<?xml version="1.0" encoding="utf-8" standalone="no"?>
<device schemaVersion="1.1">
  <name>STM32L433VCT7</name>
  <version>1.0</version>
  <description>STM32L433CBT6,STM32L433CBT7,STM32L433CBU6,STM32L433CBU7,STM32L433CBY6,STM32L433CBY7,STM32L433CCT3,STM32L433CCT6,STM32L433CCT7,STM32L433CCU3,STM32L433CCU6,STM32L433CCU7,STM32L433CCY3,STM32L433CCY6,STM32L433CCY7,STM32L433RBI6,STM32L433RBT6,STM32L433RBY6,STM32L433RCI3,STM32L433RCI6,STM32L433RCI7,STM32L433RCT3,STM32L433RCT3P,STM32L433RCT6,STM32L433RCT6P,STM32L433RCT7,STM32L433RCT7P,STM32L433RCY3,STM32L433RCY6,STM32L433RCY7,STM32L433VCI3,STM32L433VCI6,STM32L433VCI7,STM32L433VCT3,STM32L433VCT6,STM32L433VCT7</description>
  <addressUnitBits>8</addressUnitBits>
  <width>32</width>
  <size>0x20</size>
  <resetValue>0</resetValue>
  <resetMask>0xFFFFFFFF</resetMask>
  <peripherals>
    <peripheral>
      <name>TIM2</name>
      <baseAddress>0x40000000</baseAddress>
      <registers>
        <register>
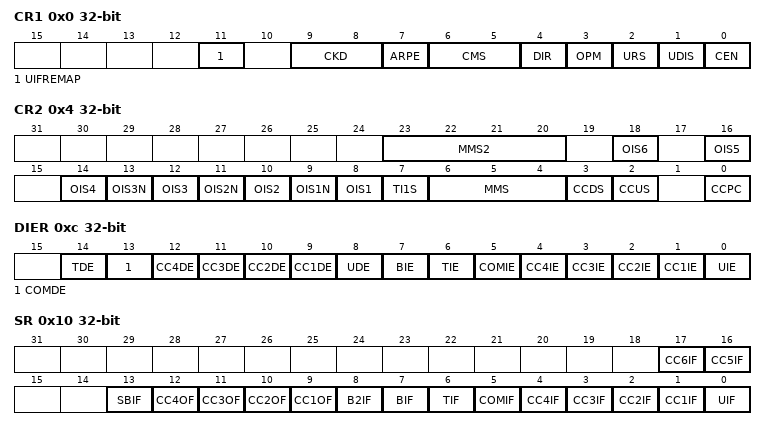
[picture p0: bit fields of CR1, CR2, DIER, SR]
          <name>CR1</name>
          <addressOffset>0x0</addressOffset>
          <size>0x20</size>
          <fields>
            <field>
              <name>CEN</name>
              <bitOffset>0</bitOffset>
              <bitWidth>1</bitWidth>
            </field>
            <field>
              <name>UDIS</name>
              <bitOffset>1</bitOffset>
              <bitWidth>1</bitWidth>
            </field>
            <field>
              <name>URS</name>
              <bitOffset>2</bitOffset>
              <bitWidth>1</bitWidth>
            </field>
            <field>
              <name>OPM</name>
              <bitOffset>3</bitOffset>
              <bitWidth>1</bitWidth>
            </field>
            <field>
              <name>DIR</name>
              <bitOffset>4</bitOffset>
              <bitWidth>1</bitWidth>
            </field>
            <field>
              <name>CMS</name>
              <bitOffset>5</bitOffset>
              <bitWidth>2</bitWidth>
            </field>
            <field>
              <name>ARPE</name>
              <bitOffset>7</bitOffset>
              <bitWidth>1</bitWidth>
            </field>
            <field>
              <name>CKD</name>
              <bitOffset>8</bitOffset>
              <bitWidth>2</bitWidth>
            </field>
            <field>
              <name>UIFREMAP</name>
              <bitOffset>11</bitOffset>
              <bitWidth>1</bitWidth>
            </field>
          </fields>
        </register>
        <register>
          <name>CR2</name>
          <addressOffset>0x4</addressOffset>
          <size>0x20</size>
          <fields>
            <field>
              <name>CCPC</name>
              <bitOffset>0</bitOffset>
              <bitWidth>1</bitWidth>
            </field>
            <field>
              <name>CCUS</name>
              <bitOffset>2</bitOffset>
              <bitWidth>1</bitWidth>
            </field>
            <field>
              <name>CCDS</name>
              <bitOffset>3</bitOffset>
              <bitWidth>1</bitWidth>
            </field>
            <field>
              <name>MMS</name>
              <bitOffset>4</bitOffset>
              <bitWidth>3</bitWidth>
            </field>
            <field>
              <name>TI1S</name>
              <bitOffset>7</bitOffset>
              <bitWidth>1</bitWidth>
            </field>
            <field>
              <name>OIS1</name>
              <bitOffset>8</bitOffset>
              <bitWidth>1</bitWidth>
            </field>
            <field>
              <name>OIS1N</name>
              <bitOffset>9</bitOffset>
              <bitWidth>1</bitWidth>
            </field>
            <field>
              <name>OIS2</name>
              <bitOffset>10</bitOffset>
              <bitWidth>1</bitWidth>
            </field>
            <field>
              <name>OIS2N</name>
              <bitOffset>11</bitOffset>
              <bitWidth>1</bitWidth>
            </field>
            <field>
              <name>OIS3</name>
              <bitOffset>12</bitOffset>
              <bitWidth>1</bitWidth>
            </field>
            <field>
              <name>OIS3N</name>
              <bitOffset>13</bitOffset>
              <bitWidth>1</bitWidth>
            </field>
            <field>
              <name>OIS4</name>
              <bitOffset>14</bitOffset>
              <bitWidth>1</bitWidth>
            </field>
            <field>
              <name>OIS5</name>
              <bitOffset>16</bitOffset>
              <bitWidth>1</bitWidth>
            </field>
            <field>
              <name>OIS6</name>
              <bitOffset>18</bitOffset>
              <bitWidth>1</bitWidth>
            </field>
            <field>
              <name>MMS2</name>
              <bitOffset>20</bitOffset>
              <bitWidth>4</bitWidth>
            </field>
          </fields>
        </register>
        <register>
          <name>SMCR</name>
          <addressOffset>0x8</addressOffset>
          <size>0x20</size>
          <fields>
            <field>
              <name>SMS</name>
              <bitOffset>0</bitOffset>
              <bitWidth>17</bitWidth>
            </field>
            <field>
              <name>OCCS</name>
              <bitOffset>3</bitOffset>
              <bitWidth>1</bitWidth>
            </field>
            <field>
              <name>TS</name>
              <bitOffset>4</bitOffset>
              <bitWidth>3</bitWidth>
            </field>
            <field>
              <name>MSM</name>
              <bitOffset>7</bitOffset>
              <bitWidth>1</bitWidth>
            </field>
            <field>
              <name>ETF</name>
              <bitOffset>8</bitOffset>
              <bitWidth>4</bitWidth>
            </field>
            <field>
              <name>ETPS</name>
              <bitOffset>12</bitOffset>
              <bitWidth>2</bitWidth>
            </field>
            <field>
              <name>ECE</name>
              <bitOffset>14</bitOffset>
              <bitWidth>1</bitWidth>
            </field>
            <field>
              <name>ETP</name>
              <bitOffset>15</bitOffset>
              <bitWidth>1</bitWidth>
            </field>
          </fields>
        </register>
        <register>
          <name>DIER</name>
          <addressOffset>0xc</addressOffset>
          <size>0x20</size>
          <fields>
            <field>
              <name>UIE</name>
              <bitOffset>0</bitOffset>
              <bitWidth>1</bitWidth>
            </field>
            <field>
              <name>CC1IE</name>
              <bitOffset>1</bitOffset>
              <bitWidth>1</bitWidth>
            </field>
            <field>
              <name>CC2IE</name>
              <bitOffset>2</bitOffset>
              <bitWidth>1</bitWidth>
            </field>
            <field>
              <name>CC3IE</name>
              <bitOffset>3</bitOffset>
              <bitWidth>1</bitWidth>
            </field>
            <field>
              <name>CC4IE</name>
              <bitOffset>4</bitOffset>
              <bitWidth>1</bitWidth>
            </field>
            <field>
              <name>COMIE</name>
              <bitOffset>5</bitOffset>
              <bitWidth>1</bitWidth>
            </field>
            <field>
              <name>TIE</name>
              <bitOffset>6</bitOffset>
              <bitWidth>1</bitWidth>
            </field>
            <field>
              <name>BIE</name>
              <bitOffset>7</bitOffset>
              <bitWidth>1</bitWidth>
            </field>
            <field>
              <name>UDE</name>
              <bitOffset>8</bitOffset>
              <bitWidth>1</bitWidth>
            </field>
            <field>
              <name>CC1DE</name>
              <bitOffset>9</bitOffset>
              <bitWidth>1</bitWidth>
            </field>
            <field>
              <name>CC2DE</name>
              <bitOffset>10</bitOffset>
              <bitWidth>1</bitWidth>
            </field>
            <field>
              <name>CC3DE</name>
              <bitOffset>11</bitOffset>
              <bitWidth>1</bitWidth>
            </field>
            <field>
              <name>CC4DE</name>
              <bitOffset>12</bitOffset>
              <bitWidth>1</bitWidth>
            </field>
            <field>
              <name>COMDE</name>
              <bitOffset>13</bitOffset>
              <bitWidth>1</bitWidth>
            </field>
            <field>
              <name>TDE</name>
              <bitOffset>14</bitOffset>
              <bitWidth>1</bitWidth>
            </field>
          </fields>
        </register>
        <register>
          <name>SR</name>
          <addressOffset>0x10</addressOffset>
          <size>0x20</size>
          <fields>
            <field>
              <name>UIF</name>
              <bitOffset>0</bitOffset>
              <bitWidth>1</bitWidth>
            </field>
            <field>
              <name>CC1IF</name>
              <bitOffset>1</bitOffset>
              <bitWidth>1</bitWidth>
            </field>
            <field>
              <name>CC2IF</name>
              <bitOffset>2</bitOffset>
              <bitWidth>1</bitWidth>
            </field>
            <field>
              <name>CC3IF</name>
              <bitOffset>3</bitOffset>
              <bitWidth>1</bitWidth>
            </field>
            <field>
              <name>CC4IF</name>
              <bitOffset>4</bitOffset>
              <bitWidth>1</bitWidth>
            </field>
            <field>
              <name>COMIF</name>
              <bitOffset>5</bitOffset>
              <bitWidth>1</bitWidth>
            </field>
            <field>
              <name>TIF</name>
              <bitOffset>6</bitOffset>
              <bitWidth>1</bitWidth>
            </field>
            <field>
              <name>BIF</name>
              <bitOffset>7</bitOffset>
              <bitWidth>1</bitWidth>
            </field>
            <field>
              <name>B2IF</name>
              <bitOffset>8</bitOffset>
              <bitWidth>1</bitWidth>
            </field>
            <field>
              <name>CC1OF</name>
              <bitOffset>9</bitOffset>
              <bitWidth>1</bitWidth>
            </field>
            <field>
              <name>CC2OF</name>
              <bitOffset>10</bitOffset>
              <bitWidth>1</bitWidth>
            </field>
            <field>
              <name>CC3OF</name>
              <bitOffset>11</bitOffset>
              <bitWidth>1</bitWidth>
            </field>
            <field>
              <name>CC4OF</name>
              <bitOffset>12</bitOffset>
              <bitWidth>1</bitWidth>
            </field>
            <field>
              <name>SBIF</name>
              <bitOffset>13</bitOffset>
              <bitWidth>1</bitWidth>
            </field>
            <field>
              <name>CC5IF</name>
              <bitOffset>16</bitOffset>
              <bitWidth>1</bitWidth>
            </field>
            <field>
              <name>CC6IF</name>
              <bitOffset>17</bitOffset>
              <bitWidth>1</bitWidth>
            </field>
          </fields>
        </register>
        <register>
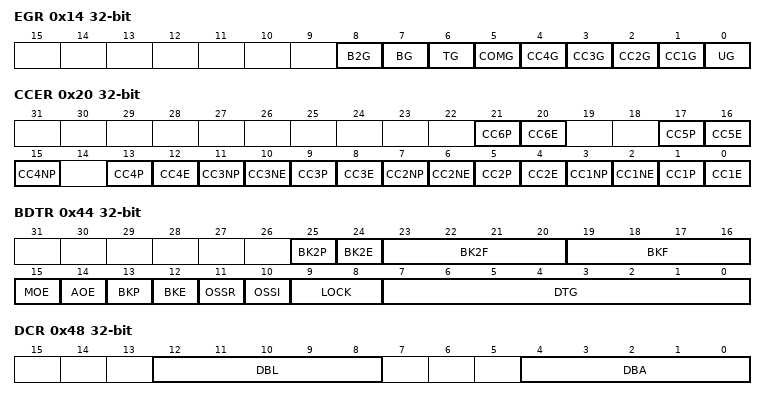
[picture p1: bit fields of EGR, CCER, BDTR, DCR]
          <name>EGR</name>
          <addressOffset>0x14</addressOffset>
          <size>0x20</size>
          <fields>
            <field>
              <name>UG</name>
              <bitOffset>0</bitOffset>
              <bitWidth>1</bitWidth>
            </field>
            <field>
              <name>CC1G</name>
              <bitOffset>1</bitOffset>
              <bitWidth>1</bitWidth>
            </field>
            <field>
              <name>CC2G</name>
              <bitOffset>2</bitOffset>
              <bitWidth>1</bitWidth>
            </field>
            <field>
              <name>CC3G</name>
              <bitOffset>3</bitOffset>
              <bitWidth>1</bitWidth>
            </field>
            <field>
              <name>CC4G</name>
              <bitOffset>4</bitOffset>
              <bitWidth>1</bitWidth>
            </field>
            <field>
              <name>COMG</name>
              <bitOffset>5</bitOffset>
              <bitWidth>1</bitWidth>
            </field>
            <field>
              <name>TG</name>
              <bitOffset>6</bitOffset>
              <bitWidth>1</bitWidth>
            </field>
            <field>
              <name>BG</name>
              <bitOffset>7</bitOffset>
              <bitWidth>1</bitWidth>
            </field>
            <field>
              <name>B2G</name>
              <bitOffset>8</bitOffset>
              <bitWidth>1</bitWidth>
            </field>
          </fields>
        </register>
        <register>
          <name>CCMR1</name>
          <addressOffset>0x18</addressOffset>
          <size>0x20</size>
          <fields>
            <field>
              <name>CC1S</name>
              <bitOffset>0</bitOffset>
              <bitWidth>2</bitWidth>
            </field>
            <field>
              <name>OC1FE</name>
              <bitOffset>2</bitOffset>
              <bitWidth>1</bitWidth>
            </field>
            <field>
              <name>OC1PE</name>
              <bitOffset>3</bitOffset>
              <bitWidth>1</bitWidth>
            </field>
            <field>
              <name>OC1M</name>
              <bitOffset>4</bitOffset>
              <bitWidth>13</bitWidth>
            </field>
            <field>
              <name>OC1CE</name>
              <bitOffset>7</bitOffset>
              <bitWidth>1</bitWidth>
            </field>
            <field>
              <name>CC2S</name>
              <bitOffset>8</bitOffset>
              <bitWidth>2</bitWidth>
            </field>
            <field>
              <name>OC2FE</name>
              <bitOffset>10</bitOffset>
              <bitWidth>1</bitWidth>
            </field>
            <field>
              <name>OC2PE</name>
              <bitOffset>11</bitOffset>
              <bitWidth>1</bitWidth>
            </field>
            <field>
              <name>OC2M</name>
              <bitOffset>12</bitOffset>
              <bitWidth>13</bitWidth>
            </field>
            <field>
              <name>OC2CE</name>
              <bitOffset>15</bitOffset>
              <bitWidth>1</bitWidth>
            </field>
          </fields>
        </register>
        <register>
          <name>CCMR2</name>
          <addressOffset>0x1c</addressOffset>
          <size>0x20</size>
          <fields>
            <field>
              <name>CC3S</name>
              <bitOffset>0</bitOffset>
              <bitWidth>2</bitWidth>
            </field>
            <field>
              <name>OC3FE</name>
              <bitOffset>2</bitOffset>
              <bitWidth>1</bitWidth>
            </field>
            <field>
              <name>OC3PE</name>
              <bitOffset>3</bitOffset>
              <bitWidth>1</bitWidth>
            </field>
            <field>
              <name>OC3M</name>
              <bitOffset>4</bitOffset>
              <bitWidth>13</bitWidth>
            </field>
            <field>
              <name>OC3CE</name>
              <bitOffset>7</bitOffset>
              <bitWidth>1</bitWidth>
            </field>
            <field>
              <name>CC4S</name>
              <bitOffset>8</bitOffset>
              <bitWidth>2</bitWidth>
            </field>
            <field>
              <name>OC4FE</name>
              <bitOffset>10</bitOffset>
              <bitWidth>1</bitWidth>
            </field>
            <field>
              <name>OC4PE</name>
              <bitOffset>11</bitOffset>
              <bitWidth>1</bitWidth>
            </field>
            <field>
              <name>OC4M</name>
              <bitOffset>12</bitOffset>
              <bitWidth>13</bitWidth>
            </field>
            <field>
              <name>OC4CE</name>
              <bitOffset>15</bitOffset>
              <bitWidth>1</bitWidth>
            </field>
          </fields>
        </register>
        <register>
          <name>CCER</name>
          <addressOffset>0x20</addressOffset>
          <size>0x20</size>
          <fields>
            <field>
              <name>CC1E</name>
              <bitOffset>0</bitOffset>
              <bitWidth>1</bitWidth>
            </field>
            <field>
              <name>CC1P</name>
              <bitOffset>1</bitOffset>
              <bitWidth>1</bitWidth>
            </field>
            <field>
              <name>CC1NE</name>
              <bitOffset>2</bitOffset>
              <bitWidth>1</bitWidth>
            </field>
            <field>
              <name>CC1NP</name>
              <bitOffset>3</bitOffset>
              <bitWidth>1</bitWidth>
            </field>
            <field>
              <name>CC2E</name>
              <bitOffset>4</bitOffset>
              <bitWidth>1</bitWidth>
            </field>
            <field>
              <name>CC2P</name>
              <bitOffset>5</bitOffset>
              <bitWidth>1</bitWidth>
            </field>
            <field>
              <name>CC2NE</name>
              <bitOffset>6</bitOffset>
              <bitWidth>1</bitWidth>
            </field>
            <field>
              <name>CC2NP</name>
              <bitOffset>7</bitOffset>
              <bitWidth>1</bitWidth>
            </field>
            <field>
              <name>CC3E</name>
              <bitOffset>8</bitOffset>
              <bitWidth>1</bitWidth>
            </field>
            <field>
              <name>CC3P</name>
              <bitOffset>9</bitOffset>
              <bitWidth>1</bitWidth>
            </field>
            <field>
              <name>CC3NE</name>
              <bitOffset>10</bitOffset>
              <bitWidth>1</bitWidth>
            </field>
            <field>
              <name>CC3NP</name>
              <bitOffset>11</bitOffset>
              <bitWidth>1</bitWidth>
            </field>
            <field>
              <name>CC4E</name>
              <bitOffset>12</bitOffset>
              <bitWidth>1</bitWidth>
            </field>
            <field>
              <name>CC4P</name>
              <bitOffset>13</bitOffset>
              <bitWidth>1</bitWidth>
            </field>
            <field>
              <name>CC4NP</name>
              <bitOffset>15</bitOffset>
              <bitWidth>1</bitWidth>
            </field>
            <field>
              <name>CC5E</name>
              <bitOffset>16</bitOffset>
              <bitWidth>1</bitWidth>
            </field>
            <field>
              <name>CC5P</name>
              <bitOffset>17</bitOffset>
              <bitWidth>1</bitWidth>
            </field>
            <field>
              <name>CC6E</name>
              <bitOffset>20</bitOffset>
              <bitWidth>1</bitWidth>
            </field>
            <field>
              <name>CC6P</name>
              <bitOffset>21</bitOffset>
              <bitWidth>1</bitWidth>
            </field>
          </fields>
        </register>
        <register>
          <name>CNT</name>
          <addressOffset>0x24</addressOffset>
          <size>0x20</size>
          <fields>
            <field>
              <name>CNT</name>
              <bitOffset>0</bitOffset>
              <bitWidth>32</bitWidth>
            </field>
            <field>
              <name>UIFCPY</name>
              <bitOffset>31</bitOffset>
              <bitWidth>1</bitWidth>
            </field>
          </fields>
        </register>
        <register>
          <name>PSC</name>
          <addressOffset>0x28</addressOffset>
          <size>0x20</size>
          <fields>
            <field>
              <name>PSC</name>
              <bitOffset>0</bitOffset>
              <bitWidth>16</bitWidth>
            </field>
          </fields>
        </register>
        <register>
          <name>ARR</name>
          <addressOffset>0x2c</addressOffset>
          <size>0x20</size>
          <fields>
            <field>
              <name>ARR</name>
              <bitOffset>0</bitOffset>
              <bitWidth>32</bitWidth>
            </field>
          </fields>
        </register>
        <register>
          <name>RCR</name>
          <addressOffset>0x30</addressOffset>
          <size>0x20</size>
          <fields>
            <field>
              <name>REP</name>
              <bitOffset>0</bitOffset>
              <bitWidth>16</bitWidth>
            </field>
          </fields>
        </register>
        <register>
          <name>CCR1</name>
          <addressOffset>0x34</addressOffset>
          <size>0x20</size>
          <fields>
            <field>
              <name>CCR1</name>
              <bitOffset>0</bitOffset>
              <bitWidth>16</bitWidth>
            </field>
          </fields>
        </register>
        <register>
          <name>CCR2</name>
          <addressOffset>0x38</addressOffset>
          <size>0x20</size>
          <fields>
            <field>
              <name>CCR2</name>
              <bitOffset>0</bitOffset>
              <bitWidth>16</bitWidth>
            </field>
          </fields>
        </register>
        <register>
          <name>CCR3</name>
          <addressOffset>0x3c</addressOffset>
          <size>0x20</size>
          <fields>
            <field>
              <name>CCR3</name>
              <bitOffset>0</bitOffset>
              <bitWidth>16</bitWidth>
            </field>
          </fields>
        </register>
        <register>
          <name>CCR4</name>
          <addressOffset>0x40</addressOffset>
          <size>0x20</size>
          <fields>
            <field>
              <name>CCR4</name>
              <bitOffset>0</bitOffset>
              <bitWidth>16</bitWidth>
            </field>
          </fields>
        </register>
        <register>
          <name>BDTR</name>
          <addressOffset>0x44</addressOffset>
          <size>0x20</size>
          <fields>
            <field>
              <name>DTG</name>
              <bitOffset>0</bitOffset>
              <bitWidth>8</bitWidth>
            </field>
            <field>
              <name>LOCK</name>
              <bitOffset>8</bitOffset>
              <bitWidth>2</bitWidth>
            </field>
            <field>
              <name>OSSI</name>
              <bitOffset>10</bitOffset>
              <bitWidth>1</bitWidth>
            </field>
            <field>
              <name>OSSR</name>
              <bitOffset>11</bitOffset>
              <bitWidth>1</bitWidth>
            </field>
            <field>
              <name>BKE</name>
              <bitOffset>12</bitOffset>
              <bitWidth>1</bitWidth>
            </field>
            <field>
              <name>BKP</name>
              <bitOffset>13</bitOffset>
              <bitWidth>1</bitWidth>
            </field>
            <field>
              <name>AOE</name>
              <bitOffset>14</bitOffset>
              <bitWidth>1</bitWidth>
            </field>
            <field>
              <name>MOE</name>
              <bitOffset>15</bitOffset>
              <bitWidth>1</bitWidth>
            </field>
            <field>
              <name>BKF</name>
              <bitOffset>16</bitOffset>
              <bitWidth>4</bitWidth>
            </field>
            <field>
              <name>BK2F</name>
              <bitOffset>20</bitOffset>
              <bitWidth>4</bitWidth>
            </field>
            <field>
              <name>BK2E</name>
              <bitOffset>24</bitOffset>
              <bitWidth>1</bitWidth>
            </field>
            <field>
              <name>BK2P</name>
              <bitOffset>25</bitOffset>
              <bitWidth>1</bitWidth>
            </field>
          </fields>
        </register>
        <register>
          <name>DCR</name>
          <addressOffset>0x48</addressOffset>
          <size>0x20</size>
          <fields>
            <field>
              <name>DBA</name>
              <bitOffset>0</bitOffset>
              <bitWidth>5</bitWidth>
            </field>
            <field>
              <name>DBL</name>
              <bitOffset>8</bitOffset>
              <bitWidth>5</bitWidth>
            </field>
          </fields>
        </register>
        <register>
          <name>DMAR</name>
          <addressOffset>0x4c</addressOffset>
          <size>0x20</size>
          <fields>
            <field>
              <name>DMAB</name>
              <bitOffset>0</bitOffset>
              <bitWidth>16</bitWidth>
            </field>
          </fields>
        </register>
        <register>
          <name>OR1</name>
          <addressOffset>0x50</addressOffset>
          <size>0x20</size>
        </register>
        <register>
          <name>CCMR3</name>
          <addressOffset>0x54</addressOffset>
          <size>0x20</size>
          <fields>
            <field>
              <name>OC5FE</name>
              <bitOffset>2</bitOffset>
              <bitWidth>1</bitWidth>
            </field>
            <field>
              <name>OC5PE</name>
              <bitOffset>3</bitOffset>
              <bitWidth>1</bitWidth>
            </field>
            <field>
              <name>OC5M</name>
              <bitOffset>4</bitOffset>
              <bitWidth>13</bitWidth>
            </field>
            <field>
              <name>OC5CE</name>
              <bitOffset>7</bitOffset>
              <bitWidth>1</bitWidth>
            </field>
            <field>
              <name>OC6FE</name>
              <bitOffset>10</bitOffset>
              <bitWidth>1</bitWidth>
            </field>
            <field>
              <name>OC6PE</name>
              <bitOffset>11</bitOffset>
              <bitWidth>1</bitWidth>
            </field>
            <field>
              <name>OC6M</name>
              <bitOffset>12</bitOffset>
              <bitWidth>13</bitWidth>
            </field>
            <field>
              <name>OC6CE</name>
              <bitOffset>15</bitOffset>
              <bitWidth>1</bitWidth>
            </field>
          </fields>
        </register>
        <register>
          <name>CCR5</name>
          <addressOffset>0x58</addressOffset>
          <size>0x20</size>
          <fields>
            <field>
              <name>CCR5</name>
              <bitOffset>0</bitOffset>
              <bitWidth>32</bitWidth>
            </field>
            <field>
              <name>GC5C1</name>
              <bitOffset>29</bitOffset>
              <bitWidth>1</bitWidth>
            </field>
            <field>
              <name>GC5C2</name>
              <bitOffset>30</bitOffset>
              <bitWidth>1</bitWidth>
            </field>
            <field>
              <name>GC5C3</name>
              <bitOffset>31</bitOffset>
              <bitWidth>1</bitWidth>
            </field>
          </fields>
        </register>
        <register>
          <name>CCR6</name>
          <addressOffset>0x5c</addressOffset>
          <size>0x20</size>
          <fields>
            <field>
              <name>CCR6</name>
              <bitOffset>0</bitOffset>
              <bitWidth>16</bitWidth>
            </field>
          </fields>
        </register>
        <register>
          <name>OR2</name>
          <addressOffset>0x60</addressOffset>
          <size>0x20</size>
        </register>
        <register>
          <name>OR3</name>
          <addressOffset>0x64</addressOffset>
          <size>0x20</size>
        </register>
      </registers>
    </peripheral>
    <peripheral>
      <name>TIM6</name>
      <baseAddress>0x40001000</baseAddress>
      <registers>
        <register>
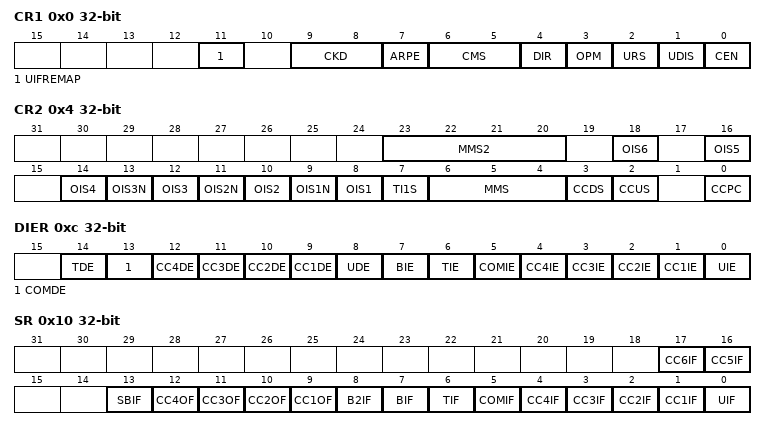
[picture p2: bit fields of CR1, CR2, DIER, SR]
          <name>CR1</name>
          <addressOffset>0x0</addressOffset>
          <size>0x20</size>
          <fields>
            <field>
              <name>CEN</name>
              <bitOffset>0</bitOffset>
              <bitWidth>1</bitWidth>
            </field>
            <field>
              <name>UDIS</name>
              <bitOffset>1</bitOffset>
              <bitWidth>1</bitWidth>
            </field>
            <field>
              <name>URS</name>
              <bitOffset>2</bitOffset>
              <bitWidth>1</bitWidth>
            </field>
            <field>
              <name>OPM</name>
              <bitOffset>3</bitOffset>
              <bitWidth>1</bitWidth>
            </field>
            <field>
              <name>DIR</name>
              <bitOffset>4</bitOffset>
              <bitWidth>1</bitWidth>
            </field>
            <field>
              <name>CMS</name>
              <bitOffset>5</bitOffset>
              <bitWidth>2</bitWidth>
            </field>
            <field>
              <name>ARPE</name>
              <bitOffset>7</bitOffset>
              <bitWidth>1</bitWidth>
            </field>
            <field>
              <name>CKD</name>
              <bitOffset>8</bitOffset>
              <bitWidth>2</bitWidth>
            </field>
            <field>
              <name>UIFREMAP</name>
              <bitOffset>11</bitOffset>
              <bitWidth>1</bitWidth>
            </field>
          </fields>
        </register>
        <register>
          <name>CR2</name>
          <addressOffset>0x4</addressOffset>
          <size>0x20</size>
          <fields>
            <field>
              <name>CCPC</name>
              <bitOffset>0</bitOffset>
              <bitWidth>1</bitWidth>
            </field>
            <field>
              <name>CCUS</name>
              <bitOffset>2</bitOffset>
              <bitWidth>1</bitWidth>
            </field>
            <field>
              <name>CCDS</name>
              <bitOffset>3</bitOffset>
              <bitWidth>1</bitWidth>
            </field>
            <field>
              <name>MMS</name>
              <bitOffset>4</bitOffset>
              <bitWidth>3</bitWidth>
            </field>
            <field>
              <name>TI1S</name>
              <bitOffset>7</bitOffset>
              <bitWidth>1</bitWidth>
            </field>
            <field>
              <name>OIS1</name>
              <bitOffset>8</bitOffset>
              <bitWidth>1</bitWidth>
            </field>
            <field>
              <name>OIS1N</name>
              <bitOffset>9</bitOffset>
              <bitWidth>1</bitWidth>
            </field>
            <field>
              <name>OIS2</name>
              <bitOffset>10</bitOffset>
              <bitWidth>1</bitWidth>
            </field>
            <field>
              <name>OIS2N</name>
              <bitOffset>11</bitOffset>
              <bitWidth>1</bitWidth>
            </field>
            <field>
              <name>OIS3</name>
              <bitOffset>12</bitOffset>
              <bitWidth>1</bitWidth>
            </field>
            <field>
              <name>OIS3N</name>
              <bitOffset>13</bitOffset>
              <bitWidth>1</bitWidth>
            </field>
            <field>
              <name>OIS4</name>
              <bitOffset>14</bitOffset>
              <bitWidth>1</bitWidth>
            </field>
            <field>
              <name>OIS5</name>
              <bitOffset>16</bitOffset>
              <bitWidth>1</bitWidth>
            </field>
            <field>
              <name>OIS6</name>
              <bitOffset>18</bitOffset>
              <bitWidth>1</bitWidth>
            </field>
            <field>
              <name>MMS2</name>
              <bitOffset>20</bitOffset>
              <bitWidth>4</bitWidth>
            </field>
          </fields>
        </register>
        <register>
          <name>SMCR</name>
          <addressOffset>0x8</addressOffset>
          <size>0x20</size>
          <fields>
            <field>
              <name>SMS</name>
              <bitOffset>0</bitOffset>
              <bitWidth>17</bitWidth>
            </field>
            <field>
              <name>OCCS</name>
              <bitOffset>3</bitOffset>
              <bitWidth>1</bitWidth>
            </field>
            <field>
              <name>TS</name>
              <bitOffset>4</bitOffset>
              <bitWidth>3</bitWidth>
            </field>
            <field>
              <name>MSM</name>
              <bitOffset>7</bitOffset>
              <bitWidth>1</bitWidth>
            </field>
            <field>
              <name>ETF</name>
              <bitOffset>8</bitOffset>
              <bitWidth>4</bitWidth>
            </field>
            <field>
              <name>ETPS</name>
              <bitOffset>12</bitOffset>
              <bitWidth>2</bitWidth>
            </field>
            <field>
              <name>ECE</name>
              <bitOffset>14</bitOffset>
              <bitWidth>1</bitWidth>
            </field>
            <field>
              <name>ETP</name>
              <bitOffset>15</bitOffset>
              <bitWidth>1</bitWidth>
            </field>
          </fields>
        </register>
        <register>
          <name>DIER</name>
          <addressOffset>0xc</addressOffset>
          <size>0x20</size>
          <fields>
            <field>
              <name>UIE</name>
              <bitOffset>0</bitOffset>
              <bitWidth>1</bitWidth>
            </field>
            <field>
              <name>CC1IE</name>
              <bitOffset>1</bitOffset>
              <bitWidth>1</bitWidth>
            </field>
            <field>
              <name>CC2IE</name>
              <bitOffset>2</bitOffset>
              <bitWidth>1</bitWidth>
            </field>
            <field>
              <name>CC3IE</name>
              <bitOffset>3</bitOffset>
              <bitWidth>1</bitWidth>
            </field>
            <field>
              <name>CC4IE</name>
              <bitOffset>4</bitOffset>
              <bitWidth>1</bitWidth>
            </field>
            <field>
              <name>COMIE</name>
              <bitOffset>5</bitOffset>
              <bitWidth>1</bitWidth>
            </field>
            <field>
              <name>TIE</name>
              <bitOffset>6</bitOffset>
              <bitWidth>1</bitWidth>
            </field>
            <field>
              <name>BIE</name>
              <bitOffset>7</bitOffset>
              <bitWidth>1</bitWidth>
            </field>
            <field>
              <name>UDE</name>
              <bitOffset>8</bitOffset>
              <bitWidth>1</bitWidth>
            </field>
            <field>
              <name>CC1DE</name>
              <bitOffset>9</bitOffset>
              <bitWidth>1</bitWidth>
            </field>
            <field>
              <name>CC2DE</name>
              <bitOffset>10</bitOffset>
              <bitWidth>1</bitWidth>
            </field>
            <field>
              <name>CC3DE</name>
              <bitOffset>11</bitOffset>
              <bitWidth>1</bitWidth>
            </field>
            <field>
              <name>CC4DE</name>
              <bitOffset>12</bitOffset>
              <bitWidth>1</bitWidth>
            </field>
            <field>
              <name>COMDE</name>
              <bitOffset>13</bitOffset>
              <bitWidth>1</bitWidth>
            </field>
            <field>
              <name>TDE</name>
              <bitOffset>14</bitOffset>
              <bitWidth>1</bitWidth>
            </field>
          </fields>
        </register>
        <register>
          <name>SR</name>
          <addressOffset>0x10</addressOffset>
          <size>0x20</size>
          <fields>
            <field>
              <name>UIF</name>
              <bitOffset>0</bitOffset>
              <bitWidth>1</bitWidth>
            </field>
            <field>
              <name>CC1IF</name>
              <bitOffset>1</bitOffset>
              <bitWidth>1</bitWidth>
            </field>
            <field>
              <name>CC2IF</name>
              <bitOffset>2</bitOffset>
              <bitWidth>1</bitWidth>
            </field>
            <field>
              <name>CC3IF</name>
              <bitOffset>3</bitOffset>
              <bitWidth>1</bitWidth>
            </field>
            <field>
              <name>CC4IF</name>
              <bitOffset>4</bitOffset>
              <bitWidth>1</bitWidth>
            </field>
            <field>
              <name>COMIF</name>
              <bitOffset>5</bitOffset>
              <bitWidth>1</bitWidth>
            </field>
            <field>
              <name>TIF</name>
              <bitOffset>6</bitOffset>
              <bitWidth>1</bitWidth>
            </field>
            <field>
              <name>BIF</name>
              <bitOffset>7</bitOffset>
              <bitWidth>1</bitWidth>
            </field>
            <field>
              <name>B2IF</name>
              <bitOffset>8</bitOffset>
              <bitWidth>1</bitWidth>
            </field>
            <field>
              <name>CC1OF</name>
              <bitOffset>9</bitOffset>
              <bitWidth>1</bitWidth>
            </field>
            <field>
              <name>CC2OF</name>
              <bitOffset>10</bitOffset>
              <bitWidth>1</bitWidth>
            </field>
            <field>
              <name>CC3OF</name>
              <bitOffset>11</bitOffset>
              <bitWidth>1</bitWidth>
            </field>
            <field>
              <name>CC4OF</name>
              <bitOffset>12</bitOffset>
              <bitWidth>1</bitWidth>
            </field>
            <field>
              <name>SBIF</name>
              <bitOffset>13</bitOffset>
              <bitWidth>1</bitWidth>
            </field>
            <field>
              <name>CC5IF</name>
              <bitOffset>16</bitOffset>
              <bitWidth>1</bitWidth>
            </field>
            <field>
              <name>CC6IF</name>
              <bitOffset>17</bitOffset>
              <bitWidth>1</bitWidth>
            </field>
          </fields>
        </register>
        <register>
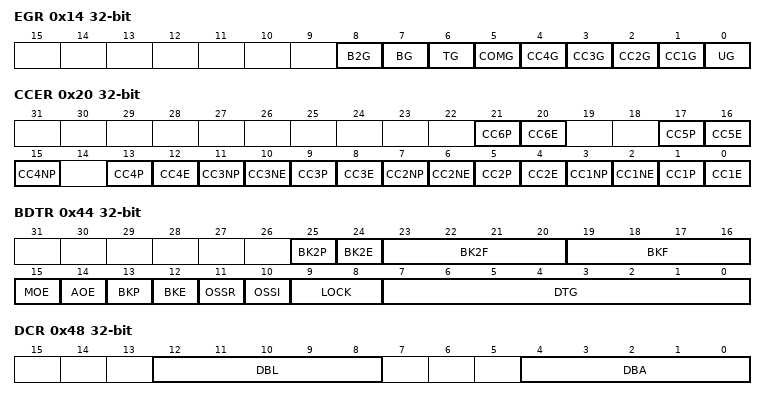
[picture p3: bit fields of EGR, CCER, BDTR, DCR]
          <name>EGR</name>
          <addressOffset>0x14</addressOffset>
          <size>0x20</size>
          <fields>
            <field>
              <name>UG</name>
              <bitOffset>0</bitOffset>
              <bitWidth>1</bitWidth>
            </field>
            <field>
              <name>CC1G</name>
              <bitOffset>1</bitOffset>
              <bitWidth>1</bitWidth>
            </field>
            <field>
              <name>CC2G</name>
              <bitOffset>2</bitOffset>
              <bitWidth>1</bitWidth>
            </field>
            <field>
              <name>CC3G</name>
              <bitOffset>3</bitOffset>
              <bitWidth>1</bitWidth>
            </field>
            <field>
              <name>CC4G</name>
              <bitOffset>4</bitOffset>
              <bitWidth>1</bitWidth>
            </field>
            <field>
              <name>COMG</name>
              <bitOffset>5</bitOffset>
              <bitWidth>1</bitWidth>
            </field>
            <field>
              <name>TG</name>
              <bitOffset>6</bitOffset>
              <bitWidth>1</bitWidth>
            </field>
            <field>
              <name>BG</name>
              <bitOffset>7</bitOffset>
              <bitWidth>1</bitWidth>
            </field>
            <field>
              <name>B2G</name>
              <bitOffset>8</bitOffset>
              <bitWidth>1</bitWidth>
            </field>
          </fields>
        </register>
        <register>
          <name>CCMR1</name>
          <addressOffset>0x18</addressOffset>
          <size>0x20</size>
          <fields>
            <field>
              <name>CC1S</name>
              <bitOffset>0</bitOffset>
              <bitWidth>2</bitWidth>
            </field>
            <field>
              <name>OC1FE</name>
              <bitOffset>2</bitOffset>
              <bitWidth>1</bitWidth>
            </field>
            <field>
              <name>OC1PE</name>
              <bitOffset>3</bitOffset>
              <bitWidth>1</bitWidth>
            </field>
            <field>
              <name>OC1M</name>
              <bitOffset>4</bitOffset>
              <bitWidth>13</bitWidth>
            </field>
            <field>
              <name>OC1CE</name>
              <bitOffset>7</bitOffset>
              <bitWidth>1</bitWidth>
            </field>
            <field>
              <name>CC2S</name>
              <bitOffset>8</bitOffset>
              <bitWidth>2</bitWidth>
            </field>
            <field>
              <name>OC2FE</name>
              <bitOffset>10</bitOffset>
              <bitWidth>1</bitWidth>
            </field>
            <field>
              <name>OC2PE</name>
              <bitOffset>11</bitOffset>
              <bitWidth>1</bitWidth>
            </field>
            <field>
              <name>OC2M</name>
              <bitOffset>12</bitOffset>
              <bitWidth>13</bitWidth>
            </field>
            <field>
              <name>OC2CE</name>
              <bitOffset>15</bitOffset>
              <bitWidth>1</bitWidth>
            </field>
          </fields>
        </register>
        <register>
          <name>CCMR2</name>
          <addressOffset>0x1c</addressOffset>
          <size>0x20</size>
          <fields>
            <field>
              <name>CC3S</name>
              <bitOffset>0</bitOffset>
              <bitWidth>2</bitWidth>
            </field>
            <field>
              <name>OC3FE</name>
              <bitOffset>2</bitOffset>
              <bitWidth>1</bitWidth>
            </field>
            <field>
              <name>OC3PE</name>
              <bitOffset>3</bitOffset>
              <bitWidth>1</bitWidth>
            </field>
            <field>
              <name>OC3M</name>
              <bitOffset>4</bitOffset>
              <bitWidth>13</bitWidth>
            </field>
            <field>
              <name>OC3CE</name>
              <bitOffset>7</bitOffset>
              <bitWidth>1</bitWidth>
            </field>
            <field>
              <name>CC4S</name>
              <bitOffset>8</bitOffset>
              <bitWidth>2</bitWidth>
            </field>
            <field>
              <name>OC4FE</name>
              <bitOffset>10</bitOffset>
              <bitWidth>1</bitWidth>
            </field>
            <field>
              <name>OC4PE</name>
              <bitOffset>11</bitOffset>
              <bitWidth>1</bitWidth>
            </field>
            <field>
              <name>OC4M</name>
              <bitOffset>12</bitOffset>
              <bitWidth>13</bitWidth>
            </field>
            <field>
              <name>OC4CE</name>
              <bitOffset>15</bitOffset>
              <bitWidth>1</bitWidth>
            </field>
          </fields>
        </register>
        <register>
          <name>CCER</name>
          <addressOffset>0x20</addressOffset>
          <size>0x20</size>
          <fields>
            <field>
              <name>CC1E</name>
              <bitOffset>0</bitOffset>
              <bitWidth>1</bitWidth>
            </field>
            <field>
              <name>CC1P</name>
              <bitOffset>1</bitOffset>
              <bitWidth>1</bitWidth>
            </field>
            <field>
              <name>CC1NE</name>
              <bitOffset>2</bitOffset>
              <bitWidth>1</bitWidth>
            </field>
            <field>
              <name>CC1NP</name>
              <bitOffset>3</bitOffset>
              <bitWidth>1</bitWidth>
            </field>
            <field>
              <name>CC2E</name>
              <bitOffset>4</bitOffset>
              <bitWidth>1</bitWidth>
            </field>
            <field>
              <name>CC2P</name>
              <bitOffset>5</bitOffset>
              <bitWidth>1</bitWidth>
            </field>
            <field>
              <name>CC2NE</name>
              <bitOffset>6</bitOffset>
              <bitWidth>1</bitWidth>
            </field>
            <field>
              <name>CC2NP</name>
              <bitOffset>7</bitOffset>
              <bitWidth>1</bitWidth>
            </field>
            <field>
              <name>CC3E</name>
              <bitOffset>8</bitOffset>
              <bitWidth>1</bitWidth>
            </field>
            <field>
              <name>CC3P</name>
              <bitOffset>9</bitOffset>
              <bitWidth>1</bitWidth>
            </field>
            <field>
              <name>CC3NE</name>
              <bitOffset>10</bitOffset>
              <bitWidth>1</bitWidth>
            </field>
            <field>
              <name>CC3NP</name>
              <bitOffset>11</bitOffset>
              <bitWidth>1</bitWidth>
            </field>
            <field>
              <name>CC4E</name>
              <bitOffset>12</bitOffset>
              <bitWidth>1</bitWidth>
            </field>
            <field>
              <name>CC4P</name>
              <bitOffset>13</bitOffset>
              <bitWidth>1</bitWidth>
            </field>
            <field>
              <name>CC4NP</name>
              <bitOffset>15</bitOffset>
              <bitWidth>1</bitWidth>
            </field>
            <field>
              <name>CC5E</name>
              <bitOffset>16</bitOffset>
              <bitWidth>1</bitWidth>
            </field>
            <field>
              <name>CC5P</name>
              <bitOffset>17</bitOffset>
              <bitWidth>1</bitWidth>
            </field>
            <field>
              <name>CC6E</name>
              <bitOffset>20</bitOffset>
              <bitWidth>1</bitWidth>
            </field>
            <field>
              <name>CC6P</name>
              <bitOffset>21</bitOffset>
              <bitWidth>1</bitWidth>
            </field>
          </fields>
        </register>
        <register>
          <name>CNT</name>
          <addressOffset>0x24</addressOffset>
          <size>0x20</size>
          <fields>
            <field>
              <name>CNT</name>
              <bitOffset>0</bitOffset>
              <bitWidth>32</bitWidth>
            </field>
            <field>
              <name>UIFCPY</name>
              <bitOffset>31</bitOffset>
              <bitWidth>1</bitWidth>
            </field>
          </fields>
        </register>
        <register>
          <name>PSC</name>
          <addressOffset>0x28</addressOffset>
          <size>0x20</size>
          <fields>
            <field>
              <name>PSC</name>
              <bitOffset>0</bitOffset>
              <bitWidth>16</bitWidth>
            </field>
          </fields>
        </register>
        <register>
          <name>ARR</name>
          <addressOffset>0x2c</addressOffset>
          <size>0x20</size>
          <fields>
            <field>
              <name>ARR</name>
              <bitOffset>0</bitOffset>
              <bitWidth>32</bitWidth>
            </field>
          </fields>
        </register>
        <register>
          <name>RCR</name>
          <addressOffset>0x30</addressOffset>
          <size>0x20</size>
          <fields>
            <field>
              <name>REP</name>
              <bitOffset>0</bitOffset>
              <bitWidth>16</bitWidth>
            </field>
          </fields>
        </register>
        <register>
          <name>CCR1</name>
          <addressOffset>0x34</addressOffset>
          <size>0x20</size>
          <fields>
            <field>
              <name>CCR1</name>
              <bitOffset>0</bitOffset>
              <bitWidth>16</bitWidth>
            </field>
          </fields>
        </register>
        <register>
          <name>CCR2</name>
          <addressOffset>0x38</addressOffset>
          <size>0x20</size>
          <fields>
            <field>
              <name>CCR2</name>
              <bitOffset>0</bitOffset>
              <bitWidth>16</bitWidth>
            </field>
          </fields>
        </register>
        <register>
          <name>CCR3</name>
          <addressOffset>0x3c</addressOffset>
          <size>0x20</size>
          <fields>
            <field>
              <name>CCR3</name>
              <bitOffset>0</bitOffset>
              <bitWidth>16</bitWidth>
            </field>
          </fields>
        </register>
        <register>
          <name>CCR4</name>
          <addressOffset>0x40</addressOffset>
          <size>0x20</size>
          <fields>
            <field>
              <name>CCR4</name>
              <bitOffset>0</bitOffset>
              <bitWidth>16</bitWidth>
            </field>
          </fields>
        </register>
        <register>
          <name>BDTR</name>
          <addressOffset>0x44</addressOffset>
          <size>0x20</size>
          <fields>
            <field>
              <name>DTG</name>
              <bitOffset>0</bitOffset>
              <bitWidth>8</bitWidth>
            </field>
            <field>
              <name>LOCK</name>
              <bitOffset>8</bitOffset>
              <bitWidth>2</bitWidth>
            </field>
            <field>
              <name>OSSI</name>
              <bitOffset>10</bitOffset>
              <bitWidth>1</bitWidth>
            </field>
            <field>
              <name>OSSR</name>
              <bitOffset>11</bitOffset>
              <bitWidth>1</bitWidth>
            </field>
            <field>
              <name>BKE</name>
              <bitOffset>12</bitOffset>
              <bitWidth>1</bitWidth>
            </field>
            <field>
              <name>BKP</name>
              <bitOffset>13</bitOffset>
              <bitWidth>1</bitWidth>
            </field>
            <field>
              <name>AOE</name>
              <bitOffset>14</bitOffset>
              <bitWidth>1</bitWidth>
            </field>
            <field>
              <name>MOE</name>
              <bitOffset>15</bitOffset>
              <bitWidth>1</bitWidth>
            </field>
            <field>
              <name>BKF</name>
              <bitOffset>16</bitOffset>
              <bitWidth>4</bitWidth>
            </field>
            <field>
              <name>BK2F</name>
              <bitOffset>20</bitOffset>
              <bitWidth>4</bitWidth>
            </field>
            <field>
              <name>BK2E</name>
              <bitOffset>24</bitOffset>
              <bitWidth>1</bitWidth>
            </field>
            <field>
              <name>BK2P</name>
              <bitOffset>25</bitOffset>
              <bitWidth>1</bitWidth>
            </field>
          </fields>
        </register>
        <register>
          <name>DCR</name>
          <addressOffset>0x48</addressOffset>
          <size>0x20</size>
          <fields>
            <field>
              <name>DBA</name>
              <bitOffset>0</bitOffset>
              <bitWidth>5</bitWidth>
            </field>
            <field>
              <name>DBL</name>
              <bitOffset>8</bitOffset>
              <bitWidth>5</bitWidth>
            </field>
          </fields>
        </register>
        <register>
          <name>DMAR</name>
          <addressOffset>0x4c</addressOffset>
          <size>0x20</size>
          <fields>
            <field>
              <name>DMAB</name>
              <bitOffset>0</bitOffset>
              <bitWidth>16</bitWidth>
            </field>
          </fields>
        </register>
        <register>
          <name>OR1</name>
          <addressOffset>0x50</addressOffset>
          <size>0x20</size>
        </register>
        <register>
          <name>CCMR3</name>
          <addressOffset>0x54</addressOffset>
          <size>0x20</size>
          <fields>
            <field>
              <name>OC5FE</name>
              <bitOffset>2</bitOffset>
              <bitWidth>1</bitWidth>
            </field>
            <field>
              <name>OC5PE</name>
              <bitOffset>3</bitOffset>
              <bitWidth>1</bitWidth>
            </field>
            <field>
              <name>OC5M</name>
              <bitOffset>4</bitOffset>
              <bitWidth>13</bitWidth>
            </field>
            <field>
              <name>OC5CE</name>
              <bitOffset>7</bitOffset>
              <bitWidth>1</bitWidth>
            </field>
            <field>
              <name>OC6FE</name>
              <bitOffset>10</bitOffset>
              <bitWidth>1</bitWidth>
            </field>
            <field>
              <name>OC6PE</name>
              <bitOffset>11</bitOffset>
              <bitWidth>1</bitWidth>
            </field>
            <field>
              <name>OC6M</name>
              <bitOffset>12</bitOffset>
              <bitWidth>13</bitWidth>
            </field>
            <field>
              <name>OC6CE</name>
              <bitOffset>15</bitOffset>
              <bitWidth>1</bitWidth>
            </field>
          </fields>
        </register>
        <register>
          <name>CCR5</name>
          <addressOffset>0x58</addressOffset>
          <size>0x20</size>
          <fields>
            <field>
              <name>CCR5</name>
              <bitOffset>0</bitOffset>
              <bitWidth>32</bitWidth>
            </field>
            <field>
              <name>GC5C1</name>
              <bitOffset>29</bitOffset>
              <bitWidth>1</bitWidth>
            </field>
            <field>
              <name>GC5C2</name>
              <bitOffset>30</bitOffset>
              <bitWidth>1</bitWidth>
            </field>
            <field>
              <name>GC5C3</name>
              <bitOffset>31</bitOffset>
              <bitWidth>1</bitWidth>
            </field>
          </fields>
        </register>
        <register>
          <name>CCR6</name>
          <addressOffset>0x5c</addressOffset>
          <size>0x20</size>
          <fields>
            <field>
              <name>CCR6</name>
              <bitOffset>0</bitOffset>
              <bitWidth>16</bitWidth>
            </field>
          </fields>
        </register>
        <register>
          <name>OR2</name>
          <addressOffset>0x60</addressOffset>
          <size>0x20</size>
        </register>
        <register>
          <name>OR3</name>
          <addressOffset>0x64</addressOffset>
          <size>0x20</size>
        </register>
      </registers>
    </peripheral>
    <peripheral>
      <name>TIM7</name>
      <baseAddress>0x40001400</baseAddress>
      <registers>
        <register>
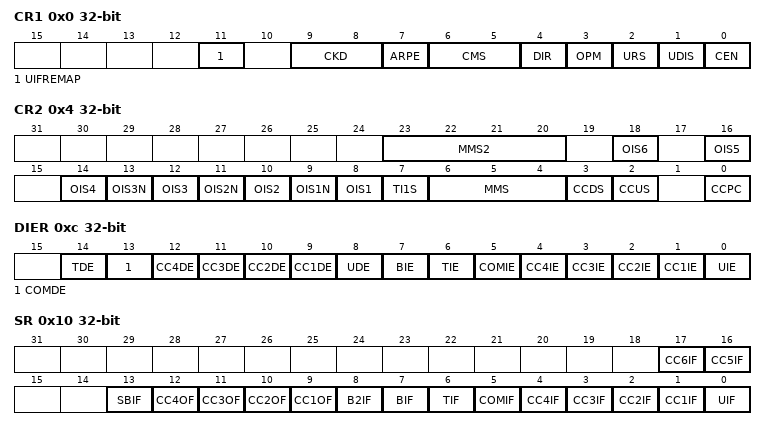
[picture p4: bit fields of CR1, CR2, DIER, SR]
          <name>CR1</name>
          <addressOffset>0x0</addressOffset>
          <size>0x20</size>
          <fields>
            <field>
              <name>CEN</name>
              <bitOffset>0</bitOffset>
              <bitWidth>1</bitWidth>
            </field>
            <field>
              <name>UDIS</name>
              <bitOffset>1</bitOffset>
              <bitWidth>1</bitWidth>
            </field>
            <field>
              <name>URS</name>
              <bitOffset>2</bitOffset>
              <bitWidth>1</bitWidth>
            </field>
            <field>
              <name>OPM</name>
              <bitOffset>3</bitOffset>
              <bitWidth>1</bitWidth>
            </field>
            <field>
              <name>DIR</name>
              <bitOffset>4</bitOffset>
              <bitWidth>1</bitWidth>
            </field>
            <field>
              <name>CMS</name>
              <bitOffset>5</bitOffset>
              <bitWidth>2</bitWidth>
            </field>
            <field>
              <name>ARPE</name>
              <bitOffset>7</bitOffset>
              <bitWidth>1</bitWidth>
            </field>
            <field>
              <name>CKD</name>
              <bitOffset>8</bitOffset>
              <bitWidth>2</bitWidth>
            </field>
            <field>
              <name>UIFREMAP</name>
              <bitOffset>11</bitOffset>
              <bitWidth>1</bitWidth>
            </field>
          </fields>
        </register>
        <register>
          <name>CR2</name>
          <addressOffset>0x4</addressOffset>
          <size>0x20</size>
          <fields>
            <field>
              <name>CCPC</name>
              <bitOffset>0</bitOffset>
              <bitWidth>1</bitWidth>
            </field>
            <field>
              <name>CCUS</name>
              <bitOffset>2</bitOffset>
              <bitWidth>1</bitWidth>
            </field>
            <field>
              <name>CCDS</name>
              <bitOffset>3</bitOffset>
              <bitWidth>1</bitWidth>
            </field>
            <field>
              <name>MMS</name>
              <bitOffset>4</bitOffset>
              <bitWidth>3</bitWidth>
            </field>
            <field>
              <name>TI1S</name>
              <bitOffset>7</bitOffset>
              <bitWidth>1</bitWidth>
            </field>
            <field>
              <name>OIS1</name>
              <bitOffset>8</bitOffset>
              <bitWidth>1</bitWidth>
            </field>
            <field>
              <name>OIS1N</name>
              <bitOffset>9</bitOffset>
              <bitWidth>1</bitWidth>
            </field>
            <field>
              <name>OIS2</name>
              <bitOffset>10</bitOffset>
              <bitWidth>1</bitWidth>
            </field>
            <field>
              <name>OIS2N</name>
              <bitOffset>11</bitOffset>
              <bitWidth>1</bitWidth>
            </field>
            <field>
              <name>OIS3</name>
              <bitOffset>12</bitOffset>
              <bitWidth>1</bitWidth>
            </field>
            <field>
              <name>OIS3N</name>
              <bitOffset>13</bitOffset>
              <bitWidth>1</bitWidth>
            </field>
            <field>
              <name>OIS4</name>
              <bitOffset>14</bitOffset>
              <bitWidth>1</bitWidth>
            </field>
            <field>
              <name>OIS5</name>
              <bitOffset>16</bitOffset>
              <bitWidth>1</bitWidth>
            </field>
            <field>
              <name>OIS6</name>
              <bitOffset>18</bitOffset>
              <bitWidth>1</bitWidth>
            </field>
            <field>
              <name>MMS2</name>
              <bitOffset>20</bitOffset>
              <bitWidth>4</bitWidth>
            </field>
          </fields>
        </register>
        <register>
          <name>SMCR</name>
          <addressOffset>0x8</addressOffset>
          <size>0x20</size>
          <fields>
            <field>
              <name>SMS</name>
              <bitOffset>0</bitOffset>
              <bitWidth>17</bitWidth>
            </field>
            <field>
              <name>OCCS</name>
              <bitOffset>3</bitOffset>
              <bitWidth>1</bitWidth>
            </field>
            <field>
              <name>TS</name>
              <bitOffset>4</bitOffset>
              <bitWidth>3</bitWidth>
            </field>
            <field>
              <name>MSM</name>
              <bitOffset>7</bitOffset>
              <bitWidth>1</bitWidth>
            </field>
            <field>
              <name>ETF</name>
              <bitOffset>8</bitOffset>
              <bitWidth>4</bitWidth>
            </field>
            <field>
              <name>ETPS</name>
              <bitOffset>12</bitOffset>
              <bitWidth>2</bitWidth>
            </field>
            <field>
              <name>ECE</name>
              <bitOffset>14</bitOffset>
              <bitWidth>1</bitWidth>
            </field>
            <field>
              <name>ETP</name>
              <bitOffset>15</bitOffset>
              <bitWidth>1</bitWidth>
            </field>
          </fields>
        </register>
        <register>
          <name>DIER</name>
          <addressOffset>0xc</addressOffset>
          <size>0x20</size>
          <fields>
            <field>
              <name>UIE</name>
              <bitOffset>0</bitOffset>
              <bitWidth>1</bitWidth>
            </field>
            <field>
              <name>CC1IE</name>
              <bitOffset>1</bitOffset>
              <bitWidth>1</bitWidth>
            </field>
            <field>
              <name>CC2IE</name>
              <bitOffset>2</bitOffset>
              <bitWidth>1</bitWidth>
            </field>
            <field>
              <name>CC3IE</name>
              <bitOffset>3</bitOffset>
              <bitWidth>1</bitWidth>
            </field>
            <field>
              <name>CC4IE</name>
              <bitOffset>4</bitOffset>
              <bitWidth>1</bitWidth>
            </field>
            <field>
              <name>COMIE</name>
              <bitOffset>5</bitOffset>
              <bitWidth>1</bitWidth>
            </field>
            <field>
              <name>TIE</name>
              <bitOffset>6</bitOffset>
              <bitWidth>1</bitWidth>
            </field>
            <field>
              <name>BIE</name>
              <bitOffset>7</bitOffset>
              <bitWidth>1</bitWidth>
            </field>
            <field>
              <name>UDE</name>
              <bitOffset>8</bitOffset>
              <bitWidth>1</bitWidth>
            </field>
            <field>
              <name>CC1DE</name>
              <bitOffset>9</bitOffset>
              <bitWidth>1</bitWidth>
            </field>
            <field>
              <name>CC2DE</name>
              <bitOffset>10</bitOffset>
              <bitWidth>1</bitWidth>
            </field>
            <field>
              <name>CC3DE</name>
              <bitOffset>11</bitOffset>
              <bitWidth>1</bitWidth>
            </field>
            <field>
              <name>CC4DE</name>
              <bitOffset>12</bitOffset>
              <bitWidth>1</bitWidth>
            </field>
            <field>
              <name>COMDE</name>
              <bitOffset>13</bitOffset>
              <bitWidth>1</bitWidth>
            </field>
            <field>
              <name>TDE</name>
              <bitOffset>14</bitOffset>
              <bitWidth>1</bitWidth>
            </field>
          </fields>
        </register>
        <register>
          <name>SR</name>
          <addressOffset>0x10</addressOffset>
          <size>0x20</size>
          <fields>
            <field>
              <name>UIF</name>
              <bitOffset>0</bitOffset>
              <bitWidth>1</bitWidth>
            </field>
            <field>
              <name>CC1IF</name>
              <bitOffset>1</bitOffset>
              <bitWidth>1</bitWidth>
            </field>
            <field>
              <name>CC2IF</name>
              <bitOffset>2</bitOffset>
              <bitWidth>1</bitWidth>
            </field>
            <field>
              <name>CC3IF</name>
              <bitOffset>3</bitOffset>
              <bitWidth>1</bitWidth>
            </field>
            <field>
              <name>CC4IF</name>
              <bitOffset>4</bitOffset>
              <bitWidth>1</bitWidth>
            </field>
            <field>
              <name>COMIF</name>
              <bitOffset>5</bitOffset>
              <bitWidth>1</bitWidth>
            </field>
            <field>
              <name>TIF</name>
              <bitOffset>6</bitOffset>
              <bitWidth>1</bitWidth>
            </field>
            <field>
              <name>BIF</name>
              <bitOffset>7</bitOffset>
              <bitWidth>1</bitWidth>
            </field>
            <field>
              <name>B2IF</name>
              <bitOffset>8</bitOffset>
              <bitWidth>1</bitWidth>
            </field>
            <field>
              <name>CC1OF</name>
              <bitOffset>9</bitOffset>
              <bitWidth>1</bitWidth>
            </field>
            <field>
              <name>CC2OF</name>
              <bitOffset>10</bitOffset>
              <bitWidth>1</bitWidth>
            </field>
            <field>
              <name>CC3OF</name>
              <bitOffset>11</bitOffset>
              <bitWidth>1</bitWidth>
            </field>
            <field>
              <name>CC4OF</name>
              <bitOffset>12</bitOffset>
              <bitWidth>1</bitWidth>
            </field>
            <field>
              <name>SBIF</name>
              <bitOffset>13</bitOffset>
              <bitWidth>1</bitWidth>
            </field>
            <field>
              <name>CC5IF</name>
              <bitOffset>16</bitOffset>
              <bitWidth>1</bitWidth>
            </field>
            <field>
              <name>CC6IF</name>
              <bitOffset>17</bitOffset>
              <bitWidth>1</bitWidth>
            </field>
          </fields>
        </register>
        <register>
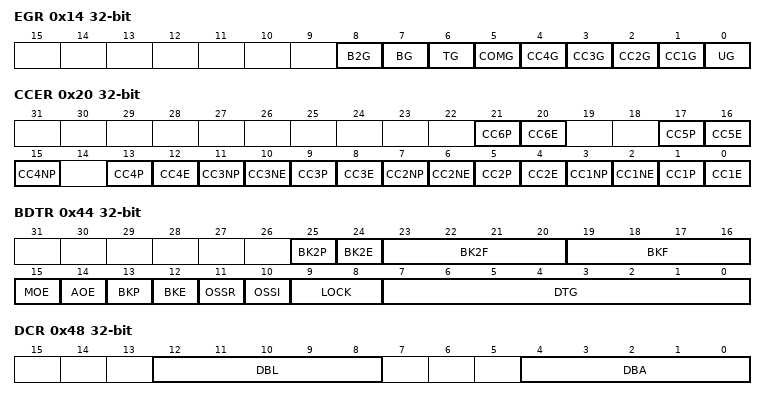
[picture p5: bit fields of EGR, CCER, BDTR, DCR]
          <name>EGR</name>
          <addressOffset>0x14</addressOffset>
          <size>0x20</size>
          <fields>
            <field>
              <name>UG</name>
              <bitOffset>0</bitOffset>
              <bitWidth>1</bitWidth>
            </field>
            <field>
              <name>CC1G</name>
              <bitOffset>1</bitOffset>
              <bitWidth>1</bitWidth>
            </field>
            <field>
              <name>CC2G</name>
              <bitOffset>2</bitOffset>
              <bitWidth>1</bitWidth>
            </field>
            <field>
              <name>CC3G</name>
              <bitOffset>3</bitOffset>
              <bitWidth>1</bitWidth>
            </field>
            <field>
              <name>CC4G</name>
              <bitOffset>4</bitOffset>
              <bitWidth>1</bitWidth>
            </field>
            <field>
              <name>COMG</name>
              <bitOffset>5</bitOffset>
              <bitWidth>1</bitWidth>
            </field>
            <field>
              <name>TG</name>
              <bitOffset>6</bitOffset>
              <bitWidth>1</bitWidth>
            </field>
            <field>
              <name>BG</name>
              <bitOffset>7</bitOffset>
              <bitWidth>1</bitWidth>
            </field>
            <field>
              <name>B2G</name>
              <bitOffset>8</bitOffset>
              <bitWidth>1</bitWidth>
            </field>
          </fields>
        </register>
        <register>
          <name>CCMR1</name>
          <addressOffset>0x18</addressOffset>
          <size>0x20</size>
          <fields>
            <field>
              <name>CC1S</name>
              <bitOffset>0</bitOffset>
              <bitWidth>2</bitWidth>
            </field>
            <field>
              <name>OC1FE</name>
              <bitOffset>2</bitOffset>
              <bitWidth>1</bitWidth>
            </field>
            <field>
              <name>OC1PE</name>
              <bitOffset>3</bitOffset>
              <bitWidth>1</bitWidth>
            </field>
            <field>
              <name>OC1M</name>
              <bitOffset>4</bitOffset>
              <bitWidth>13</bitWidth>
            </field>
            <field>
              <name>OC1CE</name>
              <bitOffset>7</bitOffset>
              <bitWidth>1</bitWidth>
            </field>
            <field>
              <name>CC2S</name>
              <bitOffset>8</bitOffset>
              <bitWidth>2</bitWidth>
            </field>
            <field>
              <name>OC2FE</name>
              <bitOffset>10</bitOffset>
              <bitWidth>1</bitWidth>
            </field>
            <field>
              <name>OC2PE</name>
              <bitOffset>11</bitOffset>
              <bitWidth>1</bitWidth>
            </field>
            <field>
              <name>OC2M</name>
              <bitOffset>12</bitOffset>
              <bitWidth>13</bitWidth>
            </field>
            <field>
              <name>OC2CE</name>
              <bitOffset>15</bitOffset>
              <bitWidth>1</bitWidth>
            </field>
          </fields>
        </register>
        <register>
          <name>CCMR2</name>
          <addressOffset>0x1c</addressOffset>
          <size>0x20</size>
          <fields>
            <field>
              <name>CC3S</name>
              <bitOffset>0</bitOffset>
              <bitWidth>2</bitWidth>
            </field>
            <field>
              <name>OC3FE</name>
              <bitOffset>2</bitOffset>
              <bitWidth>1</bitWidth>
            </field>
            <field>
              <name>OC3PE</name>
              <bitOffset>3</bitOffset>
              <bitWidth>1</bitWidth>
            </field>
            <field>
              <name>OC3M</name>
              <bitOffset>4</bitOffset>
              <bitWidth>13</bitWidth>
            </field>
            <field>
              <name>OC3CE</name>
              <bitOffset>7</bitOffset>
              <bitWidth>1</bitWidth>
            </field>
            <field>
              <name>CC4S</name>
              <bitOffset>8</bitOffset>
              <bitWidth>2</bitWidth>
            </field>
            <field>
              <name>OC4FE</name>
              <bitOffset>10</bitOffset>
              <bitWidth>1</bitWidth>
            </field>
            <field>
              <name>OC4PE</name>
              <bitOffset>11</bitOffset>
              <bitWidth>1</bitWidth>
            </field>
            <field>
              <name>OC4M</name>
              <bitOffset>12</bitOffset>
              <bitWidth>13</bitWidth>
            </field>
            <field>
              <name>OC4CE</name>
              <bitOffset>15</bitOffset>
              <bitWidth>1</bitWidth>
            </field>
          </fields>
        </register>
        <register>
          <name>CCER</name>
          <addressOffset>0x20</addressOffset>
          <size>0x20</size>
          <fields>
            <field>
              <name>CC1E</name>
              <bitOffset>0</bitOffset>
              <bitWidth>1</bitWidth>
            </field>
            <field>
              <name>CC1P</name>
              <bitOffset>1</bitOffset>
              <bitWidth>1</bitWidth>
            </field>
            <field>
              <name>CC1NE</name>
              <bitOffset>2</bitOffset>
              <bitWidth>1</bitWidth>
            </field>
            <field>
              <name>CC1NP</name>
              <bitOffset>3</bitOffset>
              <bitWidth>1</bitWidth>
            </field>
            <field>
              <name>CC2E</name>
              <bitOffset>4</bitOffset>
              <bitWidth>1</bitWidth>
            </field>
            <field>
              <name>CC2P</name>
              <bitOffset>5</bitOffset>
              <bitWidth>1</bitWidth>
            </field>
            <field>
              <name>CC2NE</name>
              <bitOffset>6</bitOffset>
              <bitWidth>1</bitWidth>
            </field>
            <field>
              <name>CC2NP</name>
              <bitOffset>7</bitOffset>
              <bitWidth>1</bitWidth>
            </field>
            <field>
              <name>CC3E</name>
              <bitOffset>8</bitOffset>
              <bitWidth>1</bitWidth>
            </field>
            <field>
              <name>CC3P</name>
              <bitOffset>9</bitOffset>
              <bitWidth>1</bitWidth>
            </field>
            <field>
              <name>CC3NE</name>
              <bitOffset>10</bitOffset>
              <bitWidth>1</bitWidth>
            </field>
            <field>
              <name>CC3NP</name>
              <bitOffset>11</bitOffset>
              <bitWidth>1</bitWidth>
            </field>
            <field>
              <name>CC4E</name>
              <bitOffset>12</bitOffset>
              <bitWidth>1</bitWidth>
            </field>
            <field>
              <name>CC4P</name>
              <bitOffset>13</bitOffset>
              <bitWidth>1</bitWidth>
            </field>
            <field>
              <name>CC4NP</name>
              <bitOffset>15</bitOffset>
              <bitWidth>1</bitWidth>
            </field>
            <field>
              <name>CC5E</name>
              <bitOffset>16</bitOffset>
              <bitWidth>1</bitWidth>
            </field>
            <field>
              <name>CC5P</name>
              <bitOffset>17</bitOffset>
              <bitWidth>1</bitWidth>
            </field>
            <field>
              <name>CC6E</name>
              <bitOffset>20</bitOffset>
              <bitWidth>1</bitWidth>
            </field>
            <field>
              <name>CC6P</name>
              <bitOffset>21</bitOffset>
              <bitWidth>1</bitWidth>
            </field>
          </fields>
        </register>
        <register>
          <name>CNT</name>
          <addressOffset>0x24</addressOffset>
          <size>0x20</size>
          <fields>
            <field>
              <name>CNT</name>
              <bitOffset>0</bitOffset>
              <bitWidth>32</bitWidth>
            </field>
            <field>
              <name>UIFCPY</name>
              <bitOffset>31</bitOffset>
              <bitWidth>1</bitWidth>
            </field>
          </fields>
        </register>
        <register>
          <name>PSC</name>
          <addressOffset>0x28</addressOffset>
          <size>0x20</size>
          <fields>
            <field>
              <name>PSC</name>
              <bitOffset>0</bitOffset>
              <bitWidth>16</bitWidth>
            </field>
          </fields>
        </register>
        <register>
          <name>ARR</name>
          <addressOffset>0x2c</addressOffset>
          <size>0x20</size>
          <fields>
            <field>
              <name>ARR</name>
              <bitOffset>0</bitOffset>
              <bitWidth>32</bitWidth>
            </field>
          </fields>
        </register>
        <register>
          <name>RCR</name>
          <addressOffset>0x30</addressOffset>
          <size>0x20</size>
          <fields>
            <field>
              <name>REP</name>
              <bitOffset>0</bitOffset>
              <bitWidth>16</bitWidth>
            </field>
          </fields>
        </register>
        <register>
          <name>CCR1</name>
          <addressOffset>0x34</addressOffset>
          <size>0x20</size>
          <fields>
            <field>
              <name>CCR1</name>
              <bitOffset>0</bitOffset>
              <bitWidth>16</bitWidth>
            </field>
          </fields>
        </register>
        <register>
          <name>CCR2</name>
          <addressOffset>0x38</addressOffset>
          <size>0x20</size>
          <fields>
            <field>
              <name>CCR2</name>
              <bitOffset>0</bitOffset>
              <bitWidth>16</bitWidth>
            </field>
          </fields>
        </register>
        <register>
          <name>CCR3</name>
          <addressOffset>0x3c</addressOffset>
          <size>0x20</size>
          <fields>
            <field>
              <name>CCR3</name>
              <bitOffset>0</bitOffset>
              <bitWidth>16</bitWidth>
            </field>
          </fields>
        </register>
        <register>
          <name>CCR4</name>
          <addressOffset>0x40</addressOffset>
          <size>0x20</size>
          <fields>
            <field>
              <name>CCR4</name>
              <bitOffset>0</bitOffset>
              <bitWidth>16</bitWidth>
            </field>
          </fields>
        </register>
        <register>
          <name>BDTR</name>
          <addressOffset>0x44</addressOffset>
          <size>0x20</size>
          <fields>
            <field>
              <name>DTG</name>
              <bitOffset>0</bitOffset>
              <bitWidth>8</bitWidth>
            </field>
            <field>
              <name>LOCK</name>
              <bitOffset>8</bitOffset>
              <bitWidth>2</bitWidth>
            </field>
            <field>
              <name>OSSI</name>
              <bitOffset>10</bitOffset>
              <bitWidth>1</bitWidth>
            </field>
            <field>
              <name>OSSR</name>
              <bitOffset>11</bitOffset>
              <bitWidth>1</bitWidth>
            </field>
            <field>
              <name>BKE</name>
              <bitOffset>12</bitOffset>
              <bitWidth>1</bitWidth>
            </field>
            <field>
              <name>BKP</name>
              <bitOffset>13</bitOffset>
              <bitWidth>1</bitWidth>
            </field>
            <field>
              <name>AOE</name>
              <bitOffset>14</bitOffset>
              <bitWidth>1</bitWidth>
            </field>
            <field>
              <name>MOE</name>
              <bitOffset>15</bitOffset>
              <bitWidth>1</bitWidth>
            </field>
            <field>
              <name>BKF</name>
              <bitOffset>16</bitOffset>
              <bitWidth>4</bitWidth>
            </field>
            <field>
              <name>BK2F</name>
              <bitOffset>20</bitOffset>
              <bitWidth>4</bitWidth>
            </field>
            <field>
              <name>BK2E</name>
              <bitOffset>24</bitOffset>
              <bitWidth>1</bitWidth>
            </field>
            <field>
              <name>BK2P</name>
              <bitOffset>25</bitOffset>
              <bitWidth>1</bitWidth>
            </field>
          </fields>
        </register>
        <register>
          <name>DCR</name>
          <addressOffset>0x48</addressOffset>
          <size>0x20</size>
          <fields>
            <field>
              <name>DBA</name>
              <bitOffset>0</bitOffset>
              <bitWidth>5</bitWidth>
            </field>
            <field>
              <name>DBL</name>
              <bitOffset>8</bitOffset>
              <bitWidth>5</bitWidth>
            </field>
          </fields>
        </register>
        <register>
          <name>DMAR</name>
          <addressOffset>0x4c</addressOffset>
          <size>0x20</size>
          <fields>
            <field>
              <name>DMAB</name>
              <bitOffset>0</bitOffset>
              <bitWidth>16</bitWidth>
            </field>
          </fields>
        </register>
        <register>
          <name>OR1</name>
          <addressOffset>0x50</addressOffset>
          <size>0x20</size>
        </register>
        <register>
          <name>CCMR3</name>
          <addressOffset>0x54</addressOffset>
          <size>0x20</size>
          <fields>
            <field>
              <name>OC5FE</name>
              <bitOffset>2</bitOffset>
              <bitWidth>1</bitWidth>
            </field>
            <field>
              <name>OC5PE</name>
              <bitOffset>3</bitOffset>
              <bitWidth>1</bitWidth>
            </field>
            <field>
              <name>OC5M</name>
              <bitOffset>4</bitOffset>
              <bitWidth>13</bitWidth>
            </field>
            <field>
              <name>OC5CE</name>
              <bitOffset>7</bitOffset>
              <bitWidth>1</bitWidth>
            </field>
            <field>
              <name>OC6FE</name>
              <bitOffset>10</bitOffset>
              <bitWidth>1</bitWidth>
            </field>
            <field>
              <name>OC6PE</name>
              <bitOffset>11</bitOffset>
              <bitWidth>1</bitWidth>
            </field>
            <field>
              <name>OC6M</name>
              <bitOffset>12</bitOffset>
              <bitWidth>13</bitWidth>
            </field>
            <field>
              <name>OC6CE</name>
              <bitOffset>15</bitOffset>
              <bitWidth>1</bitWidth>
            </field>
          </fields>
        </register>
        <register>
          <name>CCR5</name>
          <addressOffset>0x58</addressOffset>
          <size>0x20</size>
          <fields>
            <field>
              <name>CCR5</name>
              <bitOffset>0</bitOffset>
              <bitWidth>32</bitWidth>
            </field>
            <field>
              <name>GC5C1</name>
              <bitOffset>29</bitOffset>
              <bitWidth>1</bitWidth>
            </field>
            <field>
              <name>GC5C2</name>
              <bitOffset>30</bitOffset>
              <bitWidth>1</bitWidth>
            </field>
            <field>
              <name>GC5C3</name>
              <bitOffset>31</bitOffset>
              <bitWidth>1</bitWidth>
            </field>
          </fields>
        </register>
        <register>
          <name>CCR6</name>
          <addressOffset>0x5c</addressOffset>
          <size>0x20</size>
          <fields>
            <field>
              <name>CCR6</name>
              <bitOffset>0</bitOffset>
              <bitWidth>16</bitWidth>
            </field>
          </fields>
        </register>
        <register>
          <name>OR2</name>
          <addressOffset>0x60</addressOffset>
          <size>0x20</size>
        </register>
        <register>
          <name>OR3</name>
          <addressOffset>0x64</addressOffset>
          <size>0x20</size>
        </register>
      </registers>
    </peripheral>
    <peripheral>
      <name>LCD</name>
      <baseAddress>0x40002400</baseAddress>
      <registers>
        <register>
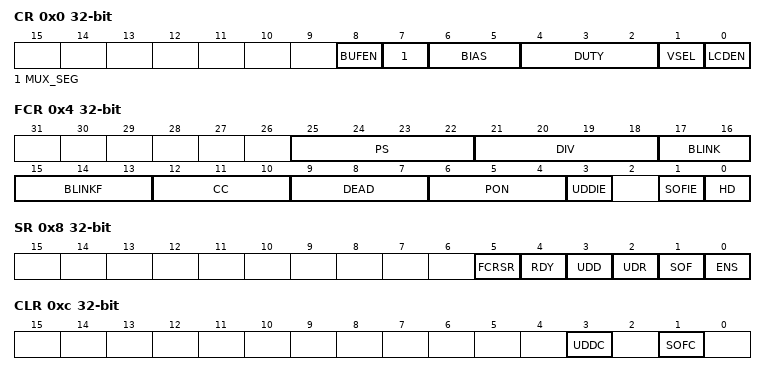
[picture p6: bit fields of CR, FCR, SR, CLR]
          <name>CR</name>
          <addressOffset>0x0</addressOffset>
          <size>0x20</size>
          <fields>
            <field>
              <name>LCDEN</name>
              <bitOffset>0</bitOffset>
              <bitWidth>1</bitWidth>
            </field>
            <field>
              <name>VSEL</name>
              <bitOffset>1</bitOffset>
              <bitWidth>1</bitWidth>
            </field>
            <field>
              <name>DUTY</name>
              <bitOffset>2</bitOffset>
              <bitWidth>3</bitWidth>
            </field>
            <field>
              <name>BIAS</name>
              <bitOffset>5</bitOffset>
              <bitWidth>2</bitWidth>
            </field>
            <field>
              <name>MUX_SEG</name>
              <bitOffset>7</bitOffset>
              <bitWidth>1</bitWidth>
            </field>
            <field>
              <name>BUFEN</name>
              <bitOffset>8</bitOffset>
              <bitWidth>1</bitWidth>
            </field>
          </fields>
        </register>
        <register>
          <name>FCR</name>
          <addressOffset>0x4</addressOffset>
          <size>0x20</size>
          <fields>
            <field>
              <name>HD</name>
              <bitOffset>0</bitOffset>
              <bitWidth>1</bitWidth>
            </field>
            <field>
              <name>SOFIE</name>
              <bitOffset>1</bitOffset>
              <bitWidth>1</bitWidth>
            </field>
            <field>
              <name>UDDIE</name>
              <bitOffset>3</bitOffset>
              <bitWidth>1</bitWidth>
            </field>
            <field>
              <name>PON</name>
              <bitOffset>4</bitOffset>
              <bitWidth>3</bitWidth>
            </field>
            <field>
              <name>DEAD</name>
              <bitOffset>7</bitOffset>
              <bitWidth>3</bitWidth>
            </field>
            <field>
              <name>CC</name>
              <bitOffset>10</bitOffset>
              <bitWidth>3</bitWidth>
            </field>
            <field>
              <name>BLINKF</name>
              <bitOffset>13</bitOffset>
              <bitWidth>3</bitWidth>
            </field>
            <field>
              <name>BLINK</name>
              <bitOffset>16</bitOffset>
              <bitWidth>2</bitWidth>
            </field>
            <field>
              <name>DIV</name>
              <bitOffset>18</bitOffset>
              <bitWidth>4</bitWidth>
            </field>
            <field>
              <name>PS</name>
              <bitOffset>22</bitOffset>
              <bitWidth>4</bitWidth>
            </field>
          </fields>
        </register>
        <register>
          <name>SR</name>
          <addressOffset>0x8</addressOffset>
          <size>0x20</size>
          <fields>
            <field>
              <name>ENS</name>
              <bitOffset>0</bitOffset>
              <bitWidth>1</bitWidth>
            </field>
            <field>
              <name>SOF</name>
              <bitOffset>1</bitOffset>
              <bitWidth>1</bitWidth>
            </field>
            <field>
              <name>UDR</name>
              <bitOffset>2</bitOffset>
              <bitWidth>1</bitWidth>
            </field>
            <field>
              <name>UDD</name>
              <bitOffset>3</bitOffset>
              <bitWidth>1</bitWidth>
            </field>
            <field>
              <name>RDY</name>
              <bitOffset>4</bitOffset>
              <bitWidth>1</bitWidth>
            </field>
            <field>
              <name>FCRSR</name>
              <bitOffset>5</bitOffset>
              <bitWidth>1</bitWidth>
            </field>
          </fields>
        </register>
        <register>
          <name>CLR</name>
          <addressOffset>0xc</addressOffset>
          <size>0x20</size>
          <fields>
            <field>
              <name>SOFC</name>
              <bitOffset>1</bitOffset>
              <bitWidth>1</bitWidth>
            </field>
            <field>
              <name>UDDC</name>
              <bitOffset>3</bitOffset>
              <bitWidth>1</bitWidth>
            </field>
          </fields>
        </register>
        <register>
          <name>RAM.0</name>
          <addressOffset>0x14</addressOffset>
          <size>0x20</size>
          <fields>
            <field>
              <name>SEGMENT_DATA</name>
              <bitOffset>0</bitOffset>
              <bitWidth>32</bitWidth>
            </field>
          </fields>
        </register>
        <register>
          <name>RAM.1</name>
          <addressOffset>0x18</addressOffset>
          <size>0x20</size>
          <fields>
            <field>
              <name>SEGMENT_DATA</name>
              <bitOffset>0</bitOffset>
              <bitWidth>32</bitWidth>
            </field>
          </fields>
        </register>
        <register>
          <name>RAM.2</name>
          <addressOffset>0x1c</addressOffset>
          <size>0x20</size>
          <fields>
            <field>
              <name>SEGMENT_DATA</name>
              <bitOffset>0</bitOffset>
              <bitWidth>32</bitWidth>
            </field>
          </fields>
        </register>
        <register>
          <name>RAM.3</name>
          <addressOffset>0x20</addressOffset>
          <size>0x20</size>
          <fields>
            <field>
              <name>SEGMENT_DATA</name>
              <bitOffset>0</bitOffset>
              <bitWidth>32</bitWidth>
            </field>
          </fields>
        </register>
        <register>
          <name>RAM.4</name>
          <addressOffset>0x24</addressOffset>
          <size>0x20</size>
          <fields>
            <field>
              <name>SEGMENT_DATA</name>
              <bitOffset>0</bitOffset>
              <bitWidth>32</bitWidth>
            </field>
          </fields>
        </register>
        <register>
          <name>RAM.5</name>
          <addressOffset>0x28</addressOffset>
          <size>0x20</size>
          <fields>
            <field>
              <name>SEGMENT_DATA</name>
              <bitOffset>0</bitOffset>
              <bitWidth>32</bitWidth>
            </field>
          </fields>
        </register>
        <register>
          <name>RAM.6</name>
          <addressOffset>0x2c</addressOffset>
          <size>0x20</size>
          <fields>
            <field>
              <name>SEGMENT_DATA</name>
              <bitOffset>0</bitOffset>
              <bitWidth>32</bitWidth>
            </field>
          </fields>
        </register>
        <register>
          <name>RAM.7</name>
          <addressOffset>0x30</addressOffset>
          <size>0x20</size>
          <fields>
            <field>
              <name>SEGMENT_DATA</name>
              <bitOffset>0</bitOffset>
              <bitWidth>32</bitWidth>
            </field>
          </fields>
        </register>
        <register>
          <name>RAM.8</name>
          <addressOffset>0x34</addressOffset>
          <size>0x20</size>
          <fields>
            <field>
              <name>SEGMENT_DATA</name>
              <bitOffset>0</bitOffset>
              <bitWidth>32</bitWidth>
            </field>
          </fields>
        </register>
        <register>
          <name>RAM.9</name>
          <addressOffset>0x38</addressOffset>
          <size>0x20</size>
          <fields>
            <field>
              <name>SEGMENT_DATA</name>
              <bitOffset>0</bitOffset>
              <bitWidth>32</bitWidth>
            </field>
          </fields>
        </register>
        <register>
          <name>RAM.10</name>
          <addressOffset>0x3c</addressOffset>
          <size>0x20</size>
          <fields>
            <field>
              <name>SEGMENT_DATA</name>
              <bitOffset>0</bitOffset>
              <bitWidth>32</bitWidth>
            </field>
          </fields>
        </register>
        <register>
          <name>RAM.11</name>
          <addressOffset>0x40</addressOffset>
          <size>0x20</size>
          <fields>
            <field>
              <name>SEGMENT_DATA</name>
              <bitOffset>0</bitOffset>
              <bitWidth>32</bitWidth>
            </field>
          </fields>
        </register>
        <register>
          <name>RAM.12</name>
          <addressOffset>0x44</addressOffset>
          <size>0x20</size>
          <fields>
            <field>
              <name>SEGMENT_DATA</name>
              <bitOffset>0</bitOffset>
              <bitWidth>32</bitWidth>
            </field>
          </fields>
        </register>
        <register>
          <name>RAM.13</name>
          <addressOffset>0x48</addressOffset>
          <size>0x20</size>
          <fields>
            <field>
              <name>SEGMENT_DATA</name>
              <bitOffset>0</bitOffset>
              <bitWidth>32</bitWidth>
            </field>
          </fields>
        </register>
        <register>
          <name>RAM.14</name>
          <addressOffset>0x4c</addressOffset>
          <size>0x20</size>
          <fields>
            <field>
              <name>SEGMENT_DATA</name>
              <bitOffset>0</bitOffset>
              <bitWidth>32</bitWidth>
            </field>
          </fields>
        </register>
        <register>
          <name>RAM.15</name>
          <addressOffset>0x50</addressOffset>
          <size>0x20</size>
          <fields>
            <field>
              <name>SEGMENT_DATA</name>
              <bitOffset>0</bitOffset>
              <bitWidth>32</bitWidth>
            </field>
          </fields>
        </register>
      </registers>
    </peripheral>
    <peripheral>
      <name>RTC</name>
      <baseAddress>0x40002800</baseAddress>
      <registers>
        <register>
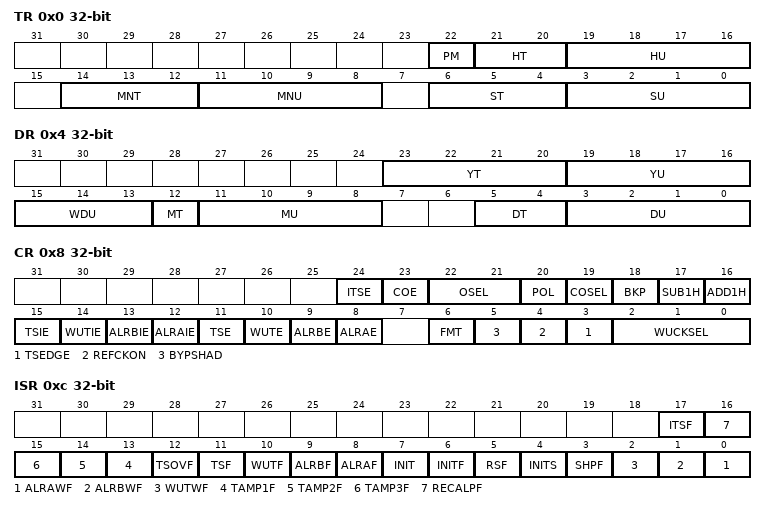
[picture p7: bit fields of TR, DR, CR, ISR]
          <name>TR</name>
          <addressOffset>0x0</addressOffset>
          <size>0x20</size>
          <fields>
            <field>
              <name>SU</name>
              <bitOffset>0</bitOffset>
              <bitWidth>4</bitWidth>
            </field>
            <field>
              <name>ST</name>
              <bitOffset>4</bitOffset>
              <bitWidth>3</bitWidth>
            </field>
            <field>
              <name>MNU</name>
              <bitOffset>8</bitOffset>
              <bitWidth>4</bitWidth>
            </field>
            <field>
              <name>MNT</name>
              <bitOffset>12</bitOffset>
              <bitWidth>3</bitWidth>
            </field>
            <field>
              <name>HU</name>
              <bitOffset>16</bitOffset>
              <bitWidth>4</bitWidth>
            </field>
            <field>
              <name>HT</name>
              <bitOffset>20</bitOffset>
              <bitWidth>2</bitWidth>
            </field>
            <field>
              <name>PM</name>
              <bitOffset>22</bitOffset>
              <bitWidth>1</bitWidth>
            </field>
          </fields>
        </register>
        <register>
          <name>DR</name>
          <addressOffset>0x4</addressOffset>
          <size>0x20</size>
          <fields>
            <field>
              <name>DU</name>
              <bitOffset>0</bitOffset>
              <bitWidth>4</bitWidth>
            </field>
            <field>
              <name>DT</name>
              <bitOffset>4</bitOffset>
              <bitWidth>2</bitWidth>
            </field>
            <field>
              <name>MU</name>
              <bitOffset>8</bitOffset>
              <bitWidth>4</bitWidth>
            </field>
            <field>
              <name>MT</name>
              <bitOffset>12</bitOffset>
              <bitWidth>1</bitWidth>
            </field>
            <field>
              <name>WDU</name>
              <bitOffset>13</bitOffset>
              <bitWidth>3</bitWidth>
            </field>
            <field>
              <name>YU</name>
              <bitOffset>16</bitOffset>
              <bitWidth>4</bitWidth>
            </field>
            <field>
              <name>YT</name>
              <bitOffset>20</bitOffset>
              <bitWidth>4</bitWidth>
            </field>
          </fields>
        </register>
        <register>
          <name>CR</name>
          <addressOffset>0x8</addressOffset>
          <size>0x20</size>
          <fields>
            <field>
              <name>WUCKSEL</name>
              <bitOffset>0</bitOffset>
              <bitWidth>3</bitWidth>
            </field>
            <field>
              <name>TSEDGE</name>
              <bitOffset>3</bitOffset>
              <bitWidth>1</bitWidth>
            </field>
            <field>
              <name>REFCKON</name>
              <bitOffset>4</bitOffset>
              <bitWidth>1</bitWidth>
            </field>
            <field>
              <name>BYPSHAD</name>
              <bitOffset>5</bitOffset>
              <bitWidth>1</bitWidth>
            </field>
            <field>
              <name>FMT</name>
              <bitOffset>6</bitOffset>
              <bitWidth>1</bitWidth>
            </field>
            <field>
              <name>ALRAE</name>
              <bitOffset>8</bitOffset>
              <bitWidth>1</bitWidth>
            </field>
            <field>
              <name>ALRBE</name>
              <bitOffset>9</bitOffset>
              <bitWidth>1</bitWidth>
            </field>
            <field>
              <name>WUTE</name>
              <bitOffset>10</bitOffset>
              <bitWidth>1</bitWidth>
            </field>
            <field>
              <name>TSE</name>
              <bitOffset>11</bitOffset>
              <bitWidth>1</bitWidth>
            </field>
            <field>
              <name>ALRAIE</name>
              <bitOffset>12</bitOffset>
              <bitWidth>1</bitWidth>
            </field>
            <field>
              <name>ALRBIE</name>
              <bitOffset>13</bitOffset>
              <bitWidth>1</bitWidth>
            </field>
            <field>
              <name>WUTIE</name>
              <bitOffset>14</bitOffset>
              <bitWidth>1</bitWidth>
            </field>
            <field>
              <name>TSIE</name>
              <bitOffset>15</bitOffset>
              <bitWidth>1</bitWidth>
            </field>
            <field>
              <name>ADD1H</name>
              <bitOffset>16</bitOffset>
              <bitWidth>1</bitWidth>
            </field>
            <field>
              <name>SUB1H</name>
              <bitOffset>17</bitOffset>
              <bitWidth>1</bitWidth>
            </field>
            <field>
              <name>BKP</name>
              <bitOffset>18</bitOffset>
              <bitWidth>1</bitWidth>
            </field>
            <field>
              <name>COSEL</name>
              <bitOffset>19</bitOffset>
              <bitWidth>1</bitWidth>
            </field>
            <field>
              <name>POL</name>
              <bitOffset>20</bitOffset>
              <bitWidth>1</bitWidth>
            </field>
            <field>
              <name>OSEL</name>
              <bitOffset>21</bitOffset>
              <bitWidth>2</bitWidth>
            </field>
            <field>
              <name>COE</name>
              <bitOffset>23</bitOffset>
              <bitWidth>1</bitWidth>
            </field>
            <field>
              <name>ITSE</name>
              <bitOffset>24</bitOffset>
              <bitWidth>1</bitWidth>
            </field>
          </fields>
        </register>
        <register>
          <name>ISR</name>
          <addressOffset>0xc</addressOffset>
          <size>0x20</size>
          <fields>
            <field>
              <name>ALRAWF</name>
              <bitOffset>0</bitOffset>
              <bitWidth>1</bitWidth>
            </field>
            <field>
              <name>ALRBWF</name>
              <bitOffset>1</bitOffset>
              <bitWidth>1</bitWidth>
            </field>
            <field>
              <name>WUTWF</name>
              <bitOffset>2</bitOffset>
              <bitWidth>1</bitWidth>
            </field>
            <field>
              <name>SHPF</name>
              <bitOffset>3</bitOffset>
              <bitWidth>1</bitWidth>
            </field>
            <field>
              <name>INITS</name>
              <bitOffset>4</bitOffset>
              <bitWidth>1</bitWidth>
            </field>
            <field>
              <name>RSF</name>
              <bitOffset>5</bitOffset>
              <bitWidth>1</bitWidth>
            </field>
            <field>
              <name>INITF</name>
              <bitOffset>6</bitOffset>
              <bitWidth>1</bitWidth>
            </field>
            <field>
              <name>INIT</name>
              <bitOffset>7</bitOffset>
              <bitWidth>1</bitWidth>
            </field>
            <field>
              <name>ALRAF</name>
              <bitOffset>8</bitOffset>
              <bitWidth>1</bitWidth>
            </field>
            <field>
              <name>ALRBF</name>
              <bitOffset>9</bitOffset>
              <bitWidth>1</bitWidth>
            </field>
            <field>
              <name>WUTF</name>
              <bitOffset>10</bitOffset>
              <bitWidth>1</bitWidth>
            </field>
            <field>
              <name>TSF</name>
              <bitOffset>11</bitOffset>
              <bitWidth>1</bitWidth>
            </field>
            <field>
              <name>TSOVF</name>
              <bitOffset>12</bitOffset>
              <bitWidth>1</bitWidth>
            </field>
            <field>
              <name>TAMP1F</name>
              <bitOffset>13</bitOffset>
              <bitWidth>1</bitWidth>
            </field>
            <field>
              <name>TAMP2F</name>
              <bitOffset>14</bitOffset>
              <bitWidth>1</bitWidth>
            </field>
            <field>
              <name>TAMP3F</name>
              <bitOffset>15</bitOffset>
              <bitWidth>1</bitWidth>
            </field>
            <field>
              <name>RECALPF</name>
              <bitOffset>16</bitOffset>
              <bitWidth>1</bitWidth>
            </field>
            <field>
              <name>ITSF</name>
              <bitOffset>17</bitOffset>
              <bitWidth>1</bitWidth>
            </field>
          </fields>
        </register>
        <register>
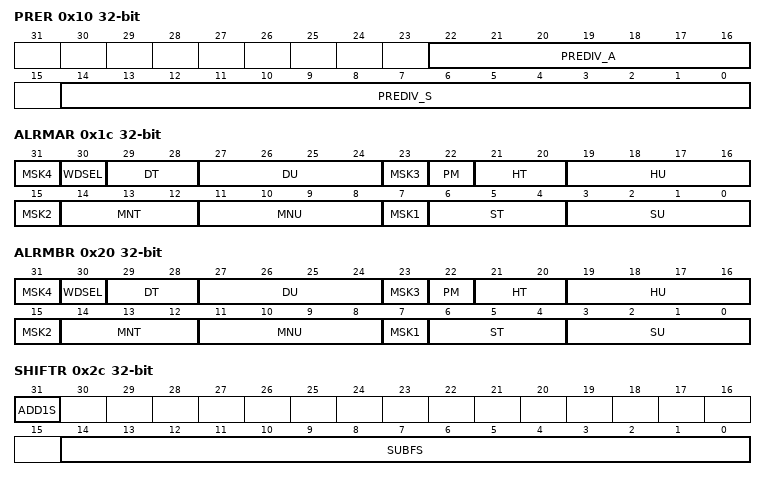
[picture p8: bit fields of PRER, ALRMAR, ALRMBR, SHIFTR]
          <name>PRER</name>
          <addressOffset>0x10</addressOffset>
          <size>0x20</size>
          <fields>
            <field>
              <name>PREDIV_S</name>
              <bitOffset>0</bitOffset>
              <bitWidth>15</bitWidth>
            </field>
            <field>
              <name>PREDIV_A</name>
              <bitOffset>16</bitOffset>
              <bitWidth>7</bitWidth>
            </field>
          </fields>
        </register>
        <register>
          <name>WUTR</name>
          <addressOffset>0x14</addressOffset>
          <size>0x20</size>
          <fields>
            <field>
              <name>WUT</name>
              <bitOffset>0</bitOffset>
              <bitWidth>16</bitWidth>
            </field>
          </fields>
        </register>
        <register>
          <name>ALRMAR</name>
          <addressOffset>0x1c</addressOffset>
          <size>0x20</size>
          <fields>
            <field>
              <name>SU</name>
              <bitOffset>0</bitOffset>
              <bitWidth>4</bitWidth>
            </field>
            <field>
              <name>ST</name>
              <bitOffset>4</bitOffset>
              <bitWidth>3</bitWidth>
            </field>
            <field>
              <name>MSK1</name>
              <bitOffset>7</bitOffset>
              <bitWidth>1</bitWidth>
            </field>
            <field>
              <name>MNU</name>
              <bitOffset>8</bitOffset>
              <bitWidth>4</bitWidth>
            </field>
            <field>
              <name>MNT</name>
              <bitOffset>12</bitOffset>
              <bitWidth>3</bitWidth>
            </field>
            <field>
              <name>MSK2</name>
              <bitOffset>15</bitOffset>
              <bitWidth>1</bitWidth>
            </field>
            <field>
              <name>HU</name>
              <bitOffset>16</bitOffset>
              <bitWidth>4</bitWidth>
            </field>
            <field>
              <name>HT</name>
              <bitOffset>20</bitOffset>
              <bitWidth>2</bitWidth>
            </field>
            <field>
              <name>PM</name>
              <bitOffset>22</bitOffset>
              <bitWidth>1</bitWidth>
            </field>
            <field>
              <name>MSK3</name>
              <bitOffset>23</bitOffset>
              <bitWidth>1</bitWidth>
            </field>
            <field>
              <name>DU</name>
              <bitOffset>24</bitOffset>
              <bitWidth>4</bitWidth>
            </field>
            <field>
              <name>DT</name>
              <bitOffset>28</bitOffset>
              <bitWidth>2</bitWidth>
            </field>
            <field>
              <name>WDSEL</name>
              <bitOffset>30</bitOffset>
              <bitWidth>1</bitWidth>
            </field>
            <field>
              <name>MSK4</name>
              <bitOffset>31</bitOffset>
              <bitWidth>1</bitWidth>
            </field>
          </fields>
        </register>
        <register>
          <name>ALRMBR</name>
          <addressOffset>0x20</addressOffset>
          <size>0x20</size>
          <fields>
            <field>
              <name>SU</name>
              <bitOffset>0</bitOffset>
              <bitWidth>4</bitWidth>
            </field>
            <field>
              <name>ST</name>
              <bitOffset>4</bitOffset>
              <bitWidth>3</bitWidth>
            </field>
            <field>
              <name>MSK1</name>
              <bitOffset>7</bitOffset>
              <bitWidth>1</bitWidth>
            </field>
            <field>
              <name>MNU</name>
              <bitOffset>8</bitOffset>
              <bitWidth>4</bitWidth>
            </field>
            <field>
              <name>MNT</name>
              <bitOffset>12</bitOffset>
              <bitWidth>3</bitWidth>
            </field>
            <field>
              <name>MSK2</name>
              <bitOffset>15</bitOffset>
              <bitWidth>1</bitWidth>
            </field>
            <field>
              <name>HU</name>
              <bitOffset>16</bitOffset>
              <bitWidth>4</bitWidth>
            </field>
            <field>
              <name>HT</name>
              <bitOffset>20</bitOffset>
              <bitWidth>2</bitWidth>
            </field>
            <field>
              <name>PM</name>
              <bitOffset>22</bitOffset>
              <bitWidth>1</bitWidth>
            </field>
            <field>
              <name>MSK3</name>
              <bitOffset>23</bitOffset>
              <bitWidth>1</bitWidth>
            </field>
            <field>
              <name>DU</name>
              <bitOffset>24</bitOffset>
              <bitWidth>4</bitWidth>
            </field>
            <field>
              <name>DT</name>
              <bitOffset>28</bitOffset>
              <bitWidth>2</bitWidth>
            </field>
            <field>
              <name>WDSEL</name>
              <bitOffset>30</bitOffset>
              <bitWidth>1</bitWidth>
            </field>
            <field>
              <name>MSK4</name>
              <bitOffset>31</bitOffset>
              <bitWidth>1</bitWidth>
            </field>
          </fields>
        </register>
        <register>
          <name>WPR</name>
          <addressOffset>0x24</addressOffset>
          <size>0x20</size>
          <fields>
            <field>
              <name>KEY</name>
              <bitOffset>0</bitOffset>
              <bitWidth>8</bitWidth>
            </field>
          </fields>
        </register>
        <register>
          <name>SSR</name>
          <addressOffset>0x28</addressOffset>
          <size>0x20</size>
          <fields>
            <field>
              <name>SS</name>
              <bitOffset>0</bitOffset>
              <bitWidth>16</bitWidth>
            </field>
          </fields>
        </register>
        <register>
          <name>SHIFTR</name>
          <addressOffset>0x2c</addressOffset>
          <size>0x20</size>
          <fields>
            <field>
              <name>SUBFS</name>
              <bitOffset>0</bitOffset>
              <bitWidth>15</bitWidth>
            </field>
            <field>
              <name>ADD1S</name>
              <bitOffset>31</bitOffset>
              <bitWidth>1</bitWidth>
            </field>
          </fields>
        </register>
        <register>
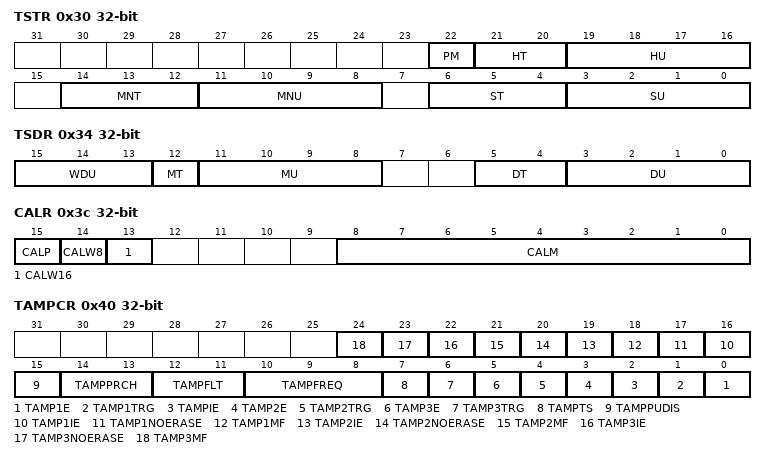
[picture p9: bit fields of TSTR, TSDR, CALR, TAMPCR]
          <name>TSTR</name>
          <addressOffset>0x30</addressOffset>
          <size>0x20</size>
          <fields>
            <field>
              <name>SU</name>
              <bitOffset>0</bitOffset>
              <bitWidth>4</bitWidth>
            </field>
            <field>
              <name>ST</name>
              <bitOffset>4</bitOffset>
              <bitWidth>3</bitWidth>
            </field>
            <field>
              <name>MNU</name>
              <bitOffset>8</bitOffset>
              <bitWidth>4</bitWidth>
            </field>
            <field>
              <name>MNT</name>
              <bitOffset>12</bitOffset>
              <bitWidth>3</bitWidth>
            </field>
            <field>
              <name>HU</name>
              <bitOffset>16</bitOffset>
              <bitWidth>4</bitWidth>
            </field>
            <field>
              <name>HT</name>
              <bitOffset>20</bitOffset>
              <bitWidth>2</bitWidth>
            </field>
            <field>
              <name>PM</name>
              <bitOffset>22</bitOffset>
              <bitWidth>1</bitWidth>
            </field>
          </fields>
        </register>
        <register>
          <name>TSDR</name>
          <addressOffset>0x34</addressOffset>
          <size>0x20</size>
          <fields>
            <field>
              <name>DU</name>
              <bitOffset>0</bitOffset>
              <bitWidth>4</bitWidth>
            </field>
            <field>
              <name>DT</name>
              <bitOffset>4</bitOffset>
              <bitWidth>2</bitWidth>
            </field>
            <field>
              <name>MU</name>
              <bitOffset>8</bitOffset>
              <bitWidth>4</bitWidth>
            </field>
            <field>
              <name>MT</name>
              <bitOffset>12</bitOffset>
              <bitWidth>1</bitWidth>
            </field>
            <field>
              <name>WDU</name>
              <bitOffset>13</bitOffset>
              <bitWidth>3</bitWidth>
            </field>
          </fields>
        </register>
        <register>
          <name>TSSSR</name>
          <addressOffset>0x38</addressOffset>
          <size>0x20</size>
          <fields>
            <field>
              <name>SS</name>
              <bitOffset>0</bitOffset>
              <bitWidth>16</bitWidth>
            </field>
          </fields>
        </register>
        <register>
          <name>CALR</name>
          <addressOffset>0x3c</addressOffset>
          <size>0x20</size>
          <fields>
            <field>
              <name>CALM</name>
              <bitOffset>0</bitOffset>
              <bitWidth>9</bitWidth>
            </field>
            <field>
              <name>CALW16</name>
              <bitOffset>13</bitOffset>
              <bitWidth>1</bitWidth>
            </field>
            <field>
              <name>CALW8</name>
              <bitOffset>14</bitOffset>
              <bitWidth>1</bitWidth>
            </field>
            <field>
              <name>CALP</name>
              <bitOffset>15</bitOffset>
              <bitWidth>1</bitWidth>
            </field>
          </fields>
        </register>
        <register>
          <name>TAMPCR</name>
          <addressOffset>0x40</addressOffset>
          <size>0x20</size>
          <fields>
            <field>
              <name>TAMP1E</name>
              <bitOffset>0</bitOffset>
              <bitWidth>1</bitWidth>
            </field>
            <field>
              <name>TAMP1TRG</name>
              <bitOffset>1</bitOffset>
              <bitWidth>1</bitWidth>
            </field>
            <field>
              <name>TAMPIE</name>
              <bitOffset>2</bitOffset>
              <bitWidth>1</bitWidth>
            </field>
            <field>
              <name>TAMP2E</name>
              <bitOffset>3</bitOffset>
              <bitWidth>1</bitWidth>
            </field>
            <field>
              <name>TAMP2TRG</name>
              <bitOffset>4</bitOffset>
              <bitWidth>1</bitWidth>
            </field>
            <field>
              <name>TAMP3E</name>
              <bitOffset>5</bitOffset>
              <bitWidth>1</bitWidth>
            </field>
            <field>
              <name>TAMP3TRG</name>
              <bitOffset>6</bitOffset>
              <bitWidth>1</bitWidth>
            </field>
            <field>
              <name>TAMPTS</name>
              <bitOffset>7</bitOffset>
              <bitWidth>1</bitWidth>
            </field>
            <field>
              <name>TAMPFREQ</name>
              <bitOffset>8</bitOffset>
              <bitWidth>3</bitWidth>
            </field>
            <field>
              <name>TAMPFLT</name>
              <bitOffset>11</bitOffset>
              <bitWidth>2</bitWidth>
            </field>
            <field>
              <name>TAMPPRCH</name>
              <bitOffset>13</bitOffset>
              <bitWidth>2</bitWidth>
            </field>
            <field>
              <name>TAMPPUDIS</name>
              <bitOffset>15</bitOffset>
              <bitWidth>1</bitWidth>
            </field>
            <field>
              <name>TAMP1IE</name>
              <bitOffset>16</bitOffset>
              <bitWidth>1</bitWidth>
            </field>
            <field>
              <name>TAMP1NOERASE</name>
              <bitOffset>17</bitOffset>
              <bitWidth>1</bitWidth>
            </field>
            <field>
              <name>TAMP1MF</name>
              <bitOffset>18</bitOffset>
              <bitWidth>1</bitWidth>
            </field>
            <field>
              <name>TAMP2IE</name>
              <bitOffset>19</bitOffset>
              <bitWidth>1</bitWidth>
            </field>
            <field>
              <name>TAMP2NOERASE</name>
              <bitOffset>20</bitOffset>
              <bitWidth>1</bitWidth>
            </field>
            <field>
              <name>TAMP2MF</name>
              <bitOffset>21</bitOffset>
              <bitWidth>1</bitWidth>
            </field>
            <field>
              <name>TAMP3IE</name>
              <bitOffset>22</bitOffset>
              <bitWidth>1</bitWidth>
            </field>
            <field>
              <name>TAMP3NOERASE</name>
              <bitOffset>23</bitOffset>
              <bitWidth>1</bitWidth>
            </field>
            <field>
              <name>TAMP3MF</name>
              <bitOffset>24</bitOffset>
              <bitWidth>1</bitWidth>
            </field>
          </fields>
        </register>
        <register>
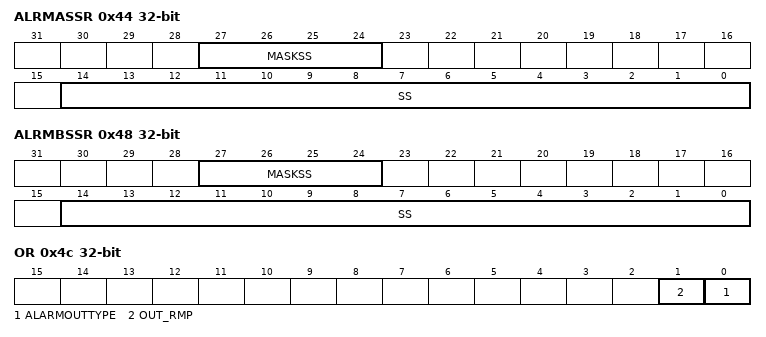
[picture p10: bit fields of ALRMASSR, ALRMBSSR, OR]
          <name>ALRMASSR</name>
          <addressOffset>0x44</addressOffset>
          <size>0x20</size>
          <fields>
            <field>
              <name>SS</name>
              <bitOffset>0</bitOffset>
              <bitWidth>15</bitWidth>
            </field>
            <field>
              <name>MASKSS</name>
              <bitOffset>24</bitOffset>
              <bitWidth>4</bitWidth>
            </field>
          </fields>
        </register>
        <register>
          <name>ALRMBSSR</name>
          <addressOffset>0x48</addressOffset>
          <size>0x20</size>
          <fields>
            <field>
              <name>SS</name>
              <bitOffset>0</bitOffset>
              <bitWidth>15</bitWidth>
            </field>
            <field>
              <name>MASKSS</name>
              <bitOffset>24</bitOffset>
              <bitWidth>4</bitWidth>
            </field>
          </fields>
        </register>
        <register>
          <name>OR</name>
          <addressOffset>0x4c</addressOffset>
          <size>0x20</size>
          <fields>
            <field>
              <name>ALARMOUTTYPE</name>
              <bitOffset>0</bitOffset>
              <bitWidth>1</bitWidth>
            </field>
            <field>
              <name>OUT_RMP</name>
              <bitOffset>1</bitOffset>
              <bitWidth>1</bitWidth>
            </field>
          </fields>
        </register>
        <register>
          <name>BKP0R</name>
          <addressOffset>0x50</addressOffset>
          <size>0x20</size>
        </register>
        <register>
          <name>BKP1R</name>
          <addressOffset>0x54</addressOffset>
          <size>0x20</size>
        </register>
        <register>
          <name>BKP2R</name>
          <addressOffset>0x58</addressOffset>
          <size>0x20</size>
        </register>
        <register>
          <name>BKP3R</name>
          <addressOffset>0x5c</addressOffset>
          <size>0x20</size>
        </register>
        <register>
          <name>BKP4R</name>
          <addressOffset>0x60</addressOffset>
          <size>0x20</size>
        </register>
        <register>
          <name>BKP5R</name>
          <addressOffset>0x64</addressOffset>
          <size>0x20</size>
        </register>
        <register>
          <name>BKP6R</name>
          <addressOffset>0x68</addressOffset>
          <size>0x20</size>
        </register>
        <register>
          <name>BKP7R</name>
          <addressOffset>0x6c</addressOffset>
          <size>0x20</size>
        </register>
        <register>
          <name>BKP8R</name>
          <addressOffset>0x70</addressOffset>
          <size>0x20</size>
        </register>
        <register>
          <name>BKP9R</name>
          <addressOffset>0x74</addressOffset>
          <size>0x20</size>
        </register>
        <register>
          <name>BKP10R</name>
          <addressOffset>0x78</addressOffset>
          <size>0x20</size>
        </register>
        <register>
          <name>BKP11R</name>
          <addressOffset>0x7c</addressOffset>
          <size>0x20</size>
        </register>
        <register>
          <name>BKP12R</name>
          <addressOffset>0x80</addressOffset>
          <size>0x20</size>
        </register>
        <register>
          <name>BKP13R</name>
          <addressOffset>0x84</addressOffset>
          <size>0x20</size>
        </register>
        <register>
          <name>BKP14R</name>
          <addressOffset>0x88</addressOffset>
          <size>0x20</size>
        </register>
        <register>
          <name>BKP15R</name>
          <addressOffset>0x8c</addressOffset>
          <size>0x20</size>
        </register>
        <register>
          <name>BKP16R</name>
          <addressOffset>0x90</addressOffset>
          <size>0x20</size>
        </register>
        <register>
          <name>BKP17R</name>
          <addressOffset>0x94</addressOffset>
          <size>0x20</size>
        </register>
        <register>
          <name>BKP18R</name>
          <addressOffset>0x98</addressOffset>
          <size>0x20</size>
        </register>
        <register>
          <name>BKP19R</name>
          <addressOffset>0x9c</addressOffset>
          <size>0x20</size>
        </register>
        <register>
          <name>BKP20R</name>
          <addressOffset>0xa0</addressOffset>
          <size>0x20</size>
        </register>
        <register>
          <name>BKP21R</name>
          <addressOffset>0xa4</addressOffset>
          <size>0x20</size>
        </register>
        <register>
          <name>BKP22R</name>
          <addressOffset>0xa8</addressOffset>
          <size>0x20</size>
        </register>
        <register>
          <name>BKP23R</name>
          <addressOffset>0xac</addressOffset>
          <size>0x20</size>
        </register>
        <register>
          <name>BKP24R</name>
          <addressOffset>0xb0</addressOffset>
          <size>0x20</size>
        </register>
        <register>
          <name>BKP25R</name>
          <addressOffset>0xb4</addressOffset>
          <size>0x20</size>
        </register>
        <register>
          <name>BKP26R</name>
          <addressOffset>0xb8</addressOffset>
          <size>0x20</size>
        </register>
        <register>
          <name>BKP27R</name>
          <addressOffset>0xbc</addressOffset>
          <size>0x20</size>
        </register>
        <register>
          <name>BKP28R</name>
          <addressOffset>0xc0</addressOffset>
          <size>0x20</size>
        </register>
        <register>
          <name>BKP29R</name>
          <addressOffset>0xc4</addressOffset>
          <size>0x20</size>
        </register>
        <register>
          <name>BKP30R</name>
          <addressOffset>0xc8</addressOffset>
          <size>0x20</size>
        </register>
        <register>
          <name>BKP31R</name>
          <addressOffset>0xcc</addressOffset>
          <size>0x20</size>
        </register>
      </registers>
    </peripheral>
    <peripheral>
      <name>WWDG</name>
      <baseAddress>0x40002c00</baseAddress>
      <registers>
        <register>
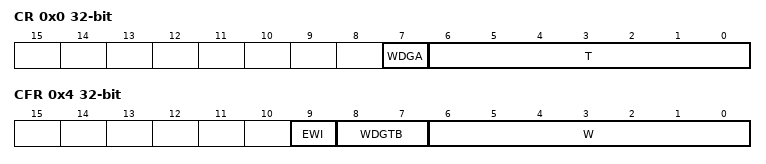
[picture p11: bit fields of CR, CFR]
          <name>CR</name>
          <addressOffset>0x0</addressOffset>
          <size>0x20</size>
          <fields>
            <field>
              <name>T</name>
              <bitOffset>0</bitOffset>
              <bitWidth>7</bitWidth>
            </field>
            <field>
              <name>WDGA</name>
              <bitOffset>7</bitOffset>
              <bitWidth>1</bitWidth>
            </field>
          </fields>
        </register>
        <register>
          <name>CFR</name>
          <addressOffset>0x4</addressOffset>
          <size>0x20</size>
          <fields>
            <field>
              <name>W</name>
              <bitOffset>0</bitOffset>
              <bitWidth>7</bitWidth>
            </field>
            <field>
              <name>WDGTB</name>
              <bitOffset>7</bitOffset>
              <bitWidth>2</bitWidth>
            </field>
            <field>
              <name>EWI</name>
              <bitOffset>9</bitOffset>
              <bitWidth>1</bitWidth>
            </field>
          </fields>
        </register>
        <register>
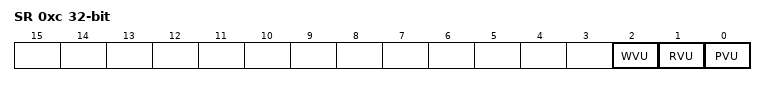
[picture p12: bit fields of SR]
          <name>SR</name>
          <addressOffset>0x8</addressOffset>
          <size>0x20</size>
          <fields>
            <field>
              <name>EWIF</name>
              <bitOffset>0</bitOffset>
              <bitWidth>1</bitWidth>
            </field>
          </fields>
        </register>
      </registers>
    </peripheral>
    <peripheral>
      <name>IWDG</name>
      <baseAddress>0x40003000</baseAddress>
      <registers>
        <register>
          <name>KR</name>
          <addressOffset>0x0</addressOffset>
          <size>0x20</size>
          <fields>
            <field>
              <name>KEY</name>
              <bitOffset>0</bitOffset>
              <bitWidth>16</bitWidth>
            </field>
          </fields>
        </register>
        <register>
          <name>PR</name>
          <addressOffset>0x4</addressOffset>
          <size>0x20</size>
          <fields>
            <field>
              <name>PR</name>
              <bitOffset>0</bitOffset>
              <bitWidth>3</bitWidth>
            </field>
          </fields>
        </register>
        <register>
          <name>RLR</name>
          <addressOffset>0x8</addressOffset>
          <size>0x20</size>
          <fields>
            <field>
              <name>RL</name>
              <bitOffset>0</bitOffset>
              <bitWidth>12</bitWidth>
            </field>
          </fields>
        </register>
        <register>
          <name>SR</name>
          <addressOffset>0xc</addressOffset>
          <size>0x20</size>
          <fields>
            <field>
              <name>PVU</name>
              <bitOffset>0</bitOffset>
              <bitWidth>1</bitWidth>
            </field>
            <field>
              <name>RVU</name>
              <bitOffset>1</bitOffset>
              <bitWidth>1</bitWidth>
            </field>
            <field>
              <name>WVU</name>
              <bitOffset>2</bitOffset>
              <bitWidth>1</bitWidth>
            </field>
          </fields>
        </register>
        <register>
          <name>WINR</name>
          <addressOffset>0x10</addressOffset>
          <size>0x20</size>
          <fields>
            <field>
              <name>WIN</name>
              <bitOffset>0</bitOffset>
              <bitWidth>12</bitWidth>
            </field>
          </fields>
        </register>
      </registers>
    </peripheral>
    <peripheral>
      <name>SPI2</name>
      <baseAddress>0x40003800</baseAddress>
      <registers>
        <register>
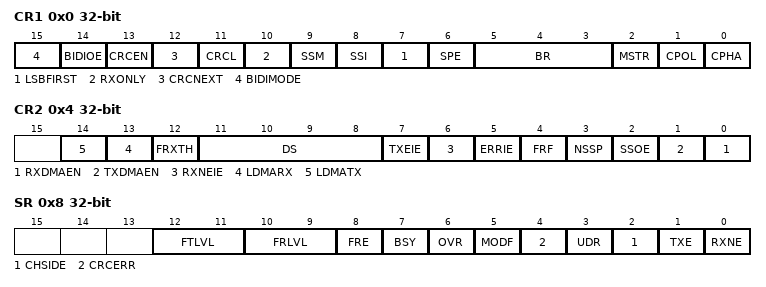
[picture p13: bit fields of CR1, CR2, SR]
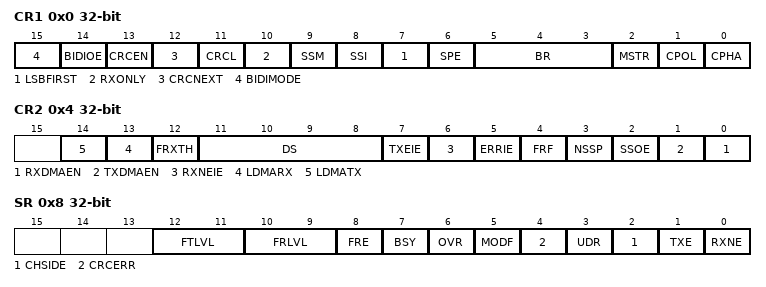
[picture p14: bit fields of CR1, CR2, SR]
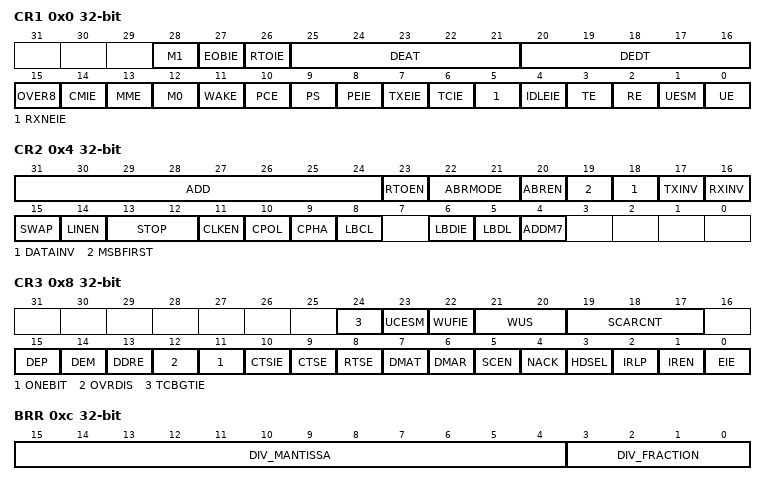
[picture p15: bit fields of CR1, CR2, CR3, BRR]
          <name>CR1</name>
          <addressOffset>0x0</addressOffset>
          <size>0x20</size>
          <fields>
            <field>
              <name>CPHA</name>
              <bitOffset>0</bitOffset>
              <bitWidth>1</bitWidth>
            </field>
            <field>
              <name>CPOL</name>
              <bitOffset>1</bitOffset>
              <bitWidth>1</bitWidth>
            </field>
            <field>
              <name>MSTR</name>
              <bitOffset>2</bitOffset>
              <bitWidth>1</bitWidth>
            </field>
            <field>
              <name>BR</name>
              <bitOffset>3</bitOffset>
              <bitWidth>3</bitWidth>
            </field>
            <field>
              <name>SPE</name>
              <bitOffset>6</bitOffset>
              <bitWidth>1</bitWidth>
            </field>
            <field>
              <name>LSBFIRST</name>
              <bitOffset>7</bitOffset>
              <bitWidth>1</bitWidth>
            </field>
            <field>
              <name>SSI</name>
              <bitOffset>8</bitOffset>
              <bitWidth>1</bitWidth>
            </field>
            <field>
              <name>SSM</name>
              <bitOffset>9</bitOffset>
              <bitWidth>1</bitWidth>
            </field>
            <field>
              <name>RXONLY</name>
              <bitOffset>10</bitOffset>
              <bitWidth>1</bitWidth>
            </field>
            <field>
              <name>CRCL</name>
              <bitOffset>11</bitOffset>
              <bitWidth>1</bitWidth>
            </field>
            <field>
              <name>CRCNEXT</name>
              <bitOffset>12</bitOffset>
              <bitWidth>1</bitWidth>
            </field>
            <field>
              <name>CRCEN</name>
              <bitOffset>13</bitOffset>
              <bitWidth>1</bitWidth>
            </field>
            <field>
              <name>BIDIOE</name>
              <bitOffset>14</bitOffset>
              <bitWidth>1</bitWidth>
            </field>
            <field>
              <name>BIDIMODE</name>
              <bitOffset>15</bitOffset>
              <bitWidth>1</bitWidth>
            </field>
          </fields>
        </register>
        <register>
          <name>CR2</name>
          <addressOffset>0x4</addressOffset>
          <size>0x20</size>
          <fields>
            <field>
              <name>RXDMAEN</name>
              <bitOffset>0</bitOffset>
              <bitWidth>1</bitWidth>
            </field>
            <field>
              <name>TXDMAEN</name>
              <bitOffset>1</bitOffset>
              <bitWidth>1</bitWidth>
            </field>
            <field>
              <name>SSOE</name>
              <bitOffset>2</bitOffset>
              <bitWidth>1</bitWidth>
            </field>
            <field>
              <name>NSSP</name>
              <bitOffset>3</bitOffset>
              <bitWidth>1</bitWidth>
            </field>
            <field>
              <name>FRF</name>
              <bitOffset>4</bitOffset>
              <bitWidth>1</bitWidth>
            </field>
            <field>
              <name>ERRIE</name>
              <bitOffset>5</bitOffset>
              <bitWidth>1</bitWidth>
            </field>
            <field>
              <name>RXNEIE</name>
              <bitOffset>6</bitOffset>
              <bitWidth>1</bitWidth>
            </field>
            <field>
              <name>TXEIE</name>
              <bitOffset>7</bitOffset>
              <bitWidth>1</bitWidth>
            </field>
            <field>
              <name>DS</name>
              <bitOffset>8</bitOffset>
              <bitWidth>4</bitWidth>
            </field>
            <field>
              <name>FRXTH</name>
              <bitOffset>12</bitOffset>
              <bitWidth>1</bitWidth>
            </field>
            <field>
              <name>LDMARX</name>
              <bitOffset>13</bitOffset>
              <bitWidth>1</bitWidth>
            </field>
            <field>
              <name>LDMATX</name>
              <bitOffset>14</bitOffset>
              <bitWidth>1</bitWidth>
            </field>
          </fields>
        </register>
        <register>
          <name>SR</name>
          <addressOffset>0x8</addressOffset>
          <size>0x20</size>
          <fields>
            <field>
              <name>RXNE</name>
              <bitOffset>0</bitOffset>
              <bitWidth>1</bitWidth>
            </field>
            <field>
              <name>TXE</name>
              <bitOffset>1</bitOffset>
              <bitWidth>1</bitWidth>
            </field>
            <field>
              <name>CHSIDE</name>
              <bitOffset>2</bitOffset>
              <bitWidth>1</bitWidth>
            </field>
            <field>
              <name>UDR</name>
              <bitOffset>3</bitOffset>
              <bitWidth>1</bitWidth>
            </field>
            <field>
              <name>CRCERR</name>
              <bitOffset>4</bitOffset>
              <bitWidth>1</bitWidth>
            </field>
            <field>
              <name>MODF</name>
              <bitOffset>5</bitOffset>
              <bitWidth>1</bitWidth>
            </field>
            <field>
              <name>OVR</name>
              <bitOffset>6</bitOffset>
              <bitWidth>1</bitWidth>
            </field>
            <field>
              <name>BSY</name>
              <bitOffset>7</bitOffset>
              <bitWidth>1</bitWidth>
            </field>
            <field>
              <name>FRE</name>
              <bitOffset>8</bitOffset>
              <bitWidth>1</bitWidth>
            </field>
            <field>
              <name>FRLVL</name>
              <bitOffset>9</bitOffset>
              <bitWidth>2</bitWidth>
            </field>
            <field>
              <name>FTLVL</name>
              <bitOffset>11</bitOffset>
              <bitWidth>2</bitWidth>
            </field>
          </fields>
        </register>
        <register>
          <name>DR</name>
          <addressOffset>0xc</addressOffset>
          <size>0x20</size>
          <fields>
            <field>
              <name>DR</name>
              <bitOffset>0</bitOffset>
              <bitWidth>16</bitWidth>
            </field>
          </fields>
        </register>
        <register>
          <name>CRCPR</name>
          <addressOffset>0x10</addressOffset>
          <size>0x20</size>
          <fields>
            <field>
              <name>CRCPOLY</name>
              <bitOffset>0</bitOffset>
              <bitWidth>16</bitWidth>
            </field>
          </fields>
        </register>
        <register>
          <name>RXCRCR</name>
          <addressOffset>0x14</addressOffset>
          <size>0x20</size>
          <fields>
            <field>
              <name>RXCRC</name>
              <bitOffset>0</bitOffset>
              <bitWidth>16</bitWidth>
            </field>
          </fields>
        </register>
        <register>
          <name>TXCRCR</name>
          <addressOffset>0x18</addressOffset>
          <size>0x20</size>
          <fields>
            <field>
              <name>TXCRC</name>
              <bitOffset>0</bitOffset>
              <bitWidth>16</bitWidth>
            </field>
          </fields>
        </register>
      </registers>
    </peripheral>
    <peripheral>
      <name>SPI3</name>
      <baseAddress>0x40003c00</baseAddress>
      <registers>
        <register>
          <name>CR1</name>
          <addressOffset>0x0</addressOffset>
          <size>0x20</size>
          <fields>
            <field>
              <name>CPHA</name>
              <bitOffset>0</bitOffset>
              <bitWidth>1</bitWidth>
            </field>
            <field>
              <name>CPOL</name>
              <bitOffset>1</bitOffset>
              <bitWidth>1</bitWidth>
            </field>
            <field>
              <name>MSTR</name>
              <bitOffset>2</bitOffset>
              <bitWidth>1</bitWidth>
            </field>
            <field>
              <name>BR</name>
              <bitOffset>3</bitOffset>
              <bitWidth>3</bitWidth>
            </field>
            <field>
              <name>SPE</name>
              <bitOffset>6</bitOffset>
              <bitWidth>1</bitWidth>
            </field>
            <field>
              <name>LSBFIRST</name>
              <bitOffset>7</bitOffset>
              <bitWidth>1</bitWidth>
            </field>
            <field>
              <name>SSI</name>
              <bitOffset>8</bitOffset>
              <bitWidth>1</bitWidth>
            </field>
            <field>
              <name>SSM</name>
              <bitOffset>9</bitOffset>
              <bitWidth>1</bitWidth>
            </field>
            <field>
              <name>RXONLY</name>
              <bitOffset>10</bitOffset>
              <bitWidth>1</bitWidth>
            </field>
            <field>
              <name>CRCL</name>
              <bitOffset>11</bitOffset>
              <bitWidth>1</bitWidth>
            </field>
            <field>
              <name>CRCNEXT</name>
              <bitOffset>12</bitOffset>
              <bitWidth>1</bitWidth>
            </field>
            <field>
              <name>CRCEN</name>
              <bitOffset>13</bitOffset>
              <bitWidth>1</bitWidth>
            </field>
            <field>
              <name>BIDIOE</name>
              <bitOffset>14</bitOffset>
              <bitWidth>1</bitWidth>
            </field>
            <field>
              <name>BIDIMODE</name>
              <bitOffset>15</bitOffset>
              <bitWidth>1</bitWidth>
            </field>
          </fields>
        </register>
        <register>
          <name>CR2</name>
          <addressOffset>0x4</addressOffset>
          <size>0x20</size>
          <fields>
            <field>
              <name>RXDMAEN</name>
              <bitOffset>0</bitOffset>
              <bitWidth>1</bitWidth>
            </field>
            <field>
              <name>TXDMAEN</name>
              <bitOffset>1</bitOffset>
              <bitWidth>1</bitWidth>
            </field>
            <field>
              <name>SSOE</name>
              <bitOffset>2</bitOffset>
              <bitWidth>1</bitWidth>
            </field>
            <field>
              <name>NSSP</name>
              <bitOffset>3</bitOffset>
              <bitWidth>1</bitWidth>
            </field>
            <field>
              <name>FRF</name>
              <bitOffset>4</bitOffset>
              <bitWidth>1</bitWidth>
            </field>
            <field>
              <name>ERRIE</name>
              <bitOffset>5</bitOffset>
              <bitWidth>1</bitWidth>
            </field>
            <field>
              <name>RXNEIE</name>
              <bitOffset>6</bitOffset>
              <bitWidth>1</bitWidth>
            </field>
            <field>
              <name>TXEIE</name>
              <bitOffset>7</bitOffset>
              <bitWidth>1</bitWidth>
            </field>
            <field>
              <name>DS</name>
              <bitOffset>8</bitOffset>
              <bitWidth>4</bitWidth>
            </field>
            <field>
              <name>FRXTH</name>
              <bitOffset>12</bitOffset>
              <bitWidth>1</bitWidth>
            </field>
            <field>
              <name>LDMARX</name>
              <bitOffset>13</bitOffset>
              <bitWidth>1</bitWidth>
            </field>
            <field>
              <name>LDMATX</name>
              <bitOffset>14</bitOffset>
              <bitWidth>1</bitWidth>
            </field>
          </fields>
        </register>
        <register>
          <name>SR</name>
          <addressOffset>0x8</addressOffset>
          <size>0x20</size>
          <fields>
            <field>
              <name>RXNE</name>
              <bitOffset>0</bitOffset>
              <bitWidth>1</bitWidth>
            </field>
            <field>
              <name>TXE</name>
              <bitOffset>1</bitOffset>
              <bitWidth>1</bitWidth>
            </field>
            <field>
              <name>CHSIDE</name>
              <bitOffset>2</bitOffset>
              <bitWidth>1</bitWidth>
            </field>
            <field>
              <name>UDR</name>
              <bitOffset>3</bitOffset>
              <bitWidth>1</bitWidth>
            </field>
            <field>
              <name>CRCERR</name>
              <bitOffset>4</bitOffset>
              <bitWidth>1</bitWidth>
            </field>
            <field>
              <name>MODF</name>
              <bitOffset>5</bitOffset>
              <bitWidth>1</bitWidth>
            </field>
            <field>
              <name>OVR</name>
              <bitOffset>6</bitOffset>
              <bitWidth>1</bitWidth>
            </field>
            <field>
              <name>BSY</name>
              <bitOffset>7</bitOffset>
              <bitWidth>1</bitWidth>
            </field>
            <field>
              <name>FRE</name>
              <bitOffset>8</bitOffset>
              <bitWidth>1</bitWidth>
            </field>
            <field>
              <name>FRLVL</name>
              <bitOffset>9</bitOffset>
              <bitWidth>2</bitWidth>
            </field>
            <field>
              <name>FTLVL</name>
              <bitOffset>11</bitOffset>
              <bitWidth>2</bitWidth>
            </field>
          </fields>
        </register>
        <register>
          <name>DR</name>
          <addressOffset>0xc</addressOffset>
          <size>0x20</size>
          <fields>
            <field>
              <name>DR</name>
              <bitOffset>0</bitOffset>
              <bitWidth>16</bitWidth>
            </field>
          </fields>
        </register>
        <register>
          <name>CRCPR</name>
          <addressOffset>0x10</addressOffset>
          <size>0x20</size>
          <fields>
            <field>
              <name>CRCPOLY</name>
              <bitOffset>0</bitOffset>
              <bitWidth>16</bitWidth>
            </field>
          </fields>
        </register>
        <register>
          <name>RXCRCR</name>
          <addressOffset>0x14</addressOffset>
          <size>0x20</size>
          <fields>
            <field>
              <name>RXCRC</name>
              <bitOffset>0</bitOffset>
              <bitWidth>16</bitWidth>
            </field>
          </fields>
        </register>
        <register>
          <name>TXCRCR</name>
          <addressOffset>0x18</addressOffset>
          <size>0x20</size>
          <fields>
            <field>
              <name>TXCRC</name>
              <bitOffset>0</bitOffset>
              <bitWidth>16</bitWidth>
            </field>
          </fields>
        </register>
      </registers>
    </peripheral>
    <peripheral>
      <name>USART2</name>
      <baseAddress>0x40004400</baseAddress>
      <registers>
        <register>
          <name>CR1</name>
          <addressOffset>0x0</addressOffset>
          <size>0x20</size>
          <fields>
            <field>
              <name>UE</name>
              <bitOffset>0</bitOffset>
              <bitWidth>1</bitWidth>
            </field>
            <field>
              <name>UESM</name>
              <bitOffset>1</bitOffset>
              <bitWidth>1</bitWidth>
            </field>
            <field>
              <name>RE</name>
              <bitOffset>2</bitOffset>
              <bitWidth>1</bitWidth>
            </field>
            <field>
              <name>TE</name>
              <bitOffset>3</bitOffset>
              <bitWidth>1</bitWidth>
            </field>
            <field>
              <name>IDLEIE</name>
              <bitOffset>4</bitOffset>
              <bitWidth>1</bitWidth>
            </field>
            <field>
              <name>RXNEIE</name>
              <bitOffset>5</bitOffset>
              <bitWidth>1</bitWidth>
            </field>
            <field>
              <name>TCIE</name>
              <bitOffset>6</bitOffset>
              <bitWidth>1</bitWidth>
            </field>
            <field>
              <name>TXEIE</name>
              <bitOffset>7</bitOffset>
              <bitWidth>1</bitWidth>
            </field>
            <field>
              <name>PEIE</name>
              <bitOffset>8</bitOffset>
              <bitWidth>1</bitWidth>
            </field>
            <field>
              <name>PS</name>
              <bitOffset>9</bitOffset>
              <bitWidth>1</bitWidth>
            </field>
            <field>
              <name>PCE</name>
              <bitOffset>10</bitOffset>
              <bitWidth>1</bitWidth>
            </field>
            <field>
              <name>WAKE</name>
              <bitOffset>11</bitOffset>
              <bitWidth>1</bitWidth>
            </field>
            <field>
              <name>M0</name>
              <bitOffset>12</bitOffset>
              <bitWidth>1</bitWidth>
            </field>
            <field>
              <name>MME</name>
              <bitOffset>13</bitOffset>
              <bitWidth>1</bitWidth>
            </field>
            <field>
              <name>CMIE</name>
              <bitOffset>14</bitOffset>
              <bitWidth>1</bitWidth>
            </field>
            <field>
              <name>OVER8</name>
              <bitOffset>15</bitOffset>
              <bitWidth>1</bitWidth>
            </field>
            <field>
              <name>DEDT</name>
              <bitOffset>16</bitOffset>
              <bitWidth>5</bitWidth>
            </field>
            <field>
              <name>DEAT</name>
              <bitOffset>21</bitOffset>
              <bitWidth>5</bitWidth>
            </field>
            <field>
              <name>RTOIE</name>
              <bitOffset>26</bitOffset>
              <bitWidth>1</bitWidth>
            </field>
            <field>
              <name>EOBIE</name>
              <bitOffset>27</bitOffset>
              <bitWidth>1</bitWidth>
            </field>
            <field>
              <name>M1</name>
              <bitOffset>28</bitOffset>
              <bitWidth>1</bitWidth>
            </field>
          </fields>
        </register>
        <register>
          <name>CR2</name>
          <addressOffset>0x4</addressOffset>
          <size>0x20</size>
          <fields>
            <field>
              <name>ADDM7</name>
              <bitOffset>4</bitOffset>
              <bitWidth>1</bitWidth>
            </field>
            <field>
              <name>LBDL</name>
              <bitOffset>5</bitOffset>
              <bitWidth>1</bitWidth>
            </field>
            <field>
              <name>LBDIE</name>
              <bitOffset>6</bitOffset>
              <bitWidth>1</bitWidth>
            </field>
            <field>
              <name>LBCL</name>
              <bitOffset>8</bitOffset>
              <bitWidth>1</bitWidth>
            </field>
            <field>
              <name>CPHA</name>
              <bitOffset>9</bitOffset>
              <bitWidth>1</bitWidth>
            </field>
            <field>
              <name>CPOL</name>
              <bitOffset>10</bitOffset>
              <bitWidth>1</bitWidth>
            </field>
            <field>
              <name>CLKEN</name>
              <bitOffset>11</bitOffset>
              <bitWidth>1</bitWidth>
            </field>
            <field>
              <name>STOP</name>
              <bitOffset>12</bitOffset>
              <bitWidth>2</bitWidth>
            </field>
            <field>
              <name>LINEN</name>
              <bitOffset>14</bitOffset>
              <bitWidth>1</bitWidth>
            </field>
            <field>
              <name>SWAP</name>
              <bitOffset>15</bitOffset>
              <bitWidth>1</bitWidth>
            </field>
            <field>
              <name>RXINV</name>
              <bitOffset>16</bitOffset>
              <bitWidth>1</bitWidth>
            </field>
            <field>
              <name>TXINV</name>
              <bitOffset>17</bitOffset>
              <bitWidth>1</bitWidth>
            </field>
            <field>
              <name>DATAINV</name>
              <bitOffset>18</bitOffset>
              <bitWidth>1</bitWidth>
            </field>
            <field>
              <name>MSBFIRST</name>
              <bitOffset>19</bitOffset>
              <bitWidth>1</bitWidth>
            </field>
            <field>
              <name>ABREN</name>
              <bitOffset>20</bitOffset>
              <bitWidth>1</bitWidth>
            </field>
            <field>
              <name>ABRMODE</name>
              <bitOffset>21</bitOffset>
              <bitWidth>2</bitWidth>
            </field>
            <field>
              <name>RTOEN</name>
              <bitOffset>23</bitOffset>
              <bitWidth>1</bitWidth>
            </field>
            <field>
              <name>ADD</name>
              <bitOffset>24</bitOffset>
              <bitWidth>8</bitWidth>
            </field>
          </fields>
        </register>
        <register>
          <name>CR3</name>
          <addressOffset>0x8</addressOffset>
          <size>0x20</size>
          <fields>
            <field>
              <name>EIE</name>
              <bitOffset>0</bitOffset>
              <bitWidth>1</bitWidth>
            </field>
            <field>
              <name>IREN</name>
              <bitOffset>1</bitOffset>
              <bitWidth>1</bitWidth>
            </field>
            <field>
              <name>IRLP</name>
              <bitOffset>2</bitOffset>
              <bitWidth>1</bitWidth>
            </field>
            <field>
              <name>HDSEL</name>
              <bitOffset>3</bitOffset>
              <bitWidth>1</bitWidth>
            </field>
            <field>
              <name>NACK</name>
              <bitOffset>4</bitOffset>
              <bitWidth>1</bitWidth>
            </field>
            <field>
              <name>SCEN</name>
              <bitOffset>5</bitOffset>
              <bitWidth>1</bitWidth>
            </field>
            <field>
              <name>DMAR</name>
              <bitOffset>6</bitOffset>
              <bitWidth>1</bitWidth>
            </field>
            <field>
              <name>DMAT</name>
              <bitOffset>7</bitOffset>
              <bitWidth>1</bitWidth>
            </field>
            <field>
              <name>RTSE</name>
              <bitOffset>8</bitOffset>
              <bitWidth>1</bitWidth>
            </field>
            <field>
              <name>CTSE</name>
              <bitOffset>9</bitOffset>
              <bitWidth>1</bitWidth>
            </field>
            <field>
              <name>CTSIE</name>
              <bitOffset>10</bitOffset>
              <bitWidth>1</bitWidth>
            </field>
            <field>
              <name>ONEBIT</name>
              <bitOffset>11</bitOffset>
              <bitWidth>1</bitWidth>
            </field>
            <field>
              <name>OVRDIS</name>
              <bitOffset>12</bitOffset>
              <bitWidth>1</bitWidth>
            </field>
            <field>
              <name>DDRE</name>
              <bitOffset>13</bitOffset>
              <bitWidth>1</bitWidth>
            </field>
            <field>
              <name>DEM</name>
              <bitOffset>14</bitOffset>
              <bitWidth>1</bitWidth>
            </field>
            <field>
              <name>DEP</name>
              <bitOffset>15</bitOffset>
              <bitWidth>1</bitWidth>
            </field>
            <field>
              <name>SCARCNT</name>
              <bitOffset>17</bitOffset>
              <bitWidth>3</bitWidth>
            </field>
            <field>
              <name>WUS</name>
              <bitOffset>20</bitOffset>
              <bitWidth>2</bitWidth>
            </field>
            <field>
              <name>WUFIE</name>
              <bitOffset>22</bitOffset>
              <bitWidth>1</bitWidth>
            </field>
            <field>
              <name>UCESM</name>
              <bitOffset>23</bitOffset>
              <bitWidth>1</bitWidth>
            </field>
            <field>
              <name>TCBGTIE</name>
              <bitOffset>24</bitOffset>
              <bitWidth>1</bitWidth>
            </field>
          </fields>
        </register>
        <register>
          <name>BRR</name>
          <addressOffset>0xc</addressOffset>
          <size>0x20</size>
          <fields>
            <field>
              <name>DIV_FRACTION</name>
              <bitOffset>0</bitOffset>
              <bitWidth>4</bitWidth>
            </field>
            <field>
              <name>DIV_MANTISSA</name>
              <bitOffset>4</bitOffset>
              <bitWidth>12</bitWidth>
            </field>
          </fields>
        </register>
        <register>
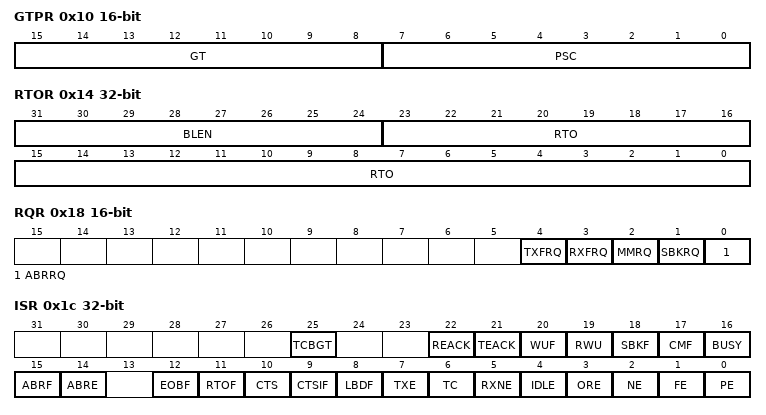
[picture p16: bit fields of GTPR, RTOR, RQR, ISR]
          <name>GTPR</name>
          <addressOffset>0x10</addressOffset>
          <size>0x10</size>
          <fields>
            <field>
              <name>PSC</name>
              <bitOffset>0</bitOffset>
              <bitWidth>8</bitWidth>
            </field>
            <field>
              <name>GT</name>
              <bitOffset>8</bitOffset>
              <bitWidth>8</bitWidth>
            </field>
          </fields>
        </register>
        <register>
          <name>RTOR</name>
          <addressOffset>0x14</addressOffset>
          <size>0x20</size>
          <fields>
            <field>
              <name>RTO</name>
              <bitOffset>0</bitOffset>
              <bitWidth>24</bitWidth>
            </field>
            <field>
              <name>BLEN</name>
              <bitOffset>24</bitOffset>
              <bitWidth>8</bitWidth>
            </field>
          </fields>
        </register>
        <register>
          <name>RQR</name>
          <addressOffset>0x18</addressOffset>
          <size>0x10</size>
          <fields>
            <field>
              <name>ABRRQ</name>
              <bitOffset>0</bitOffset>
              <bitWidth>1</bitWidth>
            </field>
            <field>
              <name>SBKRQ</name>
              <bitOffset>1</bitOffset>
              <bitWidth>1</bitWidth>
            </field>
            <field>
              <name>MMRQ</name>
              <bitOffset>2</bitOffset>
              <bitWidth>1</bitWidth>
            </field>
            <field>
              <name>RXFRQ</name>
              <bitOffset>3</bitOffset>
              <bitWidth>1</bitWidth>
            </field>
            <field>
              <name>TXFRQ</name>
              <bitOffset>4</bitOffset>
              <bitWidth>1</bitWidth>
            </field>
          </fields>
        </register>
        <register>
          <name>ISR</name>
          <addressOffset>0x1c</addressOffset>
          <size>0x20</size>
          <fields>
            <field>
              <name>PE</name>
              <bitOffset>0</bitOffset>
              <bitWidth>1</bitWidth>
            </field>
            <field>
              <name>FE</name>
              <bitOffset>1</bitOffset>
              <bitWidth>1</bitWidth>
            </field>
            <field>
              <name>NE</name>
              <bitOffset>2</bitOffset>
              <bitWidth>1</bitWidth>
            </field>
            <field>
              <name>ORE</name>
              <bitOffset>3</bitOffset>
              <bitWidth>1</bitWidth>
            </field>
            <field>
              <name>IDLE</name>
              <bitOffset>4</bitOffset>
              <bitWidth>1</bitWidth>
            </field>
            <field>
              <name>RXNE</name>
              <bitOffset>5</bitOffset>
              <bitWidth>1</bitWidth>
            </field>
            <field>
              <name>TC</name>
              <bitOffset>6</bitOffset>
              <bitWidth>1</bitWidth>
            </field>
            <field>
              <name>TXE</name>
              <bitOffset>7</bitOffset>
              <bitWidth>1</bitWidth>
            </field>
            <field>
              <name>LBDF</name>
              <bitOffset>8</bitOffset>
              <bitWidth>1</bitWidth>
            </field>
            <field>
              <name>CTSIF</name>
              <bitOffset>9</bitOffset>
              <bitWidth>1</bitWidth>
            </field>
            <field>
              <name>CTS</name>
              <bitOffset>10</bitOffset>
              <bitWidth>1</bitWidth>
            </field>
            <field>
              <name>RTOF</name>
              <bitOffset>11</bitOffset>
              <bitWidth>1</bitWidth>
            </field>
            <field>
              <name>EOBF</name>
              <bitOffset>12</bitOffset>
              <bitWidth>1</bitWidth>
            </field>
            <field>
              <name>ABRE</name>
              <bitOffset>14</bitOffset>
              <bitWidth>1</bitWidth>
            </field>
            <field>
              <name>ABRF</name>
              <bitOffset>15</bitOffset>
              <bitWidth>1</bitWidth>
            </field>
            <field>
              <name>BUSY</name>
              <bitOffset>16</bitOffset>
              <bitWidth>1</bitWidth>
            </field>
            <field>
              <name>CMF</name>
              <bitOffset>17</bitOffset>
              <bitWidth>1</bitWidth>
            </field>
            <field>
              <name>SBKF</name>
              <bitOffset>18</bitOffset>
              <bitWidth>1</bitWidth>
            </field>
            <field>
              <name>RWU</name>
              <bitOffset>19</bitOffset>
              <bitWidth>1</bitWidth>
            </field>
            <field>
              <name>WUF</name>
              <bitOffset>20</bitOffset>
              <bitWidth>1</bitWidth>
            </field>
            <field>
              <name>TEACK</name>
              <bitOffset>21</bitOffset>
              <bitWidth>1</bitWidth>
            </field>
            <field>
              <name>REACK</name>
              <bitOffset>22</bitOffset>
              <bitWidth>1</bitWidth>
            </field>
            <field>
              <name>TCBGT</name>
              <bitOffset>25</bitOffset>
              <bitWidth>1</bitWidth>
            </field>
          </fields>
        </register>
        <register>
          <name>ICR</name>
          <addressOffset>0x20</addressOffset>
          <size>0x20</size>
          <fields>
            <field>
              <name>PECF</name>
              <bitOffset>0</bitOffset>
              <bitWidth>1</bitWidth>
            </field>
            <field>
              <name>FECF</name>
              <bitOffset>1</bitOffset>
              <bitWidth>1</bitWidth>
            </field>
            <field>
              <name>NECF</name>
              <bitOffset>2</bitOffset>
              <bitWidth>1</bitWidth>
            </field>
            <field>
              <name>ORECF</name>
              <bitOffset>3</bitOffset>
              <bitWidth>1</bitWidth>
            </field>
            <field>
              <name>IDLECF</name>
              <bitOffset>4</bitOffset>
              <bitWidth>1</bitWidth>
            </field>
            <field>
              <name>TCCF</name>
              <bitOffset>6</bitOffset>
              <bitWidth>1</bitWidth>
            </field>
            <field>
              <name>TCBGTCF</name>
              <bitOffset>7</bitOffset>
              <bitWidth>1</bitWidth>
            </field>
            <field>
              <name>LBDCF</name>
              <bitOffset>8</bitOffset>
              <bitWidth>1</bitWidth>
            </field>
            <field>
              <name>CTSCF</name>
              <bitOffset>9</bitOffset>
              <bitWidth>1</bitWidth>
            </field>
            <field>
              <name>RTOCF</name>
              <bitOffset>11</bitOffset>
              <bitWidth>1</bitWidth>
            </field>
            <field>
              <name>EOBCF</name>
              <bitOffset>12</bitOffset>
              <bitWidth>1</bitWidth>
            </field>
            <field>
              <name>CMCF</name>
              <bitOffset>17</bitOffset>
              <bitWidth>1</bitWidth>
            </field>
            <field>
              <name>WUCF</name>
              <bitOffset>20</bitOffset>
              <bitWidth>1</bitWidth>
            </field>
          </fields>
        </register>
        <register>
          <name>RDR</name>
          <addressOffset>0x24</addressOffset>
          <size>0x10</size>
          <fields>
            <field>
              <name>RDR</name>
              <bitOffset>0</bitOffset>
              <bitWidth>9</bitWidth>
            </field>
          </fields>
        </register>
        <register>
          <name>TDR</name>
          <addressOffset>0x28</addressOffset>
          <size>0x10</size>
          <fields>
            <field>
              <name>TDR</name>
              <bitOffset>0</bitOffset>
              <bitWidth>9</bitWidth>
            </field>
          </fields>
        </register>
      </registers>
    </peripheral>
    <peripheral>
      <name>USART3</name>
      <baseAddress>0x40004800</baseAddress>
      <registers>
        <register>
          <name>CR1</name>
          <addressOffset>0x0</addressOffset>
          <size>0x20</size>
          <fields>
            <field>
              <name>UE</name>
              <bitOffset>0</bitOffset>
              <bitWidth>1</bitWidth>
            </field>
            <field>
              <name>UESM</name>
              <bitOffset>1</bitOffset>
              <bitWidth>1</bitWidth>
            </field>
            <field>
              <name>RE</name>
              <bitOffset>2</bitOffset>
              <bitWidth>1</bitWidth>
            </field>
            <field>
              <name>TE</name>
              <bitOffset>3</bitOffset>
              <bitWidth>1</bitWidth>
            </field>
            <field>
              <name>IDLEIE</name>
              <bitOffset>4</bitOffset>
              <bitWidth>1</bitWidth>
            </field>
            <field>
              <name>RXNEIE</name>
              <bitOffset>5</bitOffset>
              <bitWidth>1</bitWidth>
            </field>
            <field>
              <name>TCIE</name>
              <bitOffset>6</bitOffset>
              <bitWidth>1</bitWidth>
            </field>
            <field>
              <name>TXEIE</name>
              <bitOffset>7</bitOffset>
              <bitWidth>1</bitWidth>
            </field>
            <field>
              <name>PEIE</name>
              <bitOffset>8</bitOffset>
              <bitWidth>1</bitWidth>
            </field>
            <field>
              <name>PS</name>
              <bitOffset>9</bitOffset>
              <bitWidth>1</bitWidth>
            </field>
            <field>
              <name>PCE</name>
              <bitOffset>10</bitOffset>
              <bitWidth>1</bitWidth>
            </field>
            <field>
              <name>WAKE</name>
              <bitOffset>11</bitOffset>
              <bitWidth>1</bitWidth>
            </field>
            <field>
              <name>M0</name>
              <bitOffset>12</bitOffset>
              <bitWidth>1</bitWidth>
            </field>
            <field>
              <name>MME</name>
              <bitOffset>13</bitOffset>
              <bitWidth>1</bitWidth>
            </field>
            <field>
              <name>CMIE</name>
              <bitOffset>14</bitOffset>
              <bitWidth>1</bitWidth>
            </field>
            <field>
              <name>OVER8</name>
              <bitOffset>15</bitOffset>
              <bitWidth>1</bitWidth>
            </field>
            <field>
              <name>DEDT</name>
              <bitOffset>16</bitOffset>
              <bitWidth>5</bitWidth>
            </field>
            <field>
              <name>DEAT</name>
              <bitOffset>21</bitOffset>
              <bitWidth>5</bitWidth>
            </field>
            <field>
              <name>RTOIE</name>
              <bitOffset>26</bitOffset>
              <bitWidth>1</bitWidth>
            </field>
            <field>
              <name>EOBIE</name>
              <bitOffset>27</bitOffset>
              <bitWidth>1</bitWidth>
            </field>
            <field>
              <name>M1</name>
              <bitOffset>28</bitOffset>
              <bitWidth>1</bitWidth>
            </field>
          </fields>
        </register>
        <register>
          <name>CR2</name>
          <addressOffset>0x4</addressOffset>
          <size>0x20</size>
          <fields>
            <field>
              <name>ADDM7</name>
              <bitOffset>4</bitOffset>
              <bitWidth>1</bitWidth>
            </field>
            <field>
              <name>LBDL</name>
              <bitOffset>5</bitOffset>
              <bitWidth>1</bitWidth>
            </field>
            <field>
              <name>LBDIE</name>
              <bitOffset>6</bitOffset>
              <bitWidth>1</bitWidth>
            </field>
            <field>
              <name>LBCL</name>
              <bitOffset>8</bitOffset>
              <bitWidth>1</bitWidth>
            </field>
            <field>
              <name>CPHA</name>
              <bitOffset>9</bitOffset>
              <bitWidth>1</bitWidth>
            </field>
            <field>
              <name>CPOL</name>
              <bitOffset>10</bitOffset>
              <bitWidth>1</bitWidth>
            </field>
            <field>
              <name>CLKEN</name>
              <bitOffset>11</bitOffset>
              <bitWidth>1</bitWidth>
            </field>
            <field>
              <name>STOP</name>
              <bitOffset>12</bitOffset>
              <bitWidth>2</bitWidth>
            </field>
            <field>
              <name>LINEN</name>
              <bitOffset>14</bitOffset>
              <bitWidth>1</bitWidth>
            </field>
            <field>
              <name>SWAP</name>
              <bitOffset>15</bitOffset>
              <bitWidth>1</bitWidth>
            </field>
            <field>
              <name>RXINV</name>
              <bitOffset>16</bitOffset>
              <bitWidth>1</bitWidth>
            </field>
            <field>
              <name>TXINV</name>
              <bitOffset>17</bitOffset>
              <bitWidth>1</bitWidth>
            </field>
            <field>
              <name>DATAINV</name>
              <bitOffset>18</bitOffset>
              <bitWidth>1</bitWidth>
            </field>
            <field>
              <name>MSBFIRST</name>
              <bitOffset>19</bitOffset>
              <bitWidth>1</bitWidth>
            </field>
            <field>
              <name>ABREN</name>
              <bitOffset>20</bitOffset>
              <bitWidth>1</bitWidth>
            </field>
            <field>
              <name>ABRMODE</name>
              <bitOffset>21</bitOffset>
              <bitWidth>2</bitWidth>
            </field>
            <field>
              <name>RTOEN</name>
              <bitOffset>23</bitOffset>
              <bitWidth>1</bitWidth>
            </field>
            <field>
              <name>ADD</name>
              <bitOffset>24</bitOffset>
              <bitWidth>8</bitWidth>
            </field>
          </fields>
        </register>
        <register>
          <name>CR3</name>
          <addressOffset>0x8</addressOffset>
          <size>0x20</size>
          <fields>
            <field>
              <name>EIE</name>
              <bitOffset>0</bitOffset>
              <bitWidth>1</bitWidth>
            </field>
            <field>
              <name>IREN</name>
              <bitOffset>1</bitOffset>
              <bitWidth>1</bitWidth>
            </field>
            <field>
              <name>IRLP</name>
              <bitOffset>2</bitOffset>
              <bitWidth>1</bitWidth>
            </field>
            <field>
              <name>HDSEL</name>
              <bitOffset>3</bitOffset>
              <bitWidth>1</bitWidth>
            </field>
            <field>
              <name>NACK</name>
              <bitOffset>4</bitOffset>
              <bitWidth>1</bitWidth>
            </field>
            <field>
              <name>SCEN</name>
              <bitOffset>5</bitOffset>
              <bitWidth>1</bitWidth>
            </field>
            <field>
              <name>DMAR</name>
              <bitOffset>6</bitOffset>
              <bitWidth>1</bitWidth>
            </field>
            <field>
              <name>DMAT</name>
              <bitOffset>7</bitOffset>
              <bitWidth>1</bitWidth>
            </field>
            <field>
              <name>RTSE</name>
              <bitOffset>8</bitOffset>
              <bitWidth>1</bitWidth>
            </field>
            <field>
              <name>CTSE</name>
              <bitOffset>9</bitOffset>
              <bitWidth>1</bitWidth>
            </field>
            <field>
              <name>CTSIE</name>
              <bitOffset>10</bitOffset>
              <bitWidth>1</bitWidth>
            </field>
            <field>
              <name>ONEBIT</name>
              <bitOffset>11</bitOffset>
              <bitWidth>1</bitWidth>
            </field>
            <field>
              <name>OVRDIS</name>
              <bitOffset>12</bitOffset>
              <bitWidth>1</bitWidth>
            </field>
            <field>
              <name>DDRE</name>
              <bitOffset>13</bitOffset>
              <bitWidth>1</bitWidth>
            </field>
            <field>
              <name>DEM</name>
              <bitOffset>14</bitOffset>
              <bitWidth>1</bitWidth>
            </field>
            <field>
              <name>DEP</name>
              <bitOffset>15</bitOffset>
              <bitWidth>1</bitWidth>
            </field>
            <field>
              <name>SCARCNT</name>
              <bitOffset>17</bitOffset>
              <bitWidth>3</bitWidth>
            </field>
            <field>
              <name>WUS</name>
              <bitOffset>20</bitOffset>
              <bitWidth>2</bitWidth>
            </field>
            <field>
              <name>WUFIE</name>
              <bitOffset>22</bitOffset>
              <bitWidth>1</bitWidth>
            </field>
            <field>
              <name>UCESM</name>
              <bitOffset>23</bitOffset>
              <bitWidth>1</bitWidth>
            </field>
            <field>
              <name>TCBGTIE</name>
              <bitOffset>24</bitOffset>
              <bitWidth>1</bitWidth>
            </field>
          </fields>
        </register>
        <register>
          <name>BRR</name>
          <addressOffset>0xc</addressOffset>
          <size>0x20</size>
          <fields>
            <field>
              <name>DIV_FRACTION</name>
              <bitOffset>0</bitOffset>
              <bitWidth>4</bitWidth>
            </field>
            <field>
              <name>DIV_MANTISSA</name>
              <bitOffset>4</bitOffset>
              <bitWidth>12</bitWidth>
            </field>
          </fields>
        </register>
        <register>
          <name>GTPR</name>
          <addressOffset>0x10</addressOffset>
          <size>0x10</size>
          <fields>
            <field>
              <name>PSC</name>
              <bitOffset>0</bitOffset>
              <bitWidth>8</bitWidth>
            </field>
            <field>
              <name>GT</name>
              <bitOffset>8</bitOffset>
              <bitWidth>8</bitWidth>
            </field>
          </fields>
        </register>
        <register>
          <name>RTOR</name>
          <addressOffset>0x14</addressOffset>
          <size>0x20</size>
          <fields>
            <field>
              <name>RTO</name>
              <bitOffset>0</bitOffset>
              <bitWidth>24</bitWidth>
            </field>
            <field>
              <name>BLEN</name>
              <bitOffset>24</bitOffset>
              <bitWidth>8</bitWidth>
            </field>
          </fields>
        </register>
        <register>
          <name>RQR</name>
          <addressOffset>0x18</addressOffset>
          <size>0x10</size>
          <fields>
            <field>
              <name>ABRRQ</name>
              <bitOffset>0</bitOffset>
              <bitWidth>1</bitWidth>
            </field>
            <field>
              <name>SBKRQ</name>
              <bitOffset>1</bitOffset>
              <bitWidth>1</bitWidth>
            </field>
            <field>
              <name>MMRQ</name>
              <bitOffset>2</bitOffset>
              <bitWidth>1</bitWidth>
            </field>
            <field>
              <name>RXFRQ</name>
              <bitOffset>3</bitOffset>
              <bitWidth>1</bitWidth>
            </field>
            <field>
              <name>TXFRQ</name>
              <bitOffset>4</bitOffset>
              <bitWidth>1</bitWidth>
            </field>
          </fields>
        </register>
        <register>
          <name>ISR</name>
          <addressOffset>0x1c</addressOffset>
          <size>0x20</size>
          <fields>
            <field>
              <name>PE</name>
              <bitOffset>0</bitOffset>
              <bitWidth>1</bitWidth>
            </field>
            <field>
              <name>FE</name>
              <bitOffset>1</bitOffset>
              <bitWidth>1</bitWidth>
            </field>
            <field>
              <name>NE</name>
              <bitOffset>2</bitOffset>
              <bitWidth>1</bitWidth>
            </field>
            <field>
              <name>ORE</name>
              <bitOffset>3</bitOffset>
              <bitWidth>1</bitWidth>
            </field>
            <field>
              <name>IDLE</name>
              <bitOffset>4</bitOffset>
              <bitWidth>1</bitWidth>
            </field>
            <field>
              <name>RXNE</name>
              <bitOffset>5</bitOffset>
              <bitWidth>1</bitWidth>
            </field>
            <field>
              <name>TC</name>
              <bitOffset>6</bitOffset>
              <bitWidth>1</bitWidth>
            </field>
            <field>
              <name>TXE</name>
              <bitOffset>7</bitOffset>
              <bitWidth>1</bitWidth>
            </field>
            <field>
              <name>LBDF</name>
              <bitOffset>8</bitOffset>
              <bitWidth>1</bitWidth>
            </field>
            <field>
              <name>CTSIF</name>
              <bitOffset>9</bitOffset>
              <bitWidth>1</bitWidth>
            </field>
            <field>
              <name>CTS</name>
              <bitOffset>10</bitOffset>
              <bitWidth>1</bitWidth>
            </field>
            <field>
              <name>RTOF</name>
              <bitOffset>11</bitOffset>
              <bitWidth>1</bitWidth>
            </field>
            <field>
              <name>EOBF</name>
              <bitOffset>12</bitOffset>
              <bitWidth>1</bitWidth>
            </field>
            <field>
              <name>ABRE</name>
              <bitOffset>14</bitOffset>
              <bitWidth>1</bitWidth>
            </field>
            <field>
              <name>ABRF</name>
              <bitOffset>15</bitOffset>
              <bitWidth>1</bitWidth>
            </field>
            <field>
              <name>BUSY</name>
              <bitOffset>16</bitOffset>
              <bitWidth>1</bitWidth>
            </field>
            <field>
              <name>CMF</name>
              <bitOffset>17</bitOffset>
              <bitWidth>1</bitWidth>
            </field>
            <field>
              <name>SBKF</name>
              <bitOffset>18</bitOffset>
              <bitWidth>1</bitWidth>
            </field>
            <field>
              <name>RWU</name>
              <bitOffset>19</bitOffset>
              <bitWidth>1</bitWidth>
            </field>
            <field>
              <name>WUF</name>
              <bitOffset>20</bitOffset>
              <bitWidth>1</bitWidth>
            </field>
            <field>
              <name>TEACK</name>
              <bitOffset>21</bitOffset>
              <bitWidth>1</bitWidth>
            </field>
            <field>
              <name>REACK</name>
              <bitOffset>22</bitOffset>
              <bitWidth>1</bitWidth>
            </field>
            <field>
              <name>TCBGT</name>
              <bitOffset>25</bitOffset>
              <bitWidth>1</bitWidth>
            </field>
          </fields>
        </register>
        <register>
          <name>ICR</name>
          <addressOffset>0x20</addressOffset>
          <size>0x20</size>
          <fields>
            <field>
              <name>PECF</name>
              <bitOffset>0</bitOffset>
              <bitWidth>1</bitWidth>
            </field>
            <field>
              <name>FECF</name>
              <bitOffset>1</bitOffset>
              <bitWidth>1</bitWidth>
            </field>
            <field>
              <name>NECF</name>
              <bitOffset>2</bitOffset>
              <bitWidth>1</bitWidth>
            </field>
            <field>
              <name>ORECF</name>
              <bitOffset>3</bitOffset>
              <bitWidth>1</bitWidth>
            </field>
            <field>
              <name>IDLECF</name>
              <bitOffset>4</bitOffset>
              <bitWidth>1</bitWidth>
            </field>
            <field>
              <name>TCCF</name>
              <bitOffset>6</bitOffset>
              <bitWidth>1</bitWidth>
            </field>
            <field>
              <name>TCBGTCF</name>
              <bitOffset>7</bitOffset>
              <bitWidth>1</bitWidth>
            </field>
            <field>
              <name>LBDCF</name>
              <bitOffset>8</bitOffset>
              <bitWidth>1</bitWidth>
            </field>
            <field>
              <name>CTSCF</name>
              <bitOffset>9</bitOffset>
              <bitWidth>1</bitWidth>
            </field>
            <field>
              <name>RTOCF</name>
              <bitOffset>11</bitOffset>
              <bitWidth>1</bitWidth>
            </field>
            <field>
              <name>EOBCF</name>
              <bitOffset>12</bitOffset>
              <bitWidth>1</bitWidth>
            </field>
            <field>
              <name>CMCF</name>
              <bitOffset>17</bitOffset>
              <bitWidth>1</bitWidth>
            </field>
            <field>
              <name>WUCF</name>
              <bitOffset>20</bitOffset>
              <bitWidth>1</bitWidth>
            </field>
          </fields>
        </register>
        <register>
          <name>RDR</name>
          <addressOffset>0x24</addressOffset>
          <size>0x10</size>
          <fields>
            <field>
              <name>RDR</name>
              <bitOffset>0</bitOffset>
              <bitWidth>9</bitWidth>
            </field>
          </fields>
        </register>
        <register>
          <name>TDR</name>
          <addressOffset>0x28</addressOffset>
          <size>0x10</size>
          <fields>
            <field>
              <name>TDR</name>
              <bitOffset>0</bitOffset>
              <bitWidth>9</bitWidth>
            </field>
          </fields>
        </register>
      </registers>
    </peripheral>
    <peripheral>
      <name>I2C1</name>
      <baseAddress>0x40005400</baseAddress>
      <registers>
        <register>
          <name>CR1</name>
          <addressOffset>0x0</addressOffset>
          <size>0x20</size>
          <fields>
            <field>
              <name>PE</name>
              <bitOffset>0</bitOffset>
              <bitWidth>1</bitWidth>
            </field>
            <field>
              <name>TXIE</name>
              <bitOffset>1</bitOffset>
              <bitWidth>1</bitWidth>
            </field>
            <field>
              <name>RXIE</name>
              <bitOffset>2</bitOffset>
              <bitWidth>1</bitWidth>
            </field>
            <field>
              <name>ADDRIE</name>
              <bitOffset>3</bitOffset>
              <bitWidth>1</bitWidth>
            </field>
            <field>
              <name>NACKIE</name>
              <bitOffset>4</bitOffset>
              <bitWidth>1</bitWidth>
            </field>
            <field>
              <name>STOPIE</name>
              <bitOffset>5</bitOffset>
              <bitWidth>1</bitWidth>
            </field>
            <field>
              <name>TCIE</name>
              <bitOffset>6</bitOffset>
              <bitWidth>1</bitWidth>
            </field>
            <field>
              <name>ERRIE</name>
              <bitOffset>7</bitOffset>
              <bitWidth>1</bitWidth>
            </field>
            <field>
              <name>DNF</name>
              <bitOffset>8</bitOffset>
              <bitWidth>4</bitWidth>
            </field>
            <field>
              <name>ANFOFF</name>
              <bitOffset>12</bitOffset>
              <bitWidth>1</bitWidth>
            </field>
            <field>
              <name>SWRST</name>
              <bitOffset>13</bitOffset>
              <bitWidth>1</bitWidth>
            </field>
            <field>
              <name>TXDMAEN</name>
              <bitOffset>14</bitOffset>
              <bitWidth>1</bitWidth>
            </field>
            <field>
              <name>RXDMAEN</name>
              <bitOffset>15</bitOffset>
              <bitWidth>1</bitWidth>
            </field>
            <field>
              <name>SBC</name>
              <bitOffset>16</bitOffset>
              <bitWidth>1</bitWidth>
            </field>
            <field>
              <name>NOSTRETCH</name>
              <bitOffset>17</bitOffset>
              <bitWidth>1</bitWidth>
            </field>
            <field>
              <name>WUPEN</name>
              <bitOffset>18</bitOffset>
              <bitWidth>1</bitWidth>
            </field>
            <field>
              <name>GCEN</name>
              <bitOffset>19</bitOffset>
              <bitWidth>1</bitWidth>
            </field>
            <field>
              <name>SMBHEN</name>
              <bitOffset>20</bitOffset>
              <bitWidth>1</bitWidth>
            </field>
            <field>
              <name>SMBDEN</name>
              <bitOffset>21</bitOffset>
              <bitWidth>1</bitWidth>
            </field>
            <field>
              <name>ALERTEN</name>
              <bitOffset>22</bitOffset>
              <bitWidth>1</bitWidth>
            </field>
            <field>
              <name>PECEN</name>
              <bitOffset>23</bitOffset>
              <bitWidth>1</bitWidth>
            </field>
          </fields>
        </register>
        <register>
          <name>CR2</name>
          <addressOffset>0x4</addressOffset>
          <size>0x20</size>
          <fields>
            <field>
              <name>SADD</name>
              <bitOffset>0</bitOffset>
              <bitWidth>10</bitWidth>
            </field>
            <field>
              <name>RD_WRN</name>
              <bitOffset>10</bitOffset>
              <bitWidth>1</bitWidth>
            </field>
            <field>
              <name>ADD10</name>
              <bitOffset>11</bitOffset>
              <bitWidth>1</bitWidth>
            </field>
            <field>
              <name>HEAD10R</name>
              <bitOffset>12</bitOffset>
              <bitWidth>1</bitWidth>
            </field>
            <field>
              <name>START</name>
              <bitOffset>13</bitOffset>
              <bitWidth>1</bitWidth>
            </field>
            <field>
              <name>STOP</name>
              <bitOffset>14</bitOffset>
              <bitWidth>1</bitWidth>
            </field>
            <field>
              <name>NACK</name>
              <bitOffset>15</bitOffset>
              <bitWidth>1</bitWidth>
            </field>
            <field>
              <name>NBYTES</name>
              <bitOffset>16</bitOffset>
              <bitWidth>8</bitWidth>
            </field>
            <field>
              <name>RELOAD</name>
              <bitOffset>24</bitOffset>
              <bitWidth>1</bitWidth>
            </field>
            <field>
              <name>AUTOEND</name>
              <bitOffset>25</bitOffset>
              <bitWidth>1</bitWidth>
            </field>
            <field>
              <name>PECBYTE</name>
              <bitOffset>26</bitOffset>
              <bitWidth>1</bitWidth>
            </field>
          </fields>
        </register>
        <register>
          <name>OAR1</name>
          <addressOffset>0x8</addressOffset>
          <size>0x20</size>
          <fields>
            <field>
              <name>OA1</name>
              <bitOffset>0</bitOffset>
              <bitWidth>10</bitWidth>
            </field>
            <field>
              <name>OA1MODE</name>
              <bitOffset>10</bitOffset>
              <bitWidth>1</bitWidth>
            </field>
            <field>
              <name>OA1EN</name>
              <bitOffset>15</bitOffset>
              <bitWidth>1</bitWidth>
            </field>
          </fields>
        </register>
        <register>
          <name>OAR2</name>
          <addressOffset>0xc</addressOffset>
          <size>0x20</size>
          <fields>
            <field>
              <name>OA2</name>
              <bitOffset>1</bitOffset>
              <bitWidth>7</bitWidth>
            </field>
            <field>
              <name>OA2MSK</name>
              <bitOffset>8</bitOffset>
              <bitWidth>3</bitWidth>
            </field>
            <field>
              <name>OA2MASK06</name>
              <bitOffset>9</bitOffset>
              <bitWidth>2</bitWidth>
            </field>
            <field>
              <name>OA2MASK04</name>
              <bitOffset>10</bitOffset>
              <bitWidth>1</bitWidth>
            </field>
            <field>
              <name>OA2EN</name>
              <bitOffset>15</bitOffset>
              <bitWidth>1</bitWidth>
            </field>
          </fields>
        </register>
        <register>
          <name>TIMINGR</name>
          <addressOffset>0x10</addressOffset>
          <size>0x20</size>
          <fields>
            <field>
              <name>SCLL</name>
              <bitOffset>0</bitOffset>
              <bitWidth>8</bitWidth>
            </field>
            <field>
              <name>SCLH</name>
              <bitOffset>8</bitOffset>
              <bitWidth>8</bitWidth>
            </field>
            <field>
              <name>SDADEL</name>
              <bitOffset>16</bitOffset>
              <bitWidth>4</bitWidth>
            </field>
            <field>
              <name>SCLDEL</name>
              <bitOffset>20</bitOffset>
              <bitWidth>4</bitWidth>
            </field>
            <field>
              <name>PRESC</name>
              <bitOffset>28</bitOffset>
              <bitWidth>4</bitWidth>
            </field>
          </fields>
        </register>
        <register>
          <name>TIMEOUTR</name>
          <addressOffset>0x14</addressOffset>
          <size>0x20</size>
          <fields>
            <field>
              <name>TIMEOUTA</name>
              <bitOffset>0</bitOffset>
              <bitWidth>12</bitWidth>
            </field>
            <field>
              <name>TIDLE</name>
              <bitOffset>12</bitOffset>
              <bitWidth>1</bitWidth>
            </field>
            <field>
              <name>TIMOUTEN</name>
              <bitOffset>15</bitOffset>
              <bitWidth>1</bitWidth>
            </field>
            <field>
              <name>TIMEOUTB</name>
              <bitOffset>16</bitOffset>
              <bitWidth>12</bitWidth>
            </field>
            <field>
              <name>TEXTEN</name>
              <bitOffset>31</bitOffset>
              <bitWidth>1</bitWidth>
            </field>
          </fields>
        </register>
        <register>
          <name>ISR</name>
          <addressOffset>0x18</addressOffset>
          <size>0x20</size>
          <fields>
            <field>
              <name>TXE</name>
              <bitOffset>0</bitOffset>
              <bitWidth>1</bitWidth>
            </field>
            <field>
              <name>TXIS</name>
              <bitOffset>1</bitOffset>
              <bitWidth>1</bitWidth>
            </field>
            <field>
              <name>RXNE</name>
              <bitOffset>2</bitOffset>
              <bitWidth>1</bitWidth>
            </field>
            <field>
              <name>ADDR</name>
              <bitOffset>3</bitOffset>
              <bitWidth>1</bitWidth>
            </field>
            <field>
              <name>NACKF</name>
              <bitOffset>4</bitOffset>
              <bitWidth>1</bitWidth>
            </field>
            <field>
              <name>STOPF</name>
              <bitOffset>5</bitOffset>
              <bitWidth>1</bitWidth>
            </field>
            <field>
              <name>TC</name>
              <bitOffset>6</bitOffset>
              <bitWidth>1</bitWidth>
            </field>
            <field>
              <name>TCR</name>
              <bitOffset>7</bitOffset>
              <bitWidth>1</bitWidth>
            </field>
            <field>
              <name>BERR</name>
              <bitOffset>8</bitOffset>
              <bitWidth>1</bitWidth>
            </field>
            <field>
              <name>ARLO</name>
              <bitOffset>9</bitOffset>
              <bitWidth>1</bitWidth>
            </field>
            <field>
              <name>OVR</name>
              <bitOffset>10</bitOffset>
              <bitWidth>1</bitWidth>
            </field>
            <field>
              <name>PECERR</name>
              <bitOffset>11</bitOffset>
              <bitWidth>1</bitWidth>
            </field>
            <field>
              <name>TIMEOUT</name>
              <bitOffset>12</bitOffset>
              <bitWidth>1</bitWidth>
            </field>
            <field>
              <name>ALERT</name>
              <bitOffset>13</bitOffset>
              <bitWidth>1</bitWidth>
            </field>
            <field>
              <name>BUSY</name>
              <bitOffset>15</bitOffset>
              <bitWidth>1</bitWidth>
            </field>
            <field>
              <name>DIR</name>
              <bitOffset>16</bitOffset>
              <bitWidth>1</bitWidth>
            </field>
            <field>
              <name>ADDCODE</name>
              <bitOffset>17</bitOffset>
              <bitWidth>7</bitWidth>
            </field>
          </fields>
        </register>
        <register>
          <name>ICR</name>
          <addressOffset>0x1c</addressOffset>
          <size>0x20</size>
          <fields>
            <field>
              <name>ADDRCF</name>
              <bitOffset>3</bitOffset>
              <bitWidth>1</bitWidth>
            </field>
            <field>
              <name>NACKCF</name>
              <bitOffset>4</bitOffset>
              <bitWidth>1</bitWidth>
            </field>
            <field>
              <name>STOPCF</name>
              <bitOffset>5</bitOffset>
              <bitWidth>1</bitWidth>
            </field>
            <field>
              <name>BERRCF</name>
              <bitOffset>8</bitOffset>
              <bitWidth>1</bitWidth>
            </field>
            <field>
              <name>ARLOCF</name>
              <bitOffset>9</bitOffset>
              <bitWidth>1</bitWidth>
            </field>
            <field>
              <name>OVRCF</name>
              <bitOffset>10</bitOffset>
              <bitWidth>1</bitWidth>
            </field>
            <field>
              <name>PECCF</name>
              <bitOffset>11</bitOffset>
              <bitWidth>1</bitWidth>
            </field>
            <field>
              <name>TIMOUTCF</name>
              <bitOffset>12</bitOffset>
              <bitWidth>1</bitWidth>
            </field>
            <field>
              <name>ALERTCF</name>
              <bitOffset>13</bitOffset>
              <bitWidth>1</bitWidth>
            </field>
          </fields>
        </register>
        <register>
          <name>PECR</name>
          <addressOffset>0x20</addressOffset>
          <size>0x20</size>
          <fields>
            <field>
              <name>PEC</name>
              <bitOffset>0</bitOffset>
              <bitWidth>8</bitWidth>
            </field>
          </fields>
        </register>
        <register>
          <name>RXDR</name>
          <addressOffset>0x24</addressOffset>
          <size>0x20</size>
          <fields>
            <field>
              <name>RXDATA</name>
              <bitOffset>0</bitOffset>
              <bitWidth>8</bitWidth>
            </field>
          </fields>
        </register>
        <register>
          <name>TXDR</name>
          <addressOffset>0x28</addressOffset>
          <size>0x20</size>
          <fields>
            <field>
              <name>TXDATA</name>
              <bitOffset>0</bitOffset>
              <bitWidth>8</bitWidth>
            </field>
          </fields>
        </register>
      </registers>
    </peripheral>
    <peripheral>
      <name>I2C2</name>
      <baseAddress>0x40005800</baseAddress>
      <registers>
        <register>
          <name>CR1</name>
          <addressOffset>0x0</addressOffset>
          <size>0x20</size>
          <fields>
            <field>
              <name>PE</name>
              <bitOffset>0</bitOffset>
              <bitWidth>1</bitWidth>
            </field>
            <field>
              <name>TXIE</name>
              <bitOffset>1</bitOffset>
              <bitWidth>1</bitWidth>
            </field>
            <field>
              <name>RXIE</name>
              <bitOffset>2</bitOffset>
              <bitWidth>1</bitWidth>
            </field>
            <field>
              <name>ADDRIE</name>
              <bitOffset>3</bitOffset>
              <bitWidth>1</bitWidth>
            </field>
            <field>
              <name>NACKIE</name>
              <bitOffset>4</bitOffset>
              <bitWidth>1</bitWidth>
            </field>
            <field>
              <name>STOPIE</name>
              <bitOffset>5</bitOffset>
              <bitWidth>1</bitWidth>
            </field>
            <field>
              <name>TCIE</name>
              <bitOffset>6</bitOffset>
              <bitWidth>1</bitWidth>
            </field>
            <field>
              <name>ERRIE</name>
              <bitOffset>7</bitOffset>
              <bitWidth>1</bitWidth>
            </field>
            <field>
              <name>DNF</name>
              <bitOffset>8</bitOffset>
              <bitWidth>4</bitWidth>
            </field>
            <field>
              <name>ANFOFF</name>
              <bitOffset>12</bitOffset>
              <bitWidth>1</bitWidth>
            </field>
            <field>
              <name>SWRST</name>
              <bitOffset>13</bitOffset>
              <bitWidth>1</bitWidth>
            </field>
            <field>
              <name>TXDMAEN</name>
              <bitOffset>14</bitOffset>
              <bitWidth>1</bitWidth>
            </field>
            <field>
              <name>RXDMAEN</name>
              <bitOffset>15</bitOffset>
              <bitWidth>1</bitWidth>
            </field>
            <field>
              <name>SBC</name>
              <bitOffset>16</bitOffset>
              <bitWidth>1</bitWidth>
            </field>
            <field>
              <name>NOSTRETCH</name>
              <bitOffset>17</bitOffset>
              <bitWidth>1</bitWidth>
            </field>
            <field>
              <name>WUPEN</name>
              <bitOffset>18</bitOffset>
              <bitWidth>1</bitWidth>
            </field>
            <field>
              <name>GCEN</name>
              <bitOffset>19</bitOffset>
              <bitWidth>1</bitWidth>
            </field>
            <field>
              <name>SMBHEN</name>
              <bitOffset>20</bitOffset>
              <bitWidth>1</bitWidth>
            </field>
            <field>
              <name>SMBDEN</name>
              <bitOffset>21</bitOffset>
              <bitWidth>1</bitWidth>
            </field>
            <field>
              <name>ALERTEN</name>
              <bitOffset>22</bitOffset>
              <bitWidth>1</bitWidth>
            </field>
            <field>
              <name>PECEN</name>
              <bitOffset>23</bitOffset>
              <bitWidth>1</bitWidth>
            </field>
          </fields>
        </register>
        <register>
          <name>CR2</name>
          <addressOffset>0x4</addressOffset>
          <size>0x20</size>
          <fields>
            <field>
              <name>SADD</name>
              <bitOffset>0</bitOffset>
              <bitWidth>10</bitWidth>
            </field>
            <field>
              <name>RD_WRN</name>
              <bitOffset>10</bitOffset>
              <bitWidth>1</bitWidth>
            </field>
            <field>
              <name>ADD10</name>
              <bitOffset>11</bitOffset>
              <bitWidth>1</bitWidth>
            </field>
            <field>
              <name>HEAD10R</name>
              <bitOffset>12</bitOffset>
              <bitWidth>1</bitWidth>
            </field>
            <field>
              <name>START</name>
              <bitOffset>13</bitOffset>
              <bitWidth>1</bitWidth>
            </field>
            <field>
              <name>STOP</name>
              <bitOffset>14</bitOffset>
              <bitWidth>1</bitWidth>
            </field>
            <field>
              <name>NACK</name>
              <bitOffset>15</bitOffset>
              <bitWidth>1</bitWidth>
            </field>
            <field>
              <name>NBYTES</name>
              <bitOffset>16</bitOffset>
              <bitWidth>8</bitWidth>
            </field>
            <field>
              <name>RELOAD</name>
              <bitOffset>24</bitOffset>
              <bitWidth>1</bitWidth>
            </field>
            <field>
              <name>AUTOEND</name>
              <bitOffset>25</bitOffset>
              <bitWidth>1</bitWidth>
            </field>
            <field>
              <name>PECBYTE</name>
              <bitOffset>26</bitOffset>
              <bitWidth>1</bitWidth>
            </field>
          </fields>
        </register>
        <register>
          <name>OAR1</name>
          <addressOffset>0x8</addressOffset>
          <size>0x20</size>
          <fields>
            <field>
              <name>OA1</name>
              <bitOffset>0</bitOffset>
              <bitWidth>10</bitWidth>
            </field>
            <field>
              <name>OA1MODE</name>
              <bitOffset>10</bitOffset>
              <bitWidth>1</bitWidth>
            </field>
            <field>
              <name>OA1EN</name>
              <bitOffset>15</bitOffset>
              <bitWidth>1</bitWidth>
            </field>
          </fields>
        </register>
        <register>
          <name>OAR2</name>
          <addressOffset>0xc</addressOffset>
          <size>0x20</size>
          <fields>
            <field>
              <name>OA2</name>
              <bitOffset>1</bitOffset>
              <bitWidth>7</bitWidth>
            </field>
            <field>
              <name>OA2MSK</name>
              <bitOffset>8</bitOffset>
              <bitWidth>3</bitWidth>
            </field>
            <field>
              <name>OA2MASK06</name>
              <bitOffset>9</bitOffset>
              <bitWidth>2</bitWidth>
            </field>
            <field>
              <name>OA2MASK04</name>
              <bitOffset>10</bitOffset>
              <bitWidth>1</bitWidth>
            </field>
            <field>
              <name>OA2EN</name>
              <bitOffset>15</bitOffset>
              <bitWidth>1</bitWidth>
            </field>
          </fields>
        </register>
        <register>
          <name>TIMINGR</name>
          <addressOffset>0x10</addressOffset>
          <size>0x20</size>
          <fields>
            <field>
              <name>SCLL</name>
              <bitOffset>0</bitOffset>
              <bitWidth>8</bitWidth>
            </field>
            <field>
              <name>SCLH</name>
              <bitOffset>8</bitOffset>
              <bitWidth>8</bitWidth>
            </field>
            <field>
              <name>SDADEL</name>
              <bitOffset>16</bitOffset>
              <bitWidth>4</bitWidth>
            </field>
            <field>
              <name>SCLDEL</name>
              <bitOffset>20</bitOffset>
              <bitWidth>4</bitWidth>
            </field>
            <field>
              <name>PRESC</name>
              <bitOffset>28</bitOffset>
              <bitWidth>4</bitWidth>
            </field>
          </fields>
        </register>
        <register>
          <name>TIMEOUTR</name>
          <addressOffset>0x14</addressOffset>
          <size>0x20</size>
          <fields>
            <field>
              <name>TIMEOUTA</name>
              <bitOffset>0</bitOffset>
              <bitWidth>12</bitWidth>
            </field>
            <field>
              <name>TIDLE</name>
              <bitOffset>12</bitOffset>
              <bitWidth>1</bitWidth>
            </field>
            <field>
              <name>TIMOUTEN</name>
              <bitOffset>15</bitOffset>
              <bitWidth>1</bitWidth>
            </field>
            <field>
              <name>TIMEOUTB</name>
              <bitOffset>16</bitOffset>
              <bitWidth>12</bitWidth>
            </field>
            <field>
              <name>TEXTEN</name>
              <bitOffset>31</bitOffset>
              <bitWidth>1</bitWidth>
            </field>
          </fields>
        </register>
        <register>
          <name>ISR</name>
          <addressOffset>0x18</addressOffset>
          <size>0x20</size>
          <fields>
            <field>
              <name>TXE</name>
              <bitOffset>0</bitOffset>
              <bitWidth>1</bitWidth>
            </field>
            <field>
              <name>TXIS</name>
              <bitOffset>1</bitOffset>
              <bitWidth>1</bitWidth>
            </field>
            <field>
              <name>RXNE</name>
              <bitOffset>2</bitOffset>
              <bitWidth>1</bitWidth>
            </field>
            <field>
              <name>ADDR</name>
              <bitOffset>3</bitOffset>
              <bitWidth>1</bitWidth>
            </field>
            <field>
              <name>NACKF</name>
              <bitOffset>4</bitOffset>
              <bitWidth>1</bitWidth>
            </field>
            <field>
              <name>STOPF</name>
              <bitOffset>5</bitOffset>
              <bitWidth>1</bitWidth>
            </field>
            <field>
              <name>TC</name>
              <bitOffset>6</bitOffset>
              <bitWidth>1</bitWidth>
            </field>
            <field>
              <name>TCR</name>
              <bitOffset>7</bitOffset>
              <bitWidth>1</bitWidth>
            </field>
            <field>
              <name>BERR</name>
              <bitOffset>8</bitOffset>
              <bitWidth>1</bitWidth>
            </field>
            <field>
              <name>ARLO</name>
              <bitOffset>9</bitOffset>
              <bitWidth>1</bitWidth>
            </field>
            <field>
              <name>OVR</name>
              <bitOffset>10</bitOffset>
              <bitWidth>1</bitWidth>
            </field>
            <field>
              <name>PECERR</name>
              <bitOffset>11</bitOffset>
              <bitWidth>1</bitWidth>
            </field>
            <field>
              <name>TIMEOUT</name>
              <bitOffset>12</bitOffset>
              <bitWidth>1</bitWidth>
            </field>
            <field>
              <name>ALERT</name>
              <bitOffset>13</bitOffset>
              <bitWidth>1</bitWidth>
            </field>
            <field>
              <name>BUSY</name>
              <bitOffset>15</bitOffset>
              <bitWidth>1</bitWidth>
            </field>
            <field>
              <name>DIR</name>
              <bitOffset>16</bitOffset>
              <bitWidth>1</bitWidth>
            </field>
            <field>
              <name>ADDCODE</name>
              <bitOffset>17</bitOffset>
              <bitWidth>7</bitWidth>
            </field>
          </fields>
        </register>
        <register>
          <name>ICR</name>
          <addressOffset>0x1c</addressOffset>
          <size>0x20</size>
          <fields>
            <field>
              <name>ADDRCF</name>
              <bitOffset>3</bitOffset>
              <bitWidth>1</bitWidth>
            </field>
            <field>
              <name>NACKCF</name>
              <bitOffset>4</bitOffset>
              <bitWidth>1</bitWidth>
            </field>
            <field>
              <name>STOPCF</name>
              <bitOffset>5</bitOffset>
              <bitWidth>1</bitWidth>
            </field>
            <field>
              <name>BERRCF</name>
              <bitOffset>8</bitOffset>
              <bitWidth>1</bitWidth>
            </field>
            <field>
              <name>ARLOCF</name>
              <bitOffset>9</bitOffset>
              <bitWidth>1</bitWidth>
            </field>
            <field>
              <name>OVRCF</name>
              <bitOffset>10</bitOffset>
              <bitWidth>1</bitWidth>
            </field>
            <field>
              <name>PECCF</name>
              <bitOffset>11</bitOffset>
              <bitWidth>1</bitWidth>
            </field>
            <field>
              <name>TIMOUTCF</name>
              <bitOffset>12</bitOffset>
              <bitWidth>1</bitWidth>
            </field>
            <field>
              <name>ALERTCF</name>
              <bitOffset>13</bitOffset>
              <bitWidth>1</bitWidth>
            </field>
          </fields>
        </register>
        <register>
          <name>PECR</name>
          <addressOffset>0x20</addressOffset>
          <size>0x20</size>
          <fields>
            <field>
              <name>PEC</name>
              <bitOffset>0</bitOffset>
              <bitWidth>8</bitWidth>
            </field>
          </fields>
        </register>
        <register>
          <name>RXDR</name>
          <addressOffset>0x24</addressOffset>
          <size>0x20</size>
          <fields>
            <field>
              <name>RXDATA</name>
              <bitOffset>0</bitOffset>
              <bitWidth>8</bitWidth>
            </field>
          </fields>
        </register>
        <register>
          <name>TXDR</name>
          <addressOffset>0x28</addressOffset>
          <size>0x20</size>
          <fields>
            <field>
              <name>TXDATA</name>
              <bitOffset>0</bitOffset>
              <bitWidth>8</bitWidth>
            </field>
          </fields>
        </register>
      </registers>
    </peripheral>
    <peripheral>
      <name>I2C3</name>
      <baseAddress>0x40005c00</baseAddress>
      <registers>
        <register>
          <name>CR1</name>
          <addressOffset>0x0</addressOffset>
          <size>0x20</size>
          <fields>
            <field>
              <name>PE</name>
              <bitOffset>0</bitOffset>
              <bitWidth>1</bitWidth>
            </field>
            <field>
              <name>TXIE</name>
              <bitOffset>1</bitOffset>
              <bitWidth>1</bitWidth>
            </field>
            <field>
              <name>RXIE</name>
              <bitOffset>2</bitOffset>
              <bitWidth>1</bitWidth>
            </field>
            <field>
              <name>ADDRIE</name>
              <bitOffset>3</bitOffset>
              <bitWidth>1</bitWidth>
            </field>
            <field>
              <name>NACKIE</name>
              <bitOffset>4</bitOffset>
              <bitWidth>1</bitWidth>
            </field>
            <field>
              <name>STOPIE</name>
              <bitOffset>5</bitOffset>
              <bitWidth>1</bitWidth>
            </field>
            <field>
              <name>TCIE</name>
              <bitOffset>6</bitOffset>
              <bitWidth>1</bitWidth>
            </field>
            <field>
              <name>ERRIE</name>
              <bitOffset>7</bitOffset>
              <bitWidth>1</bitWidth>
            </field>
            <field>
              <name>DNF</name>
              <bitOffset>8</bitOffset>
              <bitWidth>4</bitWidth>
            </field>
            <field>
              <name>ANFOFF</name>
              <bitOffset>12</bitOffset>
              <bitWidth>1</bitWidth>
            </field>
            <field>
              <name>SWRST</name>
              <bitOffset>13</bitOffset>
              <bitWidth>1</bitWidth>
            </field>
            <field>
              <name>TXDMAEN</name>
              <bitOffset>14</bitOffset>
              <bitWidth>1</bitWidth>
            </field>
            <field>
              <name>RXDMAEN</name>
              <bitOffset>15</bitOffset>
              <bitWidth>1</bitWidth>
            </field>
            <field>
              <name>SBC</name>
              <bitOffset>16</bitOffset>
              <bitWidth>1</bitWidth>
            </field>
            <field>
              <name>NOSTRETCH</name>
              <bitOffset>17</bitOffset>
              <bitWidth>1</bitWidth>
            </field>
            <field>
              <name>WUPEN</name>
              <bitOffset>18</bitOffset>
              <bitWidth>1</bitWidth>
            </field>
            <field>
              <name>GCEN</name>
              <bitOffset>19</bitOffset>
              <bitWidth>1</bitWidth>
            </field>
            <field>
              <name>SMBHEN</name>
              <bitOffset>20</bitOffset>
              <bitWidth>1</bitWidth>
            </field>
            <field>
              <name>SMBDEN</name>
              <bitOffset>21</bitOffset>
              <bitWidth>1</bitWidth>
            </field>
            <field>
              <name>ALERTEN</name>
              <bitOffset>22</bitOffset>
              <bitWidth>1</bitWidth>
            </field>
            <field>
              <name>PECEN</name>
              <bitOffset>23</bitOffset>
              <bitWidth>1</bitWidth>
            </field>
          </fields>
        </register>
        <register>
          <name>CR2</name>
          <addressOffset>0x4</addressOffset>
          <size>0x20</size>
          <fields>
            <field>
              <name>SADD</name>
              <bitOffset>0</bitOffset>
              <bitWidth>10</bitWidth>
            </field>
            <field>
              <name>RD_WRN</name>
              <bitOffset>10</bitOffset>
              <bitWidth>1</bitWidth>
            </field>
            <field>
              <name>ADD10</name>
              <bitOffset>11</bitOffset>
              <bitWidth>1</bitWidth>
            </field>
            <field>
              <name>HEAD10R</name>
              <bitOffset>12</bitOffset>
              <bitWidth>1</bitWidth>
            </field>
            <field>
              <name>START</name>
              <bitOffset>13</bitOffset>
              <bitWidth>1</bitWidth>
            </field>
            <field>
              <name>STOP</name>
              <bitOffset>14</bitOffset>
              <bitWidth>1</bitWidth>
            </field>
            <field>
              <name>NACK</name>
              <bitOffset>15</bitOffset>
              <bitWidth>1</bitWidth>
            </field>
            <field>
              <name>NBYTES</name>
              <bitOffset>16</bitOffset>
              <bitWidth>8</bitWidth>
            </field>
            <field>
              <name>RELOAD</name>
              <bitOffset>24</bitOffset>
              <bitWidth>1</bitWidth>
            </field>
            <field>
              <name>AUTOEND</name>
              <bitOffset>25</bitOffset>
              <bitWidth>1</bitWidth>
            </field>
            <field>
              <name>PECBYTE</name>
              <bitOffset>26</bitOffset>
              <bitWidth>1</bitWidth>
            </field>
          </fields>
        </register>
        <register>
          <name>OAR1</name>
          <addressOffset>0x8</addressOffset>
          <size>0x20</size>
          <fields>
            <field>
              <name>OA1</name>
              <bitOffset>0</bitOffset>
              <bitWidth>10</bitWidth>
            </field>
            <field>
              <name>OA1MODE</name>
              <bitOffset>10</bitOffset>
              <bitWidth>1</bitWidth>
            </field>
            <field>
              <name>OA1EN</name>
              <bitOffset>15</bitOffset>
              <bitWidth>1</bitWidth>
            </field>
          </fields>
        </register>
        <register>
          <name>OAR2</name>
          <addressOffset>0xc</addressOffset>
          <size>0x20</size>
          <fields>
            <field>
              <name>OA2</name>
              <bitOffset>1</bitOffset>
              <bitWidth>7</bitWidth>
            </field>
            <field>
              <name>OA2MSK</name>
              <bitOffset>8</bitOffset>
              <bitWidth>3</bitWidth>
            </field>
            <field>
              <name>OA2MASK06</name>
              <bitOffset>9</bitOffset>
              <bitWidth>2</bitWidth>
            </field>
            <field>
              <name>OA2MASK04</name>
              <bitOffset>10</bitOffset>
              <bitWidth>1</bitWidth>
            </field>
            <field>
              <name>OA2EN</name>
              <bitOffset>15</bitOffset>
              <bitWidth>1</bitWidth>
            </field>
          </fields>
        </register>
        <register>
          <name>TIMINGR</name>
          <addressOffset>0x10</addressOffset>
          <size>0x20</size>
          <fields>
            <field>
              <name>SCLL</name>
              <bitOffset>0</bitOffset>
              <bitWidth>8</bitWidth>
            </field>
            <field>
              <name>SCLH</name>
              <bitOffset>8</bitOffset>
              <bitWidth>8</bitWidth>
            </field>
            <field>
              <name>SDADEL</name>
              <bitOffset>16</bitOffset>
              <bitWidth>4</bitWidth>
            </field>
            <field>
              <name>SCLDEL</name>
              <bitOffset>20</bitOffset>
              <bitWidth>4</bitWidth>
            </field>
            <field>
              <name>PRESC</name>
              <bitOffset>28</bitOffset>
              <bitWidth>4</bitWidth>
            </field>
          </fields>
        </register>
        <register>
          <name>TIMEOUTR</name>
          <addressOffset>0x14</addressOffset>
          <size>0x20</size>
          <fields>
            <field>
              <name>TIMEOUTA</name>
              <bitOffset>0</bitOffset>
              <bitWidth>12</bitWidth>
            </field>
            <field>
              <name>TIDLE</name>
              <bitOffset>12</bitOffset>
              <bitWidth>1</bitWidth>
            </field>
            <field>
              <name>TIMOUTEN</name>
              <bitOffset>15</bitOffset>
              <bitWidth>1</bitWidth>
            </field>
            <field>
              <name>TIMEOUTB</name>
              <bitOffset>16</bitOffset>
              <bitWidth>12</bitWidth>
            </field>
            <field>
              <name>TEXTEN</name>
              <bitOffset>31</bitOffset>
              <bitWidth>1</bitWidth>
            </field>
          </fields>
        </register>
        <register>
          <name>ISR</name>
          <addressOffset>0x18</addressOffset>
          <size>0x20</size>
          <fields>
            <field>
              <name>TXE</name>
              <bitOffset>0</bitOffset>
              <bitWidth>1</bitWidth>
            </field>
            <field>
              <name>TXIS</name>
              <bitOffset>1</bitOffset>
              <bitWidth>1</bitWidth>
            </field>
            <field>
              <name>RXNE</name>
              <bitOffset>2</bitOffset>
              <bitWidth>1</bitWidth>
            </field>
            <field>
              <name>ADDR</name>
              <bitOffset>3</bitOffset>
              <bitWidth>1</bitWidth>
            </field>
            <field>
              <name>NACKF</name>
              <bitOffset>4</bitOffset>
              <bitWidth>1</bitWidth>
            </field>
            <field>
              <name>STOPF</name>
              <bitOffset>5</bitOffset>
              <bitWidth>1</bitWidth>
            </field>
            <field>
              <name>TC</name>
              <bitOffset>6</bitOffset>
              <bitWidth>1</bitWidth>
            </field>
            <field>
              <name>TCR</name>
              <bitOffset>7</bitOffset>
              <bitWidth>1</bitWidth>
            </field>
            <field>
              <name>BERR</name>
              <bitOffset>8</bitOffset>
              <bitWidth>1</bitWidth>
            </field>
            <field>
              <name>ARLO</name>
              <bitOffset>9</bitOffset>
              <bitWidth>1</bitWidth>
            </field>
            <field>
              <name>OVR</name>
              <bitOffset>10</bitOffset>
              <bitWidth>1</bitWidth>
            </field>
            <field>
              <name>PECERR</name>
              <bitOffset>11</bitOffset>
              <bitWidth>1</bitWidth>
            </field>
            <field>
              <name>TIMEOUT</name>
              <bitOffset>12</bitOffset>
              <bitWidth>1</bitWidth>
            </field>
            <field>
              <name>ALERT</name>
              <bitOffset>13</bitOffset>
              <bitWidth>1</bitWidth>
            </field>
            <field>
              <name>BUSY</name>
              <bitOffset>15</bitOffset>
              <bitWidth>1</bitWidth>
            </field>
            <field>
              <name>DIR</name>
              <bitOffset>16</bitOffset>
              <bitWidth>1</bitWidth>
            </field>
            <field>
              <name>ADDCODE</name>
              <bitOffset>17</bitOffset>
              <bitWidth>7</bitWidth>
            </field>
          </fields>
        </register>
        <register>
          <name>ICR</name>
          <addressOffset>0x1c</addressOffset>
          <size>0x20</size>
          <fields>
            <field>
              <name>ADDRCF</name>
              <bitOffset>3</bitOffset>
              <bitWidth>1</bitWidth>
            </field>
            <field>
              <name>NACKCF</name>
              <bitOffset>4</bitOffset>
              <bitWidth>1</bitWidth>
            </field>
            <field>
              <name>STOPCF</name>
              <bitOffset>5</bitOffset>
              <bitWidth>1</bitWidth>
            </field>
            <field>
              <name>BERRCF</name>
              <bitOffset>8</bitOffset>
              <bitWidth>1</bitWidth>
            </field>
            <field>
              <name>ARLOCF</name>
              <bitOffset>9</bitOffset>
              <bitWidth>1</bitWidth>
            </field>
            <field>
              <name>OVRCF</name>
              <bitOffset>10</bitOffset>
              <bitWidth>1</bitWidth>
            </field>
            <field>
              <name>PECCF</name>
              <bitOffset>11</bitOffset>
              <bitWidth>1</bitWidth>
            </field>
            <field>
              <name>TIMOUTCF</name>
              <bitOffset>12</bitOffset>
              <bitWidth>1</bitWidth>
            </field>
            <field>
              <name>ALERTCF</name>
              <bitOffset>13</bitOffset>
              <bitWidth>1</bitWidth>
            </field>
          </fields>
        </register>
        <register>
          <name>PECR</name>
          <addressOffset>0x20</addressOffset>
          <size>0x20</size>
          <fields>
            <field>
              <name>PEC</name>
              <bitOffset>0</bitOffset>
              <bitWidth>8</bitWidth>
            </field>
          </fields>
        </register>
        <register>
          <name>RXDR</name>
          <addressOffset>0x24</addressOffset>
          <size>0x20</size>
          <fields>
            <field>
              <name>RXDATA</name>
              <bitOffset>0</bitOffset>
              <bitWidth>8</bitWidth>
            </field>
          </fields>
        </register>
        <register>
          <name>TXDR</name>
          <addressOffset>0x28</addressOffset>
          <size>0x20</size>
          <fields>
            <field>
              <name>TXDATA</name>
              <bitOffset>0</bitOffset>
              <bitWidth>8</bitWidth>
            </field>
          </fields>
        </register>
      </registers>
    </peripheral>
    <peripheral>
      <name>CRS</name>
      <baseAddress>0x40006000</baseAddress>
      <registers>
        <register>
          <name>CR</name>
          <addressOffset>0x0</addressOffset>
          <size>0x20</size>
          <fields>
            <field>
              <name>SYNCOKIE</name>
              <bitOffset>0</bitOffset>
              <bitWidth>1</bitWidth>
            </field>
            <field>
              <name>SYNCWARNIE</name>
              <bitOffset>1</bitOffset>
              <bitWidth>1</bitWidth>
            </field>
            <field>
              <name>ERRIE</name>
              <bitOffset>2</bitOffset>
              <bitWidth>1</bitWidth>
            </field>
            <field>
              <name>ESYNCIE</name>
              <bitOffset>3</bitOffset>
              <bitWidth>1</bitWidth>
            </field>
            <field>
              <name>CEN</name>
              <bitOffset>5</bitOffset>
              <bitWidth>1</bitWidth>
            </field>
            <field>
              <name>AUTOTRIMEN</name>
              <bitOffset>6</bitOffset>
              <bitWidth>1</bitWidth>
            </field>
            <field>
              <name>SWSYNC</name>
              <bitOffset>7</bitOffset>
              <bitWidth>1</bitWidth>
            </field>
            <field>
              <name>TRIM</name>
              <bitOffset>8</bitOffset>
              <bitWidth>6</bitWidth>
            </field>
          </fields>
        </register>
        <register>
          <name>CFGR</name>
          <addressOffset>0x4</addressOffset>
          <size>0x20</size>
          <fields>
            <field>
              <name>RELOAD</name>
              <bitOffset>0</bitOffset>
              <bitWidth>16</bitWidth>
            </field>
            <field>
              <name>FELIM</name>
              <bitOffset>16</bitOffset>
              <bitWidth>8</bitWidth>
            </field>
            <field>
              <name>SYNCDIV</name>
              <bitOffset>24</bitOffset>
              <bitWidth>3</bitWidth>
            </field>
            <field>
              <name>SYNCSRC</name>
              <bitOffset>28</bitOffset>
              <bitWidth>2</bitWidth>
            </field>
            <field>
              <name>SYNCPOL</name>
              <bitOffset>31</bitOffset>
              <bitWidth>1</bitWidth>
            </field>
          </fields>
        </register>
        <register>
          <name>ISR</name>
          <addressOffset>0x8</addressOffset>
          <size>0x20</size>
          <fields>
            <field>
              <name>SYNCOKF</name>
              <bitOffset>0</bitOffset>
              <bitWidth>1</bitWidth>
            </field>
            <field>
              <name>SYNCWARNF</name>
              <bitOffset>1</bitOffset>
              <bitWidth>1</bitWidth>
            </field>
            <field>
              <name>ERRF</name>
              <bitOffset>2</bitOffset>
              <bitWidth>1</bitWidth>
            </field>
            <field>
              <name>ESYNCF</name>
              <bitOffset>3</bitOffset>
              <bitWidth>1</bitWidth>
            </field>
            <field>
              <name>SYNCERR</name>
              <bitOffset>8</bitOffset>
              <bitWidth>1</bitWidth>
            </field>
            <field>
              <name>SYNCMISS</name>
              <bitOffset>9</bitOffset>
              <bitWidth>1</bitWidth>
            </field>
            <field>
              <name>TRIMOVF</name>
              <bitOffset>10</bitOffset>
              <bitWidth>1</bitWidth>
            </field>
            <field>
              <name>FEDIR</name>
              <bitOffset>15</bitOffset>
              <bitWidth>1</bitWidth>
            </field>
            <field>
              <name>FECAP</name>
              <bitOffset>16</bitOffset>
              <bitWidth>16</bitWidth>
            </field>
          </fields>
        </register>
        <register>
          <name>ICR</name>
          <addressOffset>0xc</addressOffset>
          <size>0x20</size>
          <fields>
            <field>
              <name>SYNCOKC</name>
              <bitOffset>0</bitOffset>
              <bitWidth>1</bitWidth>
            </field>
            <field>
              <name>SYNCWARNC</name>
              <bitOffset>1</bitOffset>
              <bitWidth>1</bitWidth>
            </field>
            <field>
              <name>ERRC</name>
              <bitOffset>2</bitOffset>
              <bitWidth>1</bitWidth>
            </field>
            <field>
              <name>ESYNCC</name>
              <bitOffset>3</bitOffset>
              <bitWidth>1</bitWidth>
            </field>
          </fields>
        </register>
      </registers>
    </peripheral>
    <peripheral>
      <name>CAN</name>
      <baseAddress>0x40006400</baseAddress>
      <registers>
        <register>
          <name>MCR</name>
          <addressOffset>0x0</addressOffset>
          <size>0x20</size>
          <fields>
            <field>
              <name>INRQ</name>
              <bitOffset>0</bitOffset>
              <bitWidth>1</bitWidth>
            </field>
            <field>
              <name>SLEEP</name>
              <bitOffset>1</bitOffset>
              <bitWidth>1</bitWidth>
            </field>
            <field>
              <name>TXFP</name>
              <bitOffset>2</bitOffset>
              <bitWidth>1</bitWidth>
            </field>
            <field>
              <name>RFLM</name>
              <bitOffset>3</bitOffset>
              <bitWidth>1</bitWidth>
            </field>
            <field>
              <name>NART</name>
              <bitOffset>4</bitOffset>
              <bitWidth>1</bitWidth>
            </field>
            <field>
              <name>AWUM</name>
              <bitOffset>5</bitOffset>
              <bitWidth>1</bitWidth>
            </field>
            <field>
              <name>ABOM</name>
              <bitOffset>6</bitOffset>
              <bitWidth>1</bitWidth>
            </field>
            <field>
              <name>TTCM</name>
              <bitOffset>7</bitOffset>
              <bitWidth>1</bitWidth>
            </field>
            <field>
              <name>RESET</name>
              <bitOffset>15</bitOffset>
              <bitWidth>1</bitWidth>
            </field>
          </fields>
        </register>
        <register>
          <name>MSR</name>
          <addressOffset>0x4</addressOffset>
          <size>0x20</size>
          <fields>
            <field>
              <name>INAK</name>
              <bitOffset>0</bitOffset>
              <bitWidth>1</bitWidth>
            </field>
            <field>
              <name>SLAK</name>
              <bitOffset>1</bitOffset>
              <bitWidth>1</bitWidth>
            </field>
            <field>
              <name>ERRI</name>
              <bitOffset>2</bitOffset>
              <bitWidth>1</bitWidth>
            </field>
            <field>
              <name>WKUI</name>
              <bitOffset>3</bitOffset>
              <bitWidth>1</bitWidth>
            </field>
            <field>
              <name>SLAKI</name>
              <bitOffset>4</bitOffset>
              <bitWidth>1</bitWidth>
            </field>
            <field>
              <name>TXM</name>
              <bitOffset>8</bitOffset>
              <bitWidth>1</bitWidth>
            </field>
            <field>
              <name>RXM</name>
              <bitOffset>9</bitOffset>
              <bitWidth>1</bitWidth>
            </field>
            <field>
              <name>SAMP</name>
              <bitOffset>10</bitOffset>
              <bitWidth>1</bitWidth>
            </field>
            <field>
              <name>RX</name>
              <bitOffset>11</bitOffset>
              <bitWidth>1</bitWidth>
            </field>
          </fields>
        </register>
        <register>
          <name>TSR</name>
          <addressOffset>0x8</addressOffset>
          <size>0x20</size>
          <fields>
            <field>
              <name>RQCP0</name>
              <bitOffset>0</bitOffset>
              <bitWidth>1</bitWidth>
            </field>
            <field>
              <name>TXOK0</name>
              <bitOffset>1</bitOffset>
              <bitWidth>1</bitWidth>
            </field>
            <field>
              <name>ALST0</name>
              <bitOffset>2</bitOffset>
              <bitWidth>1</bitWidth>
            </field>
            <field>
              <name>TERR0</name>
              <bitOffset>3</bitOffset>
              <bitWidth>1</bitWidth>
            </field>
            <field>
              <name>ABRQ0</name>
              <bitOffset>7</bitOffset>
              <bitWidth>1</bitWidth>
            </field>
            <field>
              <name>RQCP1</name>
              <bitOffset>8</bitOffset>
              <bitWidth>1</bitWidth>
            </field>
            <field>
              <name>TXOK1</name>
              <bitOffset>9</bitOffset>
              <bitWidth>1</bitWidth>
            </field>
            <field>
              <name>ALST1</name>
              <bitOffset>10</bitOffset>
              <bitWidth>1</bitWidth>
            </field>
            <field>
              <name>TERR1</name>
              <bitOffset>11</bitOffset>
              <bitWidth>1</bitWidth>
            </field>
            <field>
              <name>ABRQ1</name>
              <bitOffset>15</bitOffset>
              <bitWidth>1</bitWidth>
            </field>
            <field>
              <name>RQCP2</name>
              <bitOffset>16</bitOffset>
              <bitWidth>1</bitWidth>
            </field>
            <field>
              <name>TXOK2</name>
              <bitOffset>17</bitOffset>
              <bitWidth>1</bitWidth>
            </field>
            <field>
              <name>ALST2</name>
              <bitOffset>18</bitOffset>
              <bitWidth>1</bitWidth>
            </field>
            <field>
              <name>TERR2</name>
              <bitOffset>19</bitOffset>
              <bitWidth>1</bitWidth>
            </field>
            <field>
              <name>ABRQ2</name>
              <bitOffset>23</bitOffset>
              <bitWidth>1</bitWidth>
            </field>
            <field>
              <name>CODE</name>
              <bitOffset>24</bitOffset>
              <bitWidth>2</bitWidth>
            </field>
            <field>
              <name>TME0</name>
              <bitOffset>26</bitOffset>
              <bitWidth>1</bitWidth>
            </field>
            <field>
              <name>TME1</name>
              <bitOffset>27</bitOffset>
              <bitWidth>1</bitWidth>
            </field>
            <field>
              <name>TME2</name>
              <bitOffset>28</bitOffset>
              <bitWidth>1</bitWidth>
            </field>
            <field>
              <name>LOW0</name>
              <bitOffset>29</bitOffset>
              <bitWidth>1</bitWidth>
            </field>
            <field>
              <name>LOW1</name>
              <bitOffset>30</bitOffset>
              <bitWidth>1</bitWidth>
            </field>
            <field>
              <name>LOW2</name>
              <bitOffset>31</bitOffset>
              <bitWidth>1</bitWidth>
            </field>
          </fields>
        </register>
        <register>
          <name>RF0R</name>
          <addressOffset>0xc</addressOffset>
          <size>0x20</size>
          <fields>
            <field>
              <name>FMP0</name>
              <bitOffset>0</bitOffset>
              <bitWidth>2</bitWidth>
            </field>
            <field>
              <name>FULL0</name>
              <bitOffset>3</bitOffset>
              <bitWidth>1</bitWidth>
            </field>
            <field>
              <name>FOVR0</name>
              <bitOffset>4</bitOffset>
              <bitWidth>1</bitWidth>
            </field>
            <field>
              <name>RFOM0</name>
              <bitOffset>5</bitOffset>
              <bitWidth>1</bitWidth>
            </field>
          </fields>
        </register>
        <register>
          <name>RF1R</name>
          <addressOffset>0x10</addressOffset>
          <size>0x20</size>
          <fields>
            <field>
              <name>FMP1</name>
              <bitOffset>0</bitOffset>
              <bitWidth>2</bitWidth>
            </field>
            <field>
              <name>FULL1</name>
              <bitOffset>3</bitOffset>
              <bitWidth>1</bitWidth>
            </field>
            <field>
              <name>FOVR1</name>
              <bitOffset>4</bitOffset>
              <bitWidth>1</bitWidth>
            </field>
            <field>
              <name>RFOM1</name>
              <bitOffset>5</bitOffset>
              <bitWidth>1</bitWidth>
            </field>
          </fields>
        </register>
        <register>
          <name>IER</name>
          <addressOffset>0x14</addressOffset>
          <size>0x20</size>
          <fields>
            <field>
              <name>TMEIE</name>
              <bitOffset>0</bitOffset>
              <bitWidth>1</bitWidth>
            </field>
            <field>
              <name>FMPIE0</name>
              <bitOffset>1</bitOffset>
              <bitWidth>1</bitWidth>
            </field>
            <field>
              <name>FFIE0</name>
              <bitOffset>2</bitOffset>
              <bitWidth>1</bitWidth>
            </field>
            <field>
              <name>FOVIE0</name>
              <bitOffset>3</bitOffset>
              <bitWidth>1</bitWidth>
            </field>
            <field>
              <name>FMPIE1</name>
              <bitOffset>4</bitOffset>
              <bitWidth>1</bitWidth>
            </field>
            <field>
              <name>FFIE1</name>
              <bitOffset>5</bitOffset>
              <bitWidth>1</bitWidth>
            </field>
            <field>
              <name>FOVIE1</name>
              <bitOffset>6</bitOffset>
              <bitWidth>1</bitWidth>
            </field>
            <field>
              <name>EWGIE</name>
              <bitOffset>8</bitOffset>
              <bitWidth>1</bitWidth>
            </field>
            <field>
              <name>EPVIE</name>
              <bitOffset>9</bitOffset>
              <bitWidth>1</bitWidth>
            </field>
            <field>
              <name>BOFIE</name>
              <bitOffset>10</bitOffset>
              <bitWidth>1</bitWidth>
            </field>
            <field>
              <name>LECIE</name>
              <bitOffset>11</bitOffset>
              <bitWidth>1</bitWidth>
            </field>
            <field>
              <name>ERRIE</name>
              <bitOffset>15</bitOffset>
              <bitWidth>1</bitWidth>
            </field>
            <field>
              <name>WKUIE</name>
              <bitOffset>16</bitOffset>
              <bitWidth>1</bitWidth>
            </field>
            <field>
              <name>SLKIE</name>
              <bitOffset>17</bitOffset>
              <bitWidth>1</bitWidth>
            </field>
          </fields>
        </register>
        <register>
          <name>ESR</name>
          <addressOffset>0x18</addressOffset>
          <size>0x20</size>
          <fields>
            <field>
              <name>EWGF</name>
              <bitOffset>0</bitOffset>
              <bitWidth>1</bitWidth>
            </field>
            <field>
              <name>EPVF</name>
              <bitOffset>1</bitOffset>
              <bitWidth>1</bitWidth>
            </field>
            <field>
              <name>BOFF</name>
              <bitOffset>2</bitOffset>
              <bitWidth>1</bitWidth>
            </field>
            <field>
              <name>LEC</name>
              <bitOffset>4</bitOffset>
              <bitWidth>3</bitWidth>
            </field>
            <field>
              <name>TEC</name>
              <bitOffset>16</bitOffset>
              <bitWidth>8</bitWidth>
            </field>
            <field>
              <name>REC</name>
              <bitOffset>24</bitOffset>
              <bitWidth>8</bitWidth>
            </field>
          </fields>
        </register>
        <register>
          <name>BTR</name>
          <addressOffset>0x1c</addressOffset>
          <size>0x20</size>
          <fields>
            <field>
              <name>BRP</name>
              <bitOffset>0</bitOffset>
              <bitWidth>10</bitWidth>
            </field>
            <field>
              <name>TS1</name>
              <bitOffset>16</bitOffset>
              <bitWidth>4</bitWidth>
            </field>
            <field>
              <name>TS2</name>
              <bitOffset>20</bitOffset>
              <bitWidth>3</bitWidth>
            </field>
            <field>
              <name>SJW</name>
              <bitOffset>24</bitOffset>
              <bitWidth>2</bitWidth>
            </field>
            <field>
              <name>LBKM</name>
              <bitOffset>30</bitOffset>
              <bitWidth>1</bitWidth>
            </field>
            <field>
              <name>SILM</name>
              <bitOffset>31</bitOffset>
              <bitWidth>1</bitWidth>
            </field>
          </fields>
        </register>
        <register>
          <name>sTxMailBox.0.TIR</name>
          <addressOffset>0x180</addressOffset>
          <size>0x20</size>
          <fields>
            <field>
              <name>TXRQ</name>
              <bitOffset>0</bitOffset>
              <bitWidth>1</bitWidth>
            </field>
            <field>
              <name>RTR</name>
              <bitOffset>1</bitOffset>
              <bitWidth>1</bitWidth>
            </field>
            <field>
              <name>IDE</name>
              <bitOffset>2</bitOffset>
              <bitWidth>1</bitWidth>
            </field>
            <field>
              <name>EXID</name>
              <bitOffset>3</bitOffset>
              <bitWidth>18</bitWidth>
            </field>
            <field>
              <name>STID</name>
              <bitOffset>21</bitOffset>
              <bitWidth>11</bitWidth>
            </field>
          </fields>
        </register>
        <register>
          <name>sTxMailBox.0.TDTR</name>
          <addressOffset>0x184</addressOffset>
          <size>0x20</size>
          <fields>
            <field>
              <name>DLC</name>
              <bitOffset>0</bitOffset>
              <bitWidth>4</bitWidth>
            </field>
            <field>
              <name>TGT</name>
              <bitOffset>8</bitOffset>
              <bitWidth>1</bitWidth>
            </field>
            <field>
              <name>TIME</name>
              <bitOffset>16</bitOffset>
              <bitWidth>16</bitWidth>
            </field>
          </fields>
        </register>
        <register>
          <name>sTxMailBox.0.TDLR</name>
          <addressOffset>0x188</addressOffset>
          <size>0x20</size>
          <fields>
            <field>
              <name>DATA0</name>
              <bitOffset>0</bitOffset>
              <bitWidth>8</bitWidth>
            </field>
            <field>
              <name>DATA1</name>
              <bitOffset>8</bitOffset>
              <bitWidth>8</bitWidth>
            </field>
            <field>
              <name>DATA2</name>
              <bitOffset>16</bitOffset>
              <bitWidth>8</bitWidth>
            </field>
            <field>
              <name>DATA3</name>
              <bitOffset>24</bitOffset>
              <bitWidth>8</bitWidth>
            </field>
          </fields>
        </register>
        <register>
          <name>sTxMailBox.0.TDHR</name>
          <addressOffset>0x18c</addressOffset>
          <size>0x20</size>
          <fields>
            <field>
              <name>DATA4</name>
              <bitOffset>0</bitOffset>
              <bitWidth>8</bitWidth>
            </field>
            <field>
              <name>DATA5</name>
              <bitOffset>8</bitOffset>
              <bitWidth>8</bitWidth>
            </field>
            <field>
              <name>DATA6</name>
              <bitOffset>16</bitOffset>
              <bitWidth>8</bitWidth>
            </field>
            <field>
              <name>DATA7</name>
              <bitOffset>24</bitOffset>
              <bitWidth>8</bitWidth>
            </field>
          </fields>
        </register>
        <register>
          <name>sTxMailBox.1.TIR</name>
          <addressOffset>0x190</addressOffset>
          <size>0x20</size>
          <fields>
            <field>
              <name>TXRQ</name>
              <bitOffset>0</bitOffset>
              <bitWidth>1</bitWidth>
            </field>
            <field>
              <name>RTR</name>
              <bitOffset>1</bitOffset>
              <bitWidth>1</bitWidth>
            </field>
            <field>
              <name>IDE</name>
              <bitOffset>2</bitOffset>
              <bitWidth>1</bitWidth>
            </field>
            <field>
              <name>EXID</name>
              <bitOffset>3</bitOffset>
              <bitWidth>18</bitWidth>
            </field>
            <field>
              <name>STID</name>
              <bitOffset>21</bitOffset>
              <bitWidth>11</bitWidth>
            </field>
          </fields>
        </register>
        <register>
          <name>sTxMailBox.1.TDTR</name>
          <addressOffset>0x194</addressOffset>
          <size>0x20</size>
          <fields>
            <field>
              <name>DLC</name>
              <bitOffset>0</bitOffset>
              <bitWidth>4</bitWidth>
            </field>
            <field>
              <name>TGT</name>
              <bitOffset>8</bitOffset>
              <bitWidth>1</bitWidth>
            </field>
            <field>
              <name>TIME</name>
              <bitOffset>16</bitOffset>
              <bitWidth>16</bitWidth>
            </field>
          </fields>
        </register>
        <register>
          <name>sTxMailBox.1.TDLR</name>
          <addressOffset>0x198</addressOffset>
          <size>0x20</size>
          <fields>
            <field>
              <name>DATA0</name>
              <bitOffset>0</bitOffset>
              <bitWidth>8</bitWidth>
            </field>
            <field>
              <name>DATA1</name>
              <bitOffset>8</bitOffset>
              <bitWidth>8</bitWidth>
            </field>
            <field>
              <name>DATA2</name>
              <bitOffset>16</bitOffset>
              <bitWidth>8</bitWidth>
            </field>
            <field>
              <name>DATA3</name>
              <bitOffset>24</bitOffset>
              <bitWidth>8</bitWidth>
            </field>
          </fields>
        </register>
        <register>
          <name>sTxMailBox.1.TDHR</name>
          <addressOffset>0x19c</addressOffset>
          <size>0x20</size>
          <fields>
            <field>
              <name>DATA4</name>
              <bitOffset>0</bitOffset>
              <bitWidth>8</bitWidth>
            </field>
            <field>
              <name>DATA5</name>
              <bitOffset>8</bitOffset>
              <bitWidth>8</bitWidth>
            </field>
            <field>
              <name>DATA6</name>
              <bitOffset>16</bitOffset>
              <bitWidth>8</bitWidth>
            </field>
            <field>
              <name>DATA7</name>
              <bitOffset>24</bitOffset>
              <bitWidth>8</bitWidth>
            </field>
          </fields>
        </register>
        <register>
          <name>sTxMailBox.2.TIR</name>
          <addressOffset>0x1a0</addressOffset>
          <size>0x20</size>
          <fields>
            <field>
              <name>TXRQ</name>
              <bitOffset>0</bitOffset>
              <bitWidth>1</bitWidth>
            </field>
            <field>
              <name>RTR</name>
              <bitOffset>1</bitOffset>
              <bitWidth>1</bitWidth>
            </field>
            <field>
              <name>IDE</name>
              <bitOffset>2</bitOffset>
              <bitWidth>1</bitWidth>
            </field>
            <field>
              <name>EXID</name>
              <bitOffset>3</bitOffset>
              <bitWidth>18</bitWidth>
            </field>
            <field>
              <name>STID</name>
              <bitOffset>21</bitOffset>
              <bitWidth>11</bitWidth>
            </field>
          </fields>
        </register>
        <register>
          <name>sTxMailBox.2.TDTR</name>
          <addressOffset>0x1a4</addressOffset>
          <size>0x20</size>
          <fields>
            <field>
              <name>DLC</name>
              <bitOffset>0</bitOffset>
              <bitWidth>4</bitWidth>
            </field>
            <field>
              <name>TGT</name>
              <bitOffset>8</bitOffset>
              <bitWidth>1</bitWidth>
            </field>
            <field>
              <name>TIME</name>
              <bitOffset>16</bitOffset>
              <bitWidth>16</bitWidth>
            </field>
          </fields>
        </register>
        <register>
          <name>sTxMailBox.2.TDLR</name>
          <addressOffset>0x1a8</addressOffset>
          <size>0x20</size>
          <fields>
            <field>
              <name>DATA0</name>
              <bitOffset>0</bitOffset>
              <bitWidth>8</bitWidth>
            </field>
            <field>
              <name>DATA1</name>
              <bitOffset>8</bitOffset>
              <bitWidth>8</bitWidth>
            </field>
            <field>
              <name>DATA2</name>
              <bitOffset>16</bitOffset>
              <bitWidth>8</bitWidth>
            </field>
            <field>
              <name>DATA3</name>
              <bitOffset>24</bitOffset>
              <bitWidth>8</bitWidth>
            </field>
          </fields>
        </register>
        <register>
          <name>sTxMailBox.2.TDHR</name>
          <addressOffset>0x1ac</addressOffset>
          <size>0x20</size>
          <fields>
            <field>
              <name>DATA4</name>
              <bitOffset>0</bitOffset>
              <bitWidth>8</bitWidth>
            </field>
            <field>
              <name>DATA5</name>
              <bitOffset>8</bitOffset>
              <bitWidth>8</bitWidth>
            </field>
            <field>
              <name>DATA6</name>
              <bitOffset>16</bitOffset>
              <bitWidth>8</bitWidth>
            </field>
            <field>
              <name>DATA7</name>
              <bitOffset>24</bitOffset>
              <bitWidth>8</bitWidth>
            </field>
          </fields>
        </register>
        <register>
          <name>sFIFOMailBox.0.RIR</name>
          <addressOffset>0x1b0</addressOffset>
          <size>0x20</size>
          <fields>
            <field>
              <name>RTR</name>
              <bitOffset>1</bitOffset>
              <bitWidth>1</bitWidth>
            </field>
            <field>
              <name>IDE</name>
              <bitOffset>2</bitOffset>
              <bitWidth>1</bitWidth>
            </field>
            <field>
              <name>EXID</name>
              <bitOffset>3</bitOffset>
              <bitWidth>18</bitWidth>
            </field>
            <field>
              <name>STID</name>
              <bitOffset>21</bitOffset>
              <bitWidth>11</bitWidth>
            </field>
          </fields>
        </register>
        <register>
          <name>sFIFOMailBox.0.RDTR</name>
          <addressOffset>0x1b4</addressOffset>
          <size>0x20</size>
          <fields>
            <field>
              <name>DLC</name>
              <bitOffset>0</bitOffset>
              <bitWidth>4</bitWidth>
            </field>
            <field>
              <name>FMI</name>
              <bitOffset>8</bitOffset>
              <bitWidth>8</bitWidth>
            </field>
            <field>
              <name>TIME</name>
              <bitOffset>16</bitOffset>
              <bitWidth>16</bitWidth>
            </field>
          </fields>
        </register>
        <register>
          <name>sFIFOMailBox.0.RDLR</name>
          <addressOffset>0x1b8</addressOffset>
          <size>0x20</size>
          <fields>
            <field>
              <name>DATA0</name>
              <bitOffset>0</bitOffset>
              <bitWidth>8</bitWidth>
            </field>
            <field>
              <name>DATA1</name>
              <bitOffset>8</bitOffset>
              <bitWidth>8</bitWidth>
            </field>
            <field>
              <name>DATA2</name>
              <bitOffset>16</bitOffset>
              <bitWidth>8</bitWidth>
            </field>
            <field>
              <name>DATA3</name>
              <bitOffset>24</bitOffset>
              <bitWidth>8</bitWidth>
            </field>
          </fields>
        </register>
        <register>
          <name>sFIFOMailBox.0.RDHR</name>
          <addressOffset>0x1bc</addressOffset>
          <size>0x20</size>
          <fields>
            <field>
              <name>DATA4</name>
              <bitOffset>0</bitOffset>
              <bitWidth>8</bitWidth>
            </field>
            <field>
              <name>DATA5</name>
              <bitOffset>8</bitOffset>
              <bitWidth>8</bitWidth>
            </field>
            <field>
              <name>DATA6</name>
              <bitOffset>16</bitOffset>
              <bitWidth>8</bitWidth>
            </field>
            <field>
              <name>DATA7</name>
              <bitOffset>24</bitOffset>
              <bitWidth>8</bitWidth>
            </field>
          </fields>
        </register>
        <register>
          <name>sFIFOMailBox.1.RIR</name>
          <addressOffset>0x1c0</addressOffset>
          <size>0x20</size>
          <fields>
            <field>
              <name>RTR</name>
              <bitOffset>1</bitOffset>
              <bitWidth>1</bitWidth>
            </field>
            <field>
              <name>IDE</name>
              <bitOffset>2</bitOffset>
              <bitWidth>1</bitWidth>
            </field>
            <field>
              <name>EXID</name>
              <bitOffset>3</bitOffset>
              <bitWidth>18</bitWidth>
            </field>
            <field>
              <name>STID</name>
              <bitOffset>21</bitOffset>
              <bitWidth>11</bitWidth>
            </field>
          </fields>
        </register>
        <register>
          <name>sFIFOMailBox.1.RDTR</name>
          <addressOffset>0x1c4</addressOffset>
          <size>0x20</size>
          <fields>
            <field>
              <name>DLC</name>
              <bitOffset>0</bitOffset>
              <bitWidth>4</bitWidth>
            </field>
            <field>
              <name>FMI</name>
              <bitOffset>8</bitOffset>
              <bitWidth>8</bitWidth>
            </field>
            <field>
              <name>TIME</name>
              <bitOffset>16</bitOffset>
              <bitWidth>16</bitWidth>
            </field>
          </fields>
        </register>
        <register>
          <name>sFIFOMailBox.1.RDLR</name>
          <addressOffset>0x1c8</addressOffset>
          <size>0x20</size>
          <fields>
            <field>
              <name>DATA0</name>
              <bitOffset>0</bitOffset>
              <bitWidth>8</bitWidth>
            </field>
            <field>
              <name>DATA1</name>
              <bitOffset>8</bitOffset>
              <bitWidth>8</bitWidth>
            </field>
            <field>
              <name>DATA2</name>
              <bitOffset>16</bitOffset>
              <bitWidth>8</bitWidth>
            </field>
            <field>
              <name>DATA3</name>
              <bitOffset>24</bitOffset>
              <bitWidth>8</bitWidth>
            </field>
          </fields>
        </register>
        <register>
          <name>sFIFOMailBox.1.RDHR</name>
          <addressOffset>0x1cc</addressOffset>
          <size>0x20</size>
          <fields>
            <field>
              <name>DATA4</name>
              <bitOffset>0</bitOffset>
              <bitWidth>8</bitWidth>
            </field>
            <field>
              <name>DATA5</name>
              <bitOffset>8</bitOffset>
              <bitWidth>8</bitWidth>
            </field>
            <field>
              <name>DATA6</name>
              <bitOffset>16</bitOffset>
              <bitWidth>8</bitWidth>
            </field>
            <field>
              <name>DATA7</name>
              <bitOffset>24</bitOffset>
              <bitWidth>8</bitWidth>
            </field>
          </fields>
        </register>
        <register>
          <name>FMR</name>
          <addressOffset>0x200</addressOffset>
          <size>0x20</size>
          <fields>
            <field>
              <name>FINIT</name>
              <bitOffset>0</bitOffset>
              <bitWidth>1</bitWidth>
            </field>
          </fields>
        </register>
        <register>
          <name>FM1R</name>
          <addressOffset>0x204</addressOffset>
          <size>0x20</size>
          <fields>
            <field>
              <name>FBM0</name>
              <bitOffset>0</bitOffset>
              <bitWidth>1</bitWidth>
            </field>
            <field>
              <name>FBM1</name>
              <bitOffset>1</bitOffset>
              <bitWidth>1</bitWidth>
            </field>
            <field>
              <name>FBM2</name>
              <bitOffset>2</bitOffset>
              <bitWidth>1</bitWidth>
            </field>
            <field>
              <name>FBM3</name>
              <bitOffset>3</bitOffset>
              <bitWidth>1</bitWidth>
            </field>
            <field>
              <name>FBM4</name>
              <bitOffset>4</bitOffset>
              <bitWidth>1</bitWidth>
            </field>
            <field>
              <name>FBM5</name>
              <bitOffset>5</bitOffset>
              <bitWidth>1</bitWidth>
            </field>
            <field>
              <name>FBM6</name>
              <bitOffset>6</bitOffset>
              <bitWidth>1</bitWidth>
            </field>
            <field>
              <name>FBM7</name>
              <bitOffset>7</bitOffset>
              <bitWidth>1</bitWidth>
            </field>
            <field>
              <name>FBM8</name>
              <bitOffset>8</bitOffset>
              <bitWidth>1</bitWidth>
            </field>
            <field>
              <name>FBM9</name>
              <bitOffset>9</bitOffset>
              <bitWidth>1</bitWidth>
            </field>
            <field>
              <name>FBM10</name>
              <bitOffset>10</bitOffset>
              <bitWidth>1</bitWidth>
            </field>
            <field>
              <name>FBM11</name>
              <bitOffset>11</bitOffset>
              <bitWidth>1</bitWidth>
            </field>
            <field>
              <name>FBM12</name>
              <bitOffset>12</bitOffset>
              <bitWidth>1</bitWidth>
            </field>
            <field>
              <name>FBM13</name>
              <bitOffset>13</bitOffset>
              <bitWidth>1</bitWidth>
            </field>
          </fields>
        </register>
        <register>
          <name>FS1R</name>
          <addressOffset>0x20c</addressOffset>
          <size>0x20</size>
          <fields>
            <field>
              <name>FSC0</name>
              <bitOffset>0</bitOffset>
              <bitWidth>1</bitWidth>
            </field>
            <field>
              <name>FSC1</name>
              <bitOffset>1</bitOffset>
              <bitWidth>1</bitWidth>
            </field>
            <field>
              <name>FSC2</name>
              <bitOffset>2</bitOffset>
              <bitWidth>1</bitWidth>
            </field>
            <field>
              <name>FSC3</name>
              <bitOffset>3</bitOffset>
              <bitWidth>1</bitWidth>
            </field>
            <field>
              <name>FSC4</name>
              <bitOffset>4</bitOffset>
              <bitWidth>1</bitWidth>
            </field>
            <field>
              <name>FSC5</name>
              <bitOffset>5</bitOffset>
              <bitWidth>1</bitWidth>
            </field>
            <field>
              <name>FSC6</name>
              <bitOffset>6</bitOffset>
              <bitWidth>1</bitWidth>
            </field>
            <field>
              <name>FSC7</name>
              <bitOffset>7</bitOffset>
              <bitWidth>1</bitWidth>
            </field>
            <field>
              <name>FSC8</name>
              <bitOffset>8</bitOffset>
              <bitWidth>1</bitWidth>
            </field>
            <field>
              <name>FSC9</name>
              <bitOffset>9</bitOffset>
              <bitWidth>1</bitWidth>
            </field>
            <field>
              <name>FSC10</name>
              <bitOffset>10</bitOffset>
              <bitWidth>1</bitWidth>
            </field>
            <field>
              <name>FSC11</name>
              <bitOffset>11</bitOffset>
              <bitWidth>1</bitWidth>
            </field>
            <field>
              <name>FSC12</name>
              <bitOffset>12</bitOffset>
              <bitWidth>1</bitWidth>
            </field>
            <field>
              <name>FSC13</name>
              <bitOffset>13</bitOffset>
              <bitWidth>1</bitWidth>
            </field>
          </fields>
        </register>
        <register>
          <name>FFA1R</name>
          <addressOffset>0x214</addressOffset>
          <size>0x20</size>
          <fields>
            <field>
              <name>FFA0</name>
              <bitOffset>0</bitOffset>
              <bitWidth>1</bitWidth>
            </field>
            <field>
              <name>FFA1</name>
              <bitOffset>1</bitOffset>
              <bitWidth>1</bitWidth>
            </field>
            <field>
              <name>FFA2</name>
              <bitOffset>2</bitOffset>
              <bitWidth>1</bitWidth>
            </field>
            <field>
              <name>FFA3</name>
              <bitOffset>3</bitOffset>
              <bitWidth>1</bitWidth>
            </field>
            <field>
              <name>FFA4</name>
              <bitOffset>4</bitOffset>
              <bitWidth>1</bitWidth>
            </field>
            <field>
              <name>FFA5</name>
              <bitOffset>5</bitOffset>
              <bitWidth>1</bitWidth>
            </field>
            <field>
              <name>FFA6</name>
              <bitOffset>6</bitOffset>
              <bitWidth>1</bitWidth>
            </field>
            <field>
              <name>FFA7</name>
              <bitOffset>7</bitOffset>
              <bitWidth>1</bitWidth>
            </field>
            <field>
              <name>FFA8</name>
              <bitOffset>8</bitOffset>
              <bitWidth>1</bitWidth>
            </field>
            <field>
              <name>FFA9</name>
              <bitOffset>9</bitOffset>
              <bitWidth>1</bitWidth>
            </field>
            <field>
              <name>FFA10</name>
              <bitOffset>10</bitOffset>
              <bitWidth>1</bitWidth>
            </field>
            <field>
              <name>FFA11</name>
              <bitOffset>11</bitOffset>
              <bitWidth>1</bitWidth>
            </field>
            <field>
              <name>FFA12</name>
              <bitOffset>12</bitOffset>
              <bitWidth>1</bitWidth>
            </field>
            <field>
              <name>FFA13</name>
              <bitOffset>13</bitOffset>
              <bitWidth>1</bitWidth>
            </field>
          </fields>
        </register>
        <register>
          <name>FA1R</name>
          <addressOffset>0x21c</addressOffset>
          <size>0x20</size>
          <fields>
            <field>
              <name>FACT0</name>
              <bitOffset>0</bitOffset>
              <bitWidth>1</bitWidth>
            </field>
            <field>
              <name>FACT1</name>
              <bitOffset>1</bitOffset>
              <bitWidth>1</bitWidth>
            </field>
            <field>
              <name>FACT2</name>
              <bitOffset>2</bitOffset>
              <bitWidth>1</bitWidth>
            </field>
            <field>
              <name>FACT3</name>
              <bitOffset>3</bitOffset>
              <bitWidth>1</bitWidth>
            </field>
            <field>
              <name>FACT4</name>
              <bitOffset>4</bitOffset>
              <bitWidth>1</bitWidth>
            </field>
            <field>
              <name>FACT5</name>
              <bitOffset>5</bitOffset>
              <bitWidth>1</bitWidth>
            </field>
            <field>
              <name>FACT6</name>
              <bitOffset>6</bitOffset>
              <bitWidth>1</bitWidth>
            </field>
            <field>
              <name>FACT7</name>
              <bitOffset>7</bitOffset>
              <bitWidth>1</bitWidth>
            </field>
            <field>
              <name>FACT8</name>
              <bitOffset>8</bitOffset>
              <bitWidth>1</bitWidth>
            </field>
            <field>
              <name>FACT9</name>
              <bitOffset>9</bitOffset>
              <bitWidth>1</bitWidth>
            </field>
            <field>
              <name>FACT10</name>
              <bitOffset>10</bitOffset>
              <bitWidth>1</bitWidth>
            </field>
            <field>
              <name>FACT11</name>
              <bitOffset>11</bitOffset>
              <bitWidth>1</bitWidth>
            </field>
            <field>
              <name>FACT12</name>
              <bitOffset>12</bitOffset>
              <bitWidth>1</bitWidth>
            </field>
            <field>
              <name>FACT13</name>
              <bitOffset>13</bitOffset>
              <bitWidth>1</bitWidth>
            </field>
          </fields>
        </register>
        <register>
          <name>sFilterRegister.0.FR1</name>
          <addressOffset>0x240</addressOffset>
          <size>0x20</size>
          <fields>
            <field>
              <name>FB0</name>
              <bitOffset>0</bitOffset>
              <bitWidth>1</bitWidth>
            </field>
            <field>
              <name>FB1</name>
              <bitOffset>1</bitOffset>
              <bitWidth>1</bitWidth>
            </field>
            <field>
              <name>FB2</name>
              <bitOffset>2</bitOffset>
              <bitWidth>1</bitWidth>
            </field>
            <field>
              <name>FB3</name>
              <bitOffset>3</bitOffset>
              <bitWidth>1</bitWidth>
            </field>
            <field>
              <name>FB4</name>
              <bitOffset>4</bitOffset>
              <bitWidth>1</bitWidth>
            </field>
            <field>
              <name>FB5</name>
              <bitOffset>5</bitOffset>
              <bitWidth>1</bitWidth>
            </field>
            <field>
              <name>FB6</name>
              <bitOffset>6</bitOffset>
              <bitWidth>1</bitWidth>
            </field>
            <field>
              <name>FB7</name>
              <bitOffset>7</bitOffset>
              <bitWidth>1</bitWidth>
            </field>
            <field>
              <name>FB8</name>
              <bitOffset>8</bitOffset>
              <bitWidth>1</bitWidth>
            </field>
            <field>
              <name>FB9</name>
              <bitOffset>9</bitOffset>
              <bitWidth>1</bitWidth>
            </field>
            <field>
              <name>FB10</name>
              <bitOffset>10</bitOffset>
              <bitWidth>1</bitWidth>
            </field>
            <field>
              <name>FB11</name>
              <bitOffset>11</bitOffset>
              <bitWidth>1</bitWidth>
            </field>
            <field>
              <name>FB12</name>
              <bitOffset>12</bitOffset>
              <bitWidth>1</bitWidth>
            </field>
            <field>
              <name>FB13</name>
              <bitOffset>13</bitOffset>
              <bitWidth>1</bitWidth>
            </field>
            <field>
              <name>FB14</name>
              <bitOffset>14</bitOffset>
              <bitWidth>1</bitWidth>
            </field>
            <field>
              <name>FB15</name>
              <bitOffset>15</bitOffset>
              <bitWidth>1</bitWidth>
            </field>
            <field>
              <name>FB16</name>
              <bitOffset>16</bitOffset>
              <bitWidth>1</bitWidth>
            </field>
            <field>
              <name>FB17</name>
              <bitOffset>17</bitOffset>
              <bitWidth>1</bitWidth>
            </field>
            <field>
              <name>FB18</name>
              <bitOffset>18</bitOffset>
              <bitWidth>1</bitWidth>
            </field>
            <field>
              <name>FB19</name>
              <bitOffset>19</bitOffset>
              <bitWidth>1</bitWidth>
            </field>
            <field>
              <name>FB20</name>
              <bitOffset>20</bitOffset>
              <bitWidth>1</bitWidth>
            </field>
            <field>
              <name>FB21</name>
              <bitOffset>21</bitOffset>
              <bitWidth>1</bitWidth>
            </field>
            <field>
              <name>FB22</name>
              <bitOffset>22</bitOffset>
              <bitWidth>1</bitWidth>
            </field>
            <field>
              <name>FB23</name>
              <bitOffset>23</bitOffset>
              <bitWidth>1</bitWidth>
            </field>
            <field>
              <name>FB24</name>
              <bitOffset>24</bitOffset>
              <bitWidth>1</bitWidth>
            </field>
            <field>
              <name>FB25</name>
              <bitOffset>25</bitOffset>
              <bitWidth>1</bitWidth>
            </field>
            <field>
              <name>FB26</name>
              <bitOffset>26</bitOffset>
              <bitWidth>1</bitWidth>
            </field>
            <field>
              <name>FB27</name>
              <bitOffset>27</bitOffset>
              <bitWidth>1</bitWidth>
            </field>
            <field>
              <name>FB28</name>
              <bitOffset>28</bitOffset>
              <bitWidth>1</bitWidth>
            </field>
            <field>
              <name>FB29</name>
              <bitOffset>29</bitOffset>
              <bitWidth>1</bitWidth>
            </field>
            <field>
              <name>FB30</name>
              <bitOffset>30</bitOffset>
              <bitWidth>1</bitWidth>
            </field>
            <field>
              <name>FB31</name>
              <bitOffset>31</bitOffset>
              <bitWidth>1</bitWidth>
            </field>
          </fields>
        </register>
        <register>
          <name>sFilterRegister.0.FR2</name>
          <addressOffset>0x244</addressOffset>
          <size>0x20</size>
          <fields>
            <field>
              <name>FB0</name>
              <bitOffset>0</bitOffset>
              <bitWidth>1</bitWidth>
            </field>
            <field>
              <name>FB1</name>
              <bitOffset>1</bitOffset>
              <bitWidth>1</bitWidth>
            </field>
            <field>
              <name>FB2</name>
              <bitOffset>2</bitOffset>
              <bitWidth>1</bitWidth>
            </field>
            <field>
              <name>FB3</name>
              <bitOffset>3</bitOffset>
              <bitWidth>1</bitWidth>
            </field>
            <field>
              <name>FB4</name>
              <bitOffset>4</bitOffset>
              <bitWidth>1</bitWidth>
            </field>
            <field>
              <name>FB5</name>
              <bitOffset>5</bitOffset>
              <bitWidth>1</bitWidth>
            </field>
            <field>
              <name>FB6</name>
              <bitOffset>6</bitOffset>
              <bitWidth>1</bitWidth>
            </field>
            <field>
              <name>FB7</name>
              <bitOffset>7</bitOffset>
              <bitWidth>1</bitWidth>
            </field>
            <field>
              <name>FB8</name>
              <bitOffset>8</bitOffset>
              <bitWidth>1</bitWidth>
            </field>
            <field>
              <name>FB9</name>
              <bitOffset>9</bitOffset>
              <bitWidth>1</bitWidth>
            </field>
            <field>
              <name>FB10</name>
              <bitOffset>10</bitOffset>
              <bitWidth>1</bitWidth>
            </field>
            <field>
              <name>FB11</name>
              <bitOffset>11</bitOffset>
              <bitWidth>1</bitWidth>
            </field>
            <field>
              <name>FB12</name>
              <bitOffset>12</bitOffset>
              <bitWidth>1</bitWidth>
            </field>
            <field>
              <name>FB13</name>
              <bitOffset>13</bitOffset>
              <bitWidth>1</bitWidth>
            </field>
            <field>
              <name>FB14</name>
              <bitOffset>14</bitOffset>
              <bitWidth>1</bitWidth>
            </field>
            <field>
              <name>FB15</name>
              <bitOffset>15</bitOffset>
              <bitWidth>1</bitWidth>
            </field>
            <field>
              <name>FB16</name>
              <bitOffset>16</bitOffset>
              <bitWidth>1</bitWidth>
            </field>
            <field>
              <name>FB17</name>
              <bitOffset>17</bitOffset>
              <bitWidth>1</bitWidth>
            </field>
            <field>
              <name>FB18</name>
              <bitOffset>18</bitOffset>
              <bitWidth>1</bitWidth>
            </field>
            <field>
              <name>FB19</name>
              <bitOffset>19</bitOffset>
              <bitWidth>1</bitWidth>
            </field>
            <field>
              <name>FB20</name>
              <bitOffset>20</bitOffset>
              <bitWidth>1</bitWidth>
            </field>
            <field>
              <name>FB21</name>
              <bitOffset>21</bitOffset>
              <bitWidth>1</bitWidth>
            </field>
            <field>
              <name>FB22</name>
              <bitOffset>22</bitOffset>
              <bitWidth>1</bitWidth>
            </field>
            <field>
              <name>FB23</name>
              <bitOffset>23</bitOffset>
              <bitWidth>1</bitWidth>
            </field>
            <field>
              <name>FB24</name>
              <bitOffset>24</bitOffset>
              <bitWidth>1</bitWidth>
            </field>
            <field>
              <name>FB25</name>
              <bitOffset>25</bitOffset>
              <bitWidth>1</bitWidth>
            </field>
            <field>
              <name>FB26</name>
              <bitOffset>26</bitOffset>
              <bitWidth>1</bitWidth>
            </field>
            <field>
              <name>FB27</name>
              <bitOffset>27</bitOffset>
              <bitWidth>1</bitWidth>
            </field>
            <field>
              <name>FB28</name>
              <bitOffset>28</bitOffset>
              <bitWidth>1</bitWidth>
            </field>
            <field>
              <name>FB29</name>
              <bitOffset>29</bitOffset>
              <bitWidth>1</bitWidth>
            </field>
            <field>
              <name>FB30</name>
              <bitOffset>30</bitOffset>
              <bitWidth>1</bitWidth>
            </field>
            <field>
              <name>FB31</name>
              <bitOffset>31</bitOffset>
              <bitWidth>1</bitWidth>
            </field>
          </fields>
        </register>
        <register>
          <name>sFilterRegister.1.FR1</name>
          <addressOffset>0x248</addressOffset>
          <size>0x20</size>
          <fields>
            <field>
              <name>FB0</name>
              <bitOffset>0</bitOffset>
              <bitWidth>1</bitWidth>
            </field>
            <field>
              <name>FB1</name>
              <bitOffset>1</bitOffset>
              <bitWidth>1</bitWidth>
            </field>
            <field>
              <name>FB2</name>
              <bitOffset>2</bitOffset>
              <bitWidth>1</bitWidth>
            </field>
            <field>
              <name>FB3</name>
              <bitOffset>3</bitOffset>
              <bitWidth>1</bitWidth>
            </field>
            <field>
              <name>FB4</name>
              <bitOffset>4</bitOffset>
              <bitWidth>1</bitWidth>
            </field>
            <field>
              <name>FB5</name>
              <bitOffset>5</bitOffset>
              <bitWidth>1</bitWidth>
            </field>
            <field>
              <name>FB6</name>
              <bitOffset>6</bitOffset>
              <bitWidth>1</bitWidth>
            </field>
            <field>
              <name>FB7</name>
              <bitOffset>7</bitOffset>
              <bitWidth>1</bitWidth>
            </field>
            <field>
              <name>FB8</name>
              <bitOffset>8</bitOffset>
              <bitWidth>1</bitWidth>
            </field>
            <field>
              <name>FB9</name>
              <bitOffset>9</bitOffset>
              <bitWidth>1</bitWidth>
            </field>
            <field>
              <name>FB10</name>
              <bitOffset>10</bitOffset>
              <bitWidth>1</bitWidth>
            </field>
            <field>
              <name>FB11</name>
              <bitOffset>11</bitOffset>
              <bitWidth>1</bitWidth>
            </field>
            <field>
              <name>FB12</name>
              <bitOffset>12</bitOffset>
              <bitWidth>1</bitWidth>
            </field>
            <field>
              <name>FB13</name>
              <bitOffset>13</bitOffset>
              <bitWidth>1</bitWidth>
            </field>
            <field>
              <name>FB14</name>
              <bitOffset>14</bitOffset>
              <bitWidth>1</bitWidth>
            </field>
            <field>
              <name>FB15</name>
              <bitOffset>15</bitOffset>
              <bitWidth>1</bitWidth>
            </field>
            <field>
              <name>FB16</name>
              <bitOffset>16</bitOffset>
              <bitWidth>1</bitWidth>
            </field>
            <field>
              <name>FB17</name>
              <bitOffset>17</bitOffset>
              <bitWidth>1</bitWidth>
            </field>
            <field>
              <name>FB18</name>
              <bitOffset>18</bitOffset>
              <bitWidth>1</bitWidth>
            </field>
            <field>
              <name>FB19</name>
              <bitOffset>19</bitOffset>
              <bitWidth>1</bitWidth>
            </field>
            <field>
              <name>FB20</name>
              <bitOffset>20</bitOffset>
              <bitWidth>1</bitWidth>
            </field>
            <field>
              <name>FB21</name>
              <bitOffset>21</bitOffset>
              <bitWidth>1</bitWidth>
            </field>
            <field>
              <name>FB22</name>
              <bitOffset>22</bitOffset>
              <bitWidth>1</bitWidth>
            </field>
            <field>
              <name>FB23</name>
              <bitOffset>23</bitOffset>
              <bitWidth>1</bitWidth>
            </field>
            <field>
              <name>FB24</name>
              <bitOffset>24</bitOffset>
              <bitWidth>1</bitWidth>
            </field>
            <field>
              <name>FB25</name>
              <bitOffset>25</bitOffset>
              <bitWidth>1</bitWidth>
            </field>
            <field>
              <name>FB26</name>
              <bitOffset>26</bitOffset>
              <bitWidth>1</bitWidth>
            </field>
            <field>
              <name>FB27</name>
              <bitOffset>27</bitOffset>
              <bitWidth>1</bitWidth>
            </field>
            <field>
              <name>FB28</name>
              <bitOffset>28</bitOffset>
              <bitWidth>1</bitWidth>
            </field>
            <field>
              <name>FB29</name>
              <bitOffset>29</bitOffset>
              <bitWidth>1</bitWidth>
            </field>
            <field>
              <name>FB30</name>
              <bitOffset>30</bitOffset>
              <bitWidth>1</bitWidth>
            </field>
            <field>
              <name>FB31</name>
              <bitOffset>31</bitOffset>
              <bitWidth>1</bitWidth>
            </field>
          </fields>
        </register>
        <register>
          <name>sFilterRegister.1.FR2</name>
          <addressOffset>0x24c</addressOffset>
          <size>0x20</size>
          <fields>
            <field>
              <name>FB0</name>
              <bitOffset>0</bitOffset>
              <bitWidth>1</bitWidth>
            </field>
            <field>
              <name>FB1</name>
              <bitOffset>1</bitOffset>
              <bitWidth>1</bitWidth>
            </field>
            <field>
              <name>FB2</name>
              <bitOffset>2</bitOffset>
              <bitWidth>1</bitWidth>
            </field>
            <field>
              <name>FB3</name>
              <bitOffset>3</bitOffset>
              <bitWidth>1</bitWidth>
            </field>
            <field>
              <name>FB4</name>
              <bitOffset>4</bitOffset>
              <bitWidth>1</bitWidth>
            </field>
            <field>
              <name>FB5</name>
              <bitOffset>5</bitOffset>
              <bitWidth>1</bitWidth>
            </field>
            <field>
              <name>FB6</name>
              <bitOffset>6</bitOffset>
              <bitWidth>1</bitWidth>
            </field>
            <field>
              <name>FB7</name>
              <bitOffset>7</bitOffset>
              <bitWidth>1</bitWidth>
            </field>
            <field>
              <name>FB8</name>
              <bitOffset>8</bitOffset>
              <bitWidth>1</bitWidth>
            </field>
            <field>
              <name>FB9</name>
              <bitOffset>9</bitOffset>
              <bitWidth>1</bitWidth>
            </field>
            <field>
              <name>FB10</name>
              <bitOffset>10</bitOffset>
              <bitWidth>1</bitWidth>
            </field>
            <field>
              <name>FB11</name>
              <bitOffset>11</bitOffset>
              <bitWidth>1</bitWidth>
            </field>
            <field>
              <name>FB12</name>
              <bitOffset>12</bitOffset>
              <bitWidth>1</bitWidth>
            </field>
            <field>
              <name>FB13</name>
              <bitOffset>13</bitOffset>
              <bitWidth>1</bitWidth>
            </field>
            <field>
              <name>FB14</name>
              <bitOffset>14</bitOffset>
              <bitWidth>1</bitWidth>
            </field>
            <field>
              <name>FB15</name>
              <bitOffset>15</bitOffset>
              <bitWidth>1</bitWidth>
            </field>
            <field>
              <name>FB16</name>
              <bitOffset>16</bitOffset>
              <bitWidth>1</bitWidth>
            </field>
            <field>
              <name>FB17</name>
              <bitOffset>17</bitOffset>
              <bitWidth>1</bitWidth>
            </field>
            <field>
              <name>FB18</name>
              <bitOffset>18</bitOffset>
              <bitWidth>1</bitWidth>
            </field>
            <field>
              <name>FB19</name>
              <bitOffset>19</bitOffset>
              <bitWidth>1</bitWidth>
            </field>
            <field>
              <name>FB20</name>
              <bitOffset>20</bitOffset>
              <bitWidth>1</bitWidth>
            </field>
            <field>
              <name>FB21</name>
              <bitOffset>21</bitOffset>
              <bitWidth>1</bitWidth>
            </field>
            <field>
              <name>FB22</name>
              <bitOffset>22</bitOffset>
              <bitWidth>1</bitWidth>
            </field>
            <field>
              <name>FB23</name>
              <bitOffset>23</bitOffset>
              <bitWidth>1</bitWidth>
            </field>
            <field>
              <name>FB24</name>
              <bitOffset>24</bitOffset>
              <bitWidth>1</bitWidth>
            </field>
            <field>
              <name>FB25</name>
              <bitOffset>25</bitOffset>
              <bitWidth>1</bitWidth>
            </field>
            <field>
              <name>FB26</name>
              <bitOffset>26</bitOffset>
              <bitWidth>1</bitWidth>
            </field>
            <field>
              <name>FB27</name>
              <bitOffset>27</bitOffset>
              <bitWidth>1</bitWidth>
            </field>
            <field>
              <name>FB28</name>
              <bitOffset>28</bitOffset>
              <bitWidth>1</bitWidth>
            </field>
            <field>
              <name>FB29</name>
              <bitOffset>29</bitOffset>
              <bitWidth>1</bitWidth>
            </field>
            <field>
              <name>FB30</name>
              <bitOffset>30</bitOffset>
              <bitWidth>1</bitWidth>
            </field>
            <field>
              <name>FB31</name>
              <bitOffset>31</bitOffset>
              <bitWidth>1</bitWidth>
            </field>
          </fields>
        </register>
        <register>
          <name>sFilterRegister.2.FR1</name>
          <addressOffset>0x250</addressOffset>
          <size>0x20</size>
          <fields>
            <field>
              <name>FB0</name>
              <bitOffset>0</bitOffset>
              <bitWidth>1</bitWidth>
            </field>
            <field>
              <name>FB1</name>
              <bitOffset>1</bitOffset>
              <bitWidth>1</bitWidth>
            </field>
            <field>
              <name>FB2</name>
              <bitOffset>2</bitOffset>
              <bitWidth>1</bitWidth>
            </field>
            <field>
              <name>FB3</name>
              <bitOffset>3</bitOffset>
              <bitWidth>1</bitWidth>
            </field>
            <field>
              <name>FB4</name>
              <bitOffset>4</bitOffset>
              <bitWidth>1</bitWidth>
            </field>
            <field>
              <name>FB5</name>
              <bitOffset>5</bitOffset>
              <bitWidth>1</bitWidth>
            </field>
            <field>
              <name>FB6</name>
              <bitOffset>6</bitOffset>
              <bitWidth>1</bitWidth>
            </field>
            <field>
              <name>FB7</name>
              <bitOffset>7</bitOffset>
              <bitWidth>1</bitWidth>
            </field>
            <field>
              <name>FB8</name>
              <bitOffset>8</bitOffset>
              <bitWidth>1</bitWidth>
            </field>
            <field>
              <name>FB9</name>
              <bitOffset>9</bitOffset>
              <bitWidth>1</bitWidth>
            </field>
            <field>
              <name>FB10</name>
              <bitOffset>10</bitOffset>
              <bitWidth>1</bitWidth>
            </field>
            <field>
              <name>FB11</name>
              <bitOffset>11</bitOffset>
              <bitWidth>1</bitWidth>
            </field>
            <field>
              <name>FB12</name>
              <bitOffset>12</bitOffset>
              <bitWidth>1</bitWidth>
            </field>
            <field>
              <name>FB13</name>
              <bitOffset>13</bitOffset>
              <bitWidth>1</bitWidth>
            </field>
            <field>
              <name>FB14</name>
              <bitOffset>14</bitOffset>
              <bitWidth>1</bitWidth>
            </field>
            <field>
              <name>FB15</name>
              <bitOffset>15</bitOffset>
              <bitWidth>1</bitWidth>
            </field>
            <field>
              <name>FB16</name>
              <bitOffset>16</bitOffset>
              <bitWidth>1</bitWidth>
            </field>
            <field>
              <name>FB17</name>
              <bitOffset>17</bitOffset>
              <bitWidth>1</bitWidth>
            </field>
            <field>
              <name>FB18</name>
              <bitOffset>18</bitOffset>
              <bitWidth>1</bitWidth>
            </field>
            <field>
              <name>FB19</name>
              <bitOffset>19</bitOffset>
              <bitWidth>1</bitWidth>
            </field>
            <field>
              <name>FB20</name>
              <bitOffset>20</bitOffset>
              <bitWidth>1</bitWidth>
            </field>
            <field>
              <name>FB21</name>
              <bitOffset>21</bitOffset>
              <bitWidth>1</bitWidth>
            </field>
            <field>
              <name>FB22</name>
              <bitOffset>22</bitOffset>
              <bitWidth>1</bitWidth>
            </field>
            <field>
              <name>FB23</name>
              <bitOffset>23</bitOffset>
              <bitWidth>1</bitWidth>
            </field>
            <field>
              <name>FB24</name>
              <bitOffset>24</bitOffset>
              <bitWidth>1</bitWidth>
            </field>
            <field>
              <name>FB25</name>
              <bitOffset>25</bitOffset>
              <bitWidth>1</bitWidth>
            </field>
            <field>
              <name>FB26</name>
              <bitOffset>26</bitOffset>
              <bitWidth>1</bitWidth>
            </field>
            <field>
              <name>FB27</name>
              <bitOffset>27</bitOffset>
              <bitWidth>1</bitWidth>
            </field>
            <field>
              <name>FB28</name>
              <bitOffset>28</bitOffset>
              <bitWidth>1</bitWidth>
            </field>
            <field>
              <name>FB29</name>
              <bitOffset>29</bitOffset>
              <bitWidth>1</bitWidth>
            </field>
            <field>
              <name>FB30</name>
              <bitOffset>30</bitOffset>
              <bitWidth>1</bitWidth>
            </field>
            <field>
              <name>FB31</name>
              <bitOffset>31</bitOffset>
              <bitWidth>1</bitWidth>
            </field>
          </fields>
        </register>
        <register>
          <name>sFilterRegister.2.FR2</name>
          <addressOffset>0x254</addressOffset>
          <size>0x20</size>
          <fields>
            <field>
              <name>FB0</name>
              <bitOffset>0</bitOffset>
              <bitWidth>1</bitWidth>
            </field>
            <field>
              <name>FB1</name>
              <bitOffset>1</bitOffset>
              <bitWidth>1</bitWidth>
            </field>
            <field>
              <name>FB2</name>
              <bitOffset>2</bitOffset>
              <bitWidth>1</bitWidth>
            </field>
            <field>
              <name>FB3</name>
              <bitOffset>3</bitOffset>
              <bitWidth>1</bitWidth>
            </field>
            <field>
              <name>FB4</name>
              <bitOffset>4</bitOffset>
              <bitWidth>1</bitWidth>
            </field>
            <field>
              <name>FB5</name>
              <bitOffset>5</bitOffset>
              <bitWidth>1</bitWidth>
            </field>
            <field>
              <name>FB6</name>
              <bitOffset>6</bitOffset>
              <bitWidth>1</bitWidth>
            </field>
            <field>
              <name>FB7</name>
              <bitOffset>7</bitOffset>
              <bitWidth>1</bitWidth>
            </field>
            <field>
              <name>FB8</name>
              <bitOffset>8</bitOffset>
              <bitWidth>1</bitWidth>
            </field>
            <field>
              <name>FB9</name>
              <bitOffset>9</bitOffset>
              <bitWidth>1</bitWidth>
            </field>
            <field>
              <name>FB10</name>
              <bitOffset>10</bitOffset>
              <bitWidth>1</bitWidth>
            </field>
            <field>
              <name>FB11</name>
              <bitOffset>11</bitOffset>
              <bitWidth>1</bitWidth>
            </field>
            <field>
              <name>FB12</name>
              <bitOffset>12</bitOffset>
              <bitWidth>1</bitWidth>
            </field>
            <field>
              <name>FB13</name>
              <bitOffset>13</bitOffset>
              <bitWidth>1</bitWidth>
            </field>
            <field>
              <name>FB14</name>
              <bitOffset>14</bitOffset>
              <bitWidth>1</bitWidth>
            </field>
            <field>
              <name>FB15</name>
              <bitOffset>15</bitOffset>
              <bitWidth>1</bitWidth>
            </field>
            <field>
              <name>FB16</name>
              <bitOffset>16</bitOffset>
              <bitWidth>1</bitWidth>
            </field>
            <field>
              <name>FB17</name>
              <bitOffset>17</bitOffset>
              <bitWidth>1</bitWidth>
            </field>
            <field>
              <name>FB18</name>
              <bitOffset>18</bitOffset>
              <bitWidth>1</bitWidth>
            </field>
            <field>
              <name>FB19</name>
              <bitOffset>19</bitOffset>
              <bitWidth>1</bitWidth>
            </field>
            <field>
              <name>FB20</name>
              <bitOffset>20</bitOffset>
              <bitWidth>1</bitWidth>
            </field>
            <field>
              <name>FB21</name>
              <bitOffset>21</bitOffset>
              <bitWidth>1</bitWidth>
            </field>
            <field>
              <name>FB22</name>
              <bitOffset>22</bitOffset>
              <bitWidth>1</bitWidth>
            </field>
            <field>
              <name>FB23</name>
              <bitOffset>23</bitOffset>
              <bitWidth>1</bitWidth>
            </field>
            <field>
              <name>FB24</name>
              <bitOffset>24</bitOffset>
              <bitWidth>1</bitWidth>
            </field>
            <field>
              <name>FB25</name>
              <bitOffset>25</bitOffset>
              <bitWidth>1</bitWidth>
            </field>
            <field>
              <name>FB26</name>
              <bitOffset>26</bitOffset>
              <bitWidth>1</bitWidth>
            </field>
            <field>
              <name>FB27</name>
              <bitOffset>27</bitOffset>
              <bitWidth>1</bitWidth>
            </field>
            <field>
              <name>FB28</name>
              <bitOffset>28</bitOffset>
              <bitWidth>1</bitWidth>
            </field>
            <field>
              <name>FB29</name>
              <bitOffset>29</bitOffset>
              <bitWidth>1</bitWidth>
            </field>
            <field>
              <name>FB30</name>
              <bitOffset>30</bitOffset>
              <bitWidth>1</bitWidth>
            </field>
            <field>
              <name>FB31</name>
              <bitOffset>31</bitOffset>
              <bitWidth>1</bitWidth>
            </field>
          </fields>
        </register>
        <register>
          <name>sFilterRegister.3.FR1</name>
          <addressOffset>0x258</addressOffset>
          <size>0x20</size>
          <fields>
            <field>
              <name>FB0</name>
              <bitOffset>0</bitOffset>
              <bitWidth>1</bitWidth>
            </field>
            <field>
              <name>FB1</name>
              <bitOffset>1</bitOffset>
              <bitWidth>1</bitWidth>
            </field>
            <field>
              <name>FB2</name>
              <bitOffset>2</bitOffset>
              <bitWidth>1</bitWidth>
            </field>
            <field>
              <name>FB3</name>
              <bitOffset>3</bitOffset>
              <bitWidth>1</bitWidth>
            </field>
            <field>
              <name>FB4</name>
              <bitOffset>4</bitOffset>
              <bitWidth>1</bitWidth>
            </field>
            <field>
              <name>FB5</name>
              <bitOffset>5</bitOffset>
              <bitWidth>1</bitWidth>
            </field>
            <field>
              <name>FB6</name>
              <bitOffset>6</bitOffset>
              <bitWidth>1</bitWidth>
            </field>
            <field>
              <name>FB7</name>
              <bitOffset>7</bitOffset>
              <bitWidth>1</bitWidth>
            </field>
            <field>
              <name>FB8</name>
              <bitOffset>8</bitOffset>
              <bitWidth>1</bitWidth>
            </field>
            <field>
              <name>FB9</name>
              <bitOffset>9</bitOffset>
              <bitWidth>1</bitWidth>
            </field>
            <field>
              <name>FB10</name>
              <bitOffset>10</bitOffset>
              <bitWidth>1</bitWidth>
            </field>
            <field>
              <name>FB11</name>
              <bitOffset>11</bitOffset>
              <bitWidth>1</bitWidth>
            </field>
            <field>
              <name>FB12</name>
              <bitOffset>12</bitOffset>
              <bitWidth>1</bitWidth>
            </field>
            <field>
              <name>FB13</name>
              <bitOffset>13</bitOffset>
              <bitWidth>1</bitWidth>
            </field>
            <field>
              <name>FB14</name>
              <bitOffset>14</bitOffset>
              <bitWidth>1</bitWidth>
            </field>
            <field>
              <name>FB15</name>
              <bitOffset>15</bitOffset>
              <bitWidth>1</bitWidth>
            </field>
            <field>
              <name>FB16</name>
              <bitOffset>16</bitOffset>
              <bitWidth>1</bitWidth>
            </field>
            <field>
              <name>FB17</name>
              <bitOffset>17</bitOffset>
              <bitWidth>1</bitWidth>
            </field>
            <field>
              <name>FB18</name>
              <bitOffset>18</bitOffset>
              <bitWidth>1</bitWidth>
            </field>
            <field>
              <name>FB19</name>
              <bitOffset>19</bitOffset>
              <bitWidth>1</bitWidth>
            </field>
            <field>
              <name>FB20</name>
              <bitOffset>20</bitOffset>
              <bitWidth>1</bitWidth>
            </field>
            <field>
              <name>FB21</name>
              <bitOffset>21</bitOffset>
              <bitWidth>1</bitWidth>
            </field>
            <field>
              <name>FB22</name>
              <bitOffset>22</bitOffset>
              <bitWidth>1</bitWidth>
            </field>
            <field>
              <name>FB23</name>
              <bitOffset>23</bitOffset>
              <bitWidth>1</bitWidth>
            </field>
            <field>
              <name>FB24</name>
              <bitOffset>24</bitOffset>
              <bitWidth>1</bitWidth>
            </field>
            <field>
              <name>FB25</name>
              <bitOffset>25</bitOffset>
              <bitWidth>1</bitWidth>
            </field>
            <field>
              <name>FB26</name>
              <bitOffset>26</bitOffset>
              <bitWidth>1</bitWidth>
            </field>
            <field>
              <name>FB27</name>
              <bitOffset>27</bitOffset>
              <bitWidth>1</bitWidth>
            </field>
            <field>
              <name>FB28</name>
              <bitOffset>28</bitOffset>
              <bitWidth>1</bitWidth>
            </field>
            <field>
              <name>FB29</name>
              <bitOffset>29</bitOffset>
              <bitWidth>1</bitWidth>
            </field>
            <field>
              <name>FB30</name>
              <bitOffset>30</bitOffset>
              <bitWidth>1</bitWidth>
            </field>
            <field>
              <name>FB31</name>
              <bitOffset>31</bitOffset>
              <bitWidth>1</bitWidth>
            </field>
          </fields>
        </register>
        <register>
          <name>sFilterRegister.3.FR2</name>
          <addressOffset>0x25c</addressOffset>
          <size>0x20</size>
          <fields>
            <field>
              <name>FB0</name>
              <bitOffset>0</bitOffset>
              <bitWidth>1</bitWidth>
            </field>
            <field>
              <name>FB1</name>
              <bitOffset>1</bitOffset>
              <bitWidth>1</bitWidth>
            </field>
            <field>
              <name>FB2</name>
              <bitOffset>2</bitOffset>
              <bitWidth>1</bitWidth>
            </field>
            <field>
              <name>FB3</name>
              <bitOffset>3</bitOffset>
              <bitWidth>1</bitWidth>
            </field>
            <field>
              <name>FB4</name>
              <bitOffset>4</bitOffset>
              <bitWidth>1</bitWidth>
            </field>
            <field>
              <name>FB5</name>
              <bitOffset>5</bitOffset>
              <bitWidth>1</bitWidth>
            </field>
            <field>
              <name>FB6</name>
              <bitOffset>6</bitOffset>
              <bitWidth>1</bitWidth>
            </field>
            <field>
              <name>FB7</name>
              <bitOffset>7</bitOffset>
              <bitWidth>1</bitWidth>
            </field>
            <field>
              <name>FB8</name>
              <bitOffset>8</bitOffset>
              <bitWidth>1</bitWidth>
            </field>
            <field>
              <name>FB9</name>
              <bitOffset>9</bitOffset>
              <bitWidth>1</bitWidth>
            </field>
            <field>
              <name>FB10</name>
              <bitOffset>10</bitOffset>
              <bitWidth>1</bitWidth>
            </field>
            <field>
              <name>FB11</name>
              <bitOffset>11</bitOffset>
              <bitWidth>1</bitWidth>
            </field>
            <field>
              <name>FB12</name>
              <bitOffset>12</bitOffset>
              <bitWidth>1</bitWidth>
            </field>
            <field>
              <name>FB13</name>
              <bitOffset>13</bitOffset>
              <bitWidth>1</bitWidth>
            </field>
            <field>
              <name>FB14</name>
              <bitOffset>14</bitOffset>
              <bitWidth>1</bitWidth>
            </field>
            <field>
              <name>FB15</name>
              <bitOffset>15</bitOffset>
              <bitWidth>1</bitWidth>
            </field>
            <field>
              <name>FB16</name>
              <bitOffset>16</bitOffset>
              <bitWidth>1</bitWidth>
            </field>
            <field>
              <name>FB17</name>
              <bitOffset>17</bitOffset>
              <bitWidth>1</bitWidth>
            </field>
            <field>
              <name>FB18</name>
              <bitOffset>18</bitOffset>
              <bitWidth>1</bitWidth>
            </field>
            <field>
              <name>FB19</name>
              <bitOffset>19</bitOffset>
              <bitWidth>1</bitWidth>
            </field>
            <field>
              <name>FB20</name>
              <bitOffset>20</bitOffset>
              <bitWidth>1</bitWidth>
            </field>
            <field>
              <name>FB21</name>
              <bitOffset>21</bitOffset>
              <bitWidth>1</bitWidth>
            </field>
            <field>
              <name>FB22</name>
              <bitOffset>22</bitOffset>
              <bitWidth>1</bitWidth>
            </field>
            <field>
              <name>FB23</name>
              <bitOffset>23</bitOffset>
              <bitWidth>1</bitWidth>
            </field>
            <field>
              <name>FB24</name>
              <bitOffset>24</bitOffset>
              <bitWidth>1</bitWidth>
            </field>
            <field>
              <name>FB25</name>
              <bitOffset>25</bitOffset>
              <bitWidth>1</bitWidth>
            </field>
            <field>
              <name>FB26</name>
              <bitOffset>26</bitOffset>
              <bitWidth>1</bitWidth>
            </field>
            <field>
              <name>FB27</name>
              <bitOffset>27</bitOffset>
              <bitWidth>1</bitWidth>
            </field>
            <field>
              <name>FB28</name>
              <bitOffset>28</bitOffset>
              <bitWidth>1</bitWidth>
            </field>
            <field>
              <name>FB29</name>
              <bitOffset>29</bitOffset>
              <bitWidth>1</bitWidth>
            </field>
            <field>
              <name>FB30</name>
              <bitOffset>30</bitOffset>
              <bitWidth>1</bitWidth>
            </field>
            <field>
              <name>FB31</name>
              <bitOffset>31</bitOffset>
              <bitWidth>1</bitWidth>
            </field>
          </fields>
        </register>
        <register>
          <name>sFilterRegister.4.FR1</name>
          <addressOffset>0x260</addressOffset>
          <size>0x20</size>
          <fields>
            <field>
              <name>FB0</name>
              <bitOffset>0</bitOffset>
              <bitWidth>1</bitWidth>
            </field>
            <field>
              <name>FB1</name>
              <bitOffset>1</bitOffset>
              <bitWidth>1</bitWidth>
            </field>
            <field>
              <name>FB2</name>
              <bitOffset>2</bitOffset>
              <bitWidth>1</bitWidth>
            </field>
            <field>
              <name>FB3</name>
              <bitOffset>3</bitOffset>
              <bitWidth>1</bitWidth>
            </field>
            <field>
              <name>FB4</name>
              <bitOffset>4</bitOffset>
              <bitWidth>1</bitWidth>
            </field>
            <field>
              <name>FB5</name>
              <bitOffset>5</bitOffset>
              <bitWidth>1</bitWidth>
            </field>
            <field>
              <name>FB6</name>
              <bitOffset>6</bitOffset>
              <bitWidth>1</bitWidth>
            </field>
            <field>
              <name>FB7</name>
              <bitOffset>7</bitOffset>
              <bitWidth>1</bitWidth>
            </field>
            <field>
              <name>FB8</name>
              <bitOffset>8</bitOffset>
              <bitWidth>1</bitWidth>
            </field>
            <field>
              <name>FB9</name>
              <bitOffset>9</bitOffset>
              <bitWidth>1</bitWidth>
            </field>
            <field>
              <name>FB10</name>
              <bitOffset>10</bitOffset>
              <bitWidth>1</bitWidth>
            </field>
            <field>
              <name>FB11</name>
              <bitOffset>11</bitOffset>
              <bitWidth>1</bitWidth>
            </field>
            <field>
              <name>FB12</name>
              <bitOffset>12</bitOffset>
              <bitWidth>1</bitWidth>
            </field>
            <field>
              <name>FB13</name>
              <bitOffset>13</bitOffset>
              <bitWidth>1</bitWidth>
            </field>
            <field>
              <name>FB14</name>
              <bitOffset>14</bitOffset>
              <bitWidth>1</bitWidth>
            </field>
            <field>
              <name>FB15</name>
              <bitOffset>15</bitOffset>
              <bitWidth>1</bitWidth>
            </field>
            <field>
              <name>FB16</name>
              <bitOffset>16</bitOffset>
              <bitWidth>1</bitWidth>
            </field>
            <field>
              <name>FB17</name>
              <bitOffset>17</bitOffset>
              <bitWidth>1</bitWidth>
            </field>
            <field>
              <name>FB18</name>
              <bitOffset>18</bitOffset>
              <bitWidth>1</bitWidth>
            </field>
            <field>
              <name>FB19</name>
              <bitOffset>19</bitOffset>
              <bitWidth>1</bitWidth>
            </field>
            <field>
              <name>FB20</name>
              <bitOffset>20</bitOffset>
              <bitWidth>1</bitWidth>
            </field>
            <field>
              <name>FB21</name>
              <bitOffset>21</bitOffset>
              <bitWidth>1</bitWidth>
            </field>
            <field>
              <name>FB22</name>
              <bitOffset>22</bitOffset>
              <bitWidth>1</bitWidth>
            </field>
            <field>
              <name>FB23</name>
              <bitOffset>23</bitOffset>
              <bitWidth>1</bitWidth>
            </field>
            <field>
              <name>FB24</name>
              <bitOffset>24</bitOffset>
              <bitWidth>1</bitWidth>
            </field>
            <field>
              <name>FB25</name>
              <bitOffset>25</bitOffset>
              <bitWidth>1</bitWidth>
            </field>
            <field>
              <name>FB26</name>
              <bitOffset>26</bitOffset>
              <bitWidth>1</bitWidth>
            </field>
            <field>
              <name>FB27</name>
              <bitOffset>27</bitOffset>
              <bitWidth>1</bitWidth>
            </field>
            <field>
              <name>FB28</name>
              <bitOffset>28</bitOffset>
              <bitWidth>1</bitWidth>
            </field>
            <field>
              <name>FB29</name>
              <bitOffset>29</bitOffset>
              <bitWidth>1</bitWidth>
            </field>
            <field>
              <name>FB30</name>
              <bitOffset>30</bitOffset>
              <bitWidth>1</bitWidth>
            </field>
            <field>
              <name>FB31</name>
              <bitOffset>31</bitOffset>
              <bitWidth>1</bitWidth>
            </field>
          </fields>
        </register>
        <register>
          <name>sFilterRegister.4.FR2</name>
          <addressOffset>0x264</addressOffset>
          <size>0x20</size>
          <fields>
            <field>
              <name>FB0</name>
              <bitOffset>0</bitOffset>
              <bitWidth>1</bitWidth>
            </field>
            <field>
              <name>FB1</name>
              <bitOffset>1</bitOffset>
              <bitWidth>1</bitWidth>
            </field>
            <field>
              <name>FB2</name>
              <bitOffset>2</bitOffset>
              <bitWidth>1</bitWidth>
            </field>
            <field>
              <name>FB3</name>
              <bitOffset>3</bitOffset>
              <bitWidth>1</bitWidth>
            </field>
            <field>
              <name>FB4</name>
              <bitOffset>4</bitOffset>
              <bitWidth>1</bitWidth>
            </field>
            <field>
              <name>FB5</name>
              <bitOffset>5</bitOffset>
              <bitWidth>1</bitWidth>
            </field>
            <field>
              <name>FB6</name>
              <bitOffset>6</bitOffset>
              <bitWidth>1</bitWidth>
            </field>
            <field>
              <name>FB7</name>
              <bitOffset>7</bitOffset>
              <bitWidth>1</bitWidth>
            </field>
            <field>
              <name>FB8</name>
              <bitOffset>8</bitOffset>
              <bitWidth>1</bitWidth>
            </field>
            <field>
              <name>FB9</name>
              <bitOffset>9</bitOffset>
              <bitWidth>1</bitWidth>
            </field>
            <field>
              <name>FB10</name>
              <bitOffset>10</bitOffset>
              <bitWidth>1</bitWidth>
            </field>
            <field>
              <name>FB11</name>
              <bitOffset>11</bitOffset>
              <bitWidth>1</bitWidth>
            </field>
            <field>
              <name>FB12</name>
              <bitOffset>12</bitOffset>
              <bitWidth>1</bitWidth>
            </field>
            <field>
              <name>FB13</name>
              <bitOffset>13</bitOffset>
              <bitWidth>1</bitWidth>
            </field>
            <field>
              <name>FB14</name>
              <bitOffset>14</bitOffset>
              <bitWidth>1</bitWidth>
            </field>
            <field>
              <name>FB15</name>
              <bitOffset>15</bitOffset>
              <bitWidth>1</bitWidth>
            </field>
            <field>
              <name>FB16</name>
              <bitOffset>16</bitOffset>
              <bitWidth>1</bitWidth>
            </field>
            <field>
              <name>FB17</name>
              <bitOffset>17</bitOffset>
              <bitWidth>1</bitWidth>
            </field>
            <field>
              <name>FB18</name>
              <bitOffset>18</bitOffset>
              <bitWidth>1</bitWidth>
            </field>
            <field>
              <name>FB19</name>
              <bitOffset>19</bitOffset>
              <bitWidth>1</bitWidth>
            </field>
            <field>
              <name>FB20</name>
              <bitOffset>20</bitOffset>
              <bitWidth>1</bitWidth>
            </field>
            <field>
              <name>FB21</name>
              <bitOffset>21</bitOffset>
              <bitWidth>1</bitWidth>
            </field>
            <field>
              <name>FB22</name>
              <bitOffset>22</bitOffset>
              <bitWidth>1</bitWidth>
            </field>
            <field>
              <name>FB23</name>
              <bitOffset>23</bitOffset>
              <bitWidth>1</bitWidth>
            </field>
            <field>
              <name>FB24</name>
              <bitOffset>24</bitOffset>
              <bitWidth>1</bitWidth>
            </field>
            <field>
              <name>FB25</name>
              <bitOffset>25</bitOffset>
              <bitWidth>1</bitWidth>
            </field>
            <field>
              <name>FB26</name>
              <bitOffset>26</bitOffset>
              <bitWidth>1</bitWidth>
            </field>
            <field>
              <name>FB27</name>
              <bitOffset>27</bitOffset>
              <bitWidth>1</bitWidth>
            </field>
            <field>
              <name>FB28</name>
              <bitOffset>28</bitOffset>
              <bitWidth>1</bitWidth>
            </field>
            <field>
              <name>FB29</name>
              <bitOffset>29</bitOffset>
              <bitWidth>1</bitWidth>
            </field>
            <field>
              <name>FB30</name>
              <bitOffset>30</bitOffset>
              <bitWidth>1</bitWidth>
            </field>
            <field>
              <name>FB31</name>
              <bitOffset>31</bitOffset>
              <bitWidth>1</bitWidth>
            </field>
          </fields>
        </register>
        <register>
          <name>sFilterRegister.5.FR1</name>
          <addressOffset>0x268</addressOffset>
          <size>0x20</size>
          <fields>
            <field>
              <name>FB0</name>
              <bitOffset>0</bitOffset>
              <bitWidth>1</bitWidth>
            </field>
            <field>
              <name>FB1</name>
              <bitOffset>1</bitOffset>
              <bitWidth>1</bitWidth>
            </field>
            <field>
              <name>FB2</name>
              <bitOffset>2</bitOffset>
              <bitWidth>1</bitWidth>
            </field>
            <field>
              <name>FB3</name>
              <bitOffset>3</bitOffset>
              <bitWidth>1</bitWidth>
            </field>
            <field>
              <name>FB4</name>
              <bitOffset>4</bitOffset>
              <bitWidth>1</bitWidth>
            </field>
            <field>
              <name>FB5</name>
              <bitOffset>5</bitOffset>
              <bitWidth>1</bitWidth>
            </field>
            <field>
              <name>FB6</name>
              <bitOffset>6</bitOffset>
              <bitWidth>1</bitWidth>
            </field>
            <field>
              <name>FB7</name>
              <bitOffset>7</bitOffset>
              <bitWidth>1</bitWidth>
            </field>
            <field>
              <name>FB8</name>
              <bitOffset>8</bitOffset>
              <bitWidth>1</bitWidth>
            </field>
            <field>
              <name>FB9</name>
              <bitOffset>9</bitOffset>
              <bitWidth>1</bitWidth>
            </field>
            <field>
              <name>FB10</name>
              <bitOffset>10</bitOffset>
              <bitWidth>1</bitWidth>
            </field>
            <field>
              <name>FB11</name>
              <bitOffset>11</bitOffset>
              <bitWidth>1</bitWidth>
            </field>
            <field>
              <name>FB12</name>
              <bitOffset>12</bitOffset>
              <bitWidth>1</bitWidth>
            </field>
            <field>
              <name>FB13</name>
              <bitOffset>13</bitOffset>
              <bitWidth>1</bitWidth>
            </field>
            <field>
              <name>FB14</name>
              <bitOffset>14</bitOffset>
              <bitWidth>1</bitWidth>
            </field>
            <field>
              <name>FB15</name>
              <bitOffset>15</bitOffset>
              <bitWidth>1</bitWidth>
            </field>
            <field>
              <name>FB16</name>
              <bitOffset>16</bitOffset>
              <bitWidth>1</bitWidth>
            </field>
            <field>
              <name>FB17</name>
              <bitOffset>17</bitOffset>
              <bitWidth>1</bitWidth>
            </field>
            <field>
              <name>FB18</name>
              <bitOffset>18</bitOffset>
              <bitWidth>1</bitWidth>
            </field>
            <field>
              <name>FB19</name>
              <bitOffset>19</bitOffset>
              <bitWidth>1</bitWidth>
            </field>
            <field>
              <name>FB20</name>
              <bitOffset>20</bitOffset>
              <bitWidth>1</bitWidth>
            </field>
            <field>
              <name>FB21</name>
              <bitOffset>21</bitOffset>
              <bitWidth>1</bitWidth>
            </field>
            <field>
              <name>FB22</name>
              <bitOffset>22</bitOffset>
              <bitWidth>1</bitWidth>
            </field>
            <field>
              <name>FB23</name>
              <bitOffset>23</bitOffset>
              <bitWidth>1</bitWidth>
            </field>
            <field>
              <name>FB24</name>
              <bitOffset>24</bitOffset>
              <bitWidth>1</bitWidth>
            </field>
            <field>
              <name>FB25</name>
              <bitOffset>25</bitOffset>
              <bitWidth>1</bitWidth>
            </field>
            <field>
              <name>FB26</name>
              <bitOffset>26</bitOffset>
              <bitWidth>1</bitWidth>
            </field>
            <field>
              <name>FB27</name>
              <bitOffset>27</bitOffset>
              <bitWidth>1</bitWidth>
            </field>
            <field>
              <name>FB28</name>
              <bitOffset>28</bitOffset>
              <bitWidth>1</bitWidth>
            </field>
            <field>
              <name>FB29</name>
              <bitOffset>29</bitOffset>
              <bitWidth>1</bitWidth>
            </field>
            <field>
              <name>FB30</name>
              <bitOffset>30</bitOffset>
              <bitWidth>1</bitWidth>
            </field>
            <field>
              <name>FB31</name>
              <bitOffset>31</bitOffset>
              <bitWidth>1</bitWidth>
            </field>
          </fields>
        </register>
        <register>
          <name>sFilterRegister.5.FR2</name>
          <addressOffset>0x26c</addressOffset>
          <size>0x20</size>
          <fields>
            <field>
              <name>FB0</name>
              <bitOffset>0</bitOffset>
              <bitWidth>1</bitWidth>
            </field>
            <field>
              <name>FB1</name>
              <bitOffset>1</bitOffset>
              <bitWidth>1</bitWidth>
            </field>
            <field>
              <name>FB2</name>
              <bitOffset>2</bitOffset>
              <bitWidth>1</bitWidth>
            </field>
            <field>
              <name>FB3</name>
              <bitOffset>3</bitOffset>
              <bitWidth>1</bitWidth>
            </field>
            <field>
              <name>FB4</name>
              <bitOffset>4</bitOffset>
              <bitWidth>1</bitWidth>
            </field>
            <field>
              <name>FB5</name>
              <bitOffset>5</bitOffset>
              <bitWidth>1</bitWidth>
            </field>
            <field>
              <name>FB6</name>
              <bitOffset>6</bitOffset>
              <bitWidth>1</bitWidth>
            </field>
            <field>
              <name>FB7</name>
              <bitOffset>7</bitOffset>
              <bitWidth>1</bitWidth>
            </field>
            <field>
              <name>FB8</name>
              <bitOffset>8</bitOffset>
              <bitWidth>1</bitWidth>
            </field>
            <field>
              <name>FB9</name>
              <bitOffset>9</bitOffset>
              <bitWidth>1</bitWidth>
            </field>
            <field>
              <name>FB10</name>
              <bitOffset>10</bitOffset>
              <bitWidth>1</bitWidth>
            </field>
            <field>
              <name>FB11</name>
              <bitOffset>11</bitOffset>
              <bitWidth>1</bitWidth>
            </field>
            <field>
              <name>FB12</name>
              <bitOffset>12</bitOffset>
              <bitWidth>1</bitWidth>
            </field>
            <field>
              <name>FB13</name>
              <bitOffset>13</bitOffset>
              <bitWidth>1</bitWidth>
            </field>
            <field>
              <name>FB14</name>
              <bitOffset>14</bitOffset>
              <bitWidth>1</bitWidth>
            </field>
            <field>
              <name>FB15</name>
              <bitOffset>15</bitOffset>
              <bitWidth>1</bitWidth>
            </field>
            <field>
              <name>FB16</name>
              <bitOffset>16</bitOffset>
              <bitWidth>1</bitWidth>
            </field>
            <field>
              <name>FB17</name>
              <bitOffset>17</bitOffset>
              <bitWidth>1</bitWidth>
            </field>
            <field>
              <name>FB18</name>
              <bitOffset>18</bitOffset>
              <bitWidth>1</bitWidth>
            </field>
            <field>
              <name>FB19</name>
              <bitOffset>19</bitOffset>
              <bitWidth>1</bitWidth>
            </field>
            <field>
              <name>FB20</name>
              <bitOffset>20</bitOffset>
              <bitWidth>1</bitWidth>
            </field>
            <field>
              <name>FB21</name>
              <bitOffset>21</bitOffset>
              <bitWidth>1</bitWidth>
            </field>
            <field>
              <name>FB22</name>
              <bitOffset>22</bitOffset>
              <bitWidth>1</bitWidth>
            </field>
            <field>
              <name>FB23</name>
              <bitOffset>23</bitOffset>
              <bitWidth>1</bitWidth>
            </field>
            <field>
              <name>FB24</name>
              <bitOffset>24</bitOffset>
              <bitWidth>1</bitWidth>
            </field>
            <field>
              <name>FB25</name>
              <bitOffset>25</bitOffset>
              <bitWidth>1</bitWidth>
            </field>
            <field>
              <name>FB26</name>
              <bitOffset>26</bitOffset>
              <bitWidth>1</bitWidth>
            </field>
            <field>
              <name>FB27</name>
              <bitOffset>27</bitOffset>
              <bitWidth>1</bitWidth>
            </field>
            <field>
              <name>FB28</name>
              <bitOffset>28</bitOffset>
              <bitWidth>1</bitWidth>
            </field>
            <field>
              <name>FB29</name>
              <bitOffset>29</bitOffset>
              <bitWidth>1</bitWidth>
            </field>
            <field>
              <name>FB30</name>
              <bitOffset>30</bitOffset>
              <bitWidth>1</bitWidth>
            </field>
            <field>
              <name>FB31</name>
              <bitOffset>31</bitOffset>
              <bitWidth>1</bitWidth>
            </field>
          </fields>
        </register>
        <register>
          <name>sFilterRegister.6.FR1</name>
          <addressOffset>0x270</addressOffset>
          <size>0x20</size>
          <fields>
            <field>
              <name>FB0</name>
              <bitOffset>0</bitOffset>
              <bitWidth>1</bitWidth>
            </field>
            <field>
              <name>FB1</name>
              <bitOffset>1</bitOffset>
              <bitWidth>1</bitWidth>
            </field>
            <field>
              <name>FB2</name>
              <bitOffset>2</bitOffset>
              <bitWidth>1</bitWidth>
            </field>
            <field>
              <name>FB3</name>
              <bitOffset>3</bitOffset>
              <bitWidth>1</bitWidth>
            </field>
            <field>
              <name>FB4</name>
              <bitOffset>4</bitOffset>
              <bitWidth>1</bitWidth>
            </field>
            <field>
              <name>FB5</name>
              <bitOffset>5</bitOffset>
              <bitWidth>1</bitWidth>
            </field>
            <field>
              <name>FB6</name>
              <bitOffset>6</bitOffset>
              <bitWidth>1</bitWidth>
            </field>
            <field>
              <name>FB7</name>
              <bitOffset>7</bitOffset>
              <bitWidth>1</bitWidth>
            </field>
            <field>
              <name>FB8</name>
              <bitOffset>8</bitOffset>
              <bitWidth>1</bitWidth>
            </field>
            <field>
              <name>FB9</name>
              <bitOffset>9</bitOffset>
              <bitWidth>1</bitWidth>
            </field>
            <field>
              <name>FB10</name>
              <bitOffset>10</bitOffset>
              <bitWidth>1</bitWidth>
            </field>
            <field>
              <name>FB11</name>
              <bitOffset>11</bitOffset>
              <bitWidth>1</bitWidth>
            </field>
            <field>
              <name>FB12</name>
              <bitOffset>12</bitOffset>
              <bitWidth>1</bitWidth>
            </field>
            <field>
              <name>FB13</name>
              <bitOffset>13</bitOffset>
              <bitWidth>1</bitWidth>
            </field>
            <field>
              <name>FB14</name>
              <bitOffset>14</bitOffset>
              <bitWidth>1</bitWidth>
            </field>
            <field>
              <name>FB15</name>
              <bitOffset>15</bitOffset>
              <bitWidth>1</bitWidth>
            </field>
            <field>
              <name>FB16</name>
              <bitOffset>16</bitOffset>
              <bitWidth>1</bitWidth>
            </field>
            <field>
              <name>FB17</name>
              <bitOffset>17</bitOffset>
              <bitWidth>1</bitWidth>
            </field>
            <field>
              <name>FB18</name>
              <bitOffset>18</bitOffset>
              <bitWidth>1</bitWidth>
            </field>
            <field>
              <name>FB19</name>
              <bitOffset>19</bitOffset>
              <bitWidth>1</bitWidth>
            </field>
            <field>
              <name>FB20</name>
              <bitOffset>20</bitOffset>
              <bitWidth>1</bitWidth>
            </field>
            <field>
              <name>FB21</name>
              <bitOffset>21</bitOffset>
              <bitWidth>1</bitWidth>
            </field>
            <field>
              <name>FB22</name>
              <bitOffset>22</bitOffset>
              <bitWidth>1</bitWidth>
            </field>
            <field>
              <name>FB23</name>
              <bitOffset>23</bitOffset>
              <bitWidth>1</bitWidth>
            </field>
            <field>
              <name>FB24</name>
              <bitOffset>24</bitOffset>
              <bitWidth>1</bitWidth>
            </field>
            <field>
              <name>FB25</name>
              <bitOffset>25</bitOffset>
              <bitWidth>1</bitWidth>
            </field>
            <field>
              <name>FB26</name>
              <bitOffset>26</bitOffset>
              <bitWidth>1</bitWidth>
            </field>
            <field>
              <name>FB27</name>
              <bitOffset>27</bitOffset>
              <bitWidth>1</bitWidth>
            </field>
            <field>
              <name>FB28</name>
              <bitOffset>28</bitOffset>
              <bitWidth>1</bitWidth>
            </field>
            <field>
              <name>FB29</name>
              <bitOffset>29</bitOffset>
              <bitWidth>1</bitWidth>
            </field>
            <field>
              <name>FB30</name>
              <bitOffset>30</bitOffset>
              <bitWidth>1</bitWidth>
            </field>
            <field>
              <name>FB31</name>
              <bitOffset>31</bitOffset>
              <bitWidth>1</bitWidth>
            </field>
          </fields>
        </register>
        <register>
          <name>sFilterRegister.6.FR2</name>
          <addressOffset>0x274</addressOffset>
          <size>0x20</size>
          <fields>
            <field>
              <name>FB0</name>
              <bitOffset>0</bitOffset>
              <bitWidth>1</bitWidth>
            </field>
            <field>
              <name>FB1</name>
              <bitOffset>1</bitOffset>
              <bitWidth>1</bitWidth>
            </field>
            <field>
              <name>FB2</name>
              <bitOffset>2</bitOffset>
              <bitWidth>1</bitWidth>
            </field>
            <field>
              <name>FB3</name>
              <bitOffset>3</bitOffset>
              <bitWidth>1</bitWidth>
            </field>
            <field>
              <name>FB4</name>
              <bitOffset>4</bitOffset>
              <bitWidth>1</bitWidth>
            </field>
            <field>
              <name>FB5</name>
              <bitOffset>5</bitOffset>
              <bitWidth>1</bitWidth>
            </field>
            <field>
              <name>FB6</name>
              <bitOffset>6</bitOffset>
              <bitWidth>1</bitWidth>
            </field>
            <field>
              <name>FB7</name>
              <bitOffset>7</bitOffset>
              <bitWidth>1</bitWidth>
            </field>
            <field>
              <name>FB8</name>
              <bitOffset>8</bitOffset>
              <bitWidth>1</bitWidth>
            </field>
            <field>
              <name>FB9</name>
              <bitOffset>9</bitOffset>
              <bitWidth>1</bitWidth>
            </field>
            <field>
              <name>FB10</name>
              <bitOffset>10</bitOffset>
              <bitWidth>1</bitWidth>
            </field>
            <field>
              <name>FB11</name>
              <bitOffset>11</bitOffset>
              <bitWidth>1</bitWidth>
            </field>
            <field>
              <name>FB12</name>
              <bitOffset>12</bitOffset>
              <bitWidth>1</bitWidth>
            </field>
            <field>
              <name>FB13</name>
              <bitOffset>13</bitOffset>
              <bitWidth>1</bitWidth>
            </field>
            <field>
              <name>FB14</name>
              <bitOffset>14</bitOffset>
              <bitWidth>1</bitWidth>
            </field>
            <field>
              <name>FB15</name>
              <bitOffset>15</bitOffset>
              <bitWidth>1</bitWidth>
            </field>
            <field>
              <name>FB16</name>
              <bitOffset>16</bitOffset>
              <bitWidth>1</bitWidth>
            </field>
            <field>
              <name>FB17</name>
              <bitOffset>17</bitOffset>
              <bitWidth>1</bitWidth>
            </field>
            <field>
              <name>FB18</name>
              <bitOffset>18</bitOffset>
              <bitWidth>1</bitWidth>
            </field>
            <field>
              <name>FB19</name>
              <bitOffset>19</bitOffset>
              <bitWidth>1</bitWidth>
            </field>
            <field>
              <name>FB20</name>
              <bitOffset>20</bitOffset>
              <bitWidth>1</bitWidth>
            </field>
            <field>
              <name>FB21</name>
              <bitOffset>21</bitOffset>
              <bitWidth>1</bitWidth>
            </field>
            <field>
              <name>FB22</name>
              <bitOffset>22</bitOffset>
              <bitWidth>1</bitWidth>
            </field>
            <field>
              <name>FB23</name>
              <bitOffset>23</bitOffset>
              <bitWidth>1</bitWidth>
            </field>
            <field>
              <name>FB24</name>
              <bitOffset>24</bitOffset>
              <bitWidth>1</bitWidth>
            </field>
            <field>
              <name>FB25</name>
              <bitOffset>25</bitOffset>
              <bitWidth>1</bitWidth>
            </field>
            <field>
              <name>FB26</name>
              <bitOffset>26</bitOffset>
              <bitWidth>1</bitWidth>
            </field>
            <field>
              <name>FB27</name>
              <bitOffset>27</bitOffset>
              <bitWidth>1</bitWidth>
            </field>
            <field>
              <name>FB28</name>
              <bitOffset>28</bitOffset>
              <bitWidth>1</bitWidth>
            </field>
            <field>
              <name>FB29</name>
              <bitOffset>29</bitOffset>
              <bitWidth>1</bitWidth>
            </field>
            <field>
              <name>FB30</name>
              <bitOffset>30</bitOffset>
              <bitWidth>1</bitWidth>
            </field>
            <field>
              <name>FB31</name>
              <bitOffset>31</bitOffset>
              <bitWidth>1</bitWidth>
            </field>
          </fields>
        </register>
        <register>
          <name>sFilterRegister.7.FR1</name>
          <addressOffset>0x278</addressOffset>
          <size>0x20</size>
          <fields>
            <field>
              <name>FB0</name>
              <bitOffset>0</bitOffset>
              <bitWidth>1</bitWidth>
            </field>
            <field>
              <name>FB1</name>
              <bitOffset>1</bitOffset>
              <bitWidth>1</bitWidth>
            </field>
            <field>
              <name>FB2</name>
              <bitOffset>2</bitOffset>
              <bitWidth>1</bitWidth>
            </field>
            <field>
              <name>FB3</name>
              <bitOffset>3</bitOffset>
              <bitWidth>1</bitWidth>
            </field>
            <field>
              <name>FB4</name>
              <bitOffset>4</bitOffset>
              <bitWidth>1</bitWidth>
            </field>
            <field>
              <name>FB5</name>
              <bitOffset>5</bitOffset>
              <bitWidth>1</bitWidth>
            </field>
            <field>
              <name>FB6</name>
              <bitOffset>6</bitOffset>
              <bitWidth>1</bitWidth>
            </field>
            <field>
              <name>FB7</name>
              <bitOffset>7</bitOffset>
              <bitWidth>1</bitWidth>
            </field>
            <field>
              <name>FB8</name>
              <bitOffset>8</bitOffset>
              <bitWidth>1</bitWidth>
            </field>
            <field>
              <name>FB9</name>
              <bitOffset>9</bitOffset>
              <bitWidth>1</bitWidth>
            </field>
            <field>
              <name>FB10</name>
              <bitOffset>10</bitOffset>
              <bitWidth>1</bitWidth>
            </field>
            <field>
              <name>FB11</name>
              <bitOffset>11</bitOffset>
              <bitWidth>1</bitWidth>
            </field>
            <field>
              <name>FB12</name>
              <bitOffset>12</bitOffset>
              <bitWidth>1</bitWidth>
            </field>
            <field>
              <name>FB13</name>
              <bitOffset>13</bitOffset>
              <bitWidth>1</bitWidth>
            </field>
            <field>
              <name>FB14</name>
              <bitOffset>14</bitOffset>
              <bitWidth>1</bitWidth>
            </field>
            <field>
              <name>FB15</name>
              <bitOffset>15</bitOffset>
              <bitWidth>1</bitWidth>
            </field>
            <field>
              <name>FB16</name>
              <bitOffset>16</bitOffset>
              <bitWidth>1</bitWidth>
            </field>
            <field>
              <name>FB17</name>
              <bitOffset>17</bitOffset>
              <bitWidth>1</bitWidth>
            </field>
            <field>
              <name>FB18</name>
              <bitOffset>18</bitOffset>
              <bitWidth>1</bitWidth>
            </field>
            <field>
              <name>FB19</name>
              <bitOffset>19</bitOffset>
              <bitWidth>1</bitWidth>
            </field>
            <field>
              <name>FB20</name>
              <bitOffset>20</bitOffset>
              <bitWidth>1</bitWidth>
            </field>
            <field>
              <name>FB21</name>
              <bitOffset>21</bitOffset>
              <bitWidth>1</bitWidth>
            </field>
            <field>
              <name>FB22</name>
              <bitOffset>22</bitOffset>
              <bitWidth>1</bitWidth>
            </field>
            <field>
              <name>FB23</name>
              <bitOffset>23</bitOffset>
              <bitWidth>1</bitWidth>
            </field>
            <field>
              <name>FB24</name>
              <bitOffset>24</bitOffset>
              <bitWidth>1</bitWidth>
            </field>
            <field>
              <name>FB25</name>
              <bitOffset>25</bitOffset>
              <bitWidth>1</bitWidth>
            </field>
            <field>
              <name>FB26</name>
              <bitOffset>26</bitOffset>
              <bitWidth>1</bitWidth>
            </field>
            <field>
              <name>FB27</name>
              <bitOffset>27</bitOffset>
              <bitWidth>1</bitWidth>
            </field>
            <field>
              <name>FB28</name>
              <bitOffset>28</bitOffset>
              <bitWidth>1</bitWidth>
            </field>
            <field>
              <name>FB29</name>
              <bitOffset>29</bitOffset>
              <bitWidth>1</bitWidth>
            </field>
            <field>
              <name>FB30</name>
              <bitOffset>30</bitOffset>
              <bitWidth>1</bitWidth>
            </field>
            <field>
              <name>FB31</name>
              <bitOffset>31</bitOffset>
              <bitWidth>1</bitWidth>
            </field>
          </fields>
        </register>
        <register>
          <name>sFilterRegister.7.FR2</name>
          <addressOffset>0x27c</addressOffset>
          <size>0x20</size>
          <fields>
            <field>
              <name>FB0</name>
              <bitOffset>0</bitOffset>
              <bitWidth>1</bitWidth>
            </field>
            <field>
              <name>FB1</name>
              <bitOffset>1</bitOffset>
              <bitWidth>1</bitWidth>
            </field>
            <field>
              <name>FB2</name>
              <bitOffset>2</bitOffset>
              <bitWidth>1</bitWidth>
            </field>
            <field>
              <name>FB3</name>
              <bitOffset>3</bitOffset>
              <bitWidth>1</bitWidth>
            </field>
            <field>
              <name>FB4</name>
              <bitOffset>4</bitOffset>
              <bitWidth>1</bitWidth>
            </field>
            <field>
              <name>FB5</name>
              <bitOffset>5</bitOffset>
              <bitWidth>1</bitWidth>
            </field>
            <field>
              <name>FB6</name>
              <bitOffset>6</bitOffset>
              <bitWidth>1</bitWidth>
            </field>
            <field>
              <name>FB7</name>
              <bitOffset>7</bitOffset>
              <bitWidth>1</bitWidth>
            </field>
            <field>
              <name>FB8</name>
              <bitOffset>8</bitOffset>
              <bitWidth>1</bitWidth>
            </field>
            <field>
              <name>FB9</name>
              <bitOffset>9</bitOffset>
              <bitWidth>1</bitWidth>
            </field>
            <field>
              <name>FB10</name>
              <bitOffset>10</bitOffset>
              <bitWidth>1</bitWidth>
            </field>
            <field>
              <name>FB11</name>
              <bitOffset>11</bitOffset>
              <bitWidth>1</bitWidth>
            </field>
            <field>
              <name>FB12</name>
              <bitOffset>12</bitOffset>
              <bitWidth>1</bitWidth>
            </field>
            <field>
              <name>FB13</name>
              <bitOffset>13</bitOffset>
              <bitWidth>1</bitWidth>
            </field>
            <field>
              <name>FB14</name>
              <bitOffset>14</bitOffset>
              <bitWidth>1</bitWidth>
            </field>
            <field>
              <name>FB15</name>
              <bitOffset>15</bitOffset>
              <bitWidth>1</bitWidth>
            </field>
            <field>
              <name>FB16</name>
              <bitOffset>16</bitOffset>
              <bitWidth>1</bitWidth>
            </field>
            <field>
              <name>FB17</name>
              <bitOffset>17</bitOffset>
              <bitWidth>1</bitWidth>
            </field>
            <field>
              <name>FB18</name>
              <bitOffset>18</bitOffset>
              <bitWidth>1</bitWidth>
            </field>
            <field>
              <name>FB19</name>
              <bitOffset>19</bitOffset>
              <bitWidth>1</bitWidth>
            </field>
            <field>
              <name>FB20</name>
              <bitOffset>20</bitOffset>
              <bitWidth>1</bitWidth>
            </field>
            <field>
              <name>FB21</name>
              <bitOffset>21</bitOffset>
              <bitWidth>1</bitWidth>
            </field>
            <field>
              <name>FB22</name>
              <bitOffset>22</bitOffset>
              <bitWidth>1</bitWidth>
            </field>
            <field>
              <name>FB23</name>
              <bitOffset>23</bitOffset>
              <bitWidth>1</bitWidth>
            </field>
            <field>
              <name>FB24</name>
              <bitOffset>24</bitOffset>
              <bitWidth>1</bitWidth>
            </field>
            <field>
              <name>FB25</name>
              <bitOffset>25</bitOffset>
              <bitWidth>1</bitWidth>
            </field>
            <field>
              <name>FB26</name>
              <bitOffset>26</bitOffset>
              <bitWidth>1</bitWidth>
            </field>
            <field>
              <name>FB27</name>
              <bitOffset>27</bitOffset>
              <bitWidth>1</bitWidth>
            </field>
            <field>
              <name>FB28</name>
              <bitOffset>28</bitOffset>
              <bitWidth>1</bitWidth>
            </field>
            <field>
              <name>FB29</name>
              <bitOffset>29</bitOffset>
              <bitWidth>1</bitWidth>
            </field>
            <field>
              <name>FB30</name>
              <bitOffset>30</bitOffset>
              <bitWidth>1</bitWidth>
            </field>
            <field>
              <name>FB31</name>
              <bitOffset>31</bitOffset>
              <bitWidth>1</bitWidth>
            </field>
          </fields>
        </register>
        <register>
          <name>sFilterRegister.8.FR1</name>
          <addressOffset>0x280</addressOffset>
          <size>0x20</size>
          <fields>
            <field>
              <name>FB0</name>
              <bitOffset>0</bitOffset>
              <bitWidth>1</bitWidth>
            </field>
            <field>
              <name>FB1</name>
              <bitOffset>1</bitOffset>
              <bitWidth>1</bitWidth>
            </field>
            <field>
              <name>FB2</name>
              <bitOffset>2</bitOffset>
              <bitWidth>1</bitWidth>
            </field>
            <field>
              <name>FB3</name>
              <bitOffset>3</bitOffset>
              <bitWidth>1</bitWidth>
            </field>
            <field>
              <name>FB4</name>
              <bitOffset>4</bitOffset>
              <bitWidth>1</bitWidth>
            </field>
            <field>
              <name>FB5</name>
              <bitOffset>5</bitOffset>
              <bitWidth>1</bitWidth>
            </field>
            <field>
              <name>FB6</name>
              <bitOffset>6</bitOffset>
              <bitWidth>1</bitWidth>
            </field>
            <field>
              <name>FB7</name>
              <bitOffset>7</bitOffset>
              <bitWidth>1</bitWidth>
            </field>
            <field>
              <name>FB8</name>
              <bitOffset>8</bitOffset>
              <bitWidth>1</bitWidth>
            </field>
            <field>
              <name>FB9</name>
              <bitOffset>9</bitOffset>
              <bitWidth>1</bitWidth>
            </field>
            <field>
              <name>FB10</name>
              <bitOffset>10</bitOffset>
              <bitWidth>1</bitWidth>
            </field>
            <field>
              <name>FB11</name>
              <bitOffset>11</bitOffset>
              <bitWidth>1</bitWidth>
            </field>
            <field>
              <name>FB12</name>
              <bitOffset>12</bitOffset>
              <bitWidth>1</bitWidth>
            </field>
            <field>
              <name>FB13</name>
              <bitOffset>13</bitOffset>
              <bitWidth>1</bitWidth>
            </field>
            <field>
              <name>FB14</name>
              <bitOffset>14</bitOffset>
              <bitWidth>1</bitWidth>
            </field>
            <field>
              <name>FB15</name>
              <bitOffset>15</bitOffset>
              <bitWidth>1</bitWidth>
            </field>
            <field>
              <name>FB16</name>
              <bitOffset>16</bitOffset>
              <bitWidth>1</bitWidth>
            </field>
            <field>
              <name>FB17</name>
              <bitOffset>17</bitOffset>
              <bitWidth>1</bitWidth>
            </field>
            <field>
              <name>FB18</name>
              <bitOffset>18</bitOffset>
              <bitWidth>1</bitWidth>
            </field>
            <field>
              <name>FB19</name>
              <bitOffset>19</bitOffset>
              <bitWidth>1</bitWidth>
            </field>
            <field>
              <name>FB20</name>
              <bitOffset>20</bitOffset>
              <bitWidth>1</bitWidth>
            </field>
            <field>
              <name>FB21</name>
              <bitOffset>21</bitOffset>
              <bitWidth>1</bitWidth>
            </field>
            <field>
              <name>FB22</name>
              <bitOffset>22</bitOffset>
              <bitWidth>1</bitWidth>
            </field>
            <field>
              <name>FB23</name>
              <bitOffset>23</bitOffset>
              <bitWidth>1</bitWidth>
            </field>
            <field>
              <name>FB24</name>
              <bitOffset>24</bitOffset>
              <bitWidth>1</bitWidth>
            </field>
            <field>
              <name>FB25</name>
              <bitOffset>25</bitOffset>
              <bitWidth>1</bitWidth>
            </field>
            <field>
              <name>FB26</name>
              <bitOffset>26</bitOffset>
              <bitWidth>1</bitWidth>
            </field>
            <field>
              <name>FB27</name>
              <bitOffset>27</bitOffset>
              <bitWidth>1</bitWidth>
            </field>
            <field>
              <name>FB28</name>
              <bitOffset>28</bitOffset>
              <bitWidth>1</bitWidth>
            </field>
            <field>
              <name>FB29</name>
              <bitOffset>29</bitOffset>
              <bitWidth>1</bitWidth>
            </field>
            <field>
              <name>FB30</name>
              <bitOffset>30</bitOffset>
              <bitWidth>1</bitWidth>
            </field>
            <field>
              <name>FB31</name>
              <bitOffset>31</bitOffset>
              <bitWidth>1</bitWidth>
            </field>
          </fields>
        </register>
        <register>
          <name>sFilterRegister.8.FR2</name>
          <addressOffset>0x284</addressOffset>
          <size>0x20</size>
          <fields>
            <field>
              <name>FB0</name>
              <bitOffset>0</bitOffset>
              <bitWidth>1</bitWidth>
            </field>
            <field>
              <name>FB1</name>
              <bitOffset>1</bitOffset>
              <bitWidth>1</bitWidth>
            </field>
            <field>
              <name>FB2</name>
              <bitOffset>2</bitOffset>
              <bitWidth>1</bitWidth>
            </field>
            <field>
              <name>FB3</name>
              <bitOffset>3</bitOffset>
              <bitWidth>1</bitWidth>
            </field>
            <field>
              <name>FB4</name>
              <bitOffset>4</bitOffset>
              <bitWidth>1</bitWidth>
            </field>
            <field>
              <name>FB5</name>
              <bitOffset>5</bitOffset>
              <bitWidth>1</bitWidth>
            </field>
            <field>
              <name>FB6</name>
              <bitOffset>6</bitOffset>
              <bitWidth>1</bitWidth>
            </field>
            <field>
              <name>FB7</name>
              <bitOffset>7</bitOffset>
              <bitWidth>1</bitWidth>
            </field>
            <field>
              <name>FB8</name>
              <bitOffset>8</bitOffset>
              <bitWidth>1</bitWidth>
            </field>
            <field>
              <name>FB9</name>
              <bitOffset>9</bitOffset>
              <bitWidth>1</bitWidth>
            </field>
            <field>
              <name>FB10</name>
              <bitOffset>10</bitOffset>
              <bitWidth>1</bitWidth>
            </field>
            <field>
              <name>FB11</name>
              <bitOffset>11</bitOffset>
              <bitWidth>1</bitWidth>
            </field>
            <field>
              <name>FB12</name>
              <bitOffset>12</bitOffset>
              <bitWidth>1</bitWidth>
            </field>
            <field>
              <name>FB13</name>
              <bitOffset>13</bitOffset>
              <bitWidth>1</bitWidth>
            </field>
            <field>
              <name>FB14</name>
              <bitOffset>14</bitOffset>
              <bitWidth>1</bitWidth>
            </field>
            <field>
              <name>FB15</name>
              <bitOffset>15</bitOffset>
              <bitWidth>1</bitWidth>
            </field>
            <field>
              <name>FB16</name>
              <bitOffset>16</bitOffset>
              <bitWidth>1</bitWidth>
            </field>
            <field>
              <name>FB17</name>
              <bitOffset>17</bitOffset>
              <bitWidth>1</bitWidth>
            </field>
            <field>
              <name>FB18</name>
              <bitOffset>18</bitOffset>
              <bitWidth>1</bitWidth>
            </field>
            <field>
              <name>FB19</name>
              <bitOffset>19</bitOffset>
              <bitWidth>1</bitWidth>
            </field>
            <field>
              <name>FB20</name>
              <bitOffset>20</bitOffset>
              <bitWidth>1</bitWidth>
            </field>
            <field>
              <name>FB21</name>
              <bitOffset>21</bitOffset>
              <bitWidth>1</bitWidth>
            </field>
            <field>
              <name>FB22</name>
              <bitOffset>22</bitOffset>
              <bitWidth>1</bitWidth>
            </field>
            <field>
              <name>FB23</name>
              <bitOffset>23</bitOffset>
              <bitWidth>1</bitWidth>
            </field>
            <field>
              <name>FB24</name>
              <bitOffset>24</bitOffset>
              <bitWidth>1</bitWidth>
            </field>
            <field>
              <name>FB25</name>
              <bitOffset>25</bitOffset>
              <bitWidth>1</bitWidth>
            </field>
            <field>
              <name>FB26</name>
              <bitOffset>26</bitOffset>
              <bitWidth>1</bitWidth>
            </field>
            <field>
              <name>FB27</name>
              <bitOffset>27</bitOffset>
              <bitWidth>1</bitWidth>
            </field>
            <field>
              <name>FB28</name>
              <bitOffset>28</bitOffset>
              <bitWidth>1</bitWidth>
            </field>
            <field>
              <name>FB29</name>
              <bitOffset>29</bitOffset>
              <bitWidth>1</bitWidth>
            </field>
            <field>
              <name>FB30</name>
              <bitOffset>30</bitOffset>
              <bitWidth>1</bitWidth>
            </field>
            <field>
              <name>FB31</name>
              <bitOffset>31</bitOffset>
              <bitWidth>1</bitWidth>
            </field>
          </fields>
        </register>
        <register>
          <name>sFilterRegister.9.FR1</name>
          <addressOffset>0x288</addressOffset>
          <size>0x20</size>
          <fields>
            <field>
              <name>FB0</name>
              <bitOffset>0</bitOffset>
              <bitWidth>1</bitWidth>
            </field>
            <field>
              <name>FB1</name>
              <bitOffset>1</bitOffset>
              <bitWidth>1</bitWidth>
            </field>
            <field>
              <name>FB2</name>
              <bitOffset>2</bitOffset>
              <bitWidth>1</bitWidth>
            </field>
            <field>
              <name>FB3</name>
              <bitOffset>3</bitOffset>
              <bitWidth>1</bitWidth>
            </field>
            <field>
              <name>FB4</name>
              <bitOffset>4</bitOffset>
              <bitWidth>1</bitWidth>
            </field>
            <field>
              <name>FB5</name>
              <bitOffset>5</bitOffset>
              <bitWidth>1</bitWidth>
            </field>
            <field>
              <name>FB6</name>
              <bitOffset>6</bitOffset>
              <bitWidth>1</bitWidth>
            </field>
            <field>
              <name>FB7</name>
              <bitOffset>7</bitOffset>
              <bitWidth>1</bitWidth>
            </field>
            <field>
              <name>FB8</name>
              <bitOffset>8</bitOffset>
              <bitWidth>1</bitWidth>
            </field>
            <field>
              <name>FB9</name>
              <bitOffset>9</bitOffset>
              <bitWidth>1</bitWidth>
            </field>
            <field>
              <name>FB10</name>
              <bitOffset>10</bitOffset>
              <bitWidth>1</bitWidth>
            </field>
            <field>
              <name>FB11</name>
              <bitOffset>11</bitOffset>
              <bitWidth>1</bitWidth>
            </field>
            <field>
              <name>FB12</name>
              <bitOffset>12</bitOffset>
              <bitWidth>1</bitWidth>
            </field>
            <field>
              <name>FB13</name>
              <bitOffset>13</bitOffset>
              <bitWidth>1</bitWidth>
            </field>
            <field>
              <name>FB14</name>
              <bitOffset>14</bitOffset>
              <bitWidth>1</bitWidth>
            </field>
            <field>
              <name>FB15</name>
              <bitOffset>15</bitOffset>
              <bitWidth>1</bitWidth>
            </field>
            <field>
              <name>FB16</name>
              <bitOffset>16</bitOffset>
              <bitWidth>1</bitWidth>
            </field>
            <field>
              <name>FB17</name>
              <bitOffset>17</bitOffset>
              <bitWidth>1</bitWidth>
            </field>
            <field>
              <name>FB18</name>
              <bitOffset>18</bitOffset>
              <bitWidth>1</bitWidth>
            </field>
            <field>
              <name>FB19</name>
              <bitOffset>19</bitOffset>
              <bitWidth>1</bitWidth>
            </field>
            <field>
              <name>FB20</name>
              <bitOffset>20</bitOffset>
              <bitWidth>1</bitWidth>
            </field>
            <field>
              <name>FB21</name>
              <bitOffset>21</bitOffset>
              <bitWidth>1</bitWidth>
            </field>
            <field>
              <name>FB22</name>
              <bitOffset>22</bitOffset>
              <bitWidth>1</bitWidth>
            </field>
            <field>
              <name>FB23</name>
              <bitOffset>23</bitOffset>
              <bitWidth>1</bitWidth>
            </field>
            <field>
              <name>FB24</name>
              <bitOffset>24</bitOffset>
              <bitWidth>1</bitWidth>
            </field>
            <field>
              <name>FB25</name>
              <bitOffset>25</bitOffset>
              <bitWidth>1</bitWidth>
            </field>
            <field>
              <name>FB26</name>
              <bitOffset>26</bitOffset>
              <bitWidth>1</bitWidth>
            </field>
            <field>
              <name>FB27</name>
              <bitOffset>27</bitOffset>
              <bitWidth>1</bitWidth>
            </field>
            <field>
              <name>FB28</name>
              <bitOffset>28</bitOffset>
              <bitWidth>1</bitWidth>
            </field>
            <field>
              <name>FB29</name>
              <bitOffset>29</bitOffset>
              <bitWidth>1</bitWidth>
            </field>
            <field>
              <name>FB30</name>
              <bitOffset>30</bitOffset>
              <bitWidth>1</bitWidth>
            </field>
            <field>
              <name>FB31</name>
              <bitOffset>31</bitOffset>
              <bitWidth>1</bitWidth>
            </field>
          </fields>
        </register>
        <register>
          <name>sFilterRegister.9.FR2</name>
          <addressOffset>0x28c</addressOffset>
          <size>0x20</size>
          <fields>
            <field>
              <name>FB0</name>
              <bitOffset>0</bitOffset>
              <bitWidth>1</bitWidth>
            </field>
            <field>
              <name>FB1</name>
              <bitOffset>1</bitOffset>
              <bitWidth>1</bitWidth>
            </field>
            <field>
              <name>FB2</name>
              <bitOffset>2</bitOffset>
              <bitWidth>1</bitWidth>
            </field>
            <field>
              <name>FB3</name>
              <bitOffset>3</bitOffset>
              <bitWidth>1</bitWidth>
            </field>
            <field>
              <name>FB4</name>
              <bitOffset>4</bitOffset>
              <bitWidth>1</bitWidth>
            </field>
            <field>
              <name>FB5</name>
              <bitOffset>5</bitOffset>
              <bitWidth>1</bitWidth>
            </field>
            <field>
              <name>FB6</name>
              <bitOffset>6</bitOffset>
              <bitWidth>1</bitWidth>
            </field>
            <field>
              <name>FB7</name>
              <bitOffset>7</bitOffset>
              <bitWidth>1</bitWidth>
            </field>
            <field>
              <name>FB8</name>
              <bitOffset>8</bitOffset>
              <bitWidth>1</bitWidth>
            </field>
            <field>
              <name>FB9</name>
              <bitOffset>9</bitOffset>
              <bitWidth>1</bitWidth>
            </field>
            <field>
              <name>FB10</name>
              <bitOffset>10</bitOffset>
              <bitWidth>1</bitWidth>
            </field>
            <field>
              <name>FB11</name>
              <bitOffset>11</bitOffset>
              <bitWidth>1</bitWidth>
            </field>
            <field>
              <name>FB12</name>
              <bitOffset>12</bitOffset>
              <bitWidth>1</bitWidth>
            </field>
            <field>
              <name>FB13</name>
              <bitOffset>13</bitOffset>
              <bitWidth>1</bitWidth>
            </field>
            <field>
              <name>FB14</name>
              <bitOffset>14</bitOffset>
              <bitWidth>1</bitWidth>
            </field>
            <field>
              <name>FB15</name>
              <bitOffset>15</bitOffset>
              <bitWidth>1</bitWidth>
            </field>
            <field>
              <name>FB16</name>
              <bitOffset>16</bitOffset>
              <bitWidth>1</bitWidth>
            </field>
            <field>
              <name>FB17</name>
              <bitOffset>17</bitOffset>
              <bitWidth>1</bitWidth>
            </field>
            <field>
              <name>FB18</name>
              <bitOffset>18</bitOffset>
              <bitWidth>1</bitWidth>
            </field>
            <field>
              <name>FB19</name>
              <bitOffset>19</bitOffset>
              <bitWidth>1</bitWidth>
            </field>
            <field>
              <name>FB20</name>
              <bitOffset>20</bitOffset>
              <bitWidth>1</bitWidth>
            </field>
            <field>
              <name>FB21</name>
              <bitOffset>21</bitOffset>
              <bitWidth>1</bitWidth>
            </field>
            <field>
              <name>FB22</name>
              <bitOffset>22</bitOffset>
              <bitWidth>1</bitWidth>
            </field>
            <field>
              <name>FB23</name>
              <bitOffset>23</bitOffset>
              <bitWidth>1</bitWidth>
            </field>
            <field>
              <name>FB24</name>
              <bitOffset>24</bitOffset>
              <bitWidth>1</bitWidth>
            </field>
            <field>
              <name>FB25</name>
              <bitOffset>25</bitOffset>
              <bitWidth>1</bitWidth>
            </field>
            <field>
              <name>FB26</name>
              <bitOffset>26</bitOffset>
              <bitWidth>1</bitWidth>
            </field>
            <field>
              <name>FB27</name>
              <bitOffset>27</bitOffset>
              <bitWidth>1</bitWidth>
            </field>
            <field>
              <name>FB28</name>
              <bitOffset>28</bitOffset>
              <bitWidth>1</bitWidth>
            </field>
            <field>
              <name>FB29</name>
              <bitOffset>29</bitOffset>
              <bitWidth>1</bitWidth>
            </field>
            <field>
              <name>FB30</name>
              <bitOffset>30</bitOffset>
              <bitWidth>1</bitWidth>
            </field>
            <field>
              <name>FB31</name>
              <bitOffset>31</bitOffset>
              <bitWidth>1</bitWidth>
            </field>
          </fields>
        </register>
        <register>
          <name>sFilterRegister.10.FR1</name>
          <addressOffset>0x290</addressOffset>
          <size>0x20</size>
          <fields>
            <field>
              <name>FB0</name>
              <bitOffset>0</bitOffset>
              <bitWidth>1</bitWidth>
            </field>
            <field>
              <name>FB1</name>
              <bitOffset>1</bitOffset>
              <bitWidth>1</bitWidth>
            </field>
            <field>
              <name>FB2</name>
              <bitOffset>2</bitOffset>
              <bitWidth>1</bitWidth>
            </field>
            <field>
              <name>FB3</name>
              <bitOffset>3</bitOffset>
              <bitWidth>1</bitWidth>
            </field>
            <field>
              <name>FB4</name>
              <bitOffset>4</bitOffset>
              <bitWidth>1</bitWidth>
            </field>
            <field>
              <name>FB5</name>
              <bitOffset>5</bitOffset>
              <bitWidth>1</bitWidth>
            </field>
            <field>
              <name>FB6</name>
              <bitOffset>6</bitOffset>
              <bitWidth>1</bitWidth>
            </field>
            <field>
              <name>FB7</name>
              <bitOffset>7</bitOffset>
              <bitWidth>1</bitWidth>
            </field>
            <field>
              <name>FB8</name>
              <bitOffset>8</bitOffset>
              <bitWidth>1</bitWidth>
            </field>
            <field>
              <name>FB9</name>
              <bitOffset>9</bitOffset>
              <bitWidth>1</bitWidth>
            </field>
            <field>
              <name>FB10</name>
              <bitOffset>10</bitOffset>
              <bitWidth>1</bitWidth>
            </field>
            <field>
              <name>FB11</name>
              <bitOffset>11</bitOffset>
              <bitWidth>1</bitWidth>
            </field>
            <field>
              <name>FB12</name>
              <bitOffset>12</bitOffset>
              <bitWidth>1</bitWidth>
            </field>
            <field>
              <name>FB13</name>
              <bitOffset>13</bitOffset>
              <bitWidth>1</bitWidth>
            </field>
            <field>
              <name>FB14</name>
              <bitOffset>14</bitOffset>
              <bitWidth>1</bitWidth>
            </field>
            <field>
              <name>FB15</name>
              <bitOffset>15</bitOffset>
              <bitWidth>1</bitWidth>
            </field>
            <field>
              <name>FB16</name>
              <bitOffset>16</bitOffset>
              <bitWidth>1</bitWidth>
            </field>
            <field>
              <name>FB17</name>
              <bitOffset>17</bitOffset>
              <bitWidth>1</bitWidth>
            </field>
            <field>
              <name>FB18</name>
              <bitOffset>18</bitOffset>
              <bitWidth>1</bitWidth>
            </field>
            <field>
              <name>FB19</name>
              <bitOffset>19</bitOffset>
              <bitWidth>1</bitWidth>
            </field>
            <field>
              <name>FB20</name>
              <bitOffset>20</bitOffset>
              <bitWidth>1</bitWidth>
            </field>
            <field>
              <name>FB21</name>
              <bitOffset>21</bitOffset>
              <bitWidth>1</bitWidth>
            </field>
            <field>
              <name>FB22</name>
              <bitOffset>22</bitOffset>
              <bitWidth>1</bitWidth>
            </field>
            <field>
              <name>FB23</name>
              <bitOffset>23</bitOffset>
              <bitWidth>1</bitWidth>
            </field>
            <field>
              <name>FB24</name>
              <bitOffset>24</bitOffset>
              <bitWidth>1</bitWidth>
            </field>
            <field>
              <name>FB25</name>
              <bitOffset>25</bitOffset>
              <bitWidth>1</bitWidth>
            </field>
            <field>
              <name>FB26</name>
              <bitOffset>26</bitOffset>
              <bitWidth>1</bitWidth>
            </field>
            <field>
              <name>FB27</name>
              <bitOffset>27</bitOffset>
              <bitWidth>1</bitWidth>
            </field>
            <field>
              <name>FB28</name>
              <bitOffset>28</bitOffset>
              <bitWidth>1</bitWidth>
            </field>
            <field>
              <name>FB29</name>
              <bitOffset>29</bitOffset>
              <bitWidth>1</bitWidth>
            </field>
            <field>
              <name>FB30</name>
              <bitOffset>30</bitOffset>
              <bitWidth>1</bitWidth>
            </field>
            <field>
              <name>FB31</name>
              <bitOffset>31</bitOffset>
              <bitWidth>1</bitWidth>
            </field>
          </fields>
        </register>
        <register>
          <name>sFilterRegister.10.FR2</name>
          <addressOffset>0x294</addressOffset>
          <size>0x20</size>
          <fields>
            <field>
              <name>FB0</name>
              <bitOffset>0</bitOffset>
              <bitWidth>1</bitWidth>
            </field>
            <field>
              <name>FB1</name>
              <bitOffset>1</bitOffset>
              <bitWidth>1</bitWidth>
            </field>
            <field>
              <name>FB2</name>
              <bitOffset>2</bitOffset>
              <bitWidth>1</bitWidth>
            </field>
            <field>
              <name>FB3</name>
              <bitOffset>3</bitOffset>
              <bitWidth>1</bitWidth>
            </field>
            <field>
              <name>FB4</name>
              <bitOffset>4</bitOffset>
              <bitWidth>1</bitWidth>
            </field>
            <field>
              <name>FB5</name>
              <bitOffset>5</bitOffset>
              <bitWidth>1</bitWidth>
            </field>
            <field>
              <name>FB6</name>
              <bitOffset>6</bitOffset>
              <bitWidth>1</bitWidth>
            </field>
            <field>
              <name>FB7</name>
              <bitOffset>7</bitOffset>
              <bitWidth>1</bitWidth>
            </field>
            <field>
              <name>FB8</name>
              <bitOffset>8</bitOffset>
              <bitWidth>1</bitWidth>
            </field>
            <field>
              <name>FB9</name>
              <bitOffset>9</bitOffset>
              <bitWidth>1</bitWidth>
            </field>
            <field>
              <name>FB10</name>
              <bitOffset>10</bitOffset>
              <bitWidth>1</bitWidth>
            </field>
            <field>
              <name>FB11</name>
              <bitOffset>11</bitOffset>
              <bitWidth>1</bitWidth>
            </field>
            <field>
              <name>FB12</name>
              <bitOffset>12</bitOffset>
              <bitWidth>1</bitWidth>
            </field>
            <field>
              <name>FB13</name>
              <bitOffset>13</bitOffset>
              <bitWidth>1</bitWidth>
            </field>
            <field>
              <name>FB14</name>
              <bitOffset>14</bitOffset>
              <bitWidth>1</bitWidth>
            </field>
            <field>
              <name>FB15</name>
              <bitOffset>15</bitOffset>
              <bitWidth>1</bitWidth>
            </field>
            <field>
              <name>FB16</name>
              <bitOffset>16</bitOffset>
              <bitWidth>1</bitWidth>
            </field>
            <field>
              <name>FB17</name>
              <bitOffset>17</bitOffset>
              <bitWidth>1</bitWidth>
            </field>
            <field>
              <name>FB18</name>
              <bitOffset>18</bitOffset>
              <bitWidth>1</bitWidth>
            </field>
            <field>
              <name>FB19</name>
              <bitOffset>19</bitOffset>
              <bitWidth>1</bitWidth>
            </field>
            <field>
              <name>FB20</name>
              <bitOffset>20</bitOffset>
              <bitWidth>1</bitWidth>
            </field>
            <field>
              <name>FB21</name>
              <bitOffset>21</bitOffset>
              <bitWidth>1</bitWidth>
            </field>
            <field>
              <name>FB22</name>
              <bitOffset>22</bitOffset>
              <bitWidth>1</bitWidth>
            </field>
            <field>
              <name>FB23</name>
              <bitOffset>23</bitOffset>
              <bitWidth>1</bitWidth>
            </field>
            <field>
              <name>FB24</name>
              <bitOffset>24</bitOffset>
              <bitWidth>1</bitWidth>
            </field>
            <field>
              <name>FB25</name>
              <bitOffset>25</bitOffset>
              <bitWidth>1</bitWidth>
            </field>
            <field>
              <name>FB26</name>
              <bitOffset>26</bitOffset>
              <bitWidth>1</bitWidth>
            </field>
            <field>
              <name>FB27</name>
              <bitOffset>27</bitOffset>
              <bitWidth>1</bitWidth>
            </field>
            <field>
              <name>FB28</name>
              <bitOffset>28</bitOffset>
              <bitWidth>1</bitWidth>
            </field>
            <field>
              <name>FB29</name>
              <bitOffset>29</bitOffset>
              <bitWidth>1</bitWidth>
            </field>
            <field>
              <name>FB30</name>
              <bitOffset>30</bitOffset>
              <bitWidth>1</bitWidth>
            </field>
            <field>
              <name>FB31</name>
              <bitOffset>31</bitOffset>
              <bitWidth>1</bitWidth>
            </field>
          </fields>
        </register>
        <register>
          <name>sFilterRegister.11.FR1</name>
          <addressOffset>0x298</addressOffset>
          <size>0x20</size>
          <fields>
            <field>
              <name>FB0</name>
              <bitOffset>0</bitOffset>
              <bitWidth>1</bitWidth>
            </field>
            <field>
              <name>FB1</name>
              <bitOffset>1</bitOffset>
              <bitWidth>1</bitWidth>
            </field>
            <field>
              <name>FB2</name>
              <bitOffset>2</bitOffset>
              <bitWidth>1</bitWidth>
            </field>
            <field>
              <name>FB3</name>
              <bitOffset>3</bitOffset>
              <bitWidth>1</bitWidth>
            </field>
            <field>
              <name>FB4</name>
              <bitOffset>4</bitOffset>
              <bitWidth>1</bitWidth>
            </field>
            <field>
              <name>FB5</name>
              <bitOffset>5</bitOffset>
              <bitWidth>1</bitWidth>
            </field>
            <field>
              <name>FB6</name>
              <bitOffset>6</bitOffset>
              <bitWidth>1</bitWidth>
            </field>
            <field>
              <name>FB7</name>
              <bitOffset>7</bitOffset>
              <bitWidth>1</bitWidth>
            </field>
            <field>
              <name>FB8</name>
              <bitOffset>8</bitOffset>
              <bitWidth>1</bitWidth>
            </field>
            <field>
              <name>FB9</name>
              <bitOffset>9</bitOffset>
              <bitWidth>1</bitWidth>
            </field>
            <field>
              <name>FB10</name>
              <bitOffset>10</bitOffset>
              <bitWidth>1</bitWidth>
            </field>
            <field>
              <name>FB11</name>
              <bitOffset>11</bitOffset>
              <bitWidth>1</bitWidth>
            </field>
            <field>
              <name>FB12</name>
              <bitOffset>12</bitOffset>
              <bitWidth>1</bitWidth>
            </field>
            <field>
              <name>FB13</name>
              <bitOffset>13</bitOffset>
              <bitWidth>1</bitWidth>
            </field>
            <field>
              <name>FB14</name>
              <bitOffset>14</bitOffset>
              <bitWidth>1</bitWidth>
            </field>
            <field>
              <name>FB15</name>
              <bitOffset>15</bitOffset>
              <bitWidth>1</bitWidth>
            </field>
            <field>
              <name>FB16</name>
              <bitOffset>16</bitOffset>
              <bitWidth>1</bitWidth>
            </field>
            <field>
              <name>FB17</name>
              <bitOffset>17</bitOffset>
              <bitWidth>1</bitWidth>
            </field>
            <field>
              <name>FB18</name>
              <bitOffset>18</bitOffset>
              <bitWidth>1</bitWidth>
            </field>
            <field>
              <name>FB19</name>
              <bitOffset>19</bitOffset>
              <bitWidth>1</bitWidth>
            </field>
            <field>
              <name>FB20</name>
              <bitOffset>20</bitOffset>
              <bitWidth>1</bitWidth>
            </field>
            <field>
              <name>FB21</name>
              <bitOffset>21</bitOffset>
              <bitWidth>1</bitWidth>
            </field>
            <field>
              <name>FB22</name>
              <bitOffset>22</bitOffset>
              <bitWidth>1</bitWidth>
            </field>
            <field>
              <name>FB23</name>
              <bitOffset>23</bitOffset>
              <bitWidth>1</bitWidth>
            </field>
            <field>
              <name>FB24</name>
              <bitOffset>24</bitOffset>
              <bitWidth>1</bitWidth>
            </field>
            <field>
              <name>FB25</name>
              <bitOffset>25</bitOffset>
              <bitWidth>1</bitWidth>
            </field>
            <field>
              <name>FB26</name>
              <bitOffset>26</bitOffset>
              <bitWidth>1</bitWidth>
            </field>
            <field>
              <name>FB27</name>
              <bitOffset>27</bitOffset>
              <bitWidth>1</bitWidth>
            </field>
            <field>
              <name>FB28</name>
              <bitOffset>28</bitOffset>
              <bitWidth>1</bitWidth>
            </field>
            <field>
              <name>FB29</name>
              <bitOffset>29</bitOffset>
              <bitWidth>1</bitWidth>
            </field>
            <field>
              <name>FB30</name>
              <bitOffset>30</bitOffset>
              <bitWidth>1</bitWidth>
            </field>
            <field>
              <name>FB31</name>
              <bitOffset>31</bitOffset>
              <bitWidth>1</bitWidth>
            </field>
          </fields>
        </register>
        <register>
          <name>sFilterRegister.11.FR2</name>
          <addressOffset>0x29c</addressOffset>
          <size>0x20</size>
          <fields>
            <field>
              <name>FB0</name>
              <bitOffset>0</bitOffset>
              <bitWidth>1</bitWidth>
            </field>
            <field>
              <name>FB1</name>
              <bitOffset>1</bitOffset>
              <bitWidth>1</bitWidth>
            </field>
            <field>
              <name>FB2</name>
              <bitOffset>2</bitOffset>
              <bitWidth>1</bitWidth>
            </field>
            <field>
              <name>FB3</name>
              <bitOffset>3</bitOffset>
              <bitWidth>1</bitWidth>
            </field>
            <field>
              <name>FB4</name>
              <bitOffset>4</bitOffset>
              <bitWidth>1</bitWidth>
            </field>
            <field>
              <name>FB5</name>
              <bitOffset>5</bitOffset>
              <bitWidth>1</bitWidth>
            </field>
            <field>
              <name>FB6</name>
              <bitOffset>6</bitOffset>
              <bitWidth>1</bitWidth>
            </field>
            <field>
              <name>FB7</name>
              <bitOffset>7</bitOffset>
              <bitWidth>1</bitWidth>
            </field>
            <field>
              <name>FB8</name>
              <bitOffset>8</bitOffset>
              <bitWidth>1</bitWidth>
            </field>
            <field>
              <name>FB9</name>
              <bitOffset>9</bitOffset>
              <bitWidth>1</bitWidth>
            </field>
            <field>
              <name>FB10</name>
              <bitOffset>10</bitOffset>
              <bitWidth>1</bitWidth>
            </field>
            <field>
              <name>FB11</name>
              <bitOffset>11</bitOffset>
              <bitWidth>1</bitWidth>
            </field>
            <field>
              <name>FB12</name>
              <bitOffset>12</bitOffset>
              <bitWidth>1</bitWidth>
            </field>
            <field>
              <name>FB13</name>
              <bitOffset>13</bitOffset>
              <bitWidth>1</bitWidth>
            </field>
            <field>
              <name>FB14</name>
              <bitOffset>14</bitOffset>
              <bitWidth>1</bitWidth>
            </field>
            <field>
              <name>FB15</name>
              <bitOffset>15</bitOffset>
              <bitWidth>1</bitWidth>
            </field>
            <field>
              <name>FB16</name>
              <bitOffset>16</bitOffset>
              <bitWidth>1</bitWidth>
            </field>
            <field>
              <name>FB17</name>
              <bitOffset>17</bitOffset>
              <bitWidth>1</bitWidth>
            </field>
            <field>
              <name>FB18</name>
              <bitOffset>18</bitOffset>
              <bitWidth>1</bitWidth>
            </field>
            <field>
              <name>FB19</name>
              <bitOffset>19</bitOffset>
              <bitWidth>1</bitWidth>
            </field>
            <field>
              <name>FB20</name>
              <bitOffset>20</bitOffset>
              <bitWidth>1</bitWidth>
            </field>
            <field>
              <name>FB21</name>
              <bitOffset>21</bitOffset>
              <bitWidth>1</bitWidth>
            </field>
            <field>
              <name>FB22</name>
              <bitOffset>22</bitOffset>
              <bitWidth>1</bitWidth>
            </field>
            <field>
              <name>FB23</name>
              <bitOffset>23</bitOffset>
              <bitWidth>1</bitWidth>
            </field>
            <field>
              <name>FB24</name>
              <bitOffset>24</bitOffset>
              <bitWidth>1</bitWidth>
            </field>
            <field>
              <name>FB25</name>
              <bitOffset>25</bitOffset>
              <bitWidth>1</bitWidth>
            </field>
            <field>
              <name>FB26</name>
              <bitOffset>26</bitOffset>
              <bitWidth>1</bitWidth>
            </field>
            <field>
              <name>FB27</name>
              <bitOffset>27</bitOffset>
              <bitWidth>1</bitWidth>
            </field>
            <field>
              <name>FB28</name>
              <bitOffset>28</bitOffset>
              <bitWidth>1</bitWidth>
            </field>
            <field>
              <name>FB29</name>
              <bitOffset>29</bitOffset>
              <bitWidth>1</bitWidth>
            </field>
            <field>
              <name>FB30</name>
              <bitOffset>30</bitOffset>
              <bitWidth>1</bitWidth>
            </field>
            <field>
              <name>FB31</name>
              <bitOffset>31</bitOffset>
              <bitWidth>1</bitWidth>
            </field>
          </fields>
        </register>
        <register>
          <name>sFilterRegister.12.FR1</name>
          <addressOffset>0x2a0</addressOffset>
          <size>0x20</size>
          <fields>
            <field>
              <name>FB0</name>
              <bitOffset>0</bitOffset>
              <bitWidth>1</bitWidth>
            </field>
            <field>
              <name>FB1</name>
              <bitOffset>1</bitOffset>
              <bitWidth>1</bitWidth>
            </field>
            <field>
              <name>FB2</name>
              <bitOffset>2</bitOffset>
              <bitWidth>1</bitWidth>
            </field>
            <field>
              <name>FB3</name>
              <bitOffset>3</bitOffset>
              <bitWidth>1</bitWidth>
            </field>
            <field>
              <name>FB4</name>
              <bitOffset>4</bitOffset>
              <bitWidth>1</bitWidth>
            </field>
            <field>
              <name>FB5</name>
              <bitOffset>5</bitOffset>
              <bitWidth>1</bitWidth>
            </field>
            <field>
              <name>FB6</name>
              <bitOffset>6</bitOffset>
              <bitWidth>1</bitWidth>
            </field>
            <field>
              <name>FB7</name>
              <bitOffset>7</bitOffset>
              <bitWidth>1</bitWidth>
            </field>
            <field>
              <name>FB8</name>
              <bitOffset>8</bitOffset>
              <bitWidth>1</bitWidth>
            </field>
            <field>
              <name>FB9</name>
              <bitOffset>9</bitOffset>
              <bitWidth>1</bitWidth>
            </field>
            <field>
              <name>FB10</name>
              <bitOffset>10</bitOffset>
              <bitWidth>1</bitWidth>
            </field>
            <field>
              <name>FB11</name>
              <bitOffset>11</bitOffset>
              <bitWidth>1</bitWidth>
            </field>
            <field>
              <name>FB12</name>
              <bitOffset>12</bitOffset>
              <bitWidth>1</bitWidth>
            </field>
            <field>
              <name>FB13</name>
              <bitOffset>13</bitOffset>
              <bitWidth>1</bitWidth>
            </field>
            <field>
              <name>FB14</name>
              <bitOffset>14</bitOffset>
              <bitWidth>1</bitWidth>
            </field>
            <field>
              <name>FB15</name>
              <bitOffset>15</bitOffset>
              <bitWidth>1</bitWidth>
            </field>
            <field>
              <name>FB16</name>
              <bitOffset>16</bitOffset>
              <bitWidth>1</bitWidth>
            </field>
            <field>
              <name>FB17</name>
              <bitOffset>17</bitOffset>
              <bitWidth>1</bitWidth>
            </field>
            <field>
              <name>FB18</name>
              <bitOffset>18</bitOffset>
              <bitWidth>1</bitWidth>
            </field>
            <field>
              <name>FB19</name>
              <bitOffset>19</bitOffset>
              <bitWidth>1</bitWidth>
            </field>
            <field>
              <name>FB20</name>
              <bitOffset>20</bitOffset>
              <bitWidth>1</bitWidth>
            </field>
            <field>
              <name>FB21</name>
              <bitOffset>21</bitOffset>
              <bitWidth>1</bitWidth>
            </field>
            <field>
              <name>FB22</name>
              <bitOffset>22</bitOffset>
              <bitWidth>1</bitWidth>
            </field>
            <field>
              <name>FB23</name>
              <bitOffset>23</bitOffset>
              <bitWidth>1</bitWidth>
            </field>
            <field>
              <name>FB24</name>
              <bitOffset>24</bitOffset>
              <bitWidth>1</bitWidth>
            </field>
            <field>
              <name>FB25</name>
              <bitOffset>25</bitOffset>
              <bitWidth>1</bitWidth>
            </field>
            <field>
              <name>FB26</name>
              <bitOffset>26</bitOffset>
              <bitWidth>1</bitWidth>
            </field>
            <field>
              <name>FB27</name>
              <bitOffset>27</bitOffset>
              <bitWidth>1</bitWidth>
            </field>
            <field>
              <name>FB28</name>
              <bitOffset>28</bitOffset>
              <bitWidth>1</bitWidth>
            </field>
            <field>
              <name>FB29</name>
              <bitOffset>29</bitOffset>
              <bitWidth>1</bitWidth>
            </field>
            <field>
              <name>FB30</name>
              <bitOffset>30</bitOffset>
              <bitWidth>1</bitWidth>
            </field>
            <field>
              <name>FB31</name>
              <bitOffset>31</bitOffset>
              <bitWidth>1</bitWidth>
            </field>
          </fields>
        </register>
        <register>
          <name>sFilterRegister.12.FR2</name>
          <addressOffset>0x2a4</addressOffset>
          <size>0x20</size>
          <fields>
            <field>
              <name>FB0</name>
              <bitOffset>0</bitOffset>
              <bitWidth>1</bitWidth>
            </field>
            <field>
              <name>FB1</name>
              <bitOffset>1</bitOffset>
              <bitWidth>1</bitWidth>
            </field>
            <field>
              <name>FB2</name>
              <bitOffset>2</bitOffset>
              <bitWidth>1</bitWidth>
            </field>
            <field>
              <name>FB3</name>
              <bitOffset>3</bitOffset>
              <bitWidth>1</bitWidth>
            </field>
            <field>
              <name>FB4</name>
              <bitOffset>4</bitOffset>
              <bitWidth>1</bitWidth>
            </field>
            <field>
              <name>FB5</name>
              <bitOffset>5</bitOffset>
              <bitWidth>1</bitWidth>
            </field>
            <field>
              <name>FB6</name>
              <bitOffset>6</bitOffset>
              <bitWidth>1</bitWidth>
            </field>
            <field>
              <name>FB7</name>
              <bitOffset>7</bitOffset>
              <bitWidth>1</bitWidth>
            </field>
            <field>
              <name>FB8</name>
              <bitOffset>8</bitOffset>
              <bitWidth>1</bitWidth>
            </field>
            <field>
              <name>FB9</name>
              <bitOffset>9</bitOffset>
              <bitWidth>1</bitWidth>
            </field>
            <field>
              <name>FB10</name>
              <bitOffset>10</bitOffset>
              <bitWidth>1</bitWidth>
            </field>
            <field>
              <name>FB11</name>
              <bitOffset>11</bitOffset>
              <bitWidth>1</bitWidth>
            </field>
            <field>
              <name>FB12</name>
              <bitOffset>12</bitOffset>
              <bitWidth>1</bitWidth>
            </field>
            <field>
              <name>FB13</name>
              <bitOffset>13</bitOffset>
              <bitWidth>1</bitWidth>
            </field>
            <field>
              <name>FB14</name>
              <bitOffset>14</bitOffset>
              <bitWidth>1</bitWidth>
            </field>
            <field>
              <name>FB15</name>
              <bitOffset>15</bitOffset>
              <bitWidth>1</bitWidth>
            </field>
            <field>
              <name>FB16</name>
              <bitOffset>16</bitOffset>
              <bitWidth>1</bitWidth>
            </field>
            <field>
              <name>FB17</name>
              <bitOffset>17</bitOffset>
              <bitWidth>1</bitWidth>
            </field>
            <field>
              <name>FB18</name>
              <bitOffset>18</bitOffset>
              <bitWidth>1</bitWidth>
            </field>
            <field>
              <name>FB19</name>
              <bitOffset>19</bitOffset>
              <bitWidth>1</bitWidth>
            </field>
            <field>
              <name>FB20</name>
              <bitOffset>20</bitOffset>
              <bitWidth>1</bitWidth>
            </field>
            <field>
              <name>FB21</name>
              <bitOffset>21</bitOffset>
              <bitWidth>1</bitWidth>
            </field>
            <field>
              <name>FB22</name>
              <bitOffset>22</bitOffset>
              <bitWidth>1</bitWidth>
            </field>
            <field>
              <name>FB23</name>
              <bitOffset>23</bitOffset>
              <bitWidth>1</bitWidth>
            </field>
            <field>
              <name>FB24</name>
              <bitOffset>24</bitOffset>
              <bitWidth>1</bitWidth>
            </field>
            <field>
              <name>FB25</name>
              <bitOffset>25</bitOffset>
              <bitWidth>1</bitWidth>
            </field>
            <field>
              <name>FB26</name>
              <bitOffset>26</bitOffset>
              <bitWidth>1</bitWidth>
            </field>
            <field>
              <name>FB27</name>
              <bitOffset>27</bitOffset>
              <bitWidth>1</bitWidth>
            </field>
            <field>
              <name>FB28</name>
              <bitOffset>28</bitOffset>
              <bitWidth>1</bitWidth>
            </field>
            <field>
              <name>FB29</name>
              <bitOffset>29</bitOffset>
              <bitWidth>1</bitWidth>
            </field>
            <field>
              <name>FB30</name>
              <bitOffset>30</bitOffset>
              <bitWidth>1</bitWidth>
            </field>
            <field>
              <name>FB31</name>
              <bitOffset>31</bitOffset>
              <bitWidth>1</bitWidth>
            </field>
          </fields>
        </register>
        <register>
          <name>sFilterRegister.13.FR1</name>
          <addressOffset>0x2a8</addressOffset>
          <size>0x20</size>
          <fields>
            <field>
              <name>FB0</name>
              <bitOffset>0</bitOffset>
              <bitWidth>1</bitWidth>
            </field>
            <field>
              <name>FB1</name>
              <bitOffset>1</bitOffset>
              <bitWidth>1</bitWidth>
            </field>
            <field>
              <name>FB2</name>
              <bitOffset>2</bitOffset>
              <bitWidth>1</bitWidth>
            </field>
            <field>
              <name>FB3</name>
              <bitOffset>3</bitOffset>
              <bitWidth>1</bitWidth>
            </field>
            <field>
              <name>FB4</name>
              <bitOffset>4</bitOffset>
              <bitWidth>1</bitWidth>
            </field>
            <field>
              <name>FB5</name>
              <bitOffset>5</bitOffset>
              <bitWidth>1</bitWidth>
            </field>
            <field>
              <name>FB6</name>
              <bitOffset>6</bitOffset>
              <bitWidth>1</bitWidth>
            </field>
            <field>
              <name>FB7</name>
              <bitOffset>7</bitOffset>
              <bitWidth>1</bitWidth>
            </field>
            <field>
              <name>FB8</name>
              <bitOffset>8</bitOffset>
              <bitWidth>1</bitWidth>
            </field>
            <field>
              <name>FB9</name>
              <bitOffset>9</bitOffset>
              <bitWidth>1</bitWidth>
            </field>
            <field>
              <name>FB10</name>
              <bitOffset>10</bitOffset>
              <bitWidth>1</bitWidth>
            </field>
            <field>
              <name>FB11</name>
              <bitOffset>11</bitOffset>
              <bitWidth>1</bitWidth>
            </field>
            <field>
              <name>FB12</name>
              <bitOffset>12</bitOffset>
              <bitWidth>1</bitWidth>
            </field>
            <field>
              <name>FB13</name>
              <bitOffset>13</bitOffset>
              <bitWidth>1</bitWidth>
            </field>
            <field>
              <name>FB14</name>
              <bitOffset>14</bitOffset>
              <bitWidth>1</bitWidth>
            </field>
            <field>
              <name>FB15</name>
              <bitOffset>15</bitOffset>
              <bitWidth>1</bitWidth>
            </field>
            <field>
              <name>FB16</name>
              <bitOffset>16</bitOffset>
              <bitWidth>1</bitWidth>
            </field>
            <field>
              <name>FB17</name>
              <bitOffset>17</bitOffset>
              <bitWidth>1</bitWidth>
            </field>
            <field>
              <name>FB18</name>
              <bitOffset>18</bitOffset>
              <bitWidth>1</bitWidth>
            </field>
            <field>
              <name>FB19</name>
              <bitOffset>19</bitOffset>
              <bitWidth>1</bitWidth>
            </field>
            <field>
              <name>FB20</name>
              <bitOffset>20</bitOffset>
              <bitWidth>1</bitWidth>
            </field>
            <field>
              <name>FB21</name>
              <bitOffset>21</bitOffset>
              <bitWidth>1</bitWidth>
            </field>
            <field>
              <name>FB22</name>
              <bitOffset>22</bitOffset>
              <bitWidth>1</bitWidth>
            </field>
            <field>
              <name>FB23</name>
              <bitOffset>23</bitOffset>
              <bitWidth>1</bitWidth>
            </field>
            <field>
              <name>FB24</name>
              <bitOffset>24</bitOffset>
              <bitWidth>1</bitWidth>
            </field>
            <field>
              <name>FB25</name>
              <bitOffset>25</bitOffset>
              <bitWidth>1</bitWidth>
            </field>
            <field>
              <name>FB26</name>
              <bitOffset>26</bitOffset>
              <bitWidth>1</bitWidth>
            </field>
            <field>
              <name>FB27</name>
              <bitOffset>27</bitOffset>
              <bitWidth>1</bitWidth>
            </field>
            <field>
              <name>FB28</name>
              <bitOffset>28</bitOffset>
              <bitWidth>1</bitWidth>
            </field>
            <field>
              <name>FB29</name>
              <bitOffset>29</bitOffset>
              <bitWidth>1</bitWidth>
            </field>
            <field>
              <name>FB30</name>
              <bitOffset>30</bitOffset>
              <bitWidth>1</bitWidth>
            </field>
            <field>
              <name>FB31</name>
              <bitOffset>31</bitOffset>
              <bitWidth>1</bitWidth>
            </field>
          </fields>
        </register>
        <register>
          <name>sFilterRegister.13.FR2</name>
          <addressOffset>0x2ac</addressOffset>
          <size>0x20</size>
          <fields>
            <field>
              <name>FB0</name>
              <bitOffset>0</bitOffset>
              <bitWidth>1</bitWidth>
            </field>
            <field>
              <name>FB1</name>
              <bitOffset>1</bitOffset>
              <bitWidth>1</bitWidth>
            </field>
            <field>
              <name>FB2</name>
              <bitOffset>2</bitOffset>
              <bitWidth>1</bitWidth>
            </field>
            <field>
              <name>FB3</name>
              <bitOffset>3</bitOffset>
              <bitWidth>1</bitWidth>
            </field>
            <field>
              <name>FB4</name>
              <bitOffset>4</bitOffset>
              <bitWidth>1</bitWidth>
            </field>
            <field>
              <name>FB5</name>
              <bitOffset>5</bitOffset>
              <bitWidth>1</bitWidth>
            </field>
            <field>
              <name>FB6</name>
              <bitOffset>6</bitOffset>
              <bitWidth>1</bitWidth>
            </field>
            <field>
              <name>FB7</name>
              <bitOffset>7</bitOffset>
              <bitWidth>1</bitWidth>
            </field>
            <field>
              <name>FB8</name>
              <bitOffset>8</bitOffset>
              <bitWidth>1</bitWidth>
            </field>
            <field>
              <name>FB9</name>
              <bitOffset>9</bitOffset>
              <bitWidth>1</bitWidth>
            </field>
            <field>
              <name>FB10</name>
              <bitOffset>10</bitOffset>
              <bitWidth>1</bitWidth>
            </field>
            <field>
              <name>FB11</name>
              <bitOffset>11</bitOffset>
              <bitWidth>1</bitWidth>
            </field>
            <field>
              <name>FB12</name>
              <bitOffset>12</bitOffset>
              <bitWidth>1</bitWidth>
            </field>
            <field>
              <name>FB13</name>
              <bitOffset>13</bitOffset>
              <bitWidth>1</bitWidth>
            </field>
            <field>
              <name>FB14</name>
              <bitOffset>14</bitOffset>
              <bitWidth>1</bitWidth>
            </field>
            <field>
              <name>FB15</name>
              <bitOffset>15</bitOffset>
              <bitWidth>1</bitWidth>
            </field>
            <field>
              <name>FB16</name>
              <bitOffset>16</bitOffset>
              <bitWidth>1</bitWidth>
            </field>
            <field>
              <name>FB17</name>
              <bitOffset>17</bitOffset>
              <bitWidth>1</bitWidth>
            </field>
            <field>
              <name>FB18</name>
              <bitOffset>18</bitOffset>
              <bitWidth>1</bitWidth>
            </field>
            <field>
              <name>FB19</name>
              <bitOffset>19</bitOffset>
              <bitWidth>1</bitWidth>
            </field>
            <field>
              <name>FB20</name>
              <bitOffset>20</bitOffset>
              <bitWidth>1</bitWidth>
            </field>
            <field>
              <name>FB21</name>
              <bitOffset>21</bitOffset>
              <bitWidth>1</bitWidth>
            </field>
            <field>
              <name>FB22</name>
              <bitOffset>22</bitOffset>
              <bitWidth>1</bitWidth>
            </field>
            <field>
              <name>FB23</name>
              <bitOffset>23</bitOffset>
              <bitWidth>1</bitWidth>
            </field>
            <field>
              <name>FB24</name>
              <bitOffset>24</bitOffset>
              <bitWidth>1</bitWidth>
            </field>
            <field>
              <name>FB25</name>
              <bitOffset>25</bitOffset>
              <bitWidth>1</bitWidth>
            </field>
            <field>
              <name>FB26</name>
              <bitOffset>26</bitOffset>
              <bitWidth>1</bitWidth>
            </field>
            <field>
              <name>FB27</name>
              <bitOffset>27</bitOffset>
              <bitWidth>1</bitWidth>
            </field>
            <field>
              <name>FB28</name>
              <bitOffset>28</bitOffset>
              <bitWidth>1</bitWidth>
            </field>
            <field>
              <name>FB29</name>
              <bitOffset>29</bitOffset>
              <bitWidth>1</bitWidth>
            </field>
            <field>
              <name>FB30</name>
              <bitOffset>30</bitOffset>
              <bitWidth>1</bitWidth>
            </field>
            <field>
              <name>FB31</name>
              <bitOffset>31</bitOffset>
              <bitWidth>1</bitWidth>
            </field>
          </fields>
        </register>
        <register>
          <name>sFilterRegister.14.FR1</name>
          <addressOffset>0x2b0</addressOffset>
          <size>0x20</size>
        </register>
        <register>
          <name>sFilterRegister.14.FR2</name>
          <addressOffset>0x2b4</addressOffset>
          <size>0x20</size>
        </register>
        <register>
          <name>sFilterRegister.15.FR1</name>
          <addressOffset>0x2b8</addressOffset>
          <size>0x20</size>
        </register>
        <register>
          <name>sFilterRegister.15.FR2</name>
          <addressOffset>0x2bc</addressOffset>
          <size>0x20</size>
        </register>
        <register>
          <name>sFilterRegister.16.FR1</name>
          <addressOffset>0x2c0</addressOffset>
          <size>0x20</size>
        </register>
        <register>
          <name>sFilterRegister.16.FR2</name>
          <addressOffset>0x2c4</addressOffset>
          <size>0x20</size>
        </register>
        <register>
          <name>sFilterRegister.17.FR1</name>
          <addressOffset>0x2c8</addressOffset>
          <size>0x20</size>
        </register>
        <register>
          <name>sFilterRegister.17.FR2</name>
          <addressOffset>0x2cc</addressOffset>
          <size>0x20</size>
        </register>
        <register>
          <name>sFilterRegister.18.FR1</name>
          <addressOffset>0x2d0</addressOffset>
          <size>0x20</size>
        </register>
        <register>
          <name>sFilterRegister.18.FR2</name>
          <addressOffset>0x2d4</addressOffset>
          <size>0x20</size>
        </register>
        <register>
          <name>sFilterRegister.19.FR1</name>
          <addressOffset>0x2d8</addressOffset>
          <size>0x20</size>
        </register>
        <register>
          <name>sFilterRegister.19.FR2</name>
          <addressOffset>0x2dc</addressOffset>
          <size>0x20</size>
        </register>
        <register>
          <name>sFilterRegister.20.FR1</name>
          <addressOffset>0x2e0</addressOffset>
          <size>0x20</size>
        </register>
        <register>
          <name>sFilterRegister.20.FR2</name>
          <addressOffset>0x2e4</addressOffset>
          <size>0x20</size>
        </register>
        <register>
          <name>sFilterRegister.21.FR1</name>
          <addressOffset>0x2e8</addressOffset>
          <size>0x20</size>
        </register>
        <register>
          <name>sFilterRegister.21.FR2</name>
          <addressOffset>0x2ec</addressOffset>
          <size>0x20</size>
        </register>
        <register>
          <name>sFilterRegister.22.FR1</name>
          <addressOffset>0x2f0</addressOffset>
          <size>0x20</size>
        </register>
        <register>
          <name>sFilterRegister.22.FR2</name>
          <addressOffset>0x2f4</addressOffset>
          <size>0x20</size>
        </register>
        <register>
          <name>sFilterRegister.23.FR1</name>
          <addressOffset>0x2f8</addressOffset>
          <size>0x20</size>
        </register>
        <register>
          <name>sFilterRegister.23.FR2</name>
          <addressOffset>0x2fc</addressOffset>
          <size>0x20</size>
        </register>
        <register>
          <name>sFilterRegister.24.FR1</name>
          <addressOffset>0x300</addressOffset>
          <size>0x20</size>
        </register>
        <register>
          <name>sFilterRegister.24.FR2</name>
          <addressOffset>0x304</addressOffset>
          <size>0x20</size>
        </register>
        <register>
          <name>sFilterRegister.25.FR1</name>
          <addressOffset>0x308</addressOffset>
          <size>0x20</size>
        </register>
        <register>
          <name>sFilterRegister.25.FR2</name>
          <addressOffset>0x30c</addressOffset>
          <size>0x20</size>
        </register>
        <register>
          <name>sFilterRegister.26.FR1</name>
          <addressOffset>0x310</addressOffset>
          <size>0x20</size>
        </register>
        <register>
          <name>sFilterRegister.26.FR2</name>
          <addressOffset>0x314</addressOffset>
          <size>0x20</size>
        </register>
        <register>
          <name>sFilterRegister.27.FR1</name>
          <addressOffset>0x318</addressOffset>
          <size>0x20</size>
        </register>
        <register>
          <name>sFilterRegister.27.FR2</name>
          <addressOffset>0x31c</addressOffset>
          <size>0x20</size>
        </register>
      </registers>
    </peripheral>
    <peripheral>
      <name>CAN1</name>
      <baseAddress>0x40006400</baseAddress>
      <registers>
        <register>
          <name>MCR</name>
          <addressOffset>0x0</addressOffset>
          <size>0x20</size>
          <fields>
            <field>
              <name>INRQ</name>
              <bitOffset>0</bitOffset>
              <bitWidth>1</bitWidth>
            </field>
            <field>
              <name>SLEEP</name>
              <bitOffset>1</bitOffset>
              <bitWidth>1</bitWidth>
            </field>
            <field>
              <name>TXFP</name>
              <bitOffset>2</bitOffset>
              <bitWidth>1</bitWidth>
            </field>
            <field>
              <name>RFLM</name>
              <bitOffset>3</bitOffset>
              <bitWidth>1</bitWidth>
            </field>
            <field>
              <name>NART</name>
              <bitOffset>4</bitOffset>
              <bitWidth>1</bitWidth>
            </field>
            <field>
              <name>AWUM</name>
              <bitOffset>5</bitOffset>
              <bitWidth>1</bitWidth>
            </field>
            <field>
              <name>ABOM</name>
              <bitOffset>6</bitOffset>
              <bitWidth>1</bitWidth>
            </field>
            <field>
              <name>TTCM</name>
              <bitOffset>7</bitOffset>
              <bitWidth>1</bitWidth>
            </field>
            <field>
              <name>RESET</name>
              <bitOffset>15</bitOffset>
              <bitWidth>1</bitWidth>
            </field>
          </fields>
        </register>
        <register>
          <name>MSR</name>
          <addressOffset>0x4</addressOffset>
          <size>0x20</size>
          <fields>
            <field>
              <name>INAK</name>
              <bitOffset>0</bitOffset>
              <bitWidth>1</bitWidth>
            </field>
            <field>
              <name>SLAK</name>
              <bitOffset>1</bitOffset>
              <bitWidth>1</bitWidth>
            </field>
            <field>
              <name>ERRI</name>
              <bitOffset>2</bitOffset>
              <bitWidth>1</bitWidth>
            </field>
            <field>
              <name>WKUI</name>
              <bitOffset>3</bitOffset>
              <bitWidth>1</bitWidth>
            </field>
            <field>
              <name>SLAKI</name>
              <bitOffset>4</bitOffset>
              <bitWidth>1</bitWidth>
            </field>
            <field>
              <name>TXM</name>
              <bitOffset>8</bitOffset>
              <bitWidth>1</bitWidth>
            </field>
            <field>
              <name>RXM</name>
              <bitOffset>9</bitOffset>
              <bitWidth>1</bitWidth>
            </field>
            <field>
              <name>SAMP</name>
              <bitOffset>10</bitOffset>
              <bitWidth>1</bitWidth>
            </field>
            <field>
              <name>RX</name>
              <bitOffset>11</bitOffset>
              <bitWidth>1</bitWidth>
            </field>
          </fields>
        </register>
        <register>
          <name>TSR</name>
          <addressOffset>0x8</addressOffset>
          <size>0x20</size>
          <fields>
            <field>
              <name>RQCP0</name>
              <bitOffset>0</bitOffset>
              <bitWidth>1</bitWidth>
            </field>
            <field>
              <name>TXOK0</name>
              <bitOffset>1</bitOffset>
              <bitWidth>1</bitWidth>
            </field>
            <field>
              <name>ALST0</name>
              <bitOffset>2</bitOffset>
              <bitWidth>1</bitWidth>
            </field>
            <field>
              <name>TERR0</name>
              <bitOffset>3</bitOffset>
              <bitWidth>1</bitWidth>
            </field>
            <field>
              <name>ABRQ0</name>
              <bitOffset>7</bitOffset>
              <bitWidth>1</bitWidth>
            </field>
            <field>
              <name>RQCP1</name>
              <bitOffset>8</bitOffset>
              <bitWidth>1</bitWidth>
            </field>
            <field>
              <name>TXOK1</name>
              <bitOffset>9</bitOffset>
              <bitWidth>1</bitWidth>
            </field>
            <field>
              <name>ALST1</name>
              <bitOffset>10</bitOffset>
              <bitWidth>1</bitWidth>
            </field>
            <field>
              <name>TERR1</name>
              <bitOffset>11</bitOffset>
              <bitWidth>1</bitWidth>
            </field>
            <field>
              <name>ABRQ1</name>
              <bitOffset>15</bitOffset>
              <bitWidth>1</bitWidth>
            </field>
            <field>
              <name>RQCP2</name>
              <bitOffset>16</bitOffset>
              <bitWidth>1</bitWidth>
            </field>
            <field>
              <name>TXOK2</name>
              <bitOffset>17</bitOffset>
              <bitWidth>1</bitWidth>
            </field>
            <field>
              <name>ALST2</name>
              <bitOffset>18</bitOffset>
              <bitWidth>1</bitWidth>
            </field>
            <field>
              <name>TERR2</name>
              <bitOffset>19</bitOffset>
              <bitWidth>1</bitWidth>
            </field>
            <field>
              <name>ABRQ2</name>
              <bitOffset>23</bitOffset>
              <bitWidth>1</bitWidth>
            </field>
            <field>
              <name>CODE</name>
              <bitOffset>24</bitOffset>
              <bitWidth>2</bitWidth>
            </field>
            <field>
              <name>TME0</name>
              <bitOffset>26</bitOffset>
              <bitWidth>1</bitWidth>
            </field>
            <field>
              <name>TME1</name>
              <bitOffset>27</bitOffset>
              <bitWidth>1</bitWidth>
            </field>
            <field>
              <name>TME2</name>
              <bitOffset>28</bitOffset>
              <bitWidth>1</bitWidth>
            </field>
            <field>
              <name>LOW0</name>
              <bitOffset>29</bitOffset>
              <bitWidth>1</bitWidth>
            </field>
            <field>
              <name>LOW1</name>
              <bitOffset>30</bitOffset>
              <bitWidth>1</bitWidth>
            </field>
            <field>
              <name>LOW2</name>
              <bitOffset>31</bitOffset>
              <bitWidth>1</bitWidth>
            </field>
          </fields>
        </register>
        <register>
          <name>RF0R</name>
          <addressOffset>0xc</addressOffset>
          <size>0x20</size>
          <fields>
            <field>
              <name>FMP0</name>
              <bitOffset>0</bitOffset>
              <bitWidth>2</bitWidth>
            </field>
            <field>
              <name>FULL0</name>
              <bitOffset>3</bitOffset>
              <bitWidth>1</bitWidth>
            </field>
            <field>
              <name>FOVR0</name>
              <bitOffset>4</bitOffset>
              <bitWidth>1</bitWidth>
            </field>
            <field>
              <name>RFOM0</name>
              <bitOffset>5</bitOffset>
              <bitWidth>1</bitWidth>
            </field>
          </fields>
        </register>
        <register>
          <name>RF1R</name>
          <addressOffset>0x10</addressOffset>
          <size>0x20</size>
          <fields>
            <field>
              <name>FMP1</name>
              <bitOffset>0</bitOffset>
              <bitWidth>2</bitWidth>
            </field>
            <field>
              <name>FULL1</name>
              <bitOffset>3</bitOffset>
              <bitWidth>1</bitWidth>
            </field>
            <field>
              <name>FOVR1</name>
              <bitOffset>4</bitOffset>
              <bitWidth>1</bitWidth>
            </field>
            <field>
              <name>RFOM1</name>
              <bitOffset>5</bitOffset>
              <bitWidth>1</bitWidth>
            </field>
          </fields>
        </register>
        <register>
          <name>IER</name>
          <addressOffset>0x14</addressOffset>
          <size>0x20</size>
          <fields>
            <field>
              <name>TMEIE</name>
              <bitOffset>0</bitOffset>
              <bitWidth>1</bitWidth>
            </field>
            <field>
              <name>FMPIE0</name>
              <bitOffset>1</bitOffset>
              <bitWidth>1</bitWidth>
            </field>
            <field>
              <name>FFIE0</name>
              <bitOffset>2</bitOffset>
              <bitWidth>1</bitWidth>
            </field>
            <field>
              <name>FOVIE0</name>
              <bitOffset>3</bitOffset>
              <bitWidth>1</bitWidth>
            </field>
            <field>
              <name>FMPIE1</name>
              <bitOffset>4</bitOffset>
              <bitWidth>1</bitWidth>
            </field>
            <field>
              <name>FFIE1</name>
              <bitOffset>5</bitOffset>
              <bitWidth>1</bitWidth>
            </field>
            <field>
              <name>FOVIE1</name>
              <bitOffset>6</bitOffset>
              <bitWidth>1</bitWidth>
            </field>
            <field>
              <name>EWGIE</name>
              <bitOffset>8</bitOffset>
              <bitWidth>1</bitWidth>
            </field>
            <field>
              <name>EPVIE</name>
              <bitOffset>9</bitOffset>
              <bitWidth>1</bitWidth>
            </field>
            <field>
              <name>BOFIE</name>
              <bitOffset>10</bitOffset>
              <bitWidth>1</bitWidth>
            </field>
            <field>
              <name>LECIE</name>
              <bitOffset>11</bitOffset>
              <bitWidth>1</bitWidth>
            </field>
            <field>
              <name>ERRIE</name>
              <bitOffset>15</bitOffset>
              <bitWidth>1</bitWidth>
            </field>
            <field>
              <name>WKUIE</name>
              <bitOffset>16</bitOffset>
              <bitWidth>1</bitWidth>
            </field>
            <field>
              <name>SLKIE</name>
              <bitOffset>17</bitOffset>
              <bitWidth>1</bitWidth>
            </field>
          </fields>
        </register>
        <register>
          <name>ESR</name>
          <addressOffset>0x18</addressOffset>
          <size>0x20</size>
          <fields>
            <field>
              <name>EWGF</name>
              <bitOffset>0</bitOffset>
              <bitWidth>1</bitWidth>
            </field>
            <field>
              <name>EPVF</name>
              <bitOffset>1</bitOffset>
              <bitWidth>1</bitWidth>
            </field>
            <field>
              <name>BOFF</name>
              <bitOffset>2</bitOffset>
              <bitWidth>1</bitWidth>
            </field>
            <field>
              <name>LEC</name>
              <bitOffset>4</bitOffset>
              <bitWidth>3</bitWidth>
            </field>
            <field>
              <name>TEC</name>
              <bitOffset>16</bitOffset>
              <bitWidth>8</bitWidth>
            </field>
            <field>
              <name>REC</name>
              <bitOffset>24</bitOffset>
              <bitWidth>8</bitWidth>
            </field>
          </fields>
        </register>
        <register>
          <name>BTR</name>
          <addressOffset>0x1c</addressOffset>
          <size>0x20</size>
          <fields>
            <field>
              <name>BRP</name>
              <bitOffset>0</bitOffset>
              <bitWidth>10</bitWidth>
            </field>
            <field>
              <name>TS1</name>
              <bitOffset>16</bitOffset>
              <bitWidth>4</bitWidth>
            </field>
            <field>
              <name>TS2</name>
              <bitOffset>20</bitOffset>
              <bitWidth>3</bitWidth>
            </field>
            <field>
              <name>SJW</name>
              <bitOffset>24</bitOffset>
              <bitWidth>2</bitWidth>
            </field>
            <field>
              <name>LBKM</name>
              <bitOffset>30</bitOffset>
              <bitWidth>1</bitWidth>
            </field>
            <field>
              <name>SILM</name>
              <bitOffset>31</bitOffset>
              <bitWidth>1</bitWidth>
            </field>
          </fields>
        </register>
        <register>
          <name>sTxMailBox.0.TIR</name>
          <addressOffset>0x180</addressOffset>
          <size>0x20</size>
          <fields>
            <field>
              <name>TXRQ</name>
              <bitOffset>0</bitOffset>
              <bitWidth>1</bitWidth>
            </field>
            <field>
              <name>RTR</name>
              <bitOffset>1</bitOffset>
              <bitWidth>1</bitWidth>
            </field>
            <field>
              <name>IDE</name>
              <bitOffset>2</bitOffset>
              <bitWidth>1</bitWidth>
            </field>
            <field>
              <name>EXID</name>
              <bitOffset>3</bitOffset>
              <bitWidth>18</bitWidth>
            </field>
            <field>
              <name>STID</name>
              <bitOffset>21</bitOffset>
              <bitWidth>11</bitWidth>
            </field>
          </fields>
        </register>
        <register>
          <name>sTxMailBox.0.TDTR</name>
          <addressOffset>0x184</addressOffset>
          <size>0x20</size>
          <fields>
            <field>
              <name>DLC</name>
              <bitOffset>0</bitOffset>
              <bitWidth>4</bitWidth>
            </field>
            <field>
              <name>TGT</name>
              <bitOffset>8</bitOffset>
              <bitWidth>1</bitWidth>
            </field>
            <field>
              <name>TIME</name>
              <bitOffset>16</bitOffset>
              <bitWidth>16</bitWidth>
            </field>
          </fields>
        </register>
        <register>
          <name>sTxMailBox.0.TDLR</name>
          <addressOffset>0x188</addressOffset>
          <size>0x20</size>
          <fields>
            <field>
              <name>DATA0</name>
              <bitOffset>0</bitOffset>
              <bitWidth>8</bitWidth>
            </field>
            <field>
              <name>DATA1</name>
              <bitOffset>8</bitOffset>
              <bitWidth>8</bitWidth>
            </field>
            <field>
              <name>DATA2</name>
              <bitOffset>16</bitOffset>
              <bitWidth>8</bitWidth>
            </field>
            <field>
              <name>DATA3</name>
              <bitOffset>24</bitOffset>
              <bitWidth>8</bitWidth>
            </field>
          </fields>
        </register>
        <register>
          <name>sTxMailBox.0.TDHR</name>
          <addressOffset>0x18c</addressOffset>
          <size>0x20</size>
          <fields>
            <field>
              <name>DATA4</name>
              <bitOffset>0</bitOffset>
              <bitWidth>8</bitWidth>
            </field>
            <field>
              <name>DATA5</name>
              <bitOffset>8</bitOffset>
              <bitWidth>8</bitWidth>
            </field>
            <field>
              <name>DATA6</name>
              <bitOffset>16</bitOffset>
              <bitWidth>8</bitWidth>
            </field>
            <field>
              <name>DATA7</name>
              <bitOffset>24</bitOffset>
              <bitWidth>8</bitWidth>
            </field>
          </fields>
        </register>
        <register>
          <name>sTxMailBox.1.TIR</name>
          <addressOffset>0x190</addressOffset>
          <size>0x20</size>
          <fields>
            <field>
              <name>TXRQ</name>
              <bitOffset>0</bitOffset>
              <bitWidth>1</bitWidth>
            </field>
            <field>
              <name>RTR</name>
              <bitOffset>1</bitOffset>
              <bitWidth>1</bitWidth>
            </field>
            <field>
              <name>IDE</name>
              <bitOffset>2</bitOffset>
              <bitWidth>1</bitWidth>
            </field>
            <field>
              <name>EXID</name>
              <bitOffset>3</bitOffset>
              <bitWidth>18</bitWidth>
            </field>
            <field>
              <name>STID</name>
              <bitOffset>21</bitOffset>
              <bitWidth>11</bitWidth>
            </field>
          </fields>
        </register>
        <register>
          <name>sTxMailBox.1.TDTR</name>
          <addressOffset>0x194</addressOffset>
          <size>0x20</size>
          <fields>
            <field>
              <name>DLC</name>
              <bitOffset>0</bitOffset>
              <bitWidth>4</bitWidth>
            </field>
            <field>
              <name>TGT</name>
              <bitOffset>8</bitOffset>
              <bitWidth>1</bitWidth>
            </field>
            <field>
              <name>TIME</name>
              <bitOffset>16</bitOffset>
              <bitWidth>16</bitWidth>
            </field>
          </fields>
        </register>
        <register>
          <name>sTxMailBox.1.TDLR</name>
          <addressOffset>0x198</addressOffset>
          <size>0x20</size>
          <fields>
            <field>
              <name>DATA0</name>
              <bitOffset>0</bitOffset>
              <bitWidth>8</bitWidth>
            </field>
            <field>
              <name>DATA1</name>
              <bitOffset>8</bitOffset>
              <bitWidth>8</bitWidth>
            </field>
            <field>
              <name>DATA2</name>
              <bitOffset>16</bitOffset>
              <bitWidth>8</bitWidth>
            </field>
            <field>
              <name>DATA3</name>
              <bitOffset>24</bitOffset>
              <bitWidth>8</bitWidth>
            </field>
          </fields>
        </register>
        <register>
          <name>sTxMailBox.1.TDHR</name>
          <addressOffset>0x19c</addressOffset>
          <size>0x20</size>
          <fields>
            <field>
              <name>DATA4</name>
              <bitOffset>0</bitOffset>
              <bitWidth>8</bitWidth>
            </field>
            <field>
              <name>DATA5</name>
              <bitOffset>8</bitOffset>
              <bitWidth>8</bitWidth>
            </field>
            <field>
              <name>DATA6</name>
              <bitOffset>16</bitOffset>
              <bitWidth>8</bitWidth>
            </field>
            <field>
              <name>DATA7</name>
              <bitOffset>24</bitOffset>
              <bitWidth>8</bitWidth>
            </field>
          </fields>
        </register>
        <register>
          <name>sTxMailBox.2.TIR</name>
          <addressOffset>0x1a0</addressOffset>
          <size>0x20</size>
          <fields>
            <field>
              <name>TXRQ</name>
              <bitOffset>0</bitOffset>
              <bitWidth>1</bitWidth>
            </field>
            <field>
              <name>RTR</name>
              <bitOffset>1</bitOffset>
              <bitWidth>1</bitWidth>
            </field>
            <field>
              <name>IDE</name>
              <bitOffset>2</bitOffset>
              <bitWidth>1</bitWidth>
            </field>
            <field>
              <name>EXID</name>
              <bitOffset>3</bitOffset>
              <bitWidth>18</bitWidth>
            </field>
            <field>
              <name>STID</name>
              <bitOffset>21</bitOffset>
              <bitWidth>11</bitWidth>
            </field>
          </fields>
        </register>
        <register>
          <name>sTxMailBox.2.TDTR</name>
          <addressOffset>0x1a4</addressOffset>
          <size>0x20</size>
          <fields>
            <field>
              <name>DLC</name>
              <bitOffset>0</bitOffset>
              <bitWidth>4</bitWidth>
            </field>
            <field>
              <name>TGT</name>
              <bitOffset>8</bitOffset>
              <bitWidth>1</bitWidth>
            </field>
            <field>
              <name>TIME</name>
              <bitOffset>16</bitOffset>
              <bitWidth>16</bitWidth>
            </field>
          </fields>
        </register>
        <register>
          <name>sTxMailBox.2.TDLR</name>
          <addressOffset>0x1a8</addressOffset>
          <size>0x20</size>
          <fields>
            <field>
              <name>DATA0</name>
              <bitOffset>0</bitOffset>
              <bitWidth>8</bitWidth>
            </field>
            <field>
              <name>DATA1</name>
              <bitOffset>8</bitOffset>
              <bitWidth>8</bitWidth>
            </field>
            <field>
              <name>DATA2</name>
              <bitOffset>16</bitOffset>
              <bitWidth>8</bitWidth>
            </field>
            <field>
              <name>DATA3</name>
              <bitOffset>24</bitOffset>
              <bitWidth>8</bitWidth>
            </field>
          </fields>
        </register>
        <register>
          <name>sTxMailBox.2.TDHR</name>
          <addressOffset>0x1ac</addressOffset>
          <size>0x20</size>
          <fields>
            <field>
              <name>DATA4</name>
              <bitOffset>0</bitOffset>
              <bitWidth>8</bitWidth>
            </field>
            <field>
              <name>DATA5</name>
              <bitOffset>8</bitOffset>
              <bitWidth>8</bitWidth>
            </field>
            <field>
              <name>DATA6</name>
              <bitOffset>16</bitOffset>
              <bitWidth>8</bitWidth>
            </field>
            <field>
              <name>DATA7</name>
              <bitOffset>24</bitOffset>
              <bitWidth>8</bitWidth>
            </field>
          </fields>
        </register>
        <register>
          <name>sFIFOMailBox.0.RIR</name>
          <addressOffset>0x1b0</addressOffset>
          <size>0x20</size>
          <fields>
            <field>
              <name>RTR</name>
              <bitOffset>1</bitOffset>
              <bitWidth>1</bitWidth>
            </field>
            <field>
              <name>IDE</name>
              <bitOffset>2</bitOffset>
              <bitWidth>1</bitWidth>
            </field>
            <field>
              <name>EXID</name>
              <bitOffset>3</bitOffset>
              <bitWidth>18</bitWidth>
            </field>
            <field>
              <name>STID</name>
              <bitOffset>21</bitOffset>
              <bitWidth>11</bitWidth>
            </field>
          </fields>
        </register>
        <register>
          <name>sFIFOMailBox.0.RDTR</name>
          <addressOffset>0x1b4</addressOffset>
          <size>0x20</size>
          <fields>
            <field>
              <name>DLC</name>
              <bitOffset>0</bitOffset>
              <bitWidth>4</bitWidth>
            </field>
            <field>
              <name>FMI</name>
              <bitOffset>8</bitOffset>
              <bitWidth>8</bitWidth>
            </field>
            <field>
              <name>TIME</name>
              <bitOffset>16</bitOffset>
              <bitWidth>16</bitWidth>
            </field>
          </fields>
        </register>
        <register>
          <name>sFIFOMailBox.0.RDLR</name>
          <addressOffset>0x1b8</addressOffset>
          <size>0x20</size>
          <fields>
            <field>
              <name>DATA0</name>
              <bitOffset>0</bitOffset>
              <bitWidth>8</bitWidth>
            </field>
            <field>
              <name>DATA1</name>
              <bitOffset>8</bitOffset>
              <bitWidth>8</bitWidth>
            </field>
            <field>
              <name>DATA2</name>
              <bitOffset>16</bitOffset>
              <bitWidth>8</bitWidth>
            </field>
            <field>
              <name>DATA3</name>
              <bitOffset>24</bitOffset>
              <bitWidth>8</bitWidth>
            </field>
          </fields>
        </register>
        <register>
          <name>sFIFOMailBox.0.RDHR</name>
          <addressOffset>0x1bc</addressOffset>
          <size>0x20</size>
          <fields>
            <field>
              <name>DATA4</name>
              <bitOffset>0</bitOffset>
              <bitWidth>8</bitWidth>
            </field>
            <field>
              <name>DATA5</name>
              <bitOffset>8</bitOffset>
              <bitWidth>8</bitWidth>
            </field>
            <field>
              <name>DATA6</name>
              <bitOffset>16</bitOffset>
              <bitWidth>8</bitWidth>
            </field>
            <field>
              <name>DATA7</name>
              <bitOffset>24</bitOffset>
              <bitWidth>8</bitWidth>
            </field>
          </fields>
        </register>
        <register>
          <name>sFIFOMailBox.1.RIR</name>
          <addressOffset>0x1c0</addressOffset>
          <size>0x20</size>
          <fields>
            <field>
              <name>RTR</name>
              <bitOffset>1</bitOffset>
              <bitWidth>1</bitWidth>
            </field>
            <field>
              <name>IDE</name>
              <bitOffset>2</bitOffset>
              <bitWidth>1</bitWidth>
            </field>
            <field>
              <name>EXID</name>
              <bitOffset>3</bitOffset>
              <bitWidth>18</bitWidth>
            </field>
            <field>
              <name>STID</name>
              <bitOffset>21</bitOffset>
              <bitWidth>11</bitWidth>
            </field>
          </fields>
        </register>
        <register>
          <name>sFIFOMailBox.1.RDTR</name>
          <addressOffset>0x1c4</addressOffset>
          <size>0x20</size>
          <fields>
            <field>
              <name>DLC</name>
              <bitOffset>0</bitOffset>
              <bitWidth>4</bitWidth>
            </field>
            <field>
              <name>FMI</name>
              <bitOffset>8</bitOffset>
              <bitWidth>8</bitWidth>
            </field>
            <field>
              <name>TIME</name>
              <bitOffset>16</bitOffset>
              <bitWidth>16</bitWidth>
            </field>
          </fields>
        </register>
        <register>
          <name>sFIFOMailBox.1.RDLR</name>
          <addressOffset>0x1c8</addressOffset>
          <size>0x20</size>
          <fields>
            <field>
              <name>DATA0</name>
              <bitOffset>0</bitOffset>
              <bitWidth>8</bitWidth>
            </field>
            <field>
              <name>DATA1</name>
              <bitOffset>8</bitOffset>
              <bitWidth>8</bitWidth>
            </field>
            <field>
              <name>DATA2</name>
              <bitOffset>16</bitOffset>
              <bitWidth>8</bitWidth>
            </field>
            <field>
              <name>DATA3</name>
              <bitOffset>24</bitOffset>
              <bitWidth>8</bitWidth>
            </field>
          </fields>
        </register>
        <register>
          <name>sFIFOMailBox.1.RDHR</name>
          <addressOffset>0x1cc</addressOffset>
          <size>0x20</size>
          <fields>
            <field>
              <name>DATA4</name>
              <bitOffset>0</bitOffset>
              <bitWidth>8</bitWidth>
            </field>
            <field>
              <name>DATA5</name>
              <bitOffset>8</bitOffset>
              <bitWidth>8</bitWidth>
            </field>
            <field>
              <name>DATA6</name>
              <bitOffset>16</bitOffset>
              <bitWidth>8</bitWidth>
            </field>
            <field>
              <name>DATA7</name>
              <bitOffset>24</bitOffset>
              <bitWidth>8</bitWidth>
            </field>
          </fields>
        </register>
        <register>
          <name>FMR</name>
          <addressOffset>0x200</addressOffset>
          <size>0x20</size>
          <fields>
            <field>
              <name>FINIT</name>
              <bitOffset>0</bitOffset>
              <bitWidth>1</bitWidth>
            </field>
          </fields>
        </register>
        <register>
          <name>FM1R</name>
          <addressOffset>0x204</addressOffset>
          <size>0x20</size>
          <fields>
            <field>
              <name>FBM0</name>
              <bitOffset>0</bitOffset>
              <bitWidth>1</bitWidth>
            </field>
            <field>
              <name>FBM1</name>
              <bitOffset>1</bitOffset>
              <bitWidth>1</bitWidth>
            </field>
            <field>
              <name>FBM2</name>
              <bitOffset>2</bitOffset>
              <bitWidth>1</bitWidth>
            </field>
            <field>
              <name>FBM3</name>
              <bitOffset>3</bitOffset>
              <bitWidth>1</bitWidth>
            </field>
            <field>
              <name>FBM4</name>
              <bitOffset>4</bitOffset>
              <bitWidth>1</bitWidth>
            </field>
            <field>
              <name>FBM5</name>
              <bitOffset>5</bitOffset>
              <bitWidth>1</bitWidth>
            </field>
            <field>
              <name>FBM6</name>
              <bitOffset>6</bitOffset>
              <bitWidth>1</bitWidth>
            </field>
            <field>
              <name>FBM7</name>
              <bitOffset>7</bitOffset>
              <bitWidth>1</bitWidth>
            </field>
            <field>
              <name>FBM8</name>
              <bitOffset>8</bitOffset>
              <bitWidth>1</bitWidth>
            </field>
            <field>
              <name>FBM9</name>
              <bitOffset>9</bitOffset>
              <bitWidth>1</bitWidth>
            </field>
            <field>
              <name>FBM10</name>
              <bitOffset>10</bitOffset>
              <bitWidth>1</bitWidth>
            </field>
            <field>
              <name>FBM11</name>
              <bitOffset>11</bitOffset>
              <bitWidth>1</bitWidth>
            </field>
            <field>
              <name>FBM12</name>
              <bitOffset>12</bitOffset>
              <bitWidth>1</bitWidth>
            </field>
            <field>
              <name>FBM13</name>
              <bitOffset>13</bitOffset>
              <bitWidth>1</bitWidth>
            </field>
          </fields>
        </register>
        <register>
          <name>FS1R</name>
          <addressOffset>0x20c</addressOffset>
          <size>0x20</size>
          <fields>
            <field>
              <name>FSC0</name>
              <bitOffset>0</bitOffset>
              <bitWidth>1</bitWidth>
            </field>
            <field>
              <name>FSC1</name>
              <bitOffset>1</bitOffset>
              <bitWidth>1</bitWidth>
            </field>
            <field>
              <name>FSC2</name>
              <bitOffset>2</bitOffset>
              <bitWidth>1</bitWidth>
            </field>
            <field>
              <name>FSC3</name>
              <bitOffset>3</bitOffset>
              <bitWidth>1</bitWidth>
            </field>
            <field>
              <name>FSC4</name>
              <bitOffset>4</bitOffset>
              <bitWidth>1</bitWidth>
            </field>
            <field>
              <name>FSC5</name>
              <bitOffset>5</bitOffset>
              <bitWidth>1</bitWidth>
            </field>
            <field>
              <name>FSC6</name>
              <bitOffset>6</bitOffset>
              <bitWidth>1</bitWidth>
            </field>
            <field>
              <name>FSC7</name>
              <bitOffset>7</bitOffset>
              <bitWidth>1</bitWidth>
            </field>
            <field>
              <name>FSC8</name>
              <bitOffset>8</bitOffset>
              <bitWidth>1</bitWidth>
            </field>
            <field>
              <name>FSC9</name>
              <bitOffset>9</bitOffset>
              <bitWidth>1</bitWidth>
            </field>
            <field>
              <name>FSC10</name>
              <bitOffset>10</bitOffset>
              <bitWidth>1</bitWidth>
            </field>
            <field>
              <name>FSC11</name>
              <bitOffset>11</bitOffset>
              <bitWidth>1</bitWidth>
            </field>
            <field>
              <name>FSC12</name>
              <bitOffset>12</bitOffset>
              <bitWidth>1</bitWidth>
            </field>
            <field>
              <name>FSC13</name>
              <bitOffset>13</bitOffset>
              <bitWidth>1</bitWidth>
            </field>
          </fields>
        </register>
        <register>
          <name>FFA1R</name>
          <addressOffset>0x214</addressOffset>
          <size>0x20</size>
          <fields>
            <field>
              <name>FFA0</name>
              <bitOffset>0</bitOffset>
              <bitWidth>1</bitWidth>
            </field>
            <field>
              <name>FFA1</name>
              <bitOffset>1</bitOffset>
              <bitWidth>1</bitWidth>
            </field>
            <field>
              <name>FFA2</name>
              <bitOffset>2</bitOffset>
              <bitWidth>1</bitWidth>
            </field>
            <field>
              <name>FFA3</name>
              <bitOffset>3</bitOffset>
              <bitWidth>1</bitWidth>
            </field>
            <field>
              <name>FFA4</name>
              <bitOffset>4</bitOffset>
              <bitWidth>1</bitWidth>
            </field>
            <field>
              <name>FFA5</name>
              <bitOffset>5</bitOffset>
              <bitWidth>1</bitWidth>
            </field>
            <field>
              <name>FFA6</name>
              <bitOffset>6</bitOffset>
              <bitWidth>1</bitWidth>
            </field>
            <field>
              <name>FFA7</name>
              <bitOffset>7</bitOffset>
              <bitWidth>1</bitWidth>
            </field>
            <field>
              <name>FFA8</name>
              <bitOffset>8</bitOffset>
              <bitWidth>1</bitWidth>
            </field>
            <field>
              <name>FFA9</name>
              <bitOffset>9</bitOffset>
              <bitWidth>1</bitWidth>
            </field>
            <field>
              <name>FFA10</name>
              <bitOffset>10</bitOffset>
              <bitWidth>1</bitWidth>
            </field>
            <field>
              <name>FFA11</name>
              <bitOffset>11</bitOffset>
              <bitWidth>1</bitWidth>
            </field>
            <field>
              <name>FFA12</name>
              <bitOffset>12</bitOffset>
              <bitWidth>1</bitWidth>
            </field>
            <field>
              <name>FFA13</name>
              <bitOffset>13</bitOffset>
              <bitWidth>1</bitWidth>
            </field>
          </fields>
        </register>
        <register>
          <name>FA1R</name>
          <addressOffset>0x21c</addressOffset>
          <size>0x20</size>
          <fields>
            <field>
              <name>FACT0</name>
              <bitOffset>0</bitOffset>
              <bitWidth>1</bitWidth>
            </field>
            <field>
              <name>FACT1</name>
              <bitOffset>1</bitOffset>
              <bitWidth>1</bitWidth>
            </field>
            <field>
              <name>FACT2</name>
              <bitOffset>2</bitOffset>
              <bitWidth>1</bitWidth>
            </field>
            <field>
              <name>FACT3</name>
              <bitOffset>3</bitOffset>
              <bitWidth>1</bitWidth>
            </field>
            <field>
              <name>FACT4</name>
              <bitOffset>4</bitOffset>
              <bitWidth>1</bitWidth>
            </field>
            <field>
              <name>FACT5</name>
              <bitOffset>5</bitOffset>
              <bitWidth>1</bitWidth>
            </field>
            <field>
              <name>FACT6</name>
              <bitOffset>6</bitOffset>
              <bitWidth>1</bitWidth>
            </field>
            <field>
              <name>FACT7</name>
              <bitOffset>7</bitOffset>
              <bitWidth>1</bitWidth>
            </field>
            <field>
              <name>FACT8</name>
              <bitOffset>8</bitOffset>
              <bitWidth>1</bitWidth>
            </field>
            <field>
              <name>FACT9</name>
              <bitOffset>9</bitOffset>
              <bitWidth>1</bitWidth>
            </field>
            <field>
              <name>FACT10</name>
              <bitOffset>10</bitOffset>
              <bitWidth>1</bitWidth>
            </field>
            <field>
              <name>FACT11</name>
              <bitOffset>11</bitOffset>
              <bitWidth>1</bitWidth>
            </field>
            <field>
              <name>FACT12</name>
              <bitOffset>12</bitOffset>
              <bitWidth>1</bitWidth>
            </field>
            <field>
              <name>FACT13</name>
              <bitOffset>13</bitOffset>
              <bitWidth>1</bitWidth>
            </field>
          </fields>
        </register>
        <register>
          <name>sFilterRegister.0.FR1</name>
          <addressOffset>0x240</addressOffset>
          <size>0x20</size>
          <fields>
            <field>
              <name>FB0</name>
              <bitOffset>0</bitOffset>
              <bitWidth>1</bitWidth>
            </field>
            <field>
              <name>FB1</name>
              <bitOffset>1</bitOffset>
              <bitWidth>1</bitWidth>
            </field>
            <field>
              <name>FB2</name>
              <bitOffset>2</bitOffset>
              <bitWidth>1</bitWidth>
            </field>
            <field>
              <name>FB3</name>
              <bitOffset>3</bitOffset>
              <bitWidth>1</bitWidth>
            </field>
            <field>
              <name>FB4</name>
              <bitOffset>4</bitOffset>
              <bitWidth>1</bitWidth>
            </field>
            <field>
              <name>FB5</name>
              <bitOffset>5</bitOffset>
              <bitWidth>1</bitWidth>
            </field>
            <field>
              <name>FB6</name>
              <bitOffset>6</bitOffset>
              <bitWidth>1</bitWidth>
            </field>
            <field>
              <name>FB7</name>
              <bitOffset>7</bitOffset>
              <bitWidth>1</bitWidth>
            </field>
            <field>
              <name>FB8</name>
              <bitOffset>8</bitOffset>
              <bitWidth>1</bitWidth>
            </field>
            <field>
              <name>FB9</name>
              <bitOffset>9</bitOffset>
              <bitWidth>1</bitWidth>
            </field>
            <field>
              <name>FB10</name>
              <bitOffset>10</bitOffset>
              <bitWidth>1</bitWidth>
            </field>
            <field>
              <name>FB11</name>
              <bitOffset>11</bitOffset>
              <bitWidth>1</bitWidth>
            </field>
            <field>
              <name>FB12</name>
              <bitOffset>12</bitOffset>
              <bitWidth>1</bitWidth>
            </field>
            <field>
              <name>FB13</name>
              <bitOffset>13</bitOffset>
              <bitWidth>1</bitWidth>
            </field>
            <field>
              <name>FB14</name>
              <bitOffset>14</bitOffset>
              <bitWidth>1</bitWidth>
            </field>
            <field>
              <name>FB15</name>
              <bitOffset>15</bitOffset>
              <bitWidth>1</bitWidth>
            </field>
            <field>
              <name>FB16</name>
              <bitOffset>16</bitOffset>
              <bitWidth>1</bitWidth>
            </field>
            <field>
              <name>FB17</name>
              <bitOffset>17</bitOffset>
              <bitWidth>1</bitWidth>
            </field>
            <field>
              <name>FB18</name>
              <bitOffset>18</bitOffset>
              <bitWidth>1</bitWidth>
            </field>
            <field>
              <name>FB19</name>
              <bitOffset>19</bitOffset>
              <bitWidth>1</bitWidth>
            </field>
            <field>
              <name>FB20</name>
              <bitOffset>20</bitOffset>
              <bitWidth>1</bitWidth>
            </field>
            <field>
              <name>FB21</name>
              <bitOffset>21</bitOffset>
              <bitWidth>1</bitWidth>
            </field>
            <field>
              <name>FB22</name>
              <bitOffset>22</bitOffset>
              <bitWidth>1</bitWidth>
            </field>
            <field>
              <name>FB23</name>
              <bitOffset>23</bitOffset>
              <bitWidth>1</bitWidth>
            </field>
            <field>
              <name>FB24</name>
              <bitOffset>24</bitOffset>
              <bitWidth>1</bitWidth>
            </field>
            <field>
              <name>FB25</name>
              <bitOffset>25</bitOffset>
              <bitWidth>1</bitWidth>
            </field>
            <field>
              <name>FB26</name>
              <bitOffset>26</bitOffset>
              <bitWidth>1</bitWidth>
            </field>
            <field>
              <name>FB27</name>
              <bitOffset>27</bitOffset>
              <bitWidth>1</bitWidth>
            </field>
            <field>
              <name>FB28</name>
              <bitOffset>28</bitOffset>
              <bitWidth>1</bitWidth>
            </field>
            <field>
              <name>FB29</name>
              <bitOffset>29</bitOffset>
              <bitWidth>1</bitWidth>
            </field>
            <field>
              <name>FB30</name>
              <bitOffset>30</bitOffset>
              <bitWidth>1</bitWidth>
            </field>
            <field>
              <name>FB31</name>
              <bitOffset>31</bitOffset>
              <bitWidth>1</bitWidth>
            </field>
          </fields>
        </register>
        <register>
          <name>sFilterRegister.0.FR2</name>
          <addressOffset>0x244</addressOffset>
          <size>0x20</size>
          <fields>
            <field>
              <name>FB0</name>
              <bitOffset>0</bitOffset>
              <bitWidth>1</bitWidth>
            </field>
            <field>
              <name>FB1</name>
              <bitOffset>1</bitOffset>
              <bitWidth>1</bitWidth>
            </field>
            <field>
              <name>FB2</name>
              <bitOffset>2</bitOffset>
              <bitWidth>1</bitWidth>
            </field>
            <field>
              <name>FB3</name>
              <bitOffset>3</bitOffset>
              <bitWidth>1</bitWidth>
            </field>
            <field>
              <name>FB4</name>
              <bitOffset>4</bitOffset>
              <bitWidth>1</bitWidth>
            </field>
            <field>
              <name>FB5</name>
              <bitOffset>5</bitOffset>
              <bitWidth>1</bitWidth>
            </field>
            <field>
              <name>FB6</name>
              <bitOffset>6</bitOffset>
              <bitWidth>1</bitWidth>
            </field>
            <field>
              <name>FB7</name>
              <bitOffset>7</bitOffset>
              <bitWidth>1</bitWidth>
            </field>
            <field>
              <name>FB8</name>
              <bitOffset>8</bitOffset>
              <bitWidth>1</bitWidth>
            </field>
            <field>
              <name>FB9</name>
              <bitOffset>9</bitOffset>
              <bitWidth>1</bitWidth>
            </field>
            <field>
              <name>FB10</name>
              <bitOffset>10</bitOffset>
              <bitWidth>1</bitWidth>
            </field>
            <field>
              <name>FB11</name>
              <bitOffset>11</bitOffset>
              <bitWidth>1</bitWidth>
            </field>
            <field>
              <name>FB12</name>
              <bitOffset>12</bitOffset>
              <bitWidth>1</bitWidth>
            </field>
            <field>
              <name>FB13</name>
              <bitOffset>13</bitOffset>
              <bitWidth>1</bitWidth>
            </field>
            <field>
              <name>FB14</name>
              <bitOffset>14</bitOffset>
              <bitWidth>1</bitWidth>
            </field>
            <field>
              <name>FB15</name>
              <bitOffset>15</bitOffset>
              <bitWidth>1</bitWidth>
            </field>
            <field>
              <name>FB16</name>
              <bitOffset>16</bitOffset>
              <bitWidth>1</bitWidth>
            </field>
            <field>
              <name>FB17</name>
              <bitOffset>17</bitOffset>
              <bitWidth>1</bitWidth>
            </field>
            <field>
              <name>FB18</name>
              <bitOffset>18</bitOffset>
              <bitWidth>1</bitWidth>
            </field>
            <field>
              <name>FB19</name>
              <bitOffset>19</bitOffset>
              <bitWidth>1</bitWidth>
            </field>
            <field>
              <name>FB20</name>
              <bitOffset>20</bitOffset>
              <bitWidth>1</bitWidth>
            </field>
            <field>
              <name>FB21</name>
              <bitOffset>21</bitOffset>
              <bitWidth>1</bitWidth>
            </field>
            <field>
              <name>FB22</name>
              <bitOffset>22</bitOffset>
              <bitWidth>1</bitWidth>
            </field>
            <field>
              <name>FB23</name>
              <bitOffset>23</bitOffset>
              <bitWidth>1</bitWidth>
            </field>
            <field>
              <name>FB24</name>
              <bitOffset>24</bitOffset>
              <bitWidth>1</bitWidth>
            </field>
            <field>
              <name>FB25</name>
              <bitOffset>25</bitOffset>
              <bitWidth>1</bitWidth>
            </field>
            <field>
              <name>FB26</name>
              <bitOffset>26</bitOffset>
              <bitWidth>1</bitWidth>
            </field>
            <field>
              <name>FB27</name>
              <bitOffset>27</bitOffset>
              <bitWidth>1</bitWidth>
            </field>
            <field>
              <name>FB28</name>
              <bitOffset>28</bitOffset>
              <bitWidth>1</bitWidth>
            </field>
            <field>
              <name>FB29</name>
              <bitOffset>29</bitOffset>
              <bitWidth>1</bitWidth>
            </field>
            <field>
              <name>FB30</name>
              <bitOffset>30</bitOffset>
              <bitWidth>1</bitWidth>
            </field>
            <field>
              <name>FB31</name>
              <bitOffset>31</bitOffset>
              <bitWidth>1</bitWidth>
            </field>
          </fields>
        </register>
        <register>
          <name>sFilterRegister.1.FR1</name>
          <addressOffset>0x248</addressOffset>
          <size>0x20</size>
          <fields>
            <field>
              <name>FB0</name>
              <bitOffset>0</bitOffset>
              <bitWidth>1</bitWidth>
            </field>
            <field>
              <name>FB1</name>
              <bitOffset>1</bitOffset>
              <bitWidth>1</bitWidth>
            </field>
            <field>
              <name>FB2</name>
              <bitOffset>2</bitOffset>
              <bitWidth>1</bitWidth>
            </field>
            <field>
              <name>FB3</name>
              <bitOffset>3</bitOffset>
              <bitWidth>1</bitWidth>
            </field>
            <field>
              <name>FB4</name>
              <bitOffset>4</bitOffset>
              <bitWidth>1</bitWidth>
            </field>
            <field>
              <name>FB5</name>
              <bitOffset>5</bitOffset>
              <bitWidth>1</bitWidth>
            </field>
            <field>
              <name>FB6</name>
              <bitOffset>6</bitOffset>
              <bitWidth>1</bitWidth>
            </field>
            <field>
              <name>FB7</name>
              <bitOffset>7</bitOffset>
              <bitWidth>1</bitWidth>
            </field>
            <field>
              <name>FB8</name>
              <bitOffset>8</bitOffset>
              <bitWidth>1</bitWidth>
            </field>
            <field>
              <name>FB9</name>
              <bitOffset>9</bitOffset>
              <bitWidth>1</bitWidth>
            </field>
            <field>
              <name>FB10</name>
              <bitOffset>10</bitOffset>
              <bitWidth>1</bitWidth>
            </field>
            <field>
              <name>FB11</name>
              <bitOffset>11</bitOffset>
              <bitWidth>1</bitWidth>
            </field>
            <field>
              <name>FB12</name>
              <bitOffset>12</bitOffset>
              <bitWidth>1</bitWidth>
            </field>
            <field>
              <name>FB13</name>
              <bitOffset>13</bitOffset>
              <bitWidth>1</bitWidth>
            </field>
            <field>
              <name>FB14</name>
              <bitOffset>14</bitOffset>
              <bitWidth>1</bitWidth>
            </field>
            <field>
              <name>FB15</name>
              <bitOffset>15</bitOffset>
              <bitWidth>1</bitWidth>
            </field>
            <field>
              <name>FB16</name>
              <bitOffset>16</bitOffset>
              <bitWidth>1</bitWidth>
            </field>
            <field>
              <name>FB17</name>
              <bitOffset>17</bitOffset>
              <bitWidth>1</bitWidth>
            </field>
            <field>
              <name>FB18</name>
              <bitOffset>18</bitOffset>
              <bitWidth>1</bitWidth>
            </field>
            <field>
              <name>FB19</name>
              <bitOffset>19</bitOffset>
              <bitWidth>1</bitWidth>
            </field>
            <field>
              <name>FB20</name>
              <bitOffset>20</bitOffset>
              <bitWidth>1</bitWidth>
            </field>
            <field>
              <name>FB21</name>
              <bitOffset>21</bitOffset>
              <bitWidth>1</bitWidth>
            </field>
            <field>
              <name>FB22</name>
              <bitOffset>22</bitOffset>
              <bitWidth>1</bitWidth>
            </field>
            <field>
              <name>FB23</name>
              <bitOffset>23</bitOffset>
              <bitWidth>1</bitWidth>
            </field>
            <field>
              <name>FB24</name>
              <bitOffset>24</bitOffset>
              <bitWidth>1</bitWidth>
            </field>
            <field>
              <name>FB25</name>
              <bitOffset>25</bitOffset>
              <bitWidth>1</bitWidth>
            </field>
            <field>
              <name>FB26</name>
              <bitOffset>26</bitOffset>
              <bitWidth>1</bitWidth>
            </field>
            <field>
              <name>FB27</name>
              <bitOffset>27</bitOffset>
              <bitWidth>1</bitWidth>
            </field>
            <field>
              <name>FB28</name>
              <bitOffset>28</bitOffset>
              <bitWidth>1</bitWidth>
            </field>
            <field>
              <name>FB29</name>
              <bitOffset>29</bitOffset>
              <bitWidth>1</bitWidth>
            </field>
            <field>
              <name>FB30</name>
              <bitOffset>30</bitOffset>
              <bitWidth>1</bitWidth>
            </field>
            <field>
              <name>FB31</name>
              <bitOffset>31</bitOffset>
              <bitWidth>1</bitWidth>
            </field>
          </fields>
        </register>
        <register>
          <name>sFilterRegister.1.FR2</name>
          <addressOffset>0x24c</addressOffset>
          <size>0x20</size>
          <fields>
            <field>
              <name>FB0</name>
              <bitOffset>0</bitOffset>
              <bitWidth>1</bitWidth>
            </field>
            <field>
              <name>FB1</name>
              <bitOffset>1</bitOffset>
              <bitWidth>1</bitWidth>
            </field>
            <field>
              <name>FB2</name>
              <bitOffset>2</bitOffset>
              <bitWidth>1</bitWidth>
            </field>
            <field>
              <name>FB3</name>
              <bitOffset>3</bitOffset>
              <bitWidth>1</bitWidth>
            </field>
            <field>
              <name>FB4</name>
              <bitOffset>4</bitOffset>
              <bitWidth>1</bitWidth>
            </field>
            <field>
              <name>FB5</name>
              <bitOffset>5</bitOffset>
              <bitWidth>1</bitWidth>
            </field>
            <field>
              <name>FB6</name>
              <bitOffset>6</bitOffset>
              <bitWidth>1</bitWidth>
            </field>
            <field>
              <name>FB7</name>
              <bitOffset>7</bitOffset>
              <bitWidth>1</bitWidth>
            </field>
            <field>
              <name>FB8</name>
              <bitOffset>8</bitOffset>
              <bitWidth>1</bitWidth>
            </field>
            <field>
              <name>FB9</name>
              <bitOffset>9</bitOffset>
              <bitWidth>1</bitWidth>
            </field>
            <field>
              <name>FB10</name>
              <bitOffset>10</bitOffset>
              <bitWidth>1</bitWidth>
            </field>
            <field>
              <name>FB11</name>
              <bitOffset>11</bitOffset>
              <bitWidth>1</bitWidth>
            </field>
            <field>
              <name>FB12</name>
              <bitOffset>12</bitOffset>
              <bitWidth>1</bitWidth>
            </field>
            <field>
              <name>FB13</name>
              <bitOffset>13</bitOffset>
              <bitWidth>1</bitWidth>
            </field>
            <field>
              <name>FB14</name>
              <bitOffset>14</bitOffset>
              <bitWidth>1</bitWidth>
            </field>
            <field>
              <name>FB15</name>
              <bitOffset>15</bitOffset>
              <bitWidth>1</bitWidth>
            </field>
            <field>
              <name>FB16</name>
              <bitOffset>16</bitOffset>
              <bitWidth>1</bitWidth>
            </field>
            <field>
              <name>FB17</name>
              <bitOffset>17</bitOffset>
              <bitWidth>1</bitWidth>
            </field>
            <field>
              <name>FB18</name>
              <bitOffset>18</bitOffset>
              <bitWidth>1</bitWidth>
            </field>
            <field>
              <name>FB19</name>
              <bitOffset>19</bitOffset>
              <bitWidth>1</bitWidth>
            </field>
            <field>
              <name>FB20</name>
              <bitOffset>20</bitOffset>
              <bitWidth>1</bitWidth>
            </field>
            <field>
              <name>FB21</name>
              <bitOffset>21</bitOffset>
              <bitWidth>1</bitWidth>
            </field>
            <field>
              <name>FB22</name>
              <bitOffset>22</bitOffset>
              <bitWidth>1</bitWidth>
            </field>
            <field>
              <name>FB23</name>
              <bitOffset>23</bitOffset>
              <bitWidth>1</bitWidth>
            </field>
            <field>
              <name>FB24</name>
              <bitOffset>24</bitOffset>
              <bitWidth>1</bitWidth>
            </field>
            <field>
              <name>FB25</name>
              <bitOffset>25</bitOffset>
              <bitWidth>1</bitWidth>
            </field>
            <field>
              <name>FB26</name>
              <bitOffset>26</bitOffset>
              <bitWidth>1</bitWidth>
            </field>
            <field>
              <name>FB27</name>
              <bitOffset>27</bitOffset>
              <bitWidth>1</bitWidth>
            </field>
            <field>
              <name>FB28</name>
              <bitOffset>28</bitOffset>
              <bitWidth>1</bitWidth>
            </field>
            <field>
              <name>FB29</name>
              <bitOffset>29</bitOffset>
              <bitWidth>1</bitWidth>
            </field>
            <field>
              <name>FB30</name>
              <bitOffset>30</bitOffset>
              <bitWidth>1</bitWidth>
            </field>
            <field>
              <name>FB31</name>
              <bitOffset>31</bitOffset>
              <bitWidth>1</bitWidth>
            </field>
          </fields>
        </register>
        <register>
          <name>sFilterRegister.2.FR1</name>
          <addressOffset>0x250</addressOffset>
          <size>0x20</size>
          <fields>
            <field>
              <name>FB0</name>
              <bitOffset>0</bitOffset>
              <bitWidth>1</bitWidth>
            </field>
            <field>
              <name>FB1</name>
              <bitOffset>1</bitOffset>
              <bitWidth>1</bitWidth>
            </field>
            <field>
              <name>FB2</name>
              <bitOffset>2</bitOffset>
              <bitWidth>1</bitWidth>
            </field>
            <field>
              <name>FB3</name>
              <bitOffset>3</bitOffset>
              <bitWidth>1</bitWidth>
            </field>
            <field>
              <name>FB4</name>
              <bitOffset>4</bitOffset>
              <bitWidth>1</bitWidth>
            </field>
            <field>
              <name>FB5</name>
              <bitOffset>5</bitOffset>
              <bitWidth>1</bitWidth>
            </field>
            <field>
              <name>FB6</name>
              <bitOffset>6</bitOffset>
              <bitWidth>1</bitWidth>
            </field>
            <field>
              <name>FB7</name>
              <bitOffset>7</bitOffset>
              <bitWidth>1</bitWidth>
            </field>
            <field>
              <name>FB8</name>
              <bitOffset>8</bitOffset>
              <bitWidth>1</bitWidth>
            </field>
            <field>
              <name>FB9</name>
              <bitOffset>9</bitOffset>
              <bitWidth>1</bitWidth>
            </field>
            <field>
              <name>FB10</name>
              <bitOffset>10</bitOffset>
              <bitWidth>1</bitWidth>
            </field>
            <field>
              <name>FB11</name>
              <bitOffset>11</bitOffset>
              <bitWidth>1</bitWidth>
            </field>
            <field>
              <name>FB12</name>
              <bitOffset>12</bitOffset>
              <bitWidth>1</bitWidth>
            </field>
            <field>
              <name>FB13</name>
              <bitOffset>13</bitOffset>
              <bitWidth>1</bitWidth>
            </field>
            <field>
              <name>FB14</name>
              <bitOffset>14</bitOffset>
              <bitWidth>1</bitWidth>
            </field>
            <field>
              <name>FB15</name>
              <bitOffset>15</bitOffset>
              <bitWidth>1</bitWidth>
            </field>
            <field>
              <name>FB16</name>
              <bitOffset>16</bitOffset>
              <bitWidth>1</bitWidth>
            </field>
            <field>
              <name>FB17</name>
              <bitOffset>17</bitOffset>
              <bitWidth>1</bitWidth>
            </field>
            <field>
              <name>FB18</name>
              <bitOffset>18</bitOffset>
              <bitWidth>1</bitWidth>
            </field>
            <field>
              <name>FB19</name>
              <bitOffset>19</bitOffset>
              <bitWidth>1</bitWidth>
            </field>
            <field>
              <name>FB20</name>
              <bitOffset>20</bitOffset>
              <bitWidth>1</bitWidth>
            </field>
            <field>
              <name>FB21</name>
              <bitOffset>21</bitOffset>
              <bitWidth>1</bitWidth>
            </field>
            <field>
              <name>FB22</name>
              <bitOffset>22</bitOffset>
              <bitWidth>1</bitWidth>
            </field>
            <field>
              <name>FB23</name>
              <bitOffset>23</bitOffset>
              <bitWidth>1</bitWidth>
            </field>
            <field>
              <name>FB24</name>
              <bitOffset>24</bitOffset>
              <bitWidth>1</bitWidth>
            </field>
            <field>
              <name>FB25</name>
              <bitOffset>25</bitOffset>
              <bitWidth>1</bitWidth>
            </field>
            <field>
              <name>FB26</name>
              <bitOffset>26</bitOffset>
              <bitWidth>1</bitWidth>
            </field>
            <field>
              <name>FB27</name>
              <bitOffset>27</bitOffset>
              <bitWidth>1</bitWidth>
            </field>
            <field>
              <name>FB28</name>
              <bitOffset>28</bitOffset>
              <bitWidth>1</bitWidth>
            </field>
            <field>
              <name>FB29</name>
              <bitOffset>29</bitOffset>
              <bitWidth>1</bitWidth>
            </field>
            <field>
              <name>FB30</name>
              <bitOffset>30</bitOffset>
              <bitWidth>1</bitWidth>
            </field>
            <field>
              <name>FB31</name>
              <bitOffset>31</bitOffset>
              <bitWidth>1</bitWidth>
            </field>
          </fields>
        </register>
        <register>
          <name>sFilterRegister.2.FR2</name>
          <addressOffset>0x254</addressOffset>
          <size>0x20</size>
          <fields>
            <field>
              <name>FB0</name>
              <bitOffset>0</bitOffset>
              <bitWidth>1</bitWidth>
            </field>
            <field>
              <name>FB1</name>
              <bitOffset>1</bitOffset>
              <bitWidth>1</bitWidth>
            </field>
            <field>
              <name>FB2</name>
              <bitOffset>2</bitOffset>
              <bitWidth>1</bitWidth>
            </field>
            <field>
              <name>FB3</name>
              <bitOffset>3</bitOffset>
              <bitWidth>1</bitWidth>
            </field>
            <field>
              <name>FB4</name>
              <bitOffset>4</bitOffset>
              <bitWidth>1</bitWidth>
            </field>
            <field>
              <name>FB5</name>
              <bitOffset>5</bitOffset>
              <bitWidth>1</bitWidth>
            </field>
            <field>
              <name>FB6</name>
              <bitOffset>6</bitOffset>
              <bitWidth>1</bitWidth>
            </field>
            <field>
              <name>FB7</name>
              <bitOffset>7</bitOffset>
              <bitWidth>1</bitWidth>
            </field>
            <field>
              <name>FB8</name>
              <bitOffset>8</bitOffset>
              <bitWidth>1</bitWidth>
            </field>
            <field>
              <name>FB9</name>
              <bitOffset>9</bitOffset>
              <bitWidth>1</bitWidth>
            </field>
            <field>
              <name>FB10</name>
              <bitOffset>10</bitOffset>
              <bitWidth>1</bitWidth>
            </field>
            <field>
              <name>FB11</name>
              <bitOffset>11</bitOffset>
              <bitWidth>1</bitWidth>
            </field>
            <field>
              <name>FB12</name>
              <bitOffset>12</bitOffset>
              <bitWidth>1</bitWidth>
            </field>
            <field>
              <name>FB13</name>
              <bitOffset>13</bitOffset>
              <bitWidth>1</bitWidth>
            </field>
            <field>
              <name>FB14</name>
              <bitOffset>14</bitOffset>
              <bitWidth>1</bitWidth>
            </field>
            <field>
              <name>FB15</name>
              <bitOffset>15</bitOffset>
              <bitWidth>1</bitWidth>
            </field>
            <field>
              <name>FB16</name>
              <bitOffset>16</bitOffset>
              <bitWidth>1</bitWidth>
            </field>
            <field>
              <name>FB17</name>
              <bitOffset>17</bitOffset>
              <bitWidth>1</bitWidth>
            </field>
            <field>
              <name>FB18</name>
              <bitOffset>18</bitOffset>
              <bitWidth>1</bitWidth>
            </field>
            <field>
              <name>FB19</name>
              <bitOffset>19</bitOffset>
              <bitWidth>1</bitWidth>
            </field>
            <field>
              <name>FB20</name>
              <bitOffset>20</bitOffset>
              <bitWidth>1</bitWidth>
            </field>
            <field>
              <name>FB21</name>
              <bitOffset>21</bitOffset>
              <bitWidth>1</bitWidth>
            </field>
            <field>
              <name>FB22</name>
              <bitOffset>22</bitOffset>
              <bitWidth>1</bitWidth>
            </field>
            <field>
              <name>FB23</name>
              <bitOffset>23</bitOffset>
              <bitWidth>1</bitWidth>
            </field>
            <field>
              <name>FB24</name>
              <bitOffset>24</bitOffset>
              <bitWidth>1</bitWidth>
            </field>
            <field>
              <name>FB25</name>
              <bitOffset>25</bitOffset>
              <bitWidth>1</bitWidth>
            </field>
            <field>
              <name>FB26</name>
              <bitOffset>26</bitOffset>
              <bitWidth>1</bitWidth>
            </field>
            <field>
              <name>FB27</name>
              <bitOffset>27</bitOffset>
              <bitWidth>1</bitWidth>
            </field>
            <field>
              <name>FB28</name>
              <bitOffset>28</bitOffset>
              <bitWidth>1</bitWidth>
            </field>
            <field>
              <name>FB29</name>
              <bitOffset>29</bitOffset>
              <bitWidth>1</bitWidth>
            </field>
            <field>
              <name>FB30</name>
              <bitOffset>30</bitOffset>
              <bitWidth>1</bitWidth>
            </field>
            <field>
              <name>FB31</name>
              <bitOffset>31</bitOffset>
              <bitWidth>1</bitWidth>
            </field>
          </fields>
        </register>
        <register>
          <name>sFilterRegister.3.FR1</name>
          <addressOffset>0x258</addressOffset>
          <size>0x20</size>
          <fields>
            <field>
              <name>FB0</name>
              <bitOffset>0</bitOffset>
              <bitWidth>1</bitWidth>
            </field>
            <field>
              <name>FB1</name>
              <bitOffset>1</bitOffset>
              <bitWidth>1</bitWidth>
            </field>
            <field>
              <name>FB2</name>
              <bitOffset>2</bitOffset>
              <bitWidth>1</bitWidth>
            </field>
            <field>
              <name>FB3</name>
              <bitOffset>3</bitOffset>
              <bitWidth>1</bitWidth>
            </field>
            <field>
              <name>FB4</name>
              <bitOffset>4</bitOffset>
              <bitWidth>1</bitWidth>
            </field>
            <field>
              <name>FB5</name>
              <bitOffset>5</bitOffset>
              <bitWidth>1</bitWidth>
            </field>
            <field>
              <name>FB6</name>
              <bitOffset>6</bitOffset>
              <bitWidth>1</bitWidth>
            </field>
            <field>
              <name>FB7</name>
              <bitOffset>7</bitOffset>
              <bitWidth>1</bitWidth>
            </field>
            <field>
              <name>FB8</name>
              <bitOffset>8</bitOffset>
              <bitWidth>1</bitWidth>
            </field>
            <field>
              <name>FB9</name>
              <bitOffset>9</bitOffset>
              <bitWidth>1</bitWidth>
            </field>
            <field>
              <name>FB10</name>
              <bitOffset>10</bitOffset>
              <bitWidth>1</bitWidth>
            </field>
            <field>
              <name>FB11</name>
              <bitOffset>11</bitOffset>
              <bitWidth>1</bitWidth>
            </field>
            <field>
              <name>FB12</name>
              <bitOffset>12</bitOffset>
              <bitWidth>1</bitWidth>
            </field>
            <field>
              <name>FB13</name>
              <bitOffset>13</bitOffset>
              <bitWidth>1</bitWidth>
            </field>
            <field>
              <name>FB14</name>
              <bitOffset>14</bitOffset>
              <bitWidth>1</bitWidth>
            </field>
            <field>
              <name>FB15</name>
              <bitOffset>15</bitOffset>
              <bitWidth>1</bitWidth>
            </field>
            <field>
              <name>FB16</name>
              <bitOffset>16</bitOffset>
              <bitWidth>1</bitWidth>
            </field>
            <field>
              <name>FB17</name>
              <bitOffset>17</bitOffset>
              <bitWidth>1</bitWidth>
            </field>
            <field>
              <name>FB18</name>
              <bitOffset>18</bitOffset>
              <bitWidth>1</bitWidth>
            </field>
            <field>
              <name>FB19</name>
              <bitOffset>19</bitOffset>
              <bitWidth>1</bitWidth>
            </field>
            <field>
              <name>FB20</name>
              <bitOffset>20</bitOffset>
              <bitWidth>1</bitWidth>
            </field>
            <field>
              <name>FB21</name>
              <bitOffset>21</bitOffset>
              <bitWidth>1</bitWidth>
            </field>
            <field>
              <name>FB22</name>
              <bitOffset>22</bitOffset>
              <bitWidth>1</bitWidth>
            </field>
            <field>
              <name>FB23</name>
              <bitOffset>23</bitOffset>
              <bitWidth>1</bitWidth>
            </field>
            <field>
              <name>FB24</name>
              <bitOffset>24</bitOffset>
              <bitWidth>1</bitWidth>
            </field>
            <field>
              <name>FB25</name>
              <bitOffset>25</bitOffset>
              <bitWidth>1</bitWidth>
            </field>
            <field>
              <name>FB26</name>
              <bitOffset>26</bitOffset>
              <bitWidth>1</bitWidth>
            </field>
            <field>
              <name>FB27</name>
              <bitOffset>27</bitOffset>
              <bitWidth>1</bitWidth>
            </field>
            <field>
              <name>FB28</name>
              <bitOffset>28</bitOffset>
              <bitWidth>1</bitWidth>
            </field>
            <field>
              <name>FB29</name>
              <bitOffset>29</bitOffset>
              <bitWidth>1</bitWidth>
            </field>
            <field>
              <name>FB30</name>
              <bitOffset>30</bitOffset>
              <bitWidth>1</bitWidth>
            </field>
            <field>
              <name>FB31</name>
              <bitOffset>31</bitOffset>
              <bitWidth>1</bitWidth>
            </field>
          </fields>
        </register>
        <register>
          <name>sFilterRegister.3.FR2</name>
          <addressOffset>0x25c</addressOffset>
          <size>0x20</size>
          <fields>
            <field>
              <name>FB0</name>
              <bitOffset>0</bitOffset>
              <bitWidth>1</bitWidth>
            </field>
            <field>
              <name>FB1</name>
              <bitOffset>1</bitOffset>
              <bitWidth>1</bitWidth>
            </field>
            <field>
              <name>FB2</name>
              <bitOffset>2</bitOffset>
              <bitWidth>1</bitWidth>
            </field>
            <field>
              <name>FB3</name>
              <bitOffset>3</bitOffset>
              <bitWidth>1</bitWidth>
            </field>
            <field>
              <name>FB4</name>
              <bitOffset>4</bitOffset>
              <bitWidth>1</bitWidth>
            </field>
            <field>
              <name>FB5</name>
              <bitOffset>5</bitOffset>
              <bitWidth>1</bitWidth>
            </field>
            <field>
              <name>FB6</name>
              <bitOffset>6</bitOffset>
              <bitWidth>1</bitWidth>
            </field>
            <field>
              <name>FB7</name>
              <bitOffset>7</bitOffset>
              <bitWidth>1</bitWidth>
            </field>
            <field>
              <name>FB8</name>
              <bitOffset>8</bitOffset>
              <bitWidth>1</bitWidth>
            </field>
            <field>
              <name>FB9</name>
              <bitOffset>9</bitOffset>
              <bitWidth>1</bitWidth>
            </field>
            <field>
              <name>FB10</name>
              <bitOffset>10</bitOffset>
              <bitWidth>1</bitWidth>
            </field>
            <field>
              <name>FB11</name>
              <bitOffset>11</bitOffset>
              <bitWidth>1</bitWidth>
            </field>
            <field>
              <name>FB12</name>
              <bitOffset>12</bitOffset>
              <bitWidth>1</bitWidth>
            </field>
            <field>
              <name>FB13</name>
              <bitOffset>13</bitOffset>
              <bitWidth>1</bitWidth>
            </field>
            <field>
              <name>FB14</name>
              <bitOffset>14</bitOffset>
              <bitWidth>1</bitWidth>
            </field>
            <field>
              <name>FB15</name>
              <bitOffset>15</bitOffset>
              <bitWidth>1</bitWidth>
            </field>
            <field>
              <name>FB16</name>
              <bitOffset>16</bitOffset>
              <bitWidth>1</bitWidth>
            </field>
            <field>
              <name>FB17</name>
              <bitOffset>17</bitOffset>
              <bitWidth>1</bitWidth>
            </field>
            <field>
              <name>FB18</name>
              <bitOffset>18</bitOffset>
              <bitWidth>1</bitWidth>
            </field>
            <field>
              <name>FB19</name>
              <bitOffset>19</bitOffset>
              <bitWidth>1</bitWidth>
            </field>
            <field>
              <name>FB20</name>
              <bitOffset>20</bitOffset>
              <bitWidth>1</bitWidth>
            </field>
            <field>
              <name>FB21</name>
              <bitOffset>21</bitOffset>
              <bitWidth>1</bitWidth>
            </field>
            <field>
              <name>FB22</name>
              <bitOffset>22</bitOffset>
              <bitWidth>1</bitWidth>
            </field>
            <field>
              <name>FB23</name>
              <bitOffset>23</bitOffset>
              <bitWidth>1</bitWidth>
            </field>
            <field>
              <name>FB24</name>
              <bitOffset>24</bitOffset>
              <bitWidth>1</bitWidth>
            </field>
            <field>
              <name>FB25</name>
              <bitOffset>25</bitOffset>
              <bitWidth>1</bitWidth>
            </field>
            <field>
              <name>FB26</name>
              <bitOffset>26</bitOffset>
              <bitWidth>1</bitWidth>
            </field>
            <field>
              <name>FB27</name>
              <bitOffset>27</bitOffset>
              <bitWidth>1</bitWidth>
            </field>
            <field>
              <name>FB28</name>
              <bitOffset>28</bitOffset>
              <bitWidth>1</bitWidth>
            </field>
            <field>
              <name>FB29</name>
              <bitOffset>29</bitOffset>
              <bitWidth>1</bitWidth>
            </field>
            <field>
              <name>FB30</name>
              <bitOffset>30</bitOffset>
              <bitWidth>1</bitWidth>
            </field>
            <field>
              <name>FB31</name>
              <bitOffset>31</bitOffset>
              <bitWidth>1</bitWidth>
            </field>
          </fields>
        </register>
        <register>
          <name>sFilterRegister.4.FR1</name>
          <addressOffset>0x260</addressOffset>
          <size>0x20</size>
          <fields>
            <field>
              <name>FB0</name>
              <bitOffset>0</bitOffset>
              <bitWidth>1</bitWidth>
            </field>
            <field>
              <name>FB1</name>
              <bitOffset>1</bitOffset>
              <bitWidth>1</bitWidth>
            </field>
            <field>
              <name>FB2</name>
              <bitOffset>2</bitOffset>
              <bitWidth>1</bitWidth>
            </field>
            <field>
              <name>FB3</name>
              <bitOffset>3</bitOffset>
              <bitWidth>1</bitWidth>
            </field>
            <field>
              <name>FB4</name>
              <bitOffset>4</bitOffset>
              <bitWidth>1</bitWidth>
            </field>
            <field>
              <name>FB5</name>
              <bitOffset>5</bitOffset>
              <bitWidth>1</bitWidth>
            </field>
            <field>
              <name>FB6</name>
              <bitOffset>6</bitOffset>
              <bitWidth>1</bitWidth>
            </field>
            <field>
              <name>FB7</name>
              <bitOffset>7</bitOffset>
              <bitWidth>1</bitWidth>
            </field>
            <field>
              <name>FB8</name>
              <bitOffset>8</bitOffset>
              <bitWidth>1</bitWidth>
            </field>
            <field>
              <name>FB9</name>
              <bitOffset>9</bitOffset>
              <bitWidth>1</bitWidth>
            </field>
            <field>
              <name>FB10</name>
              <bitOffset>10</bitOffset>
              <bitWidth>1</bitWidth>
            </field>
            <field>
              <name>FB11</name>
              <bitOffset>11</bitOffset>
              <bitWidth>1</bitWidth>
            </field>
            <field>
              <name>FB12</name>
              <bitOffset>12</bitOffset>
              <bitWidth>1</bitWidth>
            </field>
            <field>
              <name>FB13</name>
              <bitOffset>13</bitOffset>
              <bitWidth>1</bitWidth>
            </field>
            <field>
              <name>FB14</name>
              <bitOffset>14</bitOffset>
              <bitWidth>1</bitWidth>
            </field>
            <field>
              <name>FB15</name>
              <bitOffset>15</bitOffset>
              <bitWidth>1</bitWidth>
            </field>
            <field>
              <name>FB16</name>
              <bitOffset>16</bitOffset>
              <bitWidth>1</bitWidth>
            </field>
            <field>
              <name>FB17</name>
              <bitOffset>17</bitOffset>
              <bitWidth>1</bitWidth>
            </field>
            <field>
              <name>FB18</name>
              <bitOffset>18</bitOffset>
              <bitWidth>1</bitWidth>
            </field>
            <field>
              <name>FB19</name>
              <bitOffset>19</bitOffset>
              <bitWidth>1</bitWidth>
            </field>
            <field>
              <name>FB20</name>
              <bitOffset>20</bitOffset>
              <bitWidth>1</bitWidth>
            </field>
            <field>
              <name>FB21</name>
              <bitOffset>21</bitOffset>
              <bitWidth>1</bitWidth>
            </field>
            <field>
              <name>FB22</name>
              <bitOffset>22</bitOffset>
              <bitWidth>1</bitWidth>
            </field>
            <field>
              <name>FB23</name>
              <bitOffset>23</bitOffset>
              <bitWidth>1</bitWidth>
            </field>
            <field>
              <name>FB24</name>
              <bitOffset>24</bitOffset>
              <bitWidth>1</bitWidth>
            </field>
            <field>
              <name>FB25</name>
              <bitOffset>25</bitOffset>
              <bitWidth>1</bitWidth>
            </field>
            <field>
              <name>FB26</name>
              <bitOffset>26</bitOffset>
              <bitWidth>1</bitWidth>
            </field>
            <field>
              <name>FB27</name>
              <bitOffset>27</bitOffset>
              <bitWidth>1</bitWidth>
            </field>
            <field>
              <name>FB28</name>
              <bitOffset>28</bitOffset>
              <bitWidth>1</bitWidth>
            </field>
            <field>
              <name>FB29</name>
              <bitOffset>29</bitOffset>
              <bitWidth>1</bitWidth>
            </field>
            <field>
              <name>FB30</name>
              <bitOffset>30</bitOffset>
              <bitWidth>1</bitWidth>
            </field>
            <field>
              <name>FB31</name>
              <bitOffset>31</bitOffset>
              <bitWidth>1</bitWidth>
            </field>
          </fields>
        </register>
        <register>
          <name>sFilterRegister.4.FR2</name>
          <addressOffset>0x264</addressOffset>
          <size>0x20</size>
          <fields>
            <field>
              <name>FB0</name>
              <bitOffset>0</bitOffset>
              <bitWidth>1</bitWidth>
            </field>
            <field>
              <name>FB1</name>
              <bitOffset>1</bitOffset>
              <bitWidth>1</bitWidth>
            </field>
            <field>
              <name>FB2</name>
              <bitOffset>2</bitOffset>
              <bitWidth>1</bitWidth>
            </field>
            <field>
              <name>FB3</name>
              <bitOffset>3</bitOffset>
              <bitWidth>1</bitWidth>
            </field>
            <field>
              <name>FB4</name>
              <bitOffset>4</bitOffset>
              <bitWidth>1</bitWidth>
            </field>
            <field>
              <name>FB5</name>
              <bitOffset>5</bitOffset>
              <bitWidth>1</bitWidth>
            </field>
            <field>
              <name>FB6</name>
              <bitOffset>6</bitOffset>
              <bitWidth>1</bitWidth>
            </field>
            <field>
              <name>FB7</name>
              <bitOffset>7</bitOffset>
              <bitWidth>1</bitWidth>
            </field>
            <field>
              <name>FB8</name>
              <bitOffset>8</bitOffset>
              <bitWidth>1</bitWidth>
            </field>
            <field>
              <name>FB9</name>
              <bitOffset>9</bitOffset>
              <bitWidth>1</bitWidth>
            </field>
            <field>
              <name>FB10</name>
              <bitOffset>10</bitOffset>
              <bitWidth>1</bitWidth>
            </field>
            <field>
              <name>FB11</name>
              <bitOffset>11</bitOffset>
              <bitWidth>1</bitWidth>
            </field>
            <field>
              <name>FB12</name>
              <bitOffset>12</bitOffset>
              <bitWidth>1</bitWidth>
            </field>
            <field>
              <name>FB13</name>
              <bitOffset>13</bitOffset>
              <bitWidth>1</bitWidth>
            </field>
            <field>
              <name>FB14</name>
              <bitOffset>14</bitOffset>
              <bitWidth>1</bitWidth>
            </field>
            <field>
              <name>FB15</name>
              <bitOffset>15</bitOffset>
              <bitWidth>1</bitWidth>
            </field>
            <field>
              <name>FB16</name>
              <bitOffset>16</bitOffset>
              <bitWidth>1</bitWidth>
            </field>
            <field>
              <name>FB17</name>
              <bitOffset>17</bitOffset>
              <bitWidth>1</bitWidth>
            </field>
            <field>
              <name>FB18</name>
              <bitOffset>18</bitOffset>
              <bitWidth>1</bitWidth>
            </field>
            <field>
              <name>FB19</name>
              <bitOffset>19</bitOffset>
              <bitWidth>1</bitWidth>
            </field>
            <field>
              <name>FB20</name>
              <bitOffset>20</bitOffset>
              <bitWidth>1</bitWidth>
            </field>
            <field>
              <name>FB21</name>
              <bitOffset>21</bitOffset>
              <bitWidth>1</bitWidth>
            </field>
            <field>
              <name>FB22</name>
              <bitOffset>22</bitOffset>
              <bitWidth>1</bitWidth>
            </field>
            <field>
              <name>FB23</name>
              <bitOffset>23</bitOffset>
              <bitWidth>1</bitWidth>
            </field>
            <field>
              <name>FB24</name>
              <bitOffset>24</bitOffset>
              <bitWidth>1</bitWidth>
            </field>
            <field>
              <name>FB25</name>
              <bitOffset>25</bitOffset>
              <bitWidth>1</bitWidth>
            </field>
            <field>
              <name>FB26</name>
              <bitOffset>26</bitOffset>
              <bitWidth>1</bitWidth>
            </field>
            <field>
              <name>FB27</name>
              <bitOffset>27</bitOffset>
              <bitWidth>1</bitWidth>
            </field>
            <field>
              <name>FB28</name>
              <bitOffset>28</bitOffset>
              <bitWidth>1</bitWidth>
            </field>
            <field>
              <name>FB29</name>
              <bitOffset>29</bitOffset>
              <bitWidth>1</bitWidth>
            </field>
            <field>
              <name>FB30</name>
              <bitOffset>30</bitOffset>
              <bitWidth>1</bitWidth>
            </field>
            <field>
              <name>FB31</name>
              <bitOffset>31</bitOffset>
              <bitWidth>1</bitWidth>
            </field>
          </fields>
        </register>
        <register>
          <name>sFilterRegister.5.FR1</name>
          <addressOffset>0x268</addressOffset>
          <size>0x20</size>
          <fields>
            <field>
              <name>FB0</name>
              <bitOffset>0</bitOffset>
              <bitWidth>1</bitWidth>
            </field>
            <field>
              <name>FB1</name>
              <bitOffset>1</bitOffset>
              <bitWidth>1</bitWidth>
            </field>
            <field>
              <name>FB2</name>
              <bitOffset>2</bitOffset>
              <bitWidth>1</bitWidth>
            </field>
            <field>
              <name>FB3</name>
              <bitOffset>3</bitOffset>
              <bitWidth>1</bitWidth>
            </field>
            <field>
              <name>FB4</name>
              <bitOffset>4</bitOffset>
              <bitWidth>1</bitWidth>
            </field>
            <field>
              <name>FB5</name>
              <bitOffset>5</bitOffset>
              <bitWidth>1</bitWidth>
            </field>
            <field>
              <name>FB6</name>
              <bitOffset>6</bitOffset>
              <bitWidth>1</bitWidth>
            </field>
            <field>
              <name>FB7</name>
              <bitOffset>7</bitOffset>
              <bitWidth>1</bitWidth>
            </field>
            <field>
              <name>FB8</name>
              <bitOffset>8</bitOffset>
              <bitWidth>1</bitWidth>
            </field>
            <field>
              <name>FB9</name>
              <bitOffset>9</bitOffset>
              <bitWidth>1</bitWidth>
            </field>
            <field>
              <name>FB10</name>
              <bitOffset>10</bitOffset>
              <bitWidth>1</bitWidth>
            </field>
            <field>
              <name>FB11</name>
              <bitOffset>11</bitOffset>
              <bitWidth>1</bitWidth>
            </field>
            <field>
              <name>FB12</name>
              <bitOffset>12</bitOffset>
              <bitWidth>1</bitWidth>
            </field>
            <field>
              <name>FB13</name>
              <bitOffset>13</bitOffset>
              <bitWidth>1</bitWidth>
            </field>
            <field>
              <name>FB14</name>
              <bitOffset>14</bitOffset>
              <bitWidth>1</bitWidth>
            </field>
            <field>
              <name>FB15</name>
              <bitOffset>15</bitOffset>
              <bitWidth>1</bitWidth>
            </field>
            <field>
              <name>FB16</name>
              <bitOffset>16</bitOffset>
              <bitWidth>1</bitWidth>
            </field>
            <field>
              <name>FB17</name>
              <bitOffset>17</bitOffset>
              <bitWidth>1</bitWidth>
            </field>
            <field>
              <name>FB18</name>
              <bitOffset>18</bitOffset>
              <bitWidth>1</bitWidth>
            </field>
            <field>
              <name>FB19</name>
              <bitOffset>19</bitOffset>
              <bitWidth>1</bitWidth>
            </field>
            <field>
              <name>FB20</name>
              <bitOffset>20</bitOffset>
              <bitWidth>1</bitWidth>
            </field>
            <field>
              <name>FB21</name>
              <bitOffset>21</bitOffset>
              <bitWidth>1</bitWidth>
            </field>
            <field>
              <name>FB22</name>
              <bitOffset>22</bitOffset>
              <bitWidth>1</bitWidth>
            </field>
            <field>
              <name>FB23</name>
              <bitOffset>23</bitOffset>
              <bitWidth>1</bitWidth>
            </field>
            <field>
              <name>FB24</name>
              <bitOffset>24</bitOffset>
              <bitWidth>1</bitWidth>
            </field>
            <field>
              <name>FB25</name>
              <bitOffset>25</bitOffset>
              <bitWidth>1</bitWidth>
            </field>
            <field>
              <name>FB26</name>
              <bitOffset>26</bitOffset>
              <bitWidth>1</bitWidth>
            </field>
            <field>
              <name>FB27</name>
              <bitOffset>27</bitOffset>
              <bitWidth>1</bitWidth>
            </field>
            <field>
              <name>FB28</name>
              <bitOffset>28</bitOffset>
              <bitWidth>1</bitWidth>
            </field>
            <field>
              <name>FB29</name>
              <bitOffset>29</bitOffset>
              <bitWidth>1</bitWidth>
            </field>
            <field>
              <name>FB30</name>
              <bitOffset>30</bitOffset>
              <bitWidth>1</bitWidth>
            </field>
            <field>
              <name>FB31</name>
              <bitOffset>31</bitOffset>
              <bitWidth>1</bitWidth>
            </field>
          </fields>
        </register>
        <register>
          <name>sFilterRegister.5.FR2</name>
          <addressOffset>0x26c</addressOffset>
          <size>0x20</size>
          <fields>
            <field>
              <name>FB0</name>
              <bitOffset>0</bitOffset>
              <bitWidth>1</bitWidth>
            </field>
            <field>
              <name>FB1</name>
              <bitOffset>1</bitOffset>
              <bitWidth>1</bitWidth>
            </field>
            <field>
              <name>FB2</name>
              <bitOffset>2</bitOffset>
              <bitWidth>1</bitWidth>
            </field>
            <field>
              <name>FB3</name>
              <bitOffset>3</bitOffset>
              <bitWidth>1</bitWidth>
            </field>
            <field>
              <name>FB4</name>
              <bitOffset>4</bitOffset>
              <bitWidth>1</bitWidth>
            </field>
            <field>
              <name>FB5</name>
              <bitOffset>5</bitOffset>
              <bitWidth>1</bitWidth>
            </field>
            <field>
              <name>FB6</name>
              <bitOffset>6</bitOffset>
              <bitWidth>1</bitWidth>
            </field>
            <field>
              <name>FB7</name>
              <bitOffset>7</bitOffset>
              <bitWidth>1</bitWidth>
            </field>
            <field>
              <name>FB8</name>
              <bitOffset>8</bitOffset>
              <bitWidth>1</bitWidth>
            </field>
            <field>
              <name>FB9</name>
              <bitOffset>9</bitOffset>
              <bitWidth>1</bitWidth>
            </field>
            <field>
              <name>FB10</name>
              <bitOffset>10</bitOffset>
              <bitWidth>1</bitWidth>
            </field>
            <field>
              <name>FB11</name>
              <bitOffset>11</bitOffset>
              <bitWidth>1</bitWidth>
            </field>
            <field>
              <name>FB12</name>
              <bitOffset>12</bitOffset>
              <bitWidth>1</bitWidth>
            </field>
            <field>
              <name>FB13</name>
              <bitOffset>13</bitOffset>
              <bitWidth>1</bitWidth>
            </field>
            <field>
              <name>FB14</name>
              <bitOffset>14</bitOffset>
              <bitWidth>1</bitWidth>
            </field>
            <field>
              <name>FB15</name>
              <bitOffset>15</bitOffset>
              <bitWidth>1</bitWidth>
            </field>
            <field>
              <name>FB16</name>
              <bitOffset>16</bitOffset>
              <bitWidth>1</bitWidth>
            </field>
            <field>
              <name>FB17</name>
              <bitOffset>17</bitOffset>
              <bitWidth>1</bitWidth>
            </field>
            <field>
              <name>FB18</name>
              <bitOffset>18</bitOffset>
              <bitWidth>1</bitWidth>
            </field>
            <field>
              <name>FB19</name>
              <bitOffset>19</bitOffset>
              <bitWidth>1</bitWidth>
            </field>
            <field>
              <name>FB20</name>
              <bitOffset>20</bitOffset>
              <bitWidth>1</bitWidth>
            </field>
            <field>
              <name>FB21</name>
              <bitOffset>21</bitOffset>
              <bitWidth>1</bitWidth>
            </field>
            <field>
              <name>FB22</name>
              <bitOffset>22</bitOffset>
              <bitWidth>1</bitWidth>
            </field>
            <field>
              <name>FB23</name>
              <bitOffset>23</bitOffset>
              <bitWidth>1</bitWidth>
            </field>
            <field>
              <name>FB24</name>
              <bitOffset>24</bitOffset>
              <bitWidth>1</bitWidth>
            </field>
            <field>
              <name>FB25</name>
              <bitOffset>25</bitOffset>
              <bitWidth>1</bitWidth>
            </field>
            <field>
              <name>FB26</name>
              <bitOffset>26</bitOffset>
              <bitWidth>1</bitWidth>
            </field>
            <field>
              <name>FB27</name>
              <bitOffset>27</bitOffset>
              <bitWidth>1</bitWidth>
            </field>
            <field>
              <name>FB28</name>
              <bitOffset>28</bitOffset>
              <bitWidth>1</bitWidth>
            </field>
            <field>
              <name>FB29</name>
              <bitOffset>29</bitOffset>
              <bitWidth>1</bitWidth>
            </field>
            <field>
              <name>FB30</name>
              <bitOffset>30</bitOffset>
              <bitWidth>1</bitWidth>
            </field>
            <field>
              <name>FB31</name>
              <bitOffset>31</bitOffset>
              <bitWidth>1</bitWidth>
            </field>
          </fields>
        </register>
        <register>
          <name>sFilterRegister.6.FR1</name>
          <addressOffset>0x270</addressOffset>
          <size>0x20</size>
          <fields>
            <field>
              <name>FB0</name>
              <bitOffset>0</bitOffset>
              <bitWidth>1</bitWidth>
            </field>
            <field>
              <name>FB1</name>
              <bitOffset>1</bitOffset>
              <bitWidth>1</bitWidth>
            </field>
            <field>
              <name>FB2</name>
              <bitOffset>2</bitOffset>
              <bitWidth>1</bitWidth>
            </field>
            <field>
              <name>FB3</name>
              <bitOffset>3</bitOffset>
              <bitWidth>1</bitWidth>
            </field>
            <field>
              <name>FB4</name>
              <bitOffset>4</bitOffset>
              <bitWidth>1</bitWidth>
            </field>
            <field>
              <name>FB5</name>
              <bitOffset>5</bitOffset>
              <bitWidth>1</bitWidth>
            </field>
            <field>
              <name>FB6</name>
              <bitOffset>6</bitOffset>
              <bitWidth>1</bitWidth>
            </field>
            <field>
              <name>FB7</name>
              <bitOffset>7</bitOffset>
              <bitWidth>1</bitWidth>
            </field>
            <field>
              <name>FB8</name>
              <bitOffset>8</bitOffset>
              <bitWidth>1</bitWidth>
            </field>
            <field>
              <name>FB9</name>
              <bitOffset>9</bitOffset>
              <bitWidth>1</bitWidth>
            </field>
            <field>
              <name>FB10</name>
              <bitOffset>10</bitOffset>
              <bitWidth>1</bitWidth>
            </field>
            <field>
              <name>FB11</name>
              <bitOffset>11</bitOffset>
              <bitWidth>1</bitWidth>
            </field>
            <field>
              <name>FB12</name>
              <bitOffset>12</bitOffset>
              <bitWidth>1</bitWidth>
            </field>
            <field>
              <name>FB13</name>
              <bitOffset>13</bitOffset>
              <bitWidth>1</bitWidth>
            </field>
            <field>
              <name>FB14</name>
              <bitOffset>14</bitOffset>
              <bitWidth>1</bitWidth>
            </field>
            <field>
              <name>FB15</name>
              <bitOffset>15</bitOffset>
              <bitWidth>1</bitWidth>
            </field>
            <field>
              <name>FB16</name>
              <bitOffset>16</bitOffset>
              <bitWidth>1</bitWidth>
            </field>
            <field>
              <name>FB17</name>
              <bitOffset>17</bitOffset>
              <bitWidth>1</bitWidth>
            </field>
            <field>
              <name>FB18</name>
              <bitOffset>18</bitOffset>
              <bitWidth>1</bitWidth>
            </field>
            <field>
              <name>FB19</name>
              <bitOffset>19</bitOffset>
              <bitWidth>1</bitWidth>
            </field>
            <field>
              <name>FB20</name>
              <bitOffset>20</bitOffset>
              <bitWidth>1</bitWidth>
            </field>
            <field>
              <name>FB21</name>
              <bitOffset>21</bitOffset>
              <bitWidth>1</bitWidth>
            </field>
            <field>
              <name>FB22</name>
              <bitOffset>22</bitOffset>
              <bitWidth>1</bitWidth>
            </field>
            <field>
              <name>FB23</name>
              <bitOffset>23</bitOffset>
              <bitWidth>1</bitWidth>
            </field>
            <field>
              <name>FB24</name>
              <bitOffset>24</bitOffset>
              <bitWidth>1</bitWidth>
            </field>
            <field>
              <name>FB25</name>
              <bitOffset>25</bitOffset>
              <bitWidth>1</bitWidth>
            </field>
            <field>
              <name>FB26</name>
              <bitOffset>26</bitOffset>
              <bitWidth>1</bitWidth>
            </field>
            <field>
              <name>FB27</name>
              <bitOffset>27</bitOffset>
              <bitWidth>1</bitWidth>
            </field>
            <field>
              <name>FB28</name>
              <bitOffset>28</bitOffset>
              <bitWidth>1</bitWidth>
            </field>
            <field>
              <name>FB29</name>
              <bitOffset>29</bitOffset>
              <bitWidth>1</bitWidth>
            </field>
            <field>
              <name>FB30</name>
              <bitOffset>30</bitOffset>
              <bitWidth>1</bitWidth>
            </field>
            <field>
              <name>FB31</name>
              <bitOffset>31</bitOffset>
              <bitWidth>1</bitWidth>
            </field>
          </fields>
        </register>
        <register>
          <name>sFilterRegister.6.FR2</name>
          <addressOffset>0x274</addressOffset>
          <size>0x20</size>
          <fields>
            <field>
              <name>FB0</name>
              <bitOffset>0</bitOffset>
              <bitWidth>1</bitWidth>
            </field>
            <field>
              <name>FB1</name>
              <bitOffset>1</bitOffset>
              <bitWidth>1</bitWidth>
            </field>
            <field>
              <name>FB2</name>
              <bitOffset>2</bitOffset>
              <bitWidth>1</bitWidth>
            </field>
            <field>
              <name>FB3</name>
              <bitOffset>3</bitOffset>
              <bitWidth>1</bitWidth>
            </field>
            <field>
              <name>FB4</name>
              <bitOffset>4</bitOffset>
              <bitWidth>1</bitWidth>
            </field>
            <field>
              <name>FB5</name>
              <bitOffset>5</bitOffset>
              <bitWidth>1</bitWidth>
            </field>
            <field>
              <name>FB6</name>
              <bitOffset>6</bitOffset>
              <bitWidth>1</bitWidth>
            </field>
            <field>
              <name>FB7</name>
              <bitOffset>7</bitOffset>
              <bitWidth>1</bitWidth>
            </field>
            <field>
              <name>FB8</name>
              <bitOffset>8</bitOffset>
              <bitWidth>1</bitWidth>
            </field>
            <field>
              <name>FB9</name>
              <bitOffset>9</bitOffset>
              <bitWidth>1</bitWidth>
            </field>
            <field>
              <name>FB10</name>
              <bitOffset>10</bitOffset>
              <bitWidth>1</bitWidth>
            </field>
            <field>
              <name>FB11</name>
              <bitOffset>11</bitOffset>
              <bitWidth>1</bitWidth>
            </field>
            <field>
              <name>FB12</name>
              <bitOffset>12</bitOffset>
              <bitWidth>1</bitWidth>
            </field>
            <field>
              <name>FB13</name>
              <bitOffset>13</bitOffset>
              <bitWidth>1</bitWidth>
            </field>
            <field>
              <name>FB14</name>
              <bitOffset>14</bitOffset>
              <bitWidth>1</bitWidth>
            </field>
            <field>
              <name>FB15</name>
              <bitOffset>15</bitOffset>
              <bitWidth>1</bitWidth>
            </field>
            <field>
              <name>FB16</name>
              <bitOffset>16</bitOffset>
              <bitWidth>1</bitWidth>
            </field>
            <field>
              <name>FB17</name>
              <bitOffset>17</bitOffset>
              <bitWidth>1</bitWidth>
            </field>
            <field>
              <name>FB18</name>
              <bitOffset>18</bitOffset>
              <bitWidth>1</bitWidth>
            </field>
            <field>
              <name>FB19</name>
              <bitOffset>19</bitOffset>
              <bitWidth>1</bitWidth>
            </field>
            <field>
              <name>FB20</name>
              <bitOffset>20</bitOffset>
              <bitWidth>1</bitWidth>
            </field>
            <field>
              <name>FB21</name>
              <bitOffset>21</bitOffset>
              <bitWidth>1</bitWidth>
            </field>
            <field>
              <name>FB22</name>
              <bitOffset>22</bitOffset>
              <bitWidth>1</bitWidth>
            </field>
            <field>
              <name>FB23</name>
              <bitOffset>23</bitOffset>
              <bitWidth>1</bitWidth>
            </field>
            <field>
              <name>FB24</name>
              <bitOffset>24</bitOffset>
              <bitWidth>1</bitWidth>
            </field>
            <field>
              <name>FB25</name>
              <bitOffset>25</bitOffset>
              <bitWidth>1</bitWidth>
            </field>
            <field>
              <name>FB26</name>
              <bitOffset>26</bitOffset>
              <bitWidth>1</bitWidth>
            </field>
            <field>
              <name>FB27</name>
              <bitOffset>27</bitOffset>
              <bitWidth>1</bitWidth>
            </field>
            <field>
              <name>FB28</name>
              <bitOffset>28</bitOffset>
              <bitWidth>1</bitWidth>
            </field>
            <field>
              <name>FB29</name>
              <bitOffset>29</bitOffset>
              <bitWidth>1</bitWidth>
            </field>
            <field>
              <name>FB30</name>
              <bitOffset>30</bitOffset>
              <bitWidth>1</bitWidth>
            </field>
            <field>
              <name>FB31</name>
              <bitOffset>31</bitOffset>
              <bitWidth>1</bitWidth>
            </field>
          </fields>
        </register>
        <register>
          <name>sFilterRegister.7.FR1</name>
          <addressOffset>0x278</addressOffset>
          <size>0x20</size>
          <fields>
            <field>
              <name>FB0</name>
              <bitOffset>0</bitOffset>
              <bitWidth>1</bitWidth>
            </field>
            <field>
              <name>FB1</name>
              <bitOffset>1</bitOffset>
              <bitWidth>1</bitWidth>
            </field>
            <field>
              <name>FB2</name>
              <bitOffset>2</bitOffset>
              <bitWidth>1</bitWidth>
            </field>
            <field>
              <name>FB3</name>
              <bitOffset>3</bitOffset>
              <bitWidth>1</bitWidth>
            </field>
            <field>
              <name>FB4</name>
              <bitOffset>4</bitOffset>
              <bitWidth>1</bitWidth>
            </field>
            <field>
              <name>FB5</name>
              <bitOffset>5</bitOffset>
              <bitWidth>1</bitWidth>
            </field>
            <field>
              <name>FB6</name>
              <bitOffset>6</bitOffset>
              <bitWidth>1</bitWidth>
            </field>
            <field>
              <name>FB7</name>
              <bitOffset>7</bitOffset>
              <bitWidth>1</bitWidth>
            </field>
            <field>
              <name>FB8</name>
              <bitOffset>8</bitOffset>
              <bitWidth>1</bitWidth>
            </field>
            <field>
              <name>FB9</name>
              <bitOffset>9</bitOffset>
              <bitWidth>1</bitWidth>
            </field>
            <field>
              <name>FB10</name>
              <bitOffset>10</bitOffset>
              <bitWidth>1</bitWidth>
            </field>
            <field>
              <name>FB11</name>
              <bitOffset>11</bitOffset>
              <bitWidth>1</bitWidth>
            </field>
            <field>
              <name>FB12</name>
              <bitOffset>12</bitOffset>
              <bitWidth>1</bitWidth>
            </field>
            <field>
              <name>FB13</name>
              <bitOffset>13</bitOffset>
              <bitWidth>1</bitWidth>
            </field>
            <field>
              <name>FB14</name>
              <bitOffset>14</bitOffset>
              <bitWidth>1</bitWidth>
            </field>
            <field>
              <name>FB15</name>
              <bitOffset>15</bitOffset>
              <bitWidth>1</bitWidth>
            </field>
            <field>
              <name>FB16</name>
              <bitOffset>16</bitOffset>
              <bitWidth>1</bitWidth>
            </field>
            <field>
              <name>FB17</name>
              <bitOffset>17</bitOffset>
              <bitWidth>1</bitWidth>
            </field>
            <field>
              <name>FB18</name>
              <bitOffset>18</bitOffset>
              <bitWidth>1</bitWidth>
            </field>
            <field>
              <name>FB19</name>
              <bitOffset>19</bitOffset>
              <bitWidth>1</bitWidth>
            </field>
            <field>
              <name>FB20</name>
              <bitOffset>20</bitOffset>
              <bitWidth>1</bitWidth>
            </field>
            <field>
              <name>FB21</name>
              <bitOffset>21</bitOffset>
              <bitWidth>1</bitWidth>
            </field>
            <field>
              <name>FB22</name>
              <bitOffset>22</bitOffset>
              <bitWidth>1</bitWidth>
            </field>
            <field>
              <name>FB23</name>
              <bitOffset>23</bitOffset>
              <bitWidth>1</bitWidth>
            </field>
            <field>
              <name>FB24</name>
              <bitOffset>24</bitOffset>
              <bitWidth>1</bitWidth>
            </field>
            <field>
              <name>FB25</name>
              <bitOffset>25</bitOffset>
              <bitWidth>1</bitWidth>
            </field>
            <field>
              <name>FB26</name>
              <bitOffset>26</bitOffset>
              <bitWidth>1</bitWidth>
            </field>
            <field>
              <name>FB27</name>
              <bitOffset>27</bitOffset>
              <bitWidth>1</bitWidth>
            </field>
            <field>
              <name>FB28</name>
              <bitOffset>28</bitOffset>
              <bitWidth>1</bitWidth>
            </field>
            <field>
              <name>FB29</name>
              <bitOffset>29</bitOffset>
              <bitWidth>1</bitWidth>
            </field>
            <field>
              <name>FB30</name>
              <bitOffset>30</bitOffset>
              <bitWidth>1</bitWidth>
            </field>
            <field>
              <name>FB31</name>
              <bitOffset>31</bitOffset>
              <bitWidth>1</bitWidth>
            </field>
          </fields>
        </register>
        <register>
          <name>sFilterRegister.7.FR2</name>
          <addressOffset>0x27c</addressOffset>
          <size>0x20</size>
          <fields>
            <field>
              <name>FB0</name>
              <bitOffset>0</bitOffset>
              <bitWidth>1</bitWidth>
            </field>
            <field>
              <name>FB1</name>
              <bitOffset>1</bitOffset>
              <bitWidth>1</bitWidth>
            </field>
            <field>
              <name>FB2</name>
              <bitOffset>2</bitOffset>
              <bitWidth>1</bitWidth>
            </field>
            <field>
              <name>FB3</name>
              <bitOffset>3</bitOffset>
              <bitWidth>1</bitWidth>
            </field>
            <field>
              <name>FB4</name>
              <bitOffset>4</bitOffset>
              <bitWidth>1</bitWidth>
            </field>
            <field>
              <name>FB5</name>
              <bitOffset>5</bitOffset>
              <bitWidth>1</bitWidth>
            </field>
            <field>
              <name>FB6</name>
              <bitOffset>6</bitOffset>
              <bitWidth>1</bitWidth>
            </field>
            <field>
              <name>FB7</name>
              <bitOffset>7</bitOffset>
              <bitWidth>1</bitWidth>
            </field>
            <field>
              <name>FB8</name>
              <bitOffset>8</bitOffset>
              <bitWidth>1</bitWidth>
            </field>
            <field>
              <name>FB9</name>
              <bitOffset>9</bitOffset>
              <bitWidth>1</bitWidth>
            </field>
            <field>
              <name>FB10</name>
              <bitOffset>10</bitOffset>
              <bitWidth>1</bitWidth>
            </field>
            <field>
              <name>FB11</name>
              <bitOffset>11</bitOffset>
              <bitWidth>1</bitWidth>
            </field>
            <field>
              <name>FB12</name>
              <bitOffset>12</bitOffset>
              <bitWidth>1</bitWidth>
            </field>
            <field>
              <name>FB13</name>
              <bitOffset>13</bitOffset>
              <bitWidth>1</bitWidth>
            </field>
            <field>
              <name>FB14</name>
              <bitOffset>14</bitOffset>
              <bitWidth>1</bitWidth>
            </field>
            <field>
              <name>FB15</name>
              <bitOffset>15</bitOffset>
              <bitWidth>1</bitWidth>
            </field>
            <field>
              <name>FB16</name>
              <bitOffset>16</bitOffset>
              <bitWidth>1</bitWidth>
            </field>
            <field>
              <name>FB17</name>
              <bitOffset>17</bitOffset>
              <bitWidth>1</bitWidth>
            </field>
            <field>
              <name>FB18</name>
              <bitOffset>18</bitOffset>
              <bitWidth>1</bitWidth>
            </field>
            <field>
              <name>FB19</name>
              <bitOffset>19</bitOffset>
              <bitWidth>1</bitWidth>
            </field>
            <field>
              <name>FB20</name>
              <bitOffset>20</bitOffset>
              <bitWidth>1</bitWidth>
            </field>
            <field>
              <name>FB21</name>
              <bitOffset>21</bitOffset>
              <bitWidth>1</bitWidth>
            </field>
            <field>
              <name>FB22</name>
              <bitOffset>22</bitOffset>
              <bitWidth>1</bitWidth>
            </field>
            <field>
              <name>FB23</name>
              <bitOffset>23</bitOffset>
              <bitWidth>1</bitWidth>
            </field>
            <field>
              <name>FB24</name>
              <bitOffset>24</bitOffset>
              <bitWidth>1</bitWidth>
            </field>
            <field>
              <name>FB25</name>
              <bitOffset>25</bitOffset>
              <bitWidth>1</bitWidth>
            </field>
            <field>
              <name>FB26</name>
              <bitOffset>26</bitOffset>
              <bitWidth>1</bitWidth>
            </field>
            <field>
              <name>FB27</name>
              <bitOffset>27</bitOffset>
              <bitWidth>1</bitWidth>
            </field>
            <field>
              <name>FB28</name>
              <bitOffset>28</bitOffset>
              <bitWidth>1</bitWidth>
            </field>
            <field>
              <name>FB29</name>
              <bitOffset>29</bitOffset>
              <bitWidth>1</bitWidth>
            </field>
            <field>
              <name>FB30</name>
              <bitOffset>30</bitOffset>
              <bitWidth>1</bitWidth>
            </field>
            <field>
              <name>FB31</name>
              <bitOffset>31</bitOffset>
              <bitWidth>1</bitWidth>
            </field>
          </fields>
        </register>
        <register>
          <name>sFilterRegister.8.FR1</name>
          <addressOffset>0x280</addressOffset>
          <size>0x20</size>
          <fields>
            <field>
              <name>FB0</name>
              <bitOffset>0</bitOffset>
              <bitWidth>1</bitWidth>
            </field>
            <field>
              <name>FB1</name>
              <bitOffset>1</bitOffset>
              <bitWidth>1</bitWidth>
            </field>
            <field>
              <name>FB2</name>
              <bitOffset>2</bitOffset>
              <bitWidth>1</bitWidth>
            </field>
            <field>
              <name>FB3</name>
              <bitOffset>3</bitOffset>
              <bitWidth>1</bitWidth>
            </field>
            <field>
              <name>FB4</name>
              <bitOffset>4</bitOffset>
              <bitWidth>1</bitWidth>
            </field>
            <field>
              <name>FB5</name>
              <bitOffset>5</bitOffset>
              <bitWidth>1</bitWidth>
            </field>
            <field>
              <name>FB6</name>
              <bitOffset>6</bitOffset>
              <bitWidth>1</bitWidth>
            </field>
            <field>
              <name>FB7</name>
              <bitOffset>7</bitOffset>
              <bitWidth>1</bitWidth>
            </field>
            <field>
              <name>FB8</name>
              <bitOffset>8</bitOffset>
              <bitWidth>1</bitWidth>
            </field>
            <field>
              <name>FB9</name>
              <bitOffset>9</bitOffset>
              <bitWidth>1</bitWidth>
            </field>
            <field>
              <name>FB10</name>
              <bitOffset>10</bitOffset>
              <bitWidth>1</bitWidth>
            </field>
            <field>
              <name>FB11</name>
              <bitOffset>11</bitOffset>
              <bitWidth>1</bitWidth>
            </field>
            <field>
              <name>FB12</name>
              <bitOffset>12</bitOffset>
              <bitWidth>1</bitWidth>
            </field>
            <field>
              <name>FB13</name>
              <bitOffset>13</bitOffset>
              <bitWidth>1</bitWidth>
            </field>
            <field>
              <name>FB14</name>
              <bitOffset>14</bitOffset>
              <bitWidth>1</bitWidth>
            </field>
            <field>
              <name>FB15</name>
              <bitOffset>15</bitOffset>
              <bitWidth>1</bitWidth>
            </field>
            <field>
              <name>FB16</name>
              <bitOffset>16</bitOffset>
              <bitWidth>1</bitWidth>
            </field>
            <field>
              <name>FB17</name>
              <bitOffset>17</bitOffset>
              <bitWidth>1</bitWidth>
            </field>
            <field>
              <name>FB18</name>
              <bitOffset>18</bitOffset>
              <bitWidth>1</bitWidth>
            </field>
            <field>
              <name>FB19</name>
              <bitOffset>19</bitOffset>
              <bitWidth>1</bitWidth>
            </field>
            <field>
              <name>FB20</name>
              <bitOffset>20</bitOffset>
              <bitWidth>1</bitWidth>
            </field>
            <field>
              <name>FB21</name>
              <bitOffset>21</bitOffset>
              <bitWidth>1</bitWidth>
            </field>
            <field>
              <name>FB22</name>
              <bitOffset>22</bitOffset>
              <bitWidth>1</bitWidth>
            </field>
            <field>
              <name>FB23</name>
              <bitOffset>23</bitOffset>
              <bitWidth>1</bitWidth>
            </field>
            <field>
              <name>FB24</name>
              <bitOffset>24</bitOffset>
              <bitWidth>1</bitWidth>
            </field>
            <field>
              <name>FB25</name>
              <bitOffset>25</bitOffset>
              <bitWidth>1</bitWidth>
            </field>
            <field>
              <name>FB26</name>
              <bitOffset>26</bitOffset>
              <bitWidth>1</bitWidth>
            </field>
            <field>
              <name>FB27</name>
              <bitOffset>27</bitOffset>
              <bitWidth>1</bitWidth>
            </field>
            <field>
              <name>FB28</name>
              <bitOffset>28</bitOffset>
              <bitWidth>1</bitWidth>
            </field>
            <field>
              <name>FB29</name>
              <bitOffset>29</bitOffset>
              <bitWidth>1</bitWidth>
            </field>
            <field>
              <name>FB30</name>
              <bitOffset>30</bitOffset>
              <bitWidth>1</bitWidth>
            </field>
            <field>
              <name>FB31</name>
              <bitOffset>31</bitOffset>
              <bitWidth>1</bitWidth>
            </field>
          </fields>
        </register>
        <register>
          <name>sFilterRegister.8.FR2</name>
          <addressOffset>0x284</addressOffset>
          <size>0x20</size>
          <fields>
            <field>
              <name>FB0</name>
              <bitOffset>0</bitOffset>
              <bitWidth>1</bitWidth>
            </field>
            <field>
              <name>FB1</name>
              <bitOffset>1</bitOffset>
              <bitWidth>1</bitWidth>
            </field>
            <field>
              <name>FB2</name>
              <bitOffset>2</bitOffset>
              <bitWidth>1</bitWidth>
            </field>
            <field>
              <name>FB3</name>
              <bitOffset>3</bitOffset>
              <bitWidth>1</bitWidth>
            </field>
            <field>
              <name>FB4</name>
              <bitOffset>4</bitOffset>
              <bitWidth>1</bitWidth>
            </field>
            <field>
              <name>FB5</name>
              <bitOffset>5</bitOffset>
              <bitWidth>1</bitWidth>
            </field>
            <field>
              <name>FB6</name>
              <bitOffset>6</bitOffset>
              <bitWidth>1</bitWidth>
            </field>
            <field>
              <name>FB7</name>
              <bitOffset>7</bitOffset>
              <bitWidth>1</bitWidth>
            </field>
            <field>
              <name>FB8</name>
              <bitOffset>8</bitOffset>
              <bitWidth>1</bitWidth>
            </field>
            <field>
              <name>FB9</name>
              <bitOffset>9</bitOffset>
              <bitWidth>1</bitWidth>
            </field>
            <field>
              <name>FB10</name>
              <bitOffset>10</bitOffset>
              <bitWidth>1</bitWidth>
            </field>
            <field>
              <name>FB11</name>
              <bitOffset>11</bitOffset>
              <bitWidth>1</bitWidth>
            </field>
            <field>
              <name>FB12</name>
              <bitOffset>12</bitOffset>
              <bitWidth>1</bitWidth>
            </field>
            <field>
              <name>FB13</name>
              <bitOffset>13</bitOffset>
              <bitWidth>1</bitWidth>
            </field>
            <field>
              <name>FB14</name>
              <bitOffset>14</bitOffset>
              <bitWidth>1</bitWidth>
            </field>
            <field>
              <name>FB15</name>
              <bitOffset>15</bitOffset>
              <bitWidth>1</bitWidth>
            </field>
            <field>
              <name>FB16</name>
              <bitOffset>16</bitOffset>
              <bitWidth>1</bitWidth>
            </field>
            <field>
              <name>FB17</name>
              <bitOffset>17</bitOffset>
              <bitWidth>1</bitWidth>
            </field>
            <field>
              <name>FB18</name>
              <bitOffset>18</bitOffset>
              <bitWidth>1</bitWidth>
            </field>
            <field>
              <name>FB19</name>
              <bitOffset>19</bitOffset>
              <bitWidth>1</bitWidth>
            </field>
            <field>
              <name>FB20</name>
              <bitOffset>20</bitOffset>
              <bitWidth>1</bitWidth>
            </field>
            <field>
              <name>FB21</name>
              <bitOffset>21</bitOffset>
              <bitWidth>1</bitWidth>
            </field>
            <field>
              <name>FB22</name>
              <bitOffset>22</bitOffset>
              <bitWidth>1</bitWidth>
            </field>
            <field>
              <name>FB23</name>
              <bitOffset>23</bitOffset>
              <bitWidth>1</bitWidth>
            </field>
            <field>
              <name>FB24</name>
              <bitOffset>24</bitOffset>
              <bitWidth>1</bitWidth>
            </field>
            <field>
              <name>FB25</name>
              <bitOffset>25</bitOffset>
              <bitWidth>1</bitWidth>
            </field>
            <field>
              <name>FB26</name>
              <bitOffset>26</bitOffset>
              <bitWidth>1</bitWidth>
            </field>
            <field>
              <name>FB27</name>
              <bitOffset>27</bitOffset>
              <bitWidth>1</bitWidth>
            </field>
            <field>
              <name>FB28</name>
              <bitOffset>28</bitOffset>
              <bitWidth>1</bitWidth>
            </field>
            <field>
              <name>FB29</name>
              <bitOffset>29</bitOffset>
              <bitWidth>1</bitWidth>
            </field>
            <field>
              <name>FB30</name>
              <bitOffset>30</bitOffset>
              <bitWidth>1</bitWidth>
            </field>
            <field>
              <name>FB31</name>
              <bitOffset>31</bitOffset>
              <bitWidth>1</bitWidth>
            </field>
          </fields>
        </register>
        <register>
          <name>sFilterRegister.9.FR1</name>
          <addressOffset>0x288</addressOffset>
          <size>0x20</size>
          <fields>
            <field>
              <name>FB0</name>
              <bitOffset>0</bitOffset>
              <bitWidth>1</bitWidth>
            </field>
            <field>
              <name>FB1</name>
              <bitOffset>1</bitOffset>
              <bitWidth>1</bitWidth>
            </field>
            <field>
              <name>FB2</name>
              <bitOffset>2</bitOffset>
              <bitWidth>1</bitWidth>
            </field>
            <field>
              <name>FB3</name>
              <bitOffset>3</bitOffset>
              <bitWidth>1</bitWidth>
            </field>
            <field>
              <name>FB4</name>
              <bitOffset>4</bitOffset>
              <bitWidth>1</bitWidth>
            </field>
            <field>
              <name>FB5</name>
              <bitOffset>5</bitOffset>
              <bitWidth>1</bitWidth>
            </field>
            <field>
              <name>FB6</name>
              <bitOffset>6</bitOffset>
              <bitWidth>1</bitWidth>
            </field>
            <field>
              <name>FB7</name>
              <bitOffset>7</bitOffset>
              <bitWidth>1</bitWidth>
            </field>
            <field>
              <name>FB8</name>
              <bitOffset>8</bitOffset>
              <bitWidth>1</bitWidth>
            </field>
            <field>
              <name>FB9</name>
              <bitOffset>9</bitOffset>
              <bitWidth>1</bitWidth>
            </field>
            <field>
              <name>FB10</name>
              <bitOffset>10</bitOffset>
              <bitWidth>1</bitWidth>
            </field>
            <field>
              <name>FB11</name>
              <bitOffset>11</bitOffset>
              <bitWidth>1</bitWidth>
            </field>
            <field>
              <name>FB12</name>
              <bitOffset>12</bitOffset>
              <bitWidth>1</bitWidth>
            </field>
            <field>
              <name>FB13</name>
              <bitOffset>13</bitOffset>
              <bitWidth>1</bitWidth>
            </field>
            <field>
              <name>FB14</name>
              <bitOffset>14</bitOffset>
              <bitWidth>1</bitWidth>
            </field>
            <field>
              <name>FB15</name>
              <bitOffset>15</bitOffset>
              <bitWidth>1</bitWidth>
            </field>
            <field>
              <name>FB16</name>
              <bitOffset>16</bitOffset>
              <bitWidth>1</bitWidth>
            </field>
            <field>
              <name>FB17</name>
              <bitOffset>17</bitOffset>
              <bitWidth>1</bitWidth>
            </field>
            <field>
              <name>FB18</name>
              <bitOffset>18</bitOffset>
              <bitWidth>1</bitWidth>
            </field>
            <field>
              <name>FB19</name>
              <bitOffset>19</bitOffset>
              <bitWidth>1</bitWidth>
            </field>
            <field>
              <name>FB20</name>
              <bitOffset>20</bitOffset>
              <bitWidth>1</bitWidth>
            </field>
            <field>
              <name>FB21</name>
              <bitOffset>21</bitOffset>
              <bitWidth>1</bitWidth>
            </field>
            <field>
              <name>FB22</name>
              <bitOffset>22</bitOffset>
              <bitWidth>1</bitWidth>
            </field>
            <field>
              <name>FB23</name>
              <bitOffset>23</bitOffset>
              <bitWidth>1</bitWidth>
            </field>
            <field>
              <name>FB24</name>
              <bitOffset>24</bitOffset>
              <bitWidth>1</bitWidth>
            </field>
            <field>
              <name>FB25</name>
              <bitOffset>25</bitOffset>
              <bitWidth>1</bitWidth>
            </field>
            <field>
              <name>FB26</name>
              <bitOffset>26</bitOffset>
              <bitWidth>1</bitWidth>
            </field>
            <field>
              <name>FB27</name>
              <bitOffset>27</bitOffset>
              <bitWidth>1</bitWidth>
            </field>
            <field>
              <name>FB28</name>
              <bitOffset>28</bitOffset>
              <bitWidth>1</bitWidth>
            </field>
            <field>
              <name>FB29</name>
              <bitOffset>29</bitOffset>
              <bitWidth>1</bitWidth>
            </field>
            <field>
              <name>FB30</name>
              <bitOffset>30</bitOffset>
              <bitWidth>1</bitWidth>
            </field>
            <field>
              <name>FB31</name>
              <bitOffset>31</bitOffset>
              <bitWidth>1</bitWidth>
            </field>
          </fields>
        </register>
        <register>
          <name>sFilterRegister.9.FR2</name>
          <addressOffset>0x28c</addressOffset>
          <size>0x20</size>
          <fields>
            <field>
              <name>FB0</name>
              <bitOffset>0</bitOffset>
              <bitWidth>1</bitWidth>
            </field>
            <field>
              <name>FB1</name>
              <bitOffset>1</bitOffset>
              <bitWidth>1</bitWidth>
            </field>
            <field>
              <name>FB2</name>
              <bitOffset>2</bitOffset>
              <bitWidth>1</bitWidth>
            </field>
            <field>
              <name>FB3</name>
              <bitOffset>3</bitOffset>
              <bitWidth>1</bitWidth>
            </field>
            <field>
              <name>FB4</name>
              <bitOffset>4</bitOffset>
              <bitWidth>1</bitWidth>
            </field>
            <field>
              <name>FB5</name>
              <bitOffset>5</bitOffset>
              <bitWidth>1</bitWidth>
            </field>
            <field>
              <name>FB6</name>
              <bitOffset>6</bitOffset>
              <bitWidth>1</bitWidth>
            </field>
            <field>
              <name>FB7</name>
              <bitOffset>7</bitOffset>
              <bitWidth>1</bitWidth>
            </field>
            <field>
              <name>FB8</name>
              <bitOffset>8</bitOffset>
              <bitWidth>1</bitWidth>
            </field>
            <field>
              <name>FB9</name>
              <bitOffset>9</bitOffset>
              <bitWidth>1</bitWidth>
            </field>
            <field>
              <name>FB10</name>
              <bitOffset>10</bitOffset>
              <bitWidth>1</bitWidth>
            </field>
            <field>
              <name>FB11</name>
              <bitOffset>11</bitOffset>
              <bitWidth>1</bitWidth>
            </field>
            <field>
              <name>FB12</name>
              <bitOffset>12</bitOffset>
              <bitWidth>1</bitWidth>
            </field>
            <field>
              <name>FB13</name>
              <bitOffset>13</bitOffset>
              <bitWidth>1</bitWidth>
            </field>
            <field>
              <name>FB14</name>
              <bitOffset>14</bitOffset>
              <bitWidth>1</bitWidth>
            </field>
            <field>
              <name>FB15</name>
              <bitOffset>15</bitOffset>
              <bitWidth>1</bitWidth>
            </field>
            <field>
              <name>FB16</name>
              <bitOffset>16</bitOffset>
              <bitWidth>1</bitWidth>
            </field>
            <field>
              <name>FB17</name>
              <bitOffset>17</bitOffset>
              <bitWidth>1</bitWidth>
            </field>
            <field>
              <name>FB18</name>
              <bitOffset>18</bitOffset>
              <bitWidth>1</bitWidth>
            </field>
            <field>
              <name>FB19</name>
              <bitOffset>19</bitOffset>
              <bitWidth>1</bitWidth>
            </field>
            <field>
              <name>FB20</name>
              <bitOffset>20</bitOffset>
              <bitWidth>1</bitWidth>
            </field>
            <field>
              <name>FB21</name>
              <bitOffset>21</bitOffset>
              <bitWidth>1</bitWidth>
            </field>
            <field>
              <name>FB22</name>
              <bitOffset>22</bitOffset>
              <bitWidth>1</bitWidth>
            </field>
            <field>
              <name>FB23</name>
              <bitOffset>23</bitOffset>
              <bitWidth>1</bitWidth>
            </field>
            <field>
              <name>FB24</name>
              <bitOffset>24</bitOffset>
              <bitWidth>1</bitWidth>
            </field>
            <field>
              <name>FB25</name>
              <bitOffset>25</bitOffset>
              <bitWidth>1</bitWidth>
            </field>
            <field>
              <name>FB26</name>
              <bitOffset>26</bitOffset>
              <bitWidth>1</bitWidth>
            </field>
            <field>
              <name>FB27</name>
              <bitOffset>27</bitOffset>
              <bitWidth>1</bitWidth>
            </field>
            <field>
              <name>FB28</name>
              <bitOffset>28</bitOffset>
              <bitWidth>1</bitWidth>
            </field>
            <field>
              <name>FB29</name>
              <bitOffset>29</bitOffset>
              <bitWidth>1</bitWidth>
            </field>
            <field>
              <name>FB30</name>
              <bitOffset>30</bitOffset>
              <bitWidth>1</bitWidth>
            </field>
            <field>
              <name>FB31</name>
              <bitOffset>31</bitOffset>
              <bitWidth>1</bitWidth>
            </field>
          </fields>
        </register>
        <register>
          <name>sFilterRegister.10.FR1</name>
          <addressOffset>0x290</addressOffset>
          <size>0x20</size>
          <fields>
            <field>
              <name>FB0</name>
              <bitOffset>0</bitOffset>
              <bitWidth>1</bitWidth>
            </field>
            <field>
              <name>FB1</name>
              <bitOffset>1</bitOffset>
              <bitWidth>1</bitWidth>
            </field>
            <field>
              <name>FB2</name>
              <bitOffset>2</bitOffset>
              <bitWidth>1</bitWidth>
            </field>
            <field>
              <name>FB3</name>
              <bitOffset>3</bitOffset>
              <bitWidth>1</bitWidth>
            </field>
            <field>
              <name>FB4</name>
              <bitOffset>4</bitOffset>
              <bitWidth>1</bitWidth>
            </field>
            <field>
              <name>FB5</name>
              <bitOffset>5</bitOffset>
              <bitWidth>1</bitWidth>
            </field>
            <field>
              <name>FB6</name>
              <bitOffset>6</bitOffset>
              <bitWidth>1</bitWidth>
            </field>
            <field>
              <name>FB7</name>
              <bitOffset>7</bitOffset>
              <bitWidth>1</bitWidth>
            </field>
            <field>
              <name>FB8</name>
              <bitOffset>8</bitOffset>
              <bitWidth>1</bitWidth>
            </field>
            <field>
              <name>FB9</name>
              <bitOffset>9</bitOffset>
              <bitWidth>1</bitWidth>
            </field>
            <field>
              <name>FB10</name>
              <bitOffset>10</bitOffset>
              <bitWidth>1</bitWidth>
            </field>
            <field>
              <name>FB11</name>
              <bitOffset>11</bitOffset>
              <bitWidth>1</bitWidth>
            </field>
            <field>
              <name>FB12</name>
              <bitOffset>12</bitOffset>
              <bitWidth>1</bitWidth>
            </field>
            <field>
              <name>FB13</name>
              <bitOffset>13</bitOffset>
              <bitWidth>1</bitWidth>
            </field>
            <field>
              <name>FB14</name>
              <bitOffset>14</bitOffset>
              <bitWidth>1</bitWidth>
            </field>
            <field>
              <name>FB15</name>
              <bitOffset>15</bitOffset>
              <bitWidth>1</bitWidth>
            </field>
            <field>
              <name>FB16</name>
              <bitOffset>16</bitOffset>
              <bitWidth>1</bitWidth>
            </field>
            <field>
              <name>FB17</name>
              <bitOffset>17</bitOffset>
              <bitWidth>1</bitWidth>
            </field>
            <field>
              <name>FB18</name>
              <bitOffset>18</bitOffset>
              <bitWidth>1</bitWidth>
            </field>
            <field>
              <name>FB19</name>
              <bitOffset>19</bitOffset>
              <bitWidth>1</bitWidth>
            </field>
            <field>
              <name>FB20</name>
              <bitOffset>20</bitOffset>
              <bitWidth>1</bitWidth>
            </field>
            <field>
              <name>FB21</name>
              <bitOffset>21</bitOffset>
              <bitWidth>1</bitWidth>
            </field>
            <field>
              <name>FB22</name>
              <bitOffset>22</bitOffset>
              <bitWidth>1</bitWidth>
            </field>
            <field>
              <name>FB23</name>
              <bitOffset>23</bitOffset>
              <bitWidth>1</bitWidth>
            </field>
            <field>
              <name>FB24</name>
              <bitOffset>24</bitOffset>
              <bitWidth>1</bitWidth>
            </field>
            <field>
              <name>FB25</name>
              <bitOffset>25</bitOffset>
              <bitWidth>1</bitWidth>
            </field>
            <field>
              <name>FB26</name>
              <bitOffset>26</bitOffset>
              <bitWidth>1</bitWidth>
            </field>
            <field>
              <name>FB27</name>
              <bitOffset>27</bitOffset>
              <bitWidth>1</bitWidth>
            </field>
            <field>
              <name>FB28</name>
              <bitOffset>28</bitOffset>
              <bitWidth>1</bitWidth>
            </field>
            <field>
              <name>FB29</name>
              <bitOffset>29</bitOffset>
              <bitWidth>1</bitWidth>
            </field>
            <field>
              <name>FB30</name>
              <bitOffset>30</bitOffset>
              <bitWidth>1</bitWidth>
            </field>
            <field>
              <name>FB31</name>
              <bitOffset>31</bitOffset>
              <bitWidth>1</bitWidth>
            </field>
          </fields>
        </register>
        <register>
          <name>sFilterRegister.10.FR2</name>
          <addressOffset>0x294</addressOffset>
          <size>0x20</size>
          <fields>
            <field>
              <name>FB0</name>
              <bitOffset>0</bitOffset>
              <bitWidth>1</bitWidth>
            </field>
            <field>
              <name>FB1</name>
              <bitOffset>1</bitOffset>
              <bitWidth>1</bitWidth>
            </field>
            <field>
              <name>FB2</name>
              <bitOffset>2</bitOffset>
              <bitWidth>1</bitWidth>
            </field>
            <field>
              <name>FB3</name>
              <bitOffset>3</bitOffset>
              <bitWidth>1</bitWidth>
            </field>
            <field>
              <name>FB4</name>
              <bitOffset>4</bitOffset>
              <bitWidth>1</bitWidth>
            </field>
            <field>
              <name>FB5</name>
              <bitOffset>5</bitOffset>
              <bitWidth>1</bitWidth>
            </field>
            <field>
              <name>FB6</name>
              <bitOffset>6</bitOffset>
              <bitWidth>1</bitWidth>
            </field>
            <field>
              <name>FB7</name>
              <bitOffset>7</bitOffset>
              <bitWidth>1</bitWidth>
            </field>
            <field>
              <name>FB8</name>
              <bitOffset>8</bitOffset>
              <bitWidth>1</bitWidth>
            </field>
            <field>
              <name>FB9</name>
              <bitOffset>9</bitOffset>
              <bitWidth>1</bitWidth>
            </field>
            <field>
              <name>FB10</name>
              <bitOffset>10</bitOffset>
              <bitWidth>1</bitWidth>
            </field>
            <field>
              <name>FB11</name>
              <bitOffset>11</bitOffset>
              <bitWidth>1</bitWidth>
            </field>
            <field>
              <name>FB12</name>
              <bitOffset>12</bitOffset>
              <bitWidth>1</bitWidth>
            </field>
            <field>
              <name>FB13</name>
              <bitOffset>13</bitOffset>
              <bitWidth>1</bitWidth>
            </field>
            <field>
              <name>FB14</name>
              <bitOffset>14</bitOffset>
              <bitWidth>1</bitWidth>
            </field>
            <field>
              <name>FB15</name>
              <bitOffset>15</bitOffset>
              <bitWidth>1</bitWidth>
            </field>
            <field>
              <name>FB16</name>
              <bitOffset>16</bitOffset>
              <bitWidth>1</bitWidth>
            </field>
            <field>
              <name>FB17</name>
              <bitOffset>17</bitOffset>
              <bitWidth>1</bitWidth>
            </field>
            <field>
              <name>FB18</name>
              <bitOffset>18</bitOffset>
              <bitWidth>1</bitWidth>
            </field>
            <field>
              <name>FB19</name>
              <bitOffset>19</bitOffset>
              <bitWidth>1</bitWidth>
            </field>
            <field>
              <name>FB20</name>
              <bitOffset>20</bitOffset>
              <bitWidth>1</bitWidth>
            </field>
            <field>
              <name>FB21</name>
              <bitOffset>21</bitOffset>
              <bitWidth>1</bitWidth>
            </field>
            <field>
              <name>FB22</name>
              <bitOffset>22</bitOffset>
              <bitWidth>1</bitWidth>
            </field>
            <field>
              <name>FB23</name>
              <bitOffset>23</bitOffset>
              <bitWidth>1</bitWidth>
            </field>
            <field>
              <name>FB24</name>
              <bitOffset>24</bitOffset>
              <bitWidth>1</bitWidth>
            </field>
            <field>
              <name>FB25</name>
              <bitOffset>25</bitOffset>
              <bitWidth>1</bitWidth>
            </field>
            <field>
              <name>FB26</name>
              <bitOffset>26</bitOffset>
              <bitWidth>1</bitWidth>
            </field>
            <field>
              <name>FB27</name>
              <bitOffset>27</bitOffset>
              <bitWidth>1</bitWidth>
            </field>
            <field>
              <name>FB28</name>
              <bitOffset>28</bitOffset>
              <bitWidth>1</bitWidth>
            </field>
            <field>
              <name>FB29</name>
              <bitOffset>29</bitOffset>
              <bitWidth>1</bitWidth>
            </field>
            <field>
              <name>FB30</name>
              <bitOffset>30</bitOffset>
              <bitWidth>1</bitWidth>
            </field>
            <field>
              <name>FB31</name>
              <bitOffset>31</bitOffset>
              <bitWidth>1</bitWidth>
            </field>
          </fields>
        </register>
        <register>
          <name>sFilterRegister.11.FR1</name>
          <addressOffset>0x298</addressOffset>
          <size>0x20</size>
          <fields>
            <field>
              <name>FB0</name>
              <bitOffset>0</bitOffset>
              <bitWidth>1</bitWidth>
            </field>
            <field>
              <name>FB1</name>
              <bitOffset>1</bitOffset>
              <bitWidth>1</bitWidth>
            </field>
            <field>
              <name>FB2</name>
              <bitOffset>2</bitOffset>
              <bitWidth>1</bitWidth>
            </field>
            <field>
              <name>FB3</name>
              <bitOffset>3</bitOffset>
              <bitWidth>1</bitWidth>
            </field>
            <field>
              <name>FB4</name>
              <bitOffset>4</bitOffset>
              <bitWidth>1</bitWidth>
            </field>
            <field>
              <name>FB5</name>
              <bitOffset>5</bitOffset>
              <bitWidth>1</bitWidth>
            </field>
            <field>
              <name>FB6</name>
              <bitOffset>6</bitOffset>
              <bitWidth>1</bitWidth>
            </field>
            <field>
              <name>FB7</name>
              <bitOffset>7</bitOffset>
              <bitWidth>1</bitWidth>
            </field>
            <field>
              <name>FB8</name>
              <bitOffset>8</bitOffset>
              <bitWidth>1</bitWidth>
            </field>
            <field>
              <name>FB9</name>
              <bitOffset>9</bitOffset>
              <bitWidth>1</bitWidth>
            </field>
            <field>
              <name>FB10</name>
              <bitOffset>10</bitOffset>
              <bitWidth>1</bitWidth>
            </field>
            <field>
              <name>FB11</name>
              <bitOffset>11</bitOffset>
              <bitWidth>1</bitWidth>
            </field>
            <field>
              <name>FB12</name>
              <bitOffset>12</bitOffset>
              <bitWidth>1</bitWidth>
            </field>
            <field>
              <name>FB13</name>
              <bitOffset>13</bitOffset>
              <bitWidth>1</bitWidth>
            </field>
            <field>
              <name>FB14</name>
              <bitOffset>14</bitOffset>
              <bitWidth>1</bitWidth>
            </field>
            <field>
              <name>FB15</name>
              <bitOffset>15</bitOffset>
              <bitWidth>1</bitWidth>
            </field>
            <field>
              <name>FB16</name>
              <bitOffset>16</bitOffset>
              <bitWidth>1</bitWidth>
            </field>
            <field>
              <name>FB17</name>
              <bitOffset>17</bitOffset>
              <bitWidth>1</bitWidth>
            </field>
            <field>
              <name>FB18</name>
              <bitOffset>18</bitOffset>
              <bitWidth>1</bitWidth>
            </field>
            <field>
              <name>FB19</name>
              <bitOffset>19</bitOffset>
              <bitWidth>1</bitWidth>
            </field>
            <field>
              <name>FB20</name>
              <bitOffset>20</bitOffset>
              <bitWidth>1</bitWidth>
            </field>
            <field>
              <name>FB21</name>
              <bitOffset>21</bitOffset>
              <bitWidth>1</bitWidth>
            </field>
            <field>
              <name>FB22</name>
              <bitOffset>22</bitOffset>
              <bitWidth>1</bitWidth>
            </field>
            <field>
              <name>FB23</name>
              <bitOffset>23</bitOffset>
              <bitWidth>1</bitWidth>
            </field>
            <field>
              <name>FB24</name>
              <bitOffset>24</bitOffset>
              <bitWidth>1</bitWidth>
            </field>
            <field>
              <name>FB25</name>
              <bitOffset>25</bitOffset>
              <bitWidth>1</bitWidth>
            </field>
            <field>
              <name>FB26</name>
              <bitOffset>26</bitOffset>
              <bitWidth>1</bitWidth>
            </field>
            <field>
              <name>FB27</name>
              <bitOffset>27</bitOffset>
              <bitWidth>1</bitWidth>
            </field>
            <field>
              <name>FB28</name>
              <bitOffset>28</bitOffset>
              <bitWidth>1</bitWidth>
            </field>
            <field>
              <name>FB29</name>
              <bitOffset>29</bitOffset>
              <bitWidth>1</bitWidth>
            </field>
            <field>
              <name>FB30</name>
              <bitOffset>30</bitOffset>
              <bitWidth>1</bitWidth>
            </field>
            <field>
              <name>FB31</name>
              <bitOffset>31</bitOffset>
              <bitWidth>1</bitWidth>
            </field>
          </fields>
        </register>
        <register>
          <name>sFilterRegister.11.FR2</name>
          <addressOffset>0x29c</addressOffset>
          <size>0x20</size>
          <fields>
            <field>
              <name>FB0</name>
              <bitOffset>0</bitOffset>
              <bitWidth>1</bitWidth>
            </field>
            <field>
              <name>FB1</name>
              <bitOffset>1</bitOffset>
              <bitWidth>1</bitWidth>
            </field>
            <field>
              <name>FB2</name>
              <bitOffset>2</bitOffset>
              <bitWidth>1</bitWidth>
            </field>
            <field>
              <name>FB3</name>
              <bitOffset>3</bitOffset>
              <bitWidth>1</bitWidth>
            </field>
            <field>
              <name>FB4</name>
              <bitOffset>4</bitOffset>
              <bitWidth>1</bitWidth>
            </field>
            <field>
              <name>FB5</name>
              <bitOffset>5</bitOffset>
              <bitWidth>1</bitWidth>
            </field>
            <field>
              <name>FB6</name>
              <bitOffset>6</bitOffset>
              <bitWidth>1</bitWidth>
            </field>
            <field>
              <name>FB7</name>
              <bitOffset>7</bitOffset>
              <bitWidth>1</bitWidth>
            </field>
            <field>
              <name>FB8</name>
              <bitOffset>8</bitOffset>
              <bitWidth>1</bitWidth>
            </field>
            <field>
              <name>FB9</name>
              <bitOffset>9</bitOffset>
              <bitWidth>1</bitWidth>
            </field>
            <field>
              <name>FB10</name>
              <bitOffset>10</bitOffset>
              <bitWidth>1</bitWidth>
            </field>
            <field>
              <name>FB11</name>
              <bitOffset>11</bitOffset>
              <bitWidth>1</bitWidth>
            </field>
            <field>
              <name>FB12</name>
              <bitOffset>12</bitOffset>
              <bitWidth>1</bitWidth>
            </field>
            <field>
              <name>FB13</name>
              <bitOffset>13</bitOffset>
              <bitWidth>1</bitWidth>
            </field>
            <field>
              <name>FB14</name>
              <bitOffset>14</bitOffset>
              <bitWidth>1</bitWidth>
            </field>
            <field>
              <name>FB15</name>
              <bitOffset>15</bitOffset>
              <bitWidth>1</bitWidth>
            </field>
            <field>
              <name>FB16</name>
              <bitOffset>16</bitOffset>
              <bitWidth>1</bitWidth>
            </field>
            <field>
              <name>FB17</name>
              <bitOffset>17</bitOffset>
              <bitWidth>1</bitWidth>
            </field>
            <field>
              <name>FB18</name>
              <bitOffset>18</bitOffset>
              <bitWidth>1</bitWidth>
            </field>
            <field>
              <name>FB19</name>
              <bitOffset>19</bitOffset>
              <bitWidth>1</bitWidth>
            </field>
            <field>
              <name>FB20</name>
              <bitOffset>20</bitOffset>
              <bitWidth>1</bitWidth>
            </field>
            <field>
              <name>FB21</name>
              <bitOffset>21</bitOffset>
              <bitWidth>1</bitWidth>
            </field>
            <field>
              <name>FB22</name>
              <bitOffset>22</bitOffset>
              <bitWidth>1</bitWidth>
            </field>
            <field>
              <name>FB23</name>
              <bitOffset>23</bitOffset>
              <bitWidth>1</bitWidth>
            </field>
            <field>
              <name>FB24</name>
              <bitOffset>24</bitOffset>
              <bitWidth>1</bitWidth>
            </field>
            <field>
              <name>FB25</name>
              <bitOffset>25</bitOffset>
              <bitWidth>1</bitWidth>
            </field>
            <field>
              <name>FB26</name>
              <bitOffset>26</bitOffset>
              <bitWidth>1</bitWidth>
            </field>
            <field>
              <name>FB27</name>
              <bitOffset>27</bitOffset>
              <bitWidth>1</bitWidth>
            </field>
            <field>
              <name>FB28</name>
              <bitOffset>28</bitOffset>
              <bitWidth>1</bitWidth>
            </field>
            <field>
              <name>FB29</name>
              <bitOffset>29</bitOffset>
              <bitWidth>1</bitWidth>
            </field>
            <field>
              <name>FB30</name>
              <bitOffset>30</bitOffset>
              <bitWidth>1</bitWidth>
            </field>
            <field>
              <name>FB31</name>
              <bitOffset>31</bitOffset>
              <bitWidth>1</bitWidth>
            </field>
          </fields>
        </register>
        <register>
          <name>sFilterRegister.12.FR1</name>
          <addressOffset>0x2a0</addressOffset>
          <size>0x20</size>
          <fields>
            <field>
              <name>FB0</name>
              <bitOffset>0</bitOffset>
              <bitWidth>1</bitWidth>
            </field>
            <field>
              <name>FB1</name>
              <bitOffset>1</bitOffset>
              <bitWidth>1</bitWidth>
            </field>
            <field>
              <name>FB2</name>
              <bitOffset>2</bitOffset>
              <bitWidth>1</bitWidth>
            </field>
            <field>
              <name>FB3</name>
              <bitOffset>3</bitOffset>
              <bitWidth>1</bitWidth>
            </field>
            <field>
              <name>FB4</name>
              <bitOffset>4</bitOffset>
              <bitWidth>1</bitWidth>
            </field>
            <field>
              <name>FB5</name>
              <bitOffset>5</bitOffset>
              <bitWidth>1</bitWidth>
            </field>
            <field>
              <name>FB6</name>
              <bitOffset>6</bitOffset>
              <bitWidth>1</bitWidth>
            </field>
            <field>
              <name>FB7</name>
              <bitOffset>7</bitOffset>
              <bitWidth>1</bitWidth>
            </field>
            <field>
              <name>FB8</name>
              <bitOffset>8</bitOffset>
              <bitWidth>1</bitWidth>
            </field>
            <field>
              <name>FB9</name>
              <bitOffset>9</bitOffset>
              <bitWidth>1</bitWidth>
            </field>
            <field>
              <name>FB10</name>
              <bitOffset>10</bitOffset>
              <bitWidth>1</bitWidth>
            </field>
            <field>
              <name>FB11</name>
              <bitOffset>11</bitOffset>
              <bitWidth>1</bitWidth>
            </field>
            <field>
              <name>FB12</name>
              <bitOffset>12</bitOffset>
              <bitWidth>1</bitWidth>
            </field>
            <field>
              <name>FB13</name>
              <bitOffset>13</bitOffset>
              <bitWidth>1</bitWidth>
            </field>
            <field>
              <name>FB14</name>
              <bitOffset>14</bitOffset>
              <bitWidth>1</bitWidth>
            </field>
            <field>
              <name>FB15</name>
              <bitOffset>15</bitOffset>
              <bitWidth>1</bitWidth>
            </field>
            <field>
              <name>FB16</name>
              <bitOffset>16</bitOffset>
              <bitWidth>1</bitWidth>
            </field>
            <field>
              <name>FB17</name>
              <bitOffset>17</bitOffset>
              <bitWidth>1</bitWidth>
            </field>
            <field>
              <name>FB18</name>
              <bitOffset>18</bitOffset>
              <bitWidth>1</bitWidth>
            </field>
            <field>
              <name>FB19</name>
              <bitOffset>19</bitOffset>
              <bitWidth>1</bitWidth>
            </field>
            <field>
              <name>FB20</name>
              <bitOffset>20</bitOffset>
              <bitWidth>1</bitWidth>
            </field>
            <field>
              <name>FB21</name>
              <bitOffset>21</bitOffset>
              <bitWidth>1</bitWidth>
            </field>
            <field>
              <name>FB22</name>
              <bitOffset>22</bitOffset>
              <bitWidth>1</bitWidth>
            </field>
            <field>
              <name>FB23</name>
              <bitOffset>23</bitOffset>
              <bitWidth>1</bitWidth>
            </field>
            <field>
              <name>FB24</name>
              <bitOffset>24</bitOffset>
              <bitWidth>1</bitWidth>
            </field>
            <field>
              <name>FB25</name>
              <bitOffset>25</bitOffset>
              <bitWidth>1</bitWidth>
            </field>
            <field>
              <name>FB26</name>
              <bitOffset>26</bitOffset>
              <bitWidth>1</bitWidth>
            </field>
            <field>
              <name>FB27</name>
              <bitOffset>27</bitOffset>
              <bitWidth>1</bitWidth>
            </field>
            <field>
              <name>FB28</name>
              <bitOffset>28</bitOffset>
              <bitWidth>1</bitWidth>
            </field>
            <field>
              <name>FB29</name>
              <bitOffset>29</bitOffset>
              <bitWidth>1</bitWidth>
            </field>
            <field>
              <name>FB30</name>
              <bitOffset>30</bitOffset>
              <bitWidth>1</bitWidth>
            </field>
            <field>
              <name>FB31</name>
              <bitOffset>31</bitOffset>
              <bitWidth>1</bitWidth>
            </field>
          </fields>
        </register>
        <register>
          <name>sFilterRegister.12.FR2</name>
          <addressOffset>0x2a4</addressOffset>
          <size>0x20</size>
          <fields>
            <field>
              <name>FB0</name>
              <bitOffset>0</bitOffset>
              <bitWidth>1</bitWidth>
            </field>
            <field>
              <name>FB1</name>
              <bitOffset>1</bitOffset>
              <bitWidth>1</bitWidth>
            </field>
            <field>
              <name>FB2</name>
              <bitOffset>2</bitOffset>
              <bitWidth>1</bitWidth>
            </field>
            <field>
              <name>FB3</name>
              <bitOffset>3</bitOffset>
              <bitWidth>1</bitWidth>
            </field>
            <field>
              <name>FB4</name>
              <bitOffset>4</bitOffset>
              <bitWidth>1</bitWidth>
            </field>
            <field>
              <name>FB5</name>
              <bitOffset>5</bitOffset>
              <bitWidth>1</bitWidth>
            </field>
            <field>
              <name>FB6</name>
              <bitOffset>6</bitOffset>
              <bitWidth>1</bitWidth>
            </field>
            <field>
              <name>FB7</name>
              <bitOffset>7</bitOffset>
              <bitWidth>1</bitWidth>
            </field>
            <field>
              <name>FB8</name>
              <bitOffset>8</bitOffset>
              <bitWidth>1</bitWidth>
            </field>
            <field>
              <name>FB9</name>
              <bitOffset>9</bitOffset>
              <bitWidth>1</bitWidth>
            </field>
            <field>
              <name>FB10</name>
              <bitOffset>10</bitOffset>
              <bitWidth>1</bitWidth>
            </field>
            <field>
              <name>FB11</name>
              <bitOffset>11</bitOffset>
              <bitWidth>1</bitWidth>
            </field>
            <field>
              <name>FB12</name>
              <bitOffset>12</bitOffset>
              <bitWidth>1</bitWidth>
            </field>
            <field>
              <name>FB13</name>
              <bitOffset>13</bitOffset>
              <bitWidth>1</bitWidth>
            </field>
            <field>
              <name>FB14</name>
              <bitOffset>14</bitOffset>
              <bitWidth>1</bitWidth>
            </field>
            <field>
              <name>FB15</name>
              <bitOffset>15</bitOffset>
              <bitWidth>1</bitWidth>
            </field>
            <field>
              <name>FB16</name>
              <bitOffset>16</bitOffset>
              <bitWidth>1</bitWidth>
            </field>
            <field>
              <name>FB17</name>
              <bitOffset>17</bitOffset>
              <bitWidth>1</bitWidth>
            </field>
            <field>
              <name>FB18</name>
              <bitOffset>18</bitOffset>
              <bitWidth>1</bitWidth>
            </field>
            <field>
              <name>FB19</name>
              <bitOffset>19</bitOffset>
              <bitWidth>1</bitWidth>
            </field>
            <field>
              <name>FB20</name>
              <bitOffset>20</bitOffset>
              <bitWidth>1</bitWidth>
            </field>
            <field>
              <name>FB21</name>
              <bitOffset>21</bitOffset>
              <bitWidth>1</bitWidth>
            </field>
            <field>
              <name>FB22</name>
              <bitOffset>22</bitOffset>
              <bitWidth>1</bitWidth>
            </field>
            <field>
              <name>FB23</name>
              <bitOffset>23</bitOffset>
              <bitWidth>1</bitWidth>
            </field>
            <field>
              <name>FB24</name>
              <bitOffset>24</bitOffset>
              <bitWidth>1</bitWidth>
            </field>
            <field>
              <name>FB25</name>
              <bitOffset>25</bitOffset>
              <bitWidth>1</bitWidth>
            </field>
            <field>
              <name>FB26</name>
              <bitOffset>26</bitOffset>
              <bitWidth>1</bitWidth>
            </field>
            <field>
              <name>FB27</name>
              <bitOffset>27</bitOffset>
              <bitWidth>1</bitWidth>
            </field>
            <field>
              <name>FB28</name>
              <bitOffset>28</bitOffset>
              <bitWidth>1</bitWidth>
            </field>
            <field>
              <name>FB29</name>
              <bitOffset>29</bitOffset>
              <bitWidth>1</bitWidth>
            </field>
            <field>
              <name>FB30</name>
              <bitOffset>30</bitOffset>
              <bitWidth>1</bitWidth>
            </field>
            <field>
              <name>FB31</name>
              <bitOffset>31</bitOffset>
              <bitWidth>1</bitWidth>
            </field>
          </fields>
        </register>
        <register>
          <name>sFilterRegister.13.FR1</name>
          <addressOffset>0x2a8</addressOffset>
          <size>0x20</size>
          <fields>
            <field>
              <name>FB0</name>
              <bitOffset>0</bitOffset>
              <bitWidth>1</bitWidth>
            </field>
            <field>
              <name>FB1</name>
              <bitOffset>1</bitOffset>
              <bitWidth>1</bitWidth>
            </field>
            <field>
              <name>FB2</name>
              <bitOffset>2</bitOffset>
              <bitWidth>1</bitWidth>
            </field>
            <field>
              <name>FB3</name>
              <bitOffset>3</bitOffset>
              <bitWidth>1</bitWidth>
            </field>
            <field>
              <name>FB4</name>
              <bitOffset>4</bitOffset>
              <bitWidth>1</bitWidth>
            </field>
            <field>
              <name>FB5</name>
              <bitOffset>5</bitOffset>
              <bitWidth>1</bitWidth>
            </field>
            <field>
              <name>FB6</name>
              <bitOffset>6</bitOffset>
              <bitWidth>1</bitWidth>
            </field>
            <field>
              <name>FB7</name>
              <bitOffset>7</bitOffset>
              <bitWidth>1</bitWidth>
            </field>
            <field>
              <name>FB8</name>
              <bitOffset>8</bitOffset>
              <bitWidth>1</bitWidth>
            </field>
            <field>
              <name>FB9</name>
              <bitOffset>9</bitOffset>
              <bitWidth>1</bitWidth>
            </field>
            <field>
              <name>FB10</name>
              <bitOffset>10</bitOffset>
              <bitWidth>1</bitWidth>
            </field>
            <field>
              <name>FB11</name>
              <bitOffset>11</bitOffset>
              <bitWidth>1</bitWidth>
            </field>
            <field>
              <name>FB12</name>
              <bitOffset>12</bitOffset>
              <bitWidth>1</bitWidth>
            </field>
            <field>
              <name>FB13</name>
              <bitOffset>13</bitOffset>
              <bitWidth>1</bitWidth>
            </field>
            <field>
              <name>FB14</name>
              <bitOffset>14</bitOffset>
              <bitWidth>1</bitWidth>
            </field>
            <field>
              <name>FB15</name>
              <bitOffset>15</bitOffset>
              <bitWidth>1</bitWidth>
            </field>
            <field>
              <name>FB16</name>
              <bitOffset>16</bitOffset>
              <bitWidth>1</bitWidth>
            </field>
            <field>
              <name>FB17</name>
              <bitOffset>17</bitOffset>
              <bitWidth>1</bitWidth>
            </field>
            <field>
              <name>FB18</name>
              <bitOffset>18</bitOffset>
              <bitWidth>1</bitWidth>
            </field>
            <field>
              <name>FB19</name>
              <bitOffset>19</bitOffset>
              <bitWidth>1</bitWidth>
            </field>
            <field>
              <name>FB20</name>
              <bitOffset>20</bitOffset>
              <bitWidth>1</bitWidth>
            </field>
            <field>
              <name>FB21</name>
              <bitOffset>21</bitOffset>
              <bitWidth>1</bitWidth>
            </field>
            <field>
              <name>FB22</name>
              <bitOffset>22</bitOffset>
              <bitWidth>1</bitWidth>
            </field>
            <field>
              <name>FB23</name>
              <bitOffset>23</bitOffset>
              <bitWidth>1</bitWidth>
            </field>
            <field>
              <name>FB24</name>
              <bitOffset>24</bitOffset>
              <bitWidth>1</bitWidth>
            </field>
            <field>
              <name>FB25</name>
              <bitOffset>25</bitOffset>
              <bitWidth>1</bitWidth>
            </field>
            <field>
              <name>FB26</name>
              <bitOffset>26</bitOffset>
              <bitWidth>1</bitWidth>
            </field>
            <field>
              <name>FB27</name>
              <bitOffset>27</bitOffset>
              <bitWidth>1</bitWidth>
            </field>
            <field>
              <name>FB28</name>
              <bitOffset>28</bitOffset>
              <bitWidth>1</bitWidth>
            </field>
            <field>
              <name>FB29</name>
              <bitOffset>29</bitOffset>
              <bitWidth>1</bitWidth>
            </field>
            <field>
              <name>FB30</name>
              <bitOffset>30</bitOffset>
              <bitWidth>1</bitWidth>
            </field>
            <field>
              <name>FB31</name>
              <bitOffset>31</bitOffset>
              <bitWidth>1</bitWidth>
            </field>
          </fields>
        </register>
        <register>
          <name>sFilterRegister.13.FR2</name>
          <addressOffset>0x2ac</addressOffset>
          <size>0x20</size>
          <fields>
            <field>
              <name>FB0</name>
              <bitOffset>0</bitOffset>
              <bitWidth>1</bitWidth>
            </field>
            <field>
              <name>FB1</name>
              <bitOffset>1</bitOffset>
              <bitWidth>1</bitWidth>
            </field>
            <field>
              <name>FB2</name>
              <bitOffset>2</bitOffset>
              <bitWidth>1</bitWidth>
            </field>
            <field>
              <name>FB3</name>
              <bitOffset>3</bitOffset>
              <bitWidth>1</bitWidth>
            </field>
            <field>
              <name>FB4</name>
              <bitOffset>4</bitOffset>
              <bitWidth>1</bitWidth>
            </field>
            <field>
              <name>FB5</name>
              <bitOffset>5</bitOffset>
              <bitWidth>1</bitWidth>
            </field>
            <field>
              <name>FB6</name>
              <bitOffset>6</bitOffset>
              <bitWidth>1</bitWidth>
            </field>
            <field>
              <name>FB7</name>
              <bitOffset>7</bitOffset>
              <bitWidth>1</bitWidth>
            </field>
            <field>
              <name>FB8</name>
              <bitOffset>8</bitOffset>
              <bitWidth>1</bitWidth>
            </field>
            <field>
              <name>FB9</name>
              <bitOffset>9</bitOffset>
              <bitWidth>1</bitWidth>
            </field>
            <field>
              <name>FB10</name>
              <bitOffset>10</bitOffset>
              <bitWidth>1</bitWidth>
            </field>
            <field>
              <name>FB11</name>
              <bitOffset>11</bitOffset>
              <bitWidth>1</bitWidth>
            </field>
            <field>
              <name>FB12</name>
              <bitOffset>12</bitOffset>
              <bitWidth>1</bitWidth>
            </field>
            <field>
              <name>FB13</name>
              <bitOffset>13</bitOffset>
              <bitWidth>1</bitWidth>
            </field>
            <field>
              <name>FB14</name>
              <bitOffset>14</bitOffset>
              <bitWidth>1</bitWidth>
            </field>
            <field>
              <name>FB15</name>
              <bitOffset>15</bitOffset>
              <bitWidth>1</bitWidth>
            </field>
            <field>
              <name>FB16</name>
              <bitOffset>16</bitOffset>
              <bitWidth>1</bitWidth>
            </field>
            <field>
              <name>FB17</name>
              <bitOffset>17</bitOffset>
              <bitWidth>1</bitWidth>
            </field>
            <field>
              <name>FB18</name>
              <bitOffset>18</bitOffset>
              <bitWidth>1</bitWidth>
            </field>
            <field>
              <name>FB19</name>
              <bitOffset>19</bitOffset>
              <bitWidth>1</bitWidth>
            </field>
            <field>
              <name>FB20</name>
              <bitOffset>20</bitOffset>
              <bitWidth>1</bitWidth>
            </field>
            <field>
              <name>FB21</name>
              <bitOffset>21</bitOffset>
              <bitWidth>1</bitWidth>
            </field>
            <field>
              <name>FB22</name>
              <bitOffset>22</bitOffset>
              <bitWidth>1</bitWidth>
            </field>
            <field>
              <name>FB23</name>
              <bitOffset>23</bitOffset>
              <bitWidth>1</bitWidth>
            </field>
            <field>
              <name>FB24</name>
              <bitOffset>24</bitOffset>
              <bitWidth>1</bitWidth>
            </field>
            <field>
              <name>FB25</name>
              <bitOffset>25</bitOffset>
              <bitWidth>1</bitWidth>
            </field>
            <field>
              <name>FB26</name>
              <bitOffset>26</bitOffset>
              <bitWidth>1</bitWidth>
            </field>
            <field>
              <name>FB27</name>
              <bitOffset>27</bitOffset>
              <bitWidth>1</bitWidth>
            </field>
            <field>
              <name>FB28</name>
              <bitOffset>28</bitOffset>
              <bitWidth>1</bitWidth>
            </field>
            <field>
              <name>FB29</name>
              <bitOffset>29</bitOffset>
              <bitWidth>1</bitWidth>
            </field>
            <field>
              <name>FB30</name>
              <bitOffset>30</bitOffset>
              <bitWidth>1</bitWidth>
            </field>
            <field>
              <name>FB31</name>
              <bitOffset>31</bitOffset>
              <bitWidth>1</bitWidth>
            </field>
          </fields>
        </register>
        <register>
          <name>sFilterRegister.14.FR1</name>
          <addressOffset>0x2b0</addressOffset>
          <size>0x20</size>
        </register>
        <register>
          <name>sFilterRegister.14.FR2</name>
          <addressOffset>0x2b4</addressOffset>
          <size>0x20</size>
        </register>
        <register>
          <name>sFilterRegister.15.FR1</name>
          <addressOffset>0x2b8</addressOffset>
          <size>0x20</size>
        </register>
        <register>
          <name>sFilterRegister.15.FR2</name>
          <addressOffset>0x2bc</addressOffset>
          <size>0x20</size>
        </register>
        <register>
          <name>sFilterRegister.16.FR1</name>
          <addressOffset>0x2c0</addressOffset>
          <size>0x20</size>
        </register>
        <register>
          <name>sFilterRegister.16.FR2</name>
          <addressOffset>0x2c4</addressOffset>
          <size>0x20</size>
        </register>
        <register>
          <name>sFilterRegister.17.FR1</name>
          <addressOffset>0x2c8</addressOffset>
          <size>0x20</size>
        </register>
        <register>
          <name>sFilterRegister.17.FR2</name>
          <addressOffset>0x2cc</addressOffset>
          <size>0x20</size>
        </register>
        <register>
          <name>sFilterRegister.18.FR1</name>
          <addressOffset>0x2d0</addressOffset>
          <size>0x20</size>
        </register>
        <register>
          <name>sFilterRegister.18.FR2</name>
          <addressOffset>0x2d4</addressOffset>
          <size>0x20</size>
        </register>
        <register>
          <name>sFilterRegister.19.FR1</name>
          <addressOffset>0x2d8</addressOffset>
          <size>0x20</size>
        </register>
        <register>
          <name>sFilterRegister.19.FR2</name>
          <addressOffset>0x2dc</addressOffset>
          <size>0x20</size>
        </register>
        <register>
          <name>sFilterRegister.20.FR1</name>
          <addressOffset>0x2e0</addressOffset>
          <size>0x20</size>
        </register>
        <register>
          <name>sFilterRegister.20.FR2</name>
          <addressOffset>0x2e4</addressOffset>
          <size>0x20</size>
        </register>
        <register>
          <name>sFilterRegister.21.FR1</name>
          <addressOffset>0x2e8</addressOffset>
          <size>0x20</size>
        </register>
        <register>
          <name>sFilterRegister.21.FR2</name>
          <addressOffset>0x2ec</addressOffset>
          <size>0x20</size>
        </register>
        <register>
          <name>sFilterRegister.22.FR1</name>
          <addressOffset>0x2f0</addressOffset>
          <size>0x20</size>
        </register>
        <register>
          <name>sFilterRegister.22.FR2</name>
          <addressOffset>0x2f4</addressOffset>
          <size>0x20</size>
        </register>
        <register>
          <name>sFilterRegister.23.FR1</name>
          <addressOffset>0x2f8</addressOffset>
          <size>0x20</size>
        </register>
        <register>
          <name>sFilterRegister.23.FR2</name>
          <addressOffset>0x2fc</addressOffset>
          <size>0x20</size>
        </register>
        <register>
          <name>sFilterRegister.24.FR1</name>
          <addressOffset>0x300</addressOffset>
          <size>0x20</size>
        </register>
        <register>
          <name>sFilterRegister.24.FR2</name>
          <addressOffset>0x304</addressOffset>
          <size>0x20</size>
        </register>
        <register>
          <name>sFilterRegister.25.FR1</name>
          <addressOffset>0x308</addressOffset>
          <size>0x20</size>
        </register>
        <register>
          <name>sFilterRegister.25.FR2</name>
          <addressOffset>0x30c</addressOffset>
          <size>0x20</size>
        </register>
        <register>
          <name>sFilterRegister.26.FR1</name>
          <addressOffset>0x310</addressOffset>
          <size>0x20</size>
        </register>
        <register>
          <name>sFilterRegister.26.FR2</name>
          <addressOffset>0x314</addressOffset>
          <size>0x20</size>
        </register>
        <register>
          <name>sFilterRegister.27.FR1</name>
          <addressOffset>0x318</addressOffset>
          <size>0x20</size>
        </register>
        <register>
          <name>sFilterRegister.27.FR2</name>
          <addressOffset>0x31c</addressOffset>
          <size>0x20</size>
        </register>
      </registers>
    </peripheral>
    <peripheral>
      <name>USB</name>
      <baseAddress>0x40006800</baseAddress>
      <registers>
        <register>
          <name>EP0R</name>
          <addressOffset>0x0</addressOffset>
          <size>0x10</size>
        </register>
        <register>
          <name>EP1R</name>
          <addressOffset>0x4</addressOffset>
          <size>0x10</size>
        </register>
        <register>
          <name>EP2R</name>
          <addressOffset>0x8</addressOffset>
          <size>0x10</size>
        </register>
        <register>
          <name>EP3R</name>
          <addressOffset>0xc</addressOffset>
          <size>0x10</size>
        </register>
        <register>
          <name>EP4R</name>
          <addressOffset>0x10</addressOffset>
          <size>0x10</size>
        </register>
        <register>
          <name>EP5R</name>
          <addressOffset>0x14</addressOffset>
          <size>0x10</size>
        </register>
        <register>
          <name>EP6R</name>
          <addressOffset>0x18</addressOffset>
          <size>0x10</size>
        </register>
        <register>
          <name>EP7R</name>
          <addressOffset>0x1c</addressOffset>
          <size>0x10</size>
        </register>
        <register>
          <name>CNTR</name>
          <addressOffset>0x40</addressOffset>
          <size>0x10</size>
        </register>
        <register>
          <name>ISTR</name>
          <addressOffset>0x44</addressOffset>
          <size>0x10</size>
        </register>
        <register>
          <name>FNR</name>
          <addressOffset>0x48</addressOffset>
          <size>0x10</size>
        </register>
        <register>
          <name>DADDR</name>
          <addressOffset>0x4c</addressOffset>
          <size>0x10</size>
        </register>
        <register>
          <name>BTABLE</name>
          <addressOffset>0x50</addressOffset>
          <size>0x10</size>
        </register>
        <register>
          <name>LPMCSR</name>
          <addressOffset>0x54</addressOffset>
          <size>0x10</size>
        </register>
        <register>
          <name>BCDR</name>
          <addressOffset>0x58</addressOffset>
          <size>0x10</size>
        </register>
      </registers>
    </peripheral>
    <peripheral>
      <name>PWR</name>
      <baseAddress>0x40007000</baseAddress>
      <registers>
        <register>
          <name>CR1</name>
          <addressOffset>0x0</addressOffset>
          <size>0x20</size>
          <fields>
            <field>
              <name>LPMS_STOP1</name>
              <bitOffset>0</bitOffset>
              <bitWidth>1</bitWidth>
            </field>
            <field>
              <name>LPMS_STOP2</name>
              <bitOffset>1</bitOffset>
              <bitWidth>1</bitWidth>
            </field>
            <field>
              <name>LPMS_SHUTDOWN</name>
              <bitOffset>2</bitOffset>
              <bitWidth>1</bitWidth>
            </field>
            <field>
              <name>DBP</name>
              <bitOffset>8</bitOffset>
              <bitWidth>1</bitWidth>
            </field>
            <field>
              <name>VOS</name>
              <bitOffset>9</bitOffset>
              <bitWidth>2</bitWidth>
            </field>
            <field>
              <name>LPR</name>
              <bitOffset>14</bitOffset>
              <bitWidth>1</bitWidth>
            </field>
          </fields>
        </register>
        <register>
          <name>CR2</name>
          <addressOffset>0x4</addressOffset>
          <size>0x20</size>
          <fields>
            <field>
              <name>PVDE</name>
              <bitOffset>0</bitOffset>
              <bitWidth>1</bitWidth>
            </field>
            <field>
              <name>PLS_LEV7</name>
              <bitOffset>1</bitOffset>
              <bitWidth>3</bitWidth>
            </field>
            <field>
              <name>PLS_LEV6</name>
              <bitOffset>2</bitOffset>
              <bitWidth>2</bitWidth>
            </field>
            <field>
              <name>PLS_LEV4</name>
              <bitOffset>3</bitOffset>
              <bitWidth>1</bitWidth>
            </field>
            <field>
              <name>PVME1</name>
              <bitOffset>4</bitOffset>
              <bitWidth>1</bitWidth>
            </field>
            <field>
              <name>PVME3</name>
              <bitOffset>6</bitOffset>
              <bitWidth>1</bitWidth>
            </field>
            <field>
              <name>PVME4</name>
              <bitOffset>7</bitOffset>
              <bitWidth>1</bitWidth>
            </field>
            <field>
              <name>USV</name>
              <bitOffset>10</bitOffset>
              <bitWidth>1</bitWidth>
            </field>
          </fields>
        </register>
        <register>
          <name>CR3</name>
          <addressOffset>0x8</addressOffset>
          <size>0x20</size>
          <fields>
            <field>
              <name>EWUP1</name>
              <bitOffset>0</bitOffset>
              <bitWidth>1</bitWidth>
            </field>
            <field>
              <name>EWUP2</name>
              <bitOffset>1</bitOffset>
              <bitWidth>1</bitWidth>
            </field>
            <field>
              <name>EWUP3</name>
              <bitOffset>2</bitOffset>
              <bitWidth>1</bitWidth>
            </field>
            <field>
              <name>EWUP4</name>
              <bitOffset>3</bitOffset>
              <bitWidth>1</bitWidth>
            </field>
            <field>
              <name>EWUP5</name>
              <bitOffset>4</bitOffset>
              <bitWidth>1</bitWidth>
            </field>
            <field>
              <name>RRS</name>
              <bitOffset>8</bitOffset>
              <bitWidth>1</bitWidth>
            </field>
            <field>
              <name>APC</name>
              <bitOffset>10</bitOffset>
              <bitWidth>1</bitWidth>
            </field>
            <field>
              <name>EIWUL</name>
              <bitOffset>15</bitOffset>
              <bitWidth>1</bitWidth>
            </field>
          </fields>
        </register>
        <register>
          <name>CR4</name>
          <addressOffset>0xc</addressOffset>
          <size>0x20</size>
          <fields>
            <field>
              <name>WP1</name>
              <bitOffset>0</bitOffset>
              <bitWidth>1</bitWidth>
            </field>
            <field>
              <name>WP2</name>
              <bitOffset>1</bitOffset>
              <bitWidth>1</bitWidth>
            </field>
            <field>
              <name>WP3</name>
              <bitOffset>2</bitOffset>
              <bitWidth>1</bitWidth>
            </field>
            <field>
              <name>WP4</name>
              <bitOffset>3</bitOffset>
              <bitWidth>1</bitWidth>
            </field>
            <field>
              <name>WP5</name>
              <bitOffset>4</bitOffset>
              <bitWidth>1</bitWidth>
            </field>
            <field>
              <name>VBE</name>
              <bitOffset>8</bitOffset>
              <bitWidth>1</bitWidth>
            </field>
            <field>
              <name>VBRS</name>
              <bitOffset>9</bitOffset>
              <bitWidth>1</bitWidth>
            </field>
          </fields>
        </register>
        <register>
          <name>SR1</name>
          <addressOffset>0x10</addressOffset>
          <size>0x20</size>
          <fields>
            <field>
              <name>WUF1</name>
              <bitOffset>0</bitOffset>
              <bitWidth>1</bitWidth>
            </field>
            <field>
              <name>WUF2</name>
              <bitOffset>1</bitOffset>
              <bitWidth>1</bitWidth>
            </field>
            <field>
              <name>WUF3</name>
              <bitOffset>2</bitOffset>
              <bitWidth>1</bitWidth>
            </field>
            <field>
              <name>WUF4</name>
              <bitOffset>3</bitOffset>
              <bitWidth>1</bitWidth>
            </field>
            <field>
              <name>WUF5</name>
              <bitOffset>4</bitOffset>
              <bitWidth>1</bitWidth>
            </field>
            <field>
              <name>SBF</name>
              <bitOffset>8</bitOffset>
              <bitWidth>1</bitWidth>
            </field>
            <field>
              <name>WUFI</name>
              <bitOffset>15</bitOffset>
              <bitWidth>1</bitWidth>
            </field>
          </fields>
        </register>
        <register>
          <name>SR2</name>
          <addressOffset>0x14</addressOffset>
          <size>0x20</size>
          <fields>
            <field>
              <name>REGLPS</name>
              <bitOffset>8</bitOffset>
              <bitWidth>1</bitWidth>
            </field>
            <field>
              <name>REGLPF</name>
              <bitOffset>9</bitOffset>
              <bitWidth>1</bitWidth>
            </field>
            <field>
              <name>VOSF</name>
              <bitOffset>10</bitOffset>
              <bitWidth>1</bitWidth>
            </field>
            <field>
              <name>PVDO</name>
              <bitOffset>11</bitOffset>
              <bitWidth>1</bitWidth>
            </field>
            <field>
              <name>PVMO1</name>
              <bitOffset>12</bitOffset>
              <bitWidth>1</bitWidth>
            </field>
            <field>
              <name>PVMO3</name>
              <bitOffset>14</bitOffset>
              <bitWidth>1</bitWidth>
            </field>
            <field>
              <name>PVMO4</name>
              <bitOffset>15</bitOffset>
              <bitWidth>1</bitWidth>
            </field>
          </fields>
        </register>
        <register>
          <name>SCR</name>
          <addressOffset>0x18</addressOffset>
          <size>0x20</size>
          <fields>
            <field>
              <name>CWUF1</name>
              <bitOffset>0</bitOffset>
              <bitWidth>1</bitWidth>
            </field>
            <field>
              <name>CWUF2</name>
              <bitOffset>1</bitOffset>
              <bitWidth>1</bitWidth>
            </field>
            <field>
              <name>CWUF3</name>
              <bitOffset>2</bitOffset>
              <bitWidth>1</bitWidth>
            </field>
            <field>
              <name>CWUF4</name>
              <bitOffset>3</bitOffset>
              <bitWidth>1</bitWidth>
            </field>
            <field>
              <name>CWUF5</name>
              <bitOffset>4</bitOffset>
              <bitWidth>1</bitWidth>
            </field>
            <field>
              <name>CSBF</name>
              <bitOffset>8</bitOffset>
              <bitWidth>1</bitWidth>
            </field>
          </fields>
        </register>
        <register>
          <name>PUCRA</name>
          <addressOffset>0x20</addressOffset>
          <size>0x20</size>
          <fields>
            <field>
              <name>PA0</name>
              <bitOffset>0</bitOffset>
              <bitWidth>1</bitWidth>
            </field>
            <field>
              <name>PA1</name>
              <bitOffset>1</bitOffset>
              <bitWidth>1</bitWidth>
            </field>
            <field>
              <name>PA2</name>
              <bitOffset>2</bitOffset>
              <bitWidth>1</bitWidth>
            </field>
            <field>
              <name>PA3</name>
              <bitOffset>3</bitOffset>
              <bitWidth>1</bitWidth>
            </field>
            <field>
              <name>PA4</name>
              <bitOffset>4</bitOffset>
              <bitWidth>1</bitWidth>
            </field>
            <field>
              <name>PA5</name>
              <bitOffset>5</bitOffset>
              <bitWidth>1</bitWidth>
            </field>
            <field>
              <name>PA6</name>
              <bitOffset>6</bitOffset>
              <bitWidth>1</bitWidth>
            </field>
            <field>
              <name>PA7</name>
              <bitOffset>7</bitOffset>
              <bitWidth>1</bitWidth>
            </field>
            <field>
              <name>PA8</name>
              <bitOffset>8</bitOffset>
              <bitWidth>1</bitWidth>
            </field>
            <field>
              <name>PA9</name>
              <bitOffset>9</bitOffset>
              <bitWidth>1</bitWidth>
            </field>
            <field>
              <name>PA10</name>
              <bitOffset>10</bitOffset>
              <bitWidth>1</bitWidth>
            </field>
            <field>
              <name>PA11</name>
              <bitOffset>11</bitOffset>
              <bitWidth>1</bitWidth>
            </field>
            <field>
              <name>PA12</name>
              <bitOffset>12</bitOffset>
              <bitWidth>1</bitWidth>
            </field>
            <field>
              <name>PA13</name>
              <bitOffset>13</bitOffset>
              <bitWidth>1</bitWidth>
            </field>
            <field>
              <name>PA15</name>
              <bitOffset>15</bitOffset>
              <bitWidth>1</bitWidth>
            </field>
          </fields>
        </register>
        <register>
          <name>PDCRA</name>
          <addressOffset>0x24</addressOffset>
          <size>0x20</size>
          <fields>
            <field>
              <name>PA0</name>
              <bitOffset>0</bitOffset>
              <bitWidth>1</bitWidth>
            </field>
            <field>
              <name>PA1</name>
              <bitOffset>1</bitOffset>
              <bitWidth>1</bitWidth>
            </field>
            <field>
              <name>PA2</name>
              <bitOffset>2</bitOffset>
              <bitWidth>1</bitWidth>
            </field>
            <field>
              <name>PA3</name>
              <bitOffset>3</bitOffset>
              <bitWidth>1</bitWidth>
            </field>
            <field>
              <name>PA4</name>
              <bitOffset>4</bitOffset>
              <bitWidth>1</bitWidth>
            </field>
            <field>
              <name>PA5</name>
              <bitOffset>5</bitOffset>
              <bitWidth>1</bitWidth>
            </field>
            <field>
              <name>PA6</name>
              <bitOffset>6</bitOffset>
              <bitWidth>1</bitWidth>
            </field>
            <field>
              <name>PA7</name>
              <bitOffset>7</bitOffset>
              <bitWidth>1</bitWidth>
            </field>
            <field>
              <name>PA8</name>
              <bitOffset>8</bitOffset>
              <bitWidth>1</bitWidth>
            </field>
            <field>
              <name>PA9</name>
              <bitOffset>9</bitOffset>
              <bitWidth>1</bitWidth>
            </field>
            <field>
              <name>PA10</name>
              <bitOffset>10</bitOffset>
              <bitWidth>1</bitWidth>
            </field>
            <field>
              <name>PA11</name>
              <bitOffset>11</bitOffset>
              <bitWidth>1</bitWidth>
            </field>
            <field>
              <name>PA12</name>
              <bitOffset>12</bitOffset>
              <bitWidth>1</bitWidth>
            </field>
            <field>
              <name>PA14</name>
              <bitOffset>14</bitOffset>
              <bitWidth>1</bitWidth>
            </field>
          </fields>
        </register>
        <register>
          <name>PUCRB</name>
          <addressOffset>0x28</addressOffset>
          <size>0x20</size>
          <fields>
            <field>
              <name>PB0</name>
              <bitOffset>0</bitOffset>
              <bitWidth>1</bitWidth>
            </field>
            <field>
              <name>PB1</name>
              <bitOffset>1</bitOffset>
              <bitWidth>1</bitWidth>
            </field>
            <field>
              <name>PB2</name>
              <bitOffset>2</bitOffset>
              <bitWidth>1</bitWidth>
            </field>
            <field>
              <name>PB3</name>
              <bitOffset>3</bitOffset>
              <bitWidth>1</bitWidth>
            </field>
            <field>
              <name>PB4</name>
              <bitOffset>4</bitOffset>
              <bitWidth>1</bitWidth>
            </field>
            <field>
              <name>PB5</name>
              <bitOffset>5</bitOffset>
              <bitWidth>1</bitWidth>
            </field>
            <field>
              <name>PB6</name>
              <bitOffset>6</bitOffset>
              <bitWidth>1</bitWidth>
            </field>
            <field>
              <name>PB7</name>
              <bitOffset>7</bitOffset>
              <bitWidth>1</bitWidth>
            </field>
            <field>
              <name>PB8</name>
              <bitOffset>8</bitOffset>
              <bitWidth>1</bitWidth>
            </field>
            <field>
              <name>PB9</name>
              <bitOffset>9</bitOffset>
              <bitWidth>1</bitWidth>
            </field>
            <field>
              <name>PB10</name>
              <bitOffset>10</bitOffset>
              <bitWidth>1</bitWidth>
            </field>
            <field>
              <name>PB11</name>
              <bitOffset>11</bitOffset>
              <bitWidth>1</bitWidth>
            </field>
            <field>
              <name>PB12</name>
              <bitOffset>12</bitOffset>
              <bitWidth>1</bitWidth>
            </field>
            <field>
              <name>PB13</name>
              <bitOffset>13</bitOffset>
              <bitWidth>1</bitWidth>
            </field>
            <field>
              <name>PB14</name>
              <bitOffset>14</bitOffset>
              <bitWidth>1</bitWidth>
            </field>
            <field>
              <name>PB15</name>
              <bitOffset>15</bitOffset>
              <bitWidth>1</bitWidth>
            </field>
          </fields>
        </register>
        <register>
          <name>PDCRB</name>
          <addressOffset>0x2c</addressOffset>
          <size>0x20</size>
          <fields>
            <field>
              <name>PB0</name>
              <bitOffset>0</bitOffset>
              <bitWidth>1</bitWidth>
            </field>
            <field>
              <name>PB1</name>
              <bitOffset>1</bitOffset>
              <bitWidth>1</bitWidth>
            </field>
            <field>
              <name>PB2</name>
              <bitOffset>2</bitOffset>
              <bitWidth>1</bitWidth>
            </field>
            <field>
              <name>PB3</name>
              <bitOffset>3</bitOffset>
              <bitWidth>1</bitWidth>
            </field>
            <field>
              <name>PB5</name>
              <bitOffset>5</bitOffset>
              <bitWidth>1</bitWidth>
            </field>
            <field>
              <name>PB6</name>
              <bitOffset>6</bitOffset>
              <bitWidth>1</bitWidth>
            </field>
            <field>
              <name>PB7</name>
              <bitOffset>7</bitOffset>
              <bitWidth>1</bitWidth>
            </field>
            <field>
              <name>PB8</name>
              <bitOffset>8</bitOffset>
              <bitWidth>1</bitWidth>
            </field>
            <field>
              <name>PB9</name>
              <bitOffset>9</bitOffset>
              <bitWidth>1</bitWidth>
            </field>
            <field>
              <name>PB10</name>
              <bitOffset>10</bitOffset>
              <bitWidth>1</bitWidth>
            </field>
            <field>
              <name>PB11</name>
              <bitOffset>11</bitOffset>
              <bitWidth>1</bitWidth>
            </field>
            <field>
              <name>PB12</name>
              <bitOffset>12</bitOffset>
              <bitWidth>1</bitWidth>
            </field>
            <field>
              <name>PB13</name>
              <bitOffset>13</bitOffset>
              <bitWidth>1</bitWidth>
            </field>
            <field>
              <name>PB14</name>
              <bitOffset>14</bitOffset>
              <bitWidth>1</bitWidth>
            </field>
            <field>
              <name>PB15</name>
              <bitOffset>15</bitOffset>
              <bitWidth>1</bitWidth>
            </field>
          </fields>
        </register>
        <register>
          <name>PUCRC</name>
          <addressOffset>0x30</addressOffset>
          <size>0x20</size>
          <fields>
            <field>
              <name>PC0</name>
              <bitOffset>0</bitOffset>
              <bitWidth>1</bitWidth>
            </field>
            <field>
              <name>PC1</name>
              <bitOffset>1</bitOffset>
              <bitWidth>1</bitWidth>
            </field>
            <field>
              <name>PC2</name>
              <bitOffset>2</bitOffset>
              <bitWidth>1</bitWidth>
            </field>
            <field>
              <name>PC3</name>
              <bitOffset>3</bitOffset>
              <bitWidth>1</bitWidth>
            </field>
            <field>
              <name>PC4</name>
              <bitOffset>4</bitOffset>
              <bitWidth>1</bitWidth>
            </field>
            <field>
              <name>PC5</name>
              <bitOffset>5</bitOffset>
              <bitWidth>1</bitWidth>
            </field>
            <field>
              <name>PC6</name>
              <bitOffset>6</bitOffset>
              <bitWidth>1</bitWidth>
            </field>
            <field>
              <name>PC7</name>
              <bitOffset>7</bitOffset>
              <bitWidth>1</bitWidth>
            </field>
            <field>
              <name>PC8</name>
              <bitOffset>8</bitOffset>
              <bitWidth>1</bitWidth>
            </field>
            <field>
              <name>PC9</name>
              <bitOffset>9</bitOffset>
              <bitWidth>1</bitWidth>
            </field>
            <field>
              <name>PC10</name>
              <bitOffset>10</bitOffset>
              <bitWidth>1</bitWidth>
            </field>
            <field>
              <name>PC11</name>
              <bitOffset>11</bitOffset>
              <bitWidth>1</bitWidth>
            </field>
            <field>
              <name>PC12</name>
              <bitOffset>12</bitOffset>
              <bitWidth>1</bitWidth>
            </field>
            <field>
              <name>PC13</name>
              <bitOffset>13</bitOffset>
              <bitWidth>1</bitWidth>
            </field>
            <field>
              <name>PC14</name>
              <bitOffset>14</bitOffset>
              <bitWidth>1</bitWidth>
            </field>
            <field>
              <name>PC15</name>
              <bitOffset>15</bitOffset>
              <bitWidth>1</bitWidth>
            </field>
          </fields>
        </register>
        <register>
          <name>PDCRC</name>
          <addressOffset>0x34</addressOffset>
          <size>0x20</size>
          <fields>
            <field>
              <name>PC0</name>
              <bitOffset>0</bitOffset>
              <bitWidth>1</bitWidth>
            </field>
            <field>
              <name>PC1</name>
              <bitOffset>1</bitOffset>
              <bitWidth>1</bitWidth>
            </field>
            <field>
              <name>PC2</name>
              <bitOffset>2</bitOffset>
              <bitWidth>1</bitWidth>
            </field>
            <field>
              <name>PC3</name>
              <bitOffset>3</bitOffset>
              <bitWidth>1</bitWidth>
            </field>
            <field>
              <name>PC4</name>
              <bitOffset>4</bitOffset>
              <bitWidth>1</bitWidth>
            </field>
            <field>
              <name>PC5</name>
              <bitOffset>5</bitOffset>
              <bitWidth>1</bitWidth>
            </field>
            <field>
              <name>PC6</name>
              <bitOffset>6</bitOffset>
              <bitWidth>1</bitWidth>
            </field>
            <field>
              <name>PC7</name>
              <bitOffset>7</bitOffset>
              <bitWidth>1</bitWidth>
            </field>
            <field>
              <name>PC8</name>
              <bitOffset>8</bitOffset>
              <bitWidth>1</bitWidth>
            </field>
            <field>
              <name>PC9</name>
              <bitOffset>9</bitOffset>
              <bitWidth>1</bitWidth>
            </field>
            <field>
              <name>PC10</name>
              <bitOffset>10</bitOffset>
              <bitWidth>1</bitWidth>
            </field>
            <field>
              <name>PC11</name>
              <bitOffset>11</bitOffset>
              <bitWidth>1</bitWidth>
            </field>
            <field>
              <name>PC12</name>
              <bitOffset>12</bitOffset>
              <bitWidth>1</bitWidth>
            </field>
            <field>
              <name>PC13</name>
              <bitOffset>13</bitOffset>
              <bitWidth>1</bitWidth>
            </field>
            <field>
              <name>PC14</name>
              <bitOffset>14</bitOffset>
              <bitWidth>1</bitWidth>
            </field>
            <field>
              <name>PC15</name>
              <bitOffset>15</bitOffset>
              <bitWidth>1</bitWidth>
            </field>
          </fields>
        </register>
        <register>
          <name>PUCRD</name>
          <addressOffset>0x38</addressOffset>
          <size>0x20</size>
          <fields>
            <field>
              <name>PD0</name>
              <bitOffset>0</bitOffset>
              <bitWidth>1</bitWidth>
            </field>
            <field>
              <name>PD1</name>
              <bitOffset>1</bitOffset>
              <bitWidth>1</bitWidth>
            </field>
            <field>
              <name>PD2</name>
              <bitOffset>2</bitOffset>
              <bitWidth>1</bitWidth>
            </field>
            <field>
              <name>PD3</name>
              <bitOffset>3</bitOffset>
              <bitWidth>1</bitWidth>
            </field>
            <field>
              <name>PD4</name>
              <bitOffset>4</bitOffset>
              <bitWidth>1</bitWidth>
            </field>
            <field>
              <name>PD5</name>
              <bitOffset>5</bitOffset>
              <bitWidth>1</bitWidth>
            </field>
            <field>
              <name>PD6</name>
              <bitOffset>6</bitOffset>
              <bitWidth>1</bitWidth>
            </field>
            <field>
              <name>PD7</name>
              <bitOffset>7</bitOffset>
              <bitWidth>1</bitWidth>
            </field>
            <field>
              <name>PD8</name>
              <bitOffset>8</bitOffset>
              <bitWidth>1</bitWidth>
            </field>
            <field>
              <name>PD9</name>
              <bitOffset>9</bitOffset>
              <bitWidth>1</bitWidth>
            </field>
            <field>
              <name>PD10</name>
              <bitOffset>10</bitOffset>
              <bitWidth>1</bitWidth>
            </field>
            <field>
              <name>PD11</name>
              <bitOffset>11</bitOffset>
              <bitWidth>1</bitWidth>
            </field>
            <field>
              <name>PD12</name>
              <bitOffset>12</bitOffset>
              <bitWidth>1</bitWidth>
            </field>
            <field>
              <name>PD13</name>
              <bitOffset>13</bitOffset>
              <bitWidth>1</bitWidth>
            </field>
            <field>
              <name>PD14</name>
              <bitOffset>14</bitOffset>
              <bitWidth>1</bitWidth>
            </field>
            <field>
              <name>PD15</name>
              <bitOffset>15</bitOffset>
              <bitWidth>1</bitWidth>
            </field>
          </fields>
        </register>
        <register>
          <name>PDCRD</name>
          <addressOffset>0x3c</addressOffset>
          <size>0x20</size>
          <fields>
            <field>
              <name>PD0</name>
              <bitOffset>0</bitOffset>
              <bitWidth>1</bitWidth>
            </field>
            <field>
              <name>PD1</name>
              <bitOffset>1</bitOffset>
              <bitWidth>1</bitWidth>
            </field>
            <field>
              <name>PD2</name>
              <bitOffset>2</bitOffset>
              <bitWidth>1</bitWidth>
            </field>
            <field>
              <name>PD3</name>
              <bitOffset>3</bitOffset>
              <bitWidth>1</bitWidth>
            </field>
            <field>
              <name>PD4</name>
              <bitOffset>4</bitOffset>
              <bitWidth>1</bitWidth>
            </field>
            <field>
              <name>PD5</name>
              <bitOffset>5</bitOffset>
              <bitWidth>1</bitWidth>
            </field>
            <field>
              <name>PD6</name>
              <bitOffset>6</bitOffset>
              <bitWidth>1</bitWidth>
            </field>
            <field>
              <name>PD7</name>
              <bitOffset>7</bitOffset>
              <bitWidth>1</bitWidth>
            </field>
            <field>
              <name>PD8</name>
              <bitOffset>8</bitOffset>
              <bitWidth>1</bitWidth>
            </field>
            <field>
              <name>PD9</name>
              <bitOffset>9</bitOffset>
              <bitWidth>1</bitWidth>
            </field>
            <field>
              <name>PD10</name>
              <bitOffset>10</bitOffset>
              <bitWidth>1</bitWidth>
            </field>
            <field>
              <name>PD11</name>
              <bitOffset>11</bitOffset>
              <bitWidth>1</bitWidth>
            </field>
            <field>
              <name>PD12</name>
              <bitOffset>12</bitOffset>
              <bitWidth>1</bitWidth>
            </field>
            <field>
              <name>PD13</name>
              <bitOffset>13</bitOffset>
              <bitWidth>1</bitWidth>
            </field>
            <field>
              <name>PD14</name>
              <bitOffset>14</bitOffset>
              <bitWidth>1</bitWidth>
            </field>
            <field>
              <name>PD15</name>
              <bitOffset>15</bitOffset>
              <bitWidth>1</bitWidth>
            </field>
          </fields>
        </register>
        <register>
          <name>PUCRE</name>
          <addressOffset>0x40</addressOffset>
          <size>0x20</size>
          <fields>
            <field>
              <name>PE0</name>
              <bitOffset>0</bitOffset>
              <bitWidth>1</bitWidth>
            </field>
            <field>
              <name>PE1</name>
              <bitOffset>1</bitOffset>
              <bitWidth>1</bitWidth>
            </field>
            <field>
              <name>PE2</name>
              <bitOffset>2</bitOffset>
              <bitWidth>1</bitWidth>
            </field>
            <field>
              <name>PE3</name>
              <bitOffset>3</bitOffset>
              <bitWidth>1</bitWidth>
            </field>
            <field>
              <name>PE4</name>
              <bitOffset>4</bitOffset>
              <bitWidth>1</bitWidth>
            </field>
            <field>
              <name>PE5</name>
              <bitOffset>5</bitOffset>
              <bitWidth>1</bitWidth>
            </field>
            <field>
              <name>PE6</name>
              <bitOffset>6</bitOffset>
              <bitWidth>1</bitWidth>
            </field>
            <field>
              <name>PE7</name>
              <bitOffset>7</bitOffset>
              <bitWidth>1</bitWidth>
            </field>
            <field>
              <name>PE8</name>
              <bitOffset>8</bitOffset>
              <bitWidth>1</bitWidth>
            </field>
            <field>
              <name>PE9</name>
              <bitOffset>9</bitOffset>
              <bitWidth>1</bitWidth>
            </field>
            <field>
              <name>PE10</name>
              <bitOffset>10</bitOffset>
              <bitWidth>1</bitWidth>
            </field>
            <field>
              <name>PE11</name>
              <bitOffset>11</bitOffset>
              <bitWidth>1</bitWidth>
            </field>
            <field>
              <name>PE12</name>
              <bitOffset>12</bitOffset>
              <bitWidth>1</bitWidth>
            </field>
            <field>
              <name>PE13</name>
              <bitOffset>13</bitOffset>
              <bitWidth>1</bitWidth>
            </field>
            <field>
              <name>PE14</name>
              <bitOffset>14</bitOffset>
              <bitWidth>1</bitWidth>
            </field>
            <field>
              <name>PE15</name>
              <bitOffset>15</bitOffset>
              <bitWidth>1</bitWidth>
            </field>
          </fields>
        </register>
        <register>
          <name>PDCRE</name>
          <addressOffset>0x44</addressOffset>
          <size>0x20</size>
          <fields>
            <field>
              <name>PE0</name>
              <bitOffset>0</bitOffset>
              <bitWidth>1</bitWidth>
            </field>
            <field>
              <name>PE1</name>
              <bitOffset>1</bitOffset>
              <bitWidth>1</bitWidth>
            </field>
            <field>
              <name>PE2</name>
              <bitOffset>2</bitOffset>
              <bitWidth>1</bitWidth>
            </field>
            <field>
              <name>PE3</name>
              <bitOffset>3</bitOffset>
              <bitWidth>1</bitWidth>
            </field>
            <field>
              <name>PE4</name>
              <bitOffset>4</bitOffset>
              <bitWidth>1</bitWidth>
            </field>
            <field>
              <name>PE5</name>
              <bitOffset>5</bitOffset>
              <bitWidth>1</bitWidth>
            </field>
            <field>
              <name>PE6</name>
              <bitOffset>6</bitOffset>
              <bitWidth>1</bitWidth>
            </field>
            <field>
              <name>PE7</name>
              <bitOffset>7</bitOffset>
              <bitWidth>1</bitWidth>
            </field>
            <field>
              <name>PE8</name>
              <bitOffset>8</bitOffset>
              <bitWidth>1</bitWidth>
            </field>
            <field>
              <name>PE9</name>
              <bitOffset>9</bitOffset>
              <bitWidth>1</bitWidth>
            </field>
            <field>
              <name>PE10</name>
              <bitOffset>10</bitOffset>
              <bitWidth>1</bitWidth>
            </field>
            <field>
              <name>PE11</name>
              <bitOffset>11</bitOffset>
              <bitWidth>1</bitWidth>
            </field>
            <field>
              <name>PE12</name>
              <bitOffset>12</bitOffset>
              <bitWidth>1</bitWidth>
            </field>
            <field>
              <name>PE13</name>
              <bitOffset>13</bitOffset>
              <bitWidth>1</bitWidth>
            </field>
            <field>
              <name>PE14</name>
              <bitOffset>14</bitOffset>
              <bitWidth>1</bitWidth>
            </field>
            <field>
              <name>PE15</name>
              <bitOffset>15</bitOffset>
              <bitWidth>1</bitWidth>
            </field>
          </fields>
        </register>
        <register>
          <name>PUCRH</name>
          <addressOffset>0x58</addressOffset>
          <size>0x20</size>
          <fields>
            <field>
              <name>PH0</name>
              <bitOffset>0</bitOffset>
              <bitWidth>1</bitWidth>
            </field>
            <field>
              <name>PH1</name>
              <bitOffset>1</bitOffset>
              <bitWidth>1</bitWidth>
            </field>
            <field>
              <name>PH3</name>
              <bitOffset>3</bitOffset>
              <bitWidth>1</bitWidth>
            </field>
          </fields>
        </register>
        <register>
          <name>PDCRH</name>
          <addressOffset>0x5c</addressOffset>
          <size>0x20</size>
          <fields>
            <field>
              <name>PH0</name>
              <bitOffset>0</bitOffset>
              <bitWidth>1</bitWidth>
            </field>
            <field>
              <name>PH1</name>
              <bitOffset>1</bitOffset>
              <bitWidth>1</bitWidth>
            </field>
            <field>
              <name>PH3</name>
              <bitOffset>3</bitOffset>
              <bitWidth>1</bitWidth>
            </field>
          </fields>
        </register>
      </registers>
    </peripheral>
    <peripheral>
      <name>DAC</name>
      <baseAddress>0x40007400</baseAddress>
      <registers>
        <register>
          <name>CR</name>
          <addressOffset>0x0</addressOffset>
          <size>0x20</size>
          <fields>
            <field>
              <name>EN1</name>
              <bitOffset>0</bitOffset>
              <bitWidth>1</bitWidth>
            </field>
            <field>
              <name>TEN1</name>
              <bitOffset>2</bitOffset>
              <bitWidth>1</bitWidth>
            </field>
            <field>
              <name>TSEL1</name>
              <bitOffset>3</bitOffset>
              <bitWidth>3</bitWidth>
            </field>
            <field>
              <name>WAVE1</name>
              <bitOffset>6</bitOffset>
              <bitWidth>2</bitWidth>
            </field>
            <field>
              <name>MAMP1</name>
              <bitOffset>8</bitOffset>
              <bitWidth>4</bitWidth>
            </field>
            <field>
              <name>DMAEN1</name>
              <bitOffset>12</bitOffset>
              <bitWidth>1</bitWidth>
            </field>
            <field>
              <name>DMAUDRIE1</name>
              <bitOffset>13</bitOffset>
              <bitWidth>1</bitWidth>
            </field>
            <field>
              <name>CEN1</name>
              <bitOffset>14</bitOffset>
              <bitWidth>1</bitWidth>
            </field>
            <field>
              <name>EN2</name>
              <bitOffset>16</bitOffset>
              <bitWidth>1</bitWidth>
            </field>
            <field>
              <name>TEN2</name>
              <bitOffset>18</bitOffset>
              <bitWidth>1</bitWidth>
            </field>
            <field>
              <name>TSEL2</name>
              <bitOffset>19</bitOffset>
              <bitWidth>3</bitWidth>
            </field>
            <field>
              <name>WAVE2</name>
              <bitOffset>22</bitOffset>
              <bitWidth>2</bitWidth>
            </field>
            <field>
              <name>MAMP2</name>
              <bitOffset>24</bitOffset>
              <bitWidth>4</bitWidth>
            </field>
            <field>
              <name>DMAEN2</name>
              <bitOffset>28</bitOffset>
              <bitWidth>1</bitWidth>
            </field>
            <field>
              <name>DMAUDRIE2</name>
              <bitOffset>29</bitOffset>
              <bitWidth>1</bitWidth>
            </field>
            <field>
              <name>CEN2</name>
              <bitOffset>30</bitOffset>
              <bitWidth>1</bitWidth>
            </field>
          </fields>
        </register>
        <register>
          <name>SWTRIGR</name>
          <addressOffset>0x4</addressOffset>
          <size>0x20</size>
          <fields>
            <field>
              <name>SWTRIG1</name>
              <bitOffset>0</bitOffset>
              <bitWidth>1</bitWidth>
            </field>
            <field>
              <name>SWTRIG2</name>
              <bitOffset>1</bitOffset>
              <bitWidth>1</bitWidth>
            </field>
          </fields>
        </register>
        <register>
          <name>DHR12R1</name>
          <addressOffset>0x8</addressOffset>
          <size>0x20</size>
          <fields>
            <field>
              <name>DACC1DHR</name>
              <bitOffset>0</bitOffset>
              <bitWidth>12</bitWidth>
            </field>
          </fields>
        </register>
        <register>
          <name>DHR12L1</name>
          <addressOffset>0xc</addressOffset>
          <size>0x20</size>
          <fields>
            <field>
              <name>DACC1DHR</name>
              <bitOffset>4</bitOffset>
              <bitWidth>12</bitWidth>
            </field>
          </fields>
        </register>
        <register>
          <name>DHR8R1</name>
          <addressOffset>0x10</addressOffset>
          <size>0x20</size>
          <fields>
            <field>
              <name>DACC1DHR</name>
              <bitOffset>0</bitOffset>
              <bitWidth>8</bitWidth>
            </field>
          </fields>
        </register>
        <register>
          <name>DHR12R2</name>
          <addressOffset>0x14</addressOffset>
          <size>0x20</size>
          <fields>
            <field>
              <name>DACC2DHR</name>
              <bitOffset>0</bitOffset>
              <bitWidth>12</bitWidth>
            </field>
          </fields>
        </register>
        <register>
          <name>DHR12L2</name>
          <addressOffset>0x18</addressOffset>
          <size>0x20</size>
          <fields>
            <field>
              <name>DACC2DHR</name>
              <bitOffset>4</bitOffset>
              <bitWidth>12</bitWidth>
            </field>
          </fields>
        </register>
        <register>
          <name>DHR8R2</name>
          <addressOffset>0x1c</addressOffset>
          <size>0x20</size>
          <fields>
            <field>
              <name>DACC2DHR</name>
              <bitOffset>0</bitOffset>
              <bitWidth>8</bitWidth>
            </field>
          </fields>
        </register>
        <register>
          <name>DHR12RD</name>
          <addressOffset>0x20</addressOffset>
          <size>0x20</size>
          <fields>
            <field>
              <name>DACC1DHR</name>
              <bitOffset>0</bitOffset>
              <bitWidth>12</bitWidth>
            </field>
            <field>
              <name>DACC2DHR</name>
              <bitOffset>16</bitOffset>
              <bitWidth>12</bitWidth>
            </field>
          </fields>
        </register>
        <register>
          <name>DHR12LD</name>
          <addressOffset>0x24</addressOffset>
          <size>0x20</size>
          <fields>
            <field>
              <name>DACC1DHR</name>
              <bitOffset>4</bitOffset>
              <bitWidth>12</bitWidth>
            </field>
            <field>
              <name>DACC2DHR</name>
              <bitOffset>20</bitOffset>
              <bitWidth>12</bitWidth>
            </field>
          </fields>
        </register>
        <register>
          <name>DHR8RD</name>
          <addressOffset>0x28</addressOffset>
          <size>0x20</size>
          <fields>
            <field>
              <name>DACC1DHR</name>
              <bitOffset>0</bitOffset>
              <bitWidth>8</bitWidth>
            </field>
            <field>
              <name>DACC2DHR</name>
              <bitOffset>8</bitOffset>
              <bitWidth>8</bitWidth>
            </field>
          </fields>
        </register>
        <register>
          <name>DOR1</name>
          <addressOffset>0x2c</addressOffset>
          <size>0x20</size>
          <fields>
            <field>
              <name>DACC1DOR</name>
              <bitOffset>0</bitOffset>
              <bitWidth>12</bitWidth>
            </field>
          </fields>
        </register>
        <register>
          <name>DOR2</name>
          <addressOffset>0x30</addressOffset>
          <size>0x20</size>
          <fields>
            <field>
              <name>DACC2DOR</name>
              <bitOffset>0</bitOffset>
              <bitWidth>12</bitWidth>
            </field>
          </fields>
        </register>
        <register>
          <name>SR</name>
          <addressOffset>0x34</addressOffset>
          <size>0x20</size>
          <fields>
            <field>
              <name>DMAUDR1</name>
              <bitOffset>13</bitOffset>
              <bitWidth>1</bitWidth>
            </field>
            <field>
              <name>CAL_FLAG1</name>
              <bitOffset>14</bitOffset>
              <bitWidth>1</bitWidth>
            </field>
            <field>
              <name>BWST1</name>
              <bitOffset>15</bitOffset>
              <bitWidth>1</bitWidth>
            </field>
            <field>
              <name>DMAUDR2</name>
              <bitOffset>29</bitOffset>
              <bitWidth>1</bitWidth>
            </field>
            <field>
              <name>CAL_FLAG2</name>
              <bitOffset>30</bitOffset>
              <bitWidth>1</bitWidth>
            </field>
            <field>
              <name>BWST2</name>
              <bitOffset>31</bitOffset>
              <bitWidth>1</bitWidth>
            </field>
          </fields>
        </register>
        <register>
          <name>CCR</name>
          <addressOffset>0x38</addressOffset>
          <size>0x20</size>
          <fields>
            <field>
              <name>OTRIM1</name>
              <bitOffset>0</bitOffset>
              <bitWidth>5</bitWidth>
            </field>
            <field>
              <name>OTRIM2</name>
              <bitOffset>16</bitOffset>
              <bitWidth>5</bitWidth>
            </field>
          </fields>
        </register>
        <register>
          <name>MCR</name>
          <addressOffset>0x3c</addressOffset>
          <size>0x20</size>
          <fields>
            <field>
              <name>MODE1</name>
              <bitOffset>0</bitOffset>
              <bitWidth>3</bitWidth>
            </field>
            <field>
              <name>MODE2</name>
              <bitOffset>16</bitOffset>
              <bitWidth>3</bitWidth>
            </field>
          </fields>
        </register>
        <register>
          <name>SHSR1</name>
          <addressOffset>0x40</addressOffset>
          <size>0x20</size>
          <fields>
            <field>
              <name>TSAMPLE1</name>
              <bitOffset>0</bitOffset>
              <bitWidth>10</bitWidth>
            </field>
          </fields>
        </register>
        <register>
          <name>SHSR2</name>
          <addressOffset>0x44</addressOffset>
          <size>0x20</size>
          <fields>
            <field>
              <name>TSAMPLE2</name>
              <bitOffset>0</bitOffset>
              <bitWidth>10</bitWidth>
            </field>
          </fields>
        </register>
        <register>
          <name>SHHR</name>
          <addressOffset>0x48</addressOffset>
          <size>0x20</size>
          <fields>
            <field>
              <name>THOLD1</name>
              <bitOffset>0</bitOffset>
              <bitWidth>10</bitWidth>
            </field>
            <field>
              <name>THOLD2</name>
              <bitOffset>16</bitOffset>
              <bitWidth>10</bitWidth>
            </field>
          </fields>
        </register>
        <register>
          <name>SHRR</name>
          <addressOffset>0x4c</addressOffset>
          <size>0x20</size>
          <fields>
            <field>
              <name>TREFRESH1</name>
              <bitOffset>0</bitOffset>
              <bitWidth>8</bitWidth>
            </field>
            <field>
              <name>TREFRESH2</name>
              <bitOffset>16</bitOffset>
              <bitWidth>8</bitWidth>
            </field>
          </fields>
        </register>
      </registers>
    </peripheral>
    <peripheral>
      <name>DAC1</name>
      <baseAddress>0x40007400</baseAddress>
      <registers>
        <register>
          <name>CR</name>
          <addressOffset>0x0</addressOffset>
          <size>0x20</size>
          <fields>
            <field>
              <name>EN1</name>
              <bitOffset>0</bitOffset>
              <bitWidth>1</bitWidth>
            </field>
            <field>
              <name>TEN1</name>
              <bitOffset>2</bitOffset>
              <bitWidth>1</bitWidth>
            </field>
            <field>
              <name>TSEL1</name>
              <bitOffset>3</bitOffset>
              <bitWidth>3</bitWidth>
            </field>
            <field>
              <name>WAVE1</name>
              <bitOffset>6</bitOffset>
              <bitWidth>2</bitWidth>
            </field>
            <field>
              <name>MAMP1</name>
              <bitOffset>8</bitOffset>
              <bitWidth>4</bitWidth>
            </field>
            <field>
              <name>DMAEN1</name>
              <bitOffset>12</bitOffset>
              <bitWidth>1</bitWidth>
            </field>
            <field>
              <name>DMAUDRIE1</name>
              <bitOffset>13</bitOffset>
              <bitWidth>1</bitWidth>
            </field>
            <field>
              <name>CEN1</name>
              <bitOffset>14</bitOffset>
              <bitWidth>1</bitWidth>
            </field>
            <field>
              <name>EN2</name>
              <bitOffset>16</bitOffset>
              <bitWidth>1</bitWidth>
            </field>
            <field>
              <name>TEN2</name>
              <bitOffset>18</bitOffset>
              <bitWidth>1</bitWidth>
            </field>
            <field>
              <name>TSEL2</name>
              <bitOffset>19</bitOffset>
              <bitWidth>3</bitWidth>
            </field>
            <field>
              <name>WAVE2</name>
              <bitOffset>22</bitOffset>
              <bitWidth>2</bitWidth>
            </field>
            <field>
              <name>MAMP2</name>
              <bitOffset>24</bitOffset>
              <bitWidth>4</bitWidth>
            </field>
            <field>
              <name>DMAEN2</name>
              <bitOffset>28</bitOffset>
              <bitWidth>1</bitWidth>
            </field>
            <field>
              <name>DMAUDRIE2</name>
              <bitOffset>29</bitOffset>
              <bitWidth>1</bitWidth>
            </field>
            <field>
              <name>CEN2</name>
              <bitOffset>30</bitOffset>
              <bitWidth>1</bitWidth>
            </field>
          </fields>
        </register>
        <register>
          <name>SWTRIGR</name>
          <addressOffset>0x4</addressOffset>
          <size>0x20</size>
          <fields>
            <field>
              <name>SWTRIG1</name>
              <bitOffset>0</bitOffset>
              <bitWidth>1</bitWidth>
            </field>
            <field>
              <name>SWTRIG2</name>
              <bitOffset>1</bitOffset>
              <bitWidth>1</bitWidth>
            </field>
          </fields>
        </register>
        <register>
          <name>DHR12R1</name>
          <addressOffset>0x8</addressOffset>
          <size>0x20</size>
          <fields>
            <field>
              <name>DACC1DHR</name>
              <bitOffset>0</bitOffset>
              <bitWidth>12</bitWidth>
            </field>
          </fields>
        </register>
        <register>
          <name>DHR12L1</name>
          <addressOffset>0xc</addressOffset>
          <size>0x20</size>
          <fields>
            <field>
              <name>DACC1DHR</name>
              <bitOffset>4</bitOffset>
              <bitWidth>12</bitWidth>
            </field>
          </fields>
        </register>
        <register>
          <name>DHR8R1</name>
          <addressOffset>0x10</addressOffset>
          <size>0x20</size>
          <fields>
            <field>
              <name>DACC1DHR</name>
              <bitOffset>0</bitOffset>
              <bitWidth>8</bitWidth>
            </field>
          </fields>
        </register>
        <register>
          <name>DHR12R2</name>
          <addressOffset>0x14</addressOffset>
          <size>0x20</size>
          <fields>
            <field>
              <name>DACC2DHR</name>
              <bitOffset>0</bitOffset>
              <bitWidth>12</bitWidth>
            </field>
          </fields>
        </register>
        <register>
          <name>DHR12L2</name>
          <addressOffset>0x18</addressOffset>
          <size>0x20</size>
          <fields>
            <field>
              <name>DACC2DHR</name>
              <bitOffset>4</bitOffset>
              <bitWidth>12</bitWidth>
            </field>
          </fields>
        </register>
        <register>
          <name>DHR8R2</name>
          <addressOffset>0x1c</addressOffset>
          <size>0x20</size>
          <fields>
            <field>
              <name>DACC2DHR</name>
              <bitOffset>0</bitOffset>
              <bitWidth>8</bitWidth>
            </field>
          </fields>
        </register>
        <register>
          <name>DHR12RD</name>
          <addressOffset>0x20</addressOffset>
          <size>0x20</size>
          <fields>
            <field>
              <name>DACC1DHR</name>
              <bitOffset>0</bitOffset>
              <bitWidth>12</bitWidth>
            </field>
            <field>
              <name>DACC2DHR</name>
              <bitOffset>16</bitOffset>
              <bitWidth>12</bitWidth>
            </field>
          </fields>
        </register>
        <register>
          <name>DHR12LD</name>
          <addressOffset>0x24</addressOffset>
          <size>0x20</size>
          <fields>
            <field>
              <name>DACC1DHR</name>
              <bitOffset>4</bitOffset>
              <bitWidth>12</bitWidth>
            </field>
            <field>
              <name>DACC2DHR</name>
              <bitOffset>20</bitOffset>
              <bitWidth>12</bitWidth>
            </field>
          </fields>
        </register>
        <register>
          <name>DHR8RD</name>
          <addressOffset>0x28</addressOffset>
          <size>0x20</size>
          <fields>
            <field>
              <name>DACC1DHR</name>
              <bitOffset>0</bitOffset>
              <bitWidth>8</bitWidth>
            </field>
            <field>
              <name>DACC2DHR</name>
              <bitOffset>8</bitOffset>
              <bitWidth>8</bitWidth>
            </field>
          </fields>
        </register>
        <register>
          <name>DOR1</name>
          <addressOffset>0x2c</addressOffset>
          <size>0x20</size>
          <fields>
            <field>
              <name>DACC1DOR</name>
              <bitOffset>0</bitOffset>
              <bitWidth>12</bitWidth>
            </field>
          </fields>
        </register>
        <register>
          <name>DOR2</name>
          <addressOffset>0x30</addressOffset>
          <size>0x20</size>
          <fields>
            <field>
              <name>DACC2DOR</name>
              <bitOffset>0</bitOffset>
              <bitWidth>12</bitWidth>
            </field>
          </fields>
        </register>
        <register>
          <name>SR</name>
          <addressOffset>0x34</addressOffset>
          <size>0x20</size>
          <fields>
            <field>
              <name>DMAUDR1</name>
              <bitOffset>13</bitOffset>
              <bitWidth>1</bitWidth>
            </field>
            <field>
              <name>CAL_FLAG1</name>
              <bitOffset>14</bitOffset>
              <bitWidth>1</bitWidth>
            </field>
            <field>
              <name>BWST1</name>
              <bitOffset>15</bitOffset>
              <bitWidth>1</bitWidth>
            </field>
            <field>
              <name>DMAUDR2</name>
              <bitOffset>29</bitOffset>
              <bitWidth>1</bitWidth>
            </field>
            <field>
              <name>CAL_FLAG2</name>
              <bitOffset>30</bitOffset>
              <bitWidth>1</bitWidth>
            </field>
            <field>
              <name>BWST2</name>
              <bitOffset>31</bitOffset>
              <bitWidth>1</bitWidth>
            </field>
          </fields>
        </register>
        <register>
          <name>CCR</name>
          <addressOffset>0x38</addressOffset>
          <size>0x20</size>
          <fields>
            <field>
              <name>OTRIM1</name>
              <bitOffset>0</bitOffset>
              <bitWidth>5</bitWidth>
            </field>
            <field>
              <name>OTRIM2</name>
              <bitOffset>16</bitOffset>
              <bitWidth>5</bitWidth>
            </field>
          </fields>
        </register>
        <register>
          <name>MCR</name>
          <addressOffset>0x3c</addressOffset>
          <size>0x20</size>
          <fields>
            <field>
              <name>MODE1</name>
              <bitOffset>0</bitOffset>
              <bitWidth>3</bitWidth>
            </field>
            <field>
              <name>MODE2</name>
              <bitOffset>16</bitOffset>
              <bitWidth>3</bitWidth>
            </field>
          </fields>
        </register>
        <register>
          <name>SHSR1</name>
          <addressOffset>0x40</addressOffset>
          <size>0x20</size>
          <fields>
            <field>
              <name>TSAMPLE1</name>
              <bitOffset>0</bitOffset>
              <bitWidth>10</bitWidth>
            </field>
          </fields>
        </register>
        <register>
          <name>SHSR2</name>
          <addressOffset>0x44</addressOffset>
          <size>0x20</size>
          <fields>
            <field>
              <name>TSAMPLE2</name>
              <bitOffset>0</bitOffset>
              <bitWidth>10</bitWidth>
            </field>
          </fields>
        </register>
        <register>
          <name>SHHR</name>
          <addressOffset>0x48</addressOffset>
          <size>0x20</size>
          <fields>
            <field>
              <name>THOLD1</name>
              <bitOffset>0</bitOffset>
              <bitWidth>10</bitWidth>
            </field>
            <field>
              <name>THOLD2</name>
              <bitOffset>16</bitOffset>
              <bitWidth>10</bitWidth>
            </field>
          </fields>
        </register>
        <register>
          <name>SHRR</name>
          <addressOffset>0x4c</addressOffset>
          <size>0x20</size>
          <fields>
            <field>
              <name>TREFRESH1</name>
              <bitOffset>0</bitOffset>
              <bitWidth>8</bitWidth>
            </field>
            <field>
              <name>TREFRESH2</name>
              <bitOffset>16</bitOffset>
              <bitWidth>8</bitWidth>
            </field>
          </fields>
        </register>
      </registers>
    </peripheral>
    <peripheral>
      <name>OPAMP</name>
      <baseAddress>0x40007800</baseAddress>
      <registers>
        <register>
          <name>CSR</name>
          <addressOffset>0x0</addressOffset>
          <size>0x20</size>
          <fields>
            <field>
              <name>OPAMPxEN</name>
              <bitOffset>0</bitOffset>
              <bitWidth>1</bitWidth>
            </field>
            <field>
              <name>OPALPM</name>
              <bitOffset>1</bitOffset>
              <bitWidth>1</bitWidth>
            </field>
            <field>
              <name>OPAMODE</name>
              <bitOffset>2</bitOffset>
              <bitWidth>2</bitWidth>
            </field>
            <field>
              <name>PGGAIN</name>
              <bitOffset>4</bitOffset>
              <bitWidth>2</bitWidth>
            </field>
            <field>
              <name>VMSEL</name>
              <bitOffset>8</bitOffset>
              <bitWidth>2</bitWidth>
            </field>
            <field>
              <name>VPSEL</name>
              <bitOffset>10</bitOffset>
              <bitWidth>1</bitWidth>
            </field>
            <field>
              <name>CALON</name>
              <bitOffset>12</bitOffset>
              <bitWidth>1</bitWidth>
            </field>
            <field>
              <name>CALSEL</name>
              <bitOffset>13</bitOffset>
              <bitWidth>1</bitWidth>
            </field>
            <field>
              <name>USERTRIM</name>
              <bitOffset>14</bitOffset>
              <bitWidth>1</bitWidth>
            </field>
            <field>
              <name>CALOUT</name>
              <bitOffset>15</bitOffset>
              <bitWidth>1</bitWidth>
            </field>
          </fields>
        </register>
        <register>
          <name>OTR</name>
          <addressOffset>0x4</addressOffset>
          <size>0x20</size>
          <fields>
            <field>
              <name>TRIMOFFSETN</name>
              <bitOffset>0</bitOffset>
              <bitWidth>5</bitWidth>
            </field>
            <field>
              <name>TRIMOFFSETP</name>
              <bitOffset>8</bitOffset>
              <bitWidth>5</bitWidth>
            </field>
          </fields>
        </register>
        <register>
          <name>LPOTR</name>
          <addressOffset>0x8</addressOffset>
          <size>0x20</size>
          <fields>
            <field>
              <name>TRIMLPOFFSETN</name>
              <bitOffset>0</bitOffset>
              <bitWidth>5</bitWidth>
            </field>
            <field>
              <name>TRIMLPOFFSETP</name>
              <bitOffset>8</bitOffset>
              <bitWidth>5</bitWidth>
            </field>
          </fields>
        </register>
      </registers>
    </peripheral>
    <peripheral>
      <name>OPAMP1</name>
      <baseAddress>0x40007800</baseAddress>
      <registers>
        <register>
          <name>CSR</name>
          <addressOffset>0x0</addressOffset>
          <size>0x20</size>
          <fields>
            <field>
              <name>OPAMPxEN</name>
              <bitOffset>0</bitOffset>
              <bitWidth>1</bitWidth>
            </field>
            <field>
              <name>OPALPM</name>
              <bitOffset>1</bitOffset>
              <bitWidth>1</bitWidth>
            </field>
            <field>
              <name>OPAMODE</name>
              <bitOffset>2</bitOffset>
              <bitWidth>2</bitWidth>
            </field>
            <field>
              <name>PGGAIN</name>
              <bitOffset>4</bitOffset>
              <bitWidth>2</bitWidth>
            </field>
            <field>
              <name>VMSEL</name>
              <bitOffset>8</bitOffset>
              <bitWidth>2</bitWidth>
            </field>
            <field>
              <name>VPSEL</name>
              <bitOffset>10</bitOffset>
              <bitWidth>1</bitWidth>
            </field>
            <field>
              <name>CALON</name>
              <bitOffset>12</bitOffset>
              <bitWidth>1</bitWidth>
            </field>
            <field>
              <name>CALSEL</name>
              <bitOffset>13</bitOffset>
              <bitWidth>1</bitWidth>
            </field>
            <field>
              <name>USERTRIM</name>
              <bitOffset>14</bitOffset>
              <bitWidth>1</bitWidth>
            </field>
            <field>
              <name>CALOUT</name>
              <bitOffset>15</bitOffset>
              <bitWidth>1</bitWidth>
            </field>
          </fields>
        </register>
        <register>
          <name>OTR</name>
          <addressOffset>0x4</addressOffset>
          <size>0x20</size>
          <fields>
            <field>
              <name>TRIMOFFSETN</name>
              <bitOffset>0</bitOffset>
              <bitWidth>5</bitWidth>
            </field>
            <field>
              <name>TRIMOFFSETP</name>
              <bitOffset>8</bitOffset>
              <bitWidth>5</bitWidth>
            </field>
          </fields>
        </register>
        <register>
          <name>LPOTR</name>
          <addressOffset>0x8</addressOffset>
          <size>0x20</size>
          <fields>
            <field>
              <name>TRIMLPOFFSETN</name>
              <bitOffset>0</bitOffset>
              <bitWidth>5</bitWidth>
            </field>
            <field>
              <name>TRIMLPOFFSETP</name>
              <bitOffset>8</bitOffset>
              <bitWidth>5</bitWidth>
            </field>
          </fields>
        </register>
      </registers>
    </peripheral>
    <peripheral>
      <name>OPAMP1_COMMON</name>
      <baseAddress>0x40007800</baseAddress>
      <registers>
        <register>
          <name>CSR</name>
          <addressOffset>0x0</addressOffset>
          <size>0x20</size>
          <fields>
            <field>
              <name>OPAMPxEN</name>
              <bitOffset>0</bitOffset>
              <bitWidth>1</bitWidth>
            </field>
            <field>
              <name>OPALPM</name>
              <bitOffset>1</bitOffset>
              <bitWidth>1</bitWidth>
            </field>
            <field>
              <name>OPAMODE</name>
              <bitOffset>2</bitOffset>
              <bitWidth>2</bitWidth>
            </field>
            <field>
              <name>PGGAIN</name>
              <bitOffset>4</bitOffset>
              <bitWidth>2</bitWidth>
            </field>
            <field>
              <name>VMSEL</name>
              <bitOffset>8</bitOffset>
              <bitWidth>2</bitWidth>
            </field>
            <field>
              <name>VPSEL</name>
              <bitOffset>10</bitOffset>
              <bitWidth>1</bitWidth>
            </field>
            <field>
              <name>CALON</name>
              <bitOffset>12</bitOffset>
              <bitWidth>1</bitWidth>
            </field>
            <field>
              <name>CALSEL</name>
              <bitOffset>13</bitOffset>
              <bitWidth>1</bitWidth>
            </field>
            <field>
              <name>USERTRIM</name>
              <bitOffset>14</bitOffset>
              <bitWidth>1</bitWidth>
            </field>
            <field>
              <name>CALOUT</name>
              <bitOffset>15</bitOffset>
              <bitWidth>1</bitWidth>
            </field>
          </fields>
        </register>
      </registers>
    </peripheral>
    <peripheral>
      <name>LPTIM1</name>
      <baseAddress>0x40007c00</baseAddress>
      <registers>
        <register>
          <name>ISR</name>
          <addressOffset>0x0</addressOffset>
          <size>0x20</size>
          <fields>
            <field>
              <name>CMPM</name>
              <bitOffset>0</bitOffset>
              <bitWidth>1</bitWidth>
            </field>
            <field>
              <name>ARRM</name>
              <bitOffset>1</bitOffset>
              <bitWidth>1</bitWidth>
            </field>
            <field>
              <name>EXTTRIG</name>
              <bitOffset>2</bitOffset>
              <bitWidth>1</bitWidth>
            </field>
            <field>
              <name>CMPOK</name>
              <bitOffset>3</bitOffset>
              <bitWidth>1</bitWidth>
            </field>
            <field>
              <name>ARROK</name>
              <bitOffset>4</bitOffset>
              <bitWidth>1</bitWidth>
            </field>
            <field>
              <name>UP</name>
              <bitOffset>5</bitOffset>
              <bitWidth>1</bitWidth>
            </field>
            <field>
              <name>DOWN</name>
              <bitOffset>6</bitOffset>
              <bitWidth>1</bitWidth>
            </field>
          </fields>
        </register>
        <register>
          <name>ICR</name>
          <addressOffset>0x4</addressOffset>
          <size>0x20</size>
          <fields>
            <field>
              <name>CMPMCF</name>
              <bitOffset>0</bitOffset>
              <bitWidth>1</bitWidth>
            </field>
            <field>
              <name>ARRMCF</name>
              <bitOffset>1</bitOffset>
              <bitWidth>1</bitWidth>
            </field>
            <field>
              <name>EXTTRIGCF</name>
              <bitOffset>2</bitOffset>
              <bitWidth>1</bitWidth>
            </field>
            <field>
              <name>CMPOKCF</name>
              <bitOffset>3</bitOffset>
              <bitWidth>1</bitWidth>
            </field>
            <field>
              <name>ARROKCF</name>
              <bitOffset>4</bitOffset>
              <bitWidth>1</bitWidth>
            </field>
            <field>
              <name>UPCF</name>
              <bitOffset>5</bitOffset>
              <bitWidth>1</bitWidth>
            </field>
            <field>
              <name>DOWNCF</name>
              <bitOffset>6</bitOffset>
              <bitWidth>1</bitWidth>
            </field>
          </fields>
        </register>
        <register>
          <name>IER</name>
          <addressOffset>0x8</addressOffset>
          <size>0x20</size>
          <fields>
            <field>
              <name>CMPMIE</name>
              <bitOffset>0</bitOffset>
              <bitWidth>1</bitWidth>
            </field>
            <field>
              <name>ARRMIE</name>
              <bitOffset>1</bitOffset>
              <bitWidth>1</bitWidth>
            </field>
            <field>
              <name>EXTTRIGIE</name>
              <bitOffset>2</bitOffset>
              <bitWidth>1</bitWidth>
            </field>
            <field>
              <name>CMPOKIE</name>
              <bitOffset>3</bitOffset>
              <bitWidth>1</bitWidth>
            </field>
            <field>
              <name>ARROKIE</name>
              <bitOffset>4</bitOffset>
              <bitWidth>1</bitWidth>
            </field>
            <field>
              <name>UPIE</name>
              <bitOffset>5</bitOffset>
              <bitWidth>1</bitWidth>
            </field>
            <field>
              <name>DOWNIE</name>
              <bitOffset>6</bitOffset>
              <bitWidth>1</bitWidth>
            </field>
          </fields>
        </register>
        <register>
          <name>CFGR</name>
          <addressOffset>0xc</addressOffset>
          <size>0x20</size>
          <fields>
            <field>
              <name>CKSEL</name>
              <bitOffset>0</bitOffset>
              <bitWidth>1</bitWidth>
            </field>
            <field>
              <name>CKPOL</name>
              <bitOffset>1</bitOffset>
              <bitWidth>2</bitWidth>
            </field>
            <field>
              <name>CKFLT</name>
              <bitOffset>3</bitOffset>
              <bitWidth>2</bitWidth>
            </field>
            <field>
              <name>TRGFLT</name>
              <bitOffset>6</bitOffset>
              <bitWidth>2</bitWidth>
            </field>
            <field>
              <name>PRESC</name>
              <bitOffset>9</bitOffset>
              <bitWidth>3</bitWidth>
            </field>
            <field>
              <name>TRIGSEL</name>
              <bitOffset>13</bitOffset>
              <bitWidth>3</bitWidth>
            </field>
            <field>
              <name>TRIGEN</name>
              <bitOffset>17</bitOffset>
              <bitWidth>2</bitWidth>
            </field>
            <field>
              <name>TIMOUT</name>
              <bitOffset>19</bitOffset>
              <bitWidth>1</bitWidth>
            </field>
            <field>
              <name>WAVE</name>
              <bitOffset>20</bitOffset>
              <bitWidth>1</bitWidth>
            </field>
            <field>
              <name>WAVPOL</name>
              <bitOffset>21</bitOffset>
              <bitWidth>1</bitWidth>
            </field>
            <field>
              <name>PRELOAD</name>
              <bitOffset>22</bitOffset>
              <bitWidth>1</bitWidth>
            </field>
            <field>
              <name>COUNTMODE</name>
              <bitOffset>23</bitOffset>
              <bitWidth>1</bitWidth>
            </field>
            <field>
              <name>ENC</name>
              <bitOffset>24</bitOffset>
              <bitWidth>1</bitWidth>
            </field>
          </fields>
        </register>
        <register>
          <name>CR</name>
          <addressOffset>0x10</addressOffset>
          <size>0x20</size>
          <fields>
            <field>
              <name>ENABLE</name>
              <bitOffset>0</bitOffset>
              <bitWidth>1</bitWidth>
            </field>
            <field>
              <name>SNGSTRT</name>
              <bitOffset>1</bitOffset>
              <bitWidth>1</bitWidth>
            </field>
            <field>
              <name>CNTSTRT</name>
              <bitOffset>2</bitOffset>
              <bitWidth>1</bitWidth>
            </field>
          </fields>
        </register>
        <register>
          <name>CMP</name>
          <addressOffset>0x14</addressOffset>
          <size>0x20</size>
          <fields>
            <field>
              <name>CMP</name>
              <bitOffset>0</bitOffset>
              <bitWidth>16</bitWidth>
            </field>
          </fields>
        </register>
        <register>
          <name>ARR</name>
          <addressOffset>0x18</addressOffset>
          <size>0x20</size>
          <fields>
            <field>
              <name>ARR</name>
              <bitOffset>0</bitOffset>
              <bitWidth>16</bitWidth>
            </field>
          </fields>
        </register>
        <register>
          <name>CNT</name>
          <addressOffset>0x1c</addressOffset>
          <size>0x20</size>
          <fields>
            <field>
              <name>CNT</name>
              <bitOffset>0</bitOffset>
              <bitWidth>16</bitWidth>
            </field>
          </fields>
        </register>
        <register>
          <name>OR</name>
          <addressOffset>0x20</addressOffset>
          <size>0x20</size>
          <fields>
            <field>
              <name>OR</name>
              <bitOffset>0</bitOffset>
              <bitWidth>2</bitWidth>
            </field>
          </fields>
        </register>
      </registers>
    </peripheral>
    <peripheral>
      <name>LPUART1</name>
      <baseAddress>0x40008000</baseAddress>
      <registers>
        <register>
          <name>CR1</name>
          <addressOffset>0x0</addressOffset>
          <size>0x20</size>
          <fields>
            <field>
              <name>UE</name>
              <bitOffset>0</bitOffset>
              <bitWidth>1</bitWidth>
            </field>
            <field>
              <name>UESM</name>
              <bitOffset>1</bitOffset>
              <bitWidth>1</bitWidth>
            </field>
            <field>
              <name>RE</name>
              <bitOffset>2</bitOffset>
              <bitWidth>1</bitWidth>
            </field>
            <field>
              <name>TE</name>
              <bitOffset>3</bitOffset>
              <bitWidth>1</bitWidth>
            </field>
            <field>
              <name>IDLEIE</name>
              <bitOffset>4</bitOffset>
              <bitWidth>1</bitWidth>
            </field>
            <field>
              <name>RXNEIE</name>
              <bitOffset>5</bitOffset>
              <bitWidth>1</bitWidth>
            </field>
            <field>
              <name>TCIE</name>
              <bitOffset>6</bitOffset>
              <bitWidth>1</bitWidth>
            </field>
            <field>
              <name>TXEIE</name>
              <bitOffset>7</bitOffset>
              <bitWidth>1</bitWidth>
            </field>
            <field>
              <name>PEIE</name>
              <bitOffset>8</bitOffset>
              <bitWidth>1</bitWidth>
            </field>
            <field>
              <name>PS</name>
              <bitOffset>9</bitOffset>
              <bitWidth>1</bitWidth>
            </field>
            <field>
              <name>PCE</name>
              <bitOffset>10</bitOffset>
              <bitWidth>1</bitWidth>
            </field>
            <field>
              <name>WAKE</name>
              <bitOffset>11</bitOffset>
              <bitWidth>1</bitWidth>
            </field>
            <field>
              <name>M0</name>
              <bitOffset>12</bitOffset>
              <bitWidth>1</bitWidth>
            </field>
            <field>
              <name>MME</name>
              <bitOffset>13</bitOffset>
              <bitWidth>1</bitWidth>
            </field>
            <field>
              <name>CMIE</name>
              <bitOffset>14</bitOffset>
              <bitWidth>1</bitWidth>
            </field>
            <field>
              <name>OVER8</name>
              <bitOffset>15</bitOffset>
              <bitWidth>1</bitWidth>
            </field>
            <field>
              <name>DEDT</name>
              <bitOffset>16</bitOffset>
              <bitWidth>5</bitWidth>
            </field>
            <field>
              <name>DEAT</name>
              <bitOffset>21</bitOffset>
              <bitWidth>5</bitWidth>
            </field>
            <field>
              <name>RTOIE</name>
              <bitOffset>26</bitOffset>
              <bitWidth>1</bitWidth>
            </field>
            <field>
              <name>EOBIE</name>
              <bitOffset>27</bitOffset>
              <bitWidth>1</bitWidth>
            </field>
            <field>
              <name>M1</name>
              <bitOffset>28</bitOffset>
              <bitWidth>1</bitWidth>
            </field>
          </fields>
        </register>
        <register>
          <name>CR2</name>
          <addressOffset>0x4</addressOffset>
          <size>0x20</size>
          <fields>
            <field>
              <name>ADDM7</name>
              <bitOffset>4</bitOffset>
              <bitWidth>1</bitWidth>
            </field>
            <field>
              <name>LBDL</name>
              <bitOffset>5</bitOffset>
              <bitWidth>1</bitWidth>
            </field>
            <field>
              <name>LBDIE</name>
              <bitOffset>6</bitOffset>
              <bitWidth>1</bitWidth>
            </field>
            <field>
              <name>LBCL</name>
              <bitOffset>8</bitOffset>
              <bitWidth>1</bitWidth>
            </field>
            <field>
              <name>CPHA</name>
              <bitOffset>9</bitOffset>
              <bitWidth>1</bitWidth>
            </field>
            <field>
              <name>CPOL</name>
              <bitOffset>10</bitOffset>
              <bitWidth>1</bitWidth>
            </field>
            <field>
              <name>CLKEN</name>
              <bitOffset>11</bitOffset>
              <bitWidth>1</bitWidth>
            </field>
            <field>
              <name>STOP</name>
              <bitOffset>12</bitOffset>
              <bitWidth>2</bitWidth>
            </field>
            <field>
              <name>LINEN</name>
              <bitOffset>14</bitOffset>
              <bitWidth>1</bitWidth>
            </field>
            <field>
              <name>SWAP</name>
              <bitOffset>15</bitOffset>
              <bitWidth>1</bitWidth>
            </field>
            <field>
              <name>RXINV</name>
              <bitOffset>16</bitOffset>
              <bitWidth>1</bitWidth>
            </field>
            <field>
              <name>TXINV</name>
              <bitOffset>17</bitOffset>
              <bitWidth>1</bitWidth>
            </field>
            <field>
              <name>DATAINV</name>
              <bitOffset>18</bitOffset>
              <bitWidth>1</bitWidth>
            </field>
            <field>
              <name>MSBFIRST</name>
              <bitOffset>19</bitOffset>
              <bitWidth>1</bitWidth>
            </field>
            <field>
              <name>ABREN</name>
              <bitOffset>20</bitOffset>
              <bitWidth>1</bitWidth>
            </field>
            <field>
              <name>ABRMODE</name>
              <bitOffset>21</bitOffset>
              <bitWidth>2</bitWidth>
            </field>
            <field>
              <name>RTOEN</name>
              <bitOffset>23</bitOffset>
              <bitWidth>1</bitWidth>
            </field>
            <field>
              <name>ADD</name>
              <bitOffset>24</bitOffset>
              <bitWidth>8</bitWidth>
            </field>
          </fields>
        </register>
        <register>
          <name>CR3</name>
          <addressOffset>0x8</addressOffset>
          <size>0x20</size>
          <fields>
            <field>
              <name>EIE</name>
              <bitOffset>0</bitOffset>
              <bitWidth>1</bitWidth>
            </field>
            <field>
              <name>IREN</name>
              <bitOffset>1</bitOffset>
              <bitWidth>1</bitWidth>
            </field>
            <field>
              <name>IRLP</name>
              <bitOffset>2</bitOffset>
              <bitWidth>1</bitWidth>
            </field>
            <field>
              <name>HDSEL</name>
              <bitOffset>3</bitOffset>
              <bitWidth>1</bitWidth>
            </field>
            <field>
              <name>NACK</name>
              <bitOffset>4</bitOffset>
              <bitWidth>1</bitWidth>
            </field>
            <field>
              <name>SCEN</name>
              <bitOffset>5</bitOffset>
              <bitWidth>1</bitWidth>
            </field>
            <field>
              <name>DMAR</name>
              <bitOffset>6</bitOffset>
              <bitWidth>1</bitWidth>
            </field>
            <field>
              <name>DMAT</name>
              <bitOffset>7</bitOffset>
              <bitWidth>1</bitWidth>
            </field>
            <field>
              <name>RTSE</name>
              <bitOffset>8</bitOffset>
              <bitWidth>1</bitWidth>
            </field>
            <field>
              <name>CTSE</name>
              <bitOffset>9</bitOffset>
              <bitWidth>1</bitWidth>
            </field>
            <field>
              <name>CTSIE</name>
              <bitOffset>10</bitOffset>
              <bitWidth>1</bitWidth>
            </field>
            <field>
              <name>ONEBIT</name>
              <bitOffset>11</bitOffset>
              <bitWidth>1</bitWidth>
            </field>
            <field>
              <name>OVRDIS</name>
              <bitOffset>12</bitOffset>
              <bitWidth>1</bitWidth>
            </field>
            <field>
              <name>DDRE</name>
              <bitOffset>13</bitOffset>
              <bitWidth>1</bitWidth>
            </field>
            <field>
              <name>DEM</name>
              <bitOffset>14</bitOffset>
              <bitWidth>1</bitWidth>
            </field>
            <field>
              <name>DEP</name>
              <bitOffset>15</bitOffset>
              <bitWidth>1</bitWidth>
            </field>
            <field>
              <name>SCARCNT</name>
              <bitOffset>17</bitOffset>
              <bitWidth>3</bitWidth>
            </field>
            <field>
              <name>WUS</name>
              <bitOffset>20</bitOffset>
              <bitWidth>2</bitWidth>
            </field>
            <field>
              <name>WUFIE</name>
              <bitOffset>22</bitOffset>
              <bitWidth>1</bitWidth>
            </field>
            <field>
              <name>UCESM</name>
              <bitOffset>23</bitOffset>
              <bitWidth>1</bitWidth>
            </field>
            <field>
              <name>TCBGTIE</name>
              <bitOffset>24</bitOffset>
              <bitWidth>1</bitWidth>
            </field>
          </fields>
        </register>
        <register>
          <name>BRR</name>
          <addressOffset>0xc</addressOffset>
          <size>0x20</size>
          <fields>
            <field>
              <name>DIV_FRACTION</name>
              <bitOffset>0</bitOffset>
              <bitWidth>4</bitWidth>
            </field>
            <field>
              <name>DIV_MANTISSA</name>
              <bitOffset>4</bitOffset>
              <bitWidth>12</bitWidth>
            </field>
          </fields>
        </register>
        <register>
          <name>GTPR</name>
          <addressOffset>0x10</addressOffset>
          <size>0x10</size>
          <fields>
            <field>
              <name>PSC</name>
              <bitOffset>0</bitOffset>
              <bitWidth>8</bitWidth>
            </field>
            <field>
              <name>GT</name>
              <bitOffset>8</bitOffset>
              <bitWidth>8</bitWidth>
            </field>
          </fields>
        </register>
        <register>
          <name>RTOR</name>
          <addressOffset>0x14</addressOffset>
          <size>0x20</size>
          <fields>
            <field>
              <name>RTO</name>
              <bitOffset>0</bitOffset>
              <bitWidth>24</bitWidth>
            </field>
            <field>
              <name>BLEN</name>
              <bitOffset>24</bitOffset>
              <bitWidth>8</bitWidth>
            </field>
          </fields>
        </register>
        <register>
          <name>RQR</name>
          <addressOffset>0x18</addressOffset>
          <size>0x10</size>
          <fields>
            <field>
              <name>ABRRQ</name>
              <bitOffset>0</bitOffset>
              <bitWidth>1</bitWidth>
            </field>
            <field>
              <name>SBKRQ</name>
              <bitOffset>1</bitOffset>
              <bitWidth>1</bitWidth>
            </field>
            <field>
              <name>MMRQ</name>
              <bitOffset>2</bitOffset>
              <bitWidth>1</bitWidth>
            </field>
            <field>
              <name>RXFRQ</name>
              <bitOffset>3</bitOffset>
              <bitWidth>1</bitWidth>
            </field>
            <field>
              <name>TXFRQ</name>
              <bitOffset>4</bitOffset>
              <bitWidth>1</bitWidth>
            </field>
          </fields>
        </register>
        <register>
          <name>ISR</name>
          <addressOffset>0x1c</addressOffset>
          <size>0x20</size>
          <fields>
            <field>
              <name>PE</name>
              <bitOffset>0</bitOffset>
              <bitWidth>1</bitWidth>
            </field>
            <field>
              <name>FE</name>
              <bitOffset>1</bitOffset>
              <bitWidth>1</bitWidth>
            </field>
            <field>
              <name>NE</name>
              <bitOffset>2</bitOffset>
              <bitWidth>1</bitWidth>
            </field>
            <field>
              <name>ORE</name>
              <bitOffset>3</bitOffset>
              <bitWidth>1</bitWidth>
            </field>
            <field>
              <name>IDLE</name>
              <bitOffset>4</bitOffset>
              <bitWidth>1</bitWidth>
            </field>
            <field>
              <name>RXNE</name>
              <bitOffset>5</bitOffset>
              <bitWidth>1</bitWidth>
            </field>
            <field>
              <name>TC</name>
              <bitOffset>6</bitOffset>
              <bitWidth>1</bitWidth>
            </field>
            <field>
              <name>TXE</name>
              <bitOffset>7</bitOffset>
              <bitWidth>1</bitWidth>
            </field>
            <field>
              <name>LBDF</name>
              <bitOffset>8</bitOffset>
              <bitWidth>1</bitWidth>
            </field>
            <field>
              <name>CTSIF</name>
              <bitOffset>9</bitOffset>
              <bitWidth>1</bitWidth>
            </field>
            <field>
              <name>CTS</name>
              <bitOffset>10</bitOffset>
              <bitWidth>1</bitWidth>
            </field>
            <field>
              <name>RTOF</name>
              <bitOffset>11</bitOffset>
              <bitWidth>1</bitWidth>
            </field>
            <field>
              <name>EOBF</name>
              <bitOffset>12</bitOffset>
              <bitWidth>1</bitWidth>
            </field>
            <field>
              <name>ABRE</name>
              <bitOffset>14</bitOffset>
              <bitWidth>1</bitWidth>
            </field>
            <field>
              <name>ABRF</name>
              <bitOffset>15</bitOffset>
              <bitWidth>1</bitWidth>
            </field>
            <field>
              <name>BUSY</name>
              <bitOffset>16</bitOffset>
              <bitWidth>1</bitWidth>
            </field>
            <field>
              <name>CMF</name>
              <bitOffset>17</bitOffset>
              <bitWidth>1</bitWidth>
            </field>
            <field>
              <name>SBKF</name>
              <bitOffset>18</bitOffset>
              <bitWidth>1</bitWidth>
            </field>
            <field>
              <name>RWU</name>
              <bitOffset>19</bitOffset>
              <bitWidth>1</bitWidth>
            </field>
            <field>
              <name>WUF</name>
              <bitOffset>20</bitOffset>
              <bitWidth>1</bitWidth>
            </field>
            <field>
              <name>TEACK</name>
              <bitOffset>21</bitOffset>
              <bitWidth>1</bitWidth>
            </field>
            <field>
              <name>REACK</name>
              <bitOffset>22</bitOffset>
              <bitWidth>1</bitWidth>
            </field>
            <field>
              <name>TCBGT</name>
              <bitOffset>25</bitOffset>
              <bitWidth>1</bitWidth>
            </field>
          </fields>
        </register>
        <register>
          <name>ICR</name>
          <addressOffset>0x20</addressOffset>
          <size>0x20</size>
          <fields>
            <field>
              <name>PECF</name>
              <bitOffset>0</bitOffset>
              <bitWidth>1</bitWidth>
            </field>
            <field>
              <name>FECF</name>
              <bitOffset>1</bitOffset>
              <bitWidth>1</bitWidth>
            </field>
            <field>
              <name>NECF</name>
              <bitOffset>2</bitOffset>
              <bitWidth>1</bitWidth>
            </field>
            <field>
              <name>ORECF</name>
              <bitOffset>3</bitOffset>
              <bitWidth>1</bitWidth>
            </field>
            <field>
              <name>IDLECF</name>
              <bitOffset>4</bitOffset>
              <bitWidth>1</bitWidth>
            </field>
            <field>
              <name>TCCF</name>
              <bitOffset>6</bitOffset>
              <bitWidth>1</bitWidth>
            </field>
            <field>
              <name>TCBGTCF</name>
              <bitOffset>7</bitOffset>
              <bitWidth>1</bitWidth>
            </field>
            <field>
              <name>LBDCF</name>
              <bitOffset>8</bitOffset>
              <bitWidth>1</bitWidth>
            </field>
            <field>
              <name>CTSCF</name>
              <bitOffset>9</bitOffset>
              <bitWidth>1</bitWidth>
            </field>
            <field>
              <name>RTOCF</name>
              <bitOffset>11</bitOffset>
              <bitWidth>1</bitWidth>
            </field>
            <field>
              <name>EOBCF</name>
              <bitOffset>12</bitOffset>
              <bitWidth>1</bitWidth>
            </field>
            <field>
              <name>CMCF</name>
              <bitOffset>17</bitOffset>
              <bitWidth>1</bitWidth>
            </field>
            <field>
              <name>WUCF</name>
              <bitOffset>20</bitOffset>
              <bitWidth>1</bitWidth>
            </field>
          </fields>
        </register>
        <register>
          <name>RDR</name>
          <addressOffset>0x24</addressOffset>
          <size>0x10</size>
          <fields>
            <field>
              <name>RDR</name>
              <bitOffset>0</bitOffset>
              <bitWidth>9</bitWidth>
            </field>
          </fields>
        </register>
        <register>
          <name>TDR</name>
          <addressOffset>0x28</addressOffset>
          <size>0x10</size>
          <fields>
            <field>
              <name>TDR</name>
              <bitOffset>0</bitOffset>
              <bitWidth>9</bitWidth>
            </field>
          </fields>
        </register>
      </registers>
    </peripheral>
    <peripheral>
      <name>SWPMI1</name>
      <baseAddress>0x40008800</baseAddress>
      <registers>
        <register>
          <name>CR</name>
          <addressOffset>0x0</addressOffset>
          <size>0x20</size>
          <fields>
            <field>
              <name>RXDMA</name>
              <bitOffset>0</bitOffset>
              <bitWidth>1</bitWidth>
            </field>
            <field>
              <name>TXDMA</name>
              <bitOffset>1</bitOffset>
              <bitWidth>1</bitWidth>
            </field>
            <field>
              <name>RXMODE</name>
              <bitOffset>2</bitOffset>
              <bitWidth>1</bitWidth>
            </field>
            <field>
              <name>TXMODE</name>
              <bitOffset>3</bitOffset>
              <bitWidth>1</bitWidth>
            </field>
            <field>
              <name>LPBK</name>
              <bitOffset>4</bitOffset>
              <bitWidth>1</bitWidth>
            </field>
            <field>
              <name>SWPACT</name>
              <bitOffset>5</bitOffset>
              <bitWidth>1</bitWidth>
            </field>
            <field>
              <name>DEACT</name>
              <bitOffset>10</bitOffset>
              <bitWidth>1</bitWidth>
            </field>
          </fields>
        </register>
        <register>
          <name>BRR</name>
          <addressOffset>0x4</addressOffset>
          <size>0x20</size>
          <fields>
            <field>
              <name>BR</name>
              <bitOffset>0</bitOffset>
              <bitWidth>6</bitWidth>
            </field>
          </fields>
        </register>
        <register>
          <name>ISR</name>
          <addressOffset>0xc</addressOffset>
          <size>0x20</size>
          <fields>
            <field>
              <name>RXBFF</name>
              <bitOffset>0</bitOffset>
              <bitWidth>1</bitWidth>
            </field>
            <field>
              <name>TXBEF</name>
              <bitOffset>1</bitOffset>
              <bitWidth>1</bitWidth>
            </field>
            <field>
              <name>RXBERF</name>
              <bitOffset>2</bitOffset>
              <bitWidth>1</bitWidth>
            </field>
            <field>
              <name>RXOVRF</name>
              <bitOffset>3</bitOffset>
              <bitWidth>1</bitWidth>
            </field>
            <field>
              <name>TXUNRF</name>
              <bitOffset>4</bitOffset>
              <bitWidth>1</bitWidth>
            </field>
            <field>
              <name>RXNE</name>
              <bitOffset>5</bitOffset>
              <bitWidth>1</bitWidth>
            </field>
            <field>
              <name>TXE</name>
              <bitOffset>6</bitOffset>
              <bitWidth>1</bitWidth>
            </field>
            <field>
              <name>TCF</name>
              <bitOffset>7</bitOffset>
              <bitWidth>1</bitWidth>
            </field>
            <field>
              <name>SRF</name>
              <bitOffset>8</bitOffset>
              <bitWidth>1</bitWidth>
            </field>
            <field>
              <name>SUSP</name>
              <bitOffset>9</bitOffset>
              <bitWidth>1</bitWidth>
            </field>
            <field>
              <name>DEACTF</name>
              <bitOffset>10</bitOffset>
              <bitWidth>1</bitWidth>
            </field>
          </fields>
        </register>
        <register>
          <name>ICR</name>
          <addressOffset>0x10</addressOffset>
          <size>0x20</size>
          <fields>
            <field>
              <name>CRXBFF</name>
              <bitOffset>0</bitOffset>
              <bitWidth>1</bitWidth>
            </field>
            <field>
              <name>CTXBEF</name>
              <bitOffset>1</bitOffset>
              <bitWidth>1</bitWidth>
            </field>
            <field>
              <name>CRXBERF</name>
              <bitOffset>2</bitOffset>
              <bitWidth>1</bitWidth>
            </field>
            <field>
              <name>CRXOVRF</name>
              <bitOffset>3</bitOffset>
              <bitWidth>1</bitWidth>
            </field>
            <field>
              <name>CTXUNRF</name>
              <bitOffset>4</bitOffset>
              <bitWidth>1</bitWidth>
            </field>
            <field>
              <name>CTCF</name>
              <bitOffset>7</bitOffset>
              <bitWidth>1</bitWidth>
            </field>
            <field>
              <name>CSRF</name>
              <bitOffset>8</bitOffset>
              <bitWidth>1</bitWidth>
            </field>
          </fields>
        </register>
        <register>
          <name>IER</name>
          <addressOffset>0x14</addressOffset>
          <size>0x20</size>
          <fields>
            <field>
              <name>RXBFIE</name>
              <bitOffset>0</bitOffset>
              <bitWidth>1</bitWidth>
            </field>
            <field>
              <name>TXBEIE</name>
              <bitOffset>1</bitOffset>
              <bitWidth>1</bitWidth>
            </field>
            <field>
              <name>RXBERIE</name>
              <bitOffset>2</bitOffset>
              <bitWidth>1</bitWidth>
            </field>
            <field>
              <name>RXOVRIE</name>
              <bitOffset>3</bitOffset>
              <bitWidth>1</bitWidth>
            </field>
            <field>
              <name>TXUNRIE</name>
              <bitOffset>4</bitOffset>
              <bitWidth>1</bitWidth>
            </field>
            <field>
              <name>RIE</name>
              <bitOffset>5</bitOffset>
              <bitWidth>1</bitWidth>
            </field>
            <field>
              <name>TIE</name>
              <bitOffset>6</bitOffset>
              <bitWidth>1</bitWidth>
            </field>
            <field>
              <name>TCIE</name>
              <bitOffset>7</bitOffset>
              <bitWidth>1</bitWidth>
            </field>
            <field>
              <name>SRIE</name>
              <bitOffset>8</bitOffset>
              <bitWidth>1</bitWidth>
            </field>
          </fields>
        </register>
        <register>
          <name>RFL</name>
          <addressOffset>0x18</addressOffset>
          <size>0x20</size>
          <fields>
            <field>
              <name>RFL_0_1</name>
              <bitOffset>0</bitOffset>
              <bitWidth>2</bitWidth>
            </field>
          </fields>
        </register>
        <register>
          <name>TDR</name>
          <addressOffset>0x1c</addressOffset>
          <size>0x20</size>
          <fields>
            <field>
              <name>TD</name>
              <bitOffset>0</bitOffset>
              <bitWidth>32</bitWidth>
            </field>
          </fields>
        </register>
        <register>
          <name>RDR</name>
          <addressOffset>0x20</addressOffset>
          <size>0x20</size>
          <fields>
            <field>
              <name>RD</name>
              <bitOffset>0</bitOffset>
              <bitWidth>32</bitWidth>
            </field>
          </fields>
        </register>
        <register>
          <name>OR</name>
          <addressOffset>0x24</addressOffset>
          <size>0x20</size>
          <fields>
            <field>
              <name>TBYP</name>
              <bitOffset>0</bitOffset>
              <bitWidth>1</bitWidth>
            </field>
            <field>
              <name>CLASS</name>
              <bitOffset>1</bitOffset>
              <bitWidth>1</bitWidth>
            </field>
          </fields>
        </register>
      </registers>
    </peripheral>
    <peripheral>
      <name>LPTIM2</name>
      <baseAddress>0x40009400</baseAddress>
      <registers>
        <register>
          <name>ISR</name>
          <addressOffset>0x0</addressOffset>
          <size>0x20</size>
          <fields>
            <field>
              <name>CMPM</name>
              <bitOffset>0</bitOffset>
              <bitWidth>1</bitWidth>
            </field>
            <field>
              <name>ARRM</name>
              <bitOffset>1</bitOffset>
              <bitWidth>1</bitWidth>
            </field>
            <field>
              <name>EXTTRIG</name>
              <bitOffset>2</bitOffset>
              <bitWidth>1</bitWidth>
            </field>
            <field>
              <name>CMPOK</name>
              <bitOffset>3</bitOffset>
              <bitWidth>1</bitWidth>
            </field>
            <field>
              <name>ARROK</name>
              <bitOffset>4</bitOffset>
              <bitWidth>1</bitWidth>
            </field>
            <field>
              <name>UP</name>
              <bitOffset>5</bitOffset>
              <bitWidth>1</bitWidth>
            </field>
            <field>
              <name>DOWN</name>
              <bitOffset>6</bitOffset>
              <bitWidth>1</bitWidth>
            </field>
          </fields>
        </register>
        <register>
          <name>ICR</name>
          <addressOffset>0x4</addressOffset>
          <size>0x20</size>
          <fields>
            <field>
              <name>CMPMCF</name>
              <bitOffset>0</bitOffset>
              <bitWidth>1</bitWidth>
            </field>
            <field>
              <name>ARRMCF</name>
              <bitOffset>1</bitOffset>
              <bitWidth>1</bitWidth>
            </field>
            <field>
              <name>EXTTRIGCF</name>
              <bitOffset>2</bitOffset>
              <bitWidth>1</bitWidth>
            </field>
            <field>
              <name>CMPOKCF</name>
              <bitOffset>3</bitOffset>
              <bitWidth>1</bitWidth>
            </field>
            <field>
              <name>ARROKCF</name>
              <bitOffset>4</bitOffset>
              <bitWidth>1</bitWidth>
            </field>
            <field>
              <name>UPCF</name>
              <bitOffset>5</bitOffset>
              <bitWidth>1</bitWidth>
            </field>
            <field>
              <name>DOWNCF</name>
              <bitOffset>6</bitOffset>
              <bitWidth>1</bitWidth>
            </field>
          </fields>
        </register>
        <register>
          <name>IER</name>
          <addressOffset>0x8</addressOffset>
          <size>0x20</size>
          <fields>
            <field>
              <name>CMPMIE</name>
              <bitOffset>0</bitOffset>
              <bitWidth>1</bitWidth>
            </field>
            <field>
              <name>ARRMIE</name>
              <bitOffset>1</bitOffset>
              <bitWidth>1</bitWidth>
            </field>
            <field>
              <name>EXTTRIGIE</name>
              <bitOffset>2</bitOffset>
              <bitWidth>1</bitWidth>
            </field>
            <field>
              <name>CMPOKIE</name>
              <bitOffset>3</bitOffset>
              <bitWidth>1</bitWidth>
            </field>
            <field>
              <name>ARROKIE</name>
              <bitOffset>4</bitOffset>
              <bitWidth>1</bitWidth>
            </field>
            <field>
              <name>UPIE</name>
              <bitOffset>5</bitOffset>
              <bitWidth>1</bitWidth>
            </field>
            <field>
              <name>DOWNIE</name>
              <bitOffset>6</bitOffset>
              <bitWidth>1</bitWidth>
            </field>
          </fields>
        </register>
        <register>
          <name>CFGR</name>
          <addressOffset>0xc</addressOffset>
          <size>0x20</size>
          <fields>
            <field>
              <name>CKSEL</name>
              <bitOffset>0</bitOffset>
              <bitWidth>1</bitWidth>
            </field>
            <field>
              <name>CKPOL</name>
              <bitOffset>1</bitOffset>
              <bitWidth>2</bitWidth>
            </field>
            <field>
              <name>CKFLT</name>
              <bitOffset>3</bitOffset>
              <bitWidth>2</bitWidth>
            </field>
            <field>
              <name>TRGFLT</name>
              <bitOffset>6</bitOffset>
              <bitWidth>2</bitWidth>
            </field>
            <field>
              <name>PRESC</name>
              <bitOffset>9</bitOffset>
              <bitWidth>3</bitWidth>
            </field>
            <field>
              <name>TRIGSEL</name>
              <bitOffset>13</bitOffset>
              <bitWidth>3</bitWidth>
            </field>
            <field>
              <name>TRIGEN</name>
              <bitOffset>17</bitOffset>
              <bitWidth>2</bitWidth>
            </field>
            <field>
              <name>TIMOUT</name>
              <bitOffset>19</bitOffset>
              <bitWidth>1</bitWidth>
            </field>
            <field>
              <name>WAVE</name>
              <bitOffset>20</bitOffset>
              <bitWidth>1</bitWidth>
            </field>
            <field>
              <name>WAVPOL</name>
              <bitOffset>21</bitOffset>
              <bitWidth>1</bitWidth>
            </field>
            <field>
              <name>PRELOAD</name>
              <bitOffset>22</bitOffset>
              <bitWidth>1</bitWidth>
            </field>
            <field>
              <name>COUNTMODE</name>
              <bitOffset>23</bitOffset>
              <bitWidth>1</bitWidth>
            </field>
            <field>
              <name>ENC</name>
              <bitOffset>24</bitOffset>
              <bitWidth>1</bitWidth>
            </field>
          </fields>
        </register>
        <register>
          <name>CR</name>
          <addressOffset>0x10</addressOffset>
          <size>0x20</size>
          <fields>
            <field>
              <name>ENABLE</name>
              <bitOffset>0</bitOffset>
              <bitWidth>1</bitWidth>
            </field>
            <field>
              <name>SNGSTRT</name>
              <bitOffset>1</bitOffset>
              <bitWidth>1</bitWidth>
            </field>
            <field>
              <name>CNTSTRT</name>
              <bitOffset>2</bitOffset>
              <bitWidth>1</bitWidth>
            </field>
          </fields>
        </register>
        <register>
          <name>CMP</name>
          <addressOffset>0x14</addressOffset>
          <size>0x20</size>
          <fields>
            <field>
              <name>CMP</name>
              <bitOffset>0</bitOffset>
              <bitWidth>16</bitWidth>
            </field>
          </fields>
        </register>
        <register>
          <name>ARR</name>
          <addressOffset>0x18</addressOffset>
          <size>0x20</size>
          <fields>
            <field>
              <name>ARR</name>
              <bitOffset>0</bitOffset>
              <bitWidth>16</bitWidth>
            </field>
          </fields>
        </register>
        <register>
          <name>CNT</name>
          <addressOffset>0x1c</addressOffset>
          <size>0x20</size>
          <fields>
            <field>
              <name>CNT</name>
              <bitOffset>0</bitOffset>
              <bitWidth>16</bitWidth>
            </field>
          </fields>
        </register>
        <register>
          <name>OR</name>
          <addressOffset>0x20</addressOffset>
          <size>0x20</size>
          <fields>
            <field>
              <name>OR</name>
              <bitOffset>0</bitOffset>
              <bitWidth>2</bitWidth>
            </field>
          </fields>
        </register>
      </registers>
    </peripheral>
    <peripheral>
      <name>SYSCFG</name>
      <baseAddress>0x40010000</baseAddress>
      <registers>
        <register>
          <name>MEMRMP</name>
          <addressOffset>0x0</addressOffset>
          <size>0x20</size>
          <fields>
            <field>
              <name>MEM_MODE</name>
              <bitOffset>0</bitOffset>
              <bitWidth>3</bitWidth>
            </field>
          </fields>
        </register>
        <register>
          <name>CFGR1</name>
          <addressOffset>0x4</addressOffset>
          <size>0x20</size>
          <fields>
            <field>
              <name>FWDIS</name>
              <bitOffset>0</bitOffset>
              <bitWidth>1</bitWidth>
            </field>
            <field>
              <name>BOOSTEN</name>
              <bitOffset>8</bitOffset>
              <bitWidth>1</bitWidth>
            </field>
            <field>
              <name>I2C_PB6_FMP</name>
              <bitOffset>16</bitOffset>
              <bitWidth>1</bitWidth>
            </field>
            <field>
              <name>I2C_PB7_FMP</name>
              <bitOffset>17</bitOffset>
              <bitWidth>1</bitWidth>
            </field>
            <field>
              <name>I2C_PB8_FMP</name>
              <bitOffset>18</bitOffset>
              <bitWidth>1</bitWidth>
            </field>
            <field>
              <name>I2C_PB9_FMP</name>
              <bitOffset>19</bitOffset>
              <bitWidth>1</bitWidth>
            </field>
            <field>
              <name>I2C1_FMP</name>
              <bitOffset>20</bitOffset>
              <bitWidth>1</bitWidth>
            </field>
            <field>
              <name>I2C2_FMP</name>
              <bitOffset>21</bitOffset>
              <bitWidth>1</bitWidth>
            </field>
            <field>
              <name>I2C3_FMP</name>
              <bitOffset>22</bitOffset>
              <bitWidth>1</bitWidth>
            </field>
          </fields>
        </register>
        <register>
          <name>EXTICR.0</name>
          <addressOffset>0x8</addressOffset>
          <size>0x20</size>
          <fields>
            <field>
              <name>EXTI0</name>
              <bitOffset>0</bitOffset>
              <bitWidth>3</bitWidth>
            </field>
            <field>
              <name>EXTI1</name>
              <bitOffset>4</bitOffset>
              <bitWidth>3</bitWidth>
            </field>
            <field>
              <name>EXTI2</name>
              <bitOffset>8</bitOffset>
              <bitWidth>3</bitWidth>
            </field>
            <field>
              <name>EXTI3</name>
              <bitOffset>12</bitOffset>
              <bitWidth>3</bitWidth>
            </field>
          </fields>
        </register>
        <register>
          <name>EXTICR.1</name>
          <addressOffset>0xc</addressOffset>
          <size>0x20</size>
          <fields>
            <field>
              <name>EXTI4</name>
              <bitOffset>0</bitOffset>
              <bitWidth>3</bitWidth>
            </field>
            <field>
              <name>EXTI5</name>
              <bitOffset>4</bitOffset>
              <bitWidth>3</bitWidth>
            </field>
            <field>
              <name>EXTI6</name>
              <bitOffset>8</bitOffset>
              <bitWidth>3</bitWidth>
            </field>
            <field>
              <name>EXTI7</name>
              <bitOffset>12</bitOffset>
              <bitWidth>3</bitWidth>
            </field>
          </fields>
        </register>
        <register>
          <name>EXTICR.2</name>
          <addressOffset>0x10</addressOffset>
          <size>0x20</size>
          <fields>
            <field>
              <name>EXTI8</name>
              <bitOffset>0</bitOffset>
              <bitWidth>3</bitWidth>
            </field>
            <field>
              <name>EXTI9</name>
              <bitOffset>4</bitOffset>
              <bitWidth>3</bitWidth>
            </field>
            <field>
              <name>EXTI10</name>
              <bitOffset>8</bitOffset>
              <bitWidth>3</bitWidth>
            </field>
            <field>
              <name>EXTI11</name>
              <bitOffset>12</bitOffset>
              <bitWidth>3</bitWidth>
            </field>
          </fields>
        </register>
        <register>
          <name>EXTICR.3</name>
          <addressOffset>0x14</addressOffset>
          <size>0x20</size>
          <fields>
            <field>
              <name>EXTI12</name>
              <bitOffset>0</bitOffset>
              <bitWidth>3</bitWidth>
            </field>
            <field>
              <name>EXTI13</name>
              <bitOffset>4</bitOffset>
              <bitWidth>3</bitWidth>
            </field>
            <field>
              <name>EXTI14</name>
              <bitOffset>8</bitOffset>
              <bitWidth>3</bitWidth>
            </field>
            <field>
              <name>EXTI15</name>
              <bitOffset>12</bitOffset>
              <bitWidth>3</bitWidth>
            </field>
          </fields>
        </register>
        <register>
          <name>SCSR</name>
          <addressOffset>0x18</addressOffset>
          <size>0x20</size>
          <fields>
            <field>
              <name>SRAM2ER</name>
              <bitOffset>0</bitOffset>
              <bitWidth>1</bitWidth>
            </field>
            <field>
              <name>SRAM2BSY</name>
              <bitOffset>1</bitOffset>
              <bitWidth>1</bitWidth>
            </field>
          </fields>
        </register>
        <register>
          <name>CFGR2</name>
          <addressOffset>0x1c</addressOffset>
          <size>0x20</size>
          <fields>
            <field>
              <name>CLL</name>
              <bitOffset>0</bitOffset>
              <bitWidth>1</bitWidth>
            </field>
            <field>
              <name>SPL</name>
              <bitOffset>1</bitOffset>
              <bitWidth>1</bitWidth>
            </field>
            <field>
              <name>PVDL</name>
              <bitOffset>2</bitOffset>
              <bitWidth>1</bitWidth>
            </field>
            <field>
              <name>ECCL</name>
              <bitOffset>3</bitOffset>
              <bitWidth>1</bitWidth>
            </field>
            <field>
              <name>SPF</name>
              <bitOffset>8</bitOffset>
              <bitWidth>1</bitWidth>
            </field>
          </fields>
        </register>
        <register>
          <name>SWPR</name>
          <addressOffset>0x20</addressOffset>
          <size>0x20</size>
          <fields>
            <field>
              <name>PAGE0</name>
              <bitOffset>0</bitOffset>
              <bitWidth>1</bitWidth>
            </field>
            <field>
              <name>PAGE1</name>
              <bitOffset>1</bitOffset>
              <bitWidth>1</bitWidth>
            </field>
            <field>
              <name>PAGE2</name>
              <bitOffset>2</bitOffset>
              <bitWidth>1</bitWidth>
            </field>
            <field>
              <name>PAGE3</name>
              <bitOffset>3</bitOffset>
              <bitWidth>1</bitWidth>
            </field>
            <field>
              <name>PAGE4</name>
              <bitOffset>4</bitOffset>
              <bitWidth>1</bitWidth>
            </field>
            <field>
              <name>PAGE5</name>
              <bitOffset>5</bitOffset>
              <bitWidth>1</bitWidth>
            </field>
            <field>
              <name>PAGE6</name>
              <bitOffset>6</bitOffset>
              <bitWidth>1</bitWidth>
            </field>
            <field>
              <name>PAGE7</name>
              <bitOffset>7</bitOffset>
              <bitWidth>1</bitWidth>
            </field>
            <field>
              <name>PAGE8</name>
              <bitOffset>8</bitOffset>
              <bitWidth>1</bitWidth>
            </field>
            <field>
              <name>PAGE9</name>
              <bitOffset>9</bitOffset>
              <bitWidth>1</bitWidth>
            </field>
            <field>
              <name>PAGE10</name>
              <bitOffset>10</bitOffset>
              <bitWidth>1</bitWidth>
            </field>
            <field>
              <name>PAGE11</name>
              <bitOffset>11</bitOffset>
              <bitWidth>1</bitWidth>
            </field>
            <field>
              <name>PAGE12</name>
              <bitOffset>12</bitOffset>
              <bitWidth>1</bitWidth>
            </field>
            <field>
              <name>PAGE13</name>
              <bitOffset>13</bitOffset>
              <bitWidth>1</bitWidth>
            </field>
            <field>
              <name>PAGE14</name>
              <bitOffset>14</bitOffset>
              <bitWidth>1</bitWidth>
            </field>
            <field>
              <name>PAGE15</name>
              <bitOffset>15</bitOffset>
              <bitWidth>1</bitWidth>
            </field>
          </fields>
        </register>
        <register>
          <name>SKR</name>
          <addressOffset>0x24</addressOffset>
          <size>0x20</size>
          <fields>
            <field>
              <name>KEY</name>
              <bitOffset>0</bitOffset>
              <bitWidth>8</bitWidth>
            </field>
          </fields>
        </register>
      </registers>
    </peripheral>
    <peripheral>
      <name>VREFBUF</name>
      <baseAddress>0x40010030</baseAddress>
      <registers>
        <register>
          <name>CSR</name>
          <addressOffset>0x0</addressOffset>
          <size>0x20</size>
          <fields>
            <field>
              <name>ENVR</name>
              <bitOffset>0</bitOffset>
              <bitWidth>1</bitWidth>
            </field>
            <field>
              <name>HIZ</name>
              <bitOffset>1</bitOffset>
              <bitWidth>1</bitWidth>
            </field>
            <field>
              <name>VRS</name>
              <bitOffset>2</bitOffset>
              <bitWidth>1</bitWidth>
            </field>
            <field>
              <name>VRR</name>
              <bitOffset>3</bitOffset>
              <bitWidth>1</bitWidth>
            </field>
          </fields>
        </register>
        <register>
          <name>CCR</name>
          <addressOffset>0x4</addressOffset>
          <size>0x20</size>
          <fields>
            <field>
              <name>TRIM</name>
              <bitOffset>0</bitOffset>
              <bitWidth>6</bitWidth>
            </field>
          </fields>
        </register>
      </registers>
    </peripheral>
    <peripheral>
      <name>COMP1</name>
      <baseAddress>0x40010200</baseAddress>
      <registers>
        <register>
          <name>CSR</name>
          <addressOffset>0x0</addressOffset>
          <size>0x20</size>
          <fields>
            <field>
              <name>EN</name>
              <bitOffset>0</bitOffset>
              <bitWidth>1</bitWidth>
            </field>
            <field>
              <name>PWRMODE</name>
              <bitOffset>2</bitOffset>
              <bitWidth>2</bitWidth>
            </field>
            <field>
              <name>INMSEL</name>
              <bitOffset>4</bitOffset>
              <bitWidth>3</bitWidth>
            </field>
            <field>
              <name>INPSEL</name>
              <bitOffset>7</bitOffset>
              <bitWidth>2</bitWidth>
            </field>
            <field>
              <name>WINMODE</name>
              <bitOffset>9</bitOffset>
              <bitWidth>1</bitWidth>
            </field>
            <field>
              <name>POLARITY</name>
              <bitOffset>15</bitOffset>
              <bitWidth>1</bitWidth>
            </field>
            <field>
              <name>HYST</name>
              <bitOffset>16</bitOffset>
              <bitWidth>2</bitWidth>
            </field>
            <field>
              <name>BLANKING</name>
              <bitOffset>18</bitOffset>
              <bitWidth>3</bitWidth>
            </field>
            <field>
              <name>BRGEN</name>
              <bitOffset>22</bitOffset>
              <bitWidth>1</bitWidth>
            </field>
            <field>
              <name>SCALEN</name>
              <bitOffset>23</bitOffset>
              <bitWidth>1</bitWidth>
            </field>
            <field>
              <name>INMESEL</name>
              <bitOffset>25</bitOffset>
              <bitWidth>2</bitWidth>
            </field>
            <field>
              <name>VALUE</name>
              <bitOffset>30</bitOffset>
              <bitWidth>1</bitWidth>
            </field>
            <field>
              <name>LOCK</name>
              <bitOffset>31</bitOffset>
              <bitWidth>1</bitWidth>
            </field>
          </fields>
        </register>
      </registers>
    </peripheral>
    <peripheral>
      <name>COMP2</name>
      <baseAddress>0x40010204</baseAddress>
      <registers>
        <register>
          <name>CSR</name>
          <addressOffset>0x0</addressOffset>
          <size>0x20</size>
          <fields>
            <field>
              <name>EN</name>
              <bitOffset>0</bitOffset>
              <bitWidth>1</bitWidth>
            </field>
            <field>
              <name>PWRMODE</name>
              <bitOffset>2</bitOffset>
              <bitWidth>2</bitWidth>
            </field>
            <field>
              <name>INMSEL</name>
              <bitOffset>4</bitOffset>
              <bitWidth>3</bitWidth>
            </field>
            <field>
              <name>INPSEL</name>
              <bitOffset>7</bitOffset>
              <bitWidth>2</bitWidth>
            </field>
            <field>
              <name>WINMODE</name>
              <bitOffset>9</bitOffset>
              <bitWidth>1</bitWidth>
            </field>
            <field>
              <name>POLARITY</name>
              <bitOffset>15</bitOffset>
              <bitWidth>1</bitWidth>
            </field>
            <field>
              <name>HYST</name>
              <bitOffset>16</bitOffset>
              <bitWidth>2</bitWidth>
            </field>
            <field>
              <name>BLANKING</name>
              <bitOffset>18</bitOffset>
              <bitWidth>3</bitWidth>
            </field>
            <field>
              <name>BRGEN</name>
              <bitOffset>22</bitOffset>
              <bitWidth>1</bitWidth>
            </field>
            <field>
              <name>SCALEN</name>
              <bitOffset>23</bitOffset>
              <bitWidth>1</bitWidth>
            </field>
            <field>
              <name>INMESEL</name>
              <bitOffset>25</bitOffset>
              <bitWidth>2</bitWidth>
            </field>
            <field>
              <name>VALUE</name>
              <bitOffset>30</bitOffset>
              <bitWidth>1</bitWidth>
            </field>
            <field>
              <name>LOCK</name>
              <bitOffset>31</bitOffset>
              <bitWidth>1</bitWidth>
            </field>
          </fields>
        </register>
      </registers>
    </peripheral>
    <peripheral>
      <name>COMP12_COMMON</name>
      <baseAddress>0x40010204</baseAddress>
      <registers>
        <register>
          <name>CSR</name>
          <addressOffset>0x0</addressOffset>
          <size>0x20</size>
          <fields>
            <field>
              <name>EN</name>
              <bitOffset>0</bitOffset>
              <bitWidth>1</bitWidth>
            </field>
            <field>
              <name>PWRMODE</name>
              <bitOffset>2</bitOffset>
              <bitWidth>2</bitWidth>
            </field>
            <field>
              <name>INMSEL</name>
              <bitOffset>4</bitOffset>
              <bitWidth>3</bitWidth>
            </field>
            <field>
              <name>INPSEL</name>
              <bitOffset>7</bitOffset>
              <bitWidth>2</bitWidth>
            </field>
            <field>
              <name>WINMODE</name>
              <bitOffset>9</bitOffset>
              <bitWidth>1</bitWidth>
            </field>
            <field>
              <name>POLARITY</name>
              <bitOffset>15</bitOffset>
              <bitWidth>1</bitWidth>
            </field>
            <field>
              <name>HYST</name>
              <bitOffset>16</bitOffset>
              <bitWidth>2</bitWidth>
            </field>
            <field>
              <name>BLANKING</name>
              <bitOffset>18</bitOffset>
              <bitWidth>3</bitWidth>
            </field>
            <field>
              <name>BRGEN</name>
              <bitOffset>22</bitOffset>
              <bitWidth>1</bitWidth>
            </field>
            <field>
              <name>SCALEN</name>
              <bitOffset>23</bitOffset>
              <bitWidth>1</bitWidth>
            </field>
            <field>
              <name>INMESEL</name>
              <bitOffset>25</bitOffset>
              <bitWidth>2</bitWidth>
            </field>
            <field>
              <name>VALUE</name>
              <bitOffset>30</bitOffset>
              <bitWidth>1</bitWidth>
            </field>
            <field>
              <name>LOCK</name>
              <bitOffset>31</bitOffset>
              <bitWidth>1</bitWidth>
            </field>
          </fields>
        </register>
      </registers>
    </peripheral>
    <peripheral>
      <name>EXTI</name>
      <baseAddress>0x40010400</baseAddress>
      <registers>
        <register>
          <name>IMR1</name>
          <addressOffset>0x0</addressOffset>
          <size>0x20</size>
          <fields>
            <field>
              <name>IM0</name>
              <bitOffset>0</bitOffset>
              <bitWidth>1</bitWidth>
            </field>
            <field>
              <name>IM1</name>
              <bitOffset>1</bitOffset>
              <bitWidth>1</bitWidth>
            </field>
            <field>
              <name>IM2</name>
              <bitOffset>2</bitOffset>
              <bitWidth>1</bitWidth>
            </field>
            <field>
              <name>IM3</name>
              <bitOffset>3</bitOffset>
              <bitWidth>1</bitWidth>
            </field>
            <field>
              <name>IM4</name>
              <bitOffset>4</bitOffset>
              <bitWidth>1</bitWidth>
            </field>
            <field>
              <name>IM5</name>
              <bitOffset>5</bitOffset>
              <bitWidth>1</bitWidth>
            </field>
            <field>
              <name>IM6</name>
              <bitOffset>6</bitOffset>
              <bitWidth>1</bitWidth>
            </field>
            <field>
              <name>IM7</name>
              <bitOffset>7</bitOffset>
              <bitWidth>1</bitWidth>
            </field>
            <field>
              <name>IM8</name>
              <bitOffset>8</bitOffset>
              <bitWidth>1</bitWidth>
            </field>
            <field>
              <name>IM9</name>
              <bitOffset>9</bitOffset>
              <bitWidth>1</bitWidth>
            </field>
            <field>
              <name>IM10</name>
              <bitOffset>10</bitOffset>
              <bitWidth>1</bitWidth>
            </field>
            <field>
              <name>IM11</name>
              <bitOffset>11</bitOffset>
              <bitWidth>1</bitWidth>
            </field>
            <field>
              <name>IM12</name>
              <bitOffset>12</bitOffset>
              <bitWidth>1</bitWidth>
            </field>
            <field>
              <name>IM13</name>
              <bitOffset>13</bitOffset>
              <bitWidth>1</bitWidth>
            </field>
            <field>
              <name>IM14</name>
              <bitOffset>14</bitOffset>
              <bitWidth>1</bitWidth>
            </field>
            <field>
              <name>IM15</name>
              <bitOffset>15</bitOffset>
              <bitWidth>1</bitWidth>
            </field>
            <field>
              <name>IM16</name>
              <bitOffset>16</bitOffset>
              <bitWidth>1</bitWidth>
            </field>
            <field>
              <name>IM17</name>
              <bitOffset>17</bitOffset>
              <bitWidth>1</bitWidth>
            </field>
            <field>
              <name>IM18</name>
              <bitOffset>18</bitOffset>
              <bitWidth>1</bitWidth>
            </field>
            <field>
              <name>IM19</name>
              <bitOffset>19</bitOffset>
              <bitWidth>1</bitWidth>
            </field>
            <field>
              <name>IM20</name>
              <bitOffset>20</bitOffset>
              <bitWidth>1</bitWidth>
            </field>
            <field>
              <name>IM21</name>
              <bitOffset>21</bitOffset>
              <bitWidth>1</bitWidth>
            </field>
            <field>
              <name>IM22</name>
              <bitOffset>22</bitOffset>
              <bitWidth>1</bitWidth>
            </field>
            <field>
              <name>IM23</name>
              <bitOffset>23</bitOffset>
              <bitWidth>1</bitWidth>
            </field>
            <field>
              <name>IM24</name>
              <bitOffset>24</bitOffset>
              <bitWidth>1</bitWidth>
            </field>
            <field>
              <name>IM25</name>
              <bitOffset>25</bitOffset>
              <bitWidth>1</bitWidth>
            </field>
            <field>
              <name>IM26</name>
              <bitOffset>26</bitOffset>
              <bitWidth>1</bitWidth>
            </field>
            <field>
              <name>IM27</name>
              <bitOffset>27</bitOffset>
              <bitWidth>1</bitWidth>
            </field>
            <field>
              <name>IM28</name>
              <bitOffset>28</bitOffset>
              <bitWidth>1</bitWidth>
            </field>
            <field>
              <name>IM31</name>
              <bitOffset>31</bitOffset>
              <bitWidth>1</bitWidth>
            </field>
          </fields>
        </register>
        <register>
          <name>EMR1</name>
          <addressOffset>0x4</addressOffset>
          <size>0x20</size>
          <fields>
            <field>
              <name>EM0</name>
              <bitOffset>0</bitOffset>
              <bitWidth>1</bitWidth>
            </field>
            <field>
              <name>EM1</name>
              <bitOffset>1</bitOffset>
              <bitWidth>1</bitWidth>
            </field>
            <field>
              <name>EM2</name>
              <bitOffset>2</bitOffset>
              <bitWidth>1</bitWidth>
            </field>
            <field>
              <name>EM3</name>
              <bitOffset>3</bitOffset>
              <bitWidth>1</bitWidth>
            </field>
            <field>
              <name>EM4</name>
              <bitOffset>4</bitOffset>
              <bitWidth>1</bitWidth>
            </field>
            <field>
              <name>EM5</name>
              <bitOffset>5</bitOffset>
              <bitWidth>1</bitWidth>
            </field>
            <field>
              <name>EM6</name>
              <bitOffset>6</bitOffset>
              <bitWidth>1</bitWidth>
            </field>
            <field>
              <name>EM7</name>
              <bitOffset>7</bitOffset>
              <bitWidth>1</bitWidth>
            </field>
            <field>
              <name>EM8</name>
              <bitOffset>8</bitOffset>
              <bitWidth>1</bitWidth>
            </field>
            <field>
              <name>EM9</name>
              <bitOffset>9</bitOffset>
              <bitWidth>1</bitWidth>
            </field>
            <field>
              <name>EM10</name>
              <bitOffset>10</bitOffset>
              <bitWidth>1</bitWidth>
            </field>
            <field>
              <name>EM11</name>
              <bitOffset>11</bitOffset>
              <bitWidth>1</bitWidth>
            </field>
            <field>
              <name>EM12</name>
              <bitOffset>12</bitOffset>
              <bitWidth>1</bitWidth>
            </field>
            <field>
              <name>EM13</name>
              <bitOffset>13</bitOffset>
              <bitWidth>1</bitWidth>
            </field>
            <field>
              <name>EM14</name>
              <bitOffset>14</bitOffset>
              <bitWidth>1</bitWidth>
            </field>
            <field>
              <name>EM15</name>
              <bitOffset>15</bitOffset>
              <bitWidth>1</bitWidth>
            </field>
            <field>
              <name>EM16</name>
              <bitOffset>16</bitOffset>
              <bitWidth>1</bitWidth>
            </field>
            <field>
              <name>EM17</name>
              <bitOffset>17</bitOffset>
              <bitWidth>1</bitWidth>
            </field>
            <field>
              <name>EM18</name>
              <bitOffset>18</bitOffset>
              <bitWidth>1</bitWidth>
            </field>
            <field>
              <name>EM19</name>
              <bitOffset>19</bitOffset>
              <bitWidth>1</bitWidth>
            </field>
            <field>
              <name>EM20</name>
              <bitOffset>20</bitOffset>
              <bitWidth>1</bitWidth>
            </field>
            <field>
              <name>EM21</name>
              <bitOffset>21</bitOffset>
              <bitWidth>1</bitWidth>
            </field>
            <field>
              <name>EM22</name>
              <bitOffset>22</bitOffset>
              <bitWidth>1</bitWidth>
            </field>
            <field>
              <name>EM23</name>
              <bitOffset>23</bitOffset>
              <bitWidth>1</bitWidth>
            </field>
            <field>
              <name>EM24</name>
              <bitOffset>24</bitOffset>
              <bitWidth>1</bitWidth>
            </field>
            <field>
              <name>EM25</name>
              <bitOffset>25</bitOffset>
              <bitWidth>1</bitWidth>
            </field>
            <field>
              <name>EM26</name>
              <bitOffset>26</bitOffset>
              <bitWidth>1</bitWidth>
            </field>
            <field>
              <name>EM27</name>
              <bitOffset>27</bitOffset>
              <bitWidth>1</bitWidth>
            </field>
            <field>
              <name>EM28</name>
              <bitOffset>28</bitOffset>
              <bitWidth>1</bitWidth>
            </field>
            <field>
              <name>EM31</name>
              <bitOffset>31</bitOffset>
              <bitWidth>1</bitWidth>
            </field>
          </fields>
        </register>
        <register>
          <name>RTSR1</name>
          <addressOffset>0x8</addressOffset>
          <size>0x20</size>
          <fields>
            <field>
              <name>RT0</name>
              <bitOffset>0</bitOffset>
              <bitWidth>1</bitWidth>
            </field>
            <field>
              <name>RT1</name>
              <bitOffset>1</bitOffset>
              <bitWidth>1</bitWidth>
            </field>
            <field>
              <name>RT2</name>
              <bitOffset>2</bitOffset>
              <bitWidth>1</bitWidth>
            </field>
            <field>
              <name>RT3</name>
              <bitOffset>3</bitOffset>
              <bitWidth>1</bitWidth>
            </field>
            <field>
              <name>RT4</name>
              <bitOffset>4</bitOffset>
              <bitWidth>1</bitWidth>
            </field>
            <field>
              <name>RT5</name>
              <bitOffset>5</bitOffset>
              <bitWidth>1</bitWidth>
            </field>
            <field>
              <name>RT6</name>
              <bitOffset>6</bitOffset>
              <bitWidth>1</bitWidth>
            </field>
            <field>
              <name>RT7</name>
              <bitOffset>7</bitOffset>
              <bitWidth>1</bitWidth>
            </field>
            <field>
              <name>RT8</name>
              <bitOffset>8</bitOffset>
              <bitWidth>1</bitWidth>
            </field>
            <field>
              <name>RT9</name>
              <bitOffset>9</bitOffset>
              <bitWidth>1</bitWidth>
            </field>
            <field>
              <name>RT10</name>
              <bitOffset>10</bitOffset>
              <bitWidth>1</bitWidth>
            </field>
            <field>
              <name>RT11</name>
              <bitOffset>11</bitOffset>
              <bitWidth>1</bitWidth>
            </field>
            <field>
              <name>RT12</name>
              <bitOffset>12</bitOffset>
              <bitWidth>1</bitWidth>
            </field>
            <field>
              <name>RT13</name>
              <bitOffset>13</bitOffset>
              <bitWidth>1</bitWidth>
            </field>
            <field>
              <name>RT14</name>
              <bitOffset>14</bitOffset>
              <bitWidth>1</bitWidth>
            </field>
            <field>
              <name>RT15</name>
              <bitOffset>15</bitOffset>
              <bitWidth>1</bitWidth>
            </field>
            <field>
              <name>RT16</name>
              <bitOffset>16</bitOffset>
              <bitWidth>1</bitWidth>
            </field>
            <field>
              <name>RT18</name>
              <bitOffset>18</bitOffset>
              <bitWidth>1</bitWidth>
            </field>
            <field>
              <name>RT19</name>
              <bitOffset>19</bitOffset>
              <bitWidth>1</bitWidth>
            </field>
            <field>
              <name>RT20</name>
              <bitOffset>20</bitOffset>
              <bitWidth>1</bitWidth>
            </field>
            <field>
              <name>RT21</name>
              <bitOffset>21</bitOffset>
              <bitWidth>1</bitWidth>
            </field>
            <field>
              <name>RT22</name>
              <bitOffset>22</bitOffset>
              <bitWidth>1</bitWidth>
            </field>
          </fields>
        </register>
        <register>
          <name>FTSR1</name>
          <addressOffset>0xc</addressOffset>
          <size>0x20</size>
          <fields>
            <field>
              <name>FT0</name>
              <bitOffset>0</bitOffset>
              <bitWidth>1</bitWidth>
            </field>
            <field>
              <name>FT1</name>
              <bitOffset>1</bitOffset>
              <bitWidth>1</bitWidth>
            </field>
            <field>
              <name>FT2</name>
              <bitOffset>2</bitOffset>
              <bitWidth>1</bitWidth>
            </field>
            <field>
              <name>FT3</name>
              <bitOffset>3</bitOffset>
              <bitWidth>1</bitWidth>
            </field>
            <field>
              <name>FT4</name>
              <bitOffset>4</bitOffset>
              <bitWidth>1</bitWidth>
            </field>
            <field>
              <name>FT5</name>
              <bitOffset>5</bitOffset>
              <bitWidth>1</bitWidth>
            </field>
            <field>
              <name>FT6</name>
              <bitOffset>6</bitOffset>
              <bitWidth>1</bitWidth>
            </field>
            <field>
              <name>FT7</name>
              <bitOffset>7</bitOffset>
              <bitWidth>1</bitWidth>
            </field>
            <field>
              <name>FT8</name>
              <bitOffset>8</bitOffset>
              <bitWidth>1</bitWidth>
            </field>
            <field>
              <name>FT9</name>
              <bitOffset>9</bitOffset>
              <bitWidth>1</bitWidth>
            </field>
            <field>
              <name>FT10</name>
              <bitOffset>10</bitOffset>
              <bitWidth>1</bitWidth>
            </field>
            <field>
              <name>FT11</name>
              <bitOffset>11</bitOffset>
              <bitWidth>1</bitWidth>
            </field>
            <field>
              <name>FT12</name>
              <bitOffset>12</bitOffset>
              <bitWidth>1</bitWidth>
            </field>
            <field>
              <name>FT13</name>
              <bitOffset>13</bitOffset>
              <bitWidth>1</bitWidth>
            </field>
            <field>
              <name>FT14</name>
              <bitOffset>14</bitOffset>
              <bitWidth>1</bitWidth>
            </field>
            <field>
              <name>FT15</name>
              <bitOffset>15</bitOffset>
              <bitWidth>1</bitWidth>
            </field>
            <field>
              <name>FT16</name>
              <bitOffset>16</bitOffset>
              <bitWidth>1</bitWidth>
            </field>
            <field>
              <name>FT18</name>
              <bitOffset>18</bitOffset>
              <bitWidth>1</bitWidth>
            </field>
            <field>
              <name>FT19</name>
              <bitOffset>19</bitOffset>
              <bitWidth>1</bitWidth>
            </field>
            <field>
              <name>FT20</name>
              <bitOffset>20</bitOffset>
              <bitWidth>1</bitWidth>
            </field>
            <field>
              <name>FT21</name>
              <bitOffset>21</bitOffset>
              <bitWidth>1</bitWidth>
            </field>
            <field>
              <name>FT22</name>
              <bitOffset>22</bitOffset>
              <bitWidth>1</bitWidth>
            </field>
          </fields>
        </register>
        <register>
          <name>SWIER1</name>
          <addressOffset>0x10</addressOffset>
          <size>0x20</size>
          <fields>
            <field>
              <name>SWI0</name>
              <bitOffset>0</bitOffset>
              <bitWidth>1</bitWidth>
            </field>
            <field>
              <name>SWI1</name>
              <bitOffset>1</bitOffset>
              <bitWidth>1</bitWidth>
            </field>
            <field>
              <name>SWI2</name>
              <bitOffset>2</bitOffset>
              <bitWidth>1</bitWidth>
            </field>
            <field>
              <name>SWI3</name>
              <bitOffset>3</bitOffset>
              <bitWidth>1</bitWidth>
            </field>
            <field>
              <name>SWI4</name>
              <bitOffset>4</bitOffset>
              <bitWidth>1</bitWidth>
            </field>
            <field>
              <name>SWI5</name>
              <bitOffset>5</bitOffset>
              <bitWidth>1</bitWidth>
            </field>
            <field>
              <name>SWI6</name>
              <bitOffset>6</bitOffset>
              <bitWidth>1</bitWidth>
            </field>
            <field>
              <name>SWI7</name>
              <bitOffset>7</bitOffset>
              <bitWidth>1</bitWidth>
            </field>
            <field>
              <name>SWI8</name>
              <bitOffset>8</bitOffset>
              <bitWidth>1</bitWidth>
            </field>
            <field>
              <name>SWI9</name>
              <bitOffset>9</bitOffset>
              <bitWidth>1</bitWidth>
            </field>
            <field>
              <name>SWI10</name>
              <bitOffset>10</bitOffset>
              <bitWidth>1</bitWidth>
            </field>
            <field>
              <name>SWI11</name>
              <bitOffset>11</bitOffset>
              <bitWidth>1</bitWidth>
            </field>
            <field>
              <name>SWI12</name>
              <bitOffset>12</bitOffset>
              <bitWidth>1</bitWidth>
            </field>
            <field>
              <name>SWI13</name>
              <bitOffset>13</bitOffset>
              <bitWidth>1</bitWidth>
            </field>
            <field>
              <name>SWI14</name>
              <bitOffset>14</bitOffset>
              <bitWidth>1</bitWidth>
            </field>
            <field>
              <name>SWI15</name>
              <bitOffset>15</bitOffset>
              <bitWidth>1</bitWidth>
            </field>
            <field>
              <name>SWI16</name>
              <bitOffset>16</bitOffset>
              <bitWidth>1</bitWidth>
            </field>
            <field>
              <name>SWI18</name>
              <bitOffset>18</bitOffset>
              <bitWidth>1</bitWidth>
            </field>
            <field>
              <name>SWI19</name>
              <bitOffset>19</bitOffset>
              <bitWidth>1</bitWidth>
            </field>
            <field>
              <name>SWI20</name>
              <bitOffset>20</bitOffset>
              <bitWidth>1</bitWidth>
            </field>
            <field>
              <name>SWI21</name>
              <bitOffset>21</bitOffset>
              <bitWidth>1</bitWidth>
            </field>
            <field>
              <name>SWI22</name>
              <bitOffset>22</bitOffset>
              <bitWidth>1</bitWidth>
            </field>
          </fields>
        </register>
        <register>
          <name>PR1</name>
          <addressOffset>0x14</addressOffset>
          <size>0x20</size>
          <fields>
            <field>
              <name>PIF0</name>
              <bitOffset>0</bitOffset>
              <bitWidth>1</bitWidth>
            </field>
            <field>
              <name>PIF1</name>
              <bitOffset>1</bitOffset>
              <bitWidth>1</bitWidth>
            </field>
            <field>
              <name>PIF2</name>
              <bitOffset>2</bitOffset>
              <bitWidth>1</bitWidth>
            </field>
            <field>
              <name>PIF3</name>
              <bitOffset>3</bitOffset>
              <bitWidth>1</bitWidth>
            </field>
            <field>
              <name>PIF4</name>
              <bitOffset>4</bitOffset>
              <bitWidth>1</bitWidth>
            </field>
            <field>
              <name>PIF5</name>
              <bitOffset>5</bitOffset>
              <bitWidth>1</bitWidth>
            </field>
            <field>
              <name>PIF6</name>
              <bitOffset>6</bitOffset>
              <bitWidth>1</bitWidth>
            </field>
            <field>
              <name>PIF7</name>
              <bitOffset>7</bitOffset>
              <bitWidth>1</bitWidth>
            </field>
            <field>
              <name>PIF8</name>
              <bitOffset>8</bitOffset>
              <bitWidth>1</bitWidth>
            </field>
            <field>
              <name>PIF9</name>
              <bitOffset>9</bitOffset>
              <bitWidth>1</bitWidth>
            </field>
            <field>
              <name>PIF10</name>
              <bitOffset>10</bitOffset>
              <bitWidth>1</bitWidth>
            </field>
            <field>
              <name>PIF11</name>
              <bitOffset>11</bitOffset>
              <bitWidth>1</bitWidth>
            </field>
            <field>
              <name>PIF12</name>
              <bitOffset>12</bitOffset>
              <bitWidth>1</bitWidth>
            </field>
            <field>
              <name>PIF13</name>
              <bitOffset>13</bitOffset>
              <bitWidth>1</bitWidth>
            </field>
            <field>
              <name>PIF14</name>
              <bitOffset>14</bitOffset>
              <bitWidth>1</bitWidth>
            </field>
            <field>
              <name>PIF15</name>
              <bitOffset>15</bitOffset>
              <bitWidth>1</bitWidth>
            </field>
            <field>
              <name>PIF16</name>
              <bitOffset>16</bitOffset>
              <bitWidth>1</bitWidth>
            </field>
            <field>
              <name>PIF18</name>
              <bitOffset>18</bitOffset>
              <bitWidth>1</bitWidth>
            </field>
            <field>
              <name>PIF19</name>
              <bitOffset>19</bitOffset>
              <bitWidth>1</bitWidth>
            </field>
            <field>
              <name>PIF20</name>
              <bitOffset>20</bitOffset>
              <bitWidth>1</bitWidth>
            </field>
            <field>
              <name>PIF21</name>
              <bitOffset>21</bitOffset>
              <bitWidth>1</bitWidth>
            </field>
            <field>
              <name>PIF22</name>
              <bitOffset>22</bitOffset>
              <bitWidth>1</bitWidth>
            </field>
          </fields>
        </register>
        <register>
          <name>IMR2</name>
          <addressOffset>0x20</addressOffset>
          <size>0x20</size>
          <fields>
            <field>
              <name>IM32</name>
              <bitOffset>0</bitOffset>
              <bitWidth>1</bitWidth>
            </field>
            <field>
              <name>IM33</name>
              <bitOffset>1</bitOffset>
              <bitWidth>1</bitWidth>
            </field>
            <field>
              <name>IM34</name>
              <bitOffset>2</bitOffset>
              <bitWidth>1</bitWidth>
            </field>
            <field>
              <name>IM35</name>
              <bitOffset>3</bitOffset>
              <bitWidth>1</bitWidth>
            </field>
            <field>
              <name>IM37</name>
              <bitOffset>5</bitOffset>
              <bitWidth>1</bitWidth>
            </field>
            <field>
              <name>IM38</name>
              <bitOffset>6</bitOffset>
              <bitWidth>1</bitWidth>
            </field>
            <field>
              <name>IM39</name>
              <bitOffset>7</bitOffset>
              <bitWidth>1</bitWidth>
            </field>
          </fields>
        </register>
        <register>
          <name>EMR2</name>
          <addressOffset>0x24</addressOffset>
          <size>0x20</size>
          <fields>
            <field>
              <name>EM32</name>
              <bitOffset>0</bitOffset>
              <bitWidth>1</bitWidth>
            </field>
            <field>
              <name>EM33</name>
              <bitOffset>1</bitOffset>
              <bitWidth>1</bitWidth>
            </field>
            <field>
              <name>EM34</name>
              <bitOffset>2</bitOffset>
              <bitWidth>1</bitWidth>
            </field>
            <field>
              <name>EM35</name>
              <bitOffset>3</bitOffset>
              <bitWidth>1</bitWidth>
            </field>
            <field>
              <name>EM37</name>
              <bitOffset>5</bitOffset>
              <bitWidth>1</bitWidth>
            </field>
            <field>
              <name>EM38</name>
              <bitOffset>6</bitOffset>
              <bitWidth>1</bitWidth>
            </field>
            <field>
              <name>EM39</name>
              <bitOffset>7</bitOffset>
              <bitWidth>1</bitWidth>
            </field>
          </fields>
        </register>
        <register>
          <name>RTSR2</name>
          <addressOffset>0x28</addressOffset>
          <size>0x20</size>
          <fields>
            <field>
              <name>RT35</name>
              <bitOffset>3</bitOffset>
              <bitWidth>1</bitWidth>
            </field>
            <field>
              <name>RT37</name>
              <bitOffset>5</bitOffset>
              <bitWidth>1</bitWidth>
            </field>
            <field>
              <name>RT38</name>
              <bitOffset>6</bitOffset>
              <bitWidth>1</bitWidth>
            </field>
          </fields>
        </register>
        <register>
          <name>FTSR2</name>
          <addressOffset>0x2c</addressOffset>
          <size>0x20</size>
          <fields>
            <field>
              <name>FT35</name>
              <bitOffset>3</bitOffset>
              <bitWidth>1</bitWidth>
            </field>
            <field>
              <name>FT37</name>
              <bitOffset>5</bitOffset>
              <bitWidth>1</bitWidth>
            </field>
            <field>
              <name>FT38</name>
              <bitOffset>6</bitOffset>
              <bitWidth>1</bitWidth>
            </field>
          </fields>
        </register>
        <register>
          <name>SWIER2</name>
          <addressOffset>0x30</addressOffset>
          <size>0x20</size>
          <fields>
            <field>
              <name>SWI35</name>
              <bitOffset>3</bitOffset>
              <bitWidth>1</bitWidth>
            </field>
            <field>
              <name>SWI37</name>
              <bitOffset>5</bitOffset>
              <bitWidth>1</bitWidth>
            </field>
            <field>
              <name>SWI38</name>
              <bitOffset>6</bitOffset>
              <bitWidth>1</bitWidth>
            </field>
          </fields>
        </register>
        <register>
          <name>PR2</name>
          <addressOffset>0x34</addressOffset>
          <size>0x20</size>
          <fields>
            <field>
              <name>PIF35</name>
              <bitOffset>3</bitOffset>
              <bitWidth>1</bitWidth>
            </field>
            <field>
              <name>PIF37</name>
              <bitOffset>5</bitOffset>
              <bitWidth>1</bitWidth>
            </field>
            <field>
              <name>PIF38</name>
              <bitOffset>6</bitOffset>
              <bitWidth>1</bitWidth>
            </field>
          </fields>
        </register>
      </registers>
    </peripheral>
    <peripheral>
      <name>FIREWALL</name>
      <baseAddress>0x40011c00</baseAddress>
      <registers>
        <register>
          <name>CSSA</name>
          <addressOffset>0x0</addressOffset>
          <size>0x20</size>
        </register>
        <register>
          <name>CSL</name>
          <addressOffset>0x4</addressOffset>
          <size>0x20</size>
        </register>
        <register>
          <name>NVDSSA</name>
          <addressOffset>0x8</addressOffset>
          <size>0x20</size>
        </register>
        <register>
          <name>NVDSL</name>
          <addressOffset>0xc</addressOffset>
          <size>0x20</size>
        </register>
        <register>
          <name>VDSSA</name>
          <addressOffset>0x10</addressOffset>
          <size>0x20</size>
        </register>
        <register>
          <name>VDSL</name>
          <addressOffset>0x14</addressOffset>
          <size>0x20</size>
        </register>
        <register>
          <name>CR</name>
          <addressOffset>0x20</addressOffset>
          <size>0x20</size>
        </register>
      </registers>
    </peripheral>
    <peripheral>
      <name>SDMMC1</name>
      <baseAddress>0x40012800</baseAddress>
      <registers>
        <register>
          <name>POWER</name>
          <addressOffset>0x0</addressOffset>
          <size>0x20</size>
          <fields>
            <field>
              <name>PWRCTRL</name>
              <bitOffset>0</bitOffset>
              <bitWidth>2</bitWidth>
            </field>
          </fields>
        </register>
        <register>
          <name>CLKCR</name>
          <addressOffset>0x4</addressOffset>
          <size>0x20</size>
          <fields>
            <field>
              <name>CLKDIV</name>
              <bitOffset>0</bitOffset>
              <bitWidth>8</bitWidth>
            </field>
            <field>
              <name>CLKEN</name>
              <bitOffset>8</bitOffset>
              <bitWidth>1</bitWidth>
            </field>
            <field>
              <name>PWRSAV</name>
              <bitOffset>9</bitOffset>
              <bitWidth>1</bitWidth>
            </field>
            <field>
              <name>BYPASS</name>
              <bitOffset>10</bitOffset>
              <bitWidth>1</bitWidth>
            </field>
            <field>
              <name>WIDBUS</name>
              <bitOffset>11</bitOffset>
              <bitWidth>2</bitWidth>
            </field>
            <field>
              <name>NEGEDGE</name>
              <bitOffset>13</bitOffset>
              <bitWidth>1</bitWidth>
            </field>
            <field>
              <name>HWFC_EN</name>
              <bitOffset>14</bitOffset>
              <bitWidth>1</bitWidth>
            </field>
          </fields>
        </register>
        <register>
          <name>ARG</name>
          <addressOffset>0x8</addressOffset>
          <size>0x20</size>
          <fields>
            <field>
              <name>CMDARG</name>
              <bitOffset>0</bitOffset>
              <bitWidth>32</bitWidth>
            </field>
          </fields>
        </register>
        <register>
          <name>CMD</name>
          <addressOffset>0xc</addressOffset>
          <size>0x20</size>
          <fields>
            <field>
              <name>CMDINDEX</name>
              <bitOffset>0</bitOffset>
              <bitWidth>6</bitWidth>
            </field>
            <field>
              <name>WAITRESP</name>
              <bitOffset>6</bitOffset>
              <bitWidth>2</bitWidth>
            </field>
            <field>
              <name>WAITINT</name>
              <bitOffset>8</bitOffset>
              <bitWidth>1</bitWidth>
            </field>
            <field>
              <name>WAITPEND</name>
              <bitOffset>9</bitOffset>
              <bitWidth>1</bitWidth>
            </field>
            <field>
              <name>CPSMEN</name>
              <bitOffset>10</bitOffset>
              <bitWidth>1</bitWidth>
            </field>
            <field>
              <name>SDIOSUSPEND</name>
              <bitOffset>11</bitOffset>
              <bitWidth>1</bitWidth>
            </field>
          </fields>
        </register>
        <register>
          <name>RESPCMD</name>
          <addressOffset>0x10</addressOffset>
          <size>0x20</size>
          <fields>
            <field>
              <name>RESPCMD</name>
              <bitOffset>0</bitOffset>
              <bitWidth>6</bitWidth>
            </field>
          </fields>
        </register>
        <register>
          <name>RESP1</name>
          <addressOffset>0x14</addressOffset>
          <size>0x20</size>
          <fields>
            <field>
              <name>CARDSTATUS1</name>
              <bitOffset>0</bitOffset>
              <bitWidth>32</bitWidth>
            </field>
          </fields>
        </register>
        <register>
          <name>RESP2</name>
          <addressOffset>0x18</addressOffset>
          <size>0x20</size>
          <fields>
            <field>
              <name>CARDSTATUS2</name>
              <bitOffset>0</bitOffset>
              <bitWidth>32</bitWidth>
            </field>
          </fields>
        </register>
        <register>
          <name>RESP3</name>
          <addressOffset>0x1c</addressOffset>
          <size>0x20</size>
          <fields>
            <field>
              <name>CARDSTATUS3</name>
              <bitOffset>0</bitOffset>
              <bitWidth>32</bitWidth>
            </field>
          </fields>
        </register>
        <register>
          <name>RESP4</name>
          <addressOffset>0x20</addressOffset>
          <size>0x20</size>
          <fields>
            <field>
              <name>CARDSTATUS4</name>
              <bitOffset>0</bitOffset>
              <bitWidth>32</bitWidth>
            </field>
          </fields>
        </register>
        <register>
          <name>DTIMER</name>
          <addressOffset>0x24</addressOffset>
          <size>0x20</size>
          <fields>
            <field>
              <name>DATATIME</name>
              <bitOffset>0</bitOffset>
              <bitWidth>32</bitWidth>
            </field>
          </fields>
        </register>
        <register>
          <name>DLEN</name>
          <addressOffset>0x28</addressOffset>
          <size>0x20</size>
          <fields>
            <field>
              <name>DATALENGTH</name>
              <bitOffset>0</bitOffset>
              <bitWidth>25</bitWidth>
            </field>
          </fields>
        </register>
        <register>
          <name>DCTRL</name>
          <addressOffset>0x2c</addressOffset>
          <size>0x20</size>
          <fields>
            <field>
              <name>DTEN</name>
              <bitOffset>0</bitOffset>
              <bitWidth>1</bitWidth>
            </field>
            <field>
              <name>DTDIR</name>
              <bitOffset>1</bitOffset>
              <bitWidth>1</bitWidth>
            </field>
            <field>
              <name>DTMODE</name>
              <bitOffset>2</bitOffset>
              <bitWidth>1</bitWidth>
            </field>
            <field>
              <name>DMAEN</name>
              <bitOffset>3</bitOffset>
              <bitWidth>1</bitWidth>
            </field>
            <field>
              <name>DBLOCKSIZE</name>
              <bitOffset>4</bitOffset>
              <bitWidth>4</bitWidth>
            </field>
            <field>
              <name>RWSTART</name>
              <bitOffset>8</bitOffset>
              <bitWidth>1</bitWidth>
            </field>
            <field>
              <name>RWSTOP</name>
              <bitOffset>9</bitOffset>
              <bitWidth>1</bitWidth>
            </field>
            <field>
              <name>RWMOD</name>
              <bitOffset>10</bitOffset>
              <bitWidth>1</bitWidth>
            </field>
            <field>
              <name>SDIOEN</name>
              <bitOffset>11</bitOffset>
              <bitWidth>1</bitWidth>
            </field>
          </fields>
        </register>
        <register>
          <name>DCOUNT</name>
          <addressOffset>0x30</addressOffset>
          <size>0x20</size>
          <fields>
            <field>
              <name>DATACOUNT</name>
              <bitOffset>0</bitOffset>
              <bitWidth>25</bitWidth>
            </field>
          </fields>
        </register>
        <register>
          <name>STA</name>
          <addressOffset>0x34</addressOffset>
          <size>0x20</size>
          <fields>
            <field>
              <name>CCRCFAIL</name>
              <bitOffset>0</bitOffset>
              <bitWidth>1</bitWidth>
            </field>
            <field>
              <name>DCRCFAIL</name>
              <bitOffset>1</bitOffset>
              <bitWidth>1</bitWidth>
            </field>
            <field>
              <name>CTIMEOUT</name>
              <bitOffset>2</bitOffset>
              <bitWidth>1</bitWidth>
            </field>
            <field>
              <name>DTIMEOUT</name>
              <bitOffset>3</bitOffset>
              <bitWidth>1</bitWidth>
            </field>
            <field>
              <name>TXUNDERR</name>
              <bitOffset>4</bitOffset>
              <bitWidth>1</bitWidth>
            </field>
            <field>
              <name>RXOVERR</name>
              <bitOffset>5</bitOffset>
              <bitWidth>1</bitWidth>
            </field>
            <field>
              <name>CMDREND</name>
              <bitOffset>6</bitOffset>
              <bitWidth>1</bitWidth>
            </field>
            <field>
              <name>CMDSENT</name>
              <bitOffset>7</bitOffset>
              <bitWidth>1</bitWidth>
            </field>
            <field>
              <name>DATAEND</name>
              <bitOffset>8</bitOffset>
              <bitWidth>1</bitWidth>
            </field>
            <field>
              <name>STBITERR</name>
              <bitOffset>9</bitOffset>
              <bitWidth>1</bitWidth>
            </field>
            <field>
              <name>DBCKEND</name>
              <bitOffset>10</bitOffset>
              <bitWidth>1</bitWidth>
            </field>
            <field>
              <name>CMDACT</name>
              <bitOffset>11</bitOffset>
              <bitWidth>1</bitWidth>
            </field>
            <field>
              <name>TXACT</name>
              <bitOffset>12</bitOffset>
              <bitWidth>1</bitWidth>
            </field>
            <field>
              <name>RXACT</name>
              <bitOffset>13</bitOffset>
              <bitWidth>1</bitWidth>
            </field>
            <field>
              <name>TXFIFOHE</name>
              <bitOffset>14</bitOffset>
              <bitWidth>1</bitWidth>
            </field>
            <field>
              <name>RXFIFOHF</name>
              <bitOffset>15</bitOffset>
              <bitWidth>1</bitWidth>
            </field>
            <field>
              <name>TXFIFOF</name>
              <bitOffset>16</bitOffset>
              <bitWidth>1</bitWidth>
            </field>
            <field>
              <name>RXFIFOF</name>
              <bitOffset>17</bitOffset>
              <bitWidth>1</bitWidth>
            </field>
            <field>
              <name>TXFIFOE</name>
              <bitOffset>18</bitOffset>
              <bitWidth>1</bitWidth>
            </field>
            <field>
              <name>RXFIFOE</name>
              <bitOffset>19</bitOffset>
              <bitWidth>1</bitWidth>
            </field>
            <field>
              <name>TXDAVL</name>
              <bitOffset>20</bitOffset>
              <bitWidth>1</bitWidth>
            </field>
            <field>
              <name>RXDAVL</name>
              <bitOffset>21</bitOffset>
              <bitWidth>1</bitWidth>
            </field>
            <field>
              <name>SDIOIT</name>
              <bitOffset>22</bitOffset>
              <bitWidth>1</bitWidth>
            </field>
          </fields>
        </register>
        <register>
          <name>ICR</name>
          <addressOffset>0x38</addressOffset>
          <size>0x20</size>
          <fields>
            <field>
              <name>CCRCFAILC</name>
              <bitOffset>0</bitOffset>
              <bitWidth>1</bitWidth>
            </field>
            <field>
              <name>DCRCFAILC</name>
              <bitOffset>1</bitOffset>
              <bitWidth>1</bitWidth>
            </field>
            <field>
              <name>CTIMEOUTC</name>
              <bitOffset>2</bitOffset>
              <bitWidth>1</bitWidth>
            </field>
            <field>
              <name>DTIMEOUTC</name>
              <bitOffset>3</bitOffset>
              <bitWidth>1</bitWidth>
            </field>
            <field>
              <name>TXUNDERRC</name>
              <bitOffset>4</bitOffset>
              <bitWidth>1</bitWidth>
            </field>
            <field>
              <name>RXOVERRC</name>
              <bitOffset>5</bitOffset>
              <bitWidth>1</bitWidth>
            </field>
            <field>
              <name>CMDRENDC</name>
              <bitOffset>6</bitOffset>
              <bitWidth>1</bitWidth>
            </field>
            <field>
              <name>CMDSENTC</name>
              <bitOffset>7</bitOffset>
              <bitWidth>1</bitWidth>
            </field>
            <field>
              <name>DATAENDC</name>
              <bitOffset>8</bitOffset>
              <bitWidth>1</bitWidth>
            </field>
            <field>
              <name>STBITERRC</name>
              <bitOffset>9</bitOffset>
              <bitWidth>1</bitWidth>
            </field>
            <field>
              <name>DBCKENDC</name>
              <bitOffset>10</bitOffset>
              <bitWidth>1</bitWidth>
            </field>
            <field>
              <name>SDIOITC</name>
              <bitOffset>22</bitOffset>
              <bitWidth>1</bitWidth>
            </field>
          </fields>
        </register>
        <register>
          <name>MASK</name>
          <addressOffset>0x3c</addressOffset>
          <size>0x20</size>
          <fields>
            <field>
              <name>CCRCFAILIE</name>
              <bitOffset>0</bitOffset>
              <bitWidth>1</bitWidth>
            </field>
            <field>
              <name>DCRCFAILIE</name>
              <bitOffset>1</bitOffset>
              <bitWidth>1</bitWidth>
            </field>
            <field>
              <name>CTIMEOUTIE</name>
              <bitOffset>2</bitOffset>
              <bitWidth>1</bitWidth>
            </field>
            <field>
              <name>DTIMEOUTIE</name>
              <bitOffset>3</bitOffset>
              <bitWidth>1</bitWidth>
            </field>
            <field>
              <name>TXUNDERRIE</name>
              <bitOffset>4</bitOffset>
              <bitWidth>1</bitWidth>
            </field>
            <field>
              <name>RXOVERRIE</name>
              <bitOffset>5</bitOffset>
              <bitWidth>1</bitWidth>
            </field>
            <field>
              <name>CMDRENDIE</name>
              <bitOffset>6</bitOffset>
              <bitWidth>1</bitWidth>
            </field>
            <field>
              <name>CMDSENTIE</name>
              <bitOffset>7</bitOffset>
              <bitWidth>1</bitWidth>
            </field>
            <field>
              <name>DATAENDIE</name>
              <bitOffset>8</bitOffset>
              <bitWidth>1</bitWidth>
            </field>
            <field>
              <name>DBCKENDIE</name>
              <bitOffset>10</bitOffset>
              <bitWidth>1</bitWidth>
            </field>
            <field>
              <name>CMDACTIE</name>
              <bitOffset>11</bitOffset>
              <bitWidth>1</bitWidth>
            </field>
            <field>
              <name>TXACTIE</name>
              <bitOffset>12</bitOffset>
              <bitWidth>1</bitWidth>
            </field>
            <field>
              <name>RXACTIE</name>
              <bitOffset>13</bitOffset>
              <bitWidth>1</bitWidth>
            </field>
            <field>
              <name>TXFIFOHEIE</name>
              <bitOffset>14</bitOffset>
              <bitWidth>1</bitWidth>
            </field>
            <field>
              <name>RXFIFOHFIE</name>
              <bitOffset>15</bitOffset>
              <bitWidth>1</bitWidth>
            </field>
            <field>
              <name>TXFIFOFIE</name>
              <bitOffset>16</bitOffset>
              <bitWidth>1</bitWidth>
            </field>
            <field>
              <name>RXFIFOFIE</name>
              <bitOffset>17</bitOffset>
              <bitWidth>1</bitWidth>
            </field>
            <field>
              <name>TXFIFOEIE</name>
              <bitOffset>18</bitOffset>
              <bitWidth>1</bitWidth>
            </field>
            <field>
              <name>RXFIFOEIE</name>
              <bitOffset>19</bitOffset>
              <bitWidth>1</bitWidth>
            </field>
            <field>
              <name>TXDAVLIE</name>
              <bitOffset>20</bitOffset>
              <bitWidth>1</bitWidth>
            </field>
            <field>
              <name>RXDAVLIE</name>
              <bitOffset>21</bitOffset>
              <bitWidth>1</bitWidth>
            </field>
            <field>
              <name>SDIOITIE</name>
              <bitOffset>22</bitOffset>
              <bitWidth>1</bitWidth>
            </field>
          </fields>
        </register>
        <register>
          <name>FIFOCNT</name>
          <addressOffset>0x48</addressOffset>
          <size>0x20</size>
          <fields>
            <field>
              <name>FIFOCOUNT</name>
              <bitOffset>0</bitOffset>
              <bitWidth>24</bitWidth>
            </field>
          </fields>
        </register>
        <register>
          <name>FIFO</name>
          <addressOffset>0x80</addressOffset>
          <size>0x20</size>
          <fields>
            <field>
              <name>FIFODATA</name>
              <bitOffset>0</bitOffset>
              <bitWidth>32</bitWidth>
            </field>
          </fields>
        </register>
      </registers>
    </peripheral>
    <peripheral>
      <name>TIM1</name>
      <baseAddress>0x40012c00</baseAddress>
      <registers>
        <register>
          <name>CR1</name>
          <addressOffset>0x0</addressOffset>
          <size>0x20</size>
          <fields>
            <field>
              <name>CEN</name>
              <bitOffset>0</bitOffset>
              <bitWidth>1</bitWidth>
            </field>
            <field>
              <name>UDIS</name>
              <bitOffset>1</bitOffset>
              <bitWidth>1</bitWidth>
            </field>
            <field>
              <name>URS</name>
              <bitOffset>2</bitOffset>
              <bitWidth>1</bitWidth>
            </field>
            <field>
              <name>OPM</name>
              <bitOffset>3</bitOffset>
              <bitWidth>1</bitWidth>
            </field>
            <field>
              <name>DIR</name>
              <bitOffset>4</bitOffset>
              <bitWidth>1</bitWidth>
            </field>
            <field>
              <name>CMS</name>
              <bitOffset>5</bitOffset>
              <bitWidth>2</bitWidth>
            </field>
            <field>
              <name>ARPE</name>
              <bitOffset>7</bitOffset>
              <bitWidth>1</bitWidth>
            </field>
            <field>
              <name>CKD</name>
              <bitOffset>8</bitOffset>
              <bitWidth>2</bitWidth>
            </field>
            <field>
              <name>UIFREMAP</name>
              <bitOffset>11</bitOffset>
              <bitWidth>1</bitWidth>
            </field>
          </fields>
        </register>
        <register>
          <name>CR2</name>
          <addressOffset>0x4</addressOffset>
          <size>0x20</size>
          <fields>
            <field>
              <name>CCPC</name>
              <bitOffset>0</bitOffset>
              <bitWidth>1</bitWidth>
            </field>
            <field>
              <name>CCUS</name>
              <bitOffset>2</bitOffset>
              <bitWidth>1</bitWidth>
            </field>
            <field>
              <name>CCDS</name>
              <bitOffset>3</bitOffset>
              <bitWidth>1</bitWidth>
            </field>
            <field>
              <name>MMS</name>
              <bitOffset>4</bitOffset>
              <bitWidth>3</bitWidth>
            </field>
            <field>
              <name>TI1S</name>
              <bitOffset>7</bitOffset>
              <bitWidth>1</bitWidth>
            </field>
            <field>
              <name>OIS1</name>
              <bitOffset>8</bitOffset>
              <bitWidth>1</bitWidth>
            </field>
            <field>
              <name>OIS1N</name>
              <bitOffset>9</bitOffset>
              <bitWidth>1</bitWidth>
            </field>
            <field>
              <name>OIS2</name>
              <bitOffset>10</bitOffset>
              <bitWidth>1</bitWidth>
            </field>
            <field>
              <name>OIS2N</name>
              <bitOffset>11</bitOffset>
              <bitWidth>1</bitWidth>
            </field>
            <field>
              <name>OIS3</name>
              <bitOffset>12</bitOffset>
              <bitWidth>1</bitWidth>
            </field>
            <field>
              <name>OIS3N</name>
              <bitOffset>13</bitOffset>
              <bitWidth>1</bitWidth>
            </field>
            <field>
              <name>OIS4</name>
              <bitOffset>14</bitOffset>
              <bitWidth>1</bitWidth>
            </field>
            <field>
              <name>OIS5</name>
              <bitOffset>16</bitOffset>
              <bitWidth>1</bitWidth>
            </field>
            <field>
              <name>OIS6</name>
              <bitOffset>18</bitOffset>
              <bitWidth>1</bitWidth>
            </field>
            <field>
              <name>MMS2</name>
              <bitOffset>20</bitOffset>
              <bitWidth>4</bitWidth>
            </field>
          </fields>
        </register>
        <register>
          <name>SMCR</name>
          <addressOffset>0x8</addressOffset>
          <size>0x20</size>
          <fields>
            <field>
              <name>SMS</name>
              <bitOffset>0</bitOffset>
              <bitWidth>17</bitWidth>
            </field>
            <field>
              <name>OCCS</name>
              <bitOffset>3</bitOffset>
              <bitWidth>1</bitWidth>
            </field>
            <field>
              <name>TS</name>
              <bitOffset>4</bitOffset>
              <bitWidth>3</bitWidth>
            </field>
            <field>
              <name>MSM</name>
              <bitOffset>7</bitOffset>
              <bitWidth>1</bitWidth>
            </field>
            <field>
              <name>ETF</name>
              <bitOffset>8</bitOffset>
              <bitWidth>4</bitWidth>
            </field>
            <field>
              <name>ETPS</name>
              <bitOffset>12</bitOffset>
              <bitWidth>2</bitWidth>
            </field>
            <field>
              <name>ECE</name>
              <bitOffset>14</bitOffset>
              <bitWidth>1</bitWidth>
            </field>
            <field>
              <name>ETP</name>
              <bitOffset>15</bitOffset>
              <bitWidth>1</bitWidth>
            </field>
          </fields>
        </register>
        <register>
          <name>DIER</name>
          <addressOffset>0xc</addressOffset>
          <size>0x20</size>
          <fields>
            <field>
              <name>UIE</name>
              <bitOffset>0</bitOffset>
              <bitWidth>1</bitWidth>
            </field>
            <field>
              <name>CC1IE</name>
              <bitOffset>1</bitOffset>
              <bitWidth>1</bitWidth>
            </field>
            <field>
              <name>CC2IE</name>
              <bitOffset>2</bitOffset>
              <bitWidth>1</bitWidth>
            </field>
            <field>
              <name>CC3IE</name>
              <bitOffset>3</bitOffset>
              <bitWidth>1</bitWidth>
            </field>
            <field>
              <name>CC4IE</name>
              <bitOffset>4</bitOffset>
              <bitWidth>1</bitWidth>
            </field>
            <field>
              <name>COMIE</name>
              <bitOffset>5</bitOffset>
              <bitWidth>1</bitWidth>
            </field>
            <field>
              <name>TIE</name>
              <bitOffset>6</bitOffset>
              <bitWidth>1</bitWidth>
            </field>
            <field>
              <name>BIE</name>
              <bitOffset>7</bitOffset>
              <bitWidth>1</bitWidth>
            </field>
            <field>
              <name>UDE</name>
              <bitOffset>8</bitOffset>
              <bitWidth>1</bitWidth>
            </field>
            <field>
              <name>CC1DE</name>
              <bitOffset>9</bitOffset>
              <bitWidth>1</bitWidth>
            </field>
            <field>
              <name>CC2DE</name>
              <bitOffset>10</bitOffset>
              <bitWidth>1</bitWidth>
            </field>
            <field>
              <name>CC3DE</name>
              <bitOffset>11</bitOffset>
              <bitWidth>1</bitWidth>
            </field>
            <field>
              <name>CC4DE</name>
              <bitOffset>12</bitOffset>
              <bitWidth>1</bitWidth>
            </field>
            <field>
              <name>COMDE</name>
              <bitOffset>13</bitOffset>
              <bitWidth>1</bitWidth>
            </field>
            <field>
              <name>TDE</name>
              <bitOffset>14</bitOffset>
              <bitWidth>1</bitWidth>
            </field>
          </fields>
        </register>
        <register>
          <name>SR</name>
          <addressOffset>0x10</addressOffset>
          <size>0x20</size>
          <fields>
            <field>
              <name>UIF</name>
              <bitOffset>0</bitOffset>
              <bitWidth>1</bitWidth>
            </field>
            <field>
              <name>CC1IF</name>
              <bitOffset>1</bitOffset>
              <bitWidth>1</bitWidth>
            </field>
            <field>
              <name>CC2IF</name>
              <bitOffset>2</bitOffset>
              <bitWidth>1</bitWidth>
            </field>
            <field>
              <name>CC3IF</name>
              <bitOffset>3</bitOffset>
              <bitWidth>1</bitWidth>
            </field>
            <field>
              <name>CC4IF</name>
              <bitOffset>4</bitOffset>
              <bitWidth>1</bitWidth>
            </field>
            <field>
              <name>COMIF</name>
              <bitOffset>5</bitOffset>
              <bitWidth>1</bitWidth>
            </field>
            <field>
              <name>TIF</name>
              <bitOffset>6</bitOffset>
              <bitWidth>1</bitWidth>
            </field>
            <field>
              <name>BIF</name>
              <bitOffset>7</bitOffset>
              <bitWidth>1</bitWidth>
            </field>
            <field>
              <name>B2IF</name>
              <bitOffset>8</bitOffset>
              <bitWidth>1</bitWidth>
            </field>
            <field>
              <name>CC1OF</name>
              <bitOffset>9</bitOffset>
              <bitWidth>1</bitWidth>
            </field>
            <field>
              <name>CC2OF</name>
              <bitOffset>10</bitOffset>
              <bitWidth>1</bitWidth>
            </field>
            <field>
              <name>CC3OF</name>
              <bitOffset>11</bitOffset>
              <bitWidth>1</bitWidth>
            </field>
            <field>
              <name>CC4OF</name>
              <bitOffset>12</bitOffset>
              <bitWidth>1</bitWidth>
            </field>
            <field>
              <name>SBIF</name>
              <bitOffset>13</bitOffset>
              <bitWidth>1</bitWidth>
            </field>
            <field>
              <name>CC5IF</name>
              <bitOffset>16</bitOffset>
              <bitWidth>1</bitWidth>
            </field>
            <field>
              <name>CC6IF</name>
              <bitOffset>17</bitOffset>
              <bitWidth>1</bitWidth>
            </field>
          </fields>
        </register>
        <register>
          <name>EGR</name>
          <addressOffset>0x14</addressOffset>
          <size>0x20</size>
          <fields>
            <field>
              <name>UG</name>
              <bitOffset>0</bitOffset>
              <bitWidth>1</bitWidth>
            </field>
            <field>
              <name>CC1G</name>
              <bitOffset>1</bitOffset>
              <bitWidth>1</bitWidth>
            </field>
            <field>
              <name>CC2G</name>
              <bitOffset>2</bitOffset>
              <bitWidth>1</bitWidth>
            </field>
            <field>
              <name>CC3G</name>
              <bitOffset>3</bitOffset>
              <bitWidth>1</bitWidth>
            </field>
            <field>
              <name>CC4G</name>
              <bitOffset>4</bitOffset>
              <bitWidth>1</bitWidth>
            </field>
            <field>
              <name>COMG</name>
              <bitOffset>5</bitOffset>
              <bitWidth>1</bitWidth>
            </field>
            <field>
              <name>TG</name>
              <bitOffset>6</bitOffset>
              <bitWidth>1</bitWidth>
            </field>
            <field>
              <name>BG</name>
              <bitOffset>7</bitOffset>
              <bitWidth>1</bitWidth>
            </field>
            <field>
              <name>B2G</name>
              <bitOffset>8</bitOffset>
              <bitWidth>1</bitWidth>
            </field>
          </fields>
        </register>
        <register>
          <name>CCMR1</name>
          <addressOffset>0x18</addressOffset>
          <size>0x20</size>
          <fields>
            <field>
              <name>CC1S</name>
              <bitOffset>0</bitOffset>
              <bitWidth>2</bitWidth>
            </field>
            <field>
              <name>OC1FE</name>
              <bitOffset>2</bitOffset>
              <bitWidth>1</bitWidth>
            </field>
            <field>
              <name>OC1PE</name>
              <bitOffset>3</bitOffset>
              <bitWidth>1</bitWidth>
            </field>
            <field>
              <name>OC1M</name>
              <bitOffset>4</bitOffset>
              <bitWidth>13</bitWidth>
            </field>
            <field>
              <name>OC1CE</name>
              <bitOffset>7</bitOffset>
              <bitWidth>1</bitWidth>
            </field>
            <field>
              <name>CC2S</name>
              <bitOffset>8</bitOffset>
              <bitWidth>2</bitWidth>
            </field>
            <field>
              <name>OC2FE</name>
              <bitOffset>10</bitOffset>
              <bitWidth>1</bitWidth>
            </field>
            <field>
              <name>OC2PE</name>
              <bitOffset>11</bitOffset>
              <bitWidth>1</bitWidth>
            </field>
            <field>
              <name>OC2M</name>
              <bitOffset>12</bitOffset>
              <bitWidth>13</bitWidth>
            </field>
            <field>
              <name>OC2CE</name>
              <bitOffset>15</bitOffset>
              <bitWidth>1</bitWidth>
            </field>
          </fields>
        </register>
        <register>
          <name>CCMR2</name>
          <addressOffset>0x1c</addressOffset>
          <size>0x20</size>
          <fields>
            <field>
              <name>CC3S</name>
              <bitOffset>0</bitOffset>
              <bitWidth>2</bitWidth>
            </field>
            <field>
              <name>OC3FE</name>
              <bitOffset>2</bitOffset>
              <bitWidth>1</bitWidth>
            </field>
            <field>
              <name>OC3PE</name>
              <bitOffset>3</bitOffset>
              <bitWidth>1</bitWidth>
            </field>
            <field>
              <name>OC3M</name>
              <bitOffset>4</bitOffset>
              <bitWidth>13</bitWidth>
            </field>
            <field>
              <name>OC3CE</name>
              <bitOffset>7</bitOffset>
              <bitWidth>1</bitWidth>
            </field>
            <field>
              <name>CC4S</name>
              <bitOffset>8</bitOffset>
              <bitWidth>2</bitWidth>
            </field>
            <field>
              <name>OC4FE</name>
              <bitOffset>10</bitOffset>
              <bitWidth>1</bitWidth>
            </field>
            <field>
              <name>OC4PE</name>
              <bitOffset>11</bitOffset>
              <bitWidth>1</bitWidth>
            </field>
            <field>
              <name>OC4M</name>
              <bitOffset>12</bitOffset>
              <bitWidth>13</bitWidth>
            </field>
            <field>
              <name>OC4CE</name>
              <bitOffset>15</bitOffset>
              <bitWidth>1</bitWidth>
            </field>
          </fields>
        </register>
        <register>
          <name>CCER</name>
          <addressOffset>0x20</addressOffset>
          <size>0x20</size>
          <fields>
            <field>
              <name>CC1E</name>
              <bitOffset>0</bitOffset>
              <bitWidth>1</bitWidth>
            </field>
            <field>
              <name>CC1P</name>
              <bitOffset>1</bitOffset>
              <bitWidth>1</bitWidth>
            </field>
            <field>
              <name>CC1NE</name>
              <bitOffset>2</bitOffset>
              <bitWidth>1</bitWidth>
            </field>
            <field>
              <name>CC1NP</name>
              <bitOffset>3</bitOffset>
              <bitWidth>1</bitWidth>
            </field>
            <field>
              <name>CC2E</name>
              <bitOffset>4</bitOffset>
              <bitWidth>1</bitWidth>
            </field>
            <field>
              <name>CC2P</name>
              <bitOffset>5</bitOffset>
              <bitWidth>1</bitWidth>
            </field>
            <field>
              <name>CC2NE</name>
              <bitOffset>6</bitOffset>
              <bitWidth>1</bitWidth>
            </field>
            <field>
              <name>CC2NP</name>
              <bitOffset>7</bitOffset>
              <bitWidth>1</bitWidth>
            </field>
            <field>
              <name>CC3E</name>
              <bitOffset>8</bitOffset>
              <bitWidth>1</bitWidth>
            </field>
            <field>
              <name>CC3P</name>
              <bitOffset>9</bitOffset>
              <bitWidth>1</bitWidth>
            </field>
            <field>
              <name>CC3NE</name>
              <bitOffset>10</bitOffset>
              <bitWidth>1</bitWidth>
            </field>
            <field>
              <name>CC3NP</name>
              <bitOffset>11</bitOffset>
              <bitWidth>1</bitWidth>
            </field>
            <field>
              <name>CC4E</name>
              <bitOffset>12</bitOffset>
              <bitWidth>1</bitWidth>
            </field>
            <field>
              <name>CC4P</name>
              <bitOffset>13</bitOffset>
              <bitWidth>1</bitWidth>
            </field>
            <field>
              <name>CC4NP</name>
              <bitOffset>15</bitOffset>
              <bitWidth>1</bitWidth>
            </field>
            <field>
              <name>CC5E</name>
              <bitOffset>16</bitOffset>
              <bitWidth>1</bitWidth>
            </field>
            <field>
              <name>CC5P</name>
              <bitOffset>17</bitOffset>
              <bitWidth>1</bitWidth>
            </field>
            <field>
              <name>CC6E</name>
              <bitOffset>20</bitOffset>
              <bitWidth>1</bitWidth>
            </field>
            <field>
              <name>CC6P</name>
              <bitOffset>21</bitOffset>
              <bitWidth>1</bitWidth>
            </field>
          </fields>
        </register>
        <register>
          <name>CNT</name>
          <addressOffset>0x24</addressOffset>
          <size>0x20</size>
          <fields>
            <field>
              <name>CNT</name>
              <bitOffset>0</bitOffset>
              <bitWidth>32</bitWidth>
            </field>
            <field>
              <name>UIFCPY</name>
              <bitOffset>31</bitOffset>
              <bitWidth>1</bitWidth>
            </field>
          </fields>
        </register>
        <register>
          <name>PSC</name>
          <addressOffset>0x28</addressOffset>
          <size>0x20</size>
          <fields>
            <field>
              <name>PSC</name>
              <bitOffset>0</bitOffset>
              <bitWidth>16</bitWidth>
            </field>
          </fields>
        </register>
        <register>
          <name>ARR</name>
          <addressOffset>0x2c</addressOffset>
          <size>0x20</size>
          <fields>
            <field>
              <name>ARR</name>
              <bitOffset>0</bitOffset>
              <bitWidth>32</bitWidth>
            </field>
          </fields>
        </register>
        <register>
          <name>RCR</name>
          <addressOffset>0x30</addressOffset>
          <size>0x20</size>
          <fields>
            <field>
              <name>REP</name>
              <bitOffset>0</bitOffset>
              <bitWidth>16</bitWidth>
            </field>
          </fields>
        </register>
        <register>
          <name>CCR1</name>
          <addressOffset>0x34</addressOffset>
          <size>0x20</size>
          <fields>
            <field>
              <name>CCR1</name>
              <bitOffset>0</bitOffset>
              <bitWidth>16</bitWidth>
            </field>
          </fields>
        </register>
        <register>
          <name>CCR2</name>
          <addressOffset>0x38</addressOffset>
          <size>0x20</size>
          <fields>
            <field>
              <name>CCR2</name>
              <bitOffset>0</bitOffset>
              <bitWidth>16</bitWidth>
            </field>
          </fields>
        </register>
        <register>
          <name>CCR3</name>
          <addressOffset>0x3c</addressOffset>
          <size>0x20</size>
          <fields>
            <field>
              <name>CCR3</name>
              <bitOffset>0</bitOffset>
              <bitWidth>16</bitWidth>
            </field>
          </fields>
        </register>
        <register>
          <name>CCR4</name>
          <addressOffset>0x40</addressOffset>
          <size>0x20</size>
          <fields>
            <field>
              <name>CCR4</name>
              <bitOffset>0</bitOffset>
              <bitWidth>16</bitWidth>
            </field>
          </fields>
        </register>
        <register>
          <name>BDTR</name>
          <addressOffset>0x44</addressOffset>
          <size>0x20</size>
          <fields>
            <field>
              <name>DTG</name>
              <bitOffset>0</bitOffset>
              <bitWidth>8</bitWidth>
            </field>
            <field>
              <name>LOCK</name>
              <bitOffset>8</bitOffset>
              <bitWidth>2</bitWidth>
            </field>
            <field>
              <name>OSSI</name>
              <bitOffset>10</bitOffset>
              <bitWidth>1</bitWidth>
            </field>
            <field>
              <name>OSSR</name>
              <bitOffset>11</bitOffset>
              <bitWidth>1</bitWidth>
            </field>
            <field>
              <name>BKE</name>
              <bitOffset>12</bitOffset>
              <bitWidth>1</bitWidth>
            </field>
            <field>
              <name>BKP</name>
              <bitOffset>13</bitOffset>
              <bitWidth>1</bitWidth>
            </field>
            <field>
              <name>AOE</name>
              <bitOffset>14</bitOffset>
              <bitWidth>1</bitWidth>
            </field>
            <field>
              <name>MOE</name>
              <bitOffset>15</bitOffset>
              <bitWidth>1</bitWidth>
            </field>
            <field>
              <name>BKF</name>
              <bitOffset>16</bitOffset>
              <bitWidth>4</bitWidth>
            </field>
            <field>
              <name>BK2F</name>
              <bitOffset>20</bitOffset>
              <bitWidth>4</bitWidth>
            </field>
            <field>
              <name>BK2E</name>
              <bitOffset>24</bitOffset>
              <bitWidth>1</bitWidth>
            </field>
            <field>
              <name>BK2P</name>
              <bitOffset>25</bitOffset>
              <bitWidth>1</bitWidth>
            </field>
          </fields>
        </register>
        <register>
          <name>DCR</name>
          <addressOffset>0x48</addressOffset>
          <size>0x20</size>
          <fields>
            <field>
              <name>DBA</name>
              <bitOffset>0</bitOffset>
              <bitWidth>5</bitWidth>
            </field>
            <field>
              <name>DBL</name>
              <bitOffset>8</bitOffset>
              <bitWidth>5</bitWidth>
            </field>
          </fields>
        </register>
        <register>
          <name>DMAR</name>
          <addressOffset>0x4c</addressOffset>
          <size>0x20</size>
          <fields>
            <field>
              <name>DMAB</name>
              <bitOffset>0</bitOffset>
              <bitWidth>16</bitWidth>
            </field>
          </fields>
        </register>
        <register>
          <name>OR1</name>
          <addressOffset>0x50</addressOffset>
          <size>0x20</size>
        </register>
        <register>
          <name>CCMR3</name>
          <addressOffset>0x54</addressOffset>
          <size>0x20</size>
          <fields>
            <field>
              <name>OC5FE</name>
              <bitOffset>2</bitOffset>
              <bitWidth>1</bitWidth>
            </field>
            <field>
              <name>OC5PE</name>
              <bitOffset>3</bitOffset>
              <bitWidth>1</bitWidth>
            </field>
            <field>
              <name>OC5M</name>
              <bitOffset>4</bitOffset>
              <bitWidth>13</bitWidth>
            </field>
            <field>
              <name>OC5CE</name>
              <bitOffset>7</bitOffset>
              <bitWidth>1</bitWidth>
            </field>
            <field>
              <name>OC6FE</name>
              <bitOffset>10</bitOffset>
              <bitWidth>1</bitWidth>
            </field>
            <field>
              <name>OC6PE</name>
              <bitOffset>11</bitOffset>
              <bitWidth>1</bitWidth>
            </field>
            <field>
              <name>OC6M</name>
              <bitOffset>12</bitOffset>
              <bitWidth>13</bitWidth>
            </field>
            <field>
              <name>OC6CE</name>
              <bitOffset>15</bitOffset>
              <bitWidth>1</bitWidth>
            </field>
          </fields>
        </register>
        <register>
          <name>CCR5</name>
          <addressOffset>0x58</addressOffset>
          <size>0x20</size>
          <fields>
            <field>
              <name>CCR5</name>
              <bitOffset>0</bitOffset>
              <bitWidth>32</bitWidth>
            </field>
            <field>
              <name>GC5C1</name>
              <bitOffset>29</bitOffset>
              <bitWidth>1</bitWidth>
            </field>
            <field>
              <name>GC5C2</name>
              <bitOffset>30</bitOffset>
              <bitWidth>1</bitWidth>
            </field>
            <field>
              <name>GC5C3</name>
              <bitOffset>31</bitOffset>
              <bitWidth>1</bitWidth>
            </field>
          </fields>
        </register>
        <register>
          <name>CCR6</name>
          <addressOffset>0x5c</addressOffset>
          <size>0x20</size>
          <fields>
            <field>
              <name>CCR6</name>
              <bitOffset>0</bitOffset>
              <bitWidth>16</bitWidth>
            </field>
          </fields>
        </register>
        <register>
          <name>OR2</name>
          <addressOffset>0x60</addressOffset>
          <size>0x20</size>
        </register>
        <register>
          <name>OR3</name>
          <addressOffset>0x64</addressOffset>
          <size>0x20</size>
        </register>
      </registers>
    </peripheral>
    <peripheral>
      <name>SPI1</name>
      <baseAddress>0x40013000</baseAddress>
      <registers>
        <register>
          <name>CR1</name>
          <addressOffset>0x0</addressOffset>
          <size>0x20</size>
          <fields>
            <field>
              <name>CPHA</name>
              <bitOffset>0</bitOffset>
              <bitWidth>1</bitWidth>
            </field>
            <field>
              <name>CPOL</name>
              <bitOffset>1</bitOffset>
              <bitWidth>1</bitWidth>
            </field>
            <field>
              <name>MSTR</name>
              <bitOffset>2</bitOffset>
              <bitWidth>1</bitWidth>
            </field>
            <field>
              <name>BR</name>
              <bitOffset>3</bitOffset>
              <bitWidth>3</bitWidth>
            </field>
            <field>
              <name>SPE</name>
              <bitOffset>6</bitOffset>
              <bitWidth>1</bitWidth>
            </field>
            <field>
              <name>LSBFIRST</name>
              <bitOffset>7</bitOffset>
              <bitWidth>1</bitWidth>
            </field>
            <field>
              <name>SSI</name>
              <bitOffset>8</bitOffset>
              <bitWidth>1</bitWidth>
            </field>
            <field>
              <name>SSM</name>
              <bitOffset>9</bitOffset>
              <bitWidth>1</bitWidth>
            </field>
            <field>
              <name>RXONLY</name>
              <bitOffset>10</bitOffset>
              <bitWidth>1</bitWidth>
            </field>
            <field>
              <name>CRCL</name>
              <bitOffset>11</bitOffset>
              <bitWidth>1</bitWidth>
            </field>
            <field>
              <name>CRCNEXT</name>
              <bitOffset>12</bitOffset>
              <bitWidth>1</bitWidth>
            </field>
            <field>
              <name>CRCEN</name>
              <bitOffset>13</bitOffset>
              <bitWidth>1</bitWidth>
            </field>
            <field>
              <name>BIDIOE</name>
              <bitOffset>14</bitOffset>
              <bitWidth>1</bitWidth>
            </field>
            <field>
              <name>BIDIMODE</name>
              <bitOffset>15</bitOffset>
              <bitWidth>1</bitWidth>
            </field>
          </fields>
        </register>
        <register>
          <name>CR2</name>
          <addressOffset>0x4</addressOffset>
          <size>0x20</size>
          <fields>
            <field>
              <name>RXDMAEN</name>
              <bitOffset>0</bitOffset>
              <bitWidth>1</bitWidth>
            </field>
            <field>
              <name>TXDMAEN</name>
              <bitOffset>1</bitOffset>
              <bitWidth>1</bitWidth>
            </field>
            <field>
              <name>SSOE</name>
              <bitOffset>2</bitOffset>
              <bitWidth>1</bitWidth>
            </field>
            <field>
              <name>NSSP</name>
              <bitOffset>3</bitOffset>
              <bitWidth>1</bitWidth>
            </field>
            <field>
              <name>FRF</name>
              <bitOffset>4</bitOffset>
              <bitWidth>1</bitWidth>
            </field>
            <field>
              <name>ERRIE</name>
              <bitOffset>5</bitOffset>
              <bitWidth>1</bitWidth>
            </field>
            <field>
              <name>RXNEIE</name>
              <bitOffset>6</bitOffset>
              <bitWidth>1</bitWidth>
            </field>
            <field>
              <name>TXEIE</name>
              <bitOffset>7</bitOffset>
              <bitWidth>1</bitWidth>
            </field>
            <field>
              <name>DS</name>
              <bitOffset>8</bitOffset>
              <bitWidth>4</bitWidth>
            </field>
            <field>
              <name>FRXTH</name>
              <bitOffset>12</bitOffset>
              <bitWidth>1</bitWidth>
            </field>
            <field>
              <name>LDMARX</name>
              <bitOffset>13</bitOffset>
              <bitWidth>1</bitWidth>
            </field>
            <field>
              <name>LDMATX</name>
              <bitOffset>14</bitOffset>
              <bitWidth>1</bitWidth>
            </field>
          </fields>
        </register>
        <register>
          <name>SR</name>
          <addressOffset>0x8</addressOffset>
          <size>0x20</size>
          <fields>
            <field>
              <name>RXNE</name>
              <bitOffset>0</bitOffset>
              <bitWidth>1</bitWidth>
            </field>
            <field>
              <name>TXE</name>
              <bitOffset>1</bitOffset>
              <bitWidth>1</bitWidth>
            </field>
            <field>
              <name>CHSIDE</name>
              <bitOffset>2</bitOffset>
              <bitWidth>1</bitWidth>
            </field>
            <field>
              <name>UDR</name>
              <bitOffset>3</bitOffset>
              <bitWidth>1</bitWidth>
            </field>
            <field>
              <name>CRCERR</name>
              <bitOffset>4</bitOffset>
              <bitWidth>1</bitWidth>
            </field>
            <field>
              <name>MODF</name>
              <bitOffset>5</bitOffset>
              <bitWidth>1</bitWidth>
            </field>
            <field>
              <name>OVR</name>
              <bitOffset>6</bitOffset>
              <bitWidth>1</bitWidth>
            </field>
            <field>
              <name>BSY</name>
              <bitOffset>7</bitOffset>
              <bitWidth>1</bitWidth>
            </field>
            <field>
              <name>FRE</name>
              <bitOffset>8</bitOffset>
              <bitWidth>1</bitWidth>
            </field>
            <field>
              <name>FRLVL</name>
              <bitOffset>9</bitOffset>
              <bitWidth>2</bitWidth>
            </field>
            <field>
              <name>FTLVL</name>
              <bitOffset>11</bitOffset>
              <bitWidth>2</bitWidth>
            </field>
          </fields>
        </register>
        <register>
          <name>DR</name>
          <addressOffset>0xc</addressOffset>
          <size>0x20</size>
          <fields>
            <field>
              <name>DR</name>
              <bitOffset>0</bitOffset>
              <bitWidth>16</bitWidth>
            </field>
          </fields>
        </register>
        <register>
          <name>CRCPR</name>
          <addressOffset>0x10</addressOffset>
          <size>0x20</size>
          <fields>
            <field>
              <name>CRCPOLY</name>
              <bitOffset>0</bitOffset>
              <bitWidth>16</bitWidth>
            </field>
          </fields>
        </register>
        <register>
          <name>RXCRCR</name>
          <addressOffset>0x14</addressOffset>
          <size>0x20</size>
          <fields>
            <field>
              <name>RXCRC</name>
              <bitOffset>0</bitOffset>
              <bitWidth>16</bitWidth>
            </field>
          </fields>
        </register>
        <register>
          <name>TXCRCR</name>
          <addressOffset>0x18</addressOffset>
          <size>0x20</size>
          <fields>
            <field>
              <name>TXCRC</name>
              <bitOffset>0</bitOffset>
              <bitWidth>16</bitWidth>
            </field>
          </fields>
        </register>
      </registers>
    </peripheral>
    <peripheral>
      <name>USART1</name>
      <baseAddress>0x40013800</baseAddress>
      <registers>
        <register>
          <name>CR1</name>
          <addressOffset>0x0</addressOffset>
          <size>0x20</size>
          <fields>
            <field>
              <name>UE</name>
              <bitOffset>0</bitOffset>
              <bitWidth>1</bitWidth>
            </field>
            <field>
              <name>UESM</name>
              <bitOffset>1</bitOffset>
              <bitWidth>1</bitWidth>
            </field>
            <field>
              <name>RE</name>
              <bitOffset>2</bitOffset>
              <bitWidth>1</bitWidth>
            </field>
            <field>
              <name>TE</name>
              <bitOffset>3</bitOffset>
              <bitWidth>1</bitWidth>
            </field>
            <field>
              <name>IDLEIE</name>
              <bitOffset>4</bitOffset>
              <bitWidth>1</bitWidth>
            </field>
            <field>
              <name>RXNEIE</name>
              <bitOffset>5</bitOffset>
              <bitWidth>1</bitWidth>
            </field>
            <field>
              <name>TCIE</name>
              <bitOffset>6</bitOffset>
              <bitWidth>1</bitWidth>
            </field>
            <field>
              <name>TXEIE</name>
              <bitOffset>7</bitOffset>
              <bitWidth>1</bitWidth>
            </field>
            <field>
              <name>PEIE</name>
              <bitOffset>8</bitOffset>
              <bitWidth>1</bitWidth>
            </field>
            <field>
              <name>PS</name>
              <bitOffset>9</bitOffset>
              <bitWidth>1</bitWidth>
            </field>
            <field>
              <name>PCE</name>
              <bitOffset>10</bitOffset>
              <bitWidth>1</bitWidth>
            </field>
            <field>
              <name>WAKE</name>
              <bitOffset>11</bitOffset>
              <bitWidth>1</bitWidth>
            </field>
            <field>
              <name>M0</name>
              <bitOffset>12</bitOffset>
              <bitWidth>1</bitWidth>
            </field>
            <field>
              <name>MME</name>
              <bitOffset>13</bitOffset>
              <bitWidth>1</bitWidth>
            </field>
            <field>
              <name>CMIE</name>
              <bitOffset>14</bitOffset>
              <bitWidth>1</bitWidth>
            </field>
            <field>
              <name>OVER8</name>
              <bitOffset>15</bitOffset>
              <bitWidth>1</bitWidth>
            </field>
            <field>
              <name>DEDT</name>
              <bitOffset>16</bitOffset>
              <bitWidth>5</bitWidth>
            </field>
            <field>
              <name>DEAT</name>
              <bitOffset>21</bitOffset>
              <bitWidth>5</bitWidth>
            </field>
            <field>
              <name>RTOIE</name>
              <bitOffset>26</bitOffset>
              <bitWidth>1</bitWidth>
            </field>
            <field>
              <name>EOBIE</name>
              <bitOffset>27</bitOffset>
              <bitWidth>1</bitWidth>
            </field>
            <field>
              <name>M1</name>
              <bitOffset>28</bitOffset>
              <bitWidth>1</bitWidth>
            </field>
          </fields>
        </register>
        <register>
          <name>CR2</name>
          <addressOffset>0x4</addressOffset>
          <size>0x20</size>
          <fields>
            <field>
              <name>ADDM7</name>
              <bitOffset>4</bitOffset>
              <bitWidth>1</bitWidth>
            </field>
            <field>
              <name>LBDL</name>
              <bitOffset>5</bitOffset>
              <bitWidth>1</bitWidth>
            </field>
            <field>
              <name>LBDIE</name>
              <bitOffset>6</bitOffset>
              <bitWidth>1</bitWidth>
            </field>
            <field>
              <name>LBCL</name>
              <bitOffset>8</bitOffset>
              <bitWidth>1</bitWidth>
            </field>
            <field>
              <name>CPHA</name>
              <bitOffset>9</bitOffset>
              <bitWidth>1</bitWidth>
            </field>
            <field>
              <name>CPOL</name>
              <bitOffset>10</bitOffset>
              <bitWidth>1</bitWidth>
            </field>
            <field>
              <name>CLKEN</name>
              <bitOffset>11</bitOffset>
              <bitWidth>1</bitWidth>
            </field>
            <field>
              <name>STOP</name>
              <bitOffset>12</bitOffset>
              <bitWidth>2</bitWidth>
            </field>
            <field>
              <name>LINEN</name>
              <bitOffset>14</bitOffset>
              <bitWidth>1</bitWidth>
            </field>
            <field>
              <name>SWAP</name>
              <bitOffset>15</bitOffset>
              <bitWidth>1</bitWidth>
            </field>
            <field>
              <name>RXINV</name>
              <bitOffset>16</bitOffset>
              <bitWidth>1</bitWidth>
            </field>
            <field>
              <name>TXINV</name>
              <bitOffset>17</bitOffset>
              <bitWidth>1</bitWidth>
            </field>
            <field>
              <name>DATAINV</name>
              <bitOffset>18</bitOffset>
              <bitWidth>1</bitWidth>
            </field>
            <field>
              <name>MSBFIRST</name>
              <bitOffset>19</bitOffset>
              <bitWidth>1</bitWidth>
            </field>
            <field>
              <name>ABREN</name>
              <bitOffset>20</bitOffset>
              <bitWidth>1</bitWidth>
            </field>
            <field>
              <name>ABRMODE</name>
              <bitOffset>21</bitOffset>
              <bitWidth>2</bitWidth>
            </field>
            <field>
              <name>RTOEN</name>
              <bitOffset>23</bitOffset>
              <bitWidth>1</bitWidth>
            </field>
            <field>
              <name>ADD</name>
              <bitOffset>24</bitOffset>
              <bitWidth>8</bitWidth>
            </field>
          </fields>
        </register>
        <register>
          <name>CR3</name>
          <addressOffset>0x8</addressOffset>
          <size>0x20</size>
          <fields>
            <field>
              <name>EIE</name>
              <bitOffset>0</bitOffset>
              <bitWidth>1</bitWidth>
            </field>
            <field>
              <name>IREN</name>
              <bitOffset>1</bitOffset>
              <bitWidth>1</bitWidth>
            </field>
            <field>
              <name>IRLP</name>
              <bitOffset>2</bitOffset>
              <bitWidth>1</bitWidth>
            </field>
            <field>
              <name>HDSEL</name>
              <bitOffset>3</bitOffset>
              <bitWidth>1</bitWidth>
            </field>
            <field>
              <name>NACK</name>
              <bitOffset>4</bitOffset>
              <bitWidth>1</bitWidth>
            </field>
            <field>
              <name>SCEN</name>
              <bitOffset>5</bitOffset>
              <bitWidth>1</bitWidth>
            </field>
            <field>
              <name>DMAR</name>
              <bitOffset>6</bitOffset>
              <bitWidth>1</bitWidth>
            </field>
            <field>
              <name>DMAT</name>
              <bitOffset>7</bitOffset>
              <bitWidth>1</bitWidth>
            </field>
            <field>
              <name>RTSE</name>
              <bitOffset>8</bitOffset>
              <bitWidth>1</bitWidth>
            </field>
            <field>
              <name>CTSE</name>
              <bitOffset>9</bitOffset>
              <bitWidth>1</bitWidth>
            </field>
            <field>
              <name>CTSIE</name>
              <bitOffset>10</bitOffset>
              <bitWidth>1</bitWidth>
            </field>
            <field>
              <name>ONEBIT</name>
              <bitOffset>11</bitOffset>
              <bitWidth>1</bitWidth>
            </field>
            <field>
              <name>OVRDIS</name>
              <bitOffset>12</bitOffset>
              <bitWidth>1</bitWidth>
            </field>
            <field>
              <name>DDRE</name>
              <bitOffset>13</bitOffset>
              <bitWidth>1</bitWidth>
            </field>
            <field>
              <name>DEM</name>
              <bitOffset>14</bitOffset>
              <bitWidth>1</bitWidth>
            </field>
            <field>
              <name>DEP</name>
              <bitOffset>15</bitOffset>
              <bitWidth>1</bitWidth>
            </field>
            <field>
              <name>SCARCNT</name>
              <bitOffset>17</bitOffset>
              <bitWidth>3</bitWidth>
            </field>
            <field>
              <name>WUS</name>
              <bitOffset>20</bitOffset>
              <bitWidth>2</bitWidth>
            </field>
            <field>
              <name>WUFIE</name>
              <bitOffset>22</bitOffset>
              <bitWidth>1</bitWidth>
            </field>
            <field>
              <name>UCESM</name>
              <bitOffset>23</bitOffset>
              <bitWidth>1</bitWidth>
            </field>
            <field>
              <name>TCBGTIE</name>
              <bitOffset>24</bitOffset>
              <bitWidth>1</bitWidth>
            </field>
          </fields>
        </register>
        <register>
          <name>BRR</name>
          <addressOffset>0xc</addressOffset>
          <size>0x20</size>
          <fields>
            <field>
              <name>DIV_FRACTION</name>
              <bitOffset>0</bitOffset>
              <bitWidth>4</bitWidth>
            </field>
            <field>
              <name>DIV_MANTISSA</name>
              <bitOffset>4</bitOffset>
              <bitWidth>12</bitWidth>
            </field>
          </fields>
        </register>
        <register>
          <name>GTPR</name>
          <addressOffset>0x10</addressOffset>
          <size>0x10</size>
          <fields>
            <field>
              <name>PSC</name>
              <bitOffset>0</bitOffset>
              <bitWidth>8</bitWidth>
            </field>
            <field>
              <name>GT</name>
              <bitOffset>8</bitOffset>
              <bitWidth>8</bitWidth>
            </field>
          </fields>
        </register>
        <register>
          <name>RTOR</name>
          <addressOffset>0x14</addressOffset>
          <size>0x20</size>
          <fields>
            <field>
              <name>RTO</name>
              <bitOffset>0</bitOffset>
              <bitWidth>24</bitWidth>
            </field>
            <field>
              <name>BLEN</name>
              <bitOffset>24</bitOffset>
              <bitWidth>8</bitWidth>
            </field>
          </fields>
        </register>
        <register>
          <name>RQR</name>
          <addressOffset>0x18</addressOffset>
          <size>0x10</size>
          <fields>
            <field>
              <name>ABRRQ</name>
              <bitOffset>0</bitOffset>
              <bitWidth>1</bitWidth>
            </field>
            <field>
              <name>SBKRQ</name>
              <bitOffset>1</bitOffset>
              <bitWidth>1</bitWidth>
            </field>
            <field>
              <name>MMRQ</name>
              <bitOffset>2</bitOffset>
              <bitWidth>1</bitWidth>
            </field>
            <field>
              <name>RXFRQ</name>
              <bitOffset>3</bitOffset>
              <bitWidth>1</bitWidth>
            </field>
            <field>
              <name>TXFRQ</name>
              <bitOffset>4</bitOffset>
              <bitWidth>1</bitWidth>
            </field>
          </fields>
        </register>
        <register>
          <name>ISR</name>
          <addressOffset>0x1c</addressOffset>
          <size>0x20</size>
          <fields>
            <field>
              <name>PE</name>
              <bitOffset>0</bitOffset>
              <bitWidth>1</bitWidth>
            </field>
            <field>
              <name>FE</name>
              <bitOffset>1</bitOffset>
              <bitWidth>1</bitWidth>
            </field>
            <field>
              <name>NE</name>
              <bitOffset>2</bitOffset>
              <bitWidth>1</bitWidth>
            </field>
            <field>
              <name>ORE</name>
              <bitOffset>3</bitOffset>
              <bitWidth>1</bitWidth>
            </field>
            <field>
              <name>IDLE</name>
              <bitOffset>4</bitOffset>
              <bitWidth>1</bitWidth>
            </field>
            <field>
              <name>RXNE</name>
              <bitOffset>5</bitOffset>
              <bitWidth>1</bitWidth>
            </field>
            <field>
              <name>TC</name>
              <bitOffset>6</bitOffset>
              <bitWidth>1</bitWidth>
            </field>
            <field>
              <name>TXE</name>
              <bitOffset>7</bitOffset>
              <bitWidth>1</bitWidth>
            </field>
            <field>
              <name>LBDF</name>
              <bitOffset>8</bitOffset>
              <bitWidth>1</bitWidth>
            </field>
            <field>
              <name>CTSIF</name>
              <bitOffset>9</bitOffset>
              <bitWidth>1</bitWidth>
            </field>
            <field>
              <name>CTS</name>
              <bitOffset>10</bitOffset>
              <bitWidth>1</bitWidth>
            </field>
            <field>
              <name>RTOF</name>
              <bitOffset>11</bitOffset>
              <bitWidth>1</bitWidth>
            </field>
            <field>
              <name>EOBF</name>
              <bitOffset>12</bitOffset>
              <bitWidth>1</bitWidth>
            </field>
            <field>
              <name>ABRE</name>
              <bitOffset>14</bitOffset>
              <bitWidth>1</bitWidth>
            </field>
            <field>
              <name>ABRF</name>
              <bitOffset>15</bitOffset>
              <bitWidth>1</bitWidth>
            </field>
            <field>
              <name>BUSY</name>
              <bitOffset>16</bitOffset>
              <bitWidth>1</bitWidth>
            </field>
            <field>
              <name>CMF</name>
              <bitOffset>17</bitOffset>
              <bitWidth>1</bitWidth>
            </field>
            <field>
              <name>SBKF</name>
              <bitOffset>18</bitOffset>
              <bitWidth>1</bitWidth>
            </field>
            <field>
              <name>RWU</name>
              <bitOffset>19</bitOffset>
              <bitWidth>1</bitWidth>
            </field>
            <field>
              <name>WUF</name>
              <bitOffset>20</bitOffset>
              <bitWidth>1</bitWidth>
            </field>
            <field>
              <name>TEACK</name>
              <bitOffset>21</bitOffset>
              <bitWidth>1</bitWidth>
            </field>
            <field>
              <name>REACK</name>
              <bitOffset>22</bitOffset>
              <bitWidth>1</bitWidth>
            </field>
            <field>
              <name>TCBGT</name>
              <bitOffset>25</bitOffset>
              <bitWidth>1</bitWidth>
            </field>
          </fields>
        </register>
        <register>
          <name>ICR</name>
          <addressOffset>0x20</addressOffset>
          <size>0x20</size>
          <fields>
            <field>
              <name>PECF</name>
              <bitOffset>0</bitOffset>
              <bitWidth>1</bitWidth>
            </field>
            <field>
              <name>FECF</name>
              <bitOffset>1</bitOffset>
              <bitWidth>1</bitWidth>
            </field>
            <field>
              <name>NECF</name>
              <bitOffset>2</bitOffset>
              <bitWidth>1</bitWidth>
            </field>
            <field>
              <name>ORECF</name>
              <bitOffset>3</bitOffset>
              <bitWidth>1</bitWidth>
            </field>
            <field>
              <name>IDLECF</name>
              <bitOffset>4</bitOffset>
              <bitWidth>1</bitWidth>
            </field>
            <field>
              <name>TCCF</name>
              <bitOffset>6</bitOffset>
              <bitWidth>1</bitWidth>
            </field>
            <field>
              <name>TCBGTCF</name>
              <bitOffset>7</bitOffset>
              <bitWidth>1</bitWidth>
            </field>
            <field>
              <name>LBDCF</name>
              <bitOffset>8</bitOffset>
              <bitWidth>1</bitWidth>
            </field>
            <field>
              <name>CTSCF</name>
              <bitOffset>9</bitOffset>
              <bitWidth>1</bitWidth>
            </field>
            <field>
              <name>RTOCF</name>
              <bitOffset>11</bitOffset>
              <bitWidth>1</bitWidth>
            </field>
            <field>
              <name>EOBCF</name>
              <bitOffset>12</bitOffset>
              <bitWidth>1</bitWidth>
            </field>
            <field>
              <name>CMCF</name>
              <bitOffset>17</bitOffset>
              <bitWidth>1</bitWidth>
            </field>
            <field>
              <name>WUCF</name>
              <bitOffset>20</bitOffset>
              <bitWidth>1</bitWidth>
            </field>
          </fields>
        </register>
        <register>
          <name>RDR</name>
          <addressOffset>0x24</addressOffset>
          <size>0x10</size>
          <fields>
            <field>
              <name>RDR</name>
              <bitOffset>0</bitOffset>
              <bitWidth>9</bitWidth>
            </field>
          </fields>
        </register>
        <register>
          <name>TDR</name>
          <addressOffset>0x28</addressOffset>
          <size>0x10</size>
          <fields>
            <field>
              <name>TDR</name>
              <bitOffset>0</bitOffset>
              <bitWidth>9</bitWidth>
            </field>
          </fields>
        </register>
      </registers>
    </peripheral>
    <peripheral>
      <name>TIM15</name>
      <baseAddress>0x40014000</baseAddress>
      <registers>
        <register>
          <name>CR1</name>
          <addressOffset>0x0</addressOffset>
          <size>0x20</size>
          <fields>
            <field>
              <name>CEN</name>
              <bitOffset>0</bitOffset>
              <bitWidth>1</bitWidth>
            </field>
            <field>
              <name>UDIS</name>
              <bitOffset>1</bitOffset>
              <bitWidth>1</bitWidth>
            </field>
            <field>
              <name>URS</name>
              <bitOffset>2</bitOffset>
              <bitWidth>1</bitWidth>
            </field>
            <field>
              <name>OPM</name>
              <bitOffset>3</bitOffset>
              <bitWidth>1</bitWidth>
            </field>
            <field>
              <name>DIR</name>
              <bitOffset>4</bitOffset>
              <bitWidth>1</bitWidth>
            </field>
            <field>
              <name>CMS</name>
              <bitOffset>5</bitOffset>
              <bitWidth>2</bitWidth>
            </field>
            <field>
              <name>ARPE</name>
              <bitOffset>7</bitOffset>
              <bitWidth>1</bitWidth>
            </field>
            <field>
              <name>CKD</name>
              <bitOffset>8</bitOffset>
              <bitWidth>2</bitWidth>
            </field>
            <field>
              <name>UIFREMAP</name>
              <bitOffset>11</bitOffset>
              <bitWidth>1</bitWidth>
            </field>
          </fields>
        </register>
        <register>
          <name>CR2</name>
          <addressOffset>0x4</addressOffset>
          <size>0x20</size>
          <fields>
            <field>
              <name>CCPC</name>
              <bitOffset>0</bitOffset>
              <bitWidth>1</bitWidth>
            </field>
            <field>
              <name>CCUS</name>
              <bitOffset>2</bitOffset>
              <bitWidth>1</bitWidth>
            </field>
            <field>
              <name>CCDS</name>
              <bitOffset>3</bitOffset>
              <bitWidth>1</bitWidth>
            </field>
            <field>
              <name>MMS</name>
              <bitOffset>4</bitOffset>
              <bitWidth>3</bitWidth>
            </field>
            <field>
              <name>TI1S</name>
              <bitOffset>7</bitOffset>
              <bitWidth>1</bitWidth>
            </field>
            <field>
              <name>OIS1</name>
              <bitOffset>8</bitOffset>
              <bitWidth>1</bitWidth>
            </field>
            <field>
              <name>OIS1N</name>
              <bitOffset>9</bitOffset>
              <bitWidth>1</bitWidth>
            </field>
            <field>
              <name>OIS2</name>
              <bitOffset>10</bitOffset>
              <bitWidth>1</bitWidth>
            </field>
            <field>
              <name>OIS2N</name>
              <bitOffset>11</bitOffset>
              <bitWidth>1</bitWidth>
            </field>
            <field>
              <name>OIS3</name>
              <bitOffset>12</bitOffset>
              <bitWidth>1</bitWidth>
            </field>
            <field>
              <name>OIS3N</name>
              <bitOffset>13</bitOffset>
              <bitWidth>1</bitWidth>
            </field>
            <field>
              <name>OIS4</name>
              <bitOffset>14</bitOffset>
              <bitWidth>1</bitWidth>
            </field>
            <field>
              <name>OIS5</name>
              <bitOffset>16</bitOffset>
              <bitWidth>1</bitWidth>
            </field>
            <field>
              <name>OIS6</name>
              <bitOffset>18</bitOffset>
              <bitWidth>1</bitWidth>
            </field>
            <field>
              <name>MMS2</name>
              <bitOffset>20</bitOffset>
              <bitWidth>4</bitWidth>
            </field>
          </fields>
        </register>
        <register>
          <name>SMCR</name>
          <addressOffset>0x8</addressOffset>
          <size>0x20</size>
          <fields>
            <field>
              <name>SMS</name>
              <bitOffset>0</bitOffset>
              <bitWidth>17</bitWidth>
            </field>
            <field>
              <name>OCCS</name>
              <bitOffset>3</bitOffset>
              <bitWidth>1</bitWidth>
            </field>
            <field>
              <name>TS</name>
              <bitOffset>4</bitOffset>
              <bitWidth>3</bitWidth>
            </field>
            <field>
              <name>MSM</name>
              <bitOffset>7</bitOffset>
              <bitWidth>1</bitWidth>
            </field>
            <field>
              <name>ETF</name>
              <bitOffset>8</bitOffset>
              <bitWidth>4</bitWidth>
            </field>
            <field>
              <name>ETPS</name>
              <bitOffset>12</bitOffset>
              <bitWidth>2</bitWidth>
            </field>
            <field>
              <name>ECE</name>
              <bitOffset>14</bitOffset>
              <bitWidth>1</bitWidth>
            </field>
            <field>
              <name>ETP</name>
              <bitOffset>15</bitOffset>
              <bitWidth>1</bitWidth>
            </field>
          </fields>
        </register>
        <register>
          <name>DIER</name>
          <addressOffset>0xc</addressOffset>
          <size>0x20</size>
          <fields>
            <field>
              <name>UIE</name>
              <bitOffset>0</bitOffset>
              <bitWidth>1</bitWidth>
            </field>
            <field>
              <name>CC1IE</name>
              <bitOffset>1</bitOffset>
              <bitWidth>1</bitWidth>
            </field>
            <field>
              <name>CC2IE</name>
              <bitOffset>2</bitOffset>
              <bitWidth>1</bitWidth>
            </field>
            <field>
              <name>CC3IE</name>
              <bitOffset>3</bitOffset>
              <bitWidth>1</bitWidth>
            </field>
            <field>
              <name>CC4IE</name>
              <bitOffset>4</bitOffset>
              <bitWidth>1</bitWidth>
            </field>
            <field>
              <name>COMIE</name>
              <bitOffset>5</bitOffset>
              <bitWidth>1</bitWidth>
            </field>
            <field>
              <name>TIE</name>
              <bitOffset>6</bitOffset>
              <bitWidth>1</bitWidth>
            </field>
            <field>
              <name>BIE</name>
              <bitOffset>7</bitOffset>
              <bitWidth>1</bitWidth>
            </field>
            <field>
              <name>UDE</name>
              <bitOffset>8</bitOffset>
              <bitWidth>1</bitWidth>
            </field>
            <field>
              <name>CC1DE</name>
              <bitOffset>9</bitOffset>
              <bitWidth>1</bitWidth>
            </field>
            <field>
              <name>CC2DE</name>
              <bitOffset>10</bitOffset>
              <bitWidth>1</bitWidth>
            </field>
            <field>
              <name>CC3DE</name>
              <bitOffset>11</bitOffset>
              <bitWidth>1</bitWidth>
            </field>
            <field>
              <name>CC4DE</name>
              <bitOffset>12</bitOffset>
              <bitWidth>1</bitWidth>
            </field>
            <field>
              <name>COMDE</name>
              <bitOffset>13</bitOffset>
              <bitWidth>1</bitWidth>
            </field>
            <field>
              <name>TDE</name>
              <bitOffset>14</bitOffset>
              <bitWidth>1</bitWidth>
            </field>
          </fields>
        </register>
        <register>
          <name>SR</name>
          <addressOffset>0x10</addressOffset>
          <size>0x20</size>
          <fields>
            <field>
              <name>UIF</name>
              <bitOffset>0</bitOffset>
              <bitWidth>1</bitWidth>
            </field>
            <field>
              <name>CC1IF</name>
              <bitOffset>1</bitOffset>
              <bitWidth>1</bitWidth>
            </field>
            <field>
              <name>CC2IF</name>
              <bitOffset>2</bitOffset>
              <bitWidth>1</bitWidth>
            </field>
            <field>
              <name>CC3IF</name>
              <bitOffset>3</bitOffset>
              <bitWidth>1</bitWidth>
            </field>
            <field>
              <name>CC4IF</name>
              <bitOffset>4</bitOffset>
              <bitWidth>1</bitWidth>
            </field>
            <field>
              <name>COMIF</name>
              <bitOffset>5</bitOffset>
              <bitWidth>1</bitWidth>
            </field>
            <field>
              <name>TIF</name>
              <bitOffset>6</bitOffset>
              <bitWidth>1</bitWidth>
            </field>
            <field>
              <name>BIF</name>
              <bitOffset>7</bitOffset>
              <bitWidth>1</bitWidth>
            </field>
            <field>
              <name>B2IF</name>
              <bitOffset>8</bitOffset>
              <bitWidth>1</bitWidth>
            </field>
            <field>
              <name>CC1OF</name>
              <bitOffset>9</bitOffset>
              <bitWidth>1</bitWidth>
            </field>
            <field>
              <name>CC2OF</name>
              <bitOffset>10</bitOffset>
              <bitWidth>1</bitWidth>
            </field>
            <field>
              <name>CC3OF</name>
              <bitOffset>11</bitOffset>
              <bitWidth>1</bitWidth>
            </field>
            <field>
              <name>CC4OF</name>
              <bitOffset>12</bitOffset>
              <bitWidth>1</bitWidth>
            </field>
            <field>
              <name>SBIF</name>
              <bitOffset>13</bitOffset>
              <bitWidth>1</bitWidth>
            </field>
            <field>
              <name>CC5IF</name>
              <bitOffset>16</bitOffset>
              <bitWidth>1</bitWidth>
            </field>
            <field>
              <name>CC6IF</name>
              <bitOffset>17</bitOffset>
              <bitWidth>1</bitWidth>
            </field>
          </fields>
        </register>
        <register>
          <name>EGR</name>
          <addressOffset>0x14</addressOffset>
          <size>0x20</size>
          <fields>
            <field>
              <name>UG</name>
              <bitOffset>0</bitOffset>
              <bitWidth>1</bitWidth>
            </field>
            <field>
              <name>CC1G</name>
              <bitOffset>1</bitOffset>
              <bitWidth>1</bitWidth>
            </field>
            <field>
              <name>CC2G</name>
              <bitOffset>2</bitOffset>
              <bitWidth>1</bitWidth>
            </field>
            <field>
              <name>CC3G</name>
              <bitOffset>3</bitOffset>
              <bitWidth>1</bitWidth>
            </field>
            <field>
              <name>CC4G</name>
              <bitOffset>4</bitOffset>
              <bitWidth>1</bitWidth>
            </field>
            <field>
              <name>COMG</name>
              <bitOffset>5</bitOffset>
              <bitWidth>1</bitWidth>
            </field>
            <field>
              <name>TG</name>
              <bitOffset>6</bitOffset>
              <bitWidth>1</bitWidth>
            </field>
            <field>
              <name>BG</name>
              <bitOffset>7</bitOffset>
              <bitWidth>1</bitWidth>
            </field>
            <field>
              <name>B2G</name>
              <bitOffset>8</bitOffset>
              <bitWidth>1</bitWidth>
            </field>
          </fields>
        </register>
        <register>
          <name>CCMR1</name>
          <addressOffset>0x18</addressOffset>
          <size>0x20</size>
          <fields>
            <field>
              <name>CC1S</name>
              <bitOffset>0</bitOffset>
              <bitWidth>2</bitWidth>
            </field>
            <field>
              <name>OC1FE</name>
              <bitOffset>2</bitOffset>
              <bitWidth>1</bitWidth>
            </field>
            <field>
              <name>OC1PE</name>
              <bitOffset>3</bitOffset>
              <bitWidth>1</bitWidth>
            </field>
            <field>
              <name>OC1M</name>
              <bitOffset>4</bitOffset>
              <bitWidth>13</bitWidth>
            </field>
            <field>
              <name>OC1CE</name>
              <bitOffset>7</bitOffset>
              <bitWidth>1</bitWidth>
            </field>
            <field>
              <name>CC2S</name>
              <bitOffset>8</bitOffset>
              <bitWidth>2</bitWidth>
            </field>
            <field>
              <name>OC2FE</name>
              <bitOffset>10</bitOffset>
              <bitWidth>1</bitWidth>
            </field>
            <field>
              <name>OC2PE</name>
              <bitOffset>11</bitOffset>
              <bitWidth>1</bitWidth>
            </field>
            <field>
              <name>OC2M</name>
              <bitOffset>12</bitOffset>
              <bitWidth>13</bitWidth>
            </field>
            <field>
              <name>OC2CE</name>
              <bitOffset>15</bitOffset>
              <bitWidth>1</bitWidth>
            </field>
          </fields>
        </register>
        <register>
          <name>CCMR2</name>
          <addressOffset>0x1c</addressOffset>
          <size>0x20</size>
          <fields>
            <field>
              <name>CC3S</name>
              <bitOffset>0</bitOffset>
              <bitWidth>2</bitWidth>
            </field>
            <field>
              <name>OC3FE</name>
              <bitOffset>2</bitOffset>
              <bitWidth>1</bitWidth>
            </field>
            <field>
              <name>OC3PE</name>
              <bitOffset>3</bitOffset>
              <bitWidth>1</bitWidth>
            </field>
            <field>
              <name>OC3M</name>
              <bitOffset>4</bitOffset>
              <bitWidth>13</bitWidth>
            </field>
            <field>
              <name>OC3CE</name>
              <bitOffset>7</bitOffset>
              <bitWidth>1</bitWidth>
            </field>
            <field>
              <name>CC4S</name>
              <bitOffset>8</bitOffset>
              <bitWidth>2</bitWidth>
            </field>
            <field>
              <name>OC4FE</name>
              <bitOffset>10</bitOffset>
              <bitWidth>1</bitWidth>
            </field>
            <field>
              <name>OC4PE</name>
              <bitOffset>11</bitOffset>
              <bitWidth>1</bitWidth>
            </field>
            <field>
              <name>OC4M</name>
              <bitOffset>12</bitOffset>
              <bitWidth>13</bitWidth>
            </field>
            <field>
              <name>OC4CE</name>
              <bitOffset>15</bitOffset>
              <bitWidth>1</bitWidth>
            </field>
          </fields>
        </register>
        <register>
          <name>CCER</name>
          <addressOffset>0x20</addressOffset>
          <size>0x20</size>
          <fields>
            <field>
              <name>CC1E</name>
              <bitOffset>0</bitOffset>
              <bitWidth>1</bitWidth>
            </field>
            <field>
              <name>CC1P</name>
              <bitOffset>1</bitOffset>
              <bitWidth>1</bitWidth>
            </field>
            <field>
              <name>CC1NE</name>
              <bitOffset>2</bitOffset>
              <bitWidth>1</bitWidth>
            </field>
            <field>
              <name>CC1NP</name>
              <bitOffset>3</bitOffset>
              <bitWidth>1</bitWidth>
            </field>
            <field>
              <name>CC2E</name>
              <bitOffset>4</bitOffset>
              <bitWidth>1</bitWidth>
            </field>
            <field>
              <name>CC2P</name>
              <bitOffset>5</bitOffset>
              <bitWidth>1</bitWidth>
            </field>
            <field>
              <name>CC2NE</name>
              <bitOffset>6</bitOffset>
              <bitWidth>1</bitWidth>
            </field>
            <field>
              <name>CC2NP</name>
              <bitOffset>7</bitOffset>
              <bitWidth>1</bitWidth>
            </field>
            <field>
              <name>CC3E</name>
              <bitOffset>8</bitOffset>
              <bitWidth>1</bitWidth>
            </field>
            <field>
              <name>CC3P</name>
              <bitOffset>9</bitOffset>
              <bitWidth>1</bitWidth>
            </field>
            <field>
              <name>CC3NE</name>
              <bitOffset>10</bitOffset>
              <bitWidth>1</bitWidth>
            </field>
            <field>
              <name>CC3NP</name>
              <bitOffset>11</bitOffset>
              <bitWidth>1</bitWidth>
            </field>
            <field>
              <name>CC4E</name>
              <bitOffset>12</bitOffset>
              <bitWidth>1</bitWidth>
            </field>
            <field>
              <name>CC4P</name>
              <bitOffset>13</bitOffset>
              <bitWidth>1</bitWidth>
            </field>
            <field>
              <name>CC4NP</name>
              <bitOffset>15</bitOffset>
              <bitWidth>1</bitWidth>
            </field>
            <field>
              <name>CC5E</name>
              <bitOffset>16</bitOffset>
              <bitWidth>1</bitWidth>
            </field>
            <field>
              <name>CC5P</name>
              <bitOffset>17</bitOffset>
              <bitWidth>1</bitWidth>
            </field>
            <field>
              <name>CC6E</name>
              <bitOffset>20</bitOffset>
              <bitWidth>1</bitWidth>
            </field>
            <field>
              <name>CC6P</name>
              <bitOffset>21</bitOffset>
              <bitWidth>1</bitWidth>
            </field>
          </fields>
        </register>
        <register>
          <name>CNT</name>
          <addressOffset>0x24</addressOffset>
          <size>0x20</size>
          <fields>
            <field>
              <name>CNT</name>
              <bitOffset>0</bitOffset>
              <bitWidth>32</bitWidth>
            </field>
            <field>
              <name>UIFCPY</name>
              <bitOffset>31</bitOffset>
              <bitWidth>1</bitWidth>
            </field>
          </fields>
        </register>
        <register>
          <name>PSC</name>
          <addressOffset>0x28</addressOffset>
          <size>0x20</size>
          <fields>
            <field>
              <name>PSC</name>
              <bitOffset>0</bitOffset>
              <bitWidth>16</bitWidth>
            </field>
          </fields>
        </register>
        <register>
          <name>ARR</name>
          <addressOffset>0x2c</addressOffset>
          <size>0x20</size>
          <fields>
            <field>
              <name>ARR</name>
              <bitOffset>0</bitOffset>
              <bitWidth>32</bitWidth>
            </field>
          </fields>
        </register>
        <register>
          <name>RCR</name>
          <addressOffset>0x30</addressOffset>
          <size>0x20</size>
          <fields>
            <field>
              <name>REP</name>
              <bitOffset>0</bitOffset>
              <bitWidth>16</bitWidth>
            </field>
          </fields>
        </register>
        <register>
          <name>CCR1</name>
          <addressOffset>0x34</addressOffset>
          <size>0x20</size>
          <fields>
            <field>
              <name>CCR1</name>
              <bitOffset>0</bitOffset>
              <bitWidth>16</bitWidth>
            </field>
          </fields>
        </register>
        <register>
          <name>CCR2</name>
          <addressOffset>0x38</addressOffset>
          <size>0x20</size>
          <fields>
            <field>
              <name>CCR2</name>
              <bitOffset>0</bitOffset>
              <bitWidth>16</bitWidth>
            </field>
          </fields>
        </register>
        <register>
          <name>CCR3</name>
          <addressOffset>0x3c</addressOffset>
          <size>0x20</size>
          <fields>
            <field>
              <name>CCR3</name>
              <bitOffset>0</bitOffset>
              <bitWidth>16</bitWidth>
            </field>
          </fields>
        </register>
        <register>
          <name>CCR4</name>
          <addressOffset>0x40</addressOffset>
          <size>0x20</size>
          <fields>
            <field>
              <name>CCR4</name>
              <bitOffset>0</bitOffset>
              <bitWidth>16</bitWidth>
            </field>
          </fields>
        </register>
        <register>
          <name>BDTR</name>
          <addressOffset>0x44</addressOffset>
          <size>0x20</size>
          <fields>
            <field>
              <name>DTG</name>
              <bitOffset>0</bitOffset>
              <bitWidth>8</bitWidth>
            </field>
            <field>
              <name>LOCK</name>
              <bitOffset>8</bitOffset>
              <bitWidth>2</bitWidth>
            </field>
            <field>
              <name>OSSI</name>
              <bitOffset>10</bitOffset>
              <bitWidth>1</bitWidth>
            </field>
            <field>
              <name>OSSR</name>
              <bitOffset>11</bitOffset>
              <bitWidth>1</bitWidth>
            </field>
            <field>
              <name>BKE</name>
              <bitOffset>12</bitOffset>
              <bitWidth>1</bitWidth>
            </field>
            <field>
              <name>BKP</name>
              <bitOffset>13</bitOffset>
              <bitWidth>1</bitWidth>
            </field>
            <field>
              <name>AOE</name>
              <bitOffset>14</bitOffset>
              <bitWidth>1</bitWidth>
            </field>
            <field>
              <name>MOE</name>
              <bitOffset>15</bitOffset>
              <bitWidth>1</bitWidth>
            </field>
            <field>
              <name>BKF</name>
              <bitOffset>16</bitOffset>
              <bitWidth>4</bitWidth>
            </field>
            <field>
              <name>BK2F</name>
              <bitOffset>20</bitOffset>
              <bitWidth>4</bitWidth>
            </field>
            <field>
              <name>BK2E</name>
              <bitOffset>24</bitOffset>
              <bitWidth>1</bitWidth>
            </field>
            <field>
              <name>BK2P</name>
              <bitOffset>25</bitOffset>
              <bitWidth>1</bitWidth>
            </field>
          </fields>
        </register>
        <register>
          <name>DCR</name>
          <addressOffset>0x48</addressOffset>
          <size>0x20</size>
          <fields>
            <field>
              <name>DBA</name>
              <bitOffset>0</bitOffset>
              <bitWidth>5</bitWidth>
            </field>
            <field>
              <name>DBL</name>
              <bitOffset>8</bitOffset>
              <bitWidth>5</bitWidth>
            </field>
          </fields>
        </register>
        <register>
          <name>DMAR</name>
          <addressOffset>0x4c</addressOffset>
          <size>0x20</size>
          <fields>
            <field>
              <name>DMAB</name>
              <bitOffset>0</bitOffset>
              <bitWidth>16</bitWidth>
            </field>
          </fields>
        </register>
        <register>
          <name>OR1</name>
          <addressOffset>0x50</addressOffset>
          <size>0x20</size>
        </register>
        <register>
          <name>CCMR3</name>
          <addressOffset>0x54</addressOffset>
          <size>0x20</size>
          <fields>
            <field>
              <name>OC5FE</name>
              <bitOffset>2</bitOffset>
              <bitWidth>1</bitWidth>
            </field>
            <field>
              <name>OC5PE</name>
              <bitOffset>3</bitOffset>
              <bitWidth>1</bitWidth>
            </field>
            <field>
              <name>OC5M</name>
              <bitOffset>4</bitOffset>
              <bitWidth>13</bitWidth>
            </field>
            <field>
              <name>OC5CE</name>
              <bitOffset>7</bitOffset>
              <bitWidth>1</bitWidth>
            </field>
            <field>
              <name>OC6FE</name>
              <bitOffset>10</bitOffset>
              <bitWidth>1</bitWidth>
            </field>
            <field>
              <name>OC6PE</name>
              <bitOffset>11</bitOffset>
              <bitWidth>1</bitWidth>
            </field>
            <field>
              <name>OC6M</name>
              <bitOffset>12</bitOffset>
              <bitWidth>13</bitWidth>
            </field>
            <field>
              <name>OC6CE</name>
              <bitOffset>15</bitOffset>
              <bitWidth>1</bitWidth>
            </field>
          </fields>
        </register>
        <register>
          <name>CCR5</name>
          <addressOffset>0x58</addressOffset>
          <size>0x20</size>
          <fields>
            <field>
              <name>CCR5</name>
              <bitOffset>0</bitOffset>
              <bitWidth>32</bitWidth>
            </field>
            <field>
              <name>GC5C1</name>
              <bitOffset>29</bitOffset>
              <bitWidth>1</bitWidth>
            </field>
            <field>
              <name>GC5C2</name>
              <bitOffset>30</bitOffset>
              <bitWidth>1</bitWidth>
            </field>
            <field>
              <name>GC5C3</name>
              <bitOffset>31</bitOffset>
              <bitWidth>1</bitWidth>
            </field>
          </fields>
        </register>
        <register>
          <name>CCR6</name>
          <addressOffset>0x5c</addressOffset>
          <size>0x20</size>
          <fields>
            <field>
              <name>CCR6</name>
              <bitOffset>0</bitOffset>
              <bitWidth>16</bitWidth>
            </field>
          </fields>
        </register>
        <register>
          <name>OR2</name>
          <addressOffset>0x60</addressOffset>
          <size>0x20</size>
        </register>
        <register>
          <name>OR3</name>
          <addressOffset>0x64</addressOffset>
          <size>0x20</size>
        </register>
      </registers>
    </peripheral>
    <peripheral>
      <name>TIM16</name>
      <baseAddress>0x40014400</baseAddress>
      <registers>
        <register>
          <name>CR1</name>
          <addressOffset>0x0</addressOffset>
          <size>0x20</size>
          <fields>
            <field>
              <name>CEN</name>
              <bitOffset>0</bitOffset>
              <bitWidth>1</bitWidth>
            </field>
            <field>
              <name>UDIS</name>
              <bitOffset>1</bitOffset>
              <bitWidth>1</bitWidth>
            </field>
            <field>
              <name>URS</name>
              <bitOffset>2</bitOffset>
              <bitWidth>1</bitWidth>
            </field>
            <field>
              <name>OPM</name>
              <bitOffset>3</bitOffset>
              <bitWidth>1</bitWidth>
            </field>
            <field>
              <name>DIR</name>
              <bitOffset>4</bitOffset>
              <bitWidth>1</bitWidth>
            </field>
            <field>
              <name>CMS</name>
              <bitOffset>5</bitOffset>
              <bitWidth>2</bitWidth>
            </field>
            <field>
              <name>ARPE</name>
              <bitOffset>7</bitOffset>
              <bitWidth>1</bitWidth>
            </field>
            <field>
              <name>CKD</name>
              <bitOffset>8</bitOffset>
              <bitWidth>2</bitWidth>
            </field>
            <field>
              <name>UIFREMAP</name>
              <bitOffset>11</bitOffset>
              <bitWidth>1</bitWidth>
            </field>
          </fields>
        </register>
        <register>
          <name>CR2</name>
          <addressOffset>0x4</addressOffset>
          <size>0x20</size>
          <fields>
            <field>
              <name>CCPC</name>
              <bitOffset>0</bitOffset>
              <bitWidth>1</bitWidth>
            </field>
            <field>
              <name>CCUS</name>
              <bitOffset>2</bitOffset>
              <bitWidth>1</bitWidth>
            </field>
            <field>
              <name>CCDS</name>
              <bitOffset>3</bitOffset>
              <bitWidth>1</bitWidth>
            </field>
            <field>
              <name>MMS</name>
              <bitOffset>4</bitOffset>
              <bitWidth>3</bitWidth>
            </field>
            <field>
              <name>TI1S</name>
              <bitOffset>7</bitOffset>
              <bitWidth>1</bitWidth>
            </field>
            <field>
              <name>OIS1</name>
              <bitOffset>8</bitOffset>
              <bitWidth>1</bitWidth>
            </field>
            <field>
              <name>OIS1N</name>
              <bitOffset>9</bitOffset>
              <bitWidth>1</bitWidth>
            </field>
            <field>
              <name>OIS2</name>
              <bitOffset>10</bitOffset>
              <bitWidth>1</bitWidth>
            </field>
            <field>
              <name>OIS2N</name>
              <bitOffset>11</bitOffset>
              <bitWidth>1</bitWidth>
            </field>
            <field>
              <name>OIS3</name>
              <bitOffset>12</bitOffset>
              <bitWidth>1</bitWidth>
            </field>
            <field>
              <name>OIS3N</name>
              <bitOffset>13</bitOffset>
              <bitWidth>1</bitWidth>
            </field>
            <field>
              <name>OIS4</name>
              <bitOffset>14</bitOffset>
              <bitWidth>1</bitWidth>
            </field>
            <field>
              <name>OIS5</name>
              <bitOffset>16</bitOffset>
              <bitWidth>1</bitWidth>
            </field>
            <field>
              <name>OIS6</name>
              <bitOffset>18</bitOffset>
              <bitWidth>1</bitWidth>
            </field>
            <field>
              <name>MMS2</name>
              <bitOffset>20</bitOffset>
              <bitWidth>4</bitWidth>
            </field>
          </fields>
        </register>
        <register>
          <name>SMCR</name>
          <addressOffset>0x8</addressOffset>
          <size>0x20</size>
          <fields>
            <field>
              <name>SMS</name>
              <bitOffset>0</bitOffset>
              <bitWidth>17</bitWidth>
            </field>
            <field>
              <name>OCCS</name>
              <bitOffset>3</bitOffset>
              <bitWidth>1</bitWidth>
            </field>
            <field>
              <name>TS</name>
              <bitOffset>4</bitOffset>
              <bitWidth>3</bitWidth>
            </field>
            <field>
              <name>MSM</name>
              <bitOffset>7</bitOffset>
              <bitWidth>1</bitWidth>
            </field>
            <field>
              <name>ETF</name>
              <bitOffset>8</bitOffset>
              <bitWidth>4</bitWidth>
            </field>
            <field>
              <name>ETPS</name>
              <bitOffset>12</bitOffset>
              <bitWidth>2</bitWidth>
            </field>
            <field>
              <name>ECE</name>
              <bitOffset>14</bitOffset>
              <bitWidth>1</bitWidth>
            </field>
            <field>
              <name>ETP</name>
              <bitOffset>15</bitOffset>
              <bitWidth>1</bitWidth>
            </field>
          </fields>
        </register>
        <register>
          <name>DIER</name>
          <addressOffset>0xc</addressOffset>
          <size>0x20</size>
          <fields>
            <field>
              <name>UIE</name>
              <bitOffset>0</bitOffset>
              <bitWidth>1</bitWidth>
            </field>
            <field>
              <name>CC1IE</name>
              <bitOffset>1</bitOffset>
              <bitWidth>1</bitWidth>
            </field>
            <field>
              <name>CC2IE</name>
              <bitOffset>2</bitOffset>
              <bitWidth>1</bitWidth>
            </field>
            <field>
              <name>CC3IE</name>
              <bitOffset>3</bitOffset>
              <bitWidth>1</bitWidth>
            </field>
            <field>
              <name>CC4IE</name>
              <bitOffset>4</bitOffset>
              <bitWidth>1</bitWidth>
            </field>
            <field>
              <name>COMIE</name>
              <bitOffset>5</bitOffset>
              <bitWidth>1</bitWidth>
            </field>
            <field>
              <name>TIE</name>
              <bitOffset>6</bitOffset>
              <bitWidth>1</bitWidth>
            </field>
            <field>
              <name>BIE</name>
              <bitOffset>7</bitOffset>
              <bitWidth>1</bitWidth>
            </field>
            <field>
              <name>UDE</name>
              <bitOffset>8</bitOffset>
              <bitWidth>1</bitWidth>
            </field>
            <field>
              <name>CC1DE</name>
              <bitOffset>9</bitOffset>
              <bitWidth>1</bitWidth>
            </field>
            <field>
              <name>CC2DE</name>
              <bitOffset>10</bitOffset>
              <bitWidth>1</bitWidth>
            </field>
            <field>
              <name>CC3DE</name>
              <bitOffset>11</bitOffset>
              <bitWidth>1</bitWidth>
            </field>
            <field>
              <name>CC4DE</name>
              <bitOffset>12</bitOffset>
              <bitWidth>1</bitWidth>
            </field>
            <field>
              <name>COMDE</name>
              <bitOffset>13</bitOffset>
              <bitWidth>1</bitWidth>
            </field>
            <field>
              <name>TDE</name>
              <bitOffset>14</bitOffset>
              <bitWidth>1</bitWidth>
            </field>
          </fields>
        </register>
        <register>
          <name>SR</name>
          <addressOffset>0x10</addressOffset>
          <size>0x20</size>
          <fields>
            <field>
              <name>UIF</name>
              <bitOffset>0</bitOffset>
              <bitWidth>1</bitWidth>
            </field>
            <field>
              <name>CC1IF</name>
              <bitOffset>1</bitOffset>
              <bitWidth>1</bitWidth>
            </field>
            <field>
              <name>CC2IF</name>
              <bitOffset>2</bitOffset>
              <bitWidth>1</bitWidth>
            </field>
            <field>
              <name>CC3IF</name>
              <bitOffset>3</bitOffset>
              <bitWidth>1</bitWidth>
            </field>
            <field>
              <name>CC4IF</name>
              <bitOffset>4</bitOffset>
              <bitWidth>1</bitWidth>
            </field>
            <field>
              <name>COMIF</name>
              <bitOffset>5</bitOffset>
              <bitWidth>1</bitWidth>
            </field>
            <field>
              <name>TIF</name>
              <bitOffset>6</bitOffset>
              <bitWidth>1</bitWidth>
            </field>
            <field>
              <name>BIF</name>
              <bitOffset>7</bitOffset>
              <bitWidth>1</bitWidth>
            </field>
            <field>
              <name>B2IF</name>
              <bitOffset>8</bitOffset>
              <bitWidth>1</bitWidth>
            </field>
            <field>
              <name>CC1OF</name>
              <bitOffset>9</bitOffset>
              <bitWidth>1</bitWidth>
            </field>
            <field>
              <name>CC2OF</name>
              <bitOffset>10</bitOffset>
              <bitWidth>1</bitWidth>
            </field>
            <field>
              <name>CC3OF</name>
              <bitOffset>11</bitOffset>
              <bitWidth>1</bitWidth>
            </field>
            <field>
              <name>CC4OF</name>
              <bitOffset>12</bitOffset>
              <bitWidth>1</bitWidth>
            </field>
            <field>
              <name>SBIF</name>
              <bitOffset>13</bitOffset>
              <bitWidth>1</bitWidth>
            </field>
            <field>
              <name>CC5IF</name>
              <bitOffset>16</bitOffset>
              <bitWidth>1</bitWidth>
            </field>
            <field>
              <name>CC6IF</name>
              <bitOffset>17</bitOffset>
              <bitWidth>1</bitWidth>
            </field>
          </fields>
        </register>
        <register>
          <name>EGR</name>
          <addressOffset>0x14</addressOffset>
          <size>0x20</size>
          <fields>
            <field>
              <name>UG</name>
              <bitOffset>0</bitOffset>
              <bitWidth>1</bitWidth>
            </field>
            <field>
              <name>CC1G</name>
              <bitOffset>1</bitOffset>
              <bitWidth>1</bitWidth>
            </field>
            <field>
              <name>CC2G</name>
              <bitOffset>2</bitOffset>
              <bitWidth>1</bitWidth>
            </field>
            <field>
              <name>CC3G</name>
              <bitOffset>3</bitOffset>
              <bitWidth>1</bitWidth>
            </field>
            <field>
              <name>CC4G</name>
              <bitOffset>4</bitOffset>
              <bitWidth>1</bitWidth>
            </field>
            <field>
              <name>COMG</name>
              <bitOffset>5</bitOffset>
              <bitWidth>1</bitWidth>
            </field>
            <field>
              <name>TG</name>
              <bitOffset>6</bitOffset>
              <bitWidth>1</bitWidth>
            </field>
            <field>
              <name>BG</name>
              <bitOffset>7</bitOffset>
              <bitWidth>1</bitWidth>
            </field>
            <field>
              <name>B2G</name>
              <bitOffset>8</bitOffset>
              <bitWidth>1</bitWidth>
            </field>
          </fields>
        </register>
        <register>
          <name>CCMR1</name>
          <addressOffset>0x18</addressOffset>
          <size>0x20</size>
          <fields>
            <field>
              <name>CC1S</name>
              <bitOffset>0</bitOffset>
              <bitWidth>2</bitWidth>
            </field>
            <field>
              <name>OC1FE</name>
              <bitOffset>2</bitOffset>
              <bitWidth>1</bitWidth>
            </field>
            <field>
              <name>OC1PE</name>
              <bitOffset>3</bitOffset>
              <bitWidth>1</bitWidth>
            </field>
            <field>
              <name>OC1M</name>
              <bitOffset>4</bitOffset>
              <bitWidth>13</bitWidth>
            </field>
            <field>
              <name>OC1CE</name>
              <bitOffset>7</bitOffset>
              <bitWidth>1</bitWidth>
            </field>
            <field>
              <name>CC2S</name>
              <bitOffset>8</bitOffset>
              <bitWidth>2</bitWidth>
            </field>
            <field>
              <name>OC2FE</name>
              <bitOffset>10</bitOffset>
              <bitWidth>1</bitWidth>
            </field>
            <field>
              <name>OC2PE</name>
              <bitOffset>11</bitOffset>
              <bitWidth>1</bitWidth>
            </field>
            <field>
              <name>OC2M</name>
              <bitOffset>12</bitOffset>
              <bitWidth>13</bitWidth>
            </field>
            <field>
              <name>OC2CE</name>
              <bitOffset>15</bitOffset>
              <bitWidth>1</bitWidth>
            </field>
          </fields>
        </register>
        <register>
          <name>CCMR2</name>
          <addressOffset>0x1c</addressOffset>
          <size>0x20</size>
          <fields>
            <field>
              <name>CC3S</name>
              <bitOffset>0</bitOffset>
              <bitWidth>2</bitWidth>
            </field>
            <field>
              <name>OC3FE</name>
              <bitOffset>2</bitOffset>
              <bitWidth>1</bitWidth>
            </field>
            <field>
              <name>OC3PE</name>
              <bitOffset>3</bitOffset>
              <bitWidth>1</bitWidth>
            </field>
            <field>
              <name>OC3M</name>
              <bitOffset>4</bitOffset>
              <bitWidth>13</bitWidth>
            </field>
            <field>
              <name>OC3CE</name>
              <bitOffset>7</bitOffset>
              <bitWidth>1</bitWidth>
            </field>
            <field>
              <name>CC4S</name>
              <bitOffset>8</bitOffset>
              <bitWidth>2</bitWidth>
            </field>
            <field>
              <name>OC4FE</name>
              <bitOffset>10</bitOffset>
              <bitWidth>1</bitWidth>
            </field>
            <field>
              <name>OC4PE</name>
              <bitOffset>11</bitOffset>
              <bitWidth>1</bitWidth>
            </field>
            <field>
              <name>OC4M</name>
              <bitOffset>12</bitOffset>
              <bitWidth>13</bitWidth>
            </field>
            <field>
              <name>OC4CE</name>
              <bitOffset>15</bitOffset>
              <bitWidth>1</bitWidth>
            </field>
          </fields>
        </register>
        <register>
          <name>CCER</name>
          <addressOffset>0x20</addressOffset>
          <size>0x20</size>
          <fields>
            <field>
              <name>CC1E</name>
              <bitOffset>0</bitOffset>
              <bitWidth>1</bitWidth>
            </field>
            <field>
              <name>CC1P</name>
              <bitOffset>1</bitOffset>
              <bitWidth>1</bitWidth>
            </field>
            <field>
              <name>CC1NE</name>
              <bitOffset>2</bitOffset>
              <bitWidth>1</bitWidth>
            </field>
            <field>
              <name>CC1NP</name>
              <bitOffset>3</bitOffset>
              <bitWidth>1</bitWidth>
            </field>
            <field>
              <name>CC2E</name>
              <bitOffset>4</bitOffset>
              <bitWidth>1</bitWidth>
            </field>
            <field>
              <name>CC2P</name>
              <bitOffset>5</bitOffset>
              <bitWidth>1</bitWidth>
            </field>
            <field>
              <name>CC2NE</name>
              <bitOffset>6</bitOffset>
              <bitWidth>1</bitWidth>
            </field>
            <field>
              <name>CC2NP</name>
              <bitOffset>7</bitOffset>
              <bitWidth>1</bitWidth>
            </field>
            <field>
              <name>CC3E</name>
              <bitOffset>8</bitOffset>
              <bitWidth>1</bitWidth>
            </field>
            <field>
              <name>CC3P</name>
              <bitOffset>9</bitOffset>
              <bitWidth>1</bitWidth>
            </field>
            <field>
              <name>CC3NE</name>
              <bitOffset>10</bitOffset>
              <bitWidth>1</bitWidth>
            </field>
            <field>
              <name>CC3NP</name>
              <bitOffset>11</bitOffset>
              <bitWidth>1</bitWidth>
            </field>
            <field>
              <name>CC4E</name>
              <bitOffset>12</bitOffset>
              <bitWidth>1</bitWidth>
            </field>
            <field>
              <name>CC4P</name>
              <bitOffset>13</bitOffset>
              <bitWidth>1</bitWidth>
            </field>
            <field>
              <name>CC4NP</name>
              <bitOffset>15</bitOffset>
              <bitWidth>1</bitWidth>
            </field>
            <field>
              <name>CC5E</name>
              <bitOffset>16</bitOffset>
              <bitWidth>1</bitWidth>
            </field>
            <field>
              <name>CC5P</name>
              <bitOffset>17</bitOffset>
              <bitWidth>1</bitWidth>
            </field>
            <field>
              <name>CC6E</name>
              <bitOffset>20</bitOffset>
              <bitWidth>1</bitWidth>
            </field>
            <field>
              <name>CC6P</name>
              <bitOffset>21</bitOffset>
              <bitWidth>1</bitWidth>
            </field>
          </fields>
        </register>
        <register>
          <name>CNT</name>
          <addressOffset>0x24</addressOffset>
          <size>0x20</size>
          <fields>
            <field>
              <name>CNT</name>
              <bitOffset>0</bitOffset>
              <bitWidth>32</bitWidth>
            </field>
            <field>
              <name>UIFCPY</name>
              <bitOffset>31</bitOffset>
              <bitWidth>1</bitWidth>
            </field>
          </fields>
        </register>
        <register>
          <name>PSC</name>
          <addressOffset>0x28</addressOffset>
          <size>0x20</size>
          <fields>
            <field>
              <name>PSC</name>
              <bitOffset>0</bitOffset>
              <bitWidth>16</bitWidth>
            </field>
          </fields>
        </register>
        <register>
          <name>ARR</name>
          <addressOffset>0x2c</addressOffset>
          <size>0x20</size>
          <fields>
            <field>
              <name>ARR</name>
              <bitOffset>0</bitOffset>
              <bitWidth>32</bitWidth>
            </field>
          </fields>
        </register>
        <register>
          <name>RCR</name>
          <addressOffset>0x30</addressOffset>
          <size>0x20</size>
          <fields>
            <field>
              <name>REP</name>
              <bitOffset>0</bitOffset>
              <bitWidth>16</bitWidth>
            </field>
          </fields>
        </register>
        <register>
          <name>CCR1</name>
          <addressOffset>0x34</addressOffset>
          <size>0x20</size>
          <fields>
            <field>
              <name>CCR1</name>
              <bitOffset>0</bitOffset>
              <bitWidth>16</bitWidth>
            </field>
          </fields>
        </register>
        <register>
          <name>CCR2</name>
          <addressOffset>0x38</addressOffset>
          <size>0x20</size>
          <fields>
            <field>
              <name>CCR2</name>
              <bitOffset>0</bitOffset>
              <bitWidth>16</bitWidth>
            </field>
          </fields>
        </register>
        <register>
          <name>CCR3</name>
          <addressOffset>0x3c</addressOffset>
          <size>0x20</size>
          <fields>
            <field>
              <name>CCR3</name>
              <bitOffset>0</bitOffset>
              <bitWidth>16</bitWidth>
            </field>
          </fields>
        </register>
        <register>
          <name>CCR4</name>
          <addressOffset>0x40</addressOffset>
          <size>0x20</size>
          <fields>
            <field>
              <name>CCR4</name>
              <bitOffset>0</bitOffset>
              <bitWidth>16</bitWidth>
            </field>
          </fields>
        </register>
        <register>
          <name>BDTR</name>
          <addressOffset>0x44</addressOffset>
          <size>0x20</size>
          <fields>
            <field>
              <name>DTG</name>
              <bitOffset>0</bitOffset>
              <bitWidth>8</bitWidth>
            </field>
            <field>
              <name>LOCK</name>
              <bitOffset>8</bitOffset>
              <bitWidth>2</bitWidth>
            </field>
            <field>
              <name>OSSI</name>
              <bitOffset>10</bitOffset>
              <bitWidth>1</bitWidth>
            </field>
            <field>
              <name>OSSR</name>
              <bitOffset>11</bitOffset>
              <bitWidth>1</bitWidth>
            </field>
            <field>
              <name>BKE</name>
              <bitOffset>12</bitOffset>
              <bitWidth>1</bitWidth>
            </field>
            <field>
              <name>BKP</name>
              <bitOffset>13</bitOffset>
              <bitWidth>1</bitWidth>
            </field>
            <field>
              <name>AOE</name>
              <bitOffset>14</bitOffset>
              <bitWidth>1</bitWidth>
            </field>
            <field>
              <name>MOE</name>
              <bitOffset>15</bitOffset>
              <bitWidth>1</bitWidth>
            </field>
            <field>
              <name>BKF</name>
              <bitOffset>16</bitOffset>
              <bitWidth>4</bitWidth>
            </field>
            <field>
              <name>BK2F</name>
              <bitOffset>20</bitOffset>
              <bitWidth>4</bitWidth>
            </field>
            <field>
              <name>BK2E</name>
              <bitOffset>24</bitOffset>
              <bitWidth>1</bitWidth>
            </field>
            <field>
              <name>BK2P</name>
              <bitOffset>25</bitOffset>
              <bitWidth>1</bitWidth>
            </field>
          </fields>
        </register>
        <register>
          <name>DCR</name>
          <addressOffset>0x48</addressOffset>
          <size>0x20</size>
          <fields>
            <field>
              <name>DBA</name>
              <bitOffset>0</bitOffset>
              <bitWidth>5</bitWidth>
            </field>
            <field>
              <name>DBL</name>
              <bitOffset>8</bitOffset>
              <bitWidth>5</bitWidth>
            </field>
          </fields>
        </register>
        <register>
          <name>DMAR</name>
          <addressOffset>0x4c</addressOffset>
          <size>0x20</size>
          <fields>
            <field>
              <name>DMAB</name>
              <bitOffset>0</bitOffset>
              <bitWidth>16</bitWidth>
            </field>
          </fields>
        </register>
        <register>
          <name>OR1</name>
          <addressOffset>0x50</addressOffset>
          <size>0x20</size>
        </register>
        <register>
          <name>CCMR3</name>
          <addressOffset>0x54</addressOffset>
          <size>0x20</size>
          <fields>
            <field>
              <name>OC5FE</name>
              <bitOffset>2</bitOffset>
              <bitWidth>1</bitWidth>
            </field>
            <field>
              <name>OC5PE</name>
              <bitOffset>3</bitOffset>
              <bitWidth>1</bitWidth>
            </field>
            <field>
              <name>OC5M</name>
              <bitOffset>4</bitOffset>
              <bitWidth>13</bitWidth>
            </field>
            <field>
              <name>OC5CE</name>
              <bitOffset>7</bitOffset>
              <bitWidth>1</bitWidth>
            </field>
            <field>
              <name>OC6FE</name>
              <bitOffset>10</bitOffset>
              <bitWidth>1</bitWidth>
            </field>
            <field>
              <name>OC6PE</name>
              <bitOffset>11</bitOffset>
              <bitWidth>1</bitWidth>
            </field>
            <field>
              <name>OC6M</name>
              <bitOffset>12</bitOffset>
              <bitWidth>13</bitWidth>
            </field>
            <field>
              <name>OC6CE</name>
              <bitOffset>15</bitOffset>
              <bitWidth>1</bitWidth>
            </field>
          </fields>
        </register>
        <register>
          <name>CCR5</name>
          <addressOffset>0x58</addressOffset>
          <size>0x20</size>
          <fields>
            <field>
              <name>CCR5</name>
              <bitOffset>0</bitOffset>
              <bitWidth>32</bitWidth>
            </field>
            <field>
              <name>GC5C1</name>
              <bitOffset>29</bitOffset>
              <bitWidth>1</bitWidth>
            </field>
            <field>
              <name>GC5C2</name>
              <bitOffset>30</bitOffset>
              <bitWidth>1</bitWidth>
            </field>
            <field>
              <name>GC5C3</name>
              <bitOffset>31</bitOffset>
              <bitWidth>1</bitWidth>
            </field>
          </fields>
        </register>
        <register>
          <name>CCR6</name>
          <addressOffset>0x5c</addressOffset>
          <size>0x20</size>
          <fields>
            <field>
              <name>CCR6</name>
              <bitOffset>0</bitOffset>
              <bitWidth>16</bitWidth>
            </field>
          </fields>
        </register>
        <register>
          <name>OR2</name>
          <addressOffset>0x60</addressOffset>
          <size>0x20</size>
        </register>
        <register>
          <name>OR3</name>
          <addressOffset>0x64</addressOffset>
          <size>0x20</size>
        </register>
      </registers>
    </peripheral>
    <peripheral>
      <name>SAI1</name>
      <baseAddress>0x40015400</baseAddress>
      <registers>
        <register>
          <name>GCR</name>
          <addressOffset>0x0</addressOffset>
          <size>0x20</size>
          <fields>
            <field>
              <name>SYNCIN</name>
              <bitOffset>0</bitOffset>
              <bitWidth>2</bitWidth>
            </field>
            <field>
              <name>SYNCOUT</name>
              <bitOffset>4</bitOffset>
              <bitWidth>2</bitWidth>
            </field>
          </fields>
        </register>
        <register>
          <name>CR1A</name>
          <addressOffset>0x4</addressOffset>
          <size>0x20</size>
          <fields>
            <field>
              <name>MODE</name>
              <bitOffset>0</bitOffset>
              <bitWidth>2</bitWidth>
            </field>
            <field>
              <name>PRTCFG</name>
              <bitOffset>2</bitOffset>
              <bitWidth>2</bitWidth>
            </field>
            <field>
              <name>DS</name>
              <bitOffset>5</bitOffset>
              <bitWidth>3</bitWidth>
            </field>
            <field>
              <name>LSBFIRST</name>
              <bitOffset>8</bitOffset>
              <bitWidth>1</bitWidth>
            </field>
            <field>
              <name>CKSTR</name>
              <bitOffset>9</bitOffset>
              <bitWidth>1</bitWidth>
            </field>
            <field>
              <name>SYNCEN</name>
              <bitOffset>10</bitOffset>
              <bitWidth>2</bitWidth>
            </field>
            <field>
              <name>MONO</name>
              <bitOffset>12</bitOffset>
              <bitWidth>1</bitWidth>
            </field>
            <field>
              <name>OUTDRIV</name>
              <bitOffset>13</bitOffset>
              <bitWidth>1</bitWidth>
            </field>
            <field>
              <name>SAIEN</name>
              <bitOffset>16</bitOffset>
              <bitWidth>1</bitWidth>
            </field>
            <field>
              <name>DMAEN</name>
              <bitOffset>17</bitOffset>
              <bitWidth>1</bitWidth>
            </field>
            <field>
              <name>NODIV</name>
              <bitOffset>19</bitOffset>
              <bitWidth>1</bitWidth>
            </field>
            <field>
              <name>MCKDIV</name>
              <bitOffset>20</bitOffset>
              <bitWidth>4</bitWidth>
            </field>
          </fields>
        </register>
        <register>
          <name>CR2A</name>
          <addressOffset>0x8</addressOffset>
          <size>0x20</size>
          <fields>
            <field>
              <name>FTH</name>
              <bitOffset>0</bitOffset>
              <bitWidth>3</bitWidth>
            </field>
            <field>
              <name>FFLUSH</name>
              <bitOffset>3</bitOffset>
              <bitWidth>1</bitWidth>
            </field>
            <field>
              <name>TRIS</name>
              <bitOffset>4</bitOffset>
              <bitWidth>1</bitWidth>
            </field>
            <field>
              <name>MUTE</name>
              <bitOffset>5</bitOffset>
              <bitWidth>1</bitWidth>
            </field>
            <field>
              <name>MUTEVAL</name>
              <bitOffset>6</bitOffset>
              <bitWidth>1</bitWidth>
            </field>
            <field>
              <name>MUTECNT</name>
              <bitOffset>7</bitOffset>
              <bitWidth>6</bitWidth>
            </field>
            <field>
              <name>CPL</name>
              <bitOffset>13</bitOffset>
              <bitWidth>1</bitWidth>
            </field>
            <field>
              <name>COMP</name>
              <bitOffset>14</bitOffset>
              <bitWidth>2</bitWidth>
            </field>
          </fields>
        </register>
        <register>
          <name>FRCRA</name>
          <addressOffset>0xc</addressOffset>
          <size>0x20</size>
          <fields>
            <field>
              <name>FRL</name>
              <bitOffset>0</bitOffset>
              <bitWidth>8</bitWidth>
            </field>
            <field>
              <name>FSALL</name>
              <bitOffset>8</bitOffset>
              <bitWidth>7</bitWidth>
            </field>
            <field>
              <name>FSDEF</name>
              <bitOffset>16</bitOffset>
              <bitWidth>1</bitWidth>
            </field>
            <field>
              <name>FSPOL</name>
              <bitOffset>17</bitOffset>
              <bitWidth>1</bitWidth>
            </field>
            <field>
              <name>FSOFF</name>
              <bitOffset>18</bitOffset>
              <bitWidth>1</bitWidth>
            </field>
          </fields>
        </register>
        <register>
          <name>SLOTRA</name>
          <addressOffset>0x10</addressOffset>
          <size>0x20</size>
          <fields>
            <field>
              <name>FBOFF</name>
              <bitOffset>0</bitOffset>
              <bitWidth>5</bitWidth>
            </field>
            <field>
              <name>SLOTSZ</name>
              <bitOffset>6</bitOffset>
              <bitWidth>2</bitWidth>
            </field>
            <field>
              <name>NBSLOT</name>
              <bitOffset>8</bitOffset>
              <bitWidth>4</bitWidth>
            </field>
            <field>
              <name>SLOTEN</name>
              <bitOffset>16</bitOffset>
              <bitWidth>16</bitWidth>
            </field>
          </fields>
        </register>
        <register>
          <name>IMRA</name>
          <addressOffset>0x14</addressOffset>
          <size>0x20</size>
          <fields>
            <field>
              <name>OVRUDRIE</name>
              <bitOffset>0</bitOffset>
              <bitWidth>1</bitWidth>
            </field>
            <field>
              <name>MUTEDETIE</name>
              <bitOffset>1</bitOffset>
              <bitWidth>1</bitWidth>
            </field>
            <field>
              <name>WCKCFGIE</name>
              <bitOffset>2</bitOffset>
              <bitWidth>1</bitWidth>
            </field>
            <field>
              <name>FREQIE</name>
              <bitOffset>3</bitOffset>
              <bitWidth>1</bitWidth>
            </field>
            <field>
              <name>CNRDYIE</name>
              <bitOffset>4</bitOffset>
              <bitWidth>1</bitWidth>
            </field>
            <field>
              <name>AFSDETIE</name>
              <bitOffset>5</bitOffset>
              <bitWidth>1</bitWidth>
            </field>
            <field>
              <name>LFSDETIE</name>
              <bitOffset>6</bitOffset>
              <bitWidth>1</bitWidth>
            </field>
          </fields>
        </register>
        <register>
          <name>SRA</name>
          <addressOffset>0x18</addressOffset>
          <size>0x20</size>
          <fields>
            <field>
              <name>OVRUDR</name>
              <bitOffset>0</bitOffset>
              <bitWidth>1</bitWidth>
            </field>
            <field>
              <name>MUTEDET</name>
              <bitOffset>1</bitOffset>
              <bitWidth>1</bitWidth>
            </field>
            <field>
              <name>WCKCFG</name>
              <bitOffset>2</bitOffset>
              <bitWidth>1</bitWidth>
            </field>
            <field>
              <name>FREQ</name>
              <bitOffset>3</bitOffset>
              <bitWidth>1</bitWidth>
            </field>
            <field>
              <name>CNRDY</name>
              <bitOffset>4</bitOffset>
              <bitWidth>1</bitWidth>
            </field>
            <field>
              <name>AFSDET</name>
              <bitOffset>5</bitOffset>
              <bitWidth>1</bitWidth>
            </field>
            <field>
              <name>LFSDET</name>
              <bitOffset>6</bitOffset>
              <bitWidth>1</bitWidth>
            </field>
            <field>
              <name>FLVL</name>
              <bitOffset>16</bitOffset>
              <bitWidth>3</bitWidth>
            </field>
          </fields>
        </register>
        <register>
          <name>CLRFRA</name>
          <addressOffset>0x1c</addressOffset>
          <size>0x20</size>
          <fields>
            <field>
              <name>COVRUDR</name>
              <bitOffset>0</bitOffset>
              <bitWidth>1</bitWidth>
            </field>
            <field>
              <name>CMUTEDET</name>
              <bitOffset>1</bitOffset>
              <bitWidth>1</bitWidth>
            </field>
            <field>
              <name>CWCKCFG</name>
              <bitOffset>2</bitOffset>
              <bitWidth>1</bitWidth>
            </field>
            <field>
              <name>CFREQ</name>
              <bitOffset>3</bitOffset>
              <bitWidth>1</bitWidth>
            </field>
            <field>
              <name>CCNRDY</name>
              <bitOffset>4</bitOffset>
              <bitWidth>1</bitWidth>
            </field>
            <field>
              <name>CAFSDET</name>
              <bitOffset>5</bitOffset>
              <bitWidth>1</bitWidth>
            </field>
            <field>
              <name>CLFSDET</name>
              <bitOffset>6</bitOffset>
              <bitWidth>1</bitWidth>
            </field>
          </fields>
        </register>
        <register>
          <name>DRA</name>
          <addressOffset>0x20</addressOffset>
          <size>0x20</size>
          <fields>
            <field>
              <name>DATA</name>
              <bitOffset>0</bitOffset>
              <bitWidth>32</bitWidth>
            </field>
          </fields>
        </register>
        <register>
          <name>CR1B</name>
          <addressOffset>0x24</addressOffset>
          <size>0x20</size>
          <fields>
            <field>
              <name>MODE</name>
              <bitOffset>0</bitOffset>
              <bitWidth>2</bitWidth>
            </field>
            <field>
              <name>PRTCFG</name>
              <bitOffset>2</bitOffset>
              <bitWidth>2</bitWidth>
            </field>
            <field>
              <name>DS</name>
              <bitOffset>5</bitOffset>
              <bitWidth>3</bitWidth>
            </field>
            <field>
              <name>LSBFIRST</name>
              <bitOffset>8</bitOffset>
              <bitWidth>1</bitWidth>
            </field>
            <field>
              <name>CKSTR</name>
              <bitOffset>9</bitOffset>
              <bitWidth>1</bitWidth>
            </field>
            <field>
              <name>SYNCEN</name>
              <bitOffset>10</bitOffset>
              <bitWidth>2</bitWidth>
            </field>
            <field>
              <name>MONO</name>
              <bitOffset>12</bitOffset>
              <bitWidth>1</bitWidth>
            </field>
            <field>
              <name>OUTDRIV</name>
              <bitOffset>13</bitOffset>
              <bitWidth>1</bitWidth>
            </field>
            <field>
              <name>SAIEN</name>
              <bitOffset>16</bitOffset>
              <bitWidth>1</bitWidth>
            </field>
            <field>
              <name>DMAEN</name>
              <bitOffset>17</bitOffset>
              <bitWidth>1</bitWidth>
            </field>
            <field>
              <name>NODIV</name>
              <bitOffset>19</bitOffset>
              <bitWidth>1</bitWidth>
            </field>
            <field>
              <name>MCKDIV</name>
              <bitOffset>20</bitOffset>
              <bitWidth>4</bitWidth>
            </field>
          </fields>
        </register>
        <register>
          <name>CR2B</name>
          <addressOffset>0x28</addressOffset>
          <size>0x20</size>
          <fields>
            <field>
              <name>FTH</name>
              <bitOffset>0</bitOffset>
              <bitWidth>3</bitWidth>
            </field>
            <field>
              <name>FFLUSH</name>
              <bitOffset>3</bitOffset>
              <bitWidth>1</bitWidth>
            </field>
            <field>
              <name>TRIS</name>
              <bitOffset>4</bitOffset>
              <bitWidth>1</bitWidth>
            </field>
            <field>
              <name>MUTE</name>
              <bitOffset>5</bitOffset>
              <bitWidth>1</bitWidth>
            </field>
            <field>
              <name>MUTEVAL</name>
              <bitOffset>6</bitOffset>
              <bitWidth>1</bitWidth>
            </field>
            <field>
              <name>MUTECNT</name>
              <bitOffset>7</bitOffset>
              <bitWidth>6</bitWidth>
            </field>
            <field>
              <name>CPL</name>
              <bitOffset>13</bitOffset>
              <bitWidth>1</bitWidth>
            </field>
            <field>
              <name>COMP</name>
              <bitOffset>14</bitOffset>
              <bitWidth>2</bitWidth>
            </field>
          </fields>
        </register>
        <register>
          <name>FRCRB</name>
          <addressOffset>0x2c</addressOffset>
          <size>0x20</size>
          <fields>
            <field>
              <name>FRL</name>
              <bitOffset>0</bitOffset>
              <bitWidth>8</bitWidth>
            </field>
            <field>
              <name>FSALL</name>
              <bitOffset>8</bitOffset>
              <bitWidth>7</bitWidth>
            </field>
            <field>
              <name>FSDEF</name>
              <bitOffset>16</bitOffset>
              <bitWidth>1</bitWidth>
            </field>
            <field>
              <name>FSPOL</name>
              <bitOffset>17</bitOffset>
              <bitWidth>1</bitWidth>
            </field>
            <field>
              <name>FSOFF</name>
              <bitOffset>18</bitOffset>
              <bitWidth>1</bitWidth>
            </field>
          </fields>
        </register>
        <register>
          <name>SLOTRB</name>
          <addressOffset>0x30</addressOffset>
          <size>0x20</size>
          <fields>
            <field>
              <name>FBOFF</name>
              <bitOffset>0</bitOffset>
              <bitWidth>5</bitWidth>
            </field>
            <field>
              <name>SLOTSZ</name>
              <bitOffset>6</bitOffset>
              <bitWidth>2</bitWidth>
            </field>
            <field>
              <name>NBSLOT</name>
              <bitOffset>8</bitOffset>
              <bitWidth>4</bitWidth>
            </field>
            <field>
              <name>SLOTEN</name>
              <bitOffset>16</bitOffset>
              <bitWidth>16</bitWidth>
            </field>
          </fields>
        </register>
        <register>
          <name>IMRB</name>
          <addressOffset>0x34</addressOffset>
          <size>0x20</size>
          <fields>
            <field>
              <name>OVRUDRIE</name>
              <bitOffset>0</bitOffset>
              <bitWidth>1</bitWidth>
            </field>
            <field>
              <name>MUTEDETIE</name>
              <bitOffset>1</bitOffset>
              <bitWidth>1</bitWidth>
            </field>
            <field>
              <name>WCKCFGIE</name>
              <bitOffset>2</bitOffset>
              <bitWidth>1</bitWidth>
            </field>
            <field>
              <name>FREQIE</name>
              <bitOffset>3</bitOffset>
              <bitWidth>1</bitWidth>
            </field>
            <field>
              <name>CNRDYIE</name>
              <bitOffset>4</bitOffset>
              <bitWidth>1</bitWidth>
            </field>
            <field>
              <name>AFSDETIE</name>
              <bitOffset>5</bitOffset>
              <bitWidth>1</bitWidth>
            </field>
            <field>
              <name>LFSDETIE</name>
              <bitOffset>6</bitOffset>
              <bitWidth>1</bitWidth>
            </field>
          </fields>
        </register>
        <register>
          <name>SRB</name>
          <addressOffset>0x38</addressOffset>
          <size>0x20</size>
          <fields>
            <field>
              <name>OVRUDR</name>
              <bitOffset>0</bitOffset>
              <bitWidth>1</bitWidth>
            </field>
            <field>
              <name>MUTEDET</name>
              <bitOffset>1</bitOffset>
              <bitWidth>1</bitWidth>
            </field>
            <field>
              <name>WCKCFG</name>
              <bitOffset>2</bitOffset>
              <bitWidth>1</bitWidth>
            </field>
            <field>
              <name>FREQ</name>
              <bitOffset>3</bitOffset>
              <bitWidth>1</bitWidth>
            </field>
            <field>
              <name>CNRDY</name>
              <bitOffset>4</bitOffset>
              <bitWidth>1</bitWidth>
            </field>
            <field>
              <name>AFSDET</name>
              <bitOffset>5</bitOffset>
              <bitWidth>1</bitWidth>
            </field>
            <field>
              <name>LFSDET</name>
              <bitOffset>6</bitOffset>
              <bitWidth>1</bitWidth>
            </field>
            <field>
              <name>FLVL</name>
              <bitOffset>16</bitOffset>
              <bitWidth>3</bitWidth>
            </field>
          </fields>
        </register>
        <register>
          <name>CLRFRB</name>
          <addressOffset>0x3c</addressOffset>
          <size>0x20</size>
          <fields>
            <field>
              <name>COVRUDR</name>
              <bitOffset>0</bitOffset>
              <bitWidth>1</bitWidth>
            </field>
            <field>
              <name>CMUTEDET</name>
              <bitOffset>1</bitOffset>
              <bitWidth>1</bitWidth>
            </field>
            <field>
              <name>CWCKCFG</name>
              <bitOffset>2</bitOffset>
              <bitWidth>1</bitWidth>
            </field>
            <field>
              <name>CFREQ</name>
              <bitOffset>3</bitOffset>
              <bitWidth>1</bitWidth>
            </field>
            <field>
              <name>CCNRDY</name>
              <bitOffset>4</bitOffset>
              <bitWidth>1</bitWidth>
            </field>
            <field>
              <name>CAFSDET</name>
              <bitOffset>5</bitOffset>
              <bitWidth>1</bitWidth>
            </field>
            <field>
              <name>CLFSDET</name>
              <bitOffset>6</bitOffset>
              <bitWidth>1</bitWidth>
            </field>
          </fields>
        </register>
        <register>
          <name>DRB</name>
          <addressOffset>0x40</addressOffset>
          <size>0x20</size>
          <fields>
            <field>
              <name>DATA</name>
              <bitOffset>0</bitOffset>
              <bitWidth>32</bitWidth>
            </field>
          </fields>
        </register>
      </registers>
    </peripheral>
    <peripheral>
      <name>DMA1</name>
      <baseAddress>0x40020000</baseAddress>
      <registers>
        <register>
          <name>ISR</name>
          <addressOffset>0x0</addressOffset>
          <size>0x20</size>
          <fields>
            <field>
              <name>GIF1</name>
              <bitOffset>0</bitOffset>
              <bitWidth>1</bitWidth>
            </field>
            <field>
              <name>TCIF1</name>
              <bitOffset>1</bitOffset>
              <bitWidth>1</bitWidth>
            </field>
            <field>
              <name>HTIF1</name>
              <bitOffset>2</bitOffset>
              <bitWidth>1</bitWidth>
            </field>
            <field>
              <name>TEIF1</name>
              <bitOffset>3</bitOffset>
              <bitWidth>1</bitWidth>
            </field>
            <field>
              <name>GIF2</name>
              <bitOffset>4</bitOffset>
              <bitWidth>1</bitWidth>
            </field>
            <field>
              <name>TCIF2</name>
              <bitOffset>5</bitOffset>
              <bitWidth>1</bitWidth>
            </field>
            <field>
              <name>HTIF2</name>
              <bitOffset>6</bitOffset>
              <bitWidth>1</bitWidth>
            </field>
            <field>
              <name>TEIF2</name>
              <bitOffset>7</bitOffset>
              <bitWidth>1</bitWidth>
            </field>
            <field>
              <name>GIF3</name>
              <bitOffset>8</bitOffset>
              <bitWidth>1</bitWidth>
            </field>
            <field>
              <name>TCIF3</name>
              <bitOffset>9</bitOffset>
              <bitWidth>1</bitWidth>
            </field>
            <field>
              <name>HTIF3</name>
              <bitOffset>10</bitOffset>
              <bitWidth>1</bitWidth>
            </field>
            <field>
              <name>TEIF3</name>
              <bitOffset>11</bitOffset>
              <bitWidth>1</bitWidth>
            </field>
            <field>
              <name>GIF4</name>
              <bitOffset>12</bitOffset>
              <bitWidth>1</bitWidth>
            </field>
            <field>
              <name>TCIF4</name>
              <bitOffset>13</bitOffset>
              <bitWidth>1</bitWidth>
            </field>
            <field>
              <name>HTIF4</name>
              <bitOffset>14</bitOffset>
              <bitWidth>1</bitWidth>
            </field>
            <field>
              <name>TEIF4</name>
              <bitOffset>15</bitOffset>
              <bitWidth>1</bitWidth>
            </field>
            <field>
              <name>GIF5</name>
              <bitOffset>16</bitOffset>
              <bitWidth>1</bitWidth>
            </field>
            <field>
              <name>TCIF5</name>
              <bitOffset>17</bitOffset>
              <bitWidth>1</bitWidth>
            </field>
            <field>
              <name>HTIF5</name>
              <bitOffset>18</bitOffset>
              <bitWidth>1</bitWidth>
            </field>
            <field>
              <name>TEIF5</name>
              <bitOffset>19</bitOffset>
              <bitWidth>1</bitWidth>
            </field>
            <field>
              <name>GIF6</name>
              <bitOffset>20</bitOffset>
              <bitWidth>1</bitWidth>
            </field>
            <field>
              <name>TCIF6</name>
              <bitOffset>21</bitOffset>
              <bitWidth>1</bitWidth>
            </field>
            <field>
              <name>HTIF6</name>
              <bitOffset>22</bitOffset>
              <bitWidth>1</bitWidth>
            </field>
            <field>
              <name>TEIF6</name>
              <bitOffset>23</bitOffset>
              <bitWidth>1</bitWidth>
            </field>
            <field>
              <name>GIF7</name>
              <bitOffset>24</bitOffset>
              <bitWidth>1</bitWidth>
            </field>
            <field>
              <name>TCIF7</name>
              <bitOffset>25</bitOffset>
              <bitWidth>1</bitWidth>
            </field>
            <field>
              <name>HTIF7</name>
              <bitOffset>26</bitOffset>
              <bitWidth>1</bitWidth>
            </field>
            <field>
              <name>TEIF7</name>
              <bitOffset>27</bitOffset>
              <bitWidth>1</bitWidth>
            </field>
          </fields>
        </register>
        <register>
          <name>IFCR</name>
          <addressOffset>0x4</addressOffset>
          <size>0x20</size>
          <fields>
            <field>
              <name>CGIF1</name>
              <bitOffset>0</bitOffset>
              <bitWidth>1</bitWidth>
            </field>
            <field>
              <name>CTCIF1</name>
              <bitOffset>1</bitOffset>
              <bitWidth>1</bitWidth>
            </field>
            <field>
              <name>CHTIF1</name>
              <bitOffset>2</bitOffset>
              <bitWidth>1</bitWidth>
            </field>
            <field>
              <name>CTEIF1</name>
              <bitOffset>3</bitOffset>
              <bitWidth>1</bitWidth>
            </field>
            <field>
              <name>CGIF2</name>
              <bitOffset>4</bitOffset>
              <bitWidth>1</bitWidth>
            </field>
            <field>
              <name>CTCIF2</name>
              <bitOffset>5</bitOffset>
              <bitWidth>1</bitWidth>
            </field>
            <field>
              <name>CHTIF2</name>
              <bitOffset>6</bitOffset>
              <bitWidth>1</bitWidth>
            </field>
            <field>
              <name>CTEIF2</name>
              <bitOffset>7</bitOffset>
              <bitWidth>1</bitWidth>
            </field>
            <field>
              <name>CGIF3</name>
              <bitOffset>8</bitOffset>
              <bitWidth>1</bitWidth>
            </field>
            <field>
              <name>CTCIF3</name>
              <bitOffset>9</bitOffset>
              <bitWidth>1</bitWidth>
            </field>
            <field>
              <name>CHTIF3</name>
              <bitOffset>10</bitOffset>
              <bitWidth>1</bitWidth>
            </field>
            <field>
              <name>CTEIF3</name>
              <bitOffset>11</bitOffset>
              <bitWidth>1</bitWidth>
            </field>
            <field>
              <name>CGIF4</name>
              <bitOffset>12</bitOffset>
              <bitWidth>1</bitWidth>
            </field>
            <field>
              <name>CTCIF4</name>
              <bitOffset>13</bitOffset>
              <bitWidth>1</bitWidth>
            </field>
            <field>
              <name>CHTIF4</name>
              <bitOffset>14</bitOffset>
              <bitWidth>1</bitWidth>
            </field>
            <field>
              <name>CTEIF4</name>
              <bitOffset>15</bitOffset>
              <bitWidth>1</bitWidth>
            </field>
            <field>
              <name>CGIF5</name>
              <bitOffset>16</bitOffset>
              <bitWidth>1</bitWidth>
            </field>
            <field>
              <name>CTCIF5</name>
              <bitOffset>17</bitOffset>
              <bitWidth>1</bitWidth>
            </field>
            <field>
              <name>CHTIF5</name>
              <bitOffset>18</bitOffset>
              <bitWidth>1</bitWidth>
            </field>
            <field>
              <name>CTEIF5</name>
              <bitOffset>19</bitOffset>
              <bitWidth>1</bitWidth>
            </field>
            <field>
              <name>CGIF6</name>
              <bitOffset>20</bitOffset>
              <bitWidth>1</bitWidth>
            </field>
            <field>
              <name>CTCIF6</name>
              <bitOffset>21</bitOffset>
              <bitWidth>1</bitWidth>
            </field>
            <field>
              <name>CHTIF6</name>
              <bitOffset>22</bitOffset>
              <bitWidth>1</bitWidth>
            </field>
            <field>
              <name>CTEIF6</name>
              <bitOffset>23</bitOffset>
              <bitWidth>1</bitWidth>
            </field>
            <field>
              <name>CGIF7</name>
              <bitOffset>24</bitOffset>
              <bitWidth>1</bitWidth>
            </field>
            <field>
              <name>CTCIF7</name>
              <bitOffset>25</bitOffset>
              <bitWidth>1</bitWidth>
            </field>
            <field>
              <name>CHTIF7</name>
              <bitOffset>26</bitOffset>
              <bitWidth>1</bitWidth>
            </field>
            <field>
              <name>CTEIF7</name>
              <bitOffset>27</bitOffset>
              <bitWidth>1</bitWidth>
            </field>
          </fields>
        </register>
        <register>
          <name>CCR1</name>
          <addressOffset>0x8</addressOffset>
          <size>0x20</size>
          <fields>
            <field>
              <name>EN</name>
              <bitOffset>0</bitOffset>
              <bitWidth>1</bitWidth>
            </field>
            <field>
              <name>TCIE</name>
              <bitOffset>1</bitOffset>
              <bitWidth>1</bitWidth>
            </field>
            <field>
              <name>HTIE</name>
              <bitOffset>2</bitOffset>
              <bitWidth>1</bitWidth>
            </field>
            <field>
              <name>TEIE</name>
              <bitOffset>3</bitOffset>
              <bitWidth>1</bitWidth>
            </field>
            <field>
              <name>DIR</name>
              <bitOffset>4</bitOffset>
              <bitWidth>1</bitWidth>
            </field>
            <field>
              <name>CIRC</name>
              <bitOffset>5</bitOffset>
              <bitWidth>1</bitWidth>
            </field>
            <field>
              <name>PINC</name>
              <bitOffset>6</bitOffset>
              <bitWidth>1</bitWidth>
            </field>
            <field>
              <name>MINC</name>
              <bitOffset>7</bitOffset>
              <bitWidth>1</bitWidth>
            </field>
            <field>
              <name>PSIZE</name>
              <bitOffset>8</bitOffset>
              <bitWidth>2</bitWidth>
            </field>
            <field>
              <name>MSIZE</name>
              <bitOffset>10</bitOffset>
              <bitWidth>2</bitWidth>
            </field>
            <field>
              <name>PL</name>
              <bitOffset>12</bitOffset>
              <bitWidth>2</bitWidth>
            </field>
            <field>
              <name>MEM2MEM</name>
              <bitOffset>14</bitOffset>
              <bitWidth>1</bitWidth>
            </field>
          </fields>
        </register>
        <register>
          <name>CCR1</name>
          <addressOffset>0x8</addressOffset>
          <size>0x20</size>
          <fields>
            <field>
              <name>EN</name>
              <bitOffset>0</bitOffset>
              <bitWidth>1</bitWidth>
            </field>
            <field>
              <name>TCIE</name>
              <bitOffset>1</bitOffset>
              <bitWidth>1</bitWidth>
            </field>
            <field>
              <name>HTIE</name>
              <bitOffset>2</bitOffset>
              <bitWidth>1</bitWidth>
            </field>
            <field>
              <name>TEIE</name>
              <bitOffset>3</bitOffset>
              <bitWidth>1</bitWidth>
            </field>
            <field>
              <name>DIR</name>
              <bitOffset>4</bitOffset>
              <bitWidth>1</bitWidth>
            </field>
            <field>
              <name>CIRC</name>
              <bitOffset>5</bitOffset>
              <bitWidth>1</bitWidth>
            </field>
            <field>
              <name>PINC</name>
              <bitOffset>6</bitOffset>
              <bitWidth>1</bitWidth>
            </field>
            <field>
              <name>MINC</name>
              <bitOffset>7</bitOffset>
              <bitWidth>1</bitWidth>
            </field>
            <field>
              <name>PSIZE</name>
              <bitOffset>8</bitOffset>
              <bitWidth>2</bitWidth>
            </field>
            <field>
              <name>MSIZE</name>
              <bitOffset>10</bitOffset>
              <bitWidth>2</bitWidth>
            </field>
            <field>
              <name>PL</name>
              <bitOffset>12</bitOffset>
              <bitWidth>2</bitWidth>
            </field>
            <field>
              <name>MEM2MEM</name>
              <bitOffset>14</bitOffset>
              <bitWidth>1</bitWidth>
            </field>
          </fields>
        </register>
        <register>
          <name>CNDTR1</name>
          <addressOffset>0xc</addressOffset>
          <size>0x20</size>
          <fields>
            <field>
              <name>NDT</name>
              <bitOffset>0</bitOffset>
              <bitWidth>16</bitWidth>
            </field>
          </fields>
        </register>
        <register>
          <name>CNDTR1</name>
          <addressOffset>0xc</addressOffset>
          <size>0x20</size>
          <fields>
            <field>
              <name>NDT</name>
              <bitOffset>0</bitOffset>
              <bitWidth>16</bitWidth>
            </field>
          </fields>
        </register>
        <register>
          <name>CPAR1</name>
          <addressOffset>0x10</addressOffset>
          <size>0x20</size>
          <fields>
            <field>
              <name>PA</name>
              <bitOffset>0</bitOffset>
              <bitWidth>32</bitWidth>
            </field>
          </fields>
        </register>
        <register>
          <name>CPAR1</name>
          <addressOffset>0x10</addressOffset>
          <size>0x20</size>
          <fields>
            <field>
              <name>PA</name>
              <bitOffset>0</bitOffset>
              <bitWidth>32</bitWidth>
            </field>
          </fields>
        </register>
        <register>
          <name>CMAR1</name>
          <addressOffset>0x14</addressOffset>
          <size>0x20</size>
          <fields>
            <field>
              <name>MA</name>
              <bitOffset>0</bitOffset>
              <bitWidth>32</bitWidth>
            </field>
          </fields>
        </register>
        <register>
          <name>CMAR1</name>
          <addressOffset>0x14</addressOffset>
          <size>0x20</size>
          <fields>
            <field>
              <name>MA</name>
              <bitOffset>0</bitOffset>
              <bitWidth>32</bitWidth>
            </field>
          </fields>
        </register>
        <register>
          <name>CCR2</name>
          <addressOffset>0x1c</addressOffset>
          <size>0x20</size>
          <fields>
            <field>
              <name>EN</name>
              <bitOffset>0</bitOffset>
              <bitWidth>1</bitWidth>
            </field>
            <field>
              <name>TCIE</name>
              <bitOffset>1</bitOffset>
              <bitWidth>1</bitWidth>
            </field>
            <field>
              <name>HTIE</name>
              <bitOffset>2</bitOffset>
              <bitWidth>1</bitWidth>
            </field>
            <field>
              <name>TEIE</name>
              <bitOffset>3</bitOffset>
              <bitWidth>1</bitWidth>
            </field>
            <field>
              <name>DIR</name>
              <bitOffset>4</bitOffset>
              <bitWidth>1</bitWidth>
            </field>
            <field>
              <name>CIRC</name>
              <bitOffset>5</bitOffset>
              <bitWidth>1</bitWidth>
            </field>
            <field>
              <name>PINC</name>
              <bitOffset>6</bitOffset>
              <bitWidth>1</bitWidth>
            </field>
            <field>
              <name>MINC</name>
              <bitOffset>7</bitOffset>
              <bitWidth>1</bitWidth>
            </field>
            <field>
              <name>PSIZE</name>
              <bitOffset>8</bitOffset>
              <bitWidth>2</bitWidth>
            </field>
            <field>
              <name>MSIZE</name>
              <bitOffset>10</bitOffset>
              <bitWidth>2</bitWidth>
            </field>
            <field>
              <name>PL</name>
              <bitOffset>12</bitOffset>
              <bitWidth>2</bitWidth>
            </field>
            <field>
              <name>MEM2MEM</name>
              <bitOffset>14</bitOffset>
              <bitWidth>1</bitWidth>
            </field>
          </fields>
        </register>
        <register>
          <name>CCR2</name>
          <addressOffset>0x1c</addressOffset>
          <size>0x20</size>
          <fields>
            <field>
              <name>EN</name>
              <bitOffset>0</bitOffset>
              <bitWidth>1</bitWidth>
            </field>
            <field>
              <name>TCIE</name>
              <bitOffset>1</bitOffset>
              <bitWidth>1</bitWidth>
            </field>
            <field>
              <name>HTIE</name>
              <bitOffset>2</bitOffset>
              <bitWidth>1</bitWidth>
            </field>
            <field>
              <name>TEIE</name>
              <bitOffset>3</bitOffset>
              <bitWidth>1</bitWidth>
            </field>
            <field>
              <name>DIR</name>
              <bitOffset>4</bitOffset>
              <bitWidth>1</bitWidth>
            </field>
            <field>
              <name>CIRC</name>
              <bitOffset>5</bitOffset>
              <bitWidth>1</bitWidth>
            </field>
            <field>
              <name>PINC</name>
              <bitOffset>6</bitOffset>
              <bitWidth>1</bitWidth>
            </field>
            <field>
              <name>MINC</name>
              <bitOffset>7</bitOffset>
              <bitWidth>1</bitWidth>
            </field>
            <field>
              <name>PSIZE</name>
              <bitOffset>8</bitOffset>
              <bitWidth>2</bitWidth>
            </field>
            <field>
              <name>MSIZE</name>
              <bitOffset>10</bitOffset>
              <bitWidth>2</bitWidth>
            </field>
            <field>
              <name>PL</name>
              <bitOffset>12</bitOffset>
              <bitWidth>2</bitWidth>
            </field>
            <field>
              <name>MEM2MEM</name>
              <bitOffset>14</bitOffset>
              <bitWidth>1</bitWidth>
            </field>
          </fields>
        </register>
        <register>
          <name>CNDTR2</name>
          <addressOffset>0x20</addressOffset>
          <size>0x20</size>
          <fields>
            <field>
              <name>NDT</name>
              <bitOffset>0</bitOffset>
              <bitWidth>16</bitWidth>
            </field>
          </fields>
        </register>
        <register>
          <name>CNDTR2</name>
          <addressOffset>0x20</addressOffset>
          <size>0x20</size>
          <fields>
            <field>
              <name>NDT</name>
              <bitOffset>0</bitOffset>
              <bitWidth>16</bitWidth>
            </field>
          </fields>
        </register>
        <register>
          <name>CPAR2</name>
          <addressOffset>0x24</addressOffset>
          <size>0x20</size>
          <fields>
            <field>
              <name>PA</name>
              <bitOffset>0</bitOffset>
              <bitWidth>32</bitWidth>
            </field>
          </fields>
        </register>
        <register>
          <name>CPAR2</name>
          <addressOffset>0x24</addressOffset>
          <size>0x20</size>
          <fields>
            <field>
              <name>PA</name>
              <bitOffset>0</bitOffset>
              <bitWidth>32</bitWidth>
            </field>
          </fields>
        </register>
        <register>
          <name>CMAR2</name>
          <addressOffset>0x28</addressOffset>
          <size>0x20</size>
          <fields>
            <field>
              <name>MA</name>
              <bitOffset>0</bitOffset>
              <bitWidth>32</bitWidth>
            </field>
          </fields>
        </register>
        <register>
          <name>CMAR2</name>
          <addressOffset>0x28</addressOffset>
          <size>0x20</size>
          <fields>
            <field>
              <name>MA</name>
              <bitOffset>0</bitOffset>
              <bitWidth>32</bitWidth>
            </field>
          </fields>
        </register>
        <register>
          <name>CCR3</name>
          <addressOffset>0x30</addressOffset>
          <size>0x20</size>
          <fields>
            <field>
              <name>EN</name>
              <bitOffset>0</bitOffset>
              <bitWidth>1</bitWidth>
            </field>
            <field>
              <name>TCIE</name>
              <bitOffset>1</bitOffset>
              <bitWidth>1</bitWidth>
            </field>
            <field>
              <name>HTIE</name>
              <bitOffset>2</bitOffset>
              <bitWidth>1</bitWidth>
            </field>
            <field>
              <name>TEIE</name>
              <bitOffset>3</bitOffset>
              <bitWidth>1</bitWidth>
            </field>
            <field>
              <name>DIR</name>
              <bitOffset>4</bitOffset>
              <bitWidth>1</bitWidth>
            </field>
            <field>
              <name>CIRC</name>
              <bitOffset>5</bitOffset>
              <bitWidth>1</bitWidth>
            </field>
            <field>
              <name>PINC</name>
              <bitOffset>6</bitOffset>
              <bitWidth>1</bitWidth>
            </field>
            <field>
              <name>MINC</name>
              <bitOffset>7</bitOffset>
              <bitWidth>1</bitWidth>
            </field>
            <field>
              <name>PSIZE</name>
              <bitOffset>8</bitOffset>
              <bitWidth>2</bitWidth>
            </field>
            <field>
              <name>MSIZE</name>
              <bitOffset>10</bitOffset>
              <bitWidth>2</bitWidth>
            </field>
            <field>
              <name>PL</name>
              <bitOffset>12</bitOffset>
              <bitWidth>2</bitWidth>
            </field>
            <field>
              <name>MEM2MEM</name>
              <bitOffset>14</bitOffset>
              <bitWidth>1</bitWidth>
            </field>
          </fields>
        </register>
        <register>
          <name>CCR3</name>
          <addressOffset>0x30</addressOffset>
          <size>0x20</size>
          <fields>
            <field>
              <name>EN</name>
              <bitOffset>0</bitOffset>
              <bitWidth>1</bitWidth>
            </field>
            <field>
              <name>TCIE</name>
              <bitOffset>1</bitOffset>
              <bitWidth>1</bitWidth>
            </field>
            <field>
              <name>HTIE</name>
              <bitOffset>2</bitOffset>
              <bitWidth>1</bitWidth>
            </field>
            <field>
              <name>TEIE</name>
              <bitOffset>3</bitOffset>
              <bitWidth>1</bitWidth>
            </field>
            <field>
              <name>DIR</name>
              <bitOffset>4</bitOffset>
              <bitWidth>1</bitWidth>
            </field>
            <field>
              <name>CIRC</name>
              <bitOffset>5</bitOffset>
              <bitWidth>1</bitWidth>
            </field>
            <field>
              <name>PINC</name>
              <bitOffset>6</bitOffset>
              <bitWidth>1</bitWidth>
            </field>
            <field>
              <name>MINC</name>
              <bitOffset>7</bitOffset>
              <bitWidth>1</bitWidth>
            </field>
            <field>
              <name>PSIZE</name>
              <bitOffset>8</bitOffset>
              <bitWidth>2</bitWidth>
            </field>
            <field>
              <name>MSIZE</name>
              <bitOffset>10</bitOffset>
              <bitWidth>2</bitWidth>
            </field>
            <field>
              <name>PL</name>
              <bitOffset>12</bitOffset>
              <bitWidth>2</bitWidth>
            </field>
            <field>
              <name>MEM2MEM</name>
              <bitOffset>14</bitOffset>
              <bitWidth>1</bitWidth>
            </field>
          </fields>
        </register>
        <register>
          <name>CNDTR3</name>
          <addressOffset>0x34</addressOffset>
          <size>0x20</size>
          <fields>
            <field>
              <name>NDT</name>
              <bitOffset>0</bitOffset>
              <bitWidth>16</bitWidth>
            </field>
          </fields>
        </register>
        <register>
          <name>CNDTR3</name>
          <addressOffset>0x34</addressOffset>
          <size>0x20</size>
          <fields>
            <field>
              <name>NDT</name>
              <bitOffset>0</bitOffset>
              <bitWidth>16</bitWidth>
            </field>
          </fields>
        </register>
        <register>
          <name>CPAR3</name>
          <addressOffset>0x38</addressOffset>
          <size>0x20</size>
          <fields>
            <field>
              <name>PA</name>
              <bitOffset>0</bitOffset>
              <bitWidth>32</bitWidth>
            </field>
          </fields>
        </register>
        <register>
          <name>CPAR3</name>
          <addressOffset>0x38</addressOffset>
          <size>0x20</size>
          <fields>
            <field>
              <name>PA</name>
              <bitOffset>0</bitOffset>
              <bitWidth>32</bitWidth>
            </field>
          </fields>
        </register>
        <register>
          <name>CMAR3</name>
          <addressOffset>0x3c</addressOffset>
          <size>0x20</size>
          <fields>
            <field>
              <name>MA</name>
              <bitOffset>0</bitOffset>
              <bitWidth>32</bitWidth>
            </field>
          </fields>
        </register>
        <register>
          <name>CMAR3</name>
          <addressOffset>0x3c</addressOffset>
          <size>0x20</size>
          <fields>
            <field>
              <name>MA</name>
              <bitOffset>0</bitOffset>
              <bitWidth>32</bitWidth>
            </field>
          </fields>
        </register>
        <register>
          <name>CCR4</name>
          <addressOffset>0x44</addressOffset>
          <size>0x20</size>
          <fields>
            <field>
              <name>EN</name>
              <bitOffset>0</bitOffset>
              <bitWidth>1</bitWidth>
            </field>
            <field>
              <name>TCIE</name>
              <bitOffset>1</bitOffset>
              <bitWidth>1</bitWidth>
            </field>
            <field>
              <name>HTIE</name>
              <bitOffset>2</bitOffset>
              <bitWidth>1</bitWidth>
            </field>
            <field>
              <name>TEIE</name>
              <bitOffset>3</bitOffset>
              <bitWidth>1</bitWidth>
            </field>
            <field>
              <name>DIR</name>
              <bitOffset>4</bitOffset>
              <bitWidth>1</bitWidth>
            </field>
            <field>
              <name>CIRC</name>
              <bitOffset>5</bitOffset>
              <bitWidth>1</bitWidth>
            </field>
            <field>
              <name>PINC</name>
              <bitOffset>6</bitOffset>
              <bitWidth>1</bitWidth>
            </field>
            <field>
              <name>MINC</name>
              <bitOffset>7</bitOffset>
              <bitWidth>1</bitWidth>
            </field>
            <field>
              <name>PSIZE</name>
              <bitOffset>8</bitOffset>
              <bitWidth>2</bitWidth>
            </field>
            <field>
              <name>MSIZE</name>
              <bitOffset>10</bitOffset>
              <bitWidth>2</bitWidth>
            </field>
            <field>
              <name>PL</name>
              <bitOffset>12</bitOffset>
              <bitWidth>2</bitWidth>
            </field>
            <field>
              <name>MEM2MEM</name>
              <bitOffset>14</bitOffset>
              <bitWidth>1</bitWidth>
            </field>
          </fields>
        </register>
        <register>
          <name>CCR4</name>
          <addressOffset>0x44</addressOffset>
          <size>0x20</size>
          <fields>
            <field>
              <name>EN</name>
              <bitOffset>0</bitOffset>
              <bitWidth>1</bitWidth>
            </field>
            <field>
              <name>TCIE</name>
              <bitOffset>1</bitOffset>
              <bitWidth>1</bitWidth>
            </field>
            <field>
              <name>HTIE</name>
              <bitOffset>2</bitOffset>
              <bitWidth>1</bitWidth>
            </field>
            <field>
              <name>TEIE</name>
              <bitOffset>3</bitOffset>
              <bitWidth>1</bitWidth>
            </field>
            <field>
              <name>DIR</name>
              <bitOffset>4</bitOffset>
              <bitWidth>1</bitWidth>
            </field>
            <field>
              <name>CIRC</name>
              <bitOffset>5</bitOffset>
              <bitWidth>1</bitWidth>
            </field>
            <field>
              <name>PINC</name>
              <bitOffset>6</bitOffset>
              <bitWidth>1</bitWidth>
            </field>
            <field>
              <name>MINC</name>
              <bitOffset>7</bitOffset>
              <bitWidth>1</bitWidth>
            </field>
            <field>
              <name>PSIZE</name>
              <bitOffset>8</bitOffset>
              <bitWidth>2</bitWidth>
            </field>
            <field>
              <name>MSIZE</name>
              <bitOffset>10</bitOffset>
              <bitWidth>2</bitWidth>
            </field>
            <field>
              <name>PL</name>
              <bitOffset>12</bitOffset>
              <bitWidth>2</bitWidth>
            </field>
            <field>
              <name>MEM2MEM</name>
              <bitOffset>14</bitOffset>
              <bitWidth>1</bitWidth>
            </field>
          </fields>
        </register>
        <register>
          <name>CNDTR4</name>
          <addressOffset>0x48</addressOffset>
          <size>0x20</size>
          <fields>
            <field>
              <name>NDT</name>
              <bitOffset>0</bitOffset>
              <bitWidth>16</bitWidth>
            </field>
          </fields>
        </register>
        <register>
          <name>CNDTR4</name>
          <addressOffset>0x48</addressOffset>
          <size>0x20</size>
          <fields>
            <field>
              <name>NDT</name>
              <bitOffset>0</bitOffset>
              <bitWidth>16</bitWidth>
            </field>
          </fields>
        </register>
        <register>
          <name>CPAR4</name>
          <addressOffset>0x4c</addressOffset>
          <size>0x20</size>
          <fields>
            <field>
              <name>PA</name>
              <bitOffset>0</bitOffset>
              <bitWidth>32</bitWidth>
            </field>
          </fields>
        </register>
        <register>
          <name>CPAR4</name>
          <addressOffset>0x4c</addressOffset>
          <size>0x20</size>
          <fields>
            <field>
              <name>PA</name>
              <bitOffset>0</bitOffset>
              <bitWidth>32</bitWidth>
            </field>
          </fields>
        </register>
        <register>
          <name>CMAR4</name>
          <addressOffset>0x50</addressOffset>
          <size>0x20</size>
          <fields>
            <field>
              <name>MA</name>
              <bitOffset>0</bitOffset>
              <bitWidth>32</bitWidth>
            </field>
          </fields>
        </register>
        <register>
          <name>CMAR4</name>
          <addressOffset>0x50</addressOffset>
          <size>0x20</size>
          <fields>
            <field>
              <name>MA</name>
              <bitOffset>0</bitOffset>
              <bitWidth>32</bitWidth>
            </field>
          </fields>
        </register>
        <register>
          <name>CCR5</name>
          <addressOffset>0x58</addressOffset>
          <size>0x20</size>
          <fields>
            <field>
              <name>EN</name>
              <bitOffset>0</bitOffset>
              <bitWidth>1</bitWidth>
            </field>
            <field>
              <name>TCIE</name>
              <bitOffset>1</bitOffset>
              <bitWidth>1</bitWidth>
            </field>
            <field>
              <name>HTIE</name>
              <bitOffset>2</bitOffset>
              <bitWidth>1</bitWidth>
            </field>
            <field>
              <name>TEIE</name>
              <bitOffset>3</bitOffset>
              <bitWidth>1</bitWidth>
            </field>
            <field>
              <name>DIR</name>
              <bitOffset>4</bitOffset>
              <bitWidth>1</bitWidth>
            </field>
            <field>
              <name>CIRC</name>
              <bitOffset>5</bitOffset>
              <bitWidth>1</bitWidth>
            </field>
            <field>
              <name>PINC</name>
              <bitOffset>6</bitOffset>
              <bitWidth>1</bitWidth>
            </field>
            <field>
              <name>MINC</name>
              <bitOffset>7</bitOffset>
              <bitWidth>1</bitWidth>
            </field>
            <field>
              <name>PSIZE</name>
              <bitOffset>8</bitOffset>
              <bitWidth>2</bitWidth>
            </field>
            <field>
              <name>MSIZE</name>
              <bitOffset>10</bitOffset>
              <bitWidth>2</bitWidth>
            </field>
            <field>
              <name>PL</name>
              <bitOffset>12</bitOffset>
              <bitWidth>2</bitWidth>
            </field>
            <field>
              <name>MEM2MEM</name>
              <bitOffset>14</bitOffset>
              <bitWidth>1</bitWidth>
            </field>
          </fields>
        </register>
        <register>
          <name>CCR5</name>
          <addressOffset>0x58</addressOffset>
          <size>0x20</size>
          <fields>
            <field>
              <name>EN</name>
              <bitOffset>0</bitOffset>
              <bitWidth>1</bitWidth>
            </field>
            <field>
              <name>TCIE</name>
              <bitOffset>1</bitOffset>
              <bitWidth>1</bitWidth>
            </field>
            <field>
              <name>HTIE</name>
              <bitOffset>2</bitOffset>
              <bitWidth>1</bitWidth>
            </field>
            <field>
              <name>TEIE</name>
              <bitOffset>3</bitOffset>
              <bitWidth>1</bitWidth>
            </field>
            <field>
              <name>DIR</name>
              <bitOffset>4</bitOffset>
              <bitWidth>1</bitWidth>
            </field>
            <field>
              <name>CIRC</name>
              <bitOffset>5</bitOffset>
              <bitWidth>1</bitWidth>
            </field>
            <field>
              <name>PINC</name>
              <bitOffset>6</bitOffset>
              <bitWidth>1</bitWidth>
            </field>
            <field>
              <name>MINC</name>
              <bitOffset>7</bitOffset>
              <bitWidth>1</bitWidth>
            </field>
            <field>
              <name>PSIZE</name>
              <bitOffset>8</bitOffset>
              <bitWidth>2</bitWidth>
            </field>
            <field>
              <name>MSIZE</name>
              <bitOffset>10</bitOffset>
              <bitWidth>2</bitWidth>
            </field>
            <field>
              <name>PL</name>
              <bitOffset>12</bitOffset>
              <bitWidth>2</bitWidth>
            </field>
            <field>
              <name>MEM2MEM</name>
              <bitOffset>14</bitOffset>
              <bitWidth>1</bitWidth>
            </field>
          </fields>
        </register>
        <register>
          <name>CNDTR5</name>
          <addressOffset>0x5c</addressOffset>
          <size>0x20</size>
          <fields>
            <field>
              <name>NDT</name>
              <bitOffset>0</bitOffset>
              <bitWidth>16</bitWidth>
            </field>
          </fields>
        </register>
        <register>
          <name>CNDTR5</name>
          <addressOffset>0x5c</addressOffset>
          <size>0x20</size>
          <fields>
            <field>
              <name>NDT</name>
              <bitOffset>0</bitOffset>
              <bitWidth>16</bitWidth>
            </field>
          </fields>
        </register>
        <register>
          <name>CPAR5</name>
          <addressOffset>0x60</addressOffset>
          <size>0x20</size>
          <fields>
            <field>
              <name>PA</name>
              <bitOffset>0</bitOffset>
              <bitWidth>32</bitWidth>
            </field>
          </fields>
        </register>
        <register>
          <name>CPAR5</name>
          <addressOffset>0x60</addressOffset>
          <size>0x20</size>
          <fields>
            <field>
              <name>PA</name>
              <bitOffset>0</bitOffset>
              <bitWidth>32</bitWidth>
            </field>
          </fields>
        </register>
        <register>
          <name>CMAR5</name>
          <addressOffset>0x64</addressOffset>
          <size>0x20</size>
          <fields>
            <field>
              <name>MA</name>
              <bitOffset>0</bitOffset>
              <bitWidth>32</bitWidth>
            </field>
          </fields>
        </register>
        <register>
          <name>CMAR5</name>
          <addressOffset>0x64</addressOffset>
          <size>0x20</size>
          <fields>
            <field>
              <name>MA</name>
              <bitOffset>0</bitOffset>
              <bitWidth>32</bitWidth>
            </field>
          </fields>
        </register>
        <register>
          <name>CCR6</name>
          <addressOffset>0x6c</addressOffset>
          <size>0x20</size>
          <fields>
            <field>
              <name>EN</name>
              <bitOffset>0</bitOffset>
              <bitWidth>1</bitWidth>
            </field>
            <field>
              <name>TCIE</name>
              <bitOffset>1</bitOffset>
              <bitWidth>1</bitWidth>
            </field>
            <field>
              <name>HTIE</name>
              <bitOffset>2</bitOffset>
              <bitWidth>1</bitWidth>
            </field>
            <field>
              <name>TEIE</name>
              <bitOffset>3</bitOffset>
              <bitWidth>1</bitWidth>
            </field>
            <field>
              <name>DIR</name>
              <bitOffset>4</bitOffset>
              <bitWidth>1</bitWidth>
            </field>
            <field>
              <name>CIRC</name>
              <bitOffset>5</bitOffset>
              <bitWidth>1</bitWidth>
            </field>
            <field>
              <name>PINC</name>
              <bitOffset>6</bitOffset>
              <bitWidth>1</bitWidth>
            </field>
            <field>
              <name>MINC</name>
              <bitOffset>7</bitOffset>
              <bitWidth>1</bitWidth>
            </field>
            <field>
              <name>PSIZE</name>
              <bitOffset>8</bitOffset>
              <bitWidth>2</bitWidth>
            </field>
            <field>
              <name>MSIZE</name>
              <bitOffset>10</bitOffset>
              <bitWidth>2</bitWidth>
            </field>
            <field>
              <name>PL</name>
              <bitOffset>12</bitOffset>
              <bitWidth>2</bitWidth>
            </field>
            <field>
              <name>MEM2MEM</name>
              <bitOffset>14</bitOffset>
              <bitWidth>1</bitWidth>
            </field>
          </fields>
        </register>
        <register>
          <name>CCR6</name>
          <addressOffset>0x6c</addressOffset>
          <size>0x20</size>
          <fields>
            <field>
              <name>EN</name>
              <bitOffset>0</bitOffset>
              <bitWidth>1</bitWidth>
            </field>
            <field>
              <name>TCIE</name>
              <bitOffset>1</bitOffset>
              <bitWidth>1</bitWidth>
            </field>
            <field>
              <name>HTIE</name>
              <bitOffset>2</bitOffset>
              <bitWidth>1</bitWidth>
            </field>
            <field>
              <name>TEIE</name>
              <bitOffset>3</bitOffset>
              <bitWidth>1</bitWidth>
            </field>
            <field>
              <name>DIR</name>
              <bitOffset>4</bitOffset>
              <bitWidth>1</bitWidth>
            </field>
            <field>
              <name>CIRC</name>
              <bitOffset>5</bitOffset>
              <bitWidth>1</bitWidth>
            </field>
            <field>
              <name>PINC</name>
              <bitOffset>6</bitOffset>
              <bitWidth>1</bitWidth>
            </field>
            <field>
              <name>MINC</name>
              <bitOffset>7</bitOffset>
              <bitWidth>1</bitWidth>
            </field>
            <field>
              <name>PSIZE</name>
              <bitOffset>8</bitOffset>
              <bitWidth>2</bitWidth>
            </field>
            <field>
              <name>MSIZE</name>
              <bitOffset>10</bitOffset>
              <bitWidth>2</bitWidth>
            </field>
            <field>
              <name>PL</name>
              <bitOffset>12</bitOffset>
              <bitWidth>2</bitWidth>
            </field>
            <field>
              <name>MEM2MEM</name>
              <bitOffset>14</bitOffset>
              <bitWidth>1</bitWidth>
            </field>
          </fields>
        </register>
        <register>
          <name>CNDTR6</name>
          <addressOffset>0x70</addressOffset>
          <size>0x20</size>
          <fields>
            <field>
              <name>NDT</name>
              <bitOffset>0</bitOffset>
              <bitWidth>16</bitWidth>
            </field>
          </fields>
        </register>
        <register>
          <name>CNDTR6</name>
          <addressOffset>0x70</addressOffset>
          <size>0x20</size>
          <fields>
            <field>
              <name>NDT</name>
              <bitOffset>0</bitOffset>
              <bitWidth>16</bitWidth>
            </field>
          </fields>
        </register>
        <register>
          <name>CPAR6</name>
          <addressOffset>0x74</addressOffset>
          <size>0x20</size>
          <fields>
            <field>
              <name>PA</name>
              <bitOffset>0</bitOffset>
              <bitWidth>32</bitWidth>
            </field>
          </fields>
        </register>
        <register>
          <name>CPAR6</name>
          <addressOffset>0x74</addressOffset>
          <size>0x20</size>
          <fields>
            <field>
              <name>PA</name>
              <bitOffset>0</bitOffset>
              <bitWidth>32</bitWidth>
            </field>
          </fields>
        </register>
        <register>
          <name>CMAR6</name>
          <addressOffset>0x78</addressOffset>
          <size>0x20</size>
          <fields>
            <field>
              <name>MA</name>
              <bitOffset>0</bitOffset>
              <bitWidth>32</bitWidth>
            </field>
          </fields>
        </register>
        <register>
          <name>CMAR6</name>
          <addressOffset>0x78</addressOffset>
          <size>0x20</size>
          <fields>
            <field>
              <name>MA</name>
              <bitOffset>0</bitOffset>
              <bitWidth>32</bitWidth>
            </field>
          </fields>
        </register>
        <register>
          <name>CCR7</name>
          <addressOffset>0x80</addressOffset>
          <size>0x20</size>
          <fields>
            <field>
              <name>EN</name>
              <bitOffset>0</bitOffset>
              <bitWidth>1</bitWidth>
            </field>
            <field>
              <name>TCIE</name>
              <bitOffset>1</bitOffset>
              <bitWidth>1</bitWidth>
            </field>
            <field>
              <name>HTIE</name>
              <bitOffset>2</bitOffset>
              <bitWidth>1</bitWidth>
            </field>
            <field>
              <name>TEIE</name>
              <bitOffset>3</bitOffset>
              <bitWidth>1</bitWidth>
            </field>
            <field>
              <name>DIR</name>
              <bitOffset>4</bitOffset>
              <bitWidth>1</bitWidth>
            </field>
            <field>
              <name>CIRC</name>
              <bitOffset>5</bitOffset>
              <bitWidth>1</bitWidth>
            </field>
            <field>
              <name>PINC</name>
              <bitOffset>6</bitOffset>
              <bitWidth>1</bitWidth>
            </field>
            <field>
              <name>MINC</name>
              <bitOffset>7</bitOffset>
              <bitWidth>1</bitWidth>
            </field>
            <field>
              <name>PSIZE</name>
              <bitOffset>8</bitOffset>
              <bitWidth>2</bitWidth>
            </field>
            <field>
              <name>MSIZE</name>
              <bitOffset>10</bitOffset>
              <bitWidth>2</bitWidth>
            </field>
            <field>
              <name>PL</name>
              <bitOffset>12</bitOffset>
              <bitWidth>2</bitWidth>
            </field>
            <field>
              <name>MEM2MEM</name>
              <bitOffset>14</bitOffset>
              <bitWidth>1</bitWidth>
            </field>
          </fields>
        </register>
        <register>
          <name>CCR7</name>
          <addressOffset>0x80</addressOffset>
          <size>0x20</size>
          <fields>
            <field>
              <name>EN</name>
              <bitOffset>0</bitOffset>
              <bitWidth>1</bitWidth>
            </field>
            <field>
              <name>TCIE</name>
              <bitOffset>1</bitOffset>
              <bitWidth>1</bitWidth>
            </field>
            <field>
              <name>HTIE</name>
              <bitOffset>2</bitOffset>
              <bitWidth>1</bitWidth>
            </field>
            <field>
              <name>TEIE</name>
              <bitOffset>3</bitOffset>
              <bitWidth>1</bitWidth>
            </field>
            <field>
              <name>DIR</name>
              <bitOffset>4</bitOffset>
              <bitWidth>1</bitWidth>
            </field>
            <field>
              <name>CIRC</name>
              <bitOffset>5</bitOffset>
              <bitWidth>1</bitWidth>
            </field>
            <field>
              <name>PINC</name>
              <bitOffset>6</bitOffset>
              <bitWidth>1</bitWidth>
            </field>
            <field>
              <name>MINC</name>
              <bitOffset>7</bitOffset>
              <bitWidth>1</bitWidth>
            </field>
            <field>
              <name>PSIZE</name>
              <bitOffset>8</bitOffset>
              <bitWidth>2</bitWidth>
            </field>
            <field>
              <name>MSIZE</name>
              <bitOffset>10</bitOffset>
              <bitWidth>2</bitWidth>
            </field>
            <field>
              <name>PL</name>
              <bitOffset>12</bitOffset>
              <bitWidth>2</bitWidth>
            </field>
            <field>
              <name>MEM2MEM</name>
              <bitOffset>14</bitOffset>
              <bitWidth>1</bitWidth>
            </field>
          </fields>
        </register>
        <register>
          <name>CNDTR7</name>
          <addressOffset>0x84</addressOffset>
          <size>0x20</size>
          <fields>
            <field>
              <name>NDT</name>
              <bitOffset>0</bitOffset>
              <bitWidth>16</bitWidth>
            </field>
          </fields>
        </register>
        <register>
          <name>CNDTR7</name>
          <addressOffset>0x84</addressOffset>
          <size>0x20</size>
          <fields>
            <field>
              <name>NDT</name>
              <bitOffset>0</bitOffset>
              <bitWidth>16</bitWidth>
            </field>
          </fields>
        </register>
        <register>
          <name>CPAR7</name>
          <addressOffset>0x88</addressOffset>
          <size>0x20</size>
          <fields>
            <field>
              <name>PA</name>
              <bitOffset>0</bitOffset>
              <bitWidth>32</bitWidth>
            </field>
          </fields>
        </register>
        <register>
          <name>CPAR7</name>
          <addressOffset>0x88</addressOffset>
          <size>0x20</size>
          <fields>
            <field>
              <name>PA</name>
              <bitOffset>0</bitOffset>
              <bitWidth>32</bitWidth>
            </field>
          </fields>
        </register>
        <register>
          <name>CMAR7</name>
          <addressOffset>0x8c</addressOffset>
          <size>0x20</size>
          <fields>
            <field>
              <name>MA</name>
              <bitOffset>0</bitOffset>
              <bitWidth>32</bitWidth>
            </field>
          </fields>
        </register>
        <register>
          <name>CMAR7</name>
          <addressOffset>0x8c</addressOffset>
          <size>0x20</size>
          <fields>
            <field>
              <name>MA</name>
              <bitOffset>0</bitOffset>
              <bitWidth>32</bitWidth>
            </field>
          </fields>
        </register>
      </registers>
    </peripheral>
    <peripheral>
      <name>DMA1_CSELR</name>
      <baseAddress>0x400200a8</baseAddress>
      <registers>
        <register>
          <name>CSELR</name>
          <addressOffset>0x0</addressOffset>
          <size>0x20</size>
          <fields>
            <field>
              <name>C1S</name>
              <bitOffset>0</bitOffset>
              <bitWidth>4</bitWidth>
            </field>
            <field>
              <name>C2S</name>
              <bitOffset>4</bitOffset>
              <bitWidth>4</bitWidth>
            </field>
            <field>
              <name>C3S</name>
              <bitOffset>8</bitOffset>
              <bitWidth>4</bitWidth>
            </field>
            <field>
              <name>C4S</name>
              <bitOffset>12</bitOffset>
              <bitWidth>4</bitWidth>
            </field>
            <field>
              <name>C5S</name>
              <bitOffset>16</bitOffset>
              <bitWidth>4</bitWidth>
            </field>
            <field>
              <name>C6S</name>
              <bitOffset>20</bitOffset>
              <bitWidth>4</bitWidth>
            </field>
            <field>
              <name>C7S</name>
              <bitOffset>24</bitOffset>
              <bitWidth>4</bitWidth>
            </field>
          </fields>
        </register>
      </registers>
    </peripheral>
    <peripheral>
      <name>DMA2</name>
      <baseAddress>0x40020400</baseAddress>
      <registers>
        <register>
          <name>ISR</name>
          <addressOffset>0x0</addressOffset>
          <size>0x20</size>
          <fields>
            <field>
              <name>GIF1</name>
              <bitOffset>0</bitOffset>
              <bitWidth>1</bitWidth>
            </field>
            <field>
              <name>TCIF1</name>
              <bitOffset>1</bitOffset>
              <bitWidth>1</bitWidth>
            </field>
            <field>
              <name>HTIF1</name>
              <bitOffset>2</bitOffset>
              <bitWidth>1</bitWidth>
            </field>
            <field>
              <name>TEIF1</name>
              <bitOffset>3</bitOffset>
              <bitWidth>1</bitWidth>
            </field>
            <field>
              <name>GIF2</name>
              <bitOffset>4</bitOffset>
              <bitWidth>1</bitWidth>
            </field>
            <field>
              <name>TCIF2</name>
              <bitOffset>5</bitOffset>
              <bitWidth>1</bitWidth>
            </field>
            <field>
              <name>HTIF2</name>
              <bitOffset>6</bitOffset>
              <bitWidth>1</bitWidth>
            </field>
            <field>
              <name>TEIF2</name>
              <bitOffset>7</bitOffset>
              <bitWidth>1</bitWidth>
            </field>
            <field>
              <name>GIF3</name>
              <bitOffset>8</bitOffset>
              <bitWidth>1</bitWidth>
            </field>
            <field>
              <name>TCIF3</name>
              <bitOffset>9</bitOffset>
              <bitWidth>1</bitWidth>
            </field>
            <field>
              <name>HTIF3</name>
              <bitOffset>10</bitOffset>
              <bitWidth>1</bitWidth>
            </field>
            <field>
              <name>TEIF3</name>
              <bitOffset>11</bitOffset>
              <bitWidth>1</bitWidth>
            </field>
            <field>
              <name>GIF4</name>
              <bitOffset>12</bitOffset>
              <bitWidth>1</bitWidth>
            </field>
            <field>
              <name>TCIF4</name>
              <bitOffset>13</bitOffset>
              <bitWidth>1</bitWidth>
            </field>
            <field>
              <name>HTIF4</name>
              <bitOffset>14</bitOffset>
              <bitWidth>1</bitWidth>
            </field>
            <field>
              <name>TEIF4</name>
              <bitOffset>15</bitOffset>
              <bitWidth>1</bitWidth>
            </field>
            <field>
              <name>GIF5</name>
              <bitOffset>16</bitOffset>
              <bitWidth>1</bitWidth>
            </field>
            <field>
              <name>TCIF5</name>
              <bitOffset>17</bitOffset>
              <bitWidth>1</bitWidth>
            </field>
            <field>
              <name>HTIF5</name>
              <bitOffset>18</bitOffset>
              <bitWidth>1</bitWidth>
            </field>
            <field>
              <name>TEIF5</name>
              <bitOffset>19</bitOffset>
              <bitWidth>1</bitWidth>
            </field>
            <field>
              <name>GIF6</name>
              <bitOffset>20</bitOffset>
              <bitWidth>1</bitWidth>
            </field>
            <field>
              <name>TCIF6</name>
              <bitOffset>21</bitOffset>
              <bitWidth>1</bitWidth>
            </field>
            <field>
              <name>HTIF6</name>
              <bitOffset>22</bitOffset>
              <bitWidth>1</bitWidth>
            </field>
            <field>
              <name>TEIF6</name>
              <bitOffset>23</bitOffset>
              <bitWidth>1</bitWidth>
            </field>
            <field>
              <name>GIF7</name>
              <bitOffset>24</bitOffset>
              <bitWidth>1</bitWidth>
            </field>
            <field>
              <name>TCIF7</name>
              <bitOffset>25</bitOffset>
              <bitWidth>1</bitWidth>
            </field>
            <field>
              <name>HTIF7</name>
              <bitOffset>26</bitOffset>
              <bitWidth>1</bitWidth>
            </field>
            <field>
              <name>TEIF7</name>
              <bitOffset>27</bitOffset>
              <bitWidth>1</bitWidth>
            </field>
          </fields>
        </register>
        <register>
          <name>IFCR</name>
          <addressOffset>0x4</addressOffset>
          <size>0x20</size>
          <fields>
            <field>
              <name>CGIF1</name>
              <bitOffset>0</bitOffset>
              <bitWidth>1</bitWidth>
            </field>
            <field>
              <name>CTCIF1</name>
              <bitOffset>1</bitOffset>
              <bitWidth>1</bitWidth>
            </field>
            <field>
              <name>CHTIF1</name>
              <bitOffset>2</bitOffset>
              <bitWidth>1</bitWidth>
            </field>
            <field>
              <name>CTEIF1</name>
              <bitOffset>3</bitOffset>
              <bitWidth>1</bitWidth>
            </field>
            <field>
              <name>CGIF2</name>
              <bitOffset>4</bitOffset>
              <bitWidth>1</bitWidth>
            </field>
            <field>
              <name>CTCIF2</name>
              <bitOffset>5</bitOffset>
              <bitWidth>1</bitWidth>
            </field>
            <field>
              <name>CHTIF2</name>
              <bitOffset>6</bitOffset>
              <bitWidth>1</bitWidth>
            </field>
            <field>
              <name>CTEIF2</name>
              <bitOffset>7</bitOffset>
              <bitWidth>1</bitWidth>
            </field>
            <field>
              <name>CGIF3</name>
              <bitOffset>8</bitOffset>
              <bitWidth>1</bitWidth>
            </field>
            <field>
              <name>CTCIF3</name>
              <bitOffset>9</bitOffset>
              <bitWidth>1</bitWidth>
            </field>
            <field>
              <name>CHTIF3</name>
              <bitOffset>10</bitOffset>
              <bitWidth>1</bitWidth>
            </field>
            <field>
              <name>CTEIF3</name>
              <bitOffset>11</bitOffset>
              <bitWidth>1</bitWidth>
            </field>
            <field>
              <name>CGIF4</name>
              <bitOffset>12</bitOffset>
              <bitWidth>1</bitWidth>
            </field>
            <field>
              <name>CTCIF4</name>
              <bitOffset>13</bitOffset>
              <bitWidth>1</bitWidth>
            </field>
            <field>
              <name>CHTIF4</name>
              <bitOffset>14</bitOffset>
              <bitWidth>1</bitWidth>
            </field>
            <field>
              <name>CTEIF4</name>
              <bitOffset>15</bitOffset>
              <bitWidth>1</bitWidth>
            </field>
            <field>
              <name>CGIF5</name>
              <bitOffset>16</bitOffset>
              <bitWidth>1</bitWidth>
            </field>
            <field>
              <name>CTCIF5</name>
              <bitOffset>17</bitOffset>
              <bitWidth>1</bitWidth>
            </field>
            <field>
              <name>CHTIF5</name>
              <bitOffset>18</bitOffset>
              <bitWidth>1</bitWidth>
            </field>
            <field>
              <name>CTEIF5</name>
              <bitOffset>19</bitOffset>
              <bitWidth>1</bitWidth>
            </field>
            <field>
              <name>CGIF6</name>
              <bitOffset>20</bitOffset>
              <bitWidth>1</bitWidth>
            </field>
            <field>
              <name>CTCIF6</name>
              <bitOffset>21</bitOffset>
              <bitWidth>1</bitWidth>
            </field>
            <field>
              <name>CHTIF6</name>
              <bitOffset>22</bitOffset>
              <bitWidth>1</bitWidth>
            </field>
            <field>
              <name>CTEIF6</name>
              <bitOffset>23</bitOffset>
              <bitWidth>1</bitWidth>
            </field>
            <field>
              <name>CGIF7</name>
              <bitOffset>24</bitOffset>
              <bitWidth>1</bitWidth>
            </field>
            <field>
              <name>CTCIF7</name>
              <bitOffset>25</bitOffset>
              <bitWidth>1</bitWidth>
            </field>
            <field>
              <name>CHTIF7</name>
              <bitOffset>26</bitOffset>
              <bitWidth>1</bitWidth>
            </field>
            <field>
              <name>CTEIF7</name>
              <bitOffset>27</bitOffset>
              <bitWidth>1</bitWidth>
            </field>
          </fields>
        </register>
        <register>
          <name>CCR1</name>
          <addressOffset>0x8</addressOffset>
          <size>0x20</size>
          <fields>
            <field>
              <name>EN</name>
              <bitOffset>0</bitOffset>
              <bitWidth>1</bitWidth>
            </field>
            <field>
              <name>TCIE</name>
              <bitOffset>1</bitOffset>
              <bitWidth>1</bitWidth>
            </field>
            <field>
              <name>HTIE</name>
              <bitOffset>2</bitOffset>
              <bitWidth>1</bitWidth>
            </field>
            <field>
              <name>TEIE</name>
              <bitOffset>3</bitOffset>
              <bitWidth>1</bitWidth>
            </field>
            <field>
              <name>DIR</name>
              <bitOffset>4</bitOffset>
              <bitWidth>1</bitWidth>
            </field>
            <field>
              <name>CIRC</name>
              <bitOffset>5</bitOffset>
              <bitWidth>1</bitWidth>
            </field>
            <field>
              <name>PINC</name>
              <bitOffset>6</bitOffset>
              <bitWidth>1</bitWidth>
            </field>
            <field>
              <name>MINC</name>
              <bitOffset>7</bitOffset>
              <bitWidth>1</bitWidth>
            </field>
            <field>
              <name>PSIZE</name>
              <bitOffset>8</bitOffset>
              <bitWidth>2</bitWidth>
            </field>
            <field>
              <name>MSIZE</name>
              <bitOffset>10</bitOffset>
              <bitWidth>2</bitWidth>
            </field>
            <field>
              <name>PL</name>
              <bitOffset>12</bitOffset>
              <bitWidth>2</bitWidth>
            </field>
            <field>
              <name>MEM2MEM</name>
              <bitOffset>14</bitOffset>
              <bitWidth>1</bitWidth>
            </field>
          </fields>
        </register>
        <register>
          <name>CCR1</name>
          <addressOffset>0x8</addressOffset>
          <size>0x20</size>
          <fields>
            <field>
              <name>EN</name>
              <bitOffset>0</bitOffset>
              <bitWidth>1</bitWidth>
            </field>
            <field>
              <name>TCIE</name>
              <bitOffset>1</bitOffset>
              <bitWidth>1</bitWidth>
            </field>
            <field>
              <name>HTIE</name>
              <bitOffset>2</bitOffset>
              <bitWidth>1</bitWidth>
            </field>
            <field>
              <name>TEIE</name>
              <bitOffset>3</bitOffset>
              <bitWidth>1</bitWidth>
            </field>
            <field>
              <name>DIR</name>
              <bitOffset>4</bitOffset>
              <bitWidth>1</bitWidth>
            </field>
            <field>
              <name>CIRC</name>
              <bitOffset>5</bitOffset>
              <bitWidth>1</bitWidth>
            </field>
            <field>
              <name>PINC</name>
              <bitOffset>6</bitOffset>
              <bitWidth>1</bitWidth>
            </field>
            <field>
              <name>MINC</name>
              <bitOffset>7</bitOffset>
              <bitWidth>1</bitWidth>
            </field>
            <field>
              <name>PSIZE</name>
              <bitOffset>8</bitOffset>
              <bitWidth>2</bitWidth>
            </field>
            <field>
              <name>MSIZE</name>
              <bitOffset>10</bitOffset>
              <bitWidth>2</bitWidth>
            </field>
            <field>
              <name>PL</name>
              <bitOffset>12</bitOffset>
              <bitWidth>2</bitWidth>
            </field>
            <field>
              <name>MEM2MEM</name>
              <bitOffset>14</bitOffset>
              <bitWidth>1</bitWidth>
            </field>
          </fields>
        </register>
        <register>
          <name>CNDTR1</name>
          <addressOffset>0xc</addressOffset>
          <size>0x20</size>
          <fields>
            <field>
              <name>NDT</name>
              <bitOffset>0</bitOffset>
              <bitWidth>16</bitWidth>
            </field>
          </fields>
        </register>
        <register>
          <name>CNDTR1</name>
          <addressOffset>0xc</addressOffset>
          <size>0x20</size>
          <fields>
            <field>
              <name>NDT</name>
              <bitOffset>0</bitOffset>
              <bitWidth>16</bitWidth>
            </field>
          </fields>
        </register>
        <register>
          <name>CPAR1</name>
          <addressOffset>0x10</addressOffset>
          <size>0x20</size>
          <fields>
            <field>
              <name>PA</name>
              <bitOffset>0</bitOffset>
              <bitWidth>32</bitWidth>
            </field>
          </fields>
        </register>
        <register>
          <name>CPAR1</name>
          <addressOffset>0x10</addressOffset>
          <size>0x20</size>
          <fields>
            <field>
              <name>PA</name>
              <bitOffset>0</bitOffset>
              <bitWidth>32</bitWidth>
            </field>
          </fields>
        </register>
        <register>
          <name>CMAR1</name>
          <addressOffset>0x14</addressOffset>
          <size>0x20</size>
          <fields>
            <field>
              <name>MA</name>
              <bitOffset>0</bitOffset>
              <bitWidth>32</bitWidth>
            </field>
          </fields>
        </register>
        <register>
          <name>CMAR1</name>
          <addressOffset>0x14</addressOffset>
          <size>0x20</size>
          <fields>
            <field>
              <name>MA</name>
              <bitOffset>0</bitOffset>
              <bitWidth>32</bitWidth>
            </field>
          </fields>
        </register>
        <register>
          <name>CCR2</name>
          <addressOffset>0x1c</addressOffset>
          <size>0x20</size>
          <fields>
            <field>
              <name>EN</name>
              <bitOffset>0</bitOffset>
              <bitWidth>1</bitWidth>
            </field>
            <field>
              <name>TCIE</name>
              <bitOffset>1</bitOffset>
              <bitWidth>1</bitWidth>
            </field>
            <field>
              <name>HTIE</name>
              <bitOffset>2</bitOffset>
              <bitWidth>1</bitWidth>
            </field>
            <field>
              <name>TEIE</name>
              <bitOffset>3</bitOffset>
              <bitWidth>1</bitWidth>
            </field>
            <field>
              <name>DIR</name>
              <bitOffset>4</bitOffset>
              <bitWidth>1</bitWidth>
            </field>
            <field>
              <name>CIRC</name>
              <bitOffset>5</bitOffset>
              <bitWidth>1</bitWidth>
            </field>
            <field>
              <name>PINC</name>
              <bitOffset>6</bitOffset>
              <bitWidth>1</bitWidth>
            </field>
            <field>
              <name>MINC</name>
              <bitOffset>7</bitOffset>
              <bitWidth>1</bitWidth>
            </field>
            <field>
              <name>PSIZE</name>
              <bitOffset>8</bitOffset>
              <bitWidth>2</bitWidth>
            </field>
            <field>
              <name>MSIZE</name>
              <bitOffset>10</bitOffset>
              <bitWidth>2</bitWidth>
            </field>
            <field>
              <name>PL</name>
              <bitOffset>12</bitOffset>
              <bitWidth>2</bitWidth>
            </field>
            <field>
              <name>MEM2MEM</name>
              <bitOffset>14</bitOffset>
              <bitWidth>1</bitWidth>
            </field>
          </fields>
        </register>
        <register>
          <name>CCR2</name>
          <addressOffset>0x1c</addressOffset>
          <size>0x20</size>
          <fields>
            <field>
              <name>EN</name>
              <bitOffset>0</bitOffset>
              <bitWidth>1</bitWidth>
            </field>
            <field>
              <name>TCIE</name>
              <bitOffset>1</bitOffset>
              <bitWidth>1</bitWidth>
            </field>
            <field>
              <name>HTIE</name>
              <bitOffset>2</bitOffset>
              <bitWidth>1</bitWidth>
            </field>
            <field>
              <name>TEIE</name>
              <bitOffset>3</bitOffset>
              <bitWidth>1</bitWidth>
            </field>
            <field>
              <name>DIR</name>
              <bitOffset>4</bitOffset>
              <bitWidth>1</bitWidth>
            </field>
            <field>
              <name>CIRC</name>
              <bitOffset>5</bitOffset>
              <bitWidth>1</bitWidth>
            </field>
            <field>
              <name>PINC</name>
              <bitOffset>6</bitOffset>
              <bitWidth>1</bitWidth>
            </field>
            <field>
              <name>MINC</name>
              <bitOffset>7</bitOffset>
              <bitWidth>1</bitWidth>
            </field>
            <field>
              <name>PSIZE</name>
              <bitOffset>8</bitOffset>
              <bitWidth>2</bitWidth>
            </field>
            <field>
              <name>MSIZE</name>
              <bitOffset>10</bitOffset>
              <bitWidth>2</bitWidth>
            </field>
            <field>
              <name>PL</name>
              <bitOffset>12</bitOffset>
              <bitWidth>2</bitWidth>
            </field>
            <field>
              <name>MEM2MEM</name>
              <bitOffset>14</bitOffset>
              <bitWidth>1</bitWidth>
            </field>
          </fields>
        </register>
        <register>
          <name>CNDTR2</name>
          <addressOffset>0x20</addressOffset>
          <size>0x20</size>
          <fields>
            <field>
              <name>NDT</name>
              <bitOffset>0</bitOffset>
              <bitWidth>16</bitWidth>
            </field>
          </fields>
        </register>
        <register>
          <name>CNDTR2</name>
          <addressOffset>0x20</addressOffset>
          <size>0x20</size>
          <fields>
            <field>
              <name>NDT</name>
              <bitOffset>0</bitOffset>
              <bitWidth>16</bitWidth>
            </field>
          </fields>
        </register>
        <register>
          <name>CPAR2</name>
          <addressOffset>0x24</addressOffset>
          <size>0x20</size>
          <fields>
            <field>
              <name>PA</name>
              <bitOffset>0</bitOffset>
              <bitWidth>32</bitWidth>
            </field>
          </fields>
        </register>
        <register>
          <name>CPAR2</name>
          <addressOffset>0x24</addressOffset>
          <size>0x20</size>
          <fields>
            <field>
              <name>PA</name>
              <bitOffset>0</bitOffset>
              <bitWidth>32</bitWidth>
            </field>
          </fields>
        </register>
        <register>
          <name>CMAR2</name>
          <addressOffset>0x28</addressOffset>
          <size>0x20</size>
          <fields>
            <field>
              <name>MA</name>
              <bitOffset>0</bitOffset>
              <bitWidth>32</bitWidth>
            </field>
          </fields>
        </register>
        <register>
          <name>CMAR2</name>
          <addressOffset>0x28</addressOffset>
          <size>0x20</size>
          <fields>
            <field>
              <name>MA</name>
              <bitOffset>0</bitOffset>
              <bitWidth>32</bitWidth>
            </field>
          </fields>
        </register>
        <register>
          <name>CCR3</name>
          <addressOffset>0x30</addressOffset>
          <size>0x20</size>
          <fields>
            <field>
              <name>EN</name>
              <bitOffset>0</bitOffset>
              <bitWidth>1</bitWidth>
            </field>
            <field>
              <name>TCIE</name>
              <bitOffset>1</bitOffset>
              <bitWidth>1</bitWidth>
            </field>
            <field>
              <name>HTIE</name>
              <bitOffset>2</bitOffset>
              <bitWidth>1</bitWidth>
            </field>
            <field>
              <name>TEIE</name>
              <bitOffset>3</bitOffset>
              <bitWidth>1</bitWidth>
            </field>
            <field>
              <name>DIR</name>
              <bitOffset>4</bitOffset>
              <bitWidth>1</bitWidth>
            </field>
            <field>
              <name>CIRC</name>
              <bitOffset>5</bitOffset>
              <bitWidth>1</bitWidth>
            </field>
            <field>
              <name>PINC</name>
              <bitOffset>6</bitOffset>
              <bitWidth>1</bitWidth>
            </field>
            <field>
              <name>MINC</name>
              <bitOffset>7</bitOffset>
              <bitWidth>1</bitWidth>
            </field>
            <field>
              <name>PSIZE</name>
              <bitOffset>8</bitOffset>
              <bitWidth>2</bitWidth>
            </field>
            <field>
              <name>MSIZE</name>
              <bitOffset>10</bitOffset>
              <bitWidth>2</bitWidth>
            </field>
            <field>
              <name>PL</name>
              <bitOffset>12</bitOffset>
              <bitWidth>2</bitWidth>
            </field>
            <field>
              <name>MEM2MEM</name>
              <bitOffset>14</bitOffset>
              <bitWidth>1</bitWidth>
            </field>
          </fields>
        </register>
        <register>
          <name>CCR3</name>
          <addressOffset>0x30</addressOffset>
          <size>0x20</size>
          <fields>
            <field>
              <name>EN</name>
              <bitOffset>0</bitOffset>
              <bitWidth>1</bitWidth>
            </field>
            <field>
              <name>TCIE</name>
              <bitOffset>1</bitOffset>
              <bitWidth>1</bitWidth>
            </field>
            <field>
              <name>HTIE</name>
              <bitOffset>2</bitOffset>
              <bitWidth>1</bitWidth>
            </field>
            <field>
              <name>TEIE</name>
              <bitOffset>3</bitOffset>
              <bitWidth>1</bitWidth>
            </field>
            <field>
              <name>DIR</name>
              <bitOffset>4</bitOffset>
              <bitWidth>1</bitWidth>
            </field>
            <field>
              <name>CIRC</name>
              <bitOffset>5</bitOffset>
              <bitWidth>1</bitWidth>
            </field>
            <field>
              <name>PINC</name>
              <bitOffset>6</bitOffset>
              <bitWidth>1</bitWidth>
            </field>
            <field>
              <name>MINC</name>
              <bitOffset>7</bitOffset>
              <bitWidth>1</bitWidth>
            </field>
            <field>
              <name>PSIZE</name>
              <bitOffset>8</bitOffset>
              <bitWidth>2</bitWidth>
            </field>
            <field>
              <name>MSIZE</name>
              <bitOffset>10</bitOffset>
              <bitWidth>2</bitWidth>
            </field>
            <field>
              <name>PL</name>
              <bitOffset>12</bitOffset>
              <bitWidth>2</bitWidth>
            </field>
            <field>
              <name>MEM2MEM</name>
              <bitOffset>14</bitOffset>
              <bitWidth>1</bitWidth>
            </field>
          </fields>
        </register>
        <register>
          <name>CNDTR3</name>
          <addressOffset>0x34</addressOffset>
          <size>0x20</size>
          <fields>
            <field>
              <name>NDT</name>
              <bitOffset>0</bitOffset>
              <bitWidth>16</bitWidth>
            </field>
          </fields>
        </register>
        <register>
          <name>CNDTR3</name>
          <addressOffset>0x34</addressOffset>
          <size>0x20</size>
          <fields>
            <field>
              <name>NDT</name>
              <bitOffset>0</bitOffset>
              <bitWidth>16</bitWidth>
            </field>
          </fields>
        </register>
        <register>
          <name>CPAR3</name>
          <addressOffset>0x38</addressOffset>
          <size>0x20</size>
          <fields>
            <field>
              <name>PA</name>
              <bitOffset>0</bitOffset>
              <bitWidth>32</bitWidth>
            </field>
          </fields>
        </register>
        <register>
          <name>CPAR3</name>
          <addressOffset>0x38</addressOffset>
          <size>0x20</size>
          <fields>
            <field>
              <name>PA</name>
              <bitOffset>0</bitOffset>
              <bitWidth>32</bitWidth>
            </field>
          </fields>
        </register>
        <register>
          <name>CMAR3</name>
          <addressOffset>0x3c</addressOffset>
          <size>0x20</size>
          <fields>
            <field>
              <name>MA</name>
              <bitOffset>0</bitOffset>
              <bitWidth>32</bitWidth>
            </field>
          </fields>
        </register>
        <register>
          <name>CMAR3</name>
          <addressOffset>0x3c</addressOffset>
          <size>0x20</size>
          <fields>
            <field>
              <name>MA</name>
              <bitOffset>0</bitOffset>
              <bitWidth>32</bitWidth>
            </field>
          </fields>
        </register>
        <register>
          <name>CCR4</name>
          <addressOffset>0x44</addressOffset>
          <size>0x20</size>
          <fields>
            <field>
              <name>EN</name>
              <bitOffset>0</bitOffset>
              <bitWidth>1</bitWidth>
            </field>
            <field>
              <name>TCIE</name>
              <bitOffset>1</bitOffset>
              <bitWidth>1</bitWidth>
            </field>
            <field>
              <name>HTIE</name>
              <bitOffset>2</bitOffset>
              <bitWidth>1</bitWidth>
            </field>
            <field>
              <name>TEIE</name>
              <bitOffset>3</bitOffset>
              <bitWidth>1</bitWidth>
            </field>
            <field>
              <name>DIR</name>
              <bitOffset>4</bitOffset>
              <bitWidth>1</bitWidth>
            </field>
            <field>
              <name>CIRC</name>
              <bitOffset>5</bitOffset>
              <bitWidth>1</bitWidth>
            </field>
            <field>
              <name>PINC</name>
              <bitOffset>6</bitOffset>
              <bitWidth>1</bitWidth>
            </field>
            <field>
              <name>MINC</name>
              <bitOffset>7</bitOffset>
              <bitWidth>1</bitWidth>
            </field>
            <field>
              <name>PSIZE</name>
              <bitOffset>8</bitOffset>
              <bitWidth>2</bitWidth>
            </field>
            <field>
              <name>MSIZE</name>
              <bitOffset>10</bitOffset>
              <bitWidth>2</bitWidth>
            </field>
            <field>
              <name>PL</name>
              <bitOffset>12</bitOffset>
              <bitWidth>2</bitWidth>
            </field>
            <field>
              <name>MEM2MEM</name>
              <bitOffset>14</bitOffset>
              <bitWidth>1</bitWidth>
            </field>
          </fields>
        </register>
        <register>
          <name>CCR4</name>
          <addressOffset>0x44</addressOffset>
          <size>0x20</size>
          <fields>
            <field>
              <name>EN</name>
              <bitOffset>0</bitOffset>
              <bitWidth>1</bitWidth>
            </field>
            <field>
              <name>TCIE</name>
              <bitOffset>1</bitOffset>
              <bitWidth>1</bitWidth>
            </field>
            <field>
              <name>HTIE</name>
              <bitOffset>2</bitOffset>
              <bitWidth>1</bitWidth>
            </field>
            <field>
              <name>TEIE</name>
              <bitOffset>3</bitOffset>
              <bitWidth>1</bitWidth>
            </field>
            <field>
              <name>DIR</name>
              <bitOffset>4</bitOffset>
              <bitWidth>1</bitWidth>
            </field>
            <field>
              <name>CIRC</name>
              <bitOffset>5</bitOffset>
              <bitWidth>1</bitWidth>
            </field>
            <field>
              <name>PINC</name>
              <bitOffset>6</bitOffset>
              <bitWidth>1</bitWidth>
            </field>
            <field>
              <name>MINC</name>
              <bitOffset>7</bitOffset>
              <bitWidth>1</bitWidth>
            </field>
            <field>
              <name>PSIZE</name>
              <bitOffset>8</bitOffset>
              <bitWidth>2</bitWidth>
            </field>
            <field>
              <name>MSIZE</name>
              <bitOffset>10</bitOffset>
              <bitWidth>2</bitWidth>
            </field>
            <field>
              <name>PL</name>
              <bitOffset>12</bitOffset>
              <bitWidth>2</bitWidth>
            </field>
            <field>
              <name>MEM2MEM</name>
              <bitOffset>14</bitOffset>
              <bitWidth>1</bitWidth>
            </field>
          </fields>
        </register>
        <register>
          <name>CNDTR4</name>
          <addressOffset>0x48</addressOffset>
          <size>0x20</size>
          <fields>
            <field>
              <name>NDT</name>
              <bitOffset>0</bitOffset>
              <bitWidth>16</bitWidth>
            </field>
          </fields>
        </register>
        <register>
          <name>CNDTR4</name>
          <addressOffset>0x48</addressOffset>
          <size>0x20</size>
          <fields>
            <field>
              <name>NDT</name>
              <bitOffset>0</bitOffset>
              <bitWidth>16</bitWidth>
            </field>
          </fields>
        </register>
        <register>
          <name>CPAR4</name>
          <addressOffset>0x4c</addressOffset>
          <size>0x20</size>
          <fields>
            <field>
              <name>PA</name>
              <bitOffset>0</bitOffset>
              <bitWidth>32</bitWidth>
            </field>
          </fields>
        </register>
        <register>
          <name>CPAR4</name>
          <addressOffset>0x4c</addressOffset>
          <size>0x20</size>
          <fields>
            <field>
              <name>PA</name>
              <bitOffset>0</bitOffset>
              <bitWidth>32</bitWidth>
            </field>
          </fields>
        </register>
        <register>
          <name>CMAR4</name>
          <addressOffset>0x50</addressOffset>
          <size>0x20</size>
          <fields>
            <field>
              <name>MA</name>
              <bitOffset>0</bitOffset>
              <bitWidth>32</bitWidth>
            </field>
          </fields>
        </register>
        <register>
          <name>CMAR4</name>
          <addressOffset>0x50</addressOffset>
          <size>0x20</size>
          <fields>
            <field>
              <name>MA</name>
              <bitOffset>0</bitOffset>
              <bitWidth>32</bitWidth>
            </field>
          </fields>
        </register>
        <register>
          <name>CCR5</name>
          <addressOffset>0x58</addressOffset>
          <size>0x20</size>
          <fields>
            <field>
              <name>EN</name>
              <bitOffset>0</bitOffset>
              <bitWidth>1</bitWidth>
            </field>
            <field>
              <name>TCIE</name>
              <bitOffset>1</bitOffset>
              <bitWidth>1</bitWidth>
            </field>
            <field>
              <name>HTIE</name>
              <bitOffset>2</bitOffset>
              <bitWidth>1</bitWidth>
            </field>
            <field>
              <name>TEIE</name>
              <bitOffset>3</bitOffset>
              <bitWidth>1</bitWidth>
            </field>
            <field>
              <name>DIR</name>
              <bitOffset>4</bitOffset>
              <bitWidth>1</bitWidth>
            </field>
            <field>
              <name>CIRC</name>
              <bitOffset>5</bitOffset>
              <bitWidth>1</bitWidth>
            </field>
            <field>
              <name>PINC</name>
              <bitOffset>6</bitOffset>
              <bitWidth>1</bitWidth>
            </field>
            <field>
              <name>MINC</name>
              <bitOffset>7</bitOffset>
              <bitWidth>1</bitWidth>
            </field>
            <field>
              <name>PSIZE</name>
              <bitOffset>8</bitOffset>
              <bitWidth>2</bitWidth>
            </field>
            <field>
              <name>MSIZE</name>
              <bitOffset>10</bitOffset>
              <bitWidth>2</bitWidth>
            </field>
            <field>
              <name>PL</name>
              <bitOffset>12</bitOffset>
              <bitWidth>2</bitWidth>
            </field>
            <field>
              <name>MEM2MEM</name>
              <bitOffset>14</bitOffset>
              <bitWidth>1</bitWidth>
            </field>
          </fields>
        </register>
        <register>
          <name>CCR5</name>
          <addressOffset>0x58</addressOffset>
          <size>0x20</size>
          <fields>
            <field>
              <name>EN</name>
              <bitOffset>0</bitOffset>
              <bitWidth>1</bitWidth>
            </field>
            <field>
              <name>TCIE</name>
              <bitOffset>1</bitOffset>
              <bitWidth>1</bitWidth>
            </field>
            <field>
              <name>HTIE</name>
              <bitOffset>2</bitOffset>
              <bitWidth>1</bitWidth>
            </field>
            <field>
              <name>TEIE</name>
              <bitOffset>3</bitOffset>
              <bitWidth>1</bitWidth>
            </field>
            <field>
              <name>DIR</name>
              <bitOffset>4</bitOffset>
              <bitWidth>1</bitWidth>
            </field>
            <field>
              <name>CIRC</name>
              <bitOffset>5</bitOffset>
              <bitWidth>1</bitWidth>
            </field>
            <field>
              <name>PINC</name>
              <bitOffset>6</bitOffset>
              <bitWidth>1</bitWidth>
            </field>
            <field>
              <name>MINC</name>
              <bitOffset>7</bitOffset>
              <bitWidth>1</bitWidth>
            </field>
            <field>
              <name>PSIZE</name>
              <bitOffset>8</bitOffset>
              <bitWidth>2</bitWidth>
            </field>
            <field>
              <name>MSIZE</name>
              <bitOffset>10</bitOffset>
              <bitWidth>2</bitWidth>
            </field>
            <field>
              <name>PL</name>
              <bitOffset>12</bitOffset>
              <bitWidth>2</bitWidth>
            </field>
            <field>
              <name>MEM2MEM</name>
              <bitOffset>14</bitOffset>
              <bitWidth>1</bitWidth>
            </field>
          </fields>
        </register>
        <register>
          <name>CNDTR5</name>
          <addressOffset>0x5c</addressOffset>
          <size>0x20</size>
          <fields>
            <field>
              <name>NDT</name>
              <bitOffset>0</bitOffset>
              <bitWidth>16</bitWidth>
            </field>
          </fields>
        </register>
        <register>
          <name>CNDTR5</name>
          <addressOffset>0x5c</addressOffset>
          <size>0x20</size>
          <fields>
            <field>
              <name>NDT</name>
              <bitOffset>0</bitOffset>
              <bitWidth>16</bitWidth>
            </field>
          </fields>
        </register>
        <register>
          <name>CPAR5</name>
          <addressOffset>0x60</addressOffset>
          <size>0x20</size>
          <fields>
            <field>
              <name>PA</name>
              <bitOffset>0</bitOffset>
              <bitWidth>32</bitWidth>
            </field>
          </fields>
        </register>
        <register>
          <name>CPAR5</name>
          <addressOffset>0x60</addressOffset>
          <size>0x20</size>
          <fields>
            <field>
              <name>PA</name>
              <bitOffset>0</bitOffset>
              <bitWidth>32</bitWidth>
            </field>
          </fields>
        </register>
        <register>
          <name>CMAR5</name>
          <addressOffset>0x64</addressOffset>
          <size>0x20</size>
          <fields>
            <field>
              <name>MA</name>
              <bitOffset>0</bitOffset>
              <bitWidth>32</bitWidth>
            </field>
          </fields>
        </register>
        <register>
          <name>CMAR5</name>
          <addressOffset>0x64</addressOffset>
          <size>0x20</size>
          <fields>
            <field>
              <name>MA</name>
              <bitOffset>0</bitOffset>
              <bitWidth>32</bitWidth>
            </field>
          </fields>
        </register>
        <register>
          <name>CCR6</name>
          <addressOffset>0x6c</addressOffset>
          <size>0x20</size>
          <fields>
            <field>
              <name>EN</name>
              <bitOffset>0</bitOffset>
              <bitWidth>1</bitWidth>
            </field>
            <field>
              <name>TCIE</name>
              <bitOffset>1</bitOffset>
              <bitWidth>1</bitWidth>
            </field>
            <field>
              <name>HTIE</name>
              <bitOffset>2</bitOffset>
              <bitWidth>1</bitWidth>
            </field>
            <field>
              <name>TEIE</name>
              <bitOffset>3</bitOffset>
              <bitWidth>1</bitWidth>
            </field>
            <field>
              <name>DIR</name>
              <bitOffset>4</bitOffset>
              <bitWidth>1</bitWidth>
            </field>
            <field>
              <name>CIRC</name>
              <bitOffset>5</bitOffset>
              <bitWidth>1</bitWidth>
            </field>
            <field>
              <name>PINC</name>
              <bitOffset>6</bitOffset>
              <bitWidth>1</bitWidth>
            </field>
            <field>
              <name>MINC</name>
              <bitOffset>7</bitOffset>
              <bitWidth>1</bitWidth>
            </field>
            <field>
              <name>PSIZE</name>
              <bitOffset>8</bitOffset>
              <bitWidth>2</bitWidth>
            </field>
            <field>
              <name>MSIZE</name>
              <bitOffset>10</bitOffset>
              <bitWidth>2</bitWidth>
            </field>
            <field>
              <name>PL</name>
              <bitOffset>12</bitOffset>
              <bitWidth>2</bitWidth>
            </field>
            <field>
              <name>MEM2MEM</name>
              <bitOffset>14</bitOffset>
              <bitWidth>1</bitWidth>
            </field>
          </fields>
        </register>
        <register>
          <name>CCR6</name>
          <addressOffset>0x6c</addressOffset>
          <size>0x20</size>
          <fields>
            <field>
              <name>EN</name>
              <bitOffset>0</bitOffset>
              <bitWidth>1</bitWidth>
            </field>
            <field>
              <name>TCIE</name>
              <bitOffset>1</bitOffset>
              <bitWidth>1</bitWidth>
            </field>
            <field>
              <name>HTIE</name>
              <bitOffset>2</bitOffset>
              <bitWidth>1</bitWidth>
            </field>
            <field>
              <name>TEIE</name>
              <bitOffset>3</bitOffset>
              <bitWidth>1</bitWidth>
            </field>
            <field>
              <name>DIR</name>
              <bitOffset>4</bitOffset>
              <bitWidth>1</bitWidth>
            </field>
            <field>
              <name>CIRC</name>
              <bitOffset>5</bitOffset>
              <bitWidth>1</bitWidth>
            </field>
            <field>
              <name>PINC</name>
              <bitOffset>6</bitOffset>
              <bitWidth>1</bitWidth>
            </field>
            <field>
              <name>MINC</name>
              <bitOffset>7</bitOffset>
              <bitWidth>1</bitWidth>
            </field>
            <field>
              <name>PSIZE</name>
              <bitOffset>8</bitOffset>
              <bitWidth>2</bitWidth>
            </field>
            <field>
              <name>MSIZE</name>
              <bitOffset>10</bitOffset>
              <bitWidth>2</bitWidth>
            </field>
            <field>
              <name>PL</name>
              <bitOffset>12</bitOffset>
              <bitWidth>2</bitWidth>
            </field>
            <field>
              <name>MEM2MEM</name>
              <bitOffset>14</bitOffset>
              <bitWidth>1</bitWidth>
            </field>
          </fields>
        </register>
        <register>
          <name>CNDTR6</name>
          <addressOffset>0x70</addressOffset>
          <size>0x20</size>
          <fields>
            <field>
              <name>NDT</name>
              <bitOffset>0</bitOffset>
              <bitWidth>16</bitWidth>
            </field>
          </fields>
        </register>
        <register>
          <name>CNDTR6</name>
          <addressOffset>0x70</addressOffset>
          <size>0x20</size>
          <fields>
            <field>
              <name>NDT</name>
              <bitOffset>0</bitOffset>
              <bitWidth>16</bitWidth>
            </field>
          </fields>
        </register>
        <register>
          <name>CPAR6</name>
          <addressOffset>0x74</addressOffset>
          <size>0x20</size>
          <fields>
            <field>
              <name>PA</name>
              <bitOffset>0</bitOffset>
              <bitWidth>32</bitWidth>
            </field>
          </fields>
        </register>
        <register>
          <name>CPAR6</name>
          <addressOffset>0x74</addressOffset>
          <size>0x20</size>
          <fields>
            <field>
              <name>PA</name>
              <bitOffset>0</bitOffset>
              <bitWidth>32</bitWidth>
            </field>
          </fields>
        </register>
        <register>
          <name>CMAR6</name>
          <addressOffset>0x78</addressOffset>
          <size>0x20</size>
          <fields>
            <field>
              <name>MA</name>
              <bitOffset>0</bitOffset>
              <bitWidth>32</bitWidth>
            </field>
          </fields>
        </register>
        <register>
          <name>CMAR6</name>
          <addressOffset>0x78</addressOffset>
          <size>0x20</size>
          <fields>
            <field>
              <name>MA</name>
              <bitOffset>0</bitOffset>
              <bitWidth>32</bitWidth>
            </field>
          </fields>
        </register>
        <register>
          <name>CCR7</name>
          <addressOffset>0x80</addressOffset>
          <size>0x20</size>
          <fields>
            <field>
              <name>EN</name>
              <bitOffset>0</bitOffset>
              <bitWidth>1</bitWidth>
            </field>
            <field>
              <name>TCIE</name>
              <bitOffset>1</bitOffset>
              <bitWidth>1</bitWidth>
            </field>
            <field>
              <name>HTIE</name>
              <bitOffset>2</bitOffset>
              <bitWidth>1</bitWidth>
            </field>
            <field>
              <name>TEIE</name>
              <bitOffset>3</bitOffset>
              <bitWidth>1</bitWidth>
            </field>
            <field>
              <name>DIR</name>
              <bitOffset>4</bitOffset>
              <bitWidth>1</bitWidth>
            </field>
            <field>
              <name>CIRC</name>
              <bitOffset>5</bitOffset>
              <bitWidth>1</bitWidth>
            </field>
            <field>
              <name>PINC</name>
              <bitOffset>6</bitOffset>
              <bitWidth>1</bitWidth>
            </field>
            <field>
              <name>MINC</name>
              <bitOffset>7</bitOffset>
              <bitWidth>1</bitWidth>
            </field>
            <field>
              <name>PSIZE</name>
              <bitOffset>8</bitOffset>
              <bitWidth>2</bitWidth>
            </field>
            <field>
              <name>MSIZE</name>
              <bitOffset>10</bitOffset>
              <bitWidth>2</bitWidth>
            </field>
            <field>
              <name>PL</name>
              <bitOffset>12</bitOffset>
              <bitWidth>2</bitWidth>
            </field>
            <field>
              <name>MEM2MEM</name>
              <bitOffset>14</bitOffset>
              <bitWidth>1</bitWidth>
            </field>
          </fields>
        </register>
        <register>
          <name>CCR7</name>
          <addressOffset>0x80</addressOffset>
          <size>0x20</size>
          <fields>
            <field>
              <name>EN</name>
              <bitOffset>0</bitOffset>
              <bitWidth>1</bitWidth>
            </field>
            <field>
              <name>TCIE</name>
              <bitOffset>1</bitOffset>
              <bitWidth>1</bitWidth>
            </field>
            <field>
              <name>HTIE</name>
              <bitOffset>2</bitOffset>
              <bitWidth>1</bitWidth>
            </field>
            <field>
              <name>TEIE</name>
              <bitOffset>3</bitOffset>
              <bitWidth>1</bitWidth>
            </field>
            <field>
              <name>DIR</name>
              <bitOffset>4</bitOffset>
              <bitWidth>1</bitWidth>
            </field>
            <field>
              <name>CIRC</name>
              <bitOffset>5</bitOffset>
              <bitWidth>1</bitWidth>
            </field>
            <field>
              <name>PINC</name>
              <bitOffset>6</bitOffset>
              <bitWidth>1</bitWidth>
            </field>
            <field>
              <name>MINC</name>
              <bitOffset>7</bitOffset>
              <bitWidth>1</bitWidth>
            </field>
            <field>
              <name>PSIZE</name>
              <bitOffset>8</bitOffset>
              <bitWidth>2</bitWidth>
            </field>
            <field>
              <name>MSIZE</name>
              <bitOffset>10</bitOffset>
              <bitWidth>2</bitWidth>
            </field>
            <field>
              <name>PL</name>
              <bitOffset>12</bitOffset>
              <bitWidth>2</bitWidth>
            </field>
            <field>
              <name>MEM2MEM</name>
              <bitOffset>14</bitOffset>
              <bitWidth>1</bitWidth>
            </field>
          </fields>
        </register>
        <register>
          <name>CNDTR7</name>
          <addressOffset>0x84</addressOffset>
          <size>0x20</size>
          <fields>
            <field>
              <name>NDT</name>
              <bitOffset>0</bitOffset>
              <bitWidth>16</bitWidth>
            </field>
          </fields>
        </register>
        <register>
          <name>CNDTR7</name>
          <addressOffset>0x84</addressOffset>
          <size>0x20</size>
          <fields>
            <field>
              <name>NDT</name>
              <bitOffset>0</bitOffset>
              <bitWidth>16</bitWidth>
            </field>
          </fields>
        </register>
        <register>
          <name>CPAR7</name>
          <addressOffset>0x88</addressOffset>
          <size>0x20</size>
          <fields>
            <field>
              <name>PA</name>
              <bitOffset>0</bitOffset>
              <bitWidth>32</bitWidth>
            </field>
          </fields>
        </register>
        <register>
          <name>CPAR7</name>
          <addressOffset>0x88</addressOffset>
          <size>0x20</size>
          <fields>
            <field>
              <name>PA</name>
              <bitOffset>0</bitOffset>
              <bitWidth>32</bitWidth>
            </field>
          </fields>
        </register>
        <register>
          <name>CMAR7</name>
          <addressOffset>0x8c</addressOffset>
          <size>0x20</size>
          <fields>
            <field>
              <name>MA</name>
              <bitOffset>0</bitOffset>
              <bitWidth>32</bitWidth>
            </field>
          </fields>
        </register>
        <register>
          <name>CMAR7</name>
          <addressOffset>0x8c</addressOffset>
          <size>0x20</size>
          <fields>
            <field>
              <name>MA</name>
              <bitOffset>0</bitOffset>
              <bitWidth>32</bitWidth>
            </field>
          </fields>
        </register>
      </registers>
    </peripheral>
    <peripheral>
      <name>DMA2_CSELR</name>
      <baseAddress>0x400204a8</baseAddress>
      <registers>
        <register>
          <name>CSELR</name>
          <addressOffset>0x0</addressOffset>
          <size>0x20</size>
          <fields>
            <field>
              <name>C1S</name>
              <bitOffset>0</bitOffset>
              <bitWidth>4</bitWidth>
            </field>
            <field>
              <name>C2S</name>
              <bitOffset>4</bitOffset>
              <bitWidth>4</bitWidth>
            </field>
            <field>
              <name>C3S</name>
              <bitOffset>8</bitOffset>
              <bitWidth>4</bitWidth>
            </field>
            <field>
              <name>C4S</name>
              <bitOffset>12</bitOffset>
              <bitWidth>4</bitWidth>
            </field>
            <field>
              <name>C5S</name>
              <bitOffset>16</bitOffset>
              <bitWidth>4</bitWidth>
            </field>
            <field>
              <name>C6S</name>
              <bitOffset>20</bitOffset>
              <bitWidth>4</bitWidth>
            </field>
            <field>
              <name>C7S</name>
              <bitOffset>24</bitOffset>
              <bitWidth>4</bitWidth>
            </field>
          </fields>
        </register>
      </registers>
    </peripheral>
    <peripheral>
      <name>RCC</name>
      <baseAddress>0x40021000</baseAddress>
      <registers>
        <register>
          <name>CR</name>
          <addressOffset>0x0</addressOffset>
          <size>0x20</size>
          <fields>
            <field>
              <name>MSION</name>
              <bitOffset>0</bitOffset>
              <bitWidth>1</bitWidth>
            </field>
            <field>
              <name>MSIRDY</name>
              <bitOffset>1</bitOffset>
              <bitWidth>1</bitWidth>
            </field>
            <field>
              <name>MSIPLLEN</name>
              <bitOffset>2</bitOffset>
              <bitWidth>1</bitWidth>
            </field>
            <field>
              <name>MSIRGSEL</name>
              <bitOffset>3</bitOffset>
              <bitWidth>1</bitWidth>
            </field>
            <field>
              <name>MSIRANGE</name>
              <bitOffset>4</bitOffset>
              <bitWidth>4</bitWidth>
            </field>
            <field>
              <name>HSION</name>
              <bitOffset>8</bitOffset>
              <bitWidth>1</bitWidth>
            </field>
            <field>
              <name>HSIKERON</name>
              <bitOffset>9</bitOffset>
              <bitWidth>1</bitWidth>
            </field>
            <field>
              <name>HSIRDY</name>
              <bitOffset>10</bitOffset>
              <bitWidth>1</bitWidth>
            </field>
            <field>
              <name>HSIASFS</name>
              <bitOffset>11</bitOffset>
              <bitWidth>1</bitWidth>
            </field>
            <field>
              <name>HSEON</name>
              <bitOffset>16</bitOffset>
              <bitWidth>1</bitWidth>
            </field>
            <field>
              <name>HSERDY</name>
              <bitOffset>17</bitOffset>
              <bitWidth>1</bitWidth>
            </field>
            <field>
              <name>HSEBYP</name>
              <bitOffset>18</bitOffset>
              <bitWidth>1</bitWidth>
            </field>
            <field>
              <name>CSSON</name>
              <bitOffset>19</bitOffset>
              <bitWidth>1</bitWidth>
            </field>
            <field>
              <name>PLLON</name>
              <bitOffset>24</bitOffset>
              <bitWidth>1</bitWidth>
            </field>
            <field>
              <name>PLLRDY</name>
              <bitOffset>25</bitOffset>
              <bitWidth>1</bitWidth>
            </field>
            <field>
              <name>PLLSAI1ON</name>
              <bitOffset>26</bitOffset>
              <bitWidth>1</bitWidth>
            </field>
            <field>
              <name>PLLSAI1RDY</name>
              <bitOffset>27</bitOffset>
              <bitWidth>1</bitWidth>
            </field>
          </fields>
        </register>
        <register>
          <name>ICSCR</name>
          <addressOffset>0x4</addressOffset>
          <size>0x20</size>
          <fields>
            <field>
              <name>MSICAL</name>
              <bitOffset>0</bitOffset>
              <bitWidth>8</bitWidth>
            </field>
            <field>
              <name>MSITRIM</name>
              <bitOffset>8</bitOffset>
              <bitWidth>8</bitWidth>
            </field>
            <field>
              <name>HSICAL</name>
              <bitOffset>16</bitOffset>
              <bitWidth>8</bitWidth>
            </field>
            <field>
              <name>HSITRIM</name>
              <bitOffset>24</bitOffset>
              <bitWidth>5</bitWidth>
            </field>
          </fields>
        </register>
        <register>
          <name>CFGR</name>
          <addressOffset>0x8</addressOffset>
          <size>0x20</size>
          <fields>
            <field>
              <name>SW</name>
              <bitOffset>0</bitOffset>
              <bitWidth>2</bitWidth>
            </field>
            <field>
              <name>SWS</name>
              <bitOffset>2</bitOffset>
              <bitWidth>2</bitWidth>
            </field>
            <field>
              <name>HPRE</name>
              <bitOffset>4</bitOffset>
              <bitWidth>4</bitWidth>
            </field>
            <field>
              <name>PPRE1</name>
              <bitOffset>8</bitOffset>
              <bitWidth>3</bitWidth>
            </field>
            <field>
              <name>PPRE2</name>
              <bitOffset>11</bitOffset>
              <bitWidth>3</bitWidth>
            </field>
            <field>
              <name>STOPWUCK</name>
              <bitOffset>15</bitOffset>
              <bitWidth>1</bitWidth>
            </field>
            <field>
              <name>MCOSEL</name>
              <bitOffset>24</bitOffset>
              <bitWidth>4</bitWidth>
            </field>
            <field>
              <name>MCOPRE</name>
              <bitOffset>28</bitOffset>
              <bitWidth>3</bitWidth>
            </field>
          </fields>
        </register>
        <register>
          <name>PLLCFGR</name>
          <addressOffset>0xc</addressOffset>
          <size>0x20</size>
          <fields>
            <field>
              <name>PLLSRC_MSI</name>
              <bitOffset>0</bitOffset>
              <bitWidth>1</bitWidth>
            </field>
            <field>
              <name>PLLSRC_HSI</name>
              <bitOffset>1</bitOffset>
              <bitWidth>1</bitWidth>
            </field>
            <field>
              <name>PLLM</name>
              <bitOffset>4</bitOffset>
              <bitWidth>3</bitWidth>
            </field>
            <field>
              <name>PLLN</name>
              <bitOffset>8</bitOffset>
              <bitWidth>7</bitWidth>
            </field>
            <field>
              <name>PLLPEN</name>
              <bitOffset>16</bitOffset>
              <bitWidth>1</bitWidth>
            </field>
            <field>
              <name>PLLP</name>
              <bitOffset>17</bitOffset>
              <bitWidth>1</bitWidth>
            </field>
            <field>
              <name>PLLQEN</name>
              <bitOffset>20</bitOffset>
              <bitWidth>1</bitWidth>
            </field>
            <field>
              <name>PLLQ</name>
              <bitOffset>21</bitOffset>
              <bitWidth>2</bitWidth>
            </field>
            <field>
              <name>PLLREN</name>
              <bitOffset>24</bitOffset>
              <bitWidth>1</bitWidth>
            </field>
            <field>
              <name>PLLR</name>
              <bitOffset>25</bitOffset>
              <bitWidth>2</bitWidth>
            </field>
            <field>
              <name>PLLPDIV</name>
              <bitOffset>27</bitOffset>
              <bitWidth>5</bitWidth>
            </field>
          </fields>
        </register>
        <register>
          <name>PLLSAI1CFGR</name>
          <addressOffset>0x10</addressOffset>
          <size>0x20</size>
          <fields>
            <field>
              <name>PLLSAI1N</name>
              <bitOffset>8</bitOffset>
              <bitWidth>7</bitWidth>
            </field>
            <field>
              <name>PLLSAI1PEN</name>
              <bitOffset>16</bitOffset>
              <bitWidth>1</bitWidth>
            </field>
            <field>
              <name>PLLSAI1P</name>
              <bitOffset>17</bitOffset>
              <bitWidth>1</bitWidth>
            </field>
            <field>
              <name>PLLSAI1QEN</name>
              <bitOffset>20</bitOffset>
              <bitWidth>1</bitWidth>
            </field>
            <field>
              <name>PLLSAI1Q</name>
              <bitOffset>21</bitOffset>
              <bitWidth>2</bitWidth>
            </field>
            <field>
              <name>PLLSAI1REN</name>
              <bitOffset>24</bitOffset>
              <bitWidth>1</bitWidth>
            </field>
            <field>
              <name>PLLSAI1R</name>
              <bitOffset>25</bitOffset>
              <bitWidth>2</bitWidth>
            </field>
            <field>
              <name>PLLSAI1PDIV</name>
              <bitOffset>27</bitOffset>
              <bitWidth>5</bitWidth>
            </field>
          </fields>
        </register>
        <register>
          <name>CIER</name>
          <addressOffset>0x18</addressOffset>
          <size>0x20</size>
          <fields>
            <field>
              <name>LSIRDYIE</name>
              <bitOffset>0</bitOffset>
              <bitWidth>1</bitWidth>
            </field>
            <field>
              <name>LSERDYIE</name>
              <bitOffset>1</bitOffset>
              <bitWidth>1</bitWidth>
            </field>
            <field>
              <name>MSIRDYIE</name>
              <bitOffset>2</bitOffset>
              <bitWidth>1</bitWidth>
            </field>
            <field>
              <name>HSIRDYIE</name>
              <bitOffset>3</bitOffset>
              <bitWidth>1</bitWidth>
            </field>
            <field>
              <name>HSERDYIE</name>
              <bitOffset>4</bitOffset>
              <bitWidth>1</bitWidth>
            </field>
            <field>
              <name>PLLRDYIE</name>
              <bitOffset>5</bitOffset>
              <bitWidth>1</bitWidth>
            </field>
            <field>
              <name>PLLSAI1RDYIE</name>
              <bitOffset>6</bitOffset>
              <bitWidth>1</bitWidth>
            </field>
            <field>
              <name>LSECSSIE</name>
              <bitOffset>9</bitOffset>
              <bitWidth>1</bitWidth>
            </field>
            <field>
              <name>HSI48RDYIE</name>
              <bitOffset>10</bitOffset>
              <bitWidth>1</bitWidth>
            </field>
          </fields>
        </register>
        <register>
          <name>CIFR</name>
          <addressOffset>0x1c</addressOffset>
          <size>0x20</size>
          <fields>
            <field>
              <name>LSIRDYF</name>
              <bitOffset>0</bitOffset>
              <bitWidth>1</bitWidth>
            </field>
            <field>
              <name>LSERDYF</name>
              <bitOffset>1</bitOffset>
              <bitWidth>1</bitWidth>
            </field>
            <field>
              <name>MSIRDYF</name>
              <bitOffset>2</bitOffset>
              <bitWidth>1</bitWidth>
            </field>
            <field>
              <name>HSIRDYF</name>
              <bitOffset>3</bitOffset>
              <bitWidth>1</bitWidth>
            </field>
            <field>
              <name>HSERDYF</name>
              <bitOffset>4</bitOffset>
              <bitWidth>1</bitWidth>
            </field>
            <field>
              <name>PLLRDYF</name>
              <bitOffset>5</bitOffset>
              <bitWidth>1</bitWidth>
            </field>
            <field>
              <name>PLLSAI1RDYF</name>
              <bitOffset>6</bitOffset>
              <bitWidth>1</bitWidth>
            </field>
            <field>
              <name>CSSF</name>
              <bitOffset>8</bitOffset>
              <bitWidth>1</bitWidth>
            </field>
            <field>
              <name>LSECSSF</name>
              <bitOffset>9</bitOffset>
              <bitWidth>1</bitWidth>
            </field>
            <field>
              <name>HSI48RDYF</name>
              <bitOffset>10</bitOffset>
              <bitWidth>1</bitWidth>
            </field>
          </fields>
        </register>
        <register>
          <name>CICR</name>
          <addressOffset>0x20</addressOffset>
          <size>0x20</size>
          <fields>
            <field>
              <name>LSIRDYC</name>
              <bitOffset>0</bitOffset>
              <bitWidth>1</bitWidth>
            </field>
            <field>
              <name>LSERDYC</name>
              <bitOffset>1</bitOffset>
              <bitWidth>1</bitWidth>
            </field>
            <field>
              <name>MSIRDYC</name>
              <bitOffset>2</bitOffset>
              <bitWidth>1</bitWidth>
            </field>
            <field>
              <name>HSIRDYC</name>
              <bitOffset>3</bitOffset>
              <bitWidth>1</bitWidth>
            </field>
            <field>
              <name>HSERDYC</name>
              <bitOffset>4</bitOffset>
              <bitWidth>1</bitWidth>
            </field>
            <field>
              <name>PLLRDYC</name>
              <bitOffset>5</bitOffset>
              <bitWidth>1</bitWidth>
            </field>
            <field>
              <name>PLLSAI1RDYC</name>
